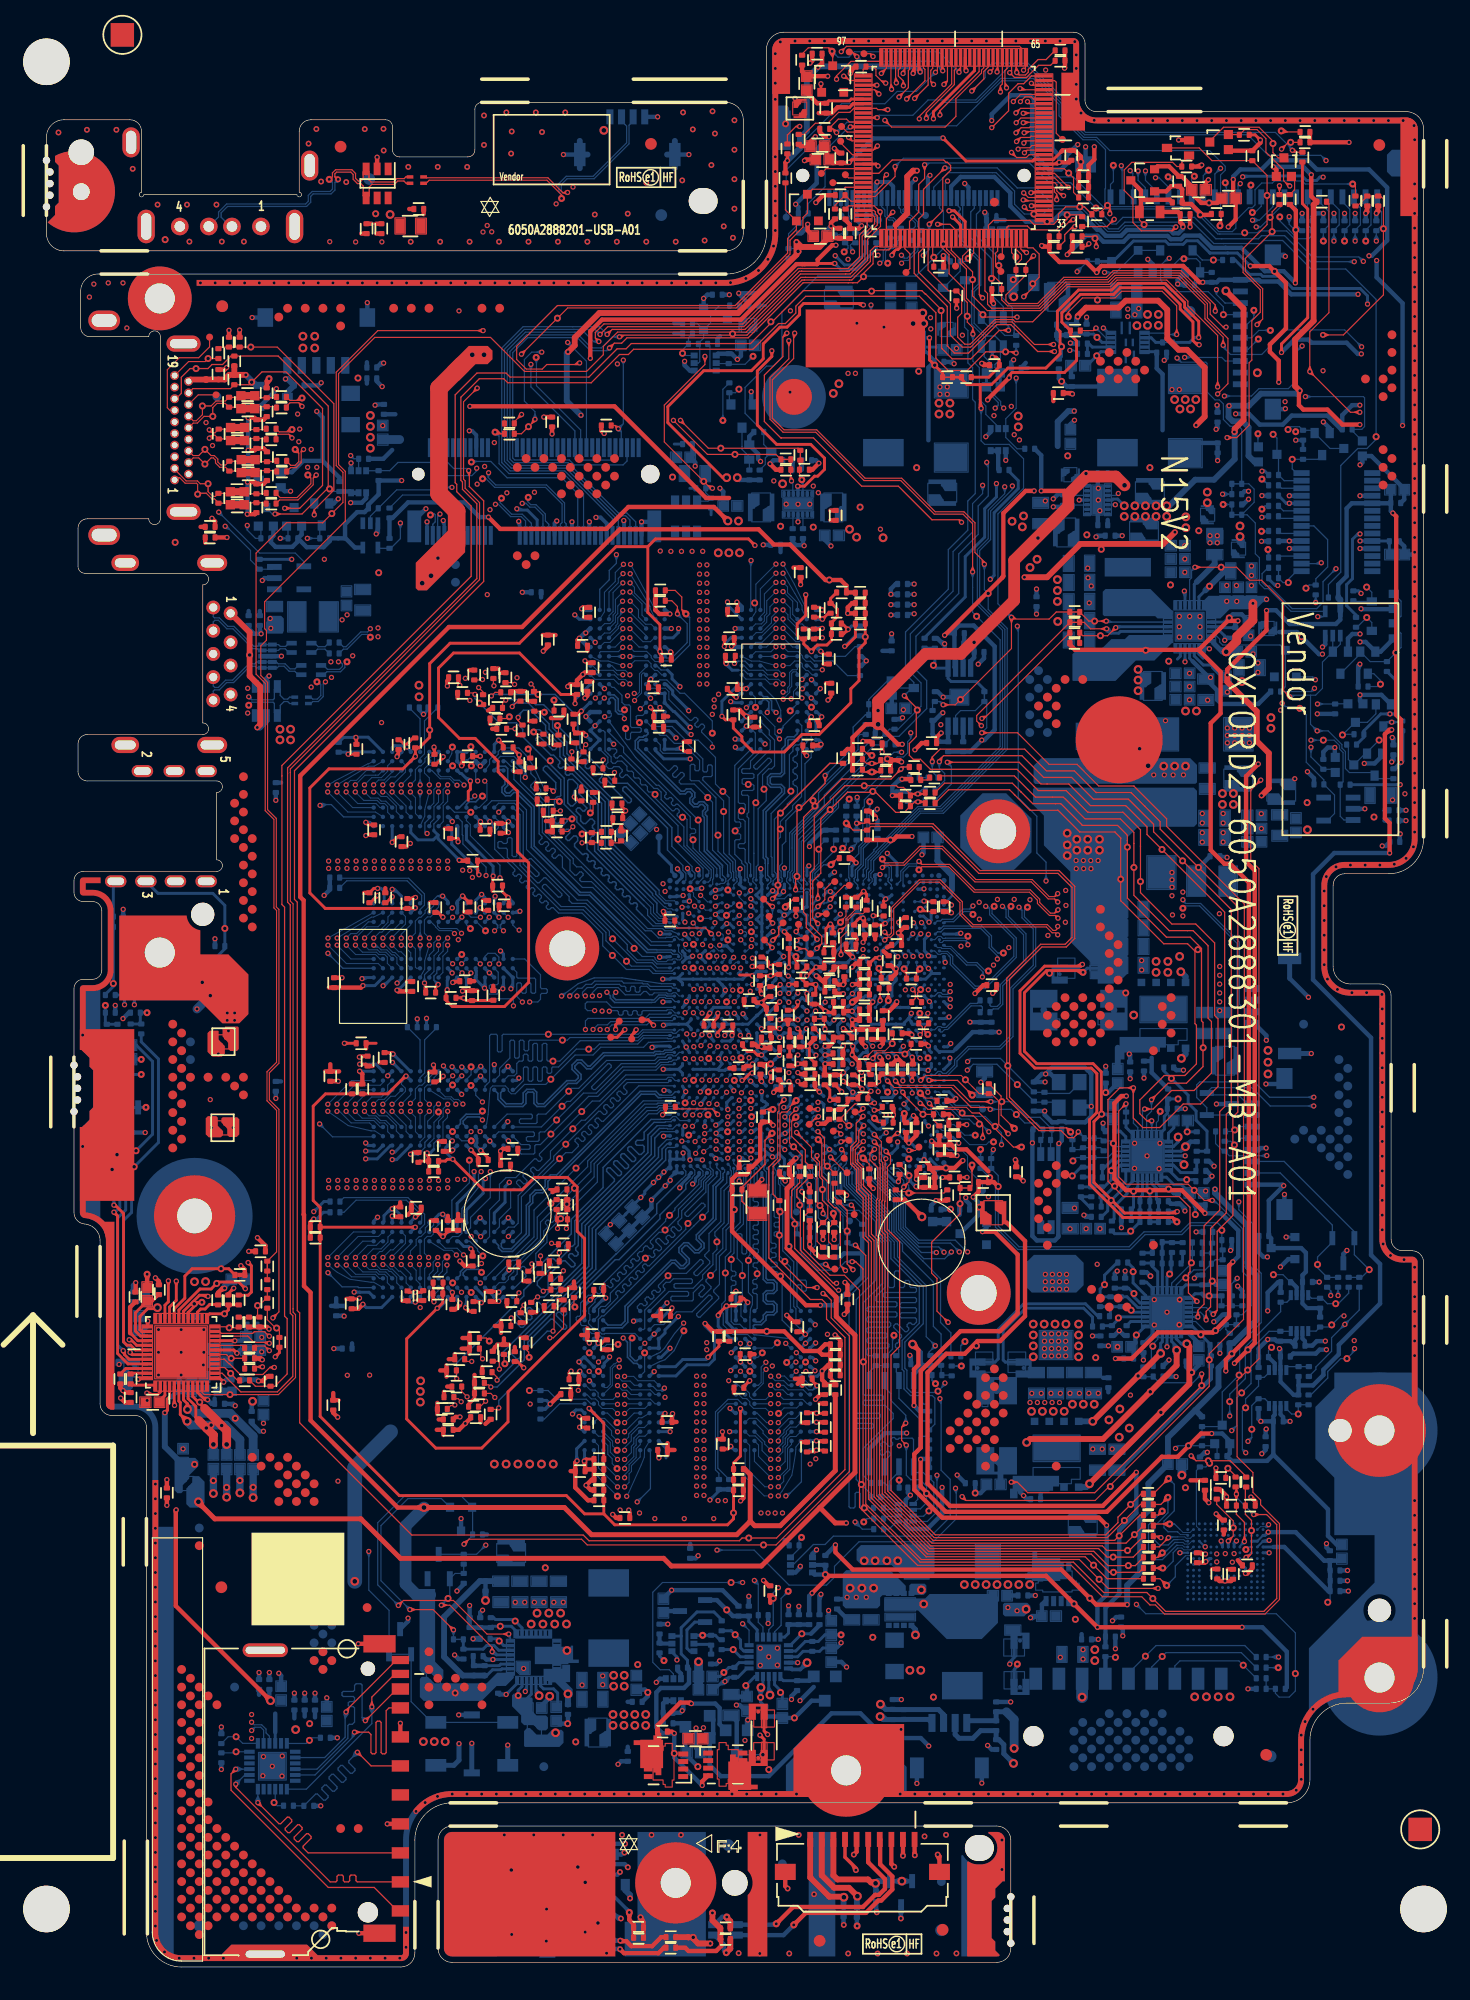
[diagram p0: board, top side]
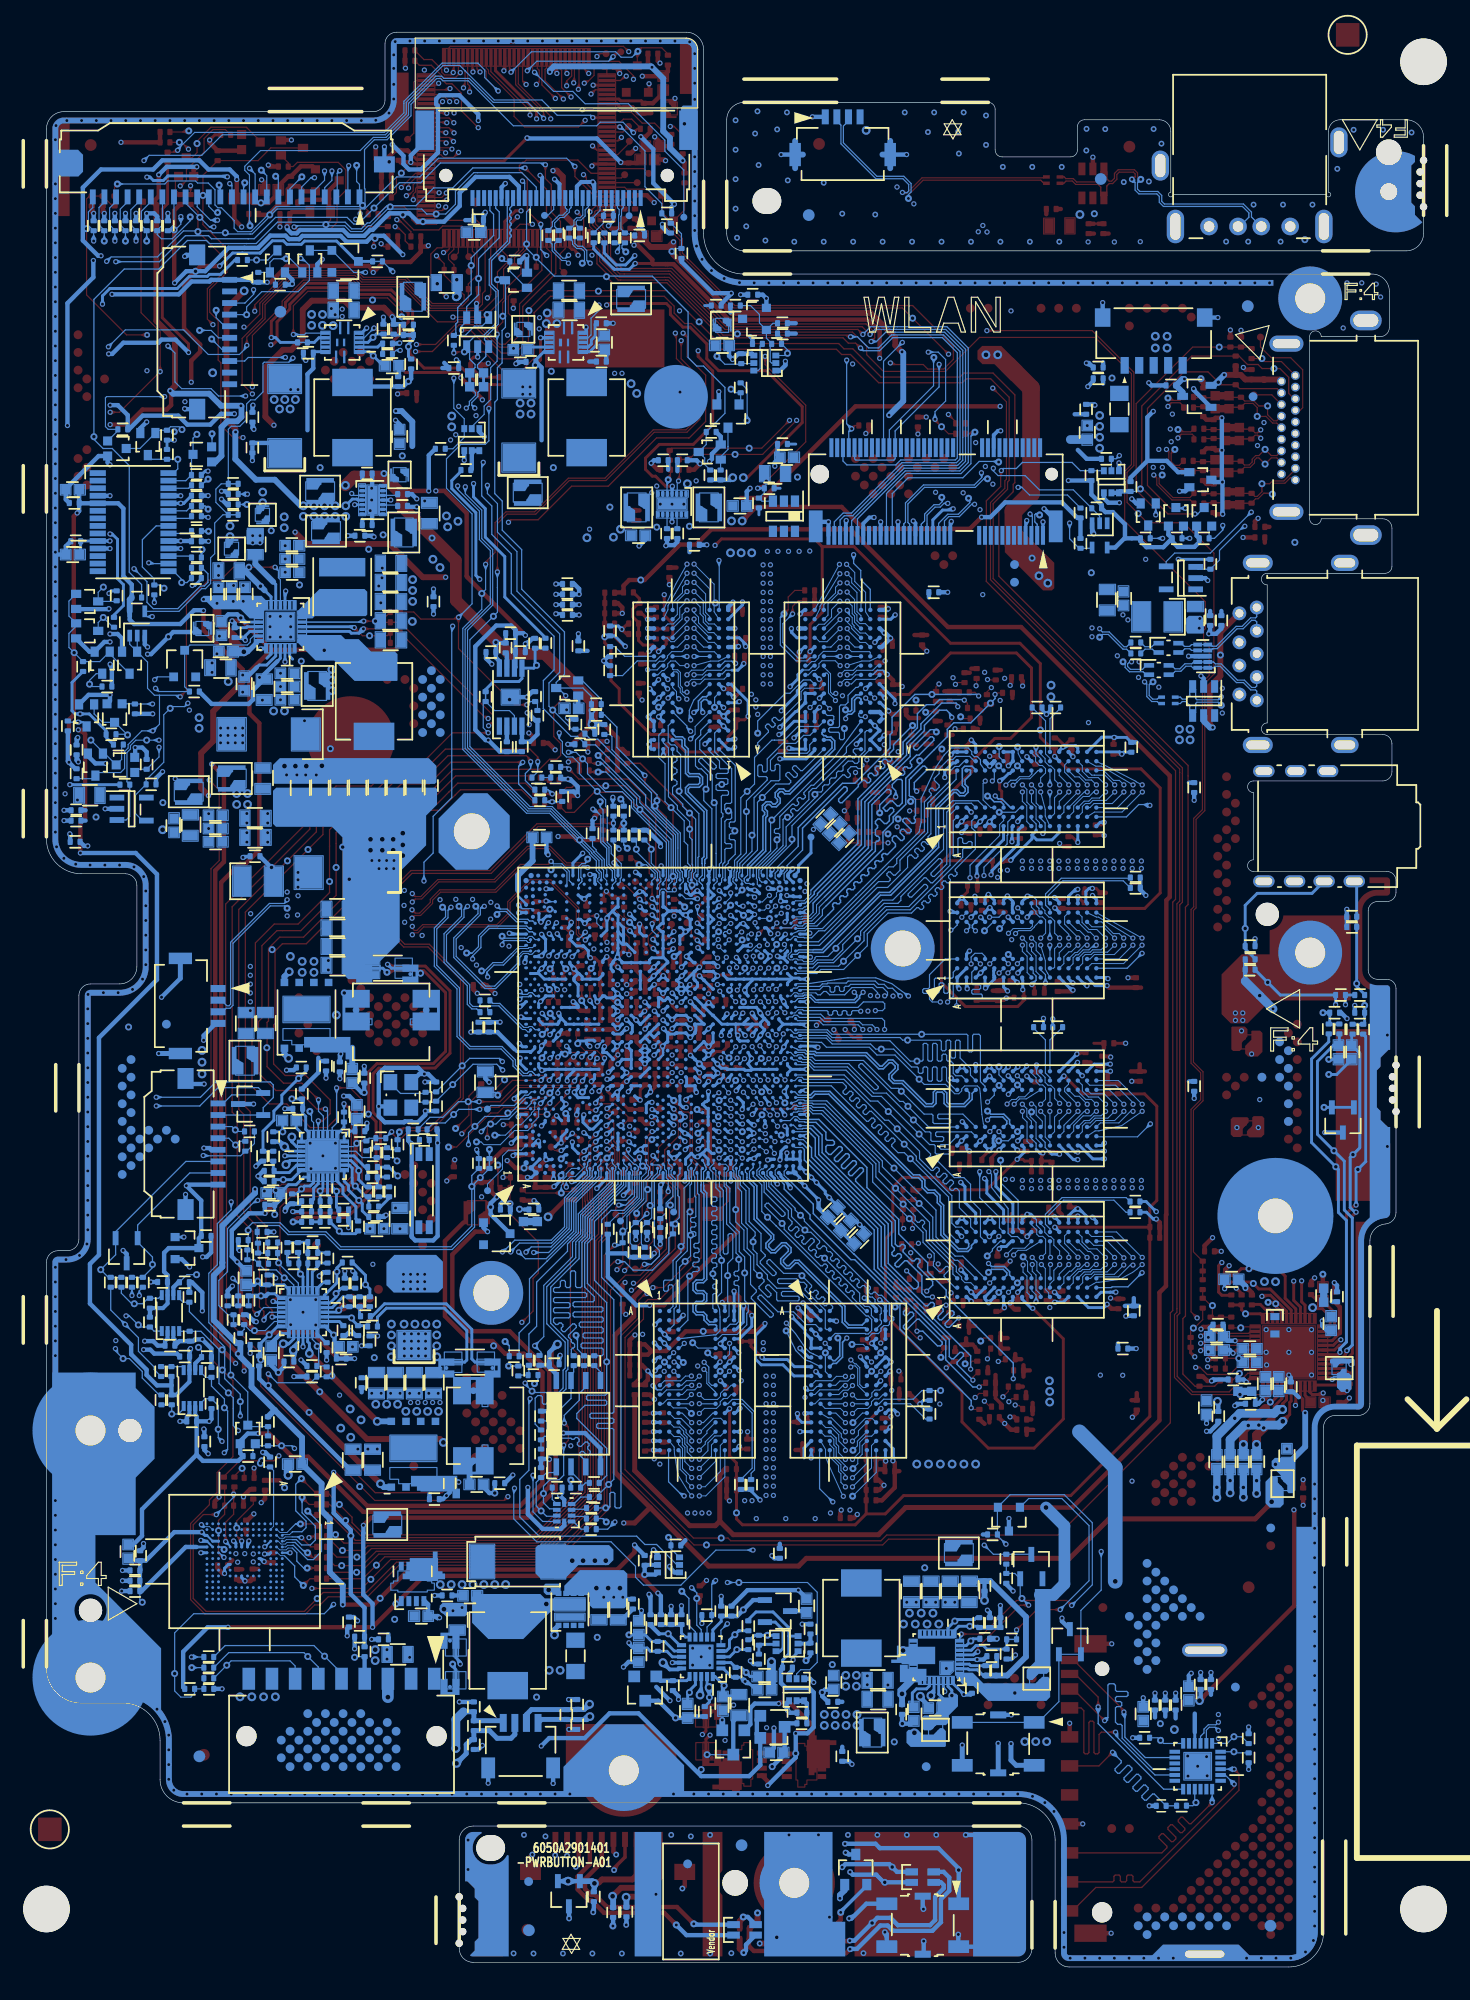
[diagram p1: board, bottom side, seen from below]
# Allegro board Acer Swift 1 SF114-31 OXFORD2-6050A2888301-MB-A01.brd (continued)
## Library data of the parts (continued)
PAD7101 PAD7102 PAD7104 = POWERPAD_2: part number: POWERPAD_2-POWERPAD_2_0610,POWERPAD_2_0610,POWERPAD_2_0610,0.559MM,POWERPAD_2,POWERPAD_2_0610; room: Sheet14
PAD7103 = POWERPAD_2: part number: POWERPAD_2-POWERPAD1X1M,POWERPAD1X1M,POWERPAD1X1M,0.559MM,POWERPAD_2,POWERPAD1X1M; room: Sheet14
PAD60300 PAD60310 = POWERPAD_2: part number: POWERPAD_2-POWERPAD_2_0610,POWERPAD_2_0610,POWERPAD_2_0610,0.559MM,POWERPAD_2,POWERPAD_2_0610; room: Sheet7
PAD60350 PAD60351 = POWERPAD_2: part number: POWERPAD_2-POWERPAD1X1M,POWERPAD1X1M,POWERPAD1X1M,0.559MM,POWERPAD_2,POWERPAD1X1M; room: Sheet7
PAD60610 PAD60900 PAD60910 = POWERPAD_2: part number: POWERPAD_2-POWERPAD_2_0610,POWERPAD_2_0610,POWERPAD_2_0610,0.559MM,POWERPAD_2,POWERPAD_2_0610; room: Sheet12
PAD61000 PAD61110 PAD61700 = POWERPAD_2: part number: POWERPAD_2-POWERPAD1X1M,POWERPAD1X1M,POWERPAD1X1M,0.559MM,POWERPAD_2,POWERPAD1X1M; room: Sheet12
Q281 = PMOS_A: part number: PMOS_A-PM513BA,6015B0145801,TSOT23_292X130X120_3_095,1.35MM,,TRANSISTOR-FET,PEMOS,20V,3A,SOT23,3P,TR; room: Sheet16
Q300 = NMOS: part number: NMOS-L2N7002WT1G,6015B0104301,TSSOT323_200X125X100_3_065,1.15MM,NMOS,,,TRANSISTOR-FET,NEMOS,60V,115MA,SC-70,3P,TR; room: Sheet17
Q310 Q311 = NMOS: part number: NMOS-RU1C001UNTCL,6015B0142601,UMT3F_200X125X100_3_065,1.15MM,NMOS,,,TRANSISTOR-FET,NEMOS,20V,100MA,UMT3F,3P,TR; room: Sheet17
Q1300 = FDC638APZ: part number: FDC638APZ-FDC638APZ_DY,6015B0068901_DY,TSOT_290X160X110_6_095,1.25MM,TRANSISTOR-FET,PEMOS,20V,4.5A,SSOT6,6P,TR; room: Sheet21
Q1302 = NMOS_DUAL_C: part number: NMOS_DUAL_C-L2N7002DW1T1G,6015B0098401,TSSC88_200X125X110_6_065-2,1.25MM,NMOS_DUAL_C,,TRANSISTOR-FET,NEMOS,60V,115MA,SOT363,6P,TR; room: Sheet45
Q3000 Q3004 = PMOS_A: part number: PMOS_A-PM513BA,6015B0145801,TSOT23_292X130X120_3_095,1.35MM,,TRANSISTOR-FET,PEMOS,20V,3A,SOT23,3P,TR; room: Sheet26
Q3001 = NMOS_DUAL_C: part number: NMOS_DUAL_C-L2N7002DW1T1G,6015B0098401,TSSC88_200X125X110_6_065-2,1.25MM,NMOS_DUAL_C,,TRANSISTOR-FET,NEMOS,60V,115MA,SOT363,6P,TR; room: Sheet26
Q3003 Q3007 = NMOS: part number: NMOS-L2N7002WT1G,6015B0104301,TSSOT323_200X125X100_3_065,1.15MM,NMOS,,,TRANSISTOR-FET,NEMOS,60V,115MA,SC-70,3P,TR; room: Sheet26
Q3006 = NPN_D: part number: NPN_D-LMBT3904LT1G,6015B0048201,TSSOT23_292X130X111_3_096,1.26MM,NPN_D,SOT23,0.2A,TRANSISTOR,NPN,40V,200MA,SOT23,3P,TR; room: Sheet26
Q3150 Q3151 = NMOS: part number: NMOS-RU1C001UNTCL,6015B0142601,UMT3F_200X125X100_3_065,1.15MM,NMOS,,,TRANSISTOR-FET,NEMOS,20V,100MA,UMT3F,3P,TR; room: Sheet27
Q3152 Q3153 = NMOS: part number: NMOS-L2N7002WT1G,6015B0104301,TSSOT323_200X125X100_3_065,1.15MM,NMOS,,,TRANSISTOR-FET,NEMOS,60V,115MA,SC-70,3P,TR; room: Sheet27
Q3500 Q3501 = NMOS: part number: NMOS-RU1C001UNTCL_DY,6015B0142601_DY,UMT3F_200X125X100_3_065,1.15MM,NMOS,,,TRANSISTOR-FET,NEMOS,20V,100MA,UMT3F,3P,TR; room: Sheet25
Q3502 = NMOS: part number: NMOS-L2N7002WT1G_DY,6015B0104301_DY,TSSOT323_200X125X100_3_065,1.15MM,NMOS,,,TRANSISTOR-FET,NEMOS,60V,115MA,SC-70,3P,TR; room: Sheet25
Q4505 = NMOS: part number: NMOS-L2N7002WT1G_DY,6015B0104301_DY,TSSOT323_200X125X100_3_065,1.15MM,NMOS,,,TRANSISTOR-FET,NEMOS,60V,115MA,SC-70,3P,TR; room: Sheet40
Q4506 = NMOS_DUAL_C: part number: NMOS_DUAL_C-L2N7002DW1T1G,6015B0098401,TSSC88_200X125X110_6_065-2,1.25MM,NMOS_DUAL_C,,TRANSISTOR-FET,NEMOS,60V,115MA,SOT363,6P,TR; room: Sheet40
Q4513 Q4516 Q4517 = NMOS: part number: NMOS-RU1C001UNTCL,6015B0142601,UMT3F_200X125X100_3_065,1.15MM,NMOS,,,TRANSISTOR-FET,NEMOS,20V,100MA,UMT3F,3P,TR; room: Sheet45
Q4524 Q4525 Q4714 = NMOS: part number: NMOS-L2N7002WT1G,6015B0104301,TSSOT323_200X125X100_3_065,1.15MM,NMOS,,,TRANSISTOR-FET,NEMOS,60V,115MA,SC-70,3P,TR; room: Sheet45
Q6000 = FDMS7620S: part number: FDMS7620S-AON7934,6015B0146701,TSMOS_300X300X080_8_065_T4,0.95MM,,TRANSISTOR-FET,NNEMOS,30V,16/18A,POWER33; room: Sheet5
Q6010 Q6012 = NMOS_4D3S: part number: NMOS_4D3S-RQ3E100BNFU7TB,6015B0134801,MOSFET_300X300X112_8_065,1.27MM,NMOS_4D3S,TRANSISTOR-FET,NEMOS,30V,10A,HSMT8,8P,TR; room: Sheet5
Q6011 = NMOS_4D3S: part number: NMOS_4D3S-RQ3E070BNFU7TB,6015B0162901,MOSFET_300X300X112_8_065,1.27MM,NMOS_4D3S,TRANSISTOR-FET,NEMOS,30V,7A,HSMT8,8,TR; room: Sheet5
Q6610 = FDMS3669S: part number: FDMS3669S-FAIRCHILD_FDMS3669S,6015B0146801,TSMOS_500X600X110_8_127_T1,1.25MM,,TRANSISTOR-FET,NNEMOS,30/30V,10/17A,POWER56; room: Sheet9
Q6710 = FDMS3669S: part number: FDMS3669S-FAIR_FDMS3664S_8P,6015B0131601,TSMOS_500X600X110_8_127_T1,1.25MM,,TRANSISTOR-FET,NNEMOS,30V,13/25A,POWER56; room: Sheet11
Q7000 = NMOS: part number: NMOS-L2N7002WT1G,6015B0104301,TSSOT323_200X125X100_3_065,1.15MM,NMOS,,,TRANSISTOR-FET,NEMOS,60V,115MA,SC-70,3P,TR; room: Sheet13
Q7106 Q7108 Q7114 Q7120 = NMOS: part number: NMOS-L2N7002WT1G,6015B0104301,TSSOT323_200X125X100_3_065,1.15MM,NMOS,,,TRANSISTOR-FET,NEMOS,60V,115MA,SC-70,3P,TR; room: Sheet14
Q7202 = PMOS_A: part number: PMOS_A-PM513BA,6015B0145801,TSOT23_292X130X120_3_095,1.35MM,,TRANSISTOR-FET,PEMOS,20V,3A,SOT23,3P,TR; room: Sheet13
Q7214 Q60002 Q60003 = NMOS_DUAL_C: part number: NMOS_DUAL_C-L2N7002DW1T1G,6015B0098401,TSSC88_200X125X110_6_065-2,1.25MM,NMOS_DUAL_C,,TRANSISTOR-FET,NEMOS,60V,115MA,SOT363,6P,TR; room: Sheet13
R20 R3010 R3021 R3030 = RSC_0402: part number: RSC_0402-100K_5%_2,60130B1040ZT,RSC_100X050X040_2,0.55MM,RSC_0402,0402,RES-CHIP-100K-5%-1/16W-0402-TAP; signal model: R2_60130B1040ZT_100K_5%_2; room: Sheet26
R28 R29 R7109 R7125 = RSC_0402: part number: RSC_0402-200_5%_2,6013A0051201,RSC_100X050X040_2,0.55MM,RSC_0402,0402,RES-CHIP-200-5%-1/16W-0402-TAP; signal model: R2_6013A0051201_200_5%_2; room: Sheet14
R35 R4523 R4545 R4546 = RSC_0402: part number: RSC_0402-10K_5%_2,60130B1030ZT,RSC_100X050X040_2,0.55MM,RSC_0402,0402,RES-CHIP,10K,5%,1/16W,0402,TR; signal model: R2_60130B1030ZT_10K_5%_2; room: Sheet37
R281 R282 R286 = RSC_0402: part number: RSC_0402-0_5%_2_DY,60130B0000ZT_DY,RSC_100X050X040_2,0.55MM,RSC_0402,0402,RES-CHIP-0OHM-5%-1/16W-0402-TAP; signal model: R2_60130B0000ZT_DY_0_5%_2_DY; room: Sheet16
R283-R285 = RSC_0402: part number: RSC_0402-0_5%_2,60130B0000ZT,RSC_100X050X040_2,0.55MM,RSC_0402,0402,RES-CHIP-0OHM-5%-1/16W-0402-TAP; signal model: R2_60130B0000ZT_0_5%_2; room: Sheet16
R301 R311 R323 R334 R350 R390 R4649 = RSC_0402: part number: RSC_0402-10K_5%_2,60130B1030ZT,RSC_100X050X040_2,0.55MM,RSC_0402,0402,RES-CHIP,10K,5%,1/16W,0402,TR; signal model: R2_60130B1030ZT_10K_5%_2; room: Sheet17
R308 R309 = RSC_0402: part number: RSC_0402-47K_5%_2,60130B4730ZT,RSC_100X050X040_2,0.55MM,RSC_0402,0402,RES-CHIP-47K-5%-1/16W-0402-TAP; signal model: R2_60130B4730ZT_47K_5%_2; room: Sheet17
R310 = RSC_0402: part number: RSC_0402-1K_5%_2,60130B1020ZT,RSC_100X050X040_2,0.55MM,RSC_0402,0402,RES-CHIP-1K-5%-1/16W-0402-TAP; signal model: R2_60130B1020ZT_1K_5%_2; room: Sheet17
R312-R314 R325 = RSC_0402: part number: RSC_0402-0_5%_2_DY,60130B0000ZT_DY,RSC_100X050X040_2,0.55MM,RSC_0402,0402,RES-CHIP-0OHM-5%-1/16W-0402-TAP; signal model: R2_60130B0000ZT_DY_0_5%_2_DY; room: Sheet17
R316 R317 = RSC_0402: part number: RSC_0402-1.8K_5%_2,6013A0072101,RSC_100X050X040_2,0.55MM,RSC_0402,0402,RES-CHIP-1.8K-5%-1/16W-0402-TAP; signal model: R2_6013A0072101_1_8K_5%_2; room: Sheet17
R318 = RSC_0603: part number: RSC_0603-2.2_5%_3,60130B2R200T,RSC_160X080X080_2,0.95MM,RSC_0603,0603,RES-CHIP-2.2-5%-1/10W-0603-TAP; signal model: R2_60130B2R200T_2_2_5%_3; room: Sheet17
R320 R324 R333 R346 = RSC_0402: part number: RSC_0402-100K_5%_2,60130B1040ZT,RSC_100X050X040_2,0.55MM,RSC_0402,0402,RES-CHIP-100K-5%-1/16W-0402-TAP; signal model: R2_60130B1040ZT_100K_5%_2; room: Sheet17
R321 R322 = RSC_0402: part number: RSC_0402-3.3K_5%_2,6013A0051001,RSC_100X050X040_2,0.55MM,RSC_0402,0402,RES-CHIP-3.3K-5%-1/16W-0402-TAP; signal model: R2_6013A0051001_3_3K_5%_2; room: Sheet17
R332 R391 = RSC_0402: part number: RSC_0402-10K_5%_2_DY,60130B1030ZT_DY,RSC_100X050X040_2,0.55MM,RSC_0402,0402,RES-CHIP,10K,5%,1/16W,0402,TR; signal model: R2_60130B1030ZT_DY_10K_5%_2_DY; room: Sheet17
R340-R343 = RSC_0402: part number: RSC_0402-33_5%_2,60130B3300ZT,RSC_100X050X040_2,0.55MM,RSC_0402,0402,RES-CHIP-33-5%-1/16W-0402-TAP; signal model: R2_60130B3300ZT_33_5%_2; room: Sheet17
R351 = RSC_0402: part number: RSC_0402-18.7K_1%_2,6013A0017101,RSC_100X050X040_2,0.55MM,RSC_0402,0402,RES-CHIP-18.7K-1%-1/16W-0402-TAP; signal model: R2_6013A0017101_18_7K_1%_2; room: Sheet17
R352 = RSC_THERMISTOR: part number: RSC_THERMISTOR-100K_1%_NTC,6013B0171701,RSC_100X050X055_2,0.7MM,RSC_THERMISTOR,,RESISTOR-THER,NTC,100K,0402,1%,0.1A,0.1W,SMD,TR; signal model: R2_6013B0171701_100K_1%_NTC; room: Sheet17
R500 R513 = RSC_SHORT: part number: RSC_SHORT-SHORT_0603_25,SHORT_0603_25,RSC_160X080X080_2_25_SHORT,0.127MM,RSC_SHORT,SHORT_0603_25; signal model: R2_short_0603_25_short_0603_25; room: Sheet18
R501 = RSC_0402: part number: RSC_0402-20K_1%_2_DY,6013A0015301_DY,RSC_100X050X040_2,0.55MM,RSC_0402,0402,RES-CHIP-20K-1%-1/16W-0402-TAP; signal model: R2_6013A0015301_DY_20K_1%_2_DY; room: Sheet18
R502 = RSC_0402: part number: RSC_0402-200K_5%_2,60130B20400Y,RSC_100X050X040_2,0.55MM,RSC_0402,0402,RES-CHIP-200K-5%-1/16W-0402-TAP; signal model: R2_60130B20400Y_200K_5%_2; room: Sheet18
R503 = RSC_0402: part number: RSC_0402-1K_5%_2_DY,60130B1020ZT_DY,RSC_100X050X040_2,0.55MM,RSC_0402,0402,RES-CHIP-1K-5%-1/16W-0402-TAP; signal model: R2_60130B1020ZT_DY_1K_5%_2_DY; room: Sheet18
R504 R531 = RSC_0402: part number: RSC_0402-100K_5%_2,60130B1040ZT,RSC_100X050X040_2,0.55MM,RSC_0402,0402,RES-CHIP-100K-5%-1/16W-0402-TAP; signal model: R2_60130B1040ZT_100K_5%_2; room: Sheet18
R505 R515 = RSC_0402: part number: RSC_0402-1K_5%_2,60130B1020ZT,RSC_100X050X040_2,0.55MM,RSC_0402,0402,RES-CHIP-1K-5%-1/16W-0402-TAP; signal model: R2_60130B1020ZT_1K_5%_2; room: Sheet18
R506 = RSC_0402: part number: RSC_0402-0_5%_2,60130B0000ZT,RSC_100X050X040_2,0.55MM,RSC_0402,0402,RES-CHIP-0OHM-5%-1/16W-0402-TAP; signal model: R2_60130B0000ZT_0_5%_2; room: Sheet18
R507 = RSC_0402: part number: RSC_0402-75_5%_2,60130B7500ZT,RSC_100X050X040_2,0.55MM,RSC_0402,0402,RES-CHIP-75OHM-5%-1/16W-0402-TAP; signal model: R2_60130B7500ZT_75_5%_2; room: Sheet18
R508-R511 = RSC_0603: part number: RSC_0603-0_5%_3,60130B00000Z,RSC_160X080X055_2,0.7MM,RSC_0603,0603,RES-CHIP-0-5%-1/10W-TAP; signal model: R2_60130B00000Z_0_5%_3; room: Sheet18
R512 = RSC_0402: part number: RSC_0402-100_5%_2,60130B1010ZT,RSC_100X050X040_2,0.55MM,RSC_0402,0402,RES-CHIP-100-5%-1/16W-0402-TAP; signal model: R2_60130B1010ZT_100_5%_2; room: Sheet18
R514 = RSC_SHORT: part number: RSC_SHORT-SHORT_0402_15,SHORT_0402_15,RSC_100X050X040_2_15_SHORT,0.127MM,RSC_SHORT,SHORT_0402_15; signal model: R2_short_0402_15_short_0402_15; room: Sheet18
R520 R521 = RSC_SHORT: part number: RSC_SHORT-SHORT_0402_5,SHORT_0402_5,RSC_100X050X040_2_SHORT,0.127MM,RSC_SHORT,SHORT_0402_5; signal model: R2_short_0402_5_short_0402_5; room: Sheet18
R600 R601 = RSC_0402: part number: RSC_0402-2.2K_5%_2,6013A0049601,RSC_100X050X040_2,0.55MM,RSC_0402,0402,RES-CHIP-2.2K-5%-1/16W-0402-TAP; signal model: R2_6013A0049601_2_2K_5%_2; room: Sheet19
R602 R603 = RSC_0402: part number: RSC_0402-0_5%_2,60130B0000ZT,RSC_100X050X040_2,0.55MM,RSC_0402,0402,RES-CHIP-0OHM-5%-1/16W-0402-TAP; signal model: R2_60130B0000ZT_0_5%_2; room: Sheet19
R604 R605 = RSC_0402: part number: RSC_0402-22_5%_2,60130B2200ZT,RSC_100X050X040_2,0.55MM,RSC_0402,0402,RES-CHIP-22-5%-1/16W-0402-TAP; signal model: R2_60130B2200ZT_22_5%_2; room: Sheet19
R606 R607 = RSC_0402: part number: RSC_0402-4.7K_5%_2,60130B4720ZT,RSC_100X050X040_2,0.55MM,RSC_0402,0402,RES-CHIP-4.7K-5%-1/16W-0402-TAP; signal model: R2_60130B4720ZT_4_7K_5%_2; room: Sheet19
R610 = RSC_0402: part number: RSC_0402-0_5%_2_DY,60130B0000ZT_DY,RSC_100X050X040_2,0.55MM,RSC_0402,0402,RES-CHIP-0OHM-5%-1/16W-0402-TAP; signal model: R2_60130B0000ZT_DY_0_5%_2_DY; room: Sheet19
R704 = RSC_SHORT: part number: RSC_SHORT-SHORT_0402_15,SHORT_0402_15,RSC_100X050X040_2_15_SHORT,0.127MM,RSC_SHORT,SHORT_0402_15; signal model: R2_short_0402_15_short_0402_15; room: Sheet40
R900 = RSC_0402: part number: RSC_0402-6.2K_1%_2,6013A0057801,RSC_100X050X040_2,0.55MM,RSC_0402,0402,RES-CHIP-6.2K,1%-1/16W-0402-TAP; signal model: R2_6013A0057801_6_2K_1%_2; room: Sheet20
R901 = RSC_0402: part number: RSC_0402-0_5%_2,60130B0000ZT,RSC_100X050X040_2,0.55MM,RSC_0402,0402,RES-CHIP-0OHM-5%-1/16W-0402-TAP; signal model: R2_60130B0000ZT_0_5%_2; room: Sheet20
R1301 = RSC_0805: part number: RSC_0805-0_5%_5,60130BA0003T,RSC_200X125X115_2,1.3MM,RSC_0805,0805,RES-CHIP-0-5%-1/8W-0805-TAP; signal model: R2_60130BA0003T_0_5%_5; room: Sheet21
R1302 = RSC_0402: part number: RSC_0402-0_5%_2_DY,60130B0000ZT_DY,RSC_100X050X040_2,0.55MM,RSC_0402,0402,RES-CHIP-0OHM-5%-1/16W-0402-TAP; signal model: R2_60130B0000ZT_DY_0_5%_2_DY; room: Sheet21
R1306 = RSC_0402: part number: RSC_0402-0_5%_2,60130B0000ZT,RSC_100X050X040_2,0.55MM,RSC_0402,0402,RES-CHIP-0OHM-5%-1/16W-0402-TAP; signal model: R2_60130B0000ZT_0_5%_2; room: Sheet21
R1307 R4639 R4640 R4642 R4643 R4652 R4653 R4655-R4657 R4834 = RSC_0402: part number: RSC_0402-10K_5%_2,60130B1030ZT,RSC_100X050X040_2,0.55MM,RSC_0402,0402,RES-CHIP,10K,5%,1/16W,0402,TR; signal model: R2_60130B1030ZT_10K_5%_2; room: Sheet45
R2000 = RSC_0402: part number: RSC_0402-RSC_0402_DY,RSC_0402_DY,RSC_100X050X040_2,0.55MM,RSC_0402,0402,RSC_0402_DY; signal model: R2_RSC_0402_DY_RSC_0402_DY; room: Sheet22
R2001 = RSC_0402: part number: RSC_0402-10K_5%_2,60130B1030ZT,RSC_100X050X040_2,0.55MM,RSC_0402,0402,RES-CHIP,10K,5%,1/16W,0402,TR; signal model: R2_60130B1030ZT_10K_5%_2; room: Sheet22
R2410 = RSC_0402: part number: RSC_0402-10K_5%_2,60130B1030ZT,RSC_100X050X040_2,0.55MM,RSC_0402,0402,RES-CHIP,10K,5%,1/16W,0402,TR; signal model: R2_60130B1030ZT_10K_5%_2; room: Sheet23
R3000 R3006 = RSC_0402: part number: RSC_0402-47K_5%_2,60130B4730ZT,RSC_100X050X040_2,0.55MM,RSC_0402,0402,RES-CHIP-47K-5%-1/16W-0402-TAP; signal model: R2_60130B4730ZT_47K_5%_2; room: Sheet26
R3001 = RSC_0402: part number: RSC_0402-470K_5%_2,60130B47400Z,RSC_100X050X040_2,0.55MM,RSC_0402,0402,RES-CHIP-470K-5%-1/16W-0402-TAP; signal model: R2_60130B47400Z_470K_5%_2; room: Sheet26
R3004 R3011 R3013 = RSC_0402: part number: RSC_0402-100_5%_2,60130B1010ZT,RSC_100X050X040_2,0.55MM,RSC_0402,0402,RES-CHIP-100-5%-1/16W-0402-TAP; signal model: R2_60130B1010ZT_100_5%_2; room: Sheet26
R3005 R3029 = RSC_SHORT: part number: RSC_SHORT-SHORT_0603_10,SHORT_0603_10,RSC_160X080X080_2_SHORT,0.127MM,RSC_SHORT,SHORT_0603_10; signal model: R2_short_0603_10_short_0603_10; room: Sheet26
R3007 = RSC_0402: part number: RSC_0402-4.7K_5%_2,60130B4720ZT,RSC_100X050X040_2,0.55MM,RSC_0402,0402,RES-CHIP-4.7K-5%-1/16W-0402-TAP; signal model: R2_60130B4720ZT_4_7K_5%_2; room: Sheet26
R3016 R3017 R4520 R4705-R4707 = RSC_0402: part number: RSC_0402-100K_5%_2,60130B1040ZT,RSC_100X050X040_2,0.55MM,RSC_0402,0402,RES-CHIP-100K-5%-1/16W-0402-TAP; signal model: R2_60130B1040ZT_100K_5%_2; room: Sheet36
R3020 = RSC_0402: part number: RSC_0402-10K_5%_2,60130B1030ZT,RSC_100X050X040_2,0.55MM,RSC_0402,0402,RES-CHIP,10K,5%,1/16W,0402,TR; signal model: R2_60130B1030ZT_10K_5%_2; room: Sheet26
R3025 = RSC_0402: part number: RSC_0402-2.2K_5%_2,6013A0049601,RSC_100X050X040_2,0.55MM,RSC_0402,0402,RES-CHIP-2.2K-5%-1/16W-0402-TAP; signal model: R2_6013A0049601_2_2K_5%_2; room: Sheet26
R3060 = RSC_0402: part number: RSC_0402-150_5%_2_DY,60130B15100Y_DY,RSC_100X050X040_2,0.55MM,RSC_0402,0402,RES-CHIP-150-5%-1/16W-0402-TAP; signal model: R2_60130B15100Y_DY_150_5%_2_DY; room: Sheet26
R3061 = RSC_0402: part number: RSC_0402-0_5%_2,60130B0000ZT,RSC_100X050X040_2,0.55MM,RSC_0402,0402,RES-CHIP-0OHM-5%-1/16W-0402-TAP; signal model: R2_60130B0000ZT_0_5%_2; room: Sheet26
R3068 = RSC_0603: part number: RSC_0603-0_5%_3,60130B00000Z,RSC_160X080X055_2,0.7MM,RSC_0603,0603,RES-CHIP-0-5%-1/10W-TAP; signal model: R2_60130B00000Z_0_5%_3; room: Sheet26
R3069 = RSC_0603: part number: RSC_0603-0_5%_3_DY,60130B00000Z_DY,RSC_160X080X055_2,0.7MM,RSC_0603,0603,RES-CHIP-0-5%-1/10W-TAP; signal model: R2_60130B00000Z_0_5%_3_DY; room: Sheet26
R3150 = RSC_0402: part number: RSC_0402-100K_5%_2,60130B1040ZT,RSC_100X050X040_2,0.55MM,RSC_0402,0402,RES-CHIP-100K-5%-1/16W-0402-TAP; signal model: R2_60130B1040ZT_100K_5%_2; room: Sheet27
R3152 R3153 R3178 R3179 = RSC_0402: part number: RSC_0402-2.2K_5%_2,6013A0049601,RSC_100X050X040_2,0.55MM,RSC_0402,0402,RES-CHIP-2.2K-5%-1/16W-0402-TAP; signal model: R2_6013A0049601_2_2K_5%_2; room: Sheet27
R3154 = RSC_0402: part number: RSC_0402-1K_5%_2,60130B1020ZT,RSC_100X050X040_2,0.55MM,RSC_0402,0402,RES-CHIP-1K-5%-1/16W-0402-TAP; signal model: R2_60130B1020ZT_1K_5%_2; room: Sheet27
R3157-R3164 = RSC_0402: part number: RSC_0402-619_1%_2,6013A0023401,RSC_100X050X040_2,0.55MM,RSC_0402,0402,RES-CHIP-619-1%-1/16W-0402-TAP; signal model: R2_6013A0023401_619_1%_2; room: Sheet27
R3167-R3170 = RSC_0402: part number: RSC_0402-120_1%_2,6013B0077801,RSC_100X050X040_2,0.55MM,RSC_0402,0402,RES-CHIP,120,1%,1/16W,0402,TR,200PPM/DEGREEC; signal model: R2_6013B0077801_120_1%_2; room: Sheet27; signal model: R2_6013B0077801_DY_120_1%_2_DY-11
R3171 = RSC_0402: part number: RSC_0402-10K_5%_2,60130B1030ZT,RSC_100X050X040_2,0.55MM,RSC_0402,0402,RES-CHIP,10K,5%,1/16W,0402,TR; signal model: R2_60130B1030ZT_10K_5%_2; room: Sheet27
R3180 R3182 R3184 R3186 = RSC_SHORT: part number: RSC_SHORT-SHORT_0603_25,SHORT_0603_25,RSC_160X080X080_2_25_SHORT,0.127MM,RSC_SHORT,SHORT_0603_25; signal model: R2_short_0603_25_short_0603_25; room: Sheet27; signal model: R2_60130B00000Z_0_5%_33
R3181 R3183 R3185 R3187 = RSC_SHORT: part number: RSC_SHORT-SHORT_0603_25,SHORT_0603_25,RSC_160X080X080_2_25_SHORT,0.127MM,RSC_SHORT,SHORT_0603_25; signal model: R2_short_0603_25_short_0603_25; room: Sheet27
R3503-R3507 R3509 R3510 = RSC_0402: part number: RSC_0402-0_5%_2_DY,60130B0000ZT_DY,RSC_100X050X040_2,0.55MM,RSC_0402,0402,RES-CHIP-0OHM-5%-1/16W-0402-TAP; signal model: R2_60130B0000ZT_DY_0_5%_2_DY; room: Sheet25
R3511 R3513-R3515 = RSC_0402: part number: RSC_0402-10K_5%_2_DY,60130B1030ZT_DY,RSC_100X050X040_2,0.55MM,RSC_0402,0402,RES-CHIP,10K,5%,1/16W,0402,TR; signal model: R2_60130B1030ZT_DY_10K_5%_2_DY; room: Sheet25
R3516 = RSC_0402: part number: RSC_0402-2.2K_5%_2_DY,6013A0049601_DY,RSC_100X050X040_2,0.55MM,RSC_0402,0402,RES-CHIP-2.2K-5%-1/16W-0402-TAP; signal model: R2_6013A0049601_DY_2_2K_5%_2_DY; room: Sheet25
R3950 = RSC_0402: part number: RSC_0402-0_5%_2_DY,60130B0000ZT_DY,RSC_100X050X040_2,0.55MM,RSC_0402,0402,RES-CHIP-0OHM-5%-1/16W-0402-TAP; signal model: R2_60130B0000ZT_DY_0_5%_2_DY; room: Sheet24
R3955 R3962 R4665-R4669 R4672-R4674 = RSC_0402: part number: RSC_0402-0_5%_2,60130B0000ZT,RSC_100X050X040_2,0.55MM,RSC_0402,0402,RES-CHIP-0OHM-5%-1/16W-0402-TAP; signal model: R2_60130B0000ZT_0_5%_2; room: Sheet24
R3963 R3965 = RSC_0402: part number: RSC_0402-10K_5%_2_DY,60130B1030ZT_DY,RSC_100X050X040_2,0.55MM,RSC_0402,0402,RES-CHIP,10K,5%,1/16W,0402,TR; signal model: R2_60130B1030ZT_DY_10K_5%_2_DY; room: Sheet24
R3964 R3966 = RSC_0603: part number: RSC_0603-0_5%_3,60130B00000Z,RSC_160X080X055_2,0.7MM,RSC_0603,0603,RES-CHIP-0-5%-1/10W-TAP; signal model: R2_60130B00000Z_0_5%_3; room: Sheet24
R4100 R4101 R4106 R4107 = RSC_0402: part number: RSC_0402-243_1%_2,6013A0087806,RSC_100X050X040_2,0.55MM,RSC_0402,0402,RESISTOR-CHIP,243OHM,1%,1/16W,0402,TAPMM; signal model: R2_6013A0087806_243_1%_2; room: Sheet28
R4102 R4103 R4108 R4109 = RSC_0402: part number: RSC_0402-243_1%_2,6013A0087806,RSC_100X050X040_2,0.55MM,RSC_0402,0402,RESISTOR-CHIP,243OHM,1%,1/16W,0402,TAPMM; signal model: R2_6013A0087806_243_1%_2; room: Sheet29
R4104 R4105 R4110 R4111 = RSC_0402: part number: RSC_0402-4.7K_1%_2,60130B47019Z,RSC_100X050X040_2,0.55MM,RSC_0402,0402,RES-CHIP-4.7K-1%-1/16W-0402-TAP; signal model: R2_60130B47019Z_4_7K_1%_2; room: Sheet28
R4112 R4113 = RSC_0402: part number: RSC_0402-0_5%_2_DY,60130B0000ZT_DY,RSC_100X050X040_2,0.55MM,RSC_0402,0402,RES-CHIP-0OHM-5%-1/16W-0402-TAP; signal model: R2_60130B0000ZT_DY_0_5%_2_DY; room: Sheet28
R4114-R4143 = RSC_0402: part number: RSC_0402-80.6_1%_2,6013A008760G,RSC_100X050X040_2,0.55MM,RSC_0402,0402,RES-CHIP-80.6-1%-1/16W-0402-TAP; signal model: R2_6013A008760G_80_6_1%_2; room: Sheet30
R4144 R4151 R4178 R4179 = RSC_0402: part number: RSC_0402-243_1%_2,6013A0087806,RSC_100X050X040_2,0.55MM,RSC_0402,0402,RESISTOR-CHIP,243OHM,1%,1/16W,0402,TAPMM; signal model: R2_6013A0087806_243_1%_2; room: Sheet31
R4145-R4150 R4152-R4171 R4183-R4186 = RSC_0402: part number: RSC_0402-80.6_1%_2,6013A008760G,RSC_100X050X040_2,0.55MM,RSC_0402,0402,RES-CHIP-80.6-1%-1/16W-0402-TAP; signal model: R2_6013A008760G_80_6_1%_2; room: Sheet33
R4172 R4174 R4175 R4177 = RSC_0402: part number: RSC_0402-4.7K_1%_2,60130B47019Z,RSC_100X050X040_2,0.55MM,RSC_0402,0402,RES-CHIP-4.7K-1%-1/16W-0402-TAP; signal model: R2_60130B47019Z_4_7K_1%_2; room: Sheet31
R4173 R4176 = RSC_0402: part number: RSC_0402-0_5%_2_DY,60130B0000ZT_DY,RSC_100X050X040_2,0.55MM,RSC_0402,0402,RES-CHIP-0OHM-5%-1/16W-0402-TAP; signal model: R2_60130B0000ZT_DY_0_5%_2_DY; room: Sheet31
R4180-R4182 R4187 = RSC_0402: part number: RSC_0402-243_1%_2,6013A0087806,RSC_100X050X040_2,0.55MM,RSC_0402,0402,RESISTOR-CHIP,243OHM,1%,1/16W,0402,TAPMM; signal model: R2_6013A0087806_243_1%_2; room: Sheet32
R4441 = RSC_0402: part number: RSC_0402-150K_5%_2,60130B15400T,RSC_100X050X040_2,0.55MM,RSC_0402,0402,RES-CHIP-150K-5%-1/16W-0402-TAP; signal model: R2_60130B15400T_150K_5%_2; room: Sheet30
R4442 = RSC_0402: part number: RSC_0402-53.6K_1%_2,6013A0073101,RSC_100X050X040_2,0.55MM,RSC_0402,0402,RES-CHIP-53.6K-1%-1/16W-0402-TAP; signal model: R2_6013A0073101_53_6K_1%_2; room: Sheet30
R4443 = RSC_0402: part number: RSC_0402-32.4K_1%_2,6013A008850E,RSC_100X050X040_2,0.55MM,RSC_0402,0402,RES-CHIP-32.4K-1%-1/16W-0402-TAP; signal model: R2_6013A008850E_32_4K_1%_2; room: Sheet30
R4444 = RSC_THERMISTOR: part number: RSC_THERMISTOR-100K_1%_NTC,6013B0171701,RSC_100X050X055_2,0.7MM,RSC_THERMISTOR,,RESISTOR-THER,NTC,100K,0402,1%,0.1A,0.1W,SMD,TR; signal model: R2_6013B0171701_100K_1%_NTC; room: Sheet30
R4445 = RSC_0402: part number: RSC_0402-100K_5%_2,60130B1040ZT,RSC_100X050X040_2,0.55MM,RSC_0402,0402,RES-CHIP-100K-5%-1/16W-0402-TAP; signal model: R2_60130B1040ZT_100K_5%_2; room: Sheet30
R4446 = RSC_0402: part number: RSC_0402-10K_5%_2,60130B1030ZT,RSC_100X050X040_2,0.55MM,RSC_0402,0402,RES-CHIP,10K,5%,1/16W,0402,TR; signal model: R2_60130B1030ZT_10K_5%_2; room: Sheet30
R4448 = RSC_SHORT: part number: RSC_SHORT-SHORT_0402_5,SHORT_0402_5,RSC_100X050X040_2_SHORT,0.127MM,RSC_SHORT,SHORT_0402_5; signal model: R2_short_0402_5_short_0402_5; room: Sheet30
R4449 = RSC_0402: part number: RSC_0402-620K_5%_2,6013B0168301,RSC_100X050X040_2,0.55MM,RSC_0402,0402,RES-CHIP,620K,5%,1/16W,0402,TAP; signal model: R2_6013B0168301_620K_5%_2; room: Sheet30
R4504 = RSC_0402: part number: RSC_0402-182_1%_2,6013A0023201,RSC_100X050X040_2,0.55MM,RSC_0402,0402,RES-CHIP-182-1%-1/16W-0402-TAP; signal model: R2_6013A0023201_182_1%_2; room: Sheet34
R4505 = RSC_0402: part number: RSC_0402-182_1%_2,6013A0023201,RSC_100X050X040_2,0.55MM,RSC_0402,0402,RES-CHIP-182-1%-1/16W-0402-TAP; signal model: R2_6013A0023201_182_1%_2; room: Sheet35
R4514 R4518 = RSC_0402: part number: RSC_0402-402_1%_2,6013A0023801,RSC_100X050X040_2,0.55MM,RSC_0402,0402,RES-CHIP-402-1%-1/16W-0402-TAP; signal model: R2_6013A0023801_402_1%_2; room: Sheet36
R4521 = RSC_0402: part number: RSC_0402-100_1%_2,6013A0016701,RSC_100X050X040_2,0.55MM,RSC_0402,0402,RES-CHIP-100OHM-1%-1/16W-0402-TAP; signal model: R2_6013A0016701_100_1%_2; room: Sheet36
R4522 R4532 = RSC_0402: part number: RSC_0402-402_1%_2,6013A0023801,RSC_100X050X040_2,0.55MM,RSC_0402,0402,RES-CHIP-402-1%-1/16W-0402-TAP; signal model: R2_6013A0023801_402_1%_2; room: Sheet37
R4533 R4534 R4547 R4686 R4900 R4901 = RSC_0402: part number: RSC_0402-10K_5%_2,60130B1030ZT,RSC_100X050X040_2,0.55MM,RSC_0402,0402,RES-CHIP,10K,5%,1/16W,0402,TR; signal model: R2_60130B1030ZT_10K_5%_2; room: Sheet38
R4536-R4539 = RSC_0402: part number: RSC_0402-75_5%_2,60130B7500ZT,RSC_100X050X040_2,0.55MM,RSC_0402,0402,RES-CHIP-75OHM-5%-1/16W-0402-TAP; signal model: R2_60130B7500ZT_75_5%_2; room: Sheet37
R4540 = RSC_SHORT: part number: RSC_SHORT-SHORT_0402_5,SHORT_0402_5,RSC_100X050X040_2_SHORT,0.127MM,RSC_SHORT,SHORT_0402_5; signal model: R2_short_0402_5_short_0402_5; room: Sheet37
R4541 = RSC_0402: part number: RSC_0402-49.9_1%_2,6013A0076901,RSC_100X050X040_2,0.55MM,RSC_0402,0402,RES-CHIP-49.9-1%-1/16W-0402-TAP; signal model: R2_6013A0076901_49_9_1%_2; room: Sheet38
R4542 = RSC_0402: part number: RSC_0402-2.49K_1%_2,6013A008810K,RSC_100X050X040_2,0.55MM,RSC_0402,0402,RES-CHIP-2.49K-1%-1/16W-0402-TAP; signal model: R2_6013A008810K_2_49K_1%_2; room: Sheet38
R4543 = RSC_0402: part number: RSC_0402-200K_5%_2,60130B20400Y,RSC_100X050X040_2,0.55MM,RSC_0402,0402,RES-CHIP-200K-5%-1/16W-0402-TAP; signal model: R2_60130B20400Y_200K_5%_2; room: Sheet38
R4544 R4548 R4551 R4851 = RSC_0402: part number: RSC_0402-4.7K_5%_2,60130B4720ZT,RSC_100X050X040_2,0.55MM,RSC_0402,0402,RES-CHIP-4.7K-5%-1/16W-0402-TAP; signal model: R2_60130B4720ZT_4_7K_5%_2; room: Sheet38
R4549 R4550 = RSC_0402: part number: RSC_0402-100K_5%_2,60130B1040ZT,RSC_100X050X040_2,0.55MM,RSC_0402,0402,RES-CHIP-100K-5%-1/16W-0402-TAP; signal model: R2_60130B1040ZT_100K_5%_2; room: Sheet38
R4553 R4894 R4895 = RSC_0402: part number: RSC_0402-1K_5%_2,60130B1020ZT,RSC_100X050X040_2,0.55MM,RSC_0402,0402,RES-CHIP-1K-5%-1/16W-0402-TAP; signal model: R2_60130B1020ZT_1K_5%_2; room: Sheet38
R4554 R4693 = RSC_0402: part number: RSC_0402-10K_1%_2_DY,60130B10029Z_DY,RSC_100X050X040_2,0.55MM,RSC_0402,0402,RES-CHIP-10K-1%-1/16W-0402-TAP; signal model: R2_60130B10029Z_DY_10K_1%_2_DY; room: Sheet38
R4555 = RSC_0402: part number: RSC_0402-100_1%_2,6013A0016701,RSC_100X050X040_2,0.55MM,RSC_0402,0402,RES-CHIP-100OHM-1%-1/16W-0402-TAP; signal model: R2_6013A0016701_100_1%_2; room: Sheet38
R4560 R4583 R4681-R4684 = RSC_0402: part number: RSC_0402-2.2K_5%_2,6013A0049601,RSC_100X050X040_2,0.55MM,RSC_0402,0402,RES-CHIP-2.2K-5%-1/16W-0402-TAP; signal model: R2_6013A0049601_2_2K_5%_2; room: Sheet38
R4561 R4562 = RSC_0402: part number: RSC_0402-2.2K_5%_2_DY,6013A0049601_DY,RSC_100X050X040_2,0.55MM,RSC_0402,0402,RES-CHIP-2.2K-5%-1/16W-0402-TAP; signal model: R2_6013A0049601_DY_2_2K_5%_2_DY; room: Sheet38
R4563 = RSC_0402: part number: RSC_0402-402_1%_2,6013A0023801,RSC_100X050X040_2,0.55MM,RSC_0402,0402,RES-CHIP-402-1%-1/16W-0402-TAP; signal model: R2_6013A0023801_402_1%_2; room: Sheet39
R4564 = RSC_0603: part number: RSC_0603-113_1%_3,6013A0021101,RSC_160X080X055_2,0.7MM,RSC_0603,0603,RES-CHIP-113-1%-1/10W-0603-TAP; signal model: R2_6013A0021101_113_1%_3; room: Sheet39
R4571 R4572 = RSC_0402: part number: RSC_0402-22_5%_2,60130B2200ZT,RSC_100X050X040_2,0.55MM,RSC_0402,0402,RES-CHIP-22-5%-1/16W-0402-TAP; signal model: R2_60130B2200ZT_22_5%_2; room: Sheet40
R4573 R4814 = RSC_0402: part number: RSC_0402-0_5%_2_DY,60130B0000ZT_DY,RSC_100X050X040_2,0.55MM,RSC_0402,0402,RES-CHIP-0OHM-5%-1/16W-0402-TAP; signal model: R2_60130B0000ZT_DY_0_5%_2_DY; room: Sheet40
R4574 R4617-R4620 R4698-R4701 R4726 = RSC_0402: part number: RSC_0402-100_1%_2,6013A0016701,RSC_100X050X040_2,0.55MM,RSC_0402,0402,RES-CHIP-100OHM-1%-1/16W-0402-TAP; signal model: R2_6013A0016701_100_1%_2; room: Sheet40
R4575 R4580 R4581 = RSC_0402: part number: RSC_0402-20K_5%_2,6013A0050701,RSC_100X050X040_2,0.55MM,RSC_0402,0402,RES-CHIP-20K-5%-1/16W-0402-TAP; signal model: R2_6013A0050701_20K_5%_2; room: Sheet40
R4576 = RSC_0402: part number: RSC_0402-0_5%_2,60130B0000ZT,RSC_100X050X040_2,0.55MM,RSC_0402,0402,RES-CHIP-0OHM-5%-1/16W-0402-TAP; signal model: R2_60130B0000ZT_0_5%_2; room: Sheet40
R4578 = RSC_0603: part number: RSC_0603-0_5%_3_DY,60130B00000Z_DY,RSC_160X080X055_2,0.7MM,RSC_0603,0603,RES-CHIP-0-5%-1/10W-TAP; signal model: R2_60130B00000Z_0_5%_3_DY; room: Sheet40
R4579 = RSC_0402: part number: RSC_0402-10M_5%_2,60130B10600Y,RSC_100X050X040_2,0.55MM,RSC_0402,0402,RES-CHIP-10M-5%-1/16W-0402-TAP; signal model: R2_60130B10600Y_10M_5%_2; room: Sheet40; signal model: R2_60130B10600Y_10M_5%_22
R4582 R4849 R4902 R4903 = RSC_0402: part number: RSC_0402-10K_5%_2_DY,60130B1030ZT_DY,RSC_100X050X040_2,0.55MM,RSC_0402,0402,RES-CHIP,10K,5%,1/16W,0402,TR; signal model: R2_60130B1030ZT_DY_10K_5%_2_DY; room: Sheet38
R4584 = RSC_0402: part number: RSC_0402-4.7K_5%_2,60130B4720ZT,RSC_100X050X040_2,0.55MM,RSC_0402,0402,RES-CHIP-4.7K-5%-1/16W-0402-TAP; signal model: R2_60130B4720ZT_4_7K_5%_2; room: Sheet40
R4586 R4660 R4820 = RSC_0402: part number: RSC_0402-10K_5%_2,60130B1030ZT,RSC_100X050X040_2,0.55MM,RSC_0402,0402,RES-CHIP,10K,5%,1/16W,0402,TR; signal model: R2_60130B1030ZT_10K_5%_2; room: Sheet40
R4587 R4628 = RSC_0402: part number: RSC_0402-1K_5%_2,60130B1020ZT,RSC_100X050X040_2,0.55MM,RSC_0402,0402,RES-CHIP-1K-5%-1/16W-0402-TAP; signal model: R2_60130B1020ZT_1K_5%_2; room: Sheet40
R4590 R4592 R4596 R4645 R4850 = RSC_0402: part number: RSC_0402-200_1%_2,6013A0023701,RSC_100X050X040_2,0.55MM,RSC_0402,0402,RES-CHIP-200-1%-1/16W-0402-TAP; signal model: R2_6013A0023701_200_1%_2; room: Sheet44
R4591 R4593 = RSC_0402: part number: RSC_0402-0_5%_2_DY,60130B0000ZT_DY,RSC_100X050X040_2,0.55MM,RSC_0402,0402,RES-CHIP-0OHM-5%-1/16W-0402-TAP; signal model: R2_60130B0000ZT_DY_0_5%_2_DY; room: Sheet38
R4601 R4604 R4614 R4647 R4846 R4847 = RSC_0402: part number: RSC_0402-0_5%_2,60130B0000ZT,RSC_100X050X040_2,0.55MM,RSC_0402,0402,RES-CHIP-0OHM-5%-1/16W-0402-TAP; signal model: R2_60130B0000ZT_0_5%_2; room: Sheet44
R4602 R4605 = RSC_0402: part number: RSC_0402-301_1%_2,6013A0076501,RSC_100X050X040_2,0.55MM,RSC_0402,0402,RES-CHIP-301-1%-1/16W-0402-TAP; signal model: R2_6013A0076501_301_1%_2; room: Sheet44
R4621-R4623 = RSC_SHORT: part number: RSC_SHORT-SHORT_0402_5,SHORT_0402_5,RSC_100X050X040_2_SHORT,0.127MM,RSC_SHORT,SHORT_0402_5; signal model: R2_short_0402_5_short_0402_5; room: Sheet40
R4625 = RSC_0402: part number: RSC_0402-2.7K_5%_2,60130B27200Z,RSC_100X050X040_2,0.55MM,RSC_0402,0402,RES-CHIP-2.7K-5%-1/16W-0402-TAP; signal model: R2_60130B27200Z_2_7K_5%_2; room: Sheet40
R4631 R4633 R4648 R4805 R4806 = RSC_0402: part number: RSC_0402-10_5%_2,60130B10000X,RSC_100X050X040_2,0.55MM,RSC_0402,0402,RES-CHIP-10-5%-1/16W-0402-TAP; signal model: R2_60130B10000X_10_5%_2; room: Sheet37
R4632 = RSC_0402: part number: RSC_0402-8.2K_5%_2,6013A0050801,RSC_100X050X040_2,0.55MM,RSC_0402,0402,RES-CHIP-8.2K-5%-1/16W-0402-TAP; signal model: R2_6013A0050801_8_2K_5%_2; room: Sheet38
R4635 = RSC_SHORT: part number: RSC_SHORT-SHORT_0402_5,SHORT_0402_5,RSC_100X050X040_2_SHORT,0.127MM,RSC_SHORT,SHORT_0402_5; signal model: R2_short_0402_5_short_0402_5; room: Sheet38
R4637 = RSC_0402: part number: RSC_0402-0_5%_2_DY,60130B0000ZT_DY,RSC_100X050X040_2,0.55MM,RSC_0402,0402,RES-CHIP-0OHM-5%-1/16W-0402-TAP; signal model: R2_60130B0000ZT_DY_0_5%_2_DY; room: Sheet45
R4641 R4644 = RSC_0402: part number: RSC_0402-2.2K_5%_2,6013A0049601,RSC_100X050X040_2,0.55MM,RSC_0402,0402,RES-CHIP-2.2K-5%-1/16W-0402-TAP; signal model: R2_6013A0049601_2_2K_5%_2; room: Sheet45
R4659 = RSC_0402: part number: RSC_0402-20K_5%_2,6013A0050701,RSC_100X050X040_2,0.55MM,RSC_0402,0402,RES-CHIP-20K-5%-1/16W-0402-TAP; signal model: R2_6013A0050701_20K_5%_2; room: Sheet45
R4661 = RSC_0402: part number: RSC_0402-10K_5%_2_DY,60130B1030ZT_DY,RSC_100X050X040_2,0.55MM,RSC_0402,0402,RES-CHIP,10K,5%,1/16W,0402,TR; signal model: R2_60130B1030ZT_DY_10K_5%_2_DY; room: Sheet45
R4670 R4680 = RSC_0402: part number: RSC_0402-100K_5%_2,60130B1040ZT,RSC_100X050X040_2,0.55MM,RSC_0402,0402,RES-CHIP-100K-5%-1/16W-0402-TAP; signal model: R2_60130B1040ZT_100K_5%_2; room: Sheet45
R4671 R4677 = RSC_0402: part number: RSC_0402-10K_5%_2,60130B1030ZT,RSC_100X050X040_2,0.55MM,RSC_0402,0402,RES-CHIP,10K,5%,1/16W,0402,TR; signal model: R2_60130B1030ZT_10K_5%_2; room: Sheet39
R4676 = RSC_0402: part number: RSC_0402-45.3_1%_2,6013A008750L,RSC_100X050X040_2,0.55MM,RSC_0402,0402,RES-CHIP-45.3-1%-1/16-0402-TAP; signal model: R2_6013A008750L_45_3_1%_2; room: Sheet39
R4702 = RSC_0402: part number: RSC_0402-100K_5%_2,60130B1040ZT,RSC_100X050X040_2,0.55MM,RSC_0402,0402,RES-CHIP-100K-5%-1/16W-0402-TAP; signal model: R2_60130B1040ZT_100K_5%_2; room: Sheet37
R4708 = RSC_SHORT: part number: RSC_SHORT-SHORT_0603_25,SHORT_0603_25,RSC_160X080X080_2_25_SHORT,0.127MM,RSC_SHORT,SHORT_0603_25; signal model: R2_short_0603_25_short_0603_25; room: Sheet42
R4709 = RSC_0402: part number: RSC_0402-10K_5%_2_DY,60130B1030ZT_DY,RSC_100X050X040_2,0.55MM,RSC_0402,0402,RES-CHIP,10K,5%,1/16W,0402,TR; signal model: R2_60130B1030ZT_DY_10K_5%_2_DY; room: Sheet40
R4711 = RSC_0402: part number: RSC_0402-150_1%_2,60130B15009Y,RSC_100X050X040_2,0.55MM,RSC_0402,0402,RES-CHIP-150-1%-1/16W-0402-TAP; signal model: R2_60130B15009Y_150_1%_2; room: Sheet36
R4712 = RSC_0402: part number: RSC_0402-80.6_1%_2,6013A008760G,RSC_100X050X040_2,0.55MM,RSC_0402,0402,RES-CHIP-80.6-1%-1/16W-0402-TAP; signal model: R2_6013A008760G_80_6_1%_2; room: Sheet36
R4807 = RSC_0402: part number: RSC_0402-33_5%_2,60130B3300ZT,RSC_100X050X040_2,0.55MM,RSC_0402,0402,RES-CHIP-33-5%-1/16W-0402-TAP; signal model: R2_60130B3300ZT_33_5%_2; room: Sheet37
R4809 R4811 = RSC_0402: part number: RSC_0402-10_5%_2,60130B10000X,RSC_100X050X040_2,0.55MM,RSC_0402,0402,RES-CHIP-10-5%-1/16W-0402-TAP; signal model: R2_60130B10000X_10_5%_2; room: Sheet36
R4810 = RSC_0402: part number: RSC_0402-10_5%_2_DY,60130B10000X_DY,RSC_100X050X040_2,0.55MM,RSC_0402,0402,RES-CHIP-10-5%-1/16W-0402-TAP; signal model: R2_60130B10000X_DY_10_5%_2_DY; room: Sheet36
R4815 R4843 = RSC_0402: part number: RSC_0402-100K_5%_2,60130B1040ZT,RSC_100X050X040_2,0.55MM,RSC_0402,0402,RES-CHIP-100K-5%-1/16W-0402-TAP; signal model: R2_60130B1040ZT_100K_5%_2; room: Sheet40
R4828 = RSC_0402: part number: RSC_0402-5.1_5%_2,6013A008950J,RSC_100X050X040_2,0.55MM,RSC_0402,0402,RES-CHIP-5.1-5%-1/16-0402-TAP; signal model: R2_6013A008950J_5_1_5%_2; room: Sheet40
R4835 = RSC_SHORT: part number: RSC_SHORT-SHORT_0402_15,SHORT_0402_15,RSC_100X050X040_2_15_SHORT,0.127MM,RSC_SHORT,SHORT_0402_15; signal model: R2_short_0402_15_short_0402_15; room: Sheet42
R4836 = RSC_0402: part number: RSC_0402-RSC_0402_DY,RSC_0402_DY,RSC_100X050X040_2,0.55MM,RSC_0402,0402,RSC_0402_DY; signal model: R2_RSC_0402_DY_RSC_0402_DY; room: Sheet40
R4837 = RSC_0402: part number: RSC_0402-0_5%_2,60130B0000ZT,RSC_100X050X040_2,0.55MM,RSC_0402,0402,RES-CHIP-0OHM-5%-1/16W-0402-TAP; signal model: R2_60130B0000ZT_0_5%_2; room: Sheet39
R4844 = RSC_0402: part number: RSC_0402-4.7K_5%_2_DY,60130B4720ZT_DY,RSC_100X050X040_2,0.55MM,RSC_0402,0402,RES-CHIP-4.7K-5%-1/16W-0402-TAP; signal model: R2_60130B4720ZT_DY_4_7K_5%_2_DY; room: Sheet38
R4892 R4893 = RSC_0402: part number: RSC_0402-1K_5%_2_DY,60130B1020ZT_DY,RSC_100X050X040_2,0.55MM,RSC_0402,0402,RES-CHIP-1K-5%-1/16W-0402-TAP; signal model: R2_60130B1020ZT_DY_1K_5%_2_DY; room: Sheet38
R6000 R6001 = RSC_1206_4PIN: part number: RSC_1206_4PIN-0.02_1%_6,6013B0181301,RSC_320X160X160_4,0.90MM,RSC_1206_4PIN,RESISTOR-M/F,0.02,1%,1W,1206,TR; signal model: R4_6013B0181301_0_02_1%_6; room: Sheet5
R6002 = RSC_0402: part number: RSC_0402-20.5K_1%_2,6013A008840P,RSC_100X050X040_2,0.55MM,RSC_0402,0402,RES-CHIP-20.5K-1%-1/16W-0402-TAP; signal model: R2_6013A008840P_20_5K_1%_2; room: Sheet5
R6003 = RSC_0402: part number: RSC_0402-3.32K_1%,6013A0088203,RSC_100X050X040_2,0.55MM,RSC_0402,0402,RESISTOR-CHIP,3.32KOHM,1%,1/16W,0402,TAPMM; signal model: R2_6013A0088203_3_32K_1%; room: Sheet5
R6004 R6005 R6009 = RSC_0402: part number: RSC_0402-4.3K_5%_2,60130B43200Z,RSC_100X050X040_2,0.55MM,RSC_0402,0402,RES-CHIP-4.3K-5%-1/16W-0402-TAP; signal model: R2_60130B43200Z_4_3K_5%_2; room: Sheet5
R6007 = RSC_0402: part number: RSC_0402-110K_5%_2,6013A008990A,RSC_100X050X040_2,0.55MM,RSC_0402,0402,RES-CHIP-110K-5%-1/16-0402-TAP; signal model: R2_6013A008990A_110K_5%_2; room: Sheet5
R6008 = RSC_0402: part number: RSC_0402-91K_5%_2,6013A0089908,RSC_100X050X040_2,0.55MM,RSC_0402,0402,RES-CHIP-91K-5%-1/16W-0402-TAP; signal model: R2_6013A0089908_91K_5%_2; room: Sheet5
R6012 = RSC_0805: part number: RSC_0805-10_5%_5,60130BA1003S,RSC_200X125X115_2,1.3MM,RSC_0805,0805,RES-CHIP-10-5%-1/8W-0805-TAP; signal model: R2_60130BA1003S_10_5%_5; room: Sheet5
R6020 R7600 = RSC_0603: part number: RSC_0603-4.7_5%_3,60130B4R700T,RSC_160X080X080_2,0.95MM,RSC_0603,0603,RES-CHIP-4.7-5%-1/10W-0603-TAP; signal model: R2_60130B4R700T_4_7_5%_3; room: Sheet5
R6050 R6052 = RSC_0402: part number: RSC_0402-33_5%_2,60130B3300ZT,RSC_100X050X040_2,0.55MM,RSC_0402,0402,RES-CHIP-33-5%-1/16W-0402-TAP; signal model: R2_60130B3300ZT_33_5%_2; room: Sheet5
R6051 = RSC_0402: part number: RSC_0402-1K_5%_2,60130B1020ZT,RSC_100X050X040_2,0.55MM,RSC_0402,0402,RES-CHIP-1K-5%-1/16W-0402-TAP; signal model: R2_60130B1020ZT_1K_5%_2; room: Sheet5
R6053 = RSC_0402: part number: RSC_0402-220K_5%_2,6013A0076001,RSC_100X050X040_2,0.55MM,RSC_0402,0402,RES-CHIP-220K-5%-1/16W-0402-TAP; signal model: R2_6013A0076001_220K_5%_2; room: Sheet5
R6054 = RSC_0402: part number: RSC_0402-RSC_0402_DY,RSC_0402_DY,RSC_100X050X040_2,0.55MM,RSC_0402,0402,RSC_0402_DY; signal model: R2_RSC_0402_DY_RSC_0402_DY; room: Sheet5
R6055 = RSC_0402: part number: RSC_0402-10K_5%_2,60130B1030ZT,RSC_100X050X040_2,0.55MM,RSC_0402,0402,RES-CHIP,10K,5%,1/16W,0402,TR; signal model: R2_60130B1030ZT_10K_5%_2; room: Sheet5
R6115 R6165 = RSC_0603: part number: RSC_0603-2.2_5%_3,60130B2R200T,RSC_160X080X080_2,0.95MM,RSC_0603,0603,RES-CHIP-2.2-5%-1/10W-0603-TAP; signal model: R2_60130B2R200T_2_2_5%_3; room: Sheet6
R6150 = RSC_0402: part number: RSC_0402-75K_1%_2,6013A008860M,RSC_100X050X040_2,0.55MM,RSC_0402,0402,RES-CHIP-75K-1%-1/16W-0402-TAP; signal model: R2_6013A008860M_75K_1%_2; room: Sheet6
R6151 = RSC_0402: part number: RSC_0402-10K_1%_2,60130B10029Z,RSC_100X050X040_2,0.55MM,RSC_0402,0402,RES-CHIP-10K-1%-1/16W-0402-TAP; signal model: R2_60130B10029Z_10K_1%_2; room: Sheet6
R6161 R6167 = RSC_SHORT: part number: RSC_SHORT-SHORT_0402_15,SHORT_0402_15,RSC_100X050X040_2_15_SHORT,0.127MM,RSC_SHORT,SHORT_0402_15; signal model: R2_short_0402_15_short_0402_15; room: Sheet6
R6166 = RSC_0402: part number: RSC_0402-RSC_0402_DY,RSC_0402_DY,RSC_100X050X040_2,0.55MM,RSC_0402,0402,RSC_0402_DY; signal model: R2_RSC_0402_DY_RSC_0402_DY; room: Sheet6
R6198 = RSC_0402: part number: RSC_0402-100K_5%_2,60130B1040ZT,RSC_100X050X040_2,0.55MM,RSC_0402,0402,RES-CHIP-100K-5%-1/16W-0402-TAP; signal model: R2_60130B1040ZT_100K_5%_2; room: Sheet6
R6610 = RSC_1206_4PIN: part number: RSC_1206_4PIN-0.002_1%_6,6013B0240203,RSC_320X160X080_4,0.95MM,RSC_1206_4PIN,RESISTOR-M/F,0.002,1%,1W,1206,TR; signal model: R4_6013B0240203_0_05_1%_6; room: Sheet9
R6612 R6650 = RSC_0402: part number: RSC_0402-0_5%_2,60130B0000ZT,RSC_100X050X040_2,0.55MM,RSC_0402,0402,RES-CHIP-0OHM-5%-1/16W-0402-TAP; signal model: R2_60130B0000ZT_0_5%_2; room: Sheet8
R6615 R6645 = RSC_0603: part number: RSC_0603-2.2_5%_3,60130B2R200T,RSC_160X080X080_2,0.95MM,RSC_0603,0603,RES-CHIP-2.2-5%-1/10W-0603-TAP; signal model: R2_60130B2R200T_2_2_5%_3; room: Sheet8
R6616 R6659 R6660 = RSC_0402: part number: RSC_0402-1K_1%_2,60130B10019Z,RSC_100X050X040_2,0.55MM,RSC_0402,0402,RES-CHIP-1K-1%-1/16W-0402-TAP; signal model: R2_60130B10019Z_1K_1%_2; room: Sheet8
R6618 = RSC_0402: part number: RSC_0402-3.3K_1%_2,60130B33019Z,RSC_100X050X040_2,0.55MM,RSC_0402,0402,RES-CHIP-3.3K-1%-1/16W-0402-TAP; signal model: R2_60130B33019Z_3_3K_1%_2; room: Sheet8
R6619 = RSC_0402: part number: RSC_0402-49.9_1%_2,6013A0076901,RSC_100X050X040_2,0.55MM,RSC_0402,0402,RES-CHIP-49.9-1%-1/16W-0402-TAP; signal model: R2_6013A0076901_49_9_1%_2; room: Sheet8
R6633 = RSC_0402: part number: RSC_0402-4.02K_1%_2,6013A008820B,RSC_100X050X040_2,0.55MM,RSC_0402,0402,RES-CHIP-4.02K-1%-1/16W-0402-TAP; signal model: R2_6013A008820B_4_02K_1%_2; room: Sheet8
R6643 R6663 R6666 = RSC_SHORT: part number: RSC_SHORT-SHORT_0402_5,SHORT_0402_5,RSC_100X050X040_2_SHORT,0.127MM,RSC_SHORT,SHORT_0402_5; signal model: R2_short_0402_5_short_0402_5; room: Sheet8
R6646 = RSC_0402: part number: RSC_0402-22.1K_1%_2,6013A008840T,RSC_100X050X040_2,0.55MM,RSC_0402,0402,RES-CHIP-22.1K-1%-1/16W-0402-TAP; signal model: R2_6013A008840T_22_1K_1%_2; room: Sheet8
R6647 = RSC_0402: part number: RSC_0402-10_1%_2,6013A0014201,RSC_100X050X040_2,0.55MM,RSC_0402,0402,RES-CHIP-10OHM-1%-1/16W-0402-TAP; signal model: R2_6013A0014201_10_1%_2; room: Sheet8
R6649 R6651 = RSC_0402: part number: RSC_0402-100K_1%_2,6013A0014701,RSC_100X050X040_2,0.55MM,RSC_0402,0402,RES-CHIP-100K-1%-1/16W-0402-TAP; signal model: R2_6013A0014701_100K_1%_2; room: Sheet8
R6652 = RSC_0402: part number: RSC_0402-18.7K_1%_2,6013A0017101,RSC_100X050X040_2,0.55MM,RSC_0402,0402,RES-CHIP-18.7K-1%-1/16W-0402-TAP; signal model: R2_6013A0017101_18_7K_1%_2; room: Sheet8
R6654 = RSC_0402: part number: RSC_0402-RSC_0402_DY,RSC_0402_DY,RSC_100X050X040_2,0.55MM,RSC_0402,0402,RSC_0402_DY; signal model: R2_RSC_0402_DY_RSC_0402_DY; room: Sheet8
R6655 = RSC_0402: part number: RSC_0402-46.4K_1%_2,6013A0088601,RSC_100X050X040_2,0.55MM,RSC_0402,0402,RES-CHIP-46.4K-1%-1/16-0402-TAP; signal model: R2_6013A0088601_46_4K_1%_2; room: Sheet8
R6658 = RSC_0402: part number: RSC_0402-8.25K_1%_2,6013A0024801,RSC_100X050X040_2,0.55MM,RSC_0402,0402,RES-CHIP-8.25K-1%-1/16W-0402-TAP; signal model: R2_6013A0024801_8_25K_1%_2; room: Sheet8
R6661 = RSC_THERMISTOR: part number: RSC_THERMISTOR-100K_1%_NTC,6013B0171701,RSC_100X050X055_2,0.7MM,RSC_THERMISTOR,,RESISTOR-THER,NTC,100K,0402,1%,0.1A,0.1W,SMD,TR; signal model: R2_6013B0171701_100K_1%_NTC; room: Sheet8
R6665 = RSC_SHORT: part number: RSC_SHORT-SHORT_0402_15,SHORT_0402_15,RSC_100X050X040_2_15_SHORT,0.127MM,RSC_SHORT,SHORT_0402_15; signal model: R2_short_0402_15_short_0402_15; room: Sheet8
R6710 = RSC_1206_4PIN: part number: RSC_1206_4PIN-0.002_1%_6,6013B0240203,RSC_320X160X080_4,0.95MM,RSC_1206_4PIN,RESISTOR-M/F,0.002,1%,1W,1206,TR; signal model: R4_6013B0240203_0_05_1%_6; room: Sheet11
R6712 = RSC_0402: part number: RSC_0402-0_5%_2,60130B0000ZT,RSC_100X050X040_2,0.55MM,RSC_0402,0402,RES-CHIP-0OHM-5%-1/16W-0402-TAP; signal model: R2_60130B0000ZT_0_5%_2; room: Sheet10
R6715 R6745 = RSC_0603: part number: RSC_0603-2.2_5%_3,60130B2R200T,RSC_160X080X080_2,0.95MM,RSC_0603,0603,RES-CHIP-2.2-5%-1/10W-0603-TAP; signal model: R2_60130B2R200T_2_2_5%_3; room: Sheet10
R6716 R6759 R6760 = RSC_0402: part number: RSC_0402-1K_1%_2,60130B10019Z,RSC_100X050X040_2,0.55MM,RSC_0402,0402,RES-CHIP-1K-1%-1/16W-0402-TAP; signal model: R2_60130B10019Z_1K_1%_2; room: Sheet10
R6718 = RSC_0402: part number: RSC_0402-3.3K_1%_2,60130B33019Z,RSC_100X050X040_2,0.55MM,RSC_0402,0402,RES-CHIP-3.3K-1%-1/16W-0402-TAP; signal model: R2_60130B33019Z_3_3K_1%_2; room: Sheet10
R6719 = RSC_0402: part number: RSC_0402-49.9_1%_2,6013A0076901,RSC_100X050X040_2,0.55MM,RSC_0402,0402,RES-CHIP-49.9-1%-1/16W-0402-TAP; signal model: R2_6013A0076901_49_9_1%_2; room: Sheet10
R6733 = RSC_0402: part number: RSC_0402-4.02K_1%_2,6013A008820B,RSC_100X050X040_2,0.55MM,RSC_0402,0402,RES-CHIP-4.02K-1%-1/16W-0402-TAP; signal model: R2_6013A008820B_4_02K_1%_2; room: Sheet10
R6743 R6763 R6766 = RSC_SHORT: part number: RSC_SHORT-SHORT_0402_5,SHORT_0402_5,RSC_100X050X040_2_SHORT,0.127MM,RSC_SHORT,SHORT_0402_5; signal model: R2_short_0402_5_short_0402_5; room: Sheet10
R6746 = RSC_0402: part number: RSC_0402-34.8K_1%_2,6013A0017901,RSC_100X050X040_2,0.55MM,RSC_0402,0402,RES-CHIP-34.8K-1%-1/16W-0402-TAP; signal model: R2_6013A0017901_34_8K_1%_2; room: Sheet10
R6747 = RSC_0402: part number: RSC_0402-10_1%_2,6013A0014201,RSC_100X050X040_2,0.55MM,RSC_0402,0402,RES-CHIP-10OHM-1%-1/16W-0402-TAP; signal model: R2_6013A0014201_10_1%_2; room: Sheet10
R6749 R6751 = RSC_0402: part number: RSC_0402-100K_1%_2,6013A0014701,RSC_100X050X040_2,0.55MM,RSC_0402,0402,RES-CHIP-100K-1%-1/16W-0402-TAP; signal model: R2_6013A0014701_100K_1%_2; room: Sheet10
R6750 = RSC_0402: part number: RSC_0402-48.7K_1%_2,6013A0073301,RSC_100X050X040_2,0.55MM,RSC_0402,0402,RES-CHIP-48.7K-1%-1/16W-0402-TAP; signal model: R2_6013A0073301_48_7K_1%_2; room: Sheet10
R6752 = RSC_0402: part number: RSC_0402-18.7K_1%_2,6013A0017101,RSC_100X050X040_2,0.55MM,RSC_0402,0402,RES-CHIP-18.7K-1%-1/16W-0402-TAP; signal model: R2_6013A0017101_18_7K_1%_2; room: Sheet10
R6754 = RSC_0402: part number: RSC_0402-RSC_0402_DY,RSC_0402_DY,RSC_100X050X040_2,0.55MM,RSC_0402,0402,RSC_0402_DY; signal model: R2_RSC_0402_DY_RSC_0402_DY; room: Sheet10
R6755 = RSC_0402: part number: RSC_0402-36.5K_1%_2,6013A0014001,RSC_100X050X040_2,0.55MM,RSC_0402,0402,RES-CHIP-36.5K-1%-1/16W-0402-TAP; signal model: R2_6013A0014001_36_5K_1%_2; room: Sheet10
R6758 = RSC_0402: part number: RSC_0402-8.25K_1%_2,6013A0024801,RSC_100X050X040_2,0.55MM,RSC_0402,0402,RES-CHIP-8.25K-1%-1/16W-0402-TAP; signal model: R2_6013A0024801_8_25K_1%_2; room: Sheet10
R6761 = RSC_THERMISTOR: part number: RSC_THERMISTOR-100K_1%_NTC,6013B0171701,RSC_100X050X055_2,0.7MM,RSC_THERMISTOR,,RESISTOR-THER,NTC,100K,0402,1%,0.1A,0.1W,SMD,TR; signal model: R2_6013B0171701_100K_1%_NTC; room: Sheet10
R6765 = RSC_SHORT: part number: RSC_SHORT-SHORT_0402_15,SHORT_0402_15,RSC_100X050X040_2_15_SHORT,0.127MM,RSC_SHORT,SHORT_0402_15; signal model: R2_short_0402_15_short_0402_15; room: Sheet10
R7000 R7100 R7229 R7230 R7245 R7247 = RSC_0402: part number: RSC_0402-10K_5%_2,60130B1030ZT,RSC_100X050X040_2,0.55MM,RSC_0402,0402,RES-CHIP,10K,5%,1/16W,0402,TR; signal model: R2_60130B1030ZT_10K_5%_2; room: Sheet13
R7003 R7204 R7206 R7208 R7241 R7243 R7250 R7252 = RSC_SHORT: part number: RSC_SHORT-SHORT_0402_5,SHORT_0402_5,RSC_100X050X040_2_SHORT,0.127MM,RSC_SHORT,SHORT_0402_5; signal model: R2_short_0402_5_short_0402_5; room: Sheet13
R7104 = RSC_0402: part number: RSC_0402-100K_5%_2_DY,60130B1040ZT_DY,RSC_100X050X040_2,0.55MM,RSC_0402,0402,RES-CHIP-100K-5%-1/16W-0402-TAP; signal model: R2_60130B1040ZT_DY_100K_5%_2_DY; room: Sheet13
R7110-R7112 R7115 = RSC_SHORT: part number: RSC_SHORT-SHORT_0402_5,SHORT_0402_5,RSC_100X050X040_2_SHORT,0.127MM,RSC_SHORT,SHORT_0402_5; signal model: R2_short_0402_5_short_0402_5; room: Sheet14
R7207 = RSC_0402: part number: RSC_0402-56.2K_1%_2,6013A0019701,RSC_100X050X040_2,0.55MM,RSC_0402,0402,RES-CHIP-56.2K-1%-1/16W-0402-TAP; signal model: R2_6013A0019701_56_2K_1%_2; room: Sheet13
R7246 = RSC_0402: part number: RSC_0402-100K_1%_2,6013A0014701,RSC_100X050X040_2,0.55MM,RSC_0402,0402,RES-CHIP-100K-1%-1/16W-0402-TAP; signal model: R2_6013A0014701_100K_1%_2; room: Sheet13
R7256 = RSC_0402: part number: RSC_0402-0_5%_2_DY,60130B0000ZT_DY,RSC_100X050X040_2,0.55MM,RSC_0402,0402,RES-CHIP-0OHM-5%-1/16W-0402-TAP; signal model: R2_60130B0000ZT_DY_0_5%_2_DY; room: Sheet13
R7501 R7502 = RSC_0402: part number: RSC_0402-0_5%_2,60130B0000ZT,RSC_100X050X040_2,0.55MM,RSC_0402,0402,RES-CHIP-0OHM-5%-1/16W-0402-TAP; signal model: R2_60130B0000ZT_0_5%_2; room: Sheet46
R7661 = RSC_0603: part number: RSC_0603-RSC_0603_DY,RSC_0603_DY,RSC_160X080X080_2,0.95MM,RSC_0603,0603,RSC_0603_DY; signal model: R2_RSC_0603_DY_RSC_0603_DY; room: Sheet9
R7761 = RSC_0603: part number: RSC_0603-RSC_0603_DY,RSC_0603_DY,RSC_160X080X080_2,0.95MM,RSC_0603,0603,RSC_0603_DY; signal model: R2_RSC_0603_DY_RSC_0603_DY; room: Sheet11
R9121 R9123 = RSC_0402: part number: RSC_0402-150_5%_2,60130B15100Y,RSC_100X050X040_2,0.55MM,RSC_0402,0402,RES-CHIP-150-5%-1/16W-0402-TAP; signal model: R2_60130B15100Y_150_5%_2; room: Sheet48
R9122 = RSC_0402: part number: RSC_0402-470_5%_2,60130B4710ZT,RSC_100X050X040_2,0.55MM,RSC_0402,0402,RES-CHIP-470-5%-1/16W-0402-TAP; signal model: R2_60130B4710ZT_470_5%_2; room: Sheet48
R9124 = RSC_0402: part number: RSC_0402-100_5%_2,60130B1010ZT,RSC_100X050X040_2,0.55MM,RSC_0402,0402,RES-CHIP-100-5%-1/16W-0402-TAP; signal model: R2_60130B1010ZT_100_5%_2; room: Sheet48
R60000 = RSC_0402: part number: RSC_0402-100K_5%_2,60130B1040ZT,RSC_100X050X040_2,0.55MM,RSC_0402,0402,RES-CHIP-100K-5%-1/16W-0402-TAP; signal model: R2_60130B1040ZT_100K_5%_2; room: Sheet12
R60001 = RSC_0402: part number: RSC_0402-10K_5%_2_DY,60130B1030ZT_DY,RSC_100X050X040_2,0.55MM,RSC_0402,0402,RES-CHIP,10K,5%,1/16W,0402,TR; signal model: R2_60130B1030ZT_DY_10K_5%_2_DY; room: Sheet12
R60002 = RSC_SHORT: part number: RSC_SHORT-SHORT_0402_5,SHORT_0402_5,RSC_100X050X040_2_SHORT,0.127MM,RSC_SHORT,SHORT_0402_5; signal model: R2_short_0402_5_short_0402_5; room: Sheet12
R60003 = RSC_0402: part number: RSC_0402-0_5%_2_DY,60130B0000ZT_DY,RSC_100X050X040_2,0.55MM,RSC_0402,0402,RES-CHIP-0OHM-5%-1/16W-0402-TAP; signal model: R2_60130B0000ZT_DY_0_5%_2_DY; room: Sheet12
R60017 R60018 = RSC_0402: part number: RSC_0402-470K_5%_2,60130B47400Z,RSC_100X050X040_2,0.55MM,RSC_0402,0402,RES-CHIP-470K-5%-1/16W-0402-TAP; signal model: R2_60130B47400Z_470K_5%_2; room: Sheet13
R60019 = RSC_0402: part number: RSC_0402-1M_5%_2,60130B10500Y,RSC_100X050X040_2,0.55MM,RSC_0402,0402,RES-CHIP-1M-5%-1/16W-0402-TAP; signal model: R2_60130B10500Y_1M_5%_2; room: Sheet13
R60020 = RSC_0402: part number: RSC_0402-3M_5%_2,6013A009000H,RSC_100X050X040_2,0.55MM,RSC_0402,0402,RES-CHIP,3M,5%,1/16W,0402,TR; signal model: R2_6013A009000H_3M_5%_2; room: Sheet13
R60021 = RSC_0603: part number: RSC_0603-4.7K_5%_3,60130B47200Z,RSC_160X080X080_2,0.95MM,RSC_0603,0603,RES-CHIP-4.7K-5%-1/10W-0603-TAP; signal model: R2_60130B47200Z_4_7K_5%_3; room: Sheet13
R60022 = RSC_0402: part number: RSC_0402-200_5%_2,6013A0051201,RSC_100X050X040_2,0.55MM,RSC_0402,0402,RES-CHIP-200-5%-1/16W-0402-TAP; signal model: R2_6013A0051201_200_5%_2; room: Sheet13
R60023 = RSC_0402: part number: RSC_0402-14K_1%_2,6013A0088407,RSC_100X050X040_2,0.55MM,RSC_0402,0402,RES-CHIP-14K-1%-1/16-0402-TAP; signal model: R2_6013A0088407_14K_1%_2; room: Sheet13
R60024 = RSC_0402: part number: RSC_0402-10K_1%_2,60130B10029Z,RSC_100X050X040_2,0.55MM,RSC_0402,0402,RES-CHIP-10K-1%-1/16W-0402-TAP; signal model: R2_60130B10029Z_10K_1%_2; room: Sheet13
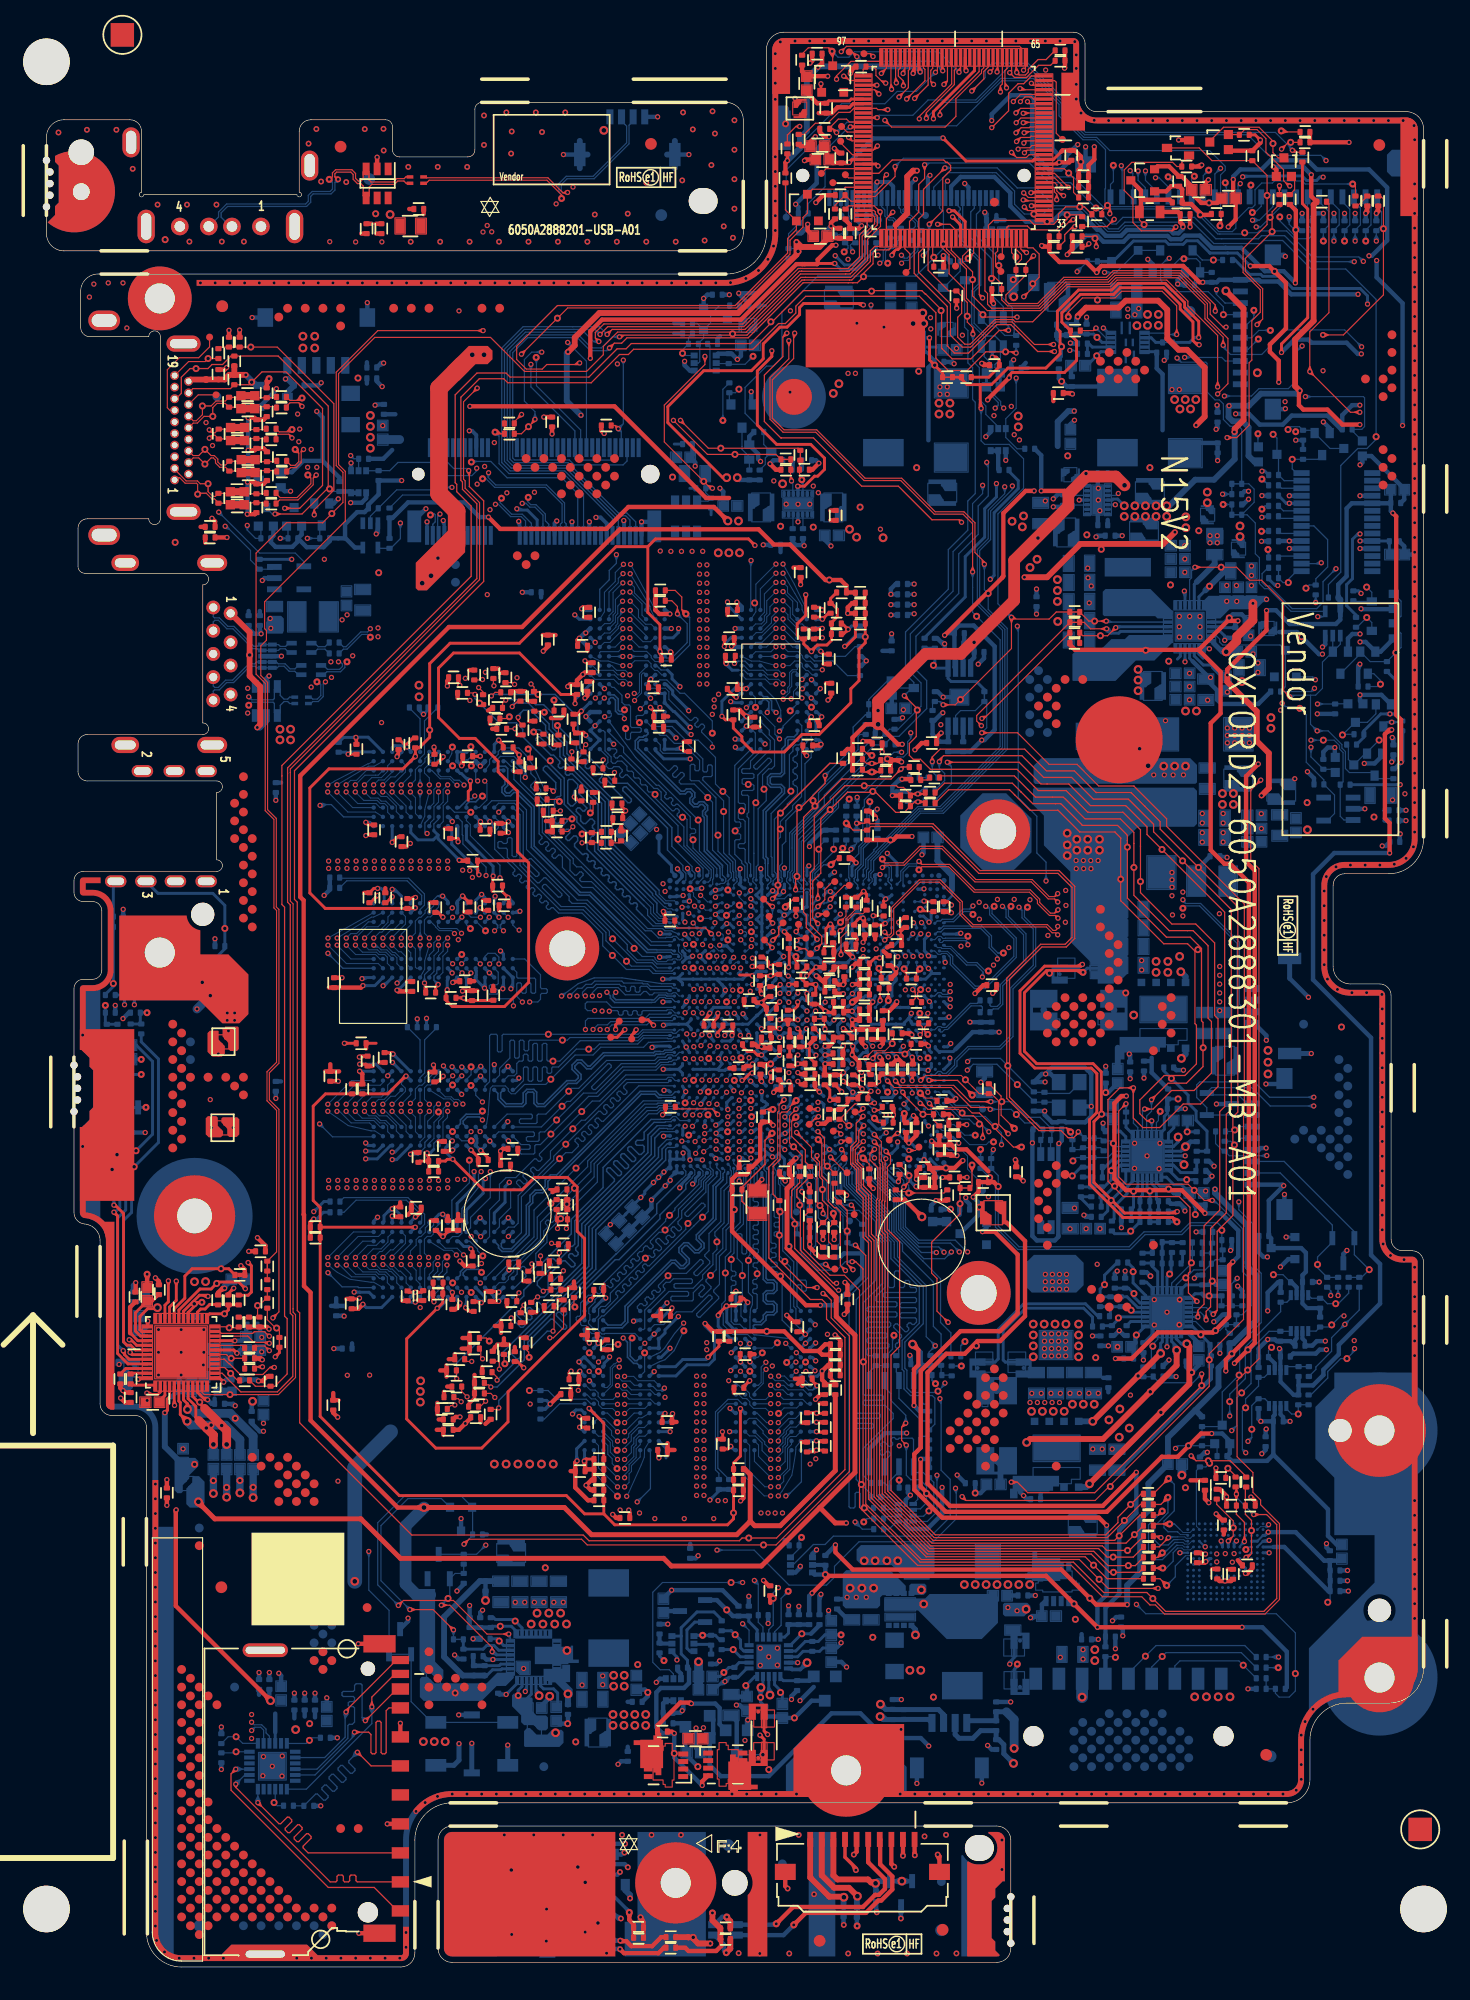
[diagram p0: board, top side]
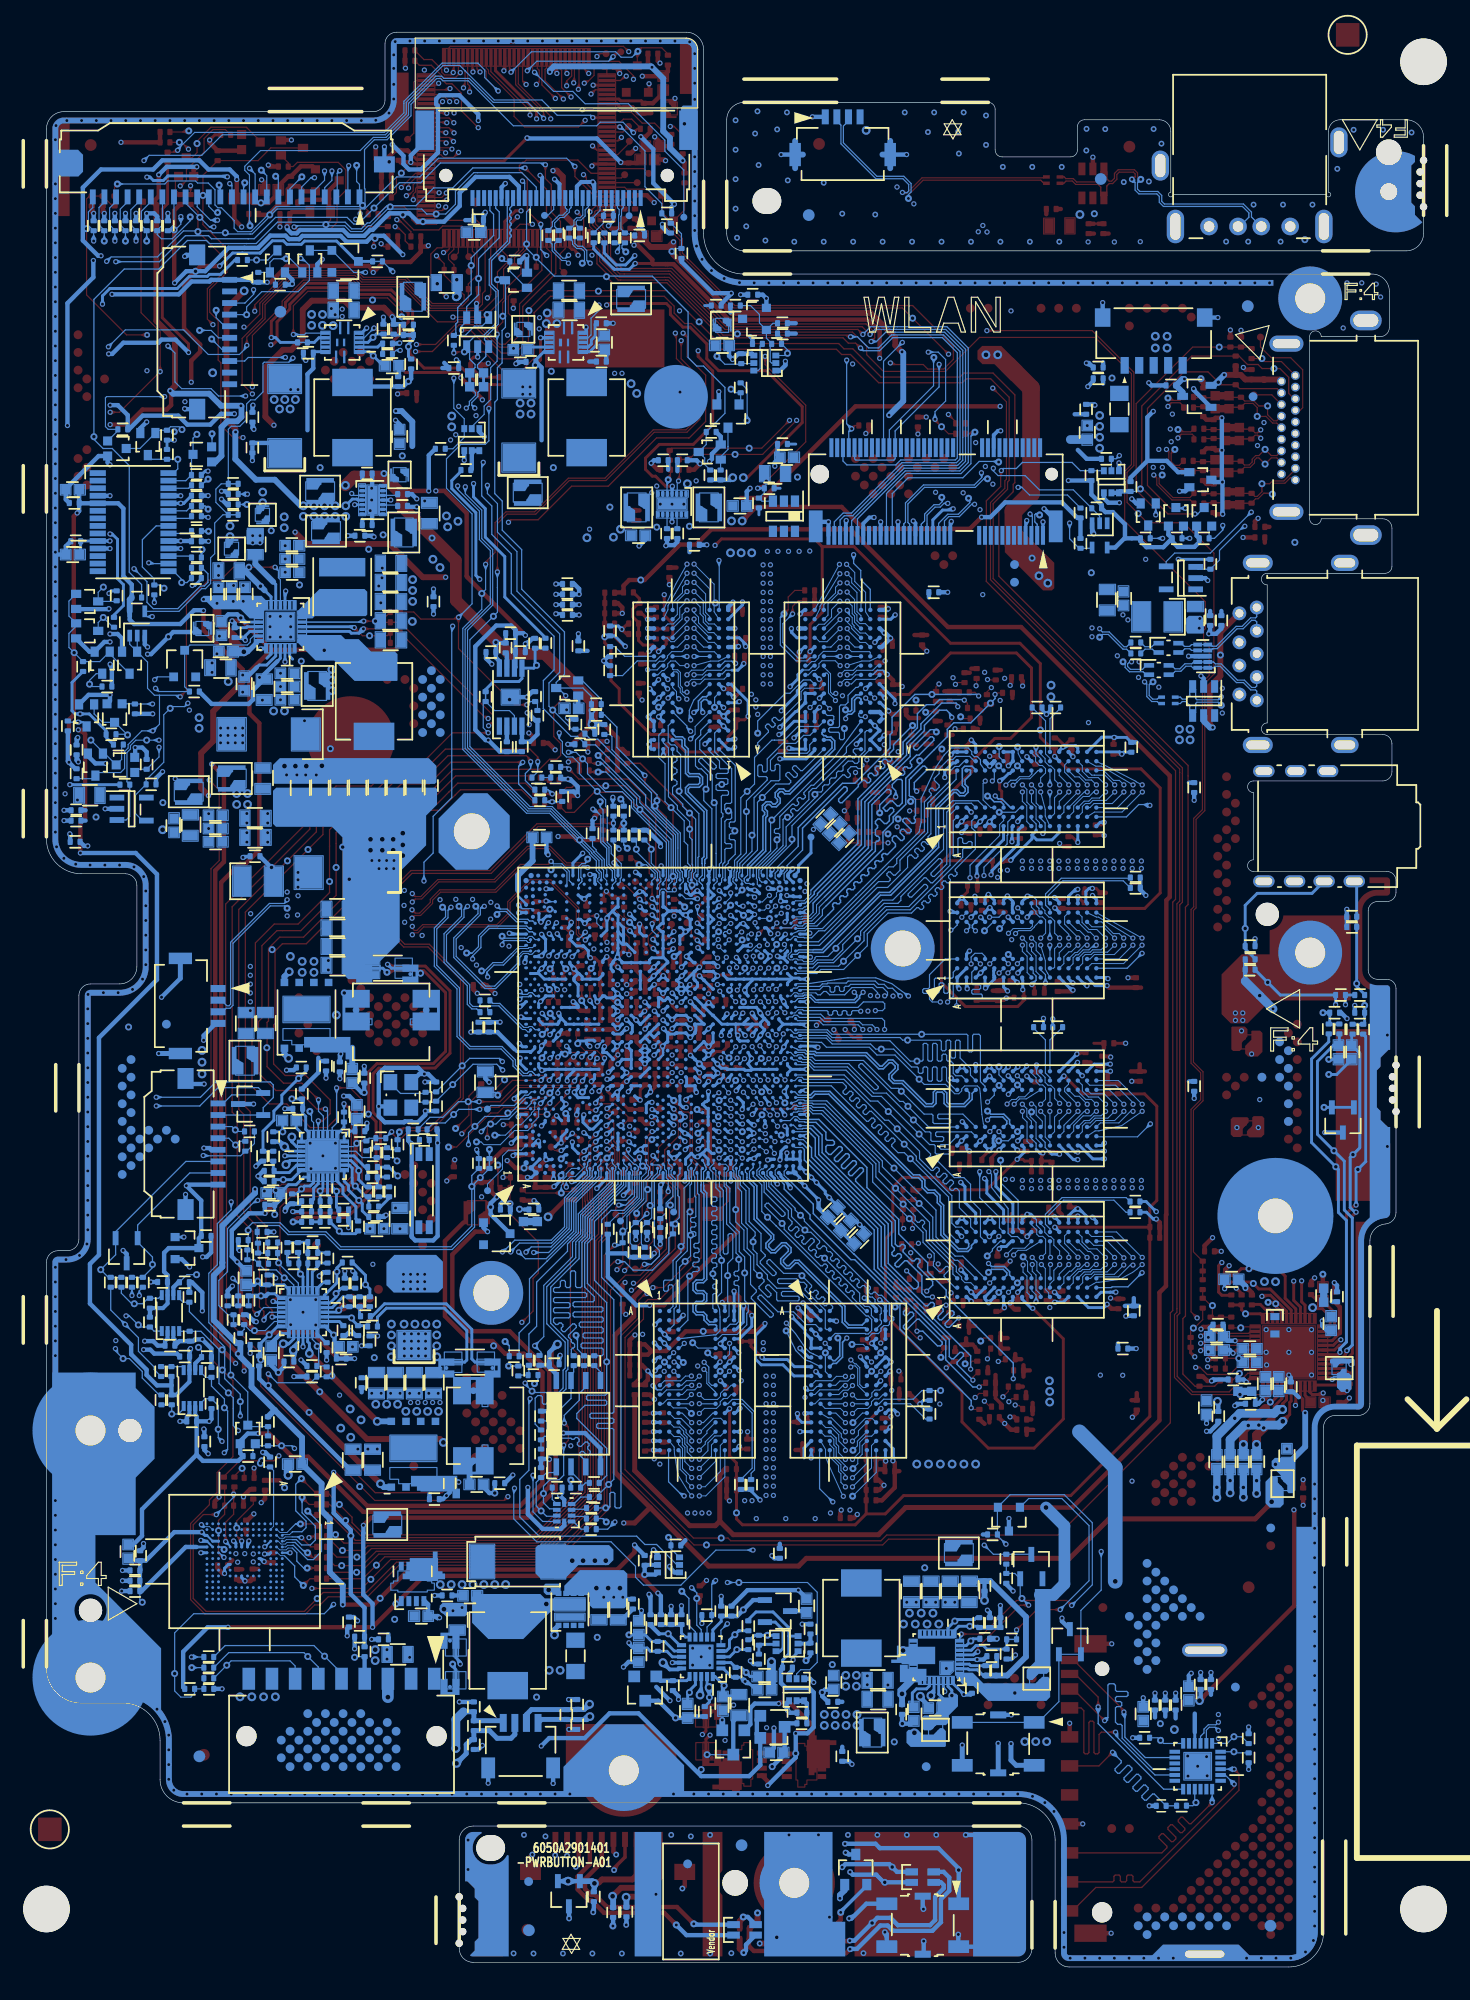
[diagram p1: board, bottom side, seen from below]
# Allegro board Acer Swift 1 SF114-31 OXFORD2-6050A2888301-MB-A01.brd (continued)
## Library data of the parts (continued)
R60300 = RSC_0402: part number: RSC_0402-8.2K_1%_2,6013A0067301,RSC_100X050X040_2,0.55MM,RSC_0402,0402,RES-CHIP-8.2K-1%-1/16W-0402-TAP; signal model: R2_6013A0067301_8_2K_1%_2; room: Sheet7
R60301 = RSC_0402: part number: RSC_0402-10K_1%_2,60130B10029Z,RSC_100X050X040_2,0.55MM,RSC_0402,0402,RES-CHIP-10K-1%-1/16W-0402-TAP; signal model: R2_60130B10029Z_10K_1%_2; room: Sheet7
R60305 = RSC_0402: part number: RSC_0402-6.04K_1%_1/16W_2,6013A0077201,RSC_100X050X040_2,0.55MM,RSC_0402,0402,RES-CHIP-6.04K-1%-1/16W-0402-TAP; signal model: R2_6013A0077201_6_04K_1%_1_16W_2; room: Sheet7
R60306 = RSC_0402: part number: RSC_0402-511K_1%_2,6013A0016201,RSC_100X050X040_2,0.55MM,RSC_0402,0402,RES-CHIP-511K-1%-1/16W-0402-TAP; signal model: R2_6013A0016201_511K_1%_2; room: Sheet7
R60309 R60359 = RSC_SHORT: part number: RSC_SHORT-SHORT_0402_15,SHORT_0402_15,RSC_100X050X040_2_15_SHORT,0.127MM,RSC_SHORT,SHORT_0402_15; signal model: R2_short_0402_15_short_0402_15; room: Sheet7
R60315 = RSC_0603: part number: RSC_0603-0_5%_3,60130B00000Z,RSC_160X080X055_2,0.7MM,RSC_0603,0603,RES-CHIP-0-5%-1/10W-TAP; signal model: R2_60130B00000Z_0_5%_3; room: Sheet7
R60316 = RSC_0603: part number: RSC_0603-RSC_0603_DY,RSC_0603_DY,RSC_160X080X080_2,0.95MM,RSC_0603,0603,RSC_0603_DY; signal model: R2_RSC_0603_DY_RSC_0603_DY; room: Sheet7
S1 S4 = SCREW_1: part number: SCREW_1-SCREW260_550_1P,SCREW260_550_1P,SCREW260_550_1P,0.127MM,SCREW_1,SCREW260_550_1P; room: Sheet15
S2 = SCREW_1: part number: SCREW_1-SCREW260_800_700_1P,SCREW260_800_700_1P,SCREW260_800_700_1P,0.127MM,SCREW_1,SCREW260_800_700_1P; room: Sheet15
S3 = SCREW_1: part number: SCREW_1-SCREW260_1000_800_1P,SCREW260_1000_800_1P,SCREW260_1000_800_1P,0.127MM,SCREW_1,SCREW260_1000_800_1P; room: Sheet15
S6 = SCREW_1: part number: SCREW_1-SCREW260_1000_600_1P,SCREW260_1000_600_1P,SCREW260_1000_600_1P,0.127MM,SCREW_1,SCREW260_1000_600_1P; room: Sheet15
S7 = SCREW_1: part number: SCREW_1-SCREW300_1000_700_1P,SCREW300_1000_700_1P,SCREW300_1000_700_1P,0.127MM,SCREW_1,SCREW300_1000_700_1P; room: Sheet15
S10 = SCREW_1: part number: SCREW_1-SCREW260_700_1P,SCREW260_700_1P,SCREW260_700_1P,0.127MM,SCREW_1,SCREW260_700_1P; room: Sheet47
S9100 = SCREW_1: part number: SCREW_1-SCREW260_700_600_1P,SCREW260_700_600_1P,SCREW260_700_600_1P,0.127MM,SCREW_1,SCREW260_700_600_1P; room: Sheet48
ST1-ST3 = STDPAD_1: part number: STDPAD_1-STANDOFF_3.1_5.5,6052B0260601,STD_R_FF40005_D30015_M20020_SN,0.65MM,STDPAD_1,STANDOFF,FF,M2.0,2.0MM,4.0MM,RND,SN,1.5MM; room: Sheet15
SW500 = TMG_533_Q_T_R: part number: TMG_533_Q_T_R-DIP_TMG_533_Q_T_R_6P,6026B0001201,SWCH-TACT_DIP_6_SMD_V_150,1.5MM,,SWITCH,TACTILE,4P,90D,SMD,TR; room: Sheet15
SW9100 = TMG_533_Q_T_R: part number: TMG_533_Q_T_R-DIP_TMG_533_Q_T_R_6P,6026B0001201,SWCH-TACT_DIP_6_SMD_V_150,1.5MM,,SWITCH,TACTILE,4P,90D,SMD,TR; room: Sheet48
TP300-TP311 TP327 TP329 = TPX_1: part number: TPX_1-TP24,TPX24,TP24,0.127MM,TPX_1,TP24; room: Sheet17
TP3001-TP3003 = TPX_1: part number: TPX_1-TP24,TPX24,TP24,0.127MM,TPX_1,TP24; room: Sheet26
TP3150-TP3152 = TPX_1: part number: TPX_1-TP24,TPX24,TP24,0.127MM,TPX_1,TP24; room: Sheet27
TP4500 TP4501 = TPX_1: part number: TPX_1-TP24,TPX24,TP24,0.127MM,TPX_1,TP24; room: Sheet34
TP4502 TP4503 = TPX_1: part number: TPX_1-TP24,TPX24,TP24,0.127MM,TPX_1,TP24; room: Sheet35
TP4504-TP4506 TP4535 TP4537 TP4551-TP4554 = TPX_1: part number: TPX_1-TP24,TPX24,TP24,0.127MM,TPX_1,TP24; room: Sheet38
TP4509-TP4517 TP4536 = TPX_1: part number: TPX_1-TP24,TPX24,TP24,0.127MM,TPX_1,TP24; room: Sheet40
TP4531 = TPX_1: part number: TPX_1-TP24,TPX24,TP24,0.127MM,TPX_1,TP24; room: Sheet36
TP4533 TP4534 = TPX_1: part number: TPX_1-TP24,TPX24,TP24,0.127MM,TPX_1,TP24; room: Sheet43
TP4540 = TPX_1: part number: TPX_1-TP24,TPX24,TP24,0.127MM,TPX_1,TP24; room: Sheet37
TP4541-TP4544 = TPX_1: part number: TPX_1-TP24,TPX24,TP24,0.127MM,TPX_1,TP24; room: Sheet39
U301 = NPCE985LB1DX: part number: NPCE985LB1DX-WINB_NPCE985LB1DX_LQFP_128P,6019B1153901,LQFP_1400X1400X160_128_040,1.75MM,,IC,EMBEDDED CONTROLLER,100KB RAM,PECI 3.; room: Sheet17
U500 = ALC233_VB2_CGT: part number: ALC233_VB2_CGT-REA_ALC233_VB2_CGT_MQFN_48P,6019B1242401,MQFN_600X600X100_48_040_T1,1.15MM,,IC,AUDIO CODEC,4 CHANNEL,MQFN,48P,TR; room: Sheet18
U900 = RTS5170_GRT: part number: RTS5170_GRT-REA_RTS5170_GRT_QFN_24P,6019B1040601,QFN_400X400X100_24_050_T8,1.15MM,,IC,CARD READER CONTRONLLER,USB2.0,QFN,24P,TR; room: Sheet20
U2000 = G524B1T11U: part number: G524B1T11U-GMT_G524B1T11U_SOT23_5P,6019B1124501,TSOT23_290X160X125_5_095,1.40MM,,IC,POWER SWITCH,SOT-23-5,5P,TR; room: Sheet22
U2406 = G524B1T11U: part number: G524B1T11U-GMT_G524B1T11U_SOT23_5P,6019B1124501,TSOT23_290X160X125_5_095,1.40MM,,IC,POWER SWITCH,SOT-23-5,5P,TR; room: Sheet23
U3151 = AP2802NTR_G1: part number: AP2802NTR_G1-GMT_G5250Q1T73U_SOT23_3P,6019B1243701,SOT23_290X160X145_3_095,1.60MM,,IC,POWER DISTRIBUTION SWITCH,SOT-23,3P,TR; room: Sheet27
U3500 = NPCT650AAAWX: part number: NPCT650AAAWX-NUVOTON_NPCT650AAAWX_TSSOP_28P_DY,6019B1234501_DY,TSSOP_970X440X120_28_065_P3,1.35MM,,IC,TPM,LPC,TSSOP28,28P,TR; room: Sheet25
U3950 = THGBMBG8D4KBAIR: part number: THGBMBG8D4KBAIR-TOSHIBA_THGBMBG8D4KBAIR_FBGA_153P,6019B1214301-001,DB10ST-6019B1214301-001,1MM,,TOSHIBA_THGBMBG8D4KBAIR_FBGA_153P; room: Sheet24
U4100 U4101 = H5TC4G63AFR: part number: H5TC4G63AFR-SAMSUNG_K4B4G1646Q_HYK0_FBGA_96P,6019B1174201,IC-DDR3_SAMSG_1330X1000X110_1,1.2MM,,IC,DDR3L SDRAM,1600MHZ,4G(256M X 16),CL11,1.35V,13.75NS,FBGA,96P,TR; room: Sheet28
U4102 U4103 = H5TC4G63AFR: part number: H5TC4G63AFR-SAMSUNG_K4B4G1646Q_HYK0_FBGA_96P,6019B1174201,IC-DDR3_SAMSG_1330X1000X110_1,1.2MM,,IC,DDR3L SDRAM,1600MHZ,4G(256M X 16),CL11,1.35V,13.75NS,FBGA,96P,TR; room: Sheet29
U4104 U4105 = H5TC4G63AFR: part number: H5TC4G63AFR-SAMSUNG_K4B4G1646Q_HYK0_FBGA_96P,6019B1174201,IC-DDR3_SAMSG_1330X1000X110_1,1.2MM,,IC,DDR3L SDRAM,1600MHZ,4G(256M X 16),CL11,1.35V,13.75NS,FBGA,96P,TR; room: Sheet31
U4106 U4107 = H5TC4G63AFR: part number: H5TC4G63AFR-SAMSUNG_K4B4G1646Q_HYK0_FBGA_96P,6019B1174201,IC-DDR3_SAMSG_1330X1000X110_1,1.2MM,,IC,DDR3L SDRAM,1600MHZ,4G(256M X 16),CL11,1.35V,13.75NS,FBGA,96P,TR; room: Sheet32
U4441 = AT9667: part number: AT9667-GMT_AT9667_MSOP8_8P,6019B1010801,MSOP_300X300X110_8_065_T2,1.25MM,,IC,TEMPERATURE SENSOR,2.7-5.5V,MSOP-8,8P; room: Sheet30
U4500 = 540276: part number: 540276-CPU_540276_BGA_1170P,TMP131223010,CPU_INT_BDW_1C_B_270X250,1.444MM,,CPU_INT_BSW_1C_270X250_1170P; room: Sheet34
U4502 = TCA9406DCUR: part number: TCA9406DCUR-TI_TCA9406DCUR_VSSOP_8P_DY,6019B1110701_DY,VSSOP_200X230X090_8_050_P2,1.05MM,,IC,LEVEL TRANSLATOR,2BIT,1.65V-5.5V,US8,8P,TR; room: Sheet38
U4503 = TCA9406DCUR: part number: TCA9406DCUR-TI_TCA9406DCUR_VSSOP_8P,6019B1110701,VSSOP_200X230X090_8_050_P2,1.05MM,,IC,LEVEL TRANSLATOR,2BIT,1.65V-5.5V,US8,8P,TR; room: Sheet38
U4504 = TC7SZ07FU: part number: TC7SZ07FU-TSB_TC7SZ07FU_SSOP_5P,6019B0599801,SSOP_200X125X100_5_065,1.15MM,,IC,NON_INVERTER,ONE,SSOP,5P,TR; room: Sheet40
U4701 = W25Q64FWSSIG: part number: W25Q64FWSSIG-MXIC_MX25U6435FM2I_10G_SOP_8P,6019B1157101,SOP_523X528X216_8_127,2.31MM,,IC,FLASH MEMORY,8M,-40~+85C,1.8V,104MHZ,4K,SOP,8P,TR; room: Sheet37
U4702 = TS3USB221ARSER: part number: TS3USB221ARSER-TI_TS3USB221ARSER_QFN_10P,6019B0661501,QFN_200X150X060_10_050,0.75MM,,IC,USB SWITCH,ESD PROTECTION,QFN,10P,TR; room: Sheet37
U4703 = AND_GATE: part number: AND_GATE-TC7SZ08FU,6019B0090701,SSOP_200X125X100_5_065,1.15MM,AND_GATE,IC,AND GATE,ONE,5PIN; room: Sheet14
U6000 = BQ24725ARGRR: part number: BQ24725ARGRR-TI_BQ24725ARGRR_QFN_20P,6019B0933901,QFN_350X350X100_20_050_T1,1.15MM,,IC,CHARGER CONTROLLER,SMBUS,QFN,20P,TR; room: Sheet5
U6100 = NB670GQ: part number: NB670GQ-MPS_NB670GQ_QFN_16P,6019B1132701,QFN_300X300X100_14_040_T2,1.15MM,,IC,DC/DC CONVERTER,QFN16,16P,TR; room: Sheet6
U6150 = NB671LGQ: part number: NB671LGQ-MPS_NB671LGQ_QFN_16P,6019B1121901,QFN_300X300X100_14_040_T1,1.15MM,,IC,DC/DC CONVERTER,QFN16,16P,TR; room: Sheet6
U6600 = NCP81101BMNTXG: part number: NCP81101BMNTXG-ON_NCP81201_QFN_28P,6019B1260901,QFN_400X400X100_28_040_T6,1.15MM,,1; room: Sheet8
U6700 = NCP81101BMNTXG: part number: NCP81101BMNTXG-ON_NCP81201_QFN_28P,6019B1260901,QFN_400X400X100_28_040_T6,1.15MM,,1; room: Sheet10
U7100 U7102 = APL3523A: part number: APL3523A-ANPEC_APL3523A_TDFN_14P,6019B1184301,TDFN_300X200X080_14_040_T1,0.95MM,,IC,LOAD SWITCH,WSON,14P,TR; room: Sheet14
U9150 = MH251EST: part number: MH251EST-MH251EST_MH251EST_TSOT23_3P,6019B1024001,IC-HALL_MST_3_SMD_V_080,1.15MM,,IC,MICROPOWER HALL SWITCH,TSOT-23,3P,TR; room: Sheet48
U60300 = G5388K11U: part number: G5388K11U-GMT_G5388K11U_QFN_32P,6019B1270701,TQFN_400X400X080_32_040_T1,0.95MM,,IC,SYNC BUCK REGULATOR,QFN,32P,TR; room: Sheet7
U60600 = RT5041AGQW: part number: RT5041AGQW-RICHTEK_RT5041AGQW_WQFN_28P,6019B1256801,WQFN_400X400X080_28_040_T2,0.95MM,,IC,SYNC BUCK REGULATOR,WQFN-28L,28P,TR; room: Sheet12
X4500 = XTAL_4PIN_19_2MHZ: part number: XTAL_4PIN_19_2MHZ-XTAL_4PIN_19.2MHZ,6018B0082801,XTAL_320X250X090_4_220-3,1.00MM,,CRYSTAL,19.2MHZ,+/-20PPM,12PF,SMD,2.5X3.2,TR; room: Sheet38
X4501 = XTAL_4PIN: part number: XTAL_4PIN-32.768KHZ_12.5PF,6018A0009301,XTAL_670X140X140_4_630,1.55MM,XTAL_4PIN,12.5PF,20PPM,XTAL-32.768KHZ(6H03200413)-20PPM-12.5PF-TAP-TXC; room: Sheet40

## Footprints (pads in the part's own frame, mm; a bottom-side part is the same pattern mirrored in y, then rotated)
AUDIO_SIGAT_6_R_165_165
  oval 1.041x1.854 hole 0.66x1.448: 1(-4.8,0) 2(4.7,-5.5) 3(-4.8,-5.2) 4(-4.8,-7.8) 5(4.7,0) 6(4.7,-2.75) MS(-4.8,-2.65)
BTB_JOINT_5_125_M_215
  rect 0.711x1.448 smd: 1(2.5,4.125) 2(1.25,4.125) 3(0,4.125) 4(-1.25,4.125) 5(-2.5,4.125)
  rect 1.346x1.6 smd: G1(4.4,0) G2(-4.4,0)
CAESAR-6014B0247601-001
  rect 0.584x0.297 smd: 1(-0.585,0.275) 2(-0.585,-0.275) 3(0.585,-0.275) 4(0.585,0.275)
CPU_INT_BDW_1C_B_270X250
  round 0.47 smd: A3(11.951,-11.814) A52(-12.383,-11.814) B2(12.383,-11.383) B53(-12.814,-11.383) BH1(12.814,11.383) BH53(-12.814,11.383) BJ2(12.383,11.814) BJ52(-12.383,11.814) C1(12.814,-10.951)
  round 0.356 smd: A5(11.17,-11.814) A6(10.447,-11.814) A7(9.748,-11.814) A9(8.836,-11.814) A47(-9.621,-11.814) A48(-10.294,-11.814) A49(-10.992,-11.814) A51(-11.773,-11.814) B4(11.632,-11.238) B5(11.038,-11.222) B6(10.445,-11.221) B8(9.258,-11.224) B46(-9.258,-11.224) B48(-10.445,-11.221) B49(-11.038,-11.222) B50(-11.632,-11.238) B52(-12.225,-11.225) BC1(12.814,8.621) BC2(12.246,8.852) BC52(-12.246,8.852) BC53(-12.814,8.621) BD1(12.814,9.294) BD2(12.221,9.445) BD52(-12.221,9.445) BD53(-12.814,9.294) BE1(12.814,9.992) BE2(12.222,10.038) BE52(-12.222,10.038) BE53(-12.814,9.992) BF2(12.238,10.632) BF52(-12.238,10.632) BG1(12.814,10.773) BG3(11.644,10.644) BG51(-11.644,10.644) BG53(-12.814,10.773) BH2(12.225,11.225) BH4(11.632,11.238) BH5(11.038,11.222) BH6(10.445,11.221) BH8(9.258,11.224) BH46(-9.258,11.224) BH48(-10.445,11.221) BH49(-11.038,11.222) BH50(-11.632,11.238) BH52(-12.225,11.225) BJ3(11.773,11.814) BJ5(10.992,11.814) BJ6(10.294,11.814) BJ7(9.621,11.814) BJ47(-9.621,11.814) BJ48(-10.294,11.814) BJ49(-10.992,11.814) BJ51(-11.773,11.814) C3(11.644,-10.644) C51(-11.644,-10.644) C53(-12.814,-10.773) D2(12.238,-10.632) D52(-12.238,-10.632) E1(12.814,-10.17) E2(12.222,-10.038) E52(-12.222,-10.038) E53(-12.814,-9.992) F1(12.814,-9.447) F2(12.221,-9.445) F52(-12.221,-9.445) F53(-12.814,-9.294) G1(12.814,-8.679) G2(12.246,-8.852) G52(-12.246,-8.852) G53(-12.814,-8.621) J1(12.814,-7.816)
  oval 0.254x0.343 smd: A11(7.774,-11.814) A13(6.803,-11.814) A15(5.831,-11.814) A17(4.859,-11.814) A19(3.887,-11.814) A21(2.915,-11.814) A23(1.944,-11.814) A25(0.972,-11.814) A27(0,-11.814) A29(-0.972,-11.814) A31(-1.944,-11.814) A33(-2.915,-11.814) A35(-3.887,-11.814) A37(-4.859,-11.814) A39(-5.831,-11.814) A41(-6.803,-11.814) A43(-7.774,-11.814) A45(-8.746,-11.814) BJ9(8.746,11.814) BJ11(7.774,11.814) BJ13(6.803,11.814) BJ15(5.831,11.814) BJ17(4.859,11.814) BJ19(3.887,11.814) BJ21(2.915,11.814) BJ23(1.944,11.814) BJ25(0.972,11.814) BJ27(0,11.814) BJ29(-0.972,11.814) BJ31(-1.944,11.814) BJ33(-2.915,11.814) BJ35(-3.887,11.814) BJ37(-4.859,11.814) BJ39(-5.831,11.814) BJ41(-6.803,11.814) BJ43(-7.774,11.814) BJ45(-8.746,11.814)
  oval 0.343x0.254 smd: AA1(12.814,-1.944) AA53(-12.814,-1.944) AC1(12.814,-0.972) AC53(-12.814,-0.972) AE1(12.814,0) AE53(-12.814,0) AG1(12.814,0.972) AG53(-12.814,0.972) AJ1(12.814,1.944) AJ53(-12.814,1.944) AL1(12.814,2.915) AL53(-12.814,2.915) AN1(12.814,3.887) AN53(-12.814,3.887) AR1(12.814,4.859) AR53(-12.814,4.859) AU1(12.814,5.831) AU53(-12.814,5.831) AW1(12.814,6.803) AW53(-12.814,6.803) BA1(12.814,7.774) BA53(-12.814,7.774) J53(-12.814,-7.774) L1(12.814,-6.803) L53(-12.814,-6.803) N1(12.814,-5.831) N53(-12.814,-5.831) R1(12.814,-4.859) R53(-12.814,-4.859) U1(12.814,-3.887) U53(-12.814,-3.887) W1(12.814,-2.915) W53(-12.814,-2.915)
  round 0.279 smd: AA3(12.071,-1.944) AA51(-12.071,-1.944) AB2(12.429,-1.458) AB3(11.73,-1.458) AB51(-11.73,-1.458) AB52(-12.429,-1.458) AC3(12.071,-0.972) AC51(-12.071,-0.972) AD2(12.429,-0.486) AD3(11.715,-0.48) AD51(-11.715,-0.48) AD52(-12.429,-0.486) AE3(12.071,0) AE4(11.366,0) AE50(-11.366,0) AE51(-12.071,0) AF2(12.429,0.486) AF3(11.715,0.48) AF51(-11.715,0.48) AF52(-12.429,0.486) AG3(12.071,0.972) AG51(-12.071,0.972) AH2(12.429,1.458) AH3(11.73,1.458) AH51(-11.73,1.458) AH52(-12.429,1.458) AJ3(12.071,1.944) AJ51(-12.071,1.944) AK2(12.429,2.43) AK3(11.73,2.43) AK51(-11.73,2.43) AK52(-12.429,2.43) AL3(12.071,2.915) AL51(-12.071,2.915) AM2(12.429,3.401) AM3(11.73,3.401) AM51(-11.73,3.401) AM52(-12.429,3.401) AN3(12.071,3.887) AN51(-12.071,3.887) AP2(12.429,4.373) AP3(11.73,4.373) AP51(-11.73,4.373) AP52(-12.429,4.373) AR3(12.071,4.859) AR51(-12.071,4.859) AT2(12.429,5.345) AT3(11.73,5.345) AT51(-11.73,5.345) AT52(-12.429,5.345) AU3(12.071,5.831) AU51(-12.071,5.831) AV2(12.429,6.317) AV3(11.73,6.317) AV51(-11.73,6.317) AV52(-12.429,6.317) AW3(12.071,6.803) AW51(-12.071,6.803) AY2(12.429,7.289) AY3(11.73,7.289) AY51(-11.73,7.289) AY52(-12.429,7.289) B10(8.26,-11.429) B12(7.289,-11.429) B14(6.317,-11.429) B16(5.345,-11.429) B18(4.373,-11.429) B20(3.401,-11.429) B22(2.43,-11.429) B24(1.458,-11.429) B26(0.486,-11.429) B28(-0.486,-11.429) B30(-1.458,-11.429) B32(-2.43,-11.429) B34(-3.401,-11.429) B36(-4.373,-11.429) B38(-5.345,-11.429) B40(-6.317,-11.429) B42(-7.289,-11.429) B44(-8.26,-11.429) BA3(12.071,7.774) BA51(-12.071,7.774) BB3(11.929,8.351) BB51(-11.929,8.351) BF27(0,10.366) BG9(8.698,11.028) BG11(7.774,11.071) BG12(7.289,10.73) BG13(6.803,11.071) BG14(6.317,10.73) BG15(5.831,11.071) BG16(5.345,10.73) BG17(4.859,11.071) BG18(4.373,10.73) BG19(3.887,11.071) BG20(3.401,10.73) BG21(2.915,11.071) BG22(2.43,10.73) BG23(1.944,11.071) BG24(1.458,10.73) BG25(0.972,11.071) BG26(0.48,10.715) BG27(0,11.071) BG28(-0.48,10.715) BG29(-0.972,11.071) BG30(-1.458,10.73) BG31(-1.944,11.071) BG32(-2.43,10.73) BG33(-2.915,11.071) BG34(-3.401,10.73) BG35(-3.887,11.071) BG36(-4.373,10.73) BG37(-4.859,11.071) BG38(-5.345,10.73) BG39(-5.831,11.071) BG40(-6.317,10.73) BG41(-6.803,11.071) BG42(-7.289,10.73) BG43(-7.774,11.071) BG45(-8.698,11.028) BH10(8.26,11.429) BH12(7.289,11.429) BH14(6.317,11.429) BH16(5.345,11.429) BH18(4.373,11.429) BH20(3.401,11.429) BH22(2.43,11.429) BH24(1.458,11.429) BH26(0.486,11.429) BH28(-0.486,11.429) BH30(-1.458,11.429) BH32(-2.43,11.429) BH34(-3.401,11.429) BH36(-4.373,11.429) BH38(-5.345,11.429) BH40(-6.317,11.429) BH42(-7.289,11.429) BH44(-8.26,11.429) C9(8.698,-11.028) C11(7.774,-11.071) C12(7.289,-10.73) C13(6.803,-11.071) C14(6.317,-10.73) C15(5.831,-11.071) C16(5.345,-10.73) C17(4.859,-11.071) C18(4.373,-10.73) C19(3.887,-11.071) C20(3.401,-10.73) C21(2.915,-11.071) C22(2.43,-10.73) C23(1.944,-11.071) C24(1.458,-10.73) C25(0.972,-11.071) C26(0.48,-10.715) C27(0,-11.071) C28(-0.48,-10.715) C29(-0.972,-11.071) C30(-1.458,-10.73) C31(-1.944,-11.071) C32(-2.43,-10.73) C33(-2.915,-11.071) C34(-3.401,-10.73) C35(-3.887,-11.071) C36(-4.373,-10.73) C37(-4.859,-11.071) C38(-5.345,-10.73) C39(-5.831,-11.071) C40(-6.317,-10.73) C41(-6.803,-11.071) C42(-7.289,-10.73) C43(-7.774,-11.071) C45(-8.698,-11.028) D27(0,-10.366) H3(11.929,-8.351) H51(-11.929,-8.351) J3(12.071,-7.774) J51(-12.071,-7.774) K2(12.429,-7.289) K3(11.73,-7.289) K51(-11.73,-7.289) K52(-12.429,-7.289) L3(12.071,-6.803) L51(-12.071,-6.803) M2(12.429,-6.317) M3(11.73,-6.317) M51(-11.73,-6.317) M52(-12.429,-6.317) N3(12.071,-5.831) N51(-12.071,-5.831) P2(12.429,-5.345) P3(11.73,-5.345) P51(-11.73,-5.345) P52(-12.429,-5.345) R3(12.071,-4.859) R51(-12.071,-4.859) T2(12.429,-4.373) T3(11.73,-4.373) T51(-11.73,-4.373) T52(-12.429,-4.373) U3(12.071,-3.887) U51(-12.071,-3.887) V2(12.429,-3.401) V3(11.73,-3.401) V51(-11.73,-3.401) V52(-12.429,-3.401) W3(12.071,-2.915) W51(-12.071,-2.915) Y2(12.429,-2.43) Y3(11.73,-2.43) Y51(-11.73,-2.43) Y52(-12.429,-2.43)
  round 0.33 smd: AA16(5.307,-1.961) AA18(4.549,-1.961) AA19(3.791,-1.961) AA21(3.033,-1.961) AA22(2.275,-1.961) AA24(1.516,-1.961) AA25(0.758,-1.961) AA27(0,-1.961) AA29(-0.758,-1.961) AA30(-1.516,-1.961) AA32(-2.275,-1.961) AA33(-3.033,-1.961) AA35(-3.791,-1.961) AA36(-4.549,-1.961) AA38(-5.307,-1.961) AC16(5.307,-1.177) AC18(4.549,-1.177) AC19(3.791,-1.177) AC21(3.033,-1.177) AC22(2.275,-1.177) AC24(1.516,-1.177) AC25(0.758,-1.177) AC27(0,-1.177) AC29(-0.758,-1.177) AC30(-1.516,-1.177) AC32(-2.275,-1.177) AC33(-3.033,-1.177) AC35(-3.791,-1.177) AC36(-4.549,-1.177) AC38(-5.307,-1.177) AD16(5.307,-0.392) AD18(4.549,-0.392) AD19(3.791,-0.392) AD21(3.033,-0.392) AD22(2.275,-0.392) AD24(1.516,-0.392) AD25(0.758,-0.392) AD27(0,-0.392) AD29(-0.758,-0.392) AD30(-1.516,-0.392) AD32(-2.275,-0.392) AD33(-3.033,-0.392) AD35(-3.791,-0.392) AD36(-4.549,-0.392) AD38(-5.307,-0.392) AF16(5.307,0.392) AF18(4.549,0.392) AF19(3.791,0.392) AF21(3.033,0.392) AF22(2.275,0.392) AF24(1.516,0.392) AF25(0.758,0.392) AF27(0,0.392) AF29(-0.758,0.392) AF30(-1.516,0.392) AF32(-2.275,0.392) AF33(-3.033,0.392) AF35(-3.791,0.392) AF36(-4.549,0.392) AF38(-5.307,0.392) AG16(5.307,1.177) AG18(4.549,1.177) AG19(3.791,1.177) AG21(3.033,1.177) AG22(2.275,1.177) AG24(1.516,1.177) AG25(0.758,1.177) AG27(0,1.177) AG29(-0.758,1.177) AG30(-1.516,1.177) AG32(-2.275,1.177) AG33(-3.033,1.177) AG35(-3.791,1.177) AG36(-4.549,1.177) AG38(-5.307,1.177) AJ16(5.307,1.961) AJ18(4.549,1.961) AJ19(3.791,1.961) AJ21(3.033,1.961) AJ22(2.275,1.961) AJ24(1.516,1.961) AJ25(0.758,1.961) AJ27(0,1.961) AJ29(-0.758,1.961) AJ30(-1.516,1.961) AJ32(-2.275,1.961) AJ33(-3.033,1.961) AJ35(-3.791,1.961) AJ36(-4.549,1.961) AJ38(-5.307,1.961) AK16(5.307,2.745) AK18(4.549,2.745) AK19(3.791,2.745) AK21(3.033,2.745) AK22(2.275,2.745) AK24(1.516,2.745) AK25(0.758,2.745) AK27(0,2.745) AK29(-0.758,2.745) AK30(-1.516,2.745) AK32(-2.275,2.745) AK33(-3.033,2.745) AK35(-3.791,2.745) AK36(-4.549,2.745) AK38(-5.307,2.745) AM16(5.307,3.53) AM18(4.549,3.53) AM19(3.791,3.53) AM21(3.033,3.53) AM22(2.275,3.53) AM24(1.516,3.53) AM25(0.758,3.53) AM27(0,3.53) AM29(-0.758,3.53) AM30(-1.516,3.53) AM32(-2.275,3.53) AM33(-3.033,3.53) AM35(-3.791,3.53) AM36(-4.549,3.53) AM38(-5.307,3.53) AN16(5.307,4.314) AN18(4.549,4.314) AN19(3.791,4.314) AN21(3.033,4.314) AN22(2.275,4.314) AN24(1.516,4.314) AN25(0.758,4.314) AN27(0,4.314) AN29(-0.758,4.314) AN30(-1.516,4.314) AN32(-2.275,4.314) AN33(-3.033,4.314) AN35(-3.791,4.314) AN36(-4.549,4.314) AN38(-5.307,4.314) U16(5.307,-4.314) U18(4.549,-4.314) U19(3.791,-4.314) U21(3.033,-4.314) U22(2.275,-4.314) U24(1.516,-4.314) U25(0.758,-4.314) U27(0,-4.314) U29(-0.758,-4.314) U30(-1.516,-4.314) U32(-2.275,-4.314) U33(-3.033,-4.314) U35(-3.791,-4.314) U36(-4.549,-4.314) U38(-5.307,-4.314) V16(5.307,-3.53) V18(4.549,-3.53) V19(3.791,-3.53) V21(3.033,-3.53) V22(2.275,-3.53) V24(1.516,-3.53) V25(0.758,-3.53) V27(0,-3.53) V29(-0.758,-3.53) V30(-1.516,-3.53) V32(-2.275,-3.53) V33(-3.033,-3.53) V35(-3.791,-3.53) V36(-4.549,-3.53) V38(-5.307,-3.53) Y16(5.307,-2.745) Y18(4.549,-2.745) Y19(3.791,-2.745) Y21(3.033,-2.745) Y22(2.275,-2.745) Y24(1.516,-2.745) Y25(0.758,-2.745) Y27(0,-2.745) Y29(-0.758,-2.745) Y30(-1.516,-2.745) Y32(-2.275,-2.745) Y33(-3.033,-2.745) Y35(-3.791,-2.745) Y36(-4.549,-2.745) Y38(-5.307,-2.745)
  round 0.305 smd: AB4(11.137,-1.448) AB6(10.463,-1.448) AB7(9.752,-1.448) AB9(9.041,-1.448) AB10(8.33,-1.448) AB12(7.618,-1.448) AB13(6.907,-1.448) AB14(6.196,-1.448) AB40(-6.196,-1.448) AB41(-6.907,-1.448) AB42(-7.618,-1.448) AB44(-8.33,-1.448) AB45(-9.041,-1.448) AB47(-9.752,-1.448) AB48(-10.463,-1.448) AB50(-11.137,-1.448) AD4(10.995,-0.463) AD6(10.404,-0.525) AD7(9.752,-0.475) AD9(9.041,-0.475) AD10(8.33,-0.475) AD12(7.618,-0.475) AD13(6.907,-0.475) AD14(6.196,-0.475) AD40(-6.196,-0.475) AD41(-6.907,-0.475) AD42(-7.618,-0.475) AD44(-8.33,-0.475) AD45(-9.041,-0.475) AD47(-9.752,-0.475) AD48(-10.404,-0.525) AD50(-10.995,-0.463) AE6(10.108,0) AE8(9.396,0) AE9(8.685,0) AE11(7.974,0) AE12(7.263,0) AE14(6.552,0) AE40(-6.552,0) AE42(-7.263,0) AE43(-7.974,0) AE45(-8.685,0) AE46(-9.396,0) AE48(-10.108,0) AF4(10.995,0.463) AF6(10.404,0.525) AF7(9.752,0.475) AF9(9.041,0.475) AF10(8.33,0.475) AF12(7.618,0.475) AF13(6.907,0.475) AF14(6.196,0.475) AF40(-6.196,0.475) AF41(-6.907,0.475) AF42(-7.618,0.475) AF44(-8.33,0.475) AF45(-9.041,0.475) AF47(-9.752,0.475) AF48(-10.404,0.525) AF50(-10.995,0.463) AH4(11.137,1.448) AH6(10.463,1.448) AH7(9.752,1.448) AH9(9.041,1.448) AH10(8.33,1.448) AH12(7.618,1.448) AH13(6.907,1.448) AH14(6.196,1.448) AH40(-6.196,1.448) AH41(-6.907,1.448) AH42(-7.618,1.448) AH44(-8.33,1.448) AH45(-9.041,1.448) AH47(-9.752,1.448) AH48(-10.463,1.448) AH50(-11.137,1.448) AK4(11.137,2.439) AK6(10.463,2.439) AK7(9.752,2.439) AK9(9.041,2.439) AK10(8.33,2.439) AK12(7.618,2.439) AK13(6.907,2.439) AK14(6.196,2.439) AK40(-6.196,2.439) AK41(-6.907,2.439) AK42(-7.618,2.439) AK44(-8.33,2.439) AK45(-9.041,2.439) AK47(-9.752,2.439) AK48(-10.463,2.439) AK50(-11.137,2.439) AM4(11.137,3.386) AM6(10.463,3.412) AM7(9.752,3.412) AM9(9.041,3.412) AM10(8.33,3.412) AM12(7.618,3.412) AM13(6.907,3.412) AM14(6.196,3.412) AM40(-6.196,3.412) AM41(-6.907,3.412) AM42(-7.618,3.412) AM44(-8.33,3.412) AM45(-9.041,3.412) AM47(-9.752,3.412) AM48(-10.463,3.412) AM50(-11.137,3.386) AN5(10.819,3.887) AN6(10.108,3.887) AN8(9.396,3.887) AN9(8.685,3.887) AN11(7.974,3.887) AN12(7.263,3.887) AN14(6.552,3.887) AN40(-6.552,3.887) AN42(-7.263,3.887) AN43(-7.974,3.887) AN45(-8.685,3.887) AN46(-9.396,3.887) AN48(-10.108,3.887) AN49(-10.819,3.887) AP4(11.137,4.388) AP6(10.463,4.362) AP7(9.752,4.362) AP9(9.041,4.362) AP10(8.33,4.362) AP12(7.618,4.362) AP13(6.907,4.362) AP14(6.196,4.362) AP40(-6.196,4.362) AP41(-6.907,4.362) AP42(-7.618,4.362) AP44(-8.33,4.362) AP45(-9.041,4.362) AP47(-9.752,4.362) AP48(-10.463,4.362) AP50(-11.137,4.388) AT4(11.137,5.336) AT6(10.463,5.336) AT7(9.752,5.336) AT9(9.041,5.336) AT10(8.33,5.336) AT12(7.618,5.336) AT13(6.907,5.336) AT14(6.305,5.336) AT16(5.336,5.196) AT18(4.362,5.196) AT19(3.887,5.552) AT20(3.412,5.196) AT22(2.439,5.196) AT24(1.448,5.196) AT26(0.475,5.196) AT27(0,5.552) AT28(-0.475,5.196) AT30(-1.448,5.196) AT32(-2.439,5.196) AT34(-3.412,5.196) AT35(-3.887,5.552) AT36(-4.362,5.196) AT38(-5.336,5.196) AT40(-6.305,5.336) AT41(-6.907,5.336) AT42(-7.618,5.336) AT44(-8.33,5.336) AT45(-9.041,5.336) AT47(-9.752,5.336) AT48(-10.463,5.336) AT50(-11.137,5.336) AU16(5.336,5.907) AU18(4.362,5.907) AU20(3.412,5.907) AU22(2.439,5.907) AU24(1.448,5.907) AU26(0.475,5.907) AU28(-0.475,5.907) AU30(-1.448,5.907) AU32(-2.439,5.907) AU34(-3.412,5.907) AU36(-4.362,5.907) AU38(-5.336,5.907) AV4(11.137,6.326) AV6(10.463,6.326) AV7(9.752,6.326) AV9(9.041,6.326) AV10(8.33,6.326) AV12(7.618,6.326) AV13(6.907,6.326) AV14(6.326,6.446) AV16(5.336,6.618) AV18(4.362,6.618) AV19(3.887,6.263) AV20(3.412,6.618) AV22(2.439,6.618) AV24(1.448,6.618) AV26(0.475,6.618) AV27(0,6.263) AV28(-0.475,6.618) AV30(-1.448,6.618) AV32(-2.439,6.618) AV34(-3.412,6.618) AV35(-3.887,6.263) AV36(-4.362,6.618) AV38(-5.336,6.618) AV40(-6.326,6.446) AV41(-6.907,6.326) AV42(-7.618,6.326) AV44(-8.33,6.326) AV45(-9.041,6.326) AV47(-9.752,6.326) AV48(-10.463,6.326) AV50(-11.137,6.326) AW13(6.751,6.915) AW19(3.887,6.974) AW27(0,6.974) AW35(-3.887,6.974) AW41(-6.751,6.915) AY4(11.137,7.317) AY6(10.463,7.317) AY7(9.752,7.317) AY9(9.041,7.317) AY10(8.33,7.317) AY12(7.317,7.34) AY14(6.326,7.33) AY16(5.336,7.33) AY18(4.362,7.33) AY20(3.412,7.33) AY22(2.439,7.33) AY24(1.448,7.33) AY26(0.475,7.33) AY28(-0.475,7.33) AY30(-1.448,7.33) AY32(-2.439,7.33) AY34(-3.412,7.33) AY36(-4.362,7.33) AY38(-5.336,7.33) AY40(-6.326,7.33) AY42(-7.317,7.34) AY44(-8.33,7.317) AY45(-9.041,7.317) AY47(-9.752,7.317) AY48(-10.463,7.317) AY50(-11.137,7.317) B7(9.852,-11.23) B47(-9.852,-11.23) BA12(7.317,8.041) BA14(6.326,8.041) BA16(5.336,8.041) BA18(4.362,8.041) BA19(3.887,7.685) BA20(3.412,8.041) BA22(2.439,8.041) BA24(1.448,8.041) BA26(0.475,8.041) BA27(0,7.685) BA28(-0.475,8.041) BA30(-1.448,8.041) BA32(-2.439,8.041) BA34(-3.412,8.041) BA35(-3.887,7.685) BA36(-4.362,8.041) BA38(-5.336,8.041) BA40(-6.326,8.041) BA42(-7.317,8.041) BB4(11.258,8.307) BB5(10.547,8.307) BB7(9.835,8.307) BB8(9.124,8.307) BB10(8.307,8.17) BB19(3.887,8.396) BB27(0,8.396) BB35(-3.887,8.396) BB44(-8.307,8.17) BB46(-9.124,8.307) BB47(-9.835,8.307) BB49(-10.547,8.307) BB50(-11.258,8.307) BC10(8.307,8.764) BC12(7.317,8.752) BC14(6.326,8.752) BC16(5.336,8.752) BC18(4.362,8.752) BC20(3.412,8.752) BC22(2.439,8.752) BC24(1.448,8.752) BC26(0.475,8.752) BC28(-0.475,8.752) BC30(-1.448,8.752) BC32(-2.439,8.752) BC34(-3.412,8.752) BC36(-4.362,8.752) BC38(-5.336,8.752) BC40(-6.326,8.752) BC42(-7.317,8.752) BC44(-8.307,8.764) BD5(10.565,9.302) BD7(9.712,9.302) BD10(8.307,9.457) BD12(7.317,9.463) BD14(6.326,9.463) BD16(5.336,9.463) BD18(4.362,9.463) BD19(3.887,9.108) BD20(3.412,9.463) BD22(2.439,9.463) BD24(1.448,9.463) BD26(0.525,9.404) BD27(0,9.108) BD28(-0.525,9.404) BD30(-1.448,9.463) BD32(-2.439,9.463) BD34(-3.412,9.463) BD35(-3.887,9.108) BD36(-4.362,9.463) BD38(-5.336,9.463) BD40(-6.326,9.463) BD42(-7.317,9.463) BD44(-8.307,9.457) BD47(-9.712,9.302) BD49(-10.565,9.302) BE3(11.643,9.58) BE8(9.32,9.747) BE19(3.887,9.819) BE35(-3.887,9.819) BE46(-9.32,9.747) BE51(-11.643,9.58) BF4(11.163,10.163) BF6(10.113,10.238) BF10(8.307,10.168) BF12(7.317,10.137) BF14(6.326,10.137) BF16(5.336,10.137) BF18(4.388,10.137) BF20(3.386,10.137) BF22(2.439,10.137) BF24(1.448,10.137) BF26(0.463,9.995) BF28(-0.463,9.995) BF30(-1.448,10.137) BF32(-2.439,10.137) BF34(-3.386,10.137) BF36(-4.388,10.137) BF38(-5.336,10.137) BF40(-6.326,10.137) BF42(-7.317,10.137) BF44(-8.307,10.168) BF48(-10.113,10.238) BF50(-11.163,10.163) BG5(10.58,10.643) BG7(9.553,10.709) BG47(-9.553,10.709) BG49(-10.58,10.643) BH7(9.852,11.23) BH47(-9.852,11.23) C5(10.58,-10.643) C7(9.553,-10.709) C47(-9.553,-10.709) C49(-10.58,-10.643) D4(11.163,-10.163) D6(10.113,-10.238) D10(8.307,-10.168) D12(7.317,-10.137) D14(6.326,-10.137) D16(5.336,-10.137) D18(4.388,-10.137) D20(3.386,-10.137) D22(2.439,-10.137) D24(1.448,-10.137) D26(0.463,-9.995) D28(-0.463,-9.995) D30(-1.448,-10.137) D32(-2.439,-10.137) D34(-3.386,-10.137) D36(-4.388,-10.137) D38(-5.336,-10.137) D40(-6.326,-10.137) D42(-7.317,-10.137) D44(-8.307,-10.168) D48(-10.113,-10.238) D50(-11.163,-10.163) E3(11.643,-9.58) E8(9.32,-9.747) E19(3.887,-9.819) E35(-3.887,-9.819) E46(-9.32,-9.747) E51(-11.643,-9.58) F5(10.565,-9.302) F7(9.712,-9.302) F10(8.307,-9.457) F12(7.317,-9.463) F14(6.326,-9.463) F16(5.336,-9.463) F18(4.362,-9.463) F19(3.887,-9.108) F20(3.412,-9.463) F22(2.439,-9.463) F24(1.448,-9.463) F26(0.525,-9.404) F27(0,-9.108) F28(-0.525,-9.404) F30(-1.448,-9.463) F32(-2.439,-9.463) F34(-3.412,-9.463) F35(-3.887,-9.108) F36(-4.362,-9.463) F38(-5.336,-9.463) F40(-6.326,-9.463) F42(-7.317,-9.463) F44(-8.307,-9.457) F47(-9.712,-9.302) F49(-10.565,-9.302) G10(8.307,-8.764) G12(7.317,-8.752) G14(6.326,-8.752) G16(5.336,-8.752) G18(4.362,-8.752) G20(3.412,-8.752) G22(2.439,-8.752) G24(1.448,-8.752) G26(0.475,-8.752) G28(-0.475,-8.752) G30(-1.448,-8.752) G32(-2.439,-8.752) G34(-3.412,-8.752) G36(-4.362,-8.752) G38(-5.336,-8.752) G40(-6.326,-8.752) G42(-7.317,-8.752) G44(-8.307,-8.764) H4(11.258,-8.307) H5(10.547,-8.307) H7(9.835,-8.307) H8(9.124,-8.307) H10(8.307,-8.17) H19(3.887,-8.396) H27(0,-8.396) H35(-3.887,-8.396) H44(-8.307,-8.17) H46(-9.124,-8.307) H47(-9.835,-8.307) H49(-10.547,-8.307) H50(-11.258,-8.307) J12(7.317,-8.041) J14(6.326,-8.041) J16(5.336,-8.041) J18(4.362,-8.041) J19(3.887,-7.685) J20(3.412,-8.041) J22(2.439,-8.041) J24(1.448,-8.041) J26(0.475,-8.041) J27(0,-7.685) J28(-0.475,-8.041) J30(-1.448,-8.041) J32(-2.439,-8.041) J34(-3.412,-8.041) J35(-3.887,-7.685) J36(-4.362,-8.041) J38(-5.336,-8.041) J40(-6.326,-8.041) J42(-7.317,-8.041) K4(11.137,-7.317) K6(10.463,-7.317) K7(9.752,-7.317) K9(9.041,-7.317) K10(8.33,-7.317) K12(7.317,-7.34) K14(6.326,-7.33) K16(5.336,-7.33) K18(4.362,-7.33) K20(3.412,-7.33) K22(2.439,-7.33) K24(1.448,-7.33) K26(0.475,-7.33) K28(-0.475,-7.33) K30(-1.448,-7.33) K32(-2.439,-7.33) K34(-3.412,-7.33) K36(-4.362,-7.33) K38(-5.336,-7.33) K40(-6.326,-7.33) K42(-7.317,-7.34) K44(-8.33,-7.317) K45(-9.041,-7.317) K47(-9.752,-7.317) K48(-10.463,-7.317) K50(-11.137,-7.317) L13(6.751,-6.915) L19(3.887,-6.974) L27(0,-6.974) L35(-3.887,-6.974) L41(-6.751,-6.915) M4(11.137,-6.326) M6(10.463,-6.326) M7(9.752,-6.326) M9(9.041,-6.326) M10(8.33,-6.326) M12(7.618,-6.326) M13(6.907,-6.326) M14(6.326,-6.446) M16(5.336,-6.618) M18(4.362,-6.618) M19(3.887,-6.263) M20(3.412,-6.618) M22(2.439,-6.618) M24(1.448,-6.618) M26(0.475,-6.618) M27(0,-6.263) M28(-0.475,-6.618) M30(-1.448,-6.618) M32(-2.439,-6.618) M34(-3.412,-6.618) M35(-3.887,-6.263) M36(-4.362,-6.618) M38(-5.336,-6.618) M40(-6.326,-6.446) M41(-6.907,-6.326) M42(-7.618,-6.326) M44(-8.33,-6.326) M45(-9.041,-6.326) M47(-9.752,-6.326) M48(-10.463,-6.326) M50(-11.137,-6.326) N16(5.336,-5.907) N18(4.362,-5.907) N20(3.412,-5.907) N22(2.439,-5.907) N24(1.448,-5.907) N26(0.475,-5.907) N28(-0.475,-5.907) N30(-1.448,-5.907) N32(-2.439,-5.907) N34(-3.412,-5.907) N36(-4.362,-5.907) N38(-5.336,-5.907) P4(11.137,-5.336) P6(10.463,-5.336) P7(9.752,-5.336) P9(9.041,-5.336) P10(8.33,-5.336) P12(7.618,-5.336) P13(6.907,-5.336) P14(6.305,-5.336) P16(5.336,-5.196) P18(4.362,-5.196) P19(3.887,-5.552) P20(3.412,-5.196) P22(2.439,-5.196) P24(1.448,-5.196) P26(0.475,-5.196) P27(0,-5.552) P28(-0.475,-5.196) P30(-1.448,-5.196) P32(-2.439,-5.196) P34(-3.412,-5.196) P35(-3.887,-5.552) P36(-4.362,-5.196) P38(-5.336,-5.196) P40(-6.305,-5.336) P41(-6.907,-5.336) P42(-7.618,-5.336) P44(-8.33,-5.336) P45(-9.041,-5.336) P47(-9.752,-5.336) P48(-10.463,-5.336) P50(-11.137,-5.336) T4(11.137,-4.388) T6(10.463,-4.362) T7(9.752,-4.362) T9(9.041,-4.362) T10(8.33,-4.362) T12(7.618,-4.362) T13(6.907,-4.362) T14(6.196,-4.362) T40(-6.196,-4.362) T41(-6.907,-4.362) T42(-7.618,-4.362) T44(-8.33,-4.362) T45(-9.041,-4.362) T47(-9.752,-4.362) T48(-10.463,-4.362) T50(-11.137,-4.388) U5(10.819,-3.887) U6(10.108,-3.887) U8(9.396,-3.887) U9(8.685,-3.887) U11(7.974,-3.887) U12(7.263,-3.887) U14(6.552,-3.887) U40(-6.552,-3.887) U42(-7.263,-3.887) U43(-7.974,-3.887) U45(-8.685,-3.887) U46(-9.396,-3.887) U48(-10.108,-3.887) U49(-10.819,-3.887) V4(11.137,-3.386) V6(10.463,-3.412) V7(9.752,-3.412) V9(9.041,-3.412) V10(8.33,-3.412) V12(7.618,-3.412) V13(6.907,-3.412) V14(6.196,-3.412) V40(-6.196,-3.412) V41(-6.907,-3.412) V42(-7.618,-3.412) V44(-8.33,-3.412) V45(-9.041,-3.412) V47(-9.752,-3.412) V48(-10.463,-3.412) V50(-11.137,-3.386) Y4(11.137,-2.439) Y6(10.463,-2.439) Y7(9.752,-2.439) Y9(9.041,-2.439) Y10(8.33,-2.439) Y12(7.618,-2.439) Y13(6.907,-2.439) Y14(6.196,-2.439) Y40(-6.196,-2.439) Y41(-6.907,-2.439) Y42(-7.618,-2.439) Y44(-8.33,-2.439) Y45(-9.041,-2.439) Y47(-9.752,-2.439) Y48(-10.463,-2.439) Y50(-11.137,-2.439)
CS_730X430X190_2
  rect 2.388x2.794 smd: 1(-3.2,0) 2(3.2,0)
CS_730X430X210_2
  rect 2.388x2.794 smd: 1(-3.2,0) 2(3.2,0)
CS_730X430X210_2_615
  rect 2.057x2.896 smd: 1(-3.075,0) 2(3.075,0)
CSC_100X050X030_2
  custom 0.112x0.112 smd: 1(-0.427,0) 2(0.427,0)
CSC_100X050X040_2
  custom 0.112x0.112 smd: 1(-0.427,0) 2(0.424,0)
CSC_100X050X055_2
  custom 0.112x0.112 smd: 1(-0.427,0) 2(0.424,0)
CSC_160X080X080_2
  rect 0.813x0.813 smd: 1(-0.6,0) 2(0.6,0)
CSC_160X080X090_2
  rect 0.813x0.813 smd: 1(-0.6,0) 2(0.6,0)
CSC_160X080X095_2
  rect 0.813x0.813 smd: 1(-0.6,0) 2(0.6,0)
CSC_200X125X130_2
  rect 0.813x1.295 smd: 1(-0.9,0) 2(0.9,0)
CSC_200X125X140_2
  rect 0.813x1.295 smd: 1(-0.9,0) 2(0.9,0)
CSTJB2_362X305X190_2
  rect 1.524x2.54 smd: 1(-1.372,0) 2(1.372,0)
DB10ST-6019B1214301-001
  round 0.254 smd: A1(-3.25,3.25) A2(-2.75,3.25) A3(-2.25,3.25) A4(-1.75,3.25) A5(-1.25,3.25) A6(-0.75,3.25) A7(-0.25,3.25) A8(0.25,3.25) A9(0.75,3.25) A10(1.25,3.25) A11(1.75,3.25) A12(2.25,3.25) A13(2.75,3.25) A14(3.25,3.25) B1(-3.25,2.75) B2(-2.75,2.75) B3(-2.25,2.75) B4(-1.75,2.75) B5(-1.25,2.75) B6(-0.75,2.75) B7(-0.25,2.75) B8(0.25,2.75) B9(0.75,2.75) B10(1.25,2.75) B11(1.75,2.75) B12(2.25,2.75) B13(2.75,2.75) B14(3.25,2.75) C1(-3.25,2.25) C2(-2.75,2.25) C3(-2.25,2.25) C4(-1.75,2.25) C5(-1.25,2.25) C6(-0.75,2.25) C7(-0.25,2.25) C8(0.25,2.25) C9(0.75,2.25) C10(1.25,2.25) C11(1.75,2.25) C12(2.25,2.25) C13(2.75,2.25) C14(3.25,2.25) D1(-3.25,1.75) D2(-2.75,1.75) D3(-2.25,1.75) D4(-1.75,1.75) D12(2.25,1.75) D13(2.75,1.75) D14(3.25,1.75) E1(-3.25,1.25) E2(-2.75,1.25) E3(-2.25,1.25) E5(-1.25,1.25) E6(-0.75,1.25) E7(-0.25,1.25) E8(0.25,1.25) E9(0.75,1.25) E10(1.25,1.25) E12(2.25,1.25) E13(2.75,1.25) E14(3.25,1.25) F1(-3.25,0.75) F2(-2.75,0.75) F3(-2.25,0.75) F5(-1.25,0.75) F10(1.25,0.75) F12(2.25,0.75) F13(2.75,0.75) F14(3.25,0.75) G1(-3.25,0.25) G2(-2.75,0.25) G3(-2.25,0.25) G5(-1.25,0.25) G10(1.25,0.25) G12(2.25,0.25) G13(2.75,0.25) G14(3.25,0.25) H1(-3.25,-0.25) H2(-2.75,-0.25) H3(-2.25,-0.25) H5(-1.25,-0.25) H10(1.25,-0.25) H12(2.25,-0.25) H13(2.75,-0.25) H14(3.25,-0.25) J1(-3.25,-0.75) J2(-2.75,-0.75) J3(-2.25,-0.75) J5(-1.25,-0.75) J10(1.25,-0.75) J12(2.25,-0.75) J13(2.75,-0.75) J14(3.25,-0.75) K1(-3.25,-1.25) K2(-2.75,-1.25) K3(-2.25,-1.25) K5(-1.25,-1.25) K6(-0.75,-1.25) K7(-0.25,-1.25) K8(0.25,-1.25) K9(0.75,-1.25) K10(1.25,-1.25) K12(2.25,-1.25) K13(2.75,-1.25) K14(3.25,-1.25) L1(-3.25,-1.75) L2(-2.75,-1.75) L3(-2.25,-1.75) L12(2.25,-1.75) L13(2.75,-1.75) L14(3.25,-1.75) M1(-3.25,-2.25) M2(-2.75,-2.25) M3(-2.25,-2.25) M4(-1.75,-2.25) M5(-1.25,-2.25) M6(-0.75,-2.25) M7(-0.25,-2.25) M8(0.25,-2.25) M9(0.75,-2.25) M10(1.25,-2.25) M11(1.75,-2.25) M12(2.25,-2.25) M13(2.75,-2.25) M14(3.25,-2.25) N1(-3.25,-2.75) N2(-2.75,-2.75) N3(-2.25,-2.75) N4(-1.75,-2.75) N5(-1.25,-2.75) N6(-0.75,-2.75) N7(-0.25,-2.75) N8(0.25,-2.75) N9(0.75,-2.75) N10(1.25,-2.75) N11(1.75,-2.75) N12(2.25,-2.75) N13(2.75,-2.75) N14(3.25,-2.75) P1(-3.25,-3.25) P2(-2.75,-3.25) P3(-2.25,-3.25) P4(-1.75,-3.25) P5(-1.25,-3.25) P6(-0.75,-3.25) P7(-0.25,-3.25) P8(0.25,-3.25) P9(0.75,-3.25) P10(1.25,-3.25) P11(1.75,-3.25) P12(2.25,-3.25) P13(2.75,-3.25) P14(3.25,-3.25)
DS_100X050X060_2_S2
  custom 0.112x0.112 smd: 1(-0.427,0) 2(0.424,0)
DS_160X080X090_2
  rect 0.813x0.813 smd: 1(-0.6,0) 2(0.6,0)
DS_250X100X065_10_050
  rect 0.356x0.762 smd: 1(-1.001,-0.437) 2(-0.5,-0.437) 4(0.5,-0.437) 5(1.001,-0.437) 6(1.001,0.437) 7(0.5,0.437) 9(-0.5,0.437) 10(-1.001,0.437)
  rect 0.406x0.686 smd: 3(0,-0.437)
  rect 0.406x0.889 smd: 8(0,0.338)
DSOT23_290X130X150_3_095
  rect 0.508x1.219 smd: 1(-0.95,-1.085) 2(0.95,-1.085) 3(0,1.085)
DSSOD523_120X080X070_2_150
  rect 0.61x0.787 smd: 1(-0.749,0) 2(0.749,0)
DSSOT23_290X130X110_3_095-2
  rect 0.508x1.219 smd: 1(0.95,-1.085) 2(-0.95,-1.085) 3(0,1.085)
DSSOT23_290X160X145_6_095
  rect 0.61x1.092 smd: 1(-0.95,-1.25) 2(0,-1.25) 3(0.95,-1.25) 4(0.95,1.25) 5(0,1.25) 6(-0.95,1.25)
DSSOT23_292X130X109_3_095
  rect 0.762x0.762 smd: 1(-0.95,-1.146) 2(0.95,-1.146) 3(0,1.146)
EMIS_BLM11
  rect 0.813x0.813 smd: 1(-0.6,0) 2(0.6,0)
FIX_MASK
  round 1.016 smd: 1(0,0)
FPC_ACES_4_100_R_150
  rect 0.61x1.295 smd: 1(-1.501,3.251) 2(-0.5,3.251) 3(0.5,3.251) 4(1.501,3.251)
  rect 0.991x2.007 smd: G1(-4.1,0) G2(4.1,0)
FPC_ACES_8_100_R_200_4
  rect 0.508x1.295 smd: 1(-3.5,2.799) 2(-2.499,2.799) 3(-1.499,2.799) 4(-0.5,2.799) 5(0.503,2.799) 6(1.501,2.799) 7(2.499,2.799) 8(3.503,2.799)
  rect 1.803x1.397 smd: G1(-5.649,-0.003) G2(5.652,-0.003)
FPC_ACES_10_100_R_200_3
  rect 0.508x1.295 smd: 1(-4.501,2.799) 2(-3.503,2.799) 3(-2.499,2.799) 4(-1.501,2.799) 5(-0.5,2.799) 6(0.5,2.799) 7(1.499,2.799) 8(2.499,2.799) 9(3.5,2.799) 10(4.501,2.799)
  rect 1.803x1.397 smd: G1(-6.652,-0.003) G2(6.65,-0.003)
FPC_ACES_24_100_R_200_4
  rect 0.508x1.295 smd: 1(-11.501,2.799) 2(-10.5,2.799) 3(-9.5,2.799) 4(-8.501,2.799) 5(-7.501,2.799) 6(-6.5,2.799) 7(-5.502,2.799) 8(-4.501,2.799) 9(-3.5,2.799) 10(-2.499,2.799) 11(-1.501,2.799) 12(-0.5,2.799) 13(0.5,2.799) 14(1.501,2.799) 15(2.499,2.799) 16(3.5,2.799) 17(4.501,2.799) 18(5.502,2.799) 19(6.5,2.799) 20(7.501,2.799) 21(8.501,2.799) 22(9.5,2.799) 23(10.5,2.799) 24(11.501,2.799)
  rect 1.803x1.397 smd: G1(-13.65,-0.003) G2(13.65,-0.003)
FUSE_160X080X031_2
  rect 0.762x1.092 smd: 1(-0.889,0) 2(0.889,0)
HDMI_CONFT_19_RS_060_218
  round 0.762 hole 0.508: 1(-4.501,6.081) 2(-4,7.282) 3(-3.5,6.081) 4(-3,7.282) 5(-2.499,6.081) 6(-1.999,7.282) 7(-1.501,6.081) 8(-1.001,7.282) 9(-0.5,6.081) 10(0,7.282) 11(0.5,6.081) 12(1.001,7.282) 13(1.501,6.081) 14(2.002,7.282) 15(2.499,6.081) 16(3.002,7.282) 17(3.5,6.081) 18(4,7.282) 19(4.501,6.081)
  oval 1.702x2.743 hole 1.092x2.159: G1(-9.251,0.003) G4(9.251,0.003)
  oval 1.397x2.946 hole 0.787x2.362: G2(-7.249,6.85) G3(7.252,6.85)
HL10BM-6012B0131110-001
  round 1.75 hole 1.75 unplated: (-8.2,0) (8.2,0)
  rect 1.092x1.905 smd: 1(8,4.95) 2(6,4.95) 3(4,4.95) 4(2,4.95) 5(0,4.95) 6(-2,4.95) 7(-4,4.95) 8(-6,4.95) 9(-8,4.95)
IC-DDR3_SAMSG_1330X1000X110_1
  round 0.381 smd: A1(-3.2,6) A2(-2.4,6) A3(-1.6,6) A7(1.6,6) A8(2.4,6) A9(3.2,6) B1(-3.2,5.2) B2(-2.4,5.2) B3(-1.6,5.2) B7(1.6,5.2) B8(2.4,5.2) B9(3.2,5.2) C1(-3.2,4.4) C2(-2.4,4.4) C3(-1.6,4.4) C7(1.6,4.4) C8(2.4,4.4) C9(3.2,4.4) D1(-3.2,3.6) D2(-2.4,3.6) D3(-1.6,3.6) D7(1.6,3.6) D8(2.4,3.6) D9(3.2,3.6) E1(-3.2,2.8) E2(-2.4,2.8) E3(-1.6,2.8) E7(1.6,2.8) E8(2.4,2.8) E9(3.2,2.8) F1(-3.2,2) F2(-2.4,2) F3(-1.6,2) F7(1.6,2) F8(2.4,2) F9(3.2,2) G1(-3.2,1.2) G2(-2.4,1.2) G3(-1.6,1.2) G7(1.6,1.2) G8(2.4,1.2) G9(3.2,1.2) H1(-3.2,0.4) H2(-2.4,0.4) H3(-1.6,0.4) H7(1.6,0.4) H8(2.4,0.4) H9(3.2,0.4) J1(-3.2,-0.4) J2(-2.4,-0.4) J3(-1.6,-0.4) J7(1.6,-0.4) J8(2.4,-0.4) J9(3.2,-0.4) K1(-3.2,-1.2) K2(-2.4,-1.2) K3(-1.6,-1.2) K7(1.6,-1.2) K8(2.4,-1.2) K9(3.2,-1.2) L1(-3.2,-2) L2(-2.4,-2) L3(-1.6,-2) L7(1.6,-2) L8(2.4,-2) L9(3.2,-2) M1(-3.2,-2.8) M2(-2.4,-2.8) M3(-1.6,-2.8) M7(1.6,-2.8) M8(2.4,-2.8) M9(3.2,-2.8) N1(-3.2,-3.6) N2(-2.4,-3.6) N3(-1.6,-3.6) N7(1.6,-3.6) N8(2.4,-3.6) N9(3.2,-3.6) P1(-3.2,-4.4) P2(-2.4,-4.4) P3(-1.6,-4.4) P7(1.6,-4.4) P8(2.4,-4.4) P9(3.2,-4.4) R1(-3.2,-5.2) R2(-2.4,-5.2) R3(-1.6,-5.2) R7(1.6,-5.2) R8(2.4,-5.2) R9(3.2,-5.2) T1(-3.2,-6) T2(-2.4,-6) T3(-1.6,-6) T7(1.6,-6) T8(2.4,-6) T9(3.2,-6)
IC-HALL_MST_3_SMD_V_080
  rect 0.787x0.991 smd: 1(-0.95,-1.3) 2(0.95,-1.3) 3(0,1.3)
LED_EVERLI_V_D_160X150X060
  rect 1.092x0.61 smd: 1(0.95,0.45) 2(0.95,-0.452) 3(-0.95,-0.452) 4(-0.95,0.45)
LQFP_1400X1400X160_128_040
  rect 0.297x1.473 smd: 1(-6.2,-7.8) 2(-5.799,-7.8) 3(-5.4,-7.8) 4(-5.001,-7.8) 5(-4.6,-7.8) 6(-4.201,-7.8) 7(-3.8,-7.8) 8(-3.401,-7.8) 9(-3,-7.8) 10(-2.601,-7.8) 11(-2.2,-7.8) 12(-1.801,-7.8) 13(-1.4,-7.8) 14(-1.001,-7.8) 15(-0.599,-7.8) 16(-0.201,-7.8) 17(0.201,-7.8) 18(0.599,-7.8) 19(1.001,-7.8) 20(1.4,-7.8) 21(1.801,-7.8) 22(2.2,-7.8) 23(2.601,-7.8) 24(3,-7.8) 25(3.401,-7.8) 26(3.8,-7.8) 27(4.201,-7.8) 28(4.6,-7.8) 29(5.001,-7.8) 30(5.4,-7.8) 31(5.799,-7.8) 32(6.2,-7.8) 65(6.2,7.8) 66(5.799,7.8) 67(5.4,7.8) 68(5.001,7.8) 69(4.6,7.8) 70(4.201,7.8) 71(3.8,7.8) 72(3.401,7.8) 73(3,7.8) 74(2.601,7.8) 75(2.2,7.8) 76(1.801,7.8) 77(1.4,7.8) 78(1.001,7.8) 79(0.599,7.8) 80(0.201,7.8) 81(-0.201,7.8) 82(-0.599,7.8) 83(-1.001,7.8) 84(-1.4,7.8) 85(-1.801,7.8) 86(-2.2,7.8) 87(-2.601,7.8) 88(-3,7.8) 89(-3.401,7.8) 90(-3.8,7.8) 91(-4.201,7.8) 92(-4.6,7.8) 93(-5.001,7.8) 94(-5.4,7.8) 95(-5.799,7.8) 96(-6.2,7.8)
  rect 1.473x0.297 smd: 33(7.8,-6.2) 34(7.8,-5.799) 35(7.8,-5.4) 36(7.8,-5.001) 37(7.8,-4.6) 38(7.8,-4.201) 39(7.8,-3.8) 40(7.8,-3.401) 41(7.8,-3) 42(7.8,-2.601) 43(7.8,-2.2) 44(7.8,-1.801) 45(7.8,-1.4) 46(7.8,-1.001) 47(7.8,-0.599) 48(7.8,-0.201) 49(7.8,0.201) 50(7.8,0.599) 51(7.8,1.001) 52(7.8,1.4) 53(7.8,1.801) 54(7.8,2.2) 55(7.8,2.601) 56(7.8,3) 57(7.8,3.401) 58(7.8,3.8) 59(7.8,4.201) 60(7.8,4.6) 61(7.8,5.001) 62(7.8,5.4) 63(7.8,5.799) 64(7.8,6.2) 97(-7.8,6.2) 98(-7.8,5.799) 99(-7.8,5.4) 100(-7.8,5.001) 101(-7.8,4.6) 102(-7.8,4.201) 103(-7.8,3.8) 104(-7.8,3.401) 105(-7.8,3) 106(-7.8,2.601) 107(-7.8,2.2) 108(-7.8,1.801) 109(-7.8,1.4) 110(-7.8,1.001) 111(-7.8,0.599) 112(-7.8,0.201) 113(-7.8,-0.201) 114(-7.8,-0.599) 115(-7.8,-1.001) 116(-7.8,-1.4) 117(-7.8,-1.801) 118(-7.8,-2.2) 119(-7.8,-2.601) 120(-7.8,-3) 121(-7.8,-3.401) 122(-7.8,-3.8) 123(-7.8,-4.201) 124(-7.8,-4.6) 125(-7.8,-5.001) 126(-7.8,-5.4) 127(-7.8,-5.799) 128(-7.8,-6.2)
LS_200X120X140_4_080
  rect 0.889x0.406 smd: 1(-0.851,0.401) 2(-0.851,-0.401) 3(0.851,-0.401) 4(0.851,0.401)
LS_320X160X130_2
  rect 1.321x1.6 smd: 1(-1.35,0) 2(1.35,0)
LS_500X500X200_2_340_P2
  rect 1.6x3.988 smd: 1(-1.702,0) 2(1.702,0)
LS_660X660X180_2_540
  rect 2.362x3.505 smd: 1(-3.025,0) 2(3.025,0)
LS_660X660X180_2_570
  rect 2.362x3.505 smd: 1(-3.025,0) 2(3.025,0)
LS_660X660X180_2_605
  rect 2.362x3.505 smd: 1(-3.025,0) 2(3.025,0)
LS_660X660X180_4
  custom 0.591x0.591 smd: 1(-3.025,1.008) 2(3.025,1.008)
  rect 2.057x0.254 smd: 3(-2.873,0) 4(2.873,0)
MOSFET_300X300X112_8_065
  rect 0.432x0.869 smd: 1(-0.975,-1.4) 2(-0.325,-1.4) 3(0.325,-1.4) 4(0.975,-1.4)
  custom 0.636x0.636 smd: 5(0.975,1.527)
  rect 0.432x0.744 smd: 6(0.325,1.527) 7(-0.325,1.527) 8(-0.975,1.527)
MPCI_LOTES_75_050_RV_198
  round 1.6 hole 1.6 unplated: (-10,0)
  round 1.092 hole 1.092 unplated: (10.003,0)
  rect 0.356x1.626 smd: 1(9.251,-5.28) 2(9.002,2.281) 3(8.75,-5.28) 4(8.501,2.281) 5(8.252,-5.28) 6(8.001,2.281) 7(7.752,-5.28) 8(7.501,2.281) 9(7.252,-5.28) 10(7,2.281) 11(6.749,-5.28) 12(6.502,2.281) 13(6.251,-5.28) 14(6.002,2.281) 15(5.751,-5.28) 16(5.502,2.281) 17(5.25,-5.28) 18(5.001,2.281) 19(4.75,-5.28) 20(4.501,2.281) 21(4.252,-5.28) 22(4,2.281) 23(3.752,-5.28) 32(1.501,2.281) 33(1.252,-5.28) 34(1.001,2.281) 35(0.752,-5.28) 36(0.5,2.281) 37(0.249,-5.28) 38(0.003,2.281) 39(-0.249,-5.28) 40(-0.5,2.281) 41(-0.749,-5.28) 42(-1.001,2.281) 43(-1.25,-5.28) 44(-1.501,2.281) 45(-1.75,-5.28) 46(-1.999,2.281) 47(-2.25,-5.28) 48(-2.499,2.281) 49(-2.751,-5.28) 50(-3,2.281) 51(-3.251,-5.28) 52(-3.5,2.281) 53(-3.749,-5.28) 54(-4,2.281) 55(-4.249,-5.28) 56(-4.501,2.281) 57(-4.75,-5.28) 58(-4.999,2.281) 59(-5.25,-5.28) 60(-5.499,2.281) 61(-5.751,-5.28) 62(-5.999,2.281) 63(-6.248,-5.28) 64(-6.5,2.281) 65(-6.749,-5.28) 66(-7,2.281) 67(-7.249,-5.28) 68(-7.501,2.281) 69(-7.75,-5.28) 70(-8.001,2.281) 71(-8.25,-5.28) 72(-8.499,2.281) 73(-8.748,-5.28) 74(-8.999,2.281) 75(-9.251,-5.28)
  rect 1.194x2.743 smd: G1(10.35,-4.5) G2(-10.35,-4.5)
MQFN_600X600X100_48_040_T1
  rect 0.297x0.864 smd: 1(-2.2,-2.901) 2(-1.801,-2.901) 3(-1.4,-2.901) 4(-1.001,-2.901) 5(-0.599,-2.901) 6(-0.201,-2.901) 7(0.201,-2.901) 8(0.599,-2.901) 9(1.001,-2.901) 10(1.4,-2.901) 11(1.801,-2.901) 12(2.2,-2.901) 25(2.2,2.901) 26(1.801,2.901) 27(1.4,2.901) 28(1.001,2.901) 29(0.599,2.901) 30(0.201,2.901) 31(-0.201,2.901) 32(-0.599,2.901) 33(-1.001,2.901) 34(-1.4,2.901) 35(-1.801,2.901) 36(-2.2,2.901)
  rect 0.864x0.297 smd: 13(2.901,-2.2) 14(2.901,-1.801) 15(2.901,-1.4) 16(2.901,-1.001) 17(2.901,-0.599) 18(2.901,-0.201) 19(2.901,0.201) 20(2.901,0.599) 21(2.901,1.001) 22(2.901,1.4) 23(2.901,1.801) 24(2.901,2.2) 37(-2.901,2.2) 38(-2.901,1.801) 39(-2.901,1.4) 40(-2.901,1.001) 41(-2.901,0.599) 42(-2.901,0.201) 43(-2.901,-0.201) 44(-2.901,-0.599) 45(-2.901,-1.001) 46(-2.901,-1.4) 47(-2.901,-1.801) 48(-2.901,-2.2)
  rect 4.394x4.394 smd: 49(0,0)
MSOP_300X300X110_8_065_T2
  rect 0.457x1.499 smd: 1(-0.975,-2.5) 2(-0.325,-2.5) 3(0.325,-2.5) 4(0.975,-2.5) 5(0.975,2.5) 6(0.325,2.5) 7(-0.325,2.5) 8(-0.975,2.5)
  rect 1.524x1.27 smd: 9(0,0)
PASSWORD_0805
  rect 1.016x1.524 smd: 1(-1.003,0) 2(1.003,0)
POWERPAD1X1M
  custom 0.194x0.194 smd: 1(-0.437,0) 2(0.437,0)
POWERPAD2X2M_NP
  custom 0.252x0.252 smd: 1(0,0) 2(1.27,0)
POWERPAD_2_0610
  custom 0.252x0.252 smd: 1(0,0) 2(1.27,0)
QFN_200X150X060_10_050
  rect 0.356x0.66 smd: 1(-0.752,-0.638) 2(-0.249,-0.638) 3(0.249,-0.638) 4(0.752,-0.638) 6(0.752,0.638) 7(0.249,0.638) 8(-0.249,0.638) 9(-0.752,0.638)
  rect 0.711x0.356 smd: 5(0.859,0) 10(-0.859,0)
QFN_300X300X100_14_040_T1
  rect 1.092x0.203 smd: 1(-1.25,0.525) 2(-1.25,-0.175) 8(1.25,-0.525) 9(1.25,0.175)
  rect 0.297x0.787 smd: 3(-0.8,-1.45) 4(-0.4,-1.45) 5(0,-1.45) 6(0.4,-1.45) 7(0.8,-1.45) 10(0.8,1.45) 11(0.4,1.45) 12(0,1.45) 13(-0.4,1.45) 14(-0.8,1.45)
  rect 0.66x0.203 smd: 15(0,0.165) 16(0,-0.435)
QFN_300X300X100_14_040_T2
  rect 1.092x0.203 smd: 1(-1.25,0.525) 2(-1.25,-0.175) 8(1.25,-0.525) 9(1.25,0.175)
  rect 0.297x0.787 smd: 3(-0.8,-1.45) 4(-0.4,-1.45) 5(0,-1.45) 6(0.4,-1.45) 7(0.8,-1.45) 10(0.8,1.45) 11(0.4,1.45) 12(0,1.45) 13(-0.4,1.45) 14(-0.8,1.45)
  rect 0.66x0.203 smd: 15(0,0.17)
  rect 0.66x0.279 smd: 16(0,-0.481)
QFN_350X350X100_20_050_T1
  rect 0.356x0.787 smd: 1(-1.001,-1.699) 2(-0.5,-1.699) 3(0,-1.699) 4(0.5,-1.699) 5(1.001,-1.699) 11(1.001,1.699) 12(0.5,1.699) 13(0,1.699) 14(-0.5,1.699) 15(-1.001,1.699)
  rect 0.787x0.356 smd: 6(1.699,-1.001) 7(1.699,-0.5) 8(1.699,0) 9(1.699,0.5) 10(1.699,1.001) 16(-1.699,1.001) 17(-1.699,0.5) 18(-1.699,0) 19(-1.699,-0.5) 20(-1.699,-1.001)
  rect 2.007x2.007 smd: 21(0,0)
QFN_400X400X100_24_050_T8
  rect 0.356x0.914 smd: 1(-1.25,-1.976) 2(-0.752,-1.976) 3(-0.249,-1.976) 4(0.249,-1.976) 5(0.752,-1.976) 6(1.25,-1.976) 13(1.25,1.976) 14(0.752,1.976) 15(0.249,1.976) 16(-0.249,1.976) 17(-0.752,1.976) 18(-1.25,1.976)
  rect 0.914x0.356 smd: 7(1.976,-1.25) 8(1.976,-0.752) 9(1.976,-0.249) 10(1.976,0.249) 11(1.976,0.752) 12(1.976,1.25) 19(-1.976,1.25) 20(-1.976,0.752) 21(-1.976,0.249) 22(-1.976,-0.249) 23(-1.976,-0.752) 24(-1.976,-1.25)
  rect 2.261x2.261 smd: 25(0,0)
QFN_400X400X100_28_040_T6
  rect 0.297x0.686 smd: 1(-1.2,-1.84) 2(-0.8,-1.84) 3(-0.4,-1.84) 4(0,-1.84) 5(0.4,-1.84) 6(0.8,-1.84) 7(1.2,-1.84) 15(1.2,1.84) 16(0.8,1.84) 17(0.4,1.84) 18(0,1.84) 19(-0.4,1.84) 20(-0.8,1.84) 21(-1.2,1.84)
  rect 0.686x0.297 smd: 8(1.84,-1.2) 9(1.84,-0.8) 10(1.84,-0.4) 11(1.84,0) 12(1.84,0.4) 13(1.84,0.8) 14(1.84,1.2) 22(-1.84,1.2) 23(-1.84,0.8) 24(-1.84,0.4) 25(-1.84,0) 26(-1.84,-0.4) 27(-1.84,-0.8) 28(-1.84,-1.2)
  rect 2.718x2.718 smd: 29(0,0)
RSC_100X050X040_2
  custom 0.112x0.112 smd: 1(-0.427,0) 2(0.424,0)
RSC_100X050X040_2_15_SHORT
  rect 0.457x0.381 smd: (0,0)
  custom 0.112x0.112 smd: 1(-0.427,0) 2(0.424,0)
RSC_100X050X040_2_SHORT
  rect 0.508x0.127 smd: (0,0)
  custom 0.112x0.112 smd: 1(-0.427,0) 2(0.424,0)
RSC_100X050X055_2
  custom 0.112x0.112 smd: 1(-0.427,0) 2(0.424,0)
RSC_160X080X055_2
  rect 0.813x0.813 smd: 1(-0.6,0) 2(0.6,0)
RSC_160X080X080_2
  rect 0.813x0.813 smd: 1(-0.6,0) 2(0.6,0)
RSC_160X080X080_2_25_SHORT
  rect 0.584x0.635 smd: (0,0)
  rect 0.813x0.813 smd: 1(-0.6,0) 2(0.6,0)
RSC_160X080X080_2_SHORT
  rect 0.584x0.254 smd: (0,0)
  rect 0.813x0.813 smd: 1(-0.6,0) 2(0.6,0)
RSC_200X125X115_2
  rect 0.813x1.295 smd: 1(-0.9,0) 2(0.9,0)
RSC_320X160X080_4
  custom 0.349x0.349 smd: 1(-1.989,0.508) 2(1.989,0.508)
  rect 1.041x0.254 smd: 3(-1.232,0) 4(1.232,0)
RSC_320X160X160_4
  custom 0.349x0.349 smd: 1(-1.989,0.508) 2(1.989,0.508)
  rect 1.041x0.254 smd: 3(-1.232,0) 4(1.232,0)
SCREW260_550_1P
  round 5.512 hole 2.591: 1(0,0)
SCREW260_700_1P
  custom 1.455x1.455 hole 2.591: 1(0,0)
SCREW260_700_600_1P
  round 7.01 hole 2.591: 1(0,0)
SCREW260_800_700_1P
  round 8.001 hole 2.591: 1(0,0)
SCREW260_1000_600_1P
  round 5.994 hole 2.591: 1(0,0)
SCREW260_1000_800_1P
  round 8.001 hole 2.591: 1(0,0)
SCREW300_1000_700_1P
  round 7.01 hole 2.997: 1(0,0)
SD_TAIT_11_SMD_ST_285_2
  round 1.245 hole 1.245 unplated: (-11.5,8.85)
  round 1.75 hole 1.75 unplated: (9.5,8.85)
  rect 0.991x1.499 smd: 1(6.875,11.65) 2(4.375,11.65) 3(1.875,11.65) 4(-0.625,11.65) 5(-3.125,11.65) 6(-5.625,11.65) 7(-8.125,11.65) 8(-9.755,11.65) 9(9.375,11.65)
  rect 0.711x1.499 smd: 10(-11.055,11.65) 11(-12.255,11.65)
  rect 1.499x2.794 smd: G1(-13.65,9.85) G2(11.3,9.85)
  oval 1.194x3.912 hole 0.61x3.404: G3(-13.1,0) G4(13.1,0)
SOP_523X528X216_8_127
  rect 0.483x1.473 smd: 1(-1.905,-3.724) 2(-0.635,-3.724) 3(0.635,-3.724) 4(1.905,-3.724) 5(1.905,3.724) 6(0.635,3.724) 7(-0.635,3.724) 8(-1.905,3.724)
SOT23_290X160X145_3_095
  rect 0.61x0.94 smd: 1(-0.95,-1.225) 2(0.95,-1.225) 3(0,1.225)
SSOP_200X125X100_5_065
  rect 0.406x1.016 smd: 1(-0.65,-1.049) 2(0,-1.049) 3(0.65,-1.049) 4(0.65,1.049) 5(-0.65,1.049)
STD_R_FF40005_D30015_M20020_SN
  round 5.512 hole 3.099: 1(0,0)
SWCH-TACT_DIP_6_SMD_V_150
  rect 1.092x1.803 smd: 1(-1.852,3.101) 3(-1.852,-3.101) 4(1.849,3.101) 6(1.849,-3.101)
  rect 0.61x1.397 smd: 2(-2.499,0) 5(2.499,0)
TDFN_300X200X080_14_040_T1
  oval 0.305x0.559 smd: 1(-1.2,-0.89) 2(-0.8,-0.89) 3(-0.4,-0.89) 4(0,-0.89) 5(0.4,-0.89) 6(0.8,-0.89) 7(1.2,-0.89) 8(1.2,0.89) 9(0.8,0.89) 10(0.4,0.89) 11(0,0.89) 12(-0.4,0.89) 13(-0.8,0.89) 14(-1.2,0.89)
  rect 2.489x0.889 smd: 15(0,0)
TP24
  round 0.61 smd: 1(0,0)
TQFN_400X400X080_32_040_T1
  rect 0.297x0.686 smd: 1(-1.4,-2) 2(-1,-2) 3(-0.6,-2) 4(-0.2,-2) 5(0.2,-2) 6(0.6,-2) 7(1,-2) 8(1.4,-2) 17(1.4,2) 18(1,2) 19(0.6,2) 21(-0.2,2) 22(-0.6,2) 23(-1,2)
  rect 0.686x0.297 smd: 9(2,-1.4) 10(2,-1) 12(2,-0.2) 13(2,0.2) 14(2,0.6) 15(2,1) 16(2,1.4) 25(-2,1.4) 26(-2,1) 27(-2,0.6) 28(-2,0.2) 29(-2,-0.2) 30(-2,-0.6) 31(-2,-1) 32(-2,-1.4)
  custom 0.171x0.171 smd: 11(2,-0.6)
  custom 0.4x0.4 smd: 20(0.2,2)
  custom 0.374x0.374 smd: 24(-1.4,2)
  custom 0.263x0.263 smd: 33(-0.925,-0.9)
TSMI_3B
  rect 1.016x1.016 smd: 1(-0.953,-1.049) 2(0.953,-1.049) 3(0,1.049)
TSMOS_300X300X080_8_065_T4
  rect 0.508x0.457 smd: 1(-0.975,-1.38) 2(-0.325,-1.38) 3(0.325,-1.38) 4(0.975,-1.38) 5(0.975,1.38) 6(0.325,1.38) 7(-0.325,1.38) 8(-0.975,1.38)
  rect 2.54x1.041 smd: 9(0,0.433)
  rect 2.54x0.559 smd: 10(0,-0.672)
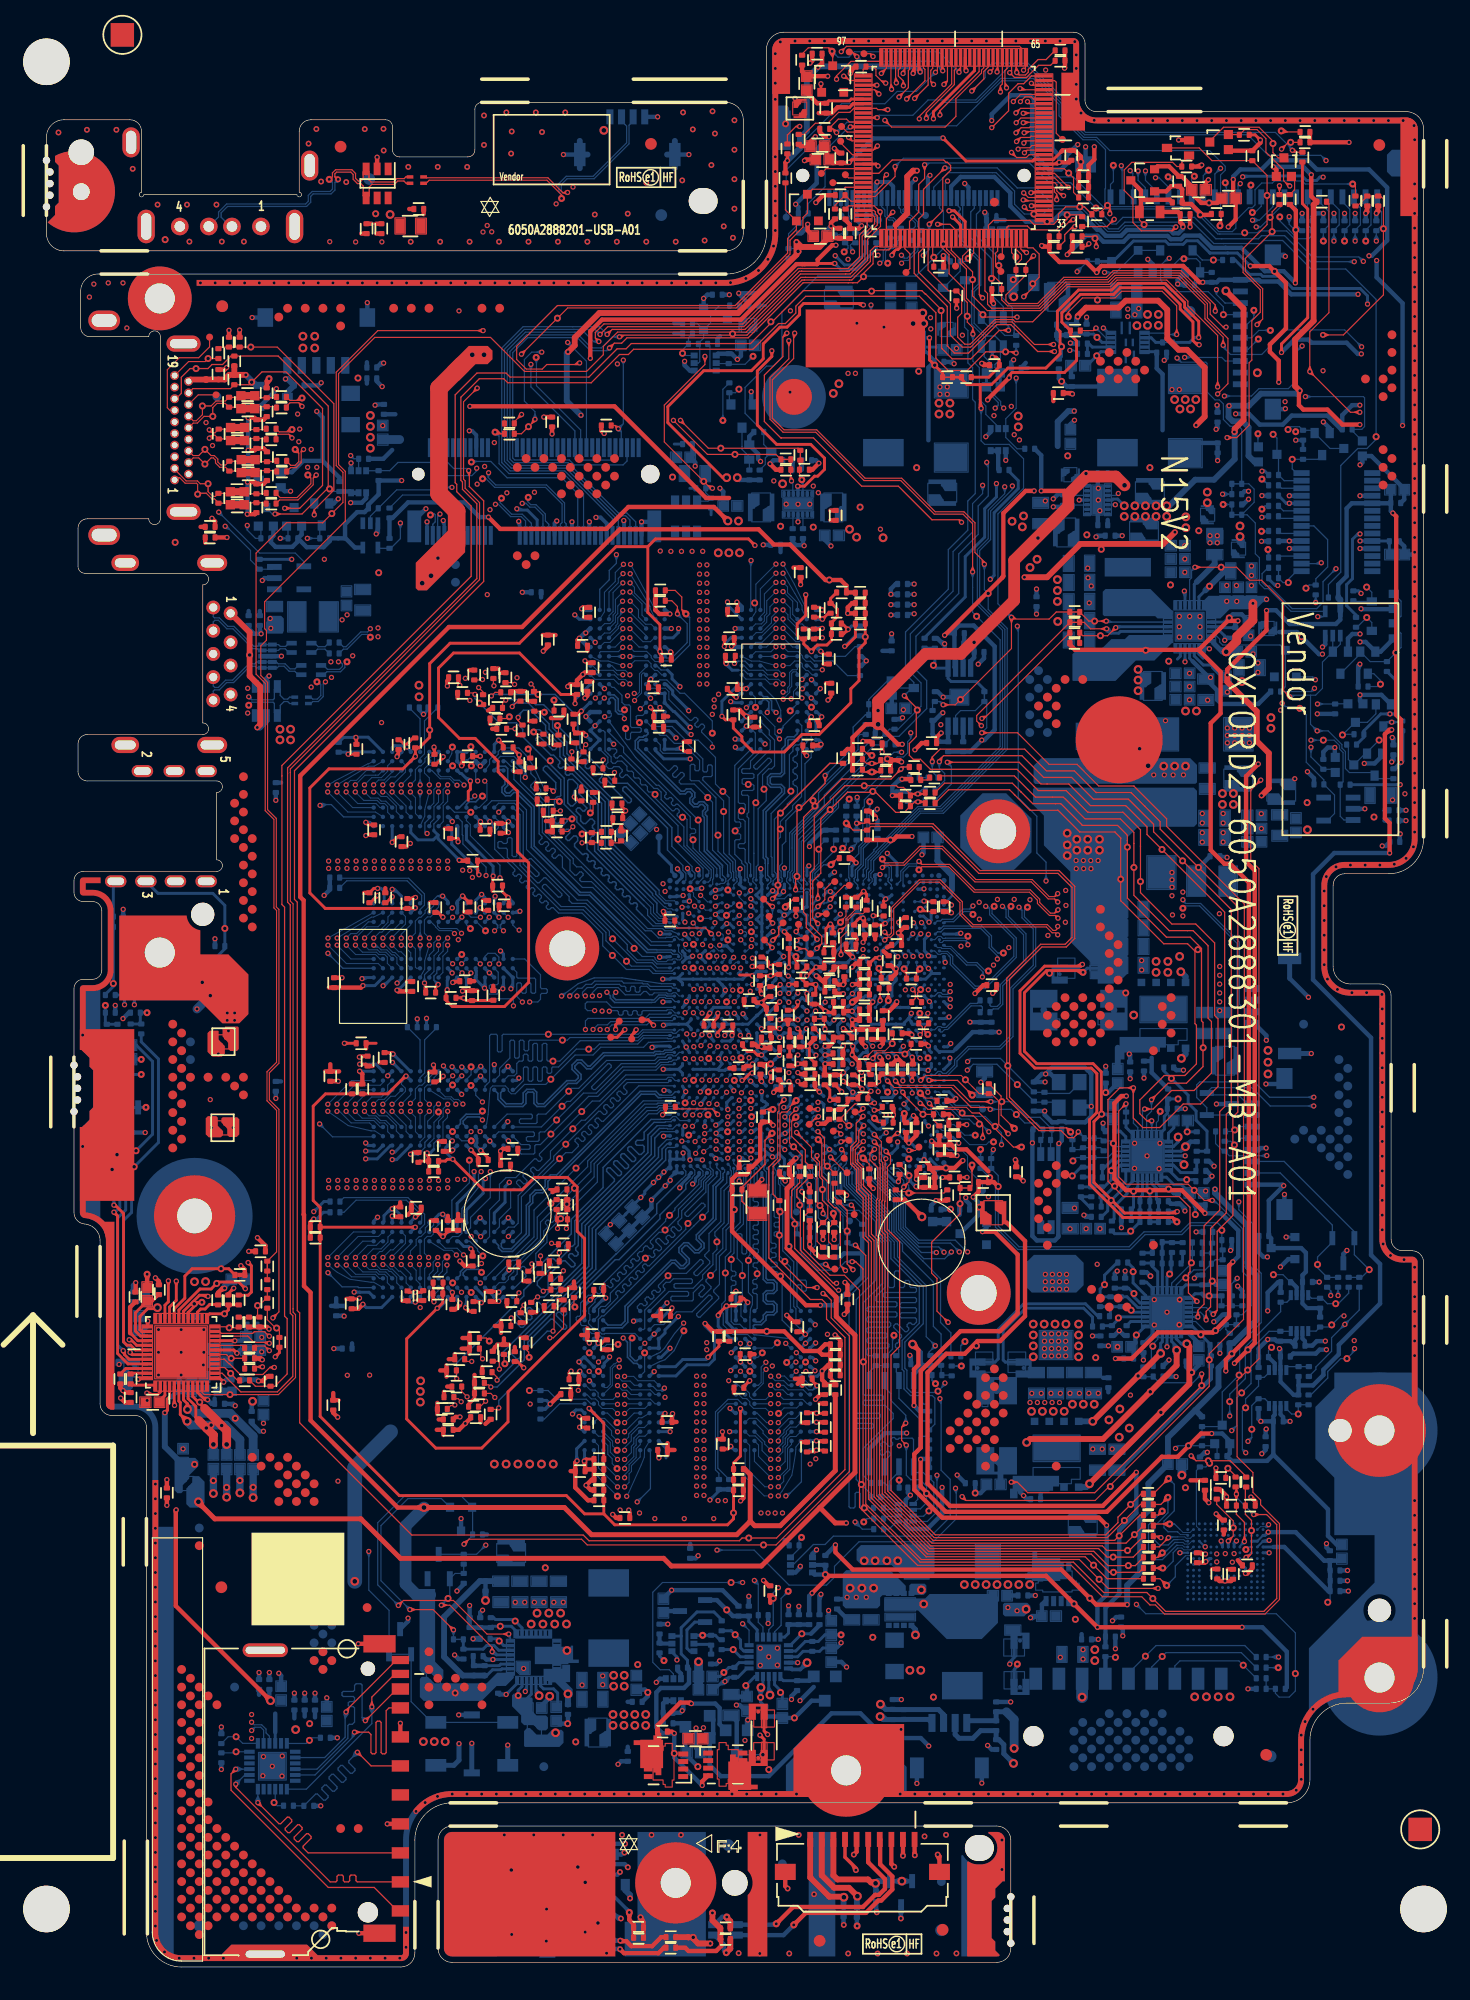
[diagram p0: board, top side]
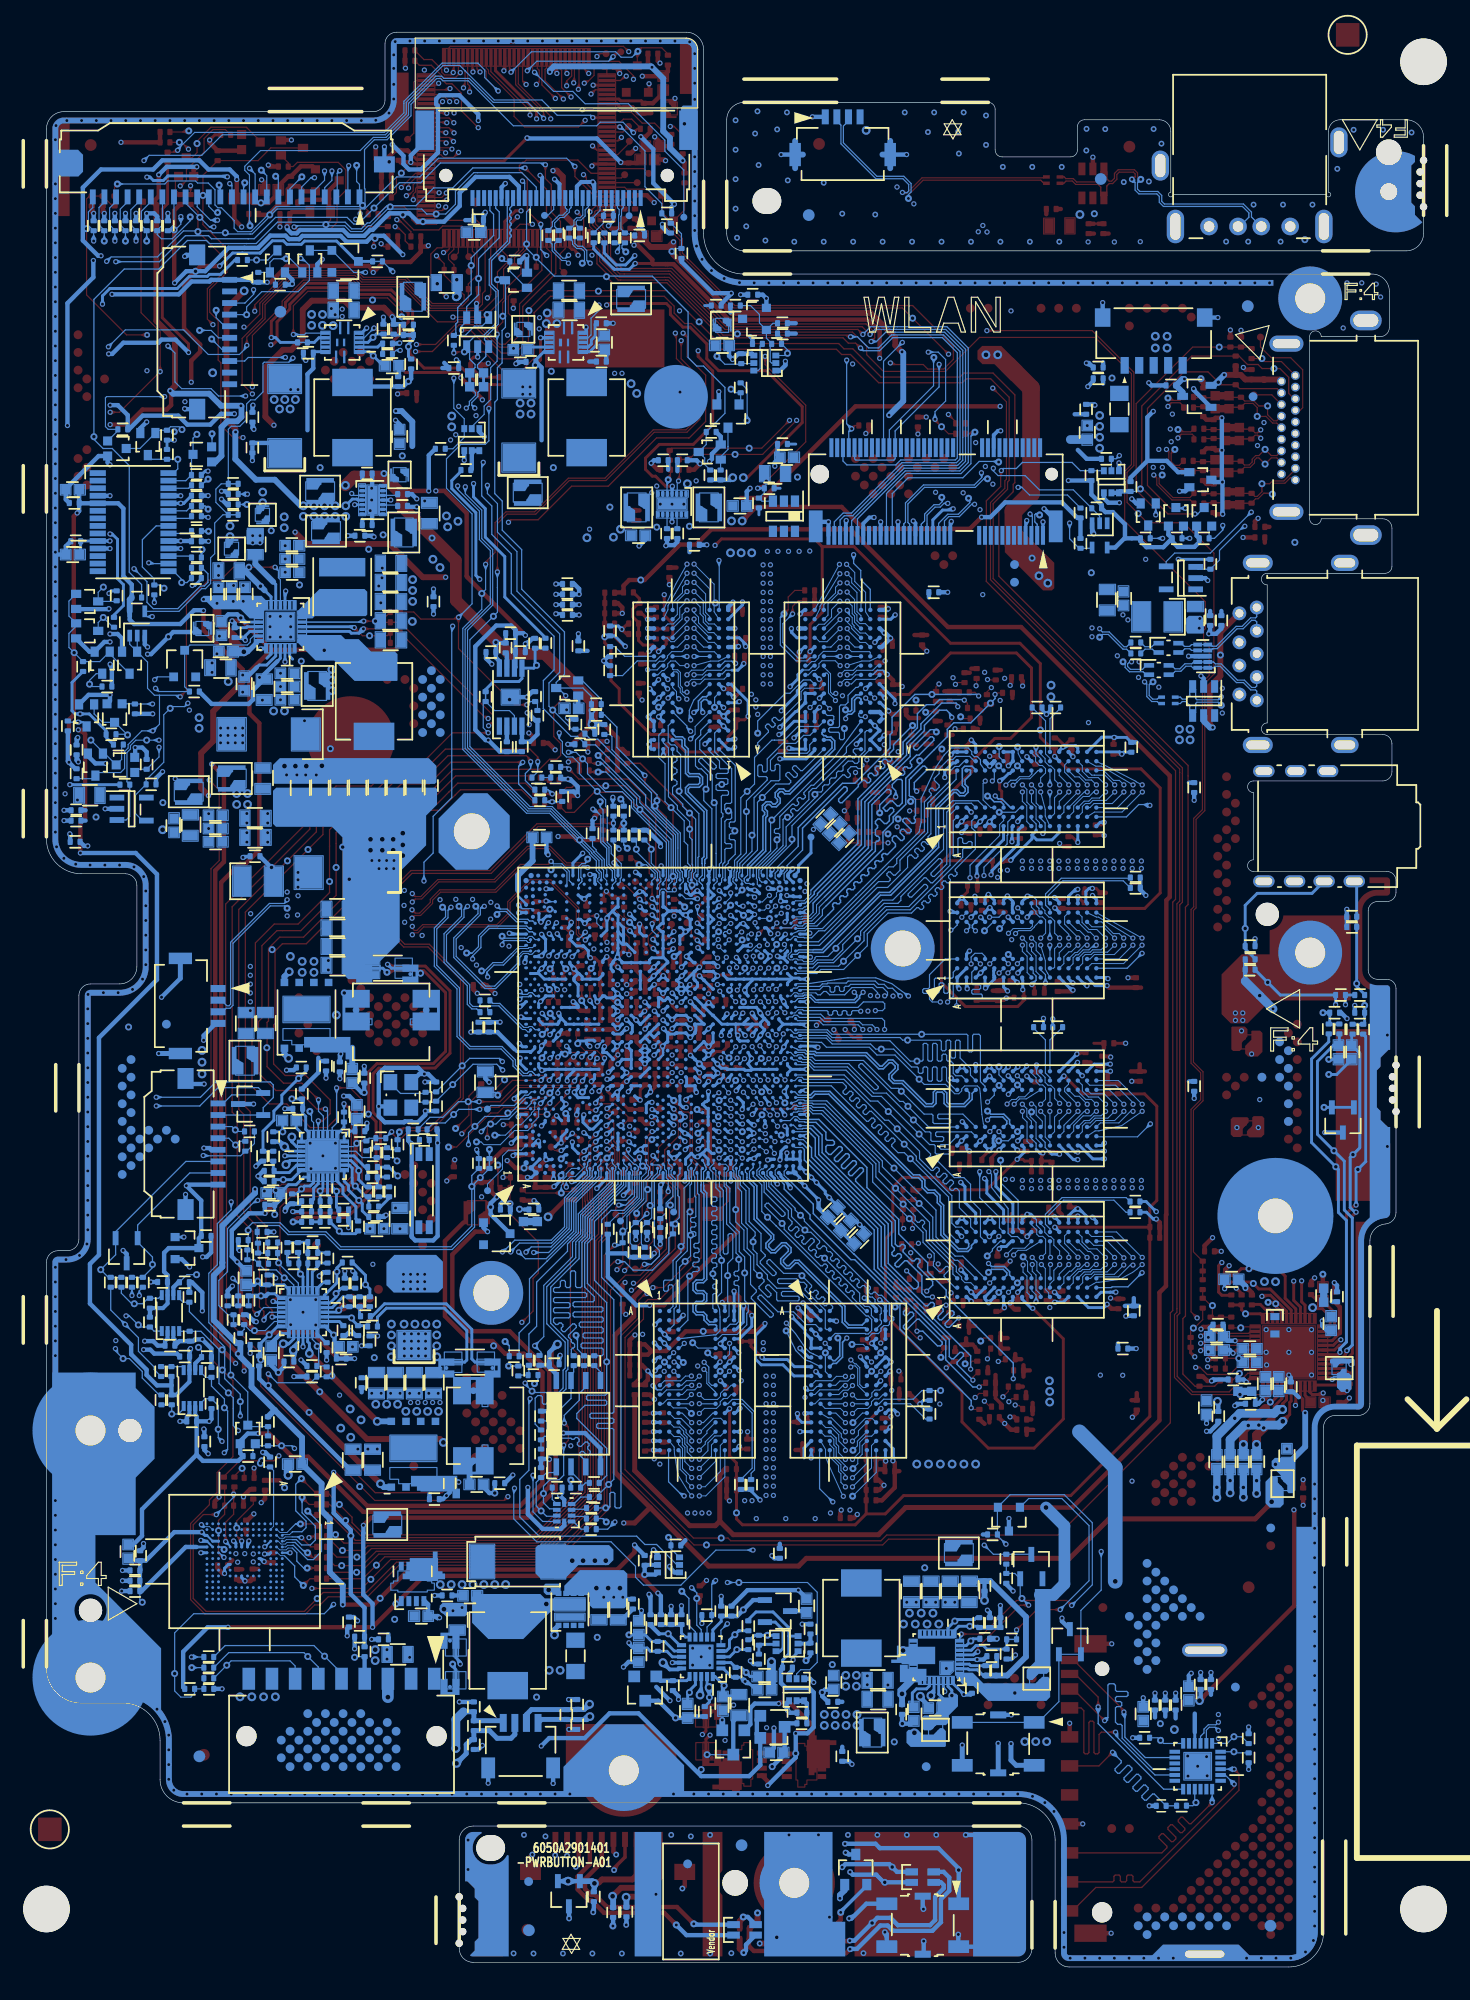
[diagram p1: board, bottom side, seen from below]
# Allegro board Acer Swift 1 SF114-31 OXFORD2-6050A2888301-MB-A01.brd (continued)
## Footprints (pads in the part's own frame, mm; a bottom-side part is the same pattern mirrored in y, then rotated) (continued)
TSMOS_500X600X110_8_127_T1
  rect 0.66x0.635 smd: 1(-1.905,-2.835) 2(-0.635,-2.835) 3(0.635,-2.835) 5(1.905,2.835) 6(0.635,2.835) 7(-0.635,2.835) 8(-1.905,2.835)
  custom 0.486x0.486 smd: 4(1.905,-2.835)
  rect 3.988x2.159 smd: 9(0,0.526)
TSOT23_290X130X110_3_096_P1
  rect 0.508x1.295 smd: 1(-0.96,-1.049) 2(0.96,-1.049) 3(0,1.049)
TSOT23_290X160X125_5_095
  rect 0.508x1.27 smd: 1(-0.965,-1.27) 2(0,-1.27) 3(0.965,-1.27) 4(1.016,1.27) 5(-0.965,1.27)
TSOT23_292X130X120_3_095
  rect 0.711x0.787 smd: 1(-0.95,-1.025) 2(0,1.025) 3(0.95,-1.025)
TSOT_290X160X110_6_095
  rect 0.711x0.991 smd: 1(-0.95,-1.3) 2(0,-1.3) 3(0.95,-1.3) 4(0.95,1.3) 5(0,1.3) 6(-0.95,1.3)
TSSC88_200X125X110_6_065-2
  rect 0.508x0.61 smd: 1(-0.65,-0.95) 2(0,-0.95) 3(0.65,-0.95) 4(0.65,0.95) 5(0,0.95) 6(-0.65,0.95)
TSSOP_970X440X120_28_065_P3
  rect 0.508x1.397 smd: 1(-4.225,-3.05) 2(-3.575,-3.05) 3(-2.925,-3.05) 4(-2.275,-3.05) 5(-1.625,-3.05) 6(-0.975,-3.05) 7(-0.325,-3.05) 8(0.325,-3.05) 9(0.975,-3.05) 10(1.625,-3.05) 11(2.275,-3.05) 12(2.925,-3.05) 13(3.575,-3.05) 14(4.225,-3.05) 15(4.225,3.05) 16(3.575,3.05) 17(2.925,3.05) 18(2.275,3.05) 19(1.625,3.05) 20(0.975,3.05) 21(0.325,3.05) 22(-0.325,3.05) 23(-0.975,3.05) 24(-1.625,3.05) 25(-2.275,3.05) 26(-2.925,3.05) 27(-3.575,3.05) 28(-4.225,3.05)
TSSOT23_292X130X111_3_096
  rect 0.787x0.889 smd: 1(-0.955,-1.001) 2(0.955,-1.001) 3(0,1.001)
TSSOT323_200X125X100_3_065
  rect 0.711x0.889 smd: 1(-0.65,-0.95) 2(0.65,-0.95) 3(0,0.95)
UMT3F_200X125X100_3_065
  rect 0.787x0.787 smd: 1(-0.65,-0.8) 2(0.65,-0.8) 3(0,0.8)
unnamed#2
  round 0.635 hole 0.635 unplated: (0,0) (1,-0.3) (2,-0.3) (3,-0.3) (4,0)
unnamed#3
  round 2.007 hole 2.007 unplated: (0,0)
unnamed#4
  oval 2.21x2.489 hole 2.21x2.489 unplated: (0,-0.14)
unnamed#5
  rect 2.007x2.007 smd: (0,0) (0,0)
USB3_OTOP_9_DIP_RV_S_100_186
  round 1.194 hole 0.711: 1(3.5,9.09) 2(1,9.09) 3(-1,9.09) 4(-3.5,9.09) 5(-4,7.59) 6(-2,7.59) 7(0,7.59) 8(2,7.59) 9(4,7.59)
  oval 1.397x2.591 hole 0.787x2.007: G1(7.85,7.5) G2(-7.85,7.5)
  oval 1.397x2.388 hole 0.787x1.803: G3(7.85,0) G4(-7.85,0)
USB_SYN_4_RS_S_110_250
  round 1.524 hole 0.914: 1(3.5,0) 2(1.001,0) 3(-1.001,0) 4(-3.5,0)
  oval 1.499x2.896 hole 0.889x2.311: G1(6.401,0) G2(-6.401,0)
  oval 1.499x2.591 hole 0.889x2.007: G3(7.701,-5.25) G4(-7.701,-7.252)
VSSOP_200X230X090_8_050_P2
  rect 0.356x0.864 smd: 1(-0.75,-1.55) 2(-0.25,-1.55) 3(0.25,-1.55) 4(0.75,-1.55) 5(0.75,1.55) 6(0.25,1.55) 7(-0.25,1.55) 8(-0.75,1.55)
WQFN_400X400X080_28_040_T2
  rect 0.297x0.787 smd: 1(-1.2,-1.85) 2(-0.8,-1.85) 3(-0.4,-1.85) 4(0,-1.85) 5(0.4,-1.85) 6(0.8,-1.85) 7(1.2,-1.85) 15(1.2,1.85) 16(0.8,1.85) 17(0.4,1.85) 18(0,1.85) 19(-0.4,1.85) 20(-0.8,1.85) 21(-1.2,1.85)
  rect 0.787x0.297 smd: 8(1.85,-1.2) 9(1.85,-0.8) 10(1.85,-0.4) 11(1.85,0) 12(1.85,0.4) 13(1.85,0.8) 14(1.85,1.2) 22(-1.85,1.2) 23(-1.85,0.8) 24(-1.85,0.4) 25(-1.85,0) 26(-1.85,-0.4) 27(-1.85,-0.8) 28(-1.85,-1.2)
  rect 2.393x2.393 smd: 29(0,0)
WTB_ACES_30_050_SMD_R_F_265_1
  round 1.143 hole 1.143 unplated: (-9.55,0.003) (9.55,0.003)
  rect 0.356x1.372 smd: 1(-7.249,1.951) 2(-6.749,1.951) 3(-6.248,1.951) 4(-5.751,1.951) 5(-5.25,1.951) 6(-4.75,1.951) 7(-4.249,1.951) 8(-3.749,1.951) 9(-3.249,1.951) 10(-2.751,1.951) 11(-2.25,1.951) 12(-1.75,1.951) 13(-1.25,1.951) 14(-0.749,1.951) 15(-0.249,1.951) 16(0.251,1.951) 17(0.752,1.951) 18(1.252,1.951) 19(1.75,1.951) 20(2.25,1.951) 21(2.751,1.951) 22(3.251,1.951) 23(3.752,1.951) 24(4.252,1.951) 25(4.75,1.951) 26(5.25,1.951) 27(5.751,1.951) 28(6.251,1.951) 29(6.751,1.951) 30(7.252,1.951)
  rect 1.6x3.404 smd: G1(-11.374,-3.899) G2(11.377,-3.899)
WTB_LCN_4_100_SMD_R_M_290
  rect 0.61x1.549 smd: 1(-1.5,3.875) 2(-0.5,3.875) 3(0.5,3.875) 4(1.5,3.875)
  rect 1.194x1.803 smd: G1(-2.8,0) G2(2.8,0)
XTAL_320X250X090_4_220-3
  rect 1.397x1.194 smd: 1(-1.1,-0.9) 2(1.1,-0.9) 3(1.1,0.9) 4(-1.1,0.9)
XTAL_670X140X140_4_630
  rect 1.194x0.61 smd: 1(-3.15,-0.45) 2(3.15,-0.45) 3(3.15,0.45) 4(-3.15,0.45)

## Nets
3V3A_PG: R7206.1(A) U6100.4
5V_PG: R7241.1(A) U6150.4
AGND_AUDIO: C501.2(B) C502.1(A) C504.2(B) C505.2(B) C512.1(A) C513.2(B) C523.1(A) C524.1(A) C525.1(A) C531.2(B) C600.2(B) C601.2(B) C604.2(B) C605.2(B) D600.3 JACK600.6 JACK600.MS PAD500.2 PAD501.2 PAD502.2 R501.2(B) R531.2(B) R610.2(B) U500.25(AVSS1) U500.38(AVSS2)
AGND_KBC: C305.2(B) PAD319.1 U301.103(AGND)
DGND: B500.2 C13.2(B) C14.2(B) C18.2(B) C300.2(B) C301.2(B) C302.2(B) C303.2(B) C304.2(B) C306.2(B) C310.2(B) C312.2(B) C313.2(B) C316.2(B) C351.2(B) C503.1(A) C506.1(A) C508.2(B) C509.2(B) C510.2(B) C514.2(B) C515.2(B) C516.2(B) C517.2(B) C519.2(B) C520.2(B) C521.2(B) C522.2(B) C523.2(B) C524.2(B) C525.2(B) C530.2(B) C532.2(B) C608.2(B) C609.2(B) C610.2(B) C611.2(B) C900.2(B) C901.2(B) C902.2(B) C903.2(B) C904.2(B) C905.2(B) C906.2(B) C907.2(B) C1301.2(B) C1302.2(B) C1303.2(B) C1304.2(B) C1305.2(B) C2000.2(B) C2001.2(B) C2002.2(B) C2003.2(B) C2004.2(B) C2005.2(B) C2426.2(B) C2427.2(B) C2428.2(B) C2432.2(B) C2456.2(B) C2457.2(B) C3001.2(B) C3002.2(B) C3007.2(B) C3008.2(B) C3009.1(A) C3014.2(B) C3019.2(B) C3020.2(B) C3150.2(B) C3151.2(B) C3500.2(B) C3501.2(B) C3502.2(B) C3503.2(B) C3504.2(B) C3505.2(B) C3950.2(B) C3951.2(B) C3952.2(B) C3953.2(B) C3954.2(B) C3955.2(B) C3956.2(B) C3957.2(B) C3958.2(B) C3959.2(B) C3960.2(B) C4100.2(B) C4101.2(B) C4103.1(A) C4104.2(B) C4105.2(B) C4106.2(B) C4107.2(B) C4108.2(B) C4109.2(B) C4110.2(B) C4111.2(B) C4112.1(A) C4113.1(A) C4114.1(A) C4115.2(B) C4116.2(B) C4117.2(B) C4118.2(B) C4119.2(B) C4120.2(B) C4121.2(B) C4122.2(B) C4123.2(B) C4124.2(B) C4125.2(B) C4126.2(B) C4127.2(B) C4128.2(B) C4129.2(B) C4130.2(B) C4131.2(B) C4132.2(B) C4133.2(B) C4134.2(B) C4135.2(B) C4136.2(B) C4137.2(B) C4138.2(B) C4139.2(B) C4140.2(B) C4141.2(B) C4142.2(B) C4143.2(B) C4144.2(B) C4145.2(B) C4146.2(B) C4147.2(B) C4148.2(B) C4149.2(B) C4150.2(B) C4151.2(B) C4152.2(B) C4153.2(B) C4154.2(B) C4155.2(B) C4156.2(B) C4157.2(B) C4158.2(B) C4159.2(B) C4160.2(B) C4163.2(B) C4164.2(B) C4165.2(B) C4166.2(B) C4167.2(B) C4168.2(B) C4169.2(B) C4170.2(B) C4171.2(B) C4172.2(B) C4173.2(B) C4174.2(B) C4175.2(B) C4176.2(B) C4177.2(B) C4178.2(B) C4179.2(B) C4180.2(B) C4181.2(B) C4182.2(B) C4183.2(B) C4184.2(B) C4185.2(B) C4186.2(B) C4187.2(B) C4188.2(B) C4189.2(B) C4190.2(B) C4191.2(B) C4192.2(B) C4193.2(B) C4194.2(B) C4195.2(B) C4196.2(B) C4197.2(B) C4198.2(B) C4199.2(B) C4201.2(B) C4202.2(B) C4203.2(B) C4204.2(B) C4205.2(B) C4206.2(B) C4207.2(B) C4208.2(B) C4209.2(B) C4210.2(B) C4211.2(B) C4212.2(B) C4213.2(B) C4214.2(B) C4215.2(B) C4251.2(B) C4252.2(B) C4441.2(B) C4506.2(B) C4507.1(A) C4509.1(A) C4510.1(A) C4511.2(B) C4512.2(B) C4513.2(B) C4514.2(B) C4515.2(B) C4516.2(B) C4517.2(B) C4518.2(B) C4519.2(B) C4520.2(B) C4521.2(B) C4522.2(B) C4523.2(B) C4524.2(B) C4525.2(B) C4526.2(B) C4527.2(B) C4528.2(B) C4529.2(B) C4530.2(B) C4531.2(B) C4532.2(B) C4533.2(B) C4534.2(B) C4535.2(B) C4536.2(B) C4537.2(B) C4538.2(B) C4539.2(B) C4540.2(B) C4541.2(B) C4542.2(B) C4543.2(B) C4544.2(B) C4545.2(B) C4546.2(B) C4547.2(B) C4548.2(B) C4549.2(B) C4550.2(B) C4551.2(B) C4552.2(B) C4553.2(B) C4554.2(B) C4555.2(B) C4556.2(B) C4557.2(B) C4558.2(B) C4559.2(B) C4560.2(B) C4561.2(B) C4562.2(B) C4563.2(B) C4564.2(B) C4565.2(B) C4566.2(B) C4569.2(B) C4570.2(B) C4571.2(B) C4572.2(B) C4573.2(B) C4574.2(B) C4575.2(B) C4576.2(B) C4577.2(B) C4578.2(B) C4579.2(B) C4580.2(B) C4581.2(B) C4582.2(B) C4583.2(B) C4584.2(B) C4585.2(B) C4586.2(B) C4587.2(B) C4588.2(B) C4589.2(B) C4590.2(B) C4591.2(B) C4592.2(B) C4593.2(B) C4594.2(B) C4595.2(B) C4596.2(B) C4597.2(B) C4598.2(B) C4599.2(B) C4600.2(B) C4601.2(B) C4602.2(B) C4603.2(B) C4604.2(B) C4605.2(B) C4606.2(B) C4607.2(B) C4608.2(B) C4609.2(B) C4610.2(B) C4617.2(B) C4625.2(B) C4626.2(B) C4627.2(B) C4630.2(B) C4631.1(A) C4636.2(B) C4640.2(B) C4652.2(B) C6000.2(B) C6001.2(B) C6010.2(B) C6011.2(B) C6021.2(B) C6022.2(B) C6024.2(B) C6025.2(B) C6026.1(A) C6028.2(B) C6032.2(B) C6036.2(B) C6037.2(B) C6050.2(B) C6051.2(B) C6100.2(B) C6109.2(B) C6110.2(B) C6111.2(B) C6121.2(B) C6122.2(B) C6150.2(B) C6160.2(B) C6161.2(B) C6162.2(B) C6169.2(B) C6172.2(B) C6600.2(B) C6601.2(B) C6602.2(B) C6603.2(B) C6604.2(B) C6605.2(B) C6606.2(B) C6607.2(B) C6608.2(B) C6609.2(B) C6610.2(B) C6611.2(B) C6612.2(B) C6616.2(B) C6642.2(B) C6643.2(B) C6645.2(B) C6646.2(B) C6647.2(B) C6699.2(B) C6700.2(B) C6701.2(B) C6702.2(B) C6710.2(B) C6711.2(B) C6712.2(B) C6716.2(B) C6742.2(B) C6743.2(B) C6745.2(B) C6746.2(B) C6747.2(B) C7000.2(B) C7001.2(B) C7002.2(B) C7003.2(B) C7100.2(B) C7101.2(B) C7102.2(B) C7104.2(B) C7108.2(B) C7109.2(B) C7110.2(B) C7111.2(B) C7114.2(B) C7116.2(B) C7120.2(B) C7121.2(B) C7122.2(B) C7123.2(B) C7125.2(B) C7203.2(B) C7205.2(B) C7206.2(B) C7207.2(B) C7225.1(A) C7510.2(B) C7511.2(B) C7512.2(B) C7513.2(B) C7514.2(B) C7518.2(B) C7519.2(B) C7520.2(B) C7521.2(B) C7522.2(B) C7526.2(B) C7527.2(B) C7528.2(B) C7529.2(B) C7531.2(B) C7532.2(B) C7533.2(B) C7534.2(B) C7535.2(B) C7536.2(B) C7537.2(B) C7538.2(B) C7539.2(B) C7540.2(B) C7541.2(B) C7546.2(B) C7552.2(B) C7567.2(B) C7568.2(B) C7569.2(B) C7572.2(B) C7573.2(B) C7574.2(B) C7577.2(B) C7578.2(B) C7580.2(B) C7583.2(B) C7584.2(B) C7585.2(B) C7591.2(B) C7593.2(B) C7600.2(B) C7601.2(B) C7602.2(B) C7604.2(B) C7661.2(B) C7761.2(B) C7979.2(B) C60013.2(B) C60209.2(B) C60300.2(B) C60301.2(B) C60302.2(B) C60303.2(B) C60306.2(B) C60310.2(B) C60311.2(B) C60316.2(B) C60350.2(B) C60351.2(B) C60600.2(B) C60601.2(B) C60602.2(B) C60603.2(B) C60604.2(B) C60610.2(B) C60611.2(B) C60612.2(B) C60900.2(B) C60901.2(B) C60910.2(B) C60911.2(B) C60912.2(B) C61000.2(B) C61010.2(B) C61100.2(B) C61110.2(B) C61700.2(B) C61710.2(B) CN245.9 CN245.10 CN245.G1 CN245.G2 CN251.G1 CN251.G2 CN281.5 CN281.G1 CN281.G2 CN600.G1(G) CN600.G2(G_1) CN901.3 CN901.6 CN901.G1 CN901.G2 CN901.G3 CN901.G4 CN1300.1(GND1) CN1300.7(GND2) CN1300.18(GND3) CN1300.33(GND4) CN1300.39(GND5) CN1300.45(GND6) CN1300.51(GND7) CN1300.57(GND8) CN1300.63(GND9) CN1300.69(GND10) CN1300.75(GND11) CN1300.G1 CN1300.G2 CN2002.4 CN2002.G1 CN2002.G2 CN2401.4 CN2401.7 CN2401.G2 CN2401.G4 CN3000.6 CN3000.9 CN3000.12 CN3000.15 CN3000.18 CN3000.25 CN3000.G1 CN3000.G2 CN3150.2 CN3150.5 CN3150.8 CN3150.11 CN3150.17 CN3150.G3 CN3150.G4 CN6000.3 CN6000.4 CN6000.G1 CN6000.G2 CN6050.3 CN6050.8 CN6050.9 D250.2 D251.2 D252.2 D253.2 D254.2 D255.2 D256.2 D257.2 D280.3 D281.3 D282.2 D500.3 D501.2(A2) D901.2 D902.2 D2406.3 D2406.8 D2409.2 D3000.2 D3950.2 D3951.2 D4500.2 D7152.1 D7501.1 D7503.1 PAD319.2 PAD500.1 PAD501.1 PAD502.1 PAD4501.2 Q300.2(S) Q1302.1(S1) Q1302.4(S2) Q3001.1(S1) Q3001.4(S2) Q3003.2(S) Q3006.2(E) Q3007.2(S) Q3152.2(S) Q3153.2(S) Q3501.2(S) Q3502.2(S) Q4506.1(S1) Q4506.4(S2) Q4516.2(S) Q4517.2(S) Q4524.2(S) Q4525.2(S) Q4714.2(S) Q6000.5 Q6000.6 Q6000.7 Q6610.5 Q6610.6 Q6610.7 Q6710.5 Q6710.6 Q6710.7 Q7000.2(S) Q7106.2(S) Q7108.2(S) Q7114.2(S) Q7120.2(S) Q7202.2 Q7214.1(S1) Q7214.4(S2) Q60002.1(S1) Q60002.4(S2) R20.2(B) R324.2(B) R333.2(B) R352.2(B) R391.1(A) R503.2(B) R900.1(A) R2000.2(B) R3010.2(B) R3017.2(B) R3021.2(B) R3061.1(A) R3150.2(B) R3965.2(B) R4100.1(A) R4101.1(A) R4102.1(A) R4103.1(A) R4105.1(A) R4106.1(A) R4107.1(A) R4108.1(A) R4109.1(A) R4111.1(A) R4144.1(A) R4151.1(A) R4174.1(A) R4177.1(A) R4178.1(A) R4179.1(A) R4180.1(A) R4181.1(A) R4182.1(A) R4187.1(A) R4441.2(B) R4444.2(B) R4504.1(A) R4505.1(A) R4520.1(A) R4521.1(A) R4533.1(A) R4541.1(A) R4542.1(A) R4555.1(A) R4564.2(B) R4574.2(B) R4670.2(B) R4676.2(B) R4680.2(B) R4700.1(A) R4701.1(A) R4702.2(B) R4705.2(B) R4706.2(B) R4707.2(B) R4711.2(B) R4712.2(B) R4809.1(A) R4810.1(A) R4815.1(A) R4820.2(B) R4836.1(A) R4837.1(A) R4843.1(A) R4844.2(B) R4849.1(A) R4851.2(B) R4900.2(B) R4901.2(B) R4902.2(B) R4903.2(B) R6003.2(B) R6008.1(A) R6054.1(A) R6151.1(A) R6646.2(B) R6650.2(B) R6652.1(A) R6655.2(B) R6658.2(B) R6661.2(B) R6746.2(B) R6750.2(B) R6752.1(A) R6755.2(B) R6758.2(B) R6761.2(B) R7100.2(B) R7501.2(B) R7502.2(B) R60018.2(B) R60019.2(B) R60024.2(B) R60301.1(A) S1.1 S2.1 S3.1 S4.1 S6.1 S7.1 ST2.1 ST3.1 SW500.2 SW500.4 SW500.5 SW500.6 U301.5(GND6) U301.18(GND1) U301.45(GND2) U301.78(GND3) U301.89(GND4) U301.116(GND5) U500.49 U900.25(GND) U2000.2 U2406.2 U3151.1 U3500.4(GND1) U3500.11(GND2) U3500.18(GND3) U3500.25(GND4) U3950.A6(VSS<1>) U3950.C4(VSSQ<1>) U3950.E7(VSS<2>) U3950.G5(VSS<3>) U3950.H10(VSS<4>) U3950.J5(VSS<5>) U3950.K8(VSS<6>) U3950.N2(VSSQ<2>) U3950.N5(VSSQ<3>) U3950.P4(VSSQ<4>) U3950.P6(VSSQ<5>) U4100.A9(VSS_1) U4100.B1(VSSQ_1) U4100.B3(VSS_2) U4100.B9(VSSQ_2) U4100.D1(VSSQ_3) U4100.D8(VSSQ_4) U4100.E1(VSS_3) U4100.E2(VSSQ_5) U4100.E8(VSSQ_6) U4100.F9(VSSQ_7) U4100.G1(VSSQ_8) U4100.G8(VSS_4) U4100.G9(VSSQ_9) U4100.J2(VSS_5) U4100.J8(VSS_6) U4100.M1(VSS_7) U4100.M9(VSS_8) U4100.P1(VSS_9) U4100.P9(VSS_10) U4100.T1(VSS_11) U4100.T9(VSS_12) U4101.A9(VSS_1) U4101.B1(VSSQ_1) U4101.B3(VSS_2) U4101.B9(VSSQ_2) U4101.D1(VSSQ_3) U4101.D8(VSSQ_4) U4101.E1(VSS_3) U4101.E2(VSSQ_5) U4101.E8(VSSQ_6) U4101.F9(VSSQ_7) U4101.G1(VSSQ_8) U4101.G8(VSS_4) U4101.G9(VSSQ_9) U4101.J2(VSS_5) U4101.J8(VSS_6) U4101.M1(VSS_7) U4101.M9(VSS_8) U4101.P1(VSS_9) U4101.P9(VSS_10) U4101.T1(VSS_11) U4101.T9(VSS_12) U4102.A9(VSS_1) U4102.B1(VSSQ_1) U4102.B3(VSS_2) U4102.B9(VSSQ_2) U4102.D1(VSSQ_3) U4102.D8(VSSQ_4) U4102.E1(VSS_3) U4102.E2(VSSQ_5) U4102.E8(VSSQ_6) U4102.F9(VSSQ_7) U4102.G1(VSSQ_8) U4102.G8(VSS_4) U4102.G9(VSSQ_9) U4102.J2(VSS_5) U4102.J8(VSS_6) U4102.M1(VSS_7) U4102.M9(VSS_8) U4102.P1(VSS_9) U4102.P9(VSS_10) U4102.T1(VSS_11) U4102.T9(VSS_12) U4103.A9(VSS_1) U4103.B1(VSSQ_1) U4103.B3(VSS_2) U4103.B9(VSSQ_2) U4103.D1(VSSQ_3) U4103.D8(VSSQ_4) U4103.E1(VSS_3) U4103.E2(VSSQ_5) U4103.E8(VSSQ_6) U4103.F9(VSSQ_7) U4103.G1(VSSQ_8) U4103.G8(VSS_4) U4103.G9(VSSQ_9) U4103.J2(VSS_5) U4103.J8(VSS_6) U4103.M1(VSS_7) U4103.M9(VSS_8) U4103.P1(VSS_9) U4103.P9(VSS_10) U4103.T1(VSS_11) U4103.T9(VSS_12) U4104.A9(VSS_1) U4104.B1(VSSQ_1) U4104.B3(VSS_2) U4104.B9(VSSQ_2) U4104.D1(VSSQ_3) U4104.D8(VSSQ_4) U4104.E1(VSS_3) U4104.E2(VSSQ_5) U4104.E8(VSSQ_6) U4104.F9(VSSQ_7) U4104.G1(VSSQ_8) U4104.G8(VSS_4) U4104.G9(VSSQ_9) U4104.J2(VSS_5) U4104.J8(VSS_6) U4104.M1(VSS_7) U4104.M9(VSS_8) U4104.P1(VSS_9) U4104.P9(VSS_10) U4104.T1(VSS_11) U4104.T9(VSS_12) U4105.A9(VSS_1) U4105.B1(VSSQ_1) U4105.B3(VSS_2) U4105.B9(VSSQ_2) U4105.D1(VSSQ_3) U4105.D8(VSSQ_4) U4105.E1(VSS_3) U4105.E2(VSSQ_5) U4105.E8(VSSQ_6) U4105.F9(VSSQ_7) U4105.G1(VSSQ_8) U4105.G8(VSS_4) U4105.G9(VSSQ_9) U4105.J2(VSS_5) U4105.J8(VSS_6) U4105.M1(VSS_7) U4105.M9(VSS_8) U4105.P1(VSS_9) U4105.P9(VSS_10) U4105.T1(VSS_11) U4105.T9(VSS_12) U4106.A9(VSS_1) U4106.B1(VSSQ_1) U4106.B3(VSS_2) U4106.B9(VSSQ_2) U4106.D1(VSSQ_3) U4106.D8(VSSQ_4) U4106.E1(VSS_3) U4106.E2(VSSQ_5) U4106.E8(VSSQ_6) U4106.F9(VSSQ_7) U4106.G1(VSSQ_8) U4106.G8(VSS_4) U4106.G9(VSSQ_9) U4106.J2(VSS_5) U4106.J8(VSS_6) U4106.M1(VSS_7) U4106.M9(VSS_8) U4106.P1(VSS_9) U4106.P9(VSS_10) U4106.T1(VSS_11) U4106.T9(VSS_12) U4107.A9(VSS_1) U4107.B1(VSSQ_1) U4107.B3(VSS_2) U4107.B9(VSSQ_2) U4107.D1(VSSQ_3) U4107.D8(VSSQ_4) U4107.E1(VSS_3) U4107.E2(VSSQ_5) U4107.E8(VSSQ_6) U4107.F9(VSSQ_7) U4107.G1(VSSQ_8) U4107.G8(VSS_4) U4107.G9(VSSQ_9) U4107.J2(VSS_5) U4107.J8(VSS_6) U4107.M1(VSS_7) U4107.M9(VSS_8) U4107.P1(VSS_9) U4107.P9(VSS_10) U4107.T1(VSS_11) U4107.T9(VSS_12) U4441.9 U4500.A5(VSS1) U4500.A7(VSS3) U4500.A11(VSS1) U4500.A15(VSS2) U4500.A19(VSS3) U4500.A23(VSS4) U4500.A31(VSS5) U4500.A39(VSS6) U4500.A43(VSS7) U4500.A47(VSS8) U4500.AA16(VSS9) U4500.AA27(VSS10) U4500.AA38(VSS11) U4500.AA53(VSS12) U4500.AB4(VSS17) U4500.AB6(VSS21) U4500.AB10(VSS13) U4500.AB12(VSS14) U4500.AB13(VSS15) U4500.AB14(VSS16) U4500.AB42(VSS18) U4500.AB47(VSS19) U4500.AB50(VSS20) U4500.AC16(VSS22) U4500.AC29(VSS23) U4500.AC33(VSS24) U4500.AC35(VSS25) U4500.AC38(VSS26) U4500.AD4(VSS31) U4500.AD21(VSS27) U4500.AD30(VSS28) U4500.AD32(VSS29) U4500.AD36(VSS30) U4500.AD44(VSS32) U4500.AE1(VSS33) U4500.AE6(VSS45) U4500.AE8(VSS46) U4500.AE9(VSS47) U4500.AE11(VSS34) U4500.AE12(VSS35) U4500.AE14(VSS36) U4500.AE40(VSS37) U4500.AE42(VSS38) U4500.AE43(VSS39) U4500.AE45(VSS40) U4500.AE46(VSS41) U4500.AE48(VSS42) U4500.AE50(VSS43) U4500.AE53(VSS44) U4500.AF10(VSS48) U4500.AF24(VSS1) U4500.AF25(VSS49) U4500.AF32(VSS50) U4500.AF38(VSS51) U4500.AF47(VSS52) U4500.AG25(VSS53) U4500.AH9(VSS62) U4500.AH10(VSS54) U4500.AH12(VSS55) U4500.AH13(VSS56) U4500.AH14(VSS57) U4500.AH41(VSS58) U4500.AH42(VSS59) U4500.AH44(VSS60) U4500.AH47(VSS61) U4500.AJ1(VSS63) U4500.AJ3(VSS66) U4500.AJ16(VSS64) U4500.AJ18(VSS1) U4500.AJ25(VSS65) U4500.AJ51(VSS67) U4500.AJ53(VSS68) U4500.AK4(VSS74) U4500.AK7(VSS80) U4500.AK16(VSS69) U4500.AK22(VSS2) U4500.AK25(VSS70) U4500.AK27(VSS71) U4500.AK29(VSS3) U4500.AK32(VSS72) U4500.AK38(VSS73) U4500.AK40(VSS75) U4500.AK44(VSS76) U4500.AK45(VSS77) U4500.AK47(VSS78) U4500.AK50(VSS79) U4500.AM4(VSS87) U4500.AM13(VSS4) U4500.AM16(VSS81) U4500.AM24(VSS82) U4500.AM27(VSS83) U4500.AM30(VSS84) U4500.AM35(VSS85) U4500.AM38(VSS86) U4500.AM42(VSS88) U4500.AM50(VSS89) U4500.AN1(VSS90) U4500.AN3(VSS98) U4500.AN5(VSS15) U4500.AN6(VSS18) U4500.AN8(VSS19) U4500.AN9(VSS20) U4500.AN11(VSS91) U4500.AN12(VSS92) U4500.AN14(VSS93) U4500.AN16(VSS94) U4500.AN21(VSS5) U4500.AN24(VSS95) U4500.AN25(VSS96) U4500.AN29(VSS97) U4500.AN30(VSS6) U4500.AN33(VSS2) U4500.AN38(VSS7) U4500.AN40(VSS8) U4500.AN42(VSS9) U4500.AN43(VSS10) U4500.AN45(VSS11) U4500.AN46(VSS12) U4500.AN48(VSS13) U4500.AN49(VSS14) U4500.AN51(VSS16) U4500.AN53(VSS17) U4500.AP4(VSS21) U4500.AP9(VSS24) U4500.AP45(VSS22) U4500.AP50(VSS23) U4500.AT3(VSS28) U4500.AT9(VSS33) U4500.AT18(VSS25) U4500.AT19(VSS26) U4500.AT27(VSS27) U4500.AT35(VSS29) U4500.AT36(VSS30) U4500.AT45(VSS31) U4500.AT51(VSS32) U4500.AU1(VSS34) U4500.AU3(VSS35) U4500.AU51(VSS36) U4500.AU53(VSS37) U4500.AV14(VSS38) U4500.AV19(VSS39) U4500.AV24(VSS40) U4500.AV27(VSS41) U4500.AV30(VSS42) U4500.AV35(VSS43) U4500.AV40(VSS44) U4500.AW13(VSS3) U4500.AW19(VSS45) U4500.AW27(VSS46) U4500.AW35(VSS47) U4500.AW41(VSS4) U4500.AY3(VSS53) U4500.AY7(VSS60) U4500.AY9(VSS61) U4500.AY20(VSS48) U4500.AY22(VSS49) U4500.AY24(VSS50) U4500.AY26(VSS51) U4500.AY28(VSS52) U4500.AY30(VSS54) U4500.AY32(VSS55) U4500.AY34(VSS56) U4500.AY45(VSS57) U4500.AY47(VSS58) U4500.AY51(VSS59) U4500.B2(VSS4) U4500.B28(VSS62) U4500.B36(VSS63) U4500.BA19(VSS64) U4500.BA24(VSS65) U4500.BA27(VSS66) U4500.BA30(VSS67) U4500.BA35(VSS68) U4500.BB4(VSS6) U4500.BB19(VSS69) U4500.BB27(VSS70) U4500.BB35(VSS71) U4500.BB50(VSS7) U4500.BC10(VSS72) U4500.BC14(VSS73) U4500.BC16(VSS74) U4500.BC26(VSS75) U4500.BC28(VSS76) U4500.BC38(VSS77) U4500.BC40(VSS78) U4500.BC44(VSS79) U4500.BD1(VSS80) U4500.BD19(VSS81) U4500.BD27(VSS82) U4500.BD35(VSS83) U4500.BD53(VSS84) U4500.BE19(VSS85) U4500.BE35(VSS86) U4500.BF4(VSS8) U4500.BF12(VSS87) U4500.BF22(VSS88) U4500.BF26(VSS89) U4500.BF27(VSS90) U4500.BF28(VSS91) U4500.BF32(VSS92) U4500.BF42(VSS93) U4500.BF50(VSS9) U4500.BG1(VSS10) U4500.BG5(VSS11) U4500.BG7(VSS102) U4500.BG14(VSS94) U4500.BG16(VSS95) U4500.BG18(VSS96) U4500.BG19(VSS97) U4500.BG20(VSS98) U4500.BG24(VSS99) U4500.BG27(VSS100) U4500.BG30(VSS101) U4500.BG34(VSS5) U4500.BG35(VSS6) U4500.BG36(VSS7) U4500.BG38(VSS8) U4500.BG40(VSS9) U4500.BG47(VSS11) U4500.BG49(VSS10) U4500.BG53(VSS12) U4500.BH1(VSS13) U4500.BH2(VSS14) U4500.BH52(VSS15) U4500.BJ7(VSS22) U4500.BJ11(VSS12) U4500.BJ15(VSS13) U4500.BJ19(VSS14) U4500.BJ23(VSS15) U4500.BJ27(VSS16) U4500.BJ31(VSS17) U4500.BJ35(VSS18) U4500.BJ39(VSS19) U4500.BJ43(VSS20) U4500.BJ47(VSS21) U4500.C1(VSS17) U4500.C3(VSS25) U4500.C20(VSS103) U4500.C22(VSS23) U4500.C28(VSS24) U4500.C30(VSS26) U4500.C36(VSS27) U4500.C39(VSS28) U4500.C47(VSS29) U4500.D10(VSS30) U4500.D16(VSS31) U4500.D24(VSS32) U4500.D27(VSS33) U4500.D32(VSS34) U4500.D38(VSS35) U4500.D40(VSS36) U4500.D42(VSS37) U4500.E19(VSS38) U4500.E35(VSS39) U4500.E46(VSS40) U4500.E51(VSS41) U4500.F1(VSS18) U4500.F5(VSS47) U4500.F19(VSS42) U4500.F24(VSS43) U4500.F27(VSS44) U4500.F32(VSS45) U4500.F35(VSS46) U4500.G12(VSS48) U4500.G14(VSS49) U4500.G22(VSS50) U4500.G26(VSS51) U4500.G28(VSS52) U4500.G30(VSS53) U4500.H8(VSS57) U4500.H19(VSS54) U4500.H27(VSS55) U4500.H35(VSS56) U4500.J18(VSS58) U4500.J19(VSS59) U4500.J22(VSS60) U4500.J27(VSS61) U4500.J30(VSS62) U4500.J35(VSS63) U4500.J38(VSS64) U4500.J42(VSS65) U4500.J53(VSS66) U4500.K4(VSS76) U4500.K12(VSS67) U4500.K14(VSS68) U4500.K16(VSS69) U4500.K22(VSS70) U4500.K24(VSS71) U4500.K30(VSS72) U4500.K32(VSS73) U4500.K34(VSS74) U4500.K36(VSS75) U4500.K45(VSS77) U4500.K50(VSS78) U4500.L1(VSS79) U4500.L19(VSS80) U4500.L27(VSS81) U4500.L35(VSS82) U4500.L41(VSS19) U4500.M9(VSS90) U4500.M14(VSS83) U4500.M19(VSS84) U4500.M24(VSSA) U4500.M27(VSS85) U4500.M35(VSS86) U4500.M40(VSS87) U4500.M45(VSS88) U4500.M50(VSS89) U4500.N22(VSS91) U4500.N24(VSS92) U4500.N32(VSS93) U4500.N51(VSS94) U4500.N53(VSS95) U4500.P4(VSS22) U4500.P10(VSS99) U4500.P19(VSS96) U4500.P22(VSS97) U4500.P27(VSS98) U4500.P32(VSS99) U4500.P35(VSS20) U4500.P36(VSS21) U4500.P42(VSS23) U4500.R1(VSS24) U4500.T9(VSS26) U4500.T14(VSS25) U4500.T47(VSS100) U4500.U5(VSS45) U4500.U6(VSS47) U4500.U8(VSS48) U4500.U9(VSS49) U4500.U11(VSS27) U4500.U12(VSS28) U4500.U14(VSS29) U4500.U18(VSS30) U4500.U21(VSS31) U4500.U25(VSS100) U4500.U29(VSS32) U4500.U30(VSS33) U4500.U32(VSS34) U4500.U33(VSS35) U4500.U36(VSS36) U4500.U38(VSS37) U4500.U40(VSS38) U4500.U42(VSS39) U4500.U43(VSS40) U4500.U45(VSS41) U4500.U46(VSS42) U4500.U48(VSS43) U4500.U49(VSS44) U4500.U53(VSS46) U4500.V16(VSS50) U4500.V21(VSS51) U4500.V25(VSS101) U4500.V32(VSS52) U4500.V38(VSS53) U4500.V41(VSS54) U4500.V42(VSS55) U4500.V44(VSS56) U4500.W1(VSS57) U4500.Y4(VSS66) U4500.Y9(VSS70) U4500.Y10(VSS58) U4500.Y14(VSS59) U4500.Y16(VSS60) U4500.Y19(VSS61) U4500.Y21(VSS62) U4500.Y22(VSS63) U4500.Y24(VSS102) U4500.Y29(VSS64) U4500.Y38(VSS65) U4500.Y40(VSS67) U4500.Y45(VSS68) U4500.Y50(VSS69) U4502.2 U4503.2 U4504.3(GND) U4701.4 U4702.5 U4703.3 U6000.14(GND) U6000.21(TML) U6100.2 U6100.14 U6150.2 U6150.14 U6600.11 U6600.29 U6700.11 U6700.29 U7100.11 U7100.15 U7102.11 U7102.15 U60300.4(VTTGND) U60300.11(PGND_1) U60300.12(PGND_2) U60300.13(PGND_3) U60300.14(PGND_4) U60300.15(PGND_5) U60300.16(PGND) U60300.30(VTTGND_1) U60300.32(GND) U60300.33 U60600.12(GND) U60600.15(PGND) U60600.29(PGND_EX) X4500.2 X4500.4
DGND_HDMI: CN2401.G1 CN2401.G3 CN3150.G1 CN3150.G2 R7501.1(A) R7502.1(A)
DGND_PB: C9100.2(B) C9101.2(B) C9102.2(B) C9150.2(B) CN9100.9 CN9100.10 CN9100.G1 CN9100.G2 D9100.3 D9150.1 S9100.1 SW9100.2 SW9100.4 SW9100.5 SW9100.6 U9150.3
DGND_USB1: C2007.2(B) C2460.2(B) C2461.2(B) C2462.2(B) CN2003.1 CN2003.G1 CN2003.G2 CN2403.4 CN2403.G1 CN2403.G2 CN2403.G3 CN2403.G4 D2410.2 S10.1
P0V675M_MA_VERF_CA: C4110.1(A) C4111.1(A) C4115.1(A) C4116.1(A) C4252.1(A) R4104.1(A) R4105.2(B) R4113.2(B) U4100.M8(VREFCA) U4101.M8(VREFCA) U4102.M8(VREFCA) U4103.M8(VREFCA)
P0V675M_MA_VERF_DQ: C4103.2(B) C4112.2(B) C4113.2(B) C4114.2(B) C4251.1(A) R4110.1(A) R4111.2(B) R4112.2(B) U4100.H1(VREFDQ) U4101.H1(VREFDQ) U4102.H1(VREFDQ) U4103.H1(VREFDQ)
P0V675M_MB_VERF_CA: C4163.1(A) C4165.1(A) C4166.1(A) C4190.1(A) C4192.1(A) C7528.1(A) C7534.1(A) C7535.1(A) C7538.1(A) R4172.1(A) R4173.2(B) R4174.2(B) U4104.M8(VREFCA) U4105.M8(VREFCA) U4106.M8(VREFCA) U4107.M8(VREFCA)
P0V675M_MB_VERF_DQ: C4164.1(A) C4167.1(A) C4169.1(A) C4191.1(A) C4193.1(A) C7529.1(A) C7533.1(A) C7536.1(A) C7539.1(A) R4175.1(A) R4176.2(B) R4177.2(B) U4104.H1(VREFDQ) U4105.H1(VREFDQ) U4106.H1(VREFDQ) U4107.H1(VREFDQ)
P0V675M_VREF: PAD60351.2 R4112.1(A) R4113.1(A) R4173.1(A) R4176.1(A)
P0V675S: C4100.1(A) C4101.1(A) C4102.1(A) C4107.1(A) C4143.1(A) C4144.1(A) C4150.1(A) C4151.1(A) C4158.1(A) C4159.1(A) C4160.1(A) C4200.1(A) PAD60350.2 R4116.1(A) R4117.1(A) R4118.1(A) R4119.1(A) R4120.1(A) R4121.1(A) R4122.1(A) R4123.1(A) R4124.1(A) R4125.1(A) R4126.1(A) R4127.1(A) R4128.1(A) R4129.1(A) R4130.1(A) R4131.1(A) R4132.1(A) R4133.1(A) R4134.1(A) R4135.1(A) R4136.1(A) R4137.1(A) R4138.1(A) R4139.1(A) R4140.1(A) R4141.1(A) R4142.1(A) R4143.1(A) R4145.1(A) R4146.1(A) R4147.1(A) R4148.1(A) R4149.1(A) R4150.1(A) R4152.1(A) R4153.1(A) R4154.1(A) R4155.1(A) R4156.1(A) R4157.1(A) R4158.1(A) R4159.1(A) R4160.1(A) R4161.1(A) R4162.1(A) R4163.1(A) R4164.1(A) R4165.1(A) R4166.1(A) R4167.1(A) R4168.1(A) R4169.1(A) R4170.1(A) R4171.1(A) R4183.1(A) R4184.1(A)
P1V05A: C4541.1(A) C4542.1(A) C4543.1(A) C4544.1(A) C4545.1(A) C4546.1(A) C4547.1(A) C4548.1(A) C4549.1(A) C4550.1(A) C4551.1(A) C4552.1(A) C4553.1(A) C4554.1(A) C4555.1(A) C4556.1(A) C4557.1(A) C4558.1(A) C4559.1(A) C4560.1(A) C4561.1(A) C4562.1(A) C4563.1(A) C4564.1(A) C4566.1(A) C4569.1(A) C4570.1(A) C4606.1(A) C4626.1(A) C4630.1(A) C7515.2(B) C7518.1(A) C7593.1(A) PAD60900.2 R4590.2(B) R4602.2(B) R4605.2(B) R4645.2(B) R4726.1(A) R4850.2(B) U4500.AA18(UNCORE_VNN_S41) U4500.AA19(UNCORE_VNN_S42) U4500.AA21(UNCORE_VNN_S43) U4500.AA22(UNCORE_VNN_S44) U4500.AA24(UNCORE_VNN_S45) U4500.AA25(UNCORE_VNN_S46) U4500.AA32(UNCORE_V1P15_S0IX1) U4500.AA33(UNCORE_V1P15_S0IX2) U4500.AA35(UNCORE_V1P15_S0IX3) U4500.AA36(UNCORE_V1P15_S0IX4) U4500.AC18(UNCORE_VNN_S47) U4500.AC19(UNCORE_VNN_S48) U4500.AC21(UNCORE_VNN_S49) U4500.AC22(UNCORE_VNN_S410) U4500.AC24(UNCORE_VNN_S411) U4500.AC25(UNCORE_VNN_S412) U4500.AC32(UNCORE_V1P15_S0IX5) U4500.AD25(UNCORE_VNN_S413) U4500.AD27(UNCORE_VNN_S414) U4500.AM21(DDR_V1P05A_G31) U4500.AM22(DDR_V1P05A_G32) U4500.AM32(DDR_V1P05A_G33) U4500.AM33(DDR_V1P05A_G34) U4500.AN22(DDR_V1P05A_G35) U4500.AN32(DDR_V1P05A_G36) U4500.G10(FUSE0_V1P05A_G3) U4500.H10(FUSE1_V1P05A_G4) U4500.N18(FUSE3_V1P05A_G5) U4500.U19(FUSE_V1P05A_G3) U4500.U22(SATA_V1P05A_G31) U4500.U24(SATA_V1P05A_G32) U4500.U27(USB3_V1P05A_G31) U4500.V18(ICLK_GND_OFF1) U4500.V19(ICLK_GND_OFF2) U4500.V22(PCIE_V1P05A_G31) U4500.V24(PCIE_V1P05A_G32) U4500.V27(USB3_V1P05A_G32) U4500.V29(USBSSIC_V1P05A_G3) U4500.V33(UNCORE_V1P15_S0IX6) U4500.Y30(UNCORE_V1P15_S0IX7) U4500.Y32(UNCORE_V1P15_S0IX8) U4500.Y33(UNCORE_V1P15_S0IX9) U4500.Y35(UNCORE_V1P15_S0IX10)
P1V5S: C508.1(A) C509.1(A) C4582.1(A) PAD503.1 PAD61700.2 U500.9(DVDD-IO) U4500.AF4(UNCORE_V1P8A_G31) U4500.AH4(UNCORE_V1P8A_G32)
P1V8A: C14.1(A) C304.1(A) C4506.1(A) C4583.1(A) C4584.1(A) C4585.1(A) C4586.1(A) C4587.1(A) C4600.1(A) C4601.1(A) C4605.1(A) C4636.1(A) C7003.1(A) C7120.1(A) Q310.1(G) Q3150.1(G) Q3151.1(G) Q4513.1(G) R35.2(B) R310.2(B) R3020.2(B) R3171.2(B) R3178.1(A) R3179.1(A) R3514.2(B) R3964.2(B) R4523.1(A) R4534.2(B) R4544.2(B) R4545.2(B) R4546.2(B) R4547.1(A) R4548.2(B) R4549.1(A) R4550.1(A) R4551.2(B) R4553.2(B) R4554.2(B) R4560.1(A) R4575.2(B) R4582.1(A) R4583.1(A) R4587.2(B) R4625.1(A) R4628.2(B) R4632.2(B) R4640.2(B) R4653.2(B) R4655.2(B) R4657.2(B) R4659.2(B) R4660.1(A) R4671.2(B) R4677.2(B) R4681.1(A) R4682.1(A) R4686.1(A) R4693.2(B) R4708.1(A) R4709.1(A) R4811.1(A) R4892.2(B) R4893.2(B) R4894.2(B) R4895.2(B) U301.88(VCC4) U4500.AA29(USB_V1P8A_G3) U4500.AD33(GPIO_V1P8A_G31) U4500.AF33(GPIO_V1P8A_G32) U4500.AK18(GPIO_V1P8A_G33) U4500.AK19(GPIO_V1P8A_G34) U4500.U16(FUSE_V1P8A_G3) U4500.Y18(GPIO_V1P8A_G35) U4502.3 U4503.3 U4504.5(VCC) U4701.8 U7100.1 U7100.2 U60600.16(SWO_1P8A)
P1V8S: C306.1(A) C312.1(A) C7121.1(A) D7501.2 PAD7103.2 Q311.1(G) Q3500.1(G) R28.1(A) R3950.2(B) R4649.2(B) U301.4(VDD)
P1V15A: C4532.1(A) C4533.1(A) C4534.1(A) C4535.1(A) C4536.1(A) C4537.1(A) C4538.1(A) C4539.1(A) C4540.1(A) C7517.1(A) PAD61110.2 U4500.AJ35(FUSE_V1P15_S0IX1) U4500.AK21(DDI_V1P15_S0IX1) U4500.AK30(CORE_V1P15_S0IX1) U4500.AK33(FUSE_V1P15_S0IX2) U4500.AK35(CORE_V1P15_S0IX2) U4500.AK36(CORE_V1P15_S0IX3) U4500.AM19(DDI_V1P15_S0IX2) U4500.AM29(CORE_V1P15_S0IX4)
P1V24A: C4588.1(A) C4589.1(A) C4590.1(A) C4591.1(A) C4592.1(A) C4593.1(A) C4594.1(A) C4595.1(A) C4596.1(A) C4597.1(A) C4598.1(A) C4599.1(A) C7516.2(B) C7517.2(B) PAD61000.2 U4500.AC30(PCIE_V1P05A_G31) U4500.AC36(CORE_VSFR_G31) U4500.AD35(CORE_VSFR_G32) U4500.AD38(CORE_VSFR_G33) U4500.AF35(CORE_VSFR_G34) U4500.H44(USB_VDDQ_G31) U4500.M41(USBHSIC_V1P2A_G3) U4500.P38(CORE_VSFR_G35) U4500.P40(MIPI_V1P2A_G31) U4500.P41(USBSSIC_V1P2A_G3) U4500.T40(MIPI_V1P2A_G32) U4500.U35(USB_VDDQ_G32) U4500.V30(CORE_VSFR_G36) U4500.V35(USB_VDDQ_G33) U4500.V36(DDI_VDDQ_G31) U4500.Y25(ICLK_VSFR_G31) U4500.Y27(ICLK_VSFR_G32) U4500.Y36(DDI_VDDQ_G32)
P1V35: C4104.1(A) C4105.1(A) C4106.1(A) C4108.1(A) C4109.1(A) C4117.1(A) C4118.1(A) C4119.1(A) C4120.1(A) C4121.1(A) C4122.1(A) C4123.1(A) C4124.1(A) C4125.1(A) C4126.1(A) C4127.1(A) C4128.1(A) C4129.1(A) C4130.1(A) C4131.1(A) C4132.1(A) C4133.1(A) C4134.1(A) C4135.1(A) C4136.1(A) C4137.1(A) C4138.1(A) C4139.1(A) C4140.1(A) C4141.1(A) C4142.1(A) C4145.1(A) C4146.1(A) C4147.1(A) C4148.1(A) C4149.1(A) C4152.1(A) C4153.1(A) C4154.1(A) C4155.1(A) C4156.1(A) C4157.1(A) C4168.1(A) C4170.1(A) C4171.1(A) C4172.1(A) C4173.1(A) C4174.1(A) C4175.1(A) C4176.1(A) C4177.1(A) C4178.1(A) C4179.1(A) C4180.1(A) C4181.1(A) C4182.1(A) C4183.1(A) C4184.1(A) C4185.1(A) C4186.1(A) C4187.1(A) C4188.1(A) C4189.1(A) C4194.1(A) C4195.1(A) C4196.1(A) C4197.1(A) C4198.1(A) C4199.1(A) C4201.1(A) C4202.1(A) C4203.1(A) C4204.1(A) C4205.1(A) C4206.1(A) C4207.1(A) C4208.1(A) C4209.1(A) C4210.1(A) C4211.1(A) C4212.1(A) C4213.1(A) C4214.1(A) C4215.1(A) C4571.1(A) C4572.1(A) C4573.1(A) C4574.1(A) C4575.1(A) C4576.1(A) C4577.1(A) C4578.1(A) C7531.1(A) C7532.1(A) C7537.1(A) C7540.1(A) C7567.1(A) C7568.1(A) C7569.1(A) C7572.1(A) C7573.1(A) C7574.1(A) C7578.1(A) C7580.1(A) C7583.1(A) C7584.1(A) C7585.1(A) C7979.1(A) PAD60300.2 R4104.2(B) R4110.2(B) R4172.2(B) R4175.2(B) R7229.2(B) R7247.2(B) U4100.A1(VDDQ_1) U4100.A8(VDDQ_2) U4100.B2(VDD_1) U4100.C1(VDDQ_3) U4100.C9(VDDQ_4) U4100.D2(VDDQ_5) U4100.D9(VDD_2) U4100.E9(VDDQ_6) U4100.F1(VDDQ_7) U4100.G7(VDD_3) U4100.H2(VDDQ_8) U4100.H9(VDDQ_9) U4100.K2(VDD_4) U4100.K8(VDD_5) U4100.N1(VDD_6) U4100.N9(VDD_7) U4100.R1(VDD_8) U4100.R9(VDD_9) U4101.A1(VDDQ_1) U4101.A8(VDDQ_2) U4101.B2(VDD_1) U4101.C1(VDDQ_3) U4101.C9(VDDQ_4) U4101.D2(VDDQ_5) U4101.D9(VDD_2) U4101.E9(VDDQ_6) U4101.F1(VDDQ_7) U4101.G7(VDD_3) U4101.H2(VDDQ_8) U4101.H9(VDDQ_9) U4101.K2(VDD_4) U4101.K8(VDD_5) U4101.N1(VDD_6) U4101.N9(VDD_7) U4101.R1(VDD_8) U4101.R9(VDD_9) U4102.A1(VDDQ_1) U4102.A8(VDDQ_2) U4102.B2(VDD_1) U4102.C1(VDDQ_3) U4102.C9(VDDQ_4) U4102.D2(VDDQ_5) U4102.D9(VDD_2) U4102.E9(VDDQ_6) U4102.F1(VDDQ_7) U4102.G7(VDD_3) U4102.H2(VDDQ_8) U4102.H9(VDDQ_9) U4102.K2(VDD_4) U4102.K8(VDD_5) U4102.N1(VDD_6) U4102.N9(VDD_7) U4102.R1(VDD_8) U4102.R9(VDD_9) U4103.A1(VDDQ_1) U4103.A8(VDDQ_2) U4103.B2(VDD_1) U4103.C1(VDDQ_3) U4103.C9(VDDQ_4) U4103.D2(VDDQ_5) U4103.D9(VDD_2) U4103.E9(VDDQ_6) U4103.F1(VDDQ_7) U4103.G7(VDD_3) U4103.H2(VDDQ_8) U4103.H9(VDDQ_9) U4103.K2(VDD_4) U4103.K8(VDD_5) U4103.N1(VDD_6) U4103.N9(VDD_7) U4103.R1(VDD_8) U4103.R9(VDD_9) U4104.A1(VDDQ_1) U4104.A8(VDDQ_2) U4104.B2(VDD_1) U4104.C1(VDDQ_3) U4104.C9(VDDQ_4) U4104.D2(VDDQ_5) U4104.D9(VDD_2) U4104.E9(VDDQ_6) U4104.F1(VDDQ_7) U4104.G7(VDD_3) U4104.H2(VDDQ_8) U4104.H9(VDDQ_9) U4104.K2(VDD_4) U4104.K8(VDD_5) U4104.N1(VDD_6) U4104.N9(VDD_7) U4104.R1(VDD_8) U4104.R9(VDD_9) U4105.A1(VDDQ_1) U4105.A8(VDDQ_2) U4105.B2(VDD_1) U4105.C1(VDDQ_3) U4105.C9(VDDQ_4) U4105.D2(VDDQ_5) U4105.D9(VDD_2) U4105.E9(VDDQ_6) U4105.F1(VDDQ_7) U4105.G7(VDD_3) U4105.H2(VDDQ_8) U4105.H9(VDDQ_9) U4105.K2(VDD_4) U4105.K8(VDD_5) U4105.N1(VDD_6) U4105.N9(VDD_7) U4105.R1(VDD_8) U4105.R9(VDD_9) U4106.A1(VDDQ_1) U4106.A8(VDDQ_2) U4106.B2(VDD_1) U4106.C1(VDDQ_3) U4106.C9(VDDQ_4) U4106.D2(VDDQ_5) U4106.D9(VDD_2) U4106.E9(VDDQ_6) U4106.F1(VDDQ_7) U4106.G7(VDD_3) U4106.H2(VDDQ_8) U4106.H9(VDDQ_9) U4106.K2(VDD_4) U4106.K8(VDD_5) U4106.N1(VDD_6) U4106.N9(VDD_7) U4106.R1(VDD_8) U4106.R9(VDD_9) U4107.A1(VDDQ_1) U4107.A8(VDDQ_2) U4107.B2(VDD_1) U4107.C1(VDDQ_3) U4107.C9(VDDQ_4) U4107.D2(VDDQ_5) U4107.D9(VDD_2) U4107.E9(VDDQ_6) U4107.F1(VDDQ_7) U4107.G7(VDD_3) U4107.H2(VDDQ_8) U4107.H9(VDDQ_9) U4107.K2(VDD_4) U4107.K8(VDD_5) U4107.N1(VDD_6) U4107.N9(VDD_7) U4107.R1(VDD_8) U4107.R9(VDD_9) U4500.AM18(DDR_VDDQ_G_S41) U4500.AM25(DDR_VDDQ_G_S42) U4500.AM36(DDR_VDDQ_G_S43) U4500.AN18(DDR_VDDQ_G_S44) U4500.AN19(DDR_VDDQ_G_S45) U4500.AN27(DDRSFR_VDDQ_G_S4) U4500.AN35(DDR_VDDQ_G_S46) U4500.AN36(DDR_VDDQ_G_S47) U4500.AU18(DDR_VDDQ_G_S48) U4500.AU36(DDR_VDDQ_G_S49) U4500.AV10(DDR_VDDQ_G_S410) U4500.AV16(DDR_VDDQ_G_S411) U4500.AV38(DDR_VDDQ_G_S412) U4500.AV44(DDR_VDDQ_G_S413) U4500.AY10(DDR_VDDQ_G_S414) U4500.AY44(DDR_VDDQ_G_S415) U4500.BE1(DDR_VDDQ_G_S416) U4500.BE3(DDR_VDDQ_G_S417) U4500.BE51(DDR_VDDQ_G_S418) U4500.BE53(DDR_VDDQ_G_S419) U4500.BG3(DDR_VDDQ_G_S420) U4500.BG51(DDR_VDDQ_G_S421) U4500.BH4(DDR_VDDQ_G_S422) U4500.BH5(DDR_VDDQ_G_S424) U4500.BH49(DDR_VDDQ_G_S423) U4500.BH50(DDR_VDDQ_G_S425) U4500.BJ2(DDR_VDDQ_G_S426) U4500.BJ3(DDR_VDDQ_G_S427) U4500.BJ5(DDR_VDDQ_G_S429) U4500.BJ49(DDR_VDDQ_G_S428) U4500.BJ51(DDR_VDDQ_G_S430) U4500.BJ52(DDR_VDDQ_G_S431)
P3V3_CARD: C1301.1(A) C1302.1(A) C1303.1(A) C1304.1(A) C1306.1(A) CN1300.2(3P3VAUX1) CN1300.4(3P3VAUX2) CN1300.72(3P3VAUX3) CN1300.74(3P3VAUX4) Q1300.1(D) Q1300.2(D1) Q1300.5(D3) Q1300.6(D2) R1301.1(A) R1307.1(A)
P3V3_LDO: C4441.1(A) PAD6121.2 R323.1(A) R4442.2(B) R4445.1(A) R4446.1(A) R4639.2(B) R4642.2(B) R4834.1(A) R7000.1(A) U4441.6 U4702.10
P3V3_RTC: C4603.1(A) C4608.1(A) C6051.1(A) PAD4501.1 R704.2(B) R4580.2(B) R4581.2(B) R6055.1(A) U4500.B6(RTC_V3P3RTC_G51) U4500.C5(RTC_V3P3RTC_G52)
P3V3_TOUCHPAD: C4631.2(B) CN281.8 D282.1 Q281.2 R308.2(B) R309.2(B) R311.2(B) R4683.2(B) R4684.2(B) U4503.7
P3V3A: C1307.1(A) C3504.1(A) C3505.1(A) C7000.1(A) C7108.1(A) PAD7104.1 Q1300.4(S) R3966.2(B) R4584.2(B) R4586.2(B) R4641.1(A) R4644.1(A) R4652.2(B) R4656.2(B) R4661.2(B) R7125.1(A) R7245.2(B) R7246.2(B) U3500.5(VSB) U4703.5 U60600.17(IN_3P3A)
P3V3A_PRIME: C4602.1(A) C4604.1(A) C4607.1(A) C7001.1(A) R4835.1(A) R60001.2(B) U4500.B22(USB_V3P3A_G31) U4500.C23(USB_V3P3A_G32) U4500.D4(RTC_V3P3A_G51) U4500.E3(RTC_V3P3A_G52) U60600.18(O_3P3A)
P3V3AL: C3009.2(B) C7110.1(A) C7114.1(A) C7566.2(B) CN245.1 D3000.5 D4501.1(A2) L300.1(INA) PAD6100.2 R301.2(B) R316.1(A) R317.1(A) R318.1(A) R320.1(A) R321.1(A) R322.1(A) R334.1(A) R346.2(B) R390.2(B) R514.2(B) R2001.1(A) R2410.1(A) R6007.2(B) R6053.2(B) R7104.1(A) R7230.2(B) U7102.1 U7102.2 U7102.6 U7102.7
P3V3AL_EC: C305.1(A) L300.2(INB) U301.102(AVCC)
P3V3AL_PB: C9100.1(A) CN9100.1 R9121.2(B) R9123.2(B) R9124.2(B) U9150.1
P3V3AL_R: C300.1(A) C301.1(A) C302.1(A) C303.1(A) C313.1(A) R318.2(B) U301.19(VCC1) U301.46(VCC2) U301.76(VCC3) U301.115(VCC5)
P3V3S: C516.1(A) C517.1(A) C532.1(A) C900.1(A) C903.1(A) C3000.2(B) C3500.1(A) C3501.1(A) C3502.1(A) C3503.1(A) C4507.2(B) C7104.1(A) C7521.1(A) C7526.1(A) C7527.1(A) C7551.1(A) C7566.1(A) D901.1 PAD7101.1 Q281.3 Q3000.3 Q3152.1(G) R332.1(A) R350.2(B) R351.1(A) R504.2(B) R1301.2(B) R3000.1(A) R3006.1(A) R3007.1(A) R3016.1(A) R3068.1(A) R3511.2(B) R3513.2(B) R3515.2(B) R3516.1(A) R4561.2(B) R4562.2(B) R4578.1(A) R4643.2(B) R7109.1(A) U500.1(DVDD) U500.36(CPVDD) U900.4(3V3_IN) U3500.10(VDD1) U3500.19(VDD2) U3500.24(VDD3) U4502.7
P3V3S_CAM: C3014.1(A) CN3000.22 FUSE3004.2
P3V3S_CR: C902.1(A) C905.1(A) C906.1(A) CN901.4 D902.1 U900.5(CARD_3V3)
P3V3S_LVDS1: C3003.2(B) PAD3003.1 Q3000.2 R3004.1(A)
P3V3S_LVDS2: C3001.1(A) C3002.1(A) CN3000.1 CN3000.2 PAD3003.2
P5V0A: C2456.1(A) C2457.1(A) C7123.1(A) C7516.1(A) CN245.2 PAD2000.1 PAD6150.2 PAD60610.1 PAD60910.1 R6645.2(B) R6665.2(B) R6745.2(B) R6765.2(B) U2406.5 U7100.4 U7100.6 U7100.7 U7102.4
P5V0A_PBN: C9101.1(A) CN9100.2 R9122.2(B)
P5V0A_USB1: C2426.1(A) C2427.1(A) C2428.1(A) C2432.1(A) CN2401.1 D2409.5 U2406.1
P5V0A_USB2: C2002.1(A) C2003.1(A) C2005.1(A) CN2002.1 R2000.1(A) U2000.1
P5V0A_USB2_DB: C2007.1(A) C2460.1(A) C2461.1(A) C2462.1(A) CN2003.4 CN2403.1 D2410.5
P5V0A_USB_PW1: C2000.1(A) C2001.1(A) PAD2000.2 U2000.5
P5V0S: C519.1(A) C522.1(A) C3150.1(A) C7102.1(A) C7514.1(A) PAD7102.1 R29.1(A) R500.1(A) R513.1(A) R3060.2(B) R3069.1(A) U3151.3
P5V0S_AUDIO_AVDD: C504.1(A) C505.1(A) D501.1(A1) R500.2(B) U500.26(AVDD1)
P5V0S_HDMI_CRT: CN3150.18 D7152.2 R3152.1(A) R3153.1(A) TP3150.1 U3151.2
P5V0S_PVDD: C514.1(A) C515.1(A) C520.1(A) C521.1(A) R513.2(B) U500.41(PVDD1) U500.46(PVDD2)
P5VAUXON: D7000.3(A1) R4445.2(B) R7003.1(A) R7256.1(A) U4441.4
PVBAT: C3019.1(A) C3020.1(A) C6162.1(A) C6699.1(A) C7510.1(A) C7511.1(A) C7512.1(A) C7513.1(A) C7541.1(A) C7546.1(A) C7577.1(A) CN3000.29 CN3000.30 D6000.2(A2) L7601.2(INB) PAD6110.1 PAD6160.1 PAD6610.2 PAD6710.2 PAD60310.2 Q6012.5(D3) Q6012.6(D2) Q6012.7(D1) Q6012.8(D0) R4449.1(A) R6000.2
PVBAT_CPU: C6610.1(A) C6611.1(A) C6612.1(A) PAD6610.1 Q6610.2 Q6610.3 Q6610.4 R6660.1(A)
PVBAT_VGG: C6710.1(A) C6711.1(A) C6712.1(A) PAD6710.1 Q6710.2 Q6710.3 Q6710.4 R6760.1(A)
VCC0_SENSEN_R: R4618.1(A) U4500.AJ32(CORE_VSS0_SENSE)
VCC0_SENSEP_R: R4617.1(A) U4500.AG32(CORE_VCC0_SENSE)
VCC1_SENSEN_R: R4620.1(A) U4500.AF27(CORE_VSS1_SENSE)
VCC1_SENSEP_R: R4619.1(A) U4500.AD29(CORE_VCC1_SENSE)
VCC_POR#: R320.2(B) U301.85(EXT_RST#)
VCC_SENSEN: R4618.2(B) R4620.2(B) R4700.2(B) R6663.1(A)
VCC_SENSEP: R4617.2(B) R4619.2(B) R4698.2(B) R6666.1(A)
VDDQ_PG: Q7202.3 R7229.1(A) U4500.AV28(DDR3_DRAM_PWROK) U60300.8(PGOOD)
ACPRES: Q60002.2(G1) R323.2(B) U301.73(GPIO70) U6000.5(ACOK)
ACPRESENT: Q4506.2(G1) U301.14(GPIO34/CIRRXL)
AOAC_ON#: C1306.2(B) C1307.2(B) Q1300.3(G) R334.2(B) U301.104(GPIO80/VD_IN1)
BAT_OLED#: CN245.6 U301.62(GPIO13/C_PWM)
BAT_OLED#_PB: CN9100.6 D9129.4
BAT_WLED#: CN245.7 U301.81(GPIO66/G_PWM)
BAT_WLED#_PB: CN9100.7 D9129.3
BATT_IN: R6051.1(A) R6053.1(A) R6054.2(B) U301.99(GPIO92/AD2)
BBS: R4549.2(B) U4500.AH51(GPIO_SUS4)
BEEP: R520.2(B) U301.66(GPO33/H_PWM/VD1_EN#)
BTIFON: CN1300.54(RSRVD/W_DISABLE2*) U301.113(GPIO87/CIRRXM/SIN_CR)
CAM_PWR#: R3030.1(A) U301.80(GPIO41/F_WP#)
CARD_REF: R900.2(B) U900.1(RREF)
CLK_KBPCI: R4571.1(A) U301.2(LCLK/GPIOF5)
CLK_KBPCI_R: R4571.2(B) U4500.P2(MF_LPC_CLKOUT0)
CLK_PCI_DEBUG: C1305.1(A) CN1300.68(RSRVD6) R4572.1(A)
CLK_PCIE_WLAN_DN: CN1300.49(REFCLKN0) U4500.B18(CLK_DIFF_N_2)
CLK_PCIE_WLAN_DP: CN1300.47(REFCLKP0) U4500.C18(CLK_DIFF_P_2)
CLK_TPM: R3509.1(A) R4573.1(A)
CLKREQ_WLAN1V8#: Q1302.6(D1) R4640.1(A) U4500.AK14(PCIE_CLKREQ2B)
CLKREQ_WLAN#: CN1300.53(CLKEQ0*) Q1302.5(G2) R1307.2(B)
COREPWROK: Q7214.2(G1) R4843.2(B) R7243.2(B) U4500.G16(COREPWROK)
CPU_EDP_AUX_DN: C3010.1(A) U4500.K42(DDI1_AUXN)
CPU_EDP_AUX_DP: C3011.1(A) U4500.M42(DDI1_AUXP)
CPU_EDP_HPD#: Q3003.3(D) R3020.1(A) U4500.R51(HV_DDI1_HPD)
CPU_PROCHOT#: Q300.3(D) Q4505.3(D) R4576.1(A) U6600.2 U6700.2
CPU_PROCHOT#_R: Q4505.2(S) R4575.1(A) R4576.2(B) U4500.AD50(PROCHOT_B)
DDR3_M0_RCOMPPD: R4504.2(B) U4500.BA28(DDR3_M0_RCOMPPD)
DDR3_M1_RCOMPPD: R4505.2(B) U4500.BA26(DDR3_M1_RCOMPPD)
DDR3_VCCA_PWROK: Q7214.3(D2) R7247.1(A) U4500.AV26(DDR3_VCCA_PWROK)
DP_TX0_C_DN: C4612.2(B) U4500.H51(DDI1_TXN_0)
DP_TX0_C_DP: C4611.2(B) U4500.J51(DDI1_TXP_0)
DP_TX0_DN: C4612.1(A) CN3000.13
DP_TX0_DP: C4611.1(A) CN3000.14
DP_TX1_C_DN: C4614.2(B) U4500.K52(DDI1_TXN_1)
DP_TX1_C_DP: C4613.2(B) U4500.K51(DDI1_TXP_1)
DP_TX1_DN: C4614.1(A) CN3000.10
DP_TX1_DP: C4613.1(A) CN3000.11
DPTF_THERMAL_SEN: C351.1(A) R351.2(B) R352.1(A) U301.108(GPIO05/AD4)
EC_BKLTEN: R332.2(B) R3013.1(A) U301.107(GPIO97/DA3)
EC_MUTE#: U301.95(GPIO03/AD6) U500.47(PDB)
EC_PMU_BATLOW#: D4701.3(A1) R4661.1(A) U301.121(GPIO85/GA20)
EC_PW_ON#: Q7000.1(G) Q7120.1(G) R7100.1(A) R7104.2(B) U301.82(GPIO75/SPI_SCK)
EC_PWRSW#: D4700.3(A1) R346.1(A) U301.79(GPIO02/SPI_CS#)
EC_RSMRST#: D60000.1(A2) R333.1(A) R4814.1(A) U301.25(GPIO50/PSCLK3/TDO) U4500.F18(RSMRST_B) U4702.9
EC_SCI#: R4548.1(A) U301.22(GPIO45/E_PWM) U4500.AG51(GPIO_SUS6)
EC_SMB1_CLK: R322.2(B) R6052.1(A) U301.70(GPIO17/SCL1/N2TCK)
EC_SMB1_DATA: R321.2(B) R6050.1(A) U301.69(GPIO22/SDA1/N2TMS)
EC_SMB2_CLK: R317.2(B) U301.67(GPIO73/SCL2/N2TCK) U6000.9(SCL)
EC_SMB2_DATA: R316.2(B) U301.68(GPIO74/SDA2/N2TMS) U6000.8(SDA)
EC_SMI#: R4656.1(A) U301.9(GPIO65/SMI#)
EC_SPI_CLK: R342.1(A) U4702.2
EC_SPI_CS0#: R343.1(A) U4702.1
EC_SPI_R_CLK: R342.2(B) U301.92(F_SCK)
EC_SPI_R_CS0#: R343.2(B) U301.90(F_CS0#)
EC_SPI_SI_IO0: R341.2(B) U301.87(F_SDIO_F_SDIO0)
EC_SPI_SO_IO1: R340.2(B) U301.86(F_SDI_F_SDIO1)
EC_WAKE_SCI#_N: R4544.1(A) U4500.AD51(GPIO_SUS0)
EC_WLAN_PCIE_WAKE#: R1302.1(A) U301.74(GPIO71)
EDP_AUX_DN: C3010.2(B) CN3000.5 R3016.2(B)
EDP_AUX_DP: C3011.2(B) CN3000.4 R3017.1(A)
EDP_BKLTEN: C3007.1(A) CN3000.21 R20.1(A) R3013.2(B)
EDP_HPD_CN: CN3000.19 Q3003.1(G) R3021.1(A)
EN_1V05A: R7252.2(B) U60600.26(EN_1P05A)
EN_3V: R7003.2(B) U6100.13
EN_3VLDO: U6100.12
EN_5V: D7000.1(A2) Q7000.3(D) R7000.2(B) R7110.1(A) U6150.13
EN_5VLDO: R6150.1(A) R6151.2(B) R6167.1(A) U6150.12
EN_PVCORE: R6643.2(B) R7250.2(B)
EN_PVGG: C7203.1(A) R6743.2(B) R7204.2(B)
EN_VDDQ: C7207.1(A) R7208.2(B) U60300.6(S5)
EN_VTT: C7206.1(A) D7200.1(A2) R7207.2(B) U60300.5(S3)
FLASH_OVERRIDE: R4550.2(B) R4844.1(A) U301.111(GPIO83/SOUT_CR) U4500.AH52(GPIO_SUS5)
GPIO0_RCOMP: R4555.2(B) U4500.AH40(GPIO0_RCOMP)
GPS_32K_CLK: TP4536.1 U4500.C15(PMU_SUSCLK)
H_PROCHOT_EC: Q300.1(G) R324.1(A) U301.21(GPIO44/SCL4B/TDI)
HDA_BITCLK: C4652.1(A) R506.2(B) R4538.2(B)
HDA_R_BITCLK: C510.1(A) R506.1(A) U500.6(BIT-CLK)
HDA_R_SDIN0: R507.1(A) U500.8(SDATA-IN)
HDA_RST#: R4536.2(B) U500.11(RESETB)
HDA_SDIN0: R507.2(B) U4500.AD7(MF_HDA_SDI0)
HDA_SDOUT: R4539.2(B) U500.5(SDATA-OUT)
HDA_SYNC: R4537.2(B) U500.10(SYNC)
HDMI_CN_DDCCLK: CN3150.15 Q3150.3(D) R3152.2(B)
HDMI_CN_DDCDATA: CN3150.16 Q3151.3(D) R3153.2(B)
HDMI_DDC_CLK: Q3150.2(S) R3179.2(B) U4500.T51(HV_DDI2_DDC_SCL)
HDMI_DDC_DAT: Q3151.2(S) R3178.2(B) U4500.T52(HV_DDI2_DDC_SDA)
HDMI_DDC_HPD: Q3153.3(D) R3171.1(A) U4500.U51(HV_DDI2_HPD)
HDMI_HPD_CN: C3151.1(A) Q3153.1(G) R3150.1(A) R3154.1(A)
HDMI_TX0_C_DN: C3164.2(B) R3162.1(A) R3185.1(A)
HDMI_TX0_C_DP: C3165.2(B) R3161.1(A) R3184.1(A)
HDMI_TX0_DN: C3164.1(A) U4500.G42(DDI2_TXN_2)
HDMI_TX0_DP: C3165.1(A) U4500.F42(DDI2_TXP_2)
HDMI_TX0_R_DN: CN3150.9 R3169.1(A) R3185.2(B)
HDMI_TX0_R_DP: CN3150.7 R3169.2(B) R3184.2(B)
HDMI_TX1_C_DN: C3162.2(B) R3160.1(A) R3183.1(A)
HDMI_TX1_C_DP: C3163.2(B) R3159.1(A) R3182.1(A)
HDMI_TX1_DN: C3162.1(A) U4500.K40(DDI2_TXN_1)
HDMI_TX1_DP: C3163.1(A) U4500.J40(DDI2_TXP_1)
HDMI_TX1_R_DN: CN3150.6 R3168.1(A) R3183.2(B)
HDMI_TX1_R_DP: CN3150.4 R3168.2(B) R3182.2(B)
HDMI_TX2_C_DN: C3160.2(B) R3158.1(A) R3181.1(A)
HDMI_TX2_C_DP: C3161.2(B) R3157.1(A) R3180.1(A)
HDMI_TX2_DN: C3160.1(A) U4500.G40(DDI2_TXN_0)
HDMI_TX2_DP: C3161.1(A) U4500.F40(DDI2_TXP_0)
HDMI_TX2_R_DN: CN3150.3 R3167.1(A) R3181.2(B)
HDMI_TX2_R_DP: CN3150.1 R3167.2(B) R3180.2(B)
HDMI_TXC_C_DN: C3166.2(B) R3163.1(A) R3187.1(A)
HDMI_TXC_C_DP: C3167.2(B) R3164.1(A) R3186.1(A)
HDMI_TXC_R_DN: CN3150.12 R3170.1(A) R3187.2(B)
HDMI_TXC_R_DP: CN3150.10 R3170.2(B) R3186.2(B)
HDMI_TXCL_DN: C3166.1(A) U4500.F44(DDI2_TXN_3)
HDMI_TXCL_DP: C3167.1(A) U4500.D44(DDI2_TXP_3)
HP_L: C602.2(B) R605.1(A) U500.32(HP-OUT-L)
HP_R: C603.2(B) R604.1(A) U500.33(HP-OUT-R)
HPS: D600.1 D600.2 JACK600.5 R502.2(B)
HW_I_ADC: C6036.1(A) C6037.1(A) U301.97(GPIO90/AD0) U6000.7(IOUT)
I2CO_SCL: R284.1(A) R4683.1(A) U4503.8
I2CO_SCL_TP: CN281.6 D280.2 R282.2(B) R284.2(B)
I2CO_SDA: R283.1(A) R4684.1(A) U4503.1
I2CO_SDA_TP: CN281.7 D280.1 R281.2(B) R283.2(B)
ICLKICOMP: R4542.2(B) U4500.P20(ICLKICOMP)
ICLKRCOMP: R4541.2(B) U4500.N20(ICLKRCOMP)
IM_CLK_5: CN281.1 D281.2 R309.1(A) U301.72(GPIO37/PSCLK1)
IM_DAT_5: CN281.2 D281.1 R308.1(A) U301.71(GPIO35/PSDAT1)
INV_PWM_3: C3008.1(A) CN3000.20 Q3007.3(D) R3007.2(B)
INV_PWM_APU_1V8: R3025.1(A) U4500.P52(PANEL1_BKLTCTL)
KBRST#: R4635.2(B) R4649.1(A) U301.122(KBRST#/GPIO86)
LCM_BKLTEN_1V8: U301.96(GPIO04/AD5) U4500.P51(PANEL1_BKLTEN)
LCM_VDDEN: Q3001.5(G2) R3010.1(A) U301.100(GPIO93/AD3)
LCM_VDDEN_1V8: R4520.2(B) U301.98(GPIO91/AD1) U4500.R53(PANEL1_VDDEN)
LID_SW#_3: CN245.4 U301.94(GPIO07/AD7/VD_IN2)
LID_SW#_3_PB: C9150.1(A) CN9100.4 D9150.2 U9150.2
LINE1_L: C602.1(A) U500.22(LINE1-L)
LINE1_R: C603.1(A) U500.21(LINE1-R)
LINE1_REF_L: R606.1(A) U500.31(LINE1-VREFO-L)
LINE1_REF_R: R607.1(A) U500.30(LINE1-VREFO-R)
LPC_3S_AD<0>: CN1300.65(RESERVED_2ND_PERP1) R3506.1(A) U301.126(LAD0/GPIOF1) U4500.M3(MF_LPC_AD0)
LPC_3S_AD<1>: CN1300.67(RESERVED_2ND_PERN1) R3505.1(A) U301.127(LAD1/GPIOF2) U4500.M2(MF_LPC_AD1)
LPC_3S_AD<2>: CN1300.71(RSRVD7) R3504.1(A) U301.128(LAD2/GPIOF3) U4500.N3(MF_LPC_AD2)
LPC_3S_AD<3>: CN1300.73(RSRVD8) R3503.1(A) U301.1(LAD3/GPIOF4) U4500.N1(MF_LPC_AD3)
LPC_3S_FRAME#: CN1300.70(RESERVED) R3507.1(A) U301.3(LFRAME#/GPIOF6) U4500.P3(LPC_FRAMEB)
LPC_HVT_RCOMP: R4574.1(A) U4500.T4(LPC_HVT_RCOMP)
M_A_A<0>: R4126.2(B) U4100.N3(A0) U4101.N3(A0) U4102.N3(A0) U4103.N3(A0) U4500.BB47(DDR3_M0_MA_0)
M_A_A<1>: R4127.2(B) U4100.P7(A1) U4101.P7(A1) U4102.P7(A1) U4103.P7(A1) U4500.BC42(DDR3_M0_MA_1)
M_A_A<2>: R4129.2(B) U4100.P3(A2) U4101.P3(A2) U4102.P3(A2) U4103.P3(A2) U4500.BJ48(DDR3_M0_MA_2)
M_A_A<3>: R4128.2(B) U4100.N2(A3) U4101.N2(A3) U4102.N2(A3) U4103.N2(A3) U4500.BH47(DDR3_M0_MA_3)
M_A_A<4>: R4130.2(B) U4100.P8(A4) U4101.P8(A4) U4102.P8(A4) U4103.P8(A4) U4500.BD42(DDR3_M0_MA_4)
M_A_A<5>: R4131.2(B) U4100.P2(A5) U4101.P2(A5) U4102.P2(A5) U4103.P2(A5) U4500.BH48(DDR3_M0_MA_5)
M_A_A<6>: R4133.2(B) U4100.R8(A6) U4101.R8(A6) U4102.R8(A6) U4103.R8(A6) U4500.BB46(DDR3_M0_MA_6)
M_A_A<7>: R4132.2(B) U4100.R2(A7) U4101.R2(A7) U4102.R2(A7) U4103.R2(A7) U4500.BE46(DDR3_M0_MA_7)
M_A_A<8>: R4134.2(B) U4100.T8(A8) U4101.T8(A8) U4102.T8(A8) U4103.T8(A8) U4500.BD44(DDR3_M0_MA_8)
M_A_A<9>: R4135.2(B) U4100.R3(A9) U4101.R3(A9) U4102.R3(A9) U4103.R3(A9) U4500.BE52(DDR3_M0_MA_9)
M_A_A<10>: R4138.2(B) U4100.L7(A10/AP) U4101.L7(A10/AP) U4102.L7(A10/AP) U4103.L7(A10/AP) U4500.BJ45(DDR3_M0_MA_10)
M_A_A<11>: R4137.2(B) U4100.R7(A11) U4101.R7(A11) U4102.R7(A11) U4103.R7(A11) U4500.BB49(DDR3_M0_MA_11)
M_A_A<12>: R4136.2(B) U4100.N7(A12/B_C_) U4101.N7(A12/B_C_) U4102.N7(A12/B_C_) U4103.N7(A12/B_C_) U4500.BF48(DDR3_M0_MA_12)
M_A_A<13>: R4139.2(B) U4100.T3(A13) U4101.T3(A13) U4102.T3(A13) U4103.T3(A13) U4500.BF44(DDR3_M0_MA_13)
M_A_A<14>: R4140.2(B) U4100.T7(A14) U4101.T7(A14) U4102.T7(A14) U4103.T7(A14) U4500.BD47(DDR3_M0_MA_14)
M_A_A<15>: R4141.2(B) U4100.M7(NC_5/A15) U4101.M7(NC_5/A15) U4102.M7(NC_5/A15) U4103.M7(NC_5/A15) U4500.BD49(DDR3_M0_MA_15)
M_A_BS0: R4123.2(B) U4100.M2(BA0) U4101.M2(BA0) U4102.M2(BA0) U4103.M2(BA0) U4500.BH46(DDR3_M0_BS_0)
M_A_BS1: R4125.2(B) U4100.N8(BA1) U4101.N8(BA1) U4102.N8(BA1) U4103.N8(BA1) U4500.AY40(DDR3_M0_BS_1)
M_A_BS2: R4124.2(B) U4100.M3(BA2) U4101.M3(BA2) U4102.M3(BA2) U4103.M3(BA2) U4500.BF52(DDR3_M0_BS_2)
M_A_CAS#: R4120.2(B) U4100.K3(CAS*) U4101.K3(CAS*) U4102.K3(CAS*) U4103.K3(CAS*) U4500.BG45(DDR3_M0_CASB)
M_A_CKE0: R4116.2(B) U4100.K9(CKE0) U4101.K9(CKE0) U4102.K9(CKE0) U4103.K9(CKE0) U4500.BB44(DDR3_M0_CKE_0)
M_A_CKE1: R4118.2(B) U4100.J9(NC_2/CKE1) U4101.J9(NC_2/CKE1) U4102.J9(NC_2/CKE1) U4103.J9(NC_2/CKE1) U4500.AY42(DDR3_M0_CKE_1)
M_A_CLK0_DN: C4616.2(B) R4115.1(A) U4100.K7(CK*) U4101.K7(CK*) U4102.K7(CK*) U4103.K7(CK*) U4500.BF40(DDR3_M0_CKB_0)
M_A_CLK0_DP: C4616.1(A) R4114.1(A) U4100.J7(CK) U4101.J7(CK) U4102.J7(CK) U4103.J7(CK) U4500.BD40(DDR3_M0_CK_0)
M_A_CS#0: R4117.2(B) U4100.L2(CS0*) U4101.L2(CS0*) U4102.L2(CS0*) U4103.L2(CS0*) U4500.AY38(DDR3_M0_CSB_0)
M_A_CS#1: R4119.2(B) U4100.L1(NC_3/_C_S_1_) U4101.L1(NC_3/_C_S_1_) U4102.L1(NC_3/_C_S_1_) U4103.L1(NC_3/_C_S_1_) U4500.AU38(DDR3_M0_CSB_1)
M_A_DM<0>: U4100.D3(UDM) U4500.AP52(DDR3_M0_DM_0)
M_A_DM<1>: U4100.E7(LDM) U4500.AT48(DDR3_M0_DM_1)
M_A_DM<2>: U4101.E7(LDM) U4500.AP44(DDR3_M0_DM_2)
M_A_DM<3>: U4101.D3(UDM) U4500.BA53(DDR3_M0_DM_3)
M_A_DM<4>: U4103.D3(UDM) U4500.BG41(DDR3_M0_DM_4)
M_A_DM<5>: U4102.E7(LDM) U4500.AY36(DDR3_M0_DM_5)
M_A_DM<6>: U4103.E7(LDM) U4500.BD32(DDR3_M0_DM_6)
M_A_DM<7>: U4102.D3(UDM) U4500.BH30(DDR3_M0_DM_7)
M_A_DQ<0>: U4100.C8(DQ10) U4500.AK51(DDR3_M0_DQ_0)
M_A_DQ<1>: U4100.A7(DQ12) U4500.AL51(DDR3_M0_DQ_1)
M_A_DQ<2>: U4100.A2(DQ13) U4500.AT52(DDR3_M0_DQ_2)
M_A_DQ<3>: U4100.C2(DQ11) U4500.AR51(DDR3_M0_DQ_3)
M_A_DQ<4>: U4100.D7(DQ8) U4500.AL53(DDR3_M0_DQ_4)
M_A_DQ<5>: U4100.B8(DQ14) U4500.AK52(DDR3_M0_DQ_5)
M_A_DQ<6>: U4100.A3(DQ15) U4500.AR53(DDR3_M0_DQ_6)
M_A_DQ<7>: U4100.C3(DQ9) U4500.AP51(DDR3_M0_DQ_7)
M_A_DQ<8>: U4100.H8(DQL5) U4500.AP48(DDR3_M0_DQ_8)
M_A_DQ<9>: U4100.E3(DQL0) U4500.AT47(DDR3_M0_DQ_9)
M_A_DQ<10>: U4100.F2(DQL2) U4500.AY48(DDR3_M0_DQ_10)
M_A_DQ<11>: U4100.H3(DQL4) U4500.AV50(DDR3_M0_DQ_11)
M_A_DQ<12>: U4100.F8(DQL3) U4500.AP47(DDR3_M0_DQ_12)
M_A_DQ<13>: U4100.F7(DQL1) U4500.AT50(DDR3_M0_DQ_13)
M_A_DQ<14>: U4100.G2(DQL6) U4500.AY50(DDR3_M0_DQ_14)
M_A_DQ<15>: U4100.H7(DQL7) U4500.AV45(DDR3_M0_DQ_15)
M_A_DQ<16>: U4101.H7(DQL7) U4500.AT40(DDR3_M0_DQ_16)
M_A_DQ<17>: U4101.G2(DQL6) U4500.AP42(DDR3_M0_DQ_17)
M_A_DQ<18>: U4101.F8(DQL3) U4500.AT38(DDR3_M0_DQ_18)
M_A_DQ<19>: U4101.H8(DQL5) U4500.AP40(DDR3_M0_DQ_19)
M_A_DQ<20>: U4101.H3(DQL4) U4500.AT44(DDR3_M0_DQ_20)
M_A_DQ<21>: U4101.F2(DQL2) U4500.AV41(DDR3_M0_DQ_21)
M_A_DQ<22>: U4101.F7(DQL1) U4500.AP41(DDR3_M0_DQ_22)
M_A_DQ<23>: U4101.E3(DQL0) U4500.AV42(DDR3_M0_DQ_23)
M_A_DQ<24>: U4101.A2(DQ13) U4500.BD52(DDR3_M0_DQ_24)
M_A_DQ<25>: U4101.C8(DQ10) U4500.AV52(DDR3_M0_DQ_25)
M_A_DQ<26>: U4101.C2(DQ11) U4500.BC53(DDR3_M0_DQ_26)
M_A_DQ<27>: U4101.D7(DQ8) U4500.AV51(DDR3_M0_DQ_27)
M_A_DQ<28>: U4101.B8(DQ14) U4500.AW51(DDR3_M0_DQ_28)
M_A_DQ<29>: U4101.A3(DQ15) U4500.BC52(DDR3_M0_DQ_29)
M_A_DQ<30>: U4101.A7(DQ12) U4500.AW53(DDR3_M0_DQ_30)
M_A_DQ<31>: U4101.C3(DQ9) U4500.BB51(DDR3_M0_DQ_31)
M_A_DQ<32>: U4103.C8(DQ10) U4500.BG42(DDR3_M0_DQ_32)
M_A_DQ<33>: U4103.D7(DQ8) U4500.BG43(DDR3_M0_DQ_33)
M_A_DQ<34>: U4103.A2(DQ13) U4500.BG37(DDR3_M0_DQ_34)
M_A_DQ<35>: U4103.A3(DQ15) U4500.BJ37(DDR3_M0_DQ_35)
M_A_DQ<36>: U4103.B8(DQ14) U4500.BH42(DDR3_M0_DQ_36)
M_A_DQ<37>: U4103.A7(DQ12) U4500.BJ41(DDR3_M0_DQ_37)
M_A_DQ<38>: U4103.C2(DQ11) U4500.BH36(DDR3_M0_DQ_38)
M_A_DQ<39>: U4103.C3(DQ9) U4500.BH38(DDR3_M0_DQ_39)
M_A_DQ<40>: U4102.F8(DQL3) U4500.BC36(DDR3_M0_DQ_40)
M_A_DQ<41>: U4102.H8(DQL5) U4500.BA36(DDR3_M0_DQ_41)
M_A_DQ<42>: U4102.F2(DQL2) U4500.AU34(DDR3_M0_DQ_42)
M_A_DQ<43>: U4102.H3(DQL4) U4500.AU32(DDR3_M0_DQ_43)
M_A_DQ<44>: U4102.F7(DQL1) U4500.BF36(DDR3_M0_DQ_44)
M_A_DQ<45>: U4102.H7(DQL7) U4500.BD36(DDR3_M0_DQ_45)
M_A_DQ<46>: U4102.E3(DQL0) U4500.AV34(DDR3_M0_DQ_46)
M_A_DQ<47>: U4102.G2(DQL6) U4500.AV32(DDR3_M0_DQ_47)
M_A_DQ<48>: U4103.E3(DQL0) U4500.BF34(DDR3_M0_DQ_48)
M_A_DQ<49>: U4103.F7(DQL1) U4500.BC34(DDR3_M0_DQ_49)
M_A_DQ<50>: U4103.F8(DQL3) U4500.BA32(DDR3_M0_DQ_50)
M_A_DQ<51>: U4103.H3(DQL4) U4500.BD30(DDR3_M0_DQ_51)
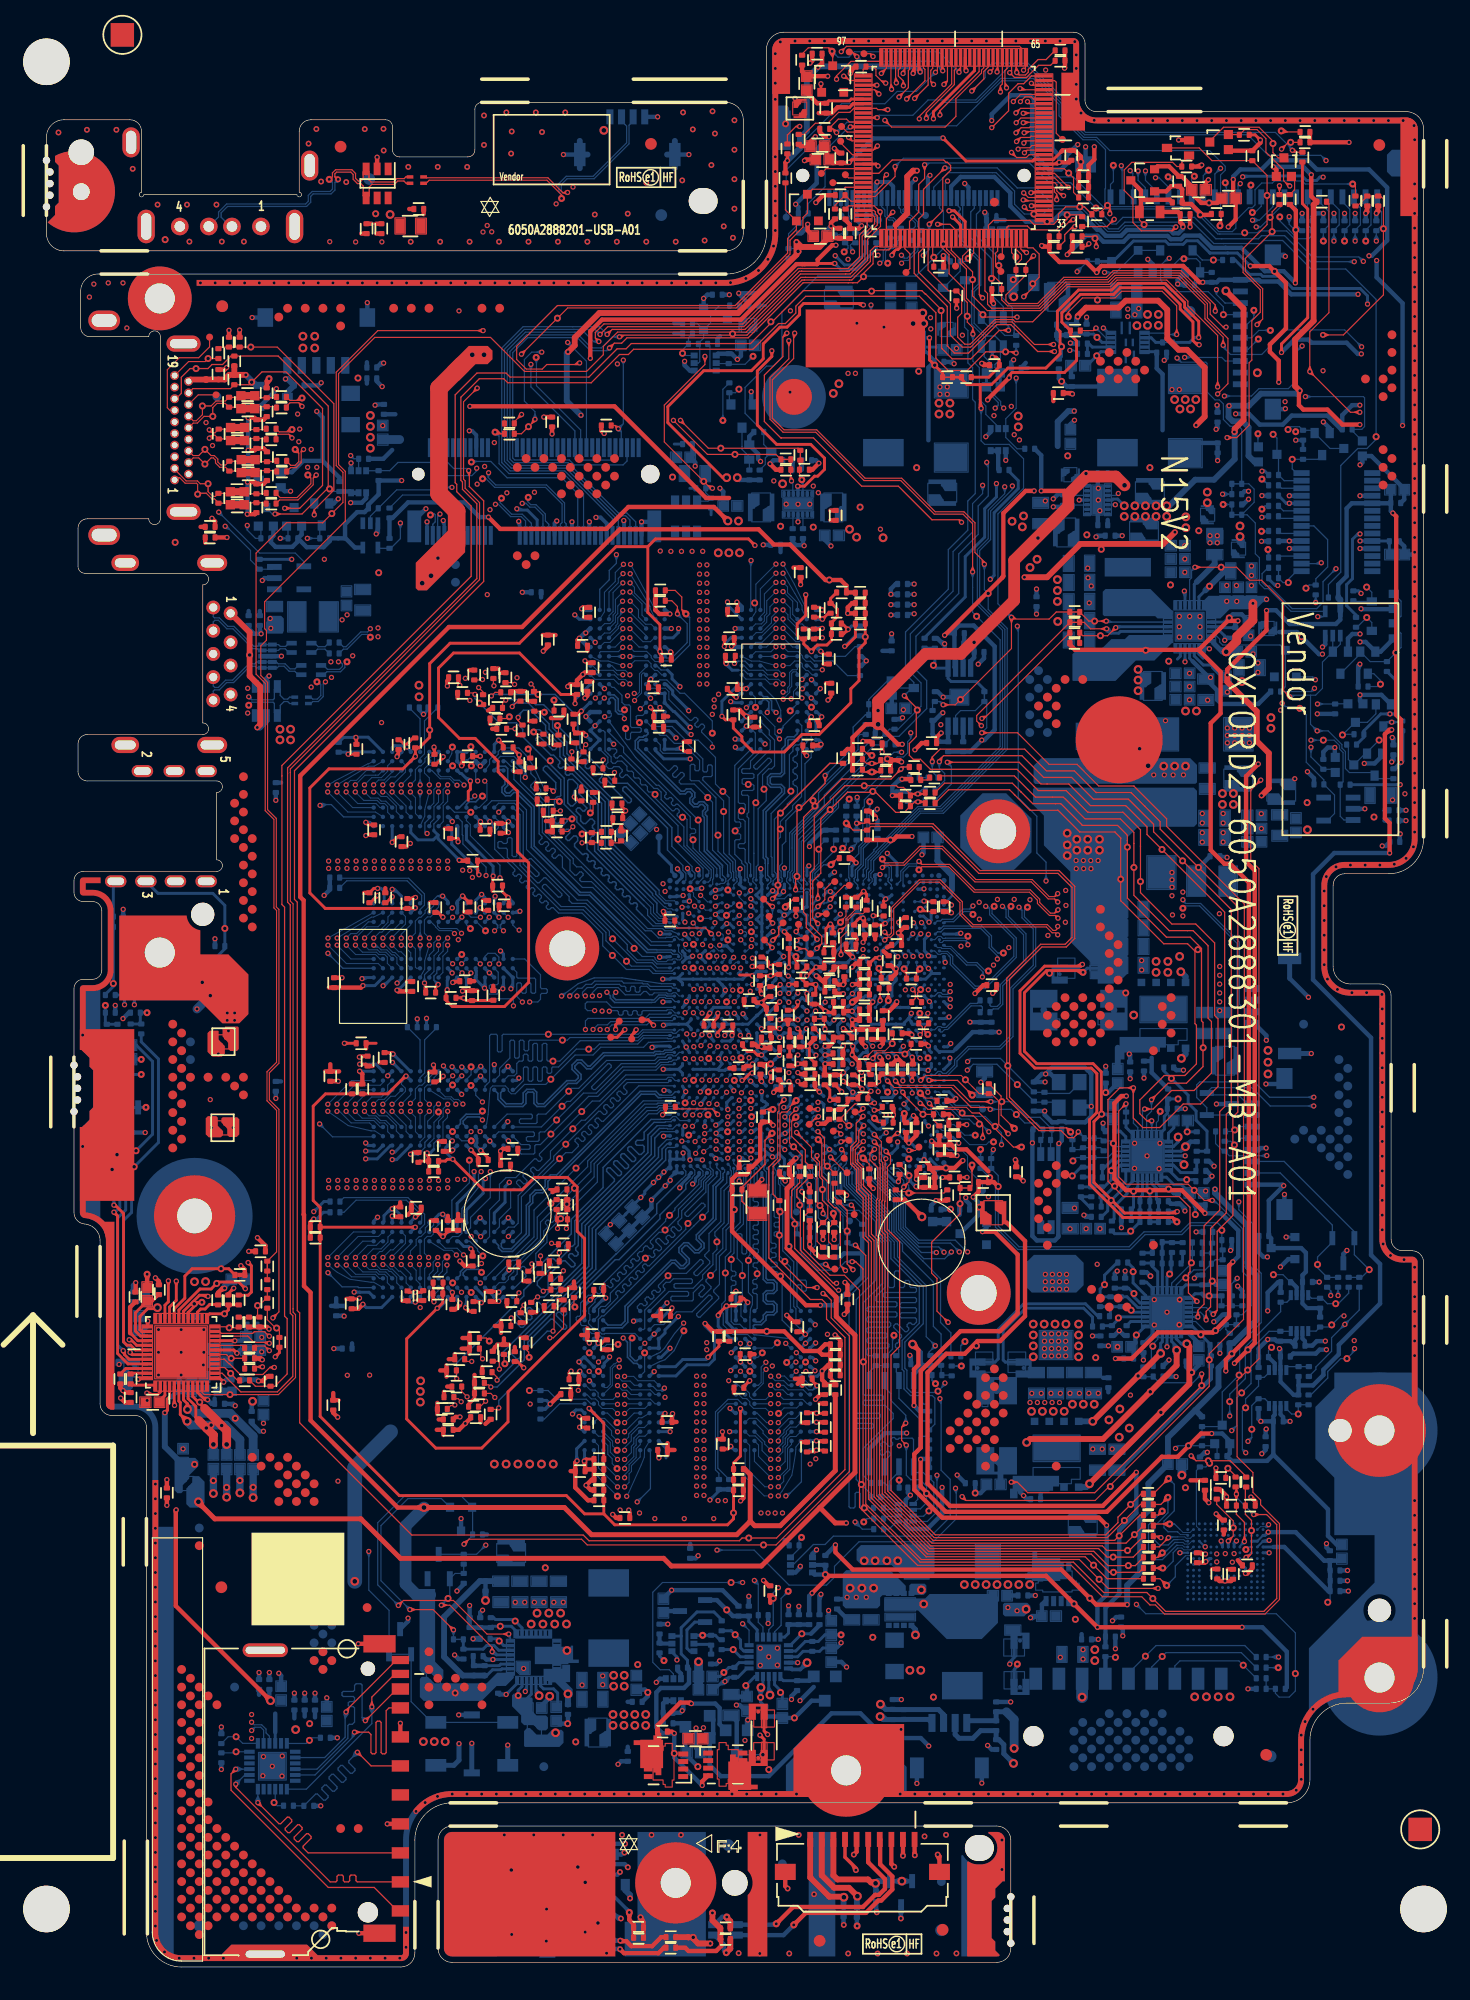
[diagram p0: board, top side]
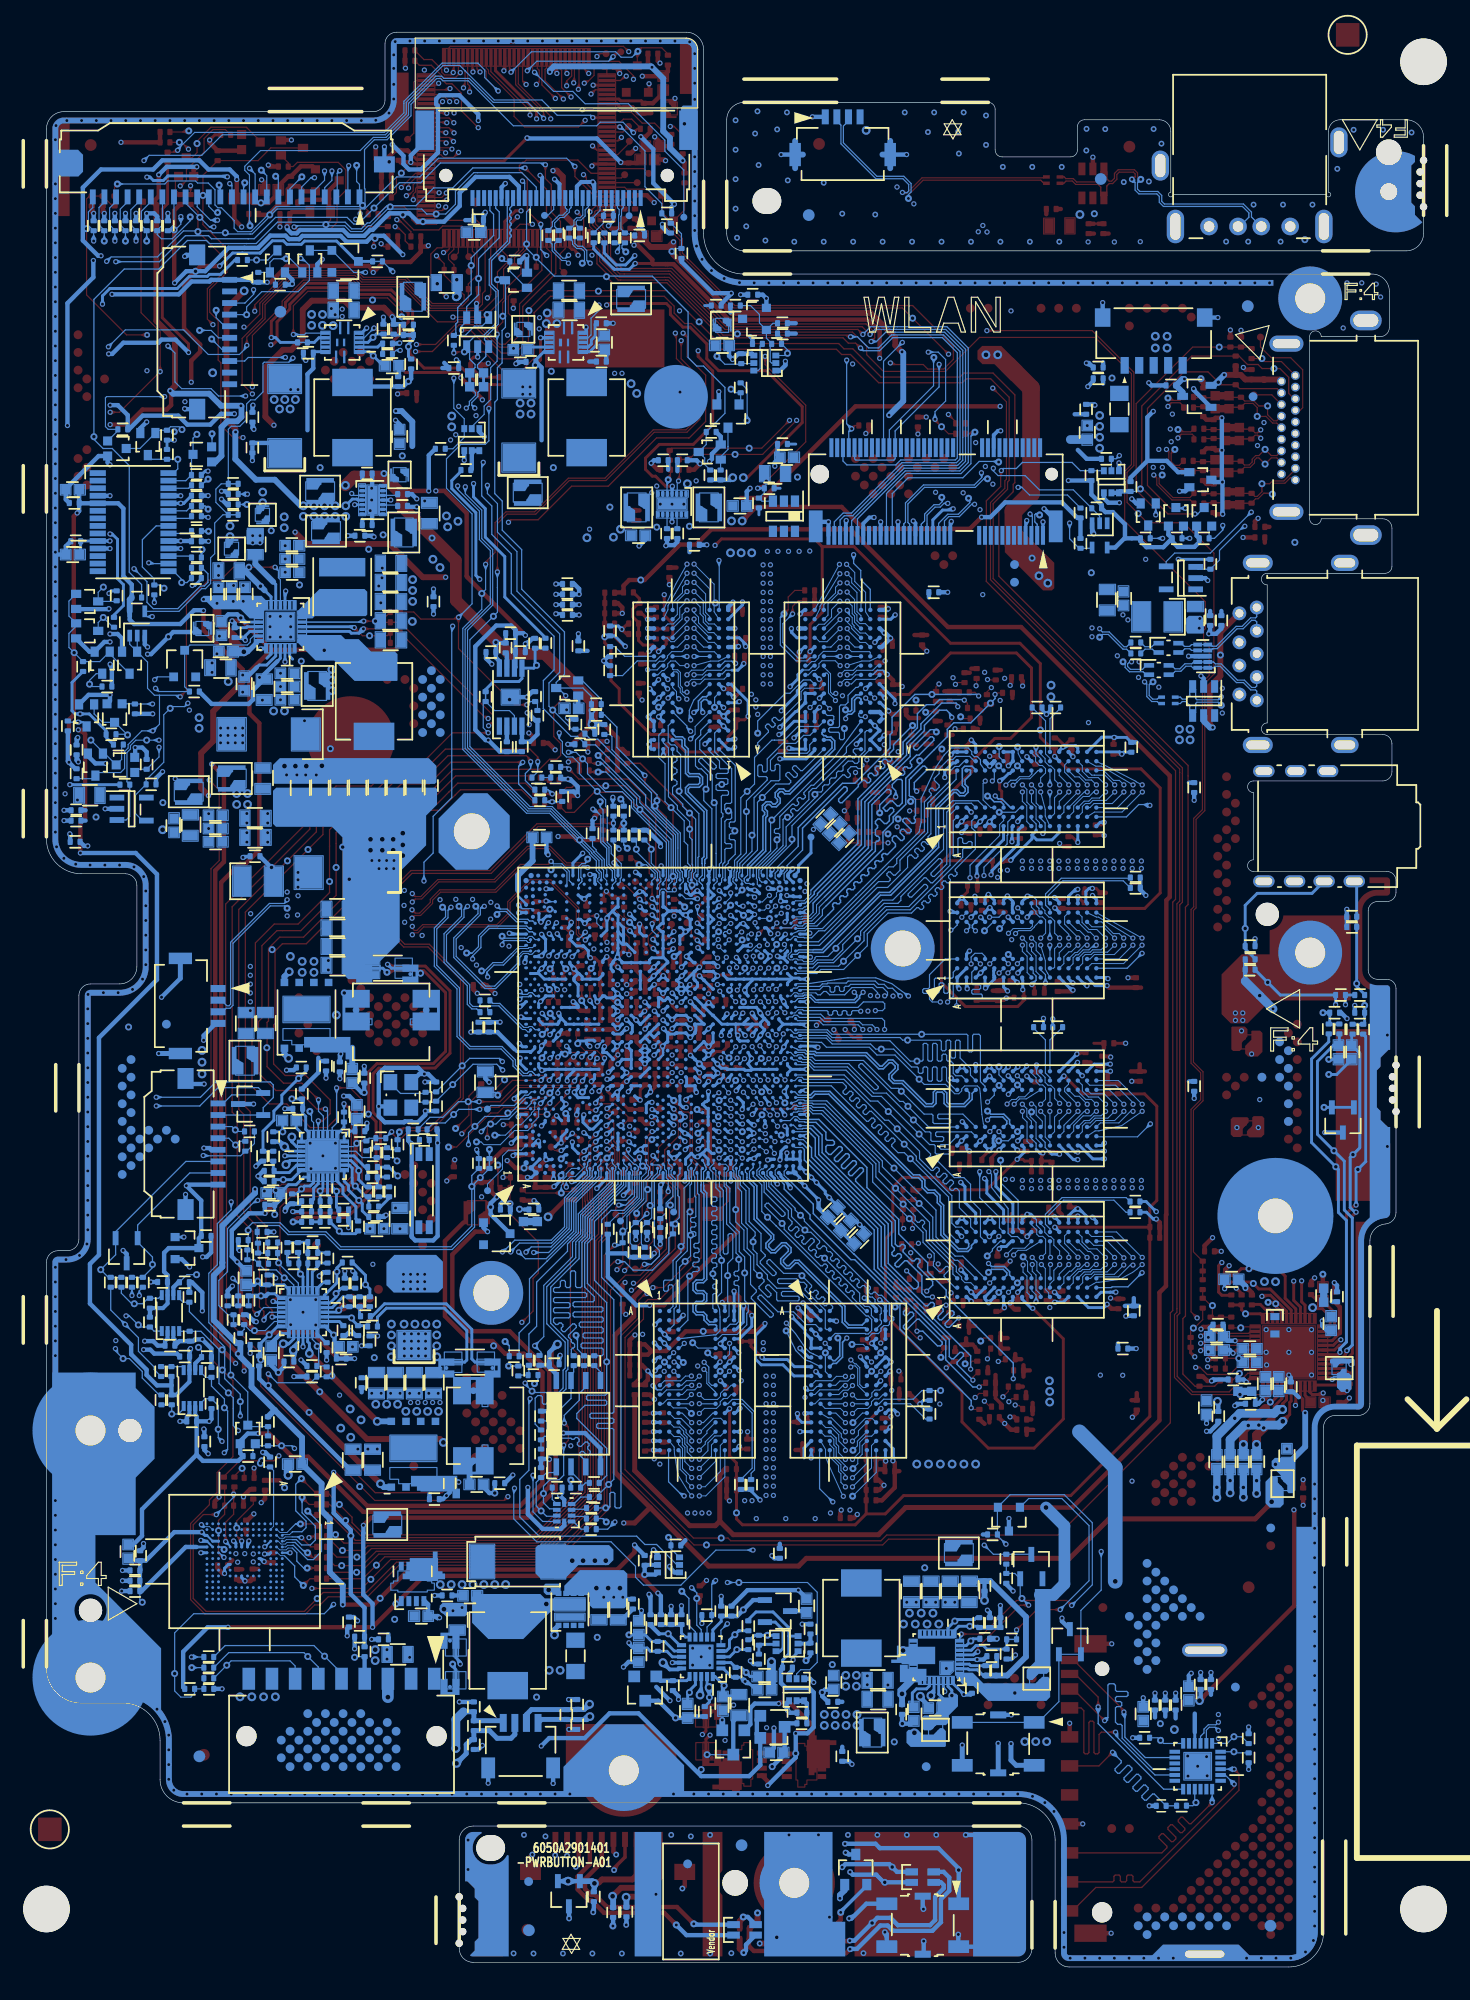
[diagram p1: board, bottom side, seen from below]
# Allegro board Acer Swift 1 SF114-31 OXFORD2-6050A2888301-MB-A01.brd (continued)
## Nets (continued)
M_A_DQ<52>: U4103.H7(DQL7) U4500.BD34(DDR3_M0_DQ_52)
M_A_DQ<53>: U4103.H8(DQL5) U4500.BA34(DDR3_M0_DQ_53)
M_A_DQ<54>: U4103.G2(DQL6) U4500.BF30(DDR3_M0_DQ_54)
M_A_DQ<55>: U4103.F2(DQL2) U4500.BD28(DDR3_M0_DQ_55)
M_A_DQ<56>: U4102.A7(DQ12) U4500.BJ33(DDR3_M0_DQ_56)
M_A_DQ<57>: U4102.A3(DQ15) U4500.BG29(DDR3_M0_DQ_57)
M_A_DQ<58>: U4102.D7(DQ8) U4500.BH34(DDR3_M0_DQ_58)
M_A_DQ<59>: U4102.B8(DQ14) U4500.BG32(DDR3_M0_DQ_59)
M_A_DQ<60>: U4102.C2(DQ11) U4500.BG28(DDR3_M0_DQ_60)
M_A_DQ<61>: U4102.C3(DQ9) U4500.BJ29(DDR3_M0_DQ_61)
M_A_DQ<62>: U4102.A2(DQ13) U4500.BH28(DDR3_M0_DQ_62)
M_A_DQ<63>: U4102.C8(DQ10) U4500.BG33(DDR3_M0_DQ_63)
M_A_DQS0_DN: U4100.B7(UDQS*) U4500.AM51(DDR3_M0_DQSB_0)
M_A_DQS0_DP: U4100.C7(UDQS) U4500.AM52(DDR3_M0_DQS_0)
M_A_DQS1_DN: U4100.G3(LDQS*) U4500.AV48(DDR3_M0_DQSB_1)
M_A_DQS1_DP: U4100.F3(LDQS) U4500.AV47(DDR3_M0_DQS_1)
M_A_DQS2_DN: U4101.G3(LDQS*) U4500.AT41(DDR3_M0_DQSB_2)
M_A_DQS2_DP: U4101.F3(LDQS) U4500.AT42(DDR3_M0_DQS_2)
M_A_DQS3_DN: U4101.B7(UDQS*) U4500.BA51(DDR3_M0_DQSB_3)
M_A_DQS3_DP: U4101.C7(UDQS) U4500.AY52(DDR3_M0_DQS_3)
M_A_DQS4_DN: U4103.B7(UDQS*) U4500.BG39(DDR3_M0_DQSB_4)
M_A_DQS4_DP: U4103.C7(UDQS) U4500.BH40(DDR3_M0_DQS_4)
M_A_DQS5_DN: U4102.G3(LDQS*) U4500.AT34(DDR3_M0_DQSB_5)
M_A_DQS5_DP: U4102.F3(LDQS) U4500.AT32(DDR3_M0_DQS_5)
M_A_DQS6_DN: U4103.G3(LDQS*) U4500.BC32(DDR3_M0_DQSB_6)
M_A_DQS6_DP: U4103.F3(LDQS) U4500.BC30(DDR3_M0_DQS_6)
M_A_DQS7_DN: U4102.B7(UDQS*) U4500.BG31(DDR3_M0_DQSB_7)
M_A_DQS7_DP: U4102.C7(UDQS) U4500.BH32(DDR3_M0_DQS_7)
M_A_OCAVREF: TP4500.1 U4500.AT28(DDR3_M0_OCAVREF)
M_A_ODQVREF: TP4501.1 U4500.AU28(DDR3_M0_ODQVREF)
M_A_ODT0: R4142.2(B) U4100.K1(ODT0) U4101.K1(ODT0) U4102.K1(ODT0) U4103.K1(ODT0) U4500.AV36(DDR3_M0_ODT_0)
M_A_ODT1: R4143.2(B) U4100.J1(NC_1/ODT1) U4101.J1(NC_1/ODT1) U4102.J1(NC_1/ODT1) U4103.J1(NC_1/ODT1) U4500.BA38(DDR3_M0_ODT_1)
M_A_RAS#: R4122.2(B) U4100.J3(RAS*) U4101.J3(RAS*) U4102.J3(RAS*) U4103.J3(RAS*) U4500.BA40(DDR3_M0_RASB)
M_A_WE#: R4121.2(B) U4100.L3(WE*) U4101.L3(WE*) U4102.L3(WE*) U4103.L3(WE*) U4500.BH44(DDR3_M0_WEB)
M_B_B<0>: R4156.2(B) U4104.N3(A0) U4105.N3(A0) U4106.N3(A0) U4107.N3(A0) U4500.BB7(DDR3_M1_MA_0)
M_B_B<1>: R4157.2(B) U4104.P7(A1) U4105.P7(A1) U4106.P7(A1) U4107.P7(A1) U4500.BC12(DDR3_M1_MA_1)
M_B_B<2>: R4159.2(B) U4104.P3(A2) U4105.P3(A2) U4106.P3(A2) U4107.P3(A2) U4500.BJ6(DDR3_M1_MA_2)
M_B_B<3>: R4158.2(B) U4104.N2(A3) U4105.N2(A3) U4106.N2(A3) U4107.N2(A3) U4500.BH7(DDR3_M1_MA_3)
M_B_B<4>: R4160.2(B) U4104.P8(A4) U4105.P8(A4) U4106.P8(A4) U4107.P8(A4) U4500.BD12(DDR3_M1_MA_4)
M_B_B<5>: R4161.2(B) U4104.P2(A5) U4105.P2(A5) U4106.P2(A5) U4107.P2(A5) U4500.BH6(DDR3_M1_MA_5)
M_B_B<6>: R4163.2(B) U4104.R8(A6) U4105.R8(A6) U4106.R8(A6) U4107.R8(A6) U4500.BB8(DDR3_M1_MA_6)
M_B_B<7>: R4162.2(B) U4104.R2(A7) U4105.R2(A7) U4106.R2(A7) U4107.R2(A7) U4500.BE8(DDR3_M1_MA_7)
M_B_B<8>: R4164.2(B) U4104.T8(A8) U4105.T8(A8) U4106.T8(A8) U4107.T8(A8) U4500.BD10(DDR3_M1_MA_8)
M_B_B<9>: R4165.2(B) U4104.R3(A9) U4105.R3(A9) U4106.R3(A9) U4107.R3(A9) U4500.BE2(DDR3_M1_MA_9)
M_B_B<10>: R4168.2(B) U4104.L7(A10/AP) U4105.L7(A10/AP) U4106.L7(A10/AP) U4107.L7(A10/AP) U4500.BJ9(DDR3_M1_MA_10)
M_B_B<11>: R4167.2(B) U4104.R7(A11) U4105.R7(A11) U4106.R7(A11) U4107.R7(A11) U4500.BB5(DDR3_M1_MA_11)
M_B_B<12>: R4166.2(B) U4104.N7(A12/B_C_) U4105.N7(A12/B_C_) U4106.N7(A12/B_C_) U4107.N7(A12/B_C_) U4500.BF6(DDR3_M1_MA_12)
M_B_B<13>: R4169.2(B) U4104.T3(A13) U4105.T3(A13) U4106.T3(A13) U4107.T3(A13) U4500.BF10(DDR3_M1_MA_13)
M_B_B<14>: R4170.2(B) U4104.T7(A14) U4105.T7(A14) U4106.T7(A14) U4107.T7(A14) U4500.BD7(DDR3_M1_MA_14)
M_B_B<15>: R4171.2(B) U4104.M7(NC_5/A15) U4105.M7(NC_5/A15) U4106.M7(NC_5/A15) U4107.M7(NC_5/A15) U4500.BD5(DDR3_M1_MA_15)
M_B_BS0: R4153.2(B) U4104.M2(BA0) U4105.M2(BA0) U4106.M2(BA0) U4107.M2(BA0) U4500.BH8(DDR3_M1_BS_0)
M_B_BS1: R4154.2(B) U4104.N8(BA1) U4105.N8(BA1) U4106.N8(BA1) U4107.N8(BA1) U4500.AY14(DDR3_M1_BS_1)
M_B_BS2: R4155.2(B) U4104.M3(BA2) U4105.M3(BA2) U4106.M3(BA2) U4107.M3(BA2) U4500.BF2(DDR3_M1_BS_2)
M_B_CAS_N: R4150.2(B) U4104.K3(CAS*) U4105.K3(CAS*) U4106.K3(CAS*) U4107.K3(CAS*) U4500.BG9(DDR3_M1_CASB)
M_B_CKE0: R4145.2(B) U4104.K9(CKE0) U4105.K9(CKE0) U4106.K9(CKE0) U4107.K9(CKE0) U4500.BB10(DDR3_M1_CKE_0)
M_B_CKE1: R4146.2(B) U4104.J9(NC_2/CKE1) U4105.J9(NC_2/CKE1) U4106.J9(NC_2/CKE1) U4107.J9(NC_2/CKE1) U4500.AY12(DDR3_M1_CKE_1)
M_B_CLK0_DN: C4623.2(B) R4186.1(A) U4104.K7(CK*) U4105.K7(CK*) U4106.K7(CK*) U4107.K7(CK*) U4500.BF14(DDR3_M1_CKB_0)
M_B_CLK0_DP: C4623.1(A) R4185.1(A) U4104.J7(CK) U4105.J7(CK) U4106.J7(CK) U4107.J7(CK) U4500.BD14(DDR3_M1_CK_0)
M_B_CS0_N: R4147.2(B) U4104.L2(CS0*) U4105.L2(CS0*) U4106.L2(CS0*) U4107.L2(CS0*) U4500.AY16(DDR3_M1_CSB_0)
M_B_CS1_N: R4148.2(B) U4104.L1(NC_3/_C_S_1_) U4105.L1(NC_3/_C_S_1_) U4106.L1(NC_3/_C_S_1_) U4107.L1(NC_3/_C_S_1_) U4500.AU16(DDR3_M1_CSB_1)
M_B_DM<0>: U4104.D3(UDM) U4500.AP2(DDR3_M1_DM_0)
M_B_DM<1>: U4105.E7(LDM) U4500.AT6(DDR3_M1_DM_1)
M_B_DM<2>: U4104.E7(LDM) U4500.AP10(DDR3_M1_DM_2)
M_B_DM<3>: U4105.D3(UDM) U4500.BA1(DDR3_M1_DM_3)
M_B_DM<4>: U4106.D3(UDM) U4500.BG13(DDR3_M1_DM_4)
M_B_DM<5>: U4107.E7(LDM) U4500.AY18(DDR3_M1_DM_5)
M_B_DM<6>: U4106.E7(LDM) U4500.BD22(DDR3_M1_DM_6)
M_B_DM<7>: U4107.D3(UDM) U4500.BH24(DDR3_M1_DM_7)
M_B_DQ<0>: U4104.A2(DQ13) U4500.AK3(DDR3_M1_DQ_0)
M_B_DQ<1>: U4104.A3(DQ15) U4500.AL3(DDR3_M1_DQ_1)
M_B_DQ<2>: U4104.C8(DQ10) U4500.AT2(DDR3_M1_DQ_2)
M_B_DQ<3>: U4104.D7(DQ8) U4500.AR3(DDR3_M1_DQ_3)
M_B_DQ<4>: U4104.C3(DQ9) U4500.AL1(DDR3_M1_DQ_4)
M_B_DQ<5>: U4104.C2(DQ11) U4500.AK2(DDR3_M1_DQ_5)
M_B_DQ<6>: U4104.B8(DQ14) U4500.AR1(DDR3_M1_DQ_6)
M_B_DQ<7>: U4104.A7(DQ12) U4500.AP3(DDR3_M1_DQ_7)
M_B_DQ<8>: U4105.F2(DQL2) U4500.AP6(DDR3_M1_DQ_8)
M_B_DQ<9>: U4105.E3(DQL0) U4500.AT7(DDR3_M1_DQ_9)
M_B_DQ<10>: U4105.F8(DQL3) U4500.AY6(DDR3_M1_DQ_10)
M_B_DQ<11>: U4105.H7(DQL7) U4500.AV4(DDR3_M1_DQ_11)
M_B_DQ<12>: U4105.G2(DQL6) U4500.AP7(DDR3_M1_DQ_12)
M_B_DQ<13>: U4105.H3(DQL4) U4500.AT4(DDR3_M1_DQ_13)
M_B_DQ<14>: U4105.H8(DQL5) U4500.AY4(DDR3_M1_DQ_14)
M_B_DQ<15>: U4105.F7(DQL1) U4500.AV9(DDR3_M1_DQ_15)
M_B_DQ<16>: U4104.H3(DQL4) U4500.AT14(DDR3_M1_DQ_16)
M_B_DQ<17>: U4104.E3(DQL0) U4500.AP12(DDR3_M1_DQ_17)
M_B_DQ<18>: U4104.H8(DQL5) U4500.AT16(DDR3_M1_DQ_18)
M_B_DQ<19>: U4104.G2(DQL6) U4500.AP14(DDR3_M1_DQ_19)
M_B_DQ<20>: U4104.F7(DQL1) U4500.AT10(DDR3_M1_DQ_20)
M_B_DQ<21>: U4104.H7(DQL7) U4500.AV13(DDR3_M1_DQ_21)
M_B_DQ<22>: U4104.F2(DQL2) U4500.AP13(DDR3_M1_DQ_22)
M_B_DQ<23>: U4104.F8(DQL3) U4500.AV12(DDR3_M1_DQ_23)
M_B_DQ<24>: U4105.D7(DQ8) U4500.BD2(DDR3_M1_DQ_24)
M_B_DQ<25>: U4105.A2(DQ13) U4500.AV2(DDR3_M1_DQ_25)
M_B_DQ<26>: U4105.C8(DQ10) U4500.BC1(DDR3_M1_DQ_26)
M_B_DQ<27>: U4105.C2(DQ11) U4500.AV3(DDR3_M1_DQ_27)
M_B_DQ<28>: U4105.C3(DQ9) U4500.AW3(DDR3_M1_DQ_28)
M_B_DQ<29>: U4105.B8(DQ14) U4500.BC2(DDR3_M1_DQ_29)
M_B_DQ<30>: U4105.A3(DQ15) U4500.AW1(DDR3_M1_DQ_30)
M_B_DQ<31>: U4105.A7(DQ12) U4500.BB3(DDR3_M1_DQ_31)
M_B_DQ<32>: U4106.C2(DQ11) U4500.BG12(DDR3_M1_DQ_32)
M_B_DQ<33>: U4106.A2(DQ13) U4500.BG11(DDR3_M1_DQ_33)
M_B_DQ<34>: U4106.C8(DQ10) U4500.BG17(DDR3_M1_DQ_34)
M_B_DQ<35>: U4106.B8(DQ14) U4500.BJ17(DDR3_M1_DQ_35)
M_B_DQ<36>: U4106.A3(DQ15) U4500.BH12(DDR3_M1_DQ_36)
M_B_DQ<37>: U4106.C3(DQ9) U4500.BJ13(DDR3_M1_DQ_37)
M_B_DQ<38>: U4106.D7(DQ8) U4500.BH18(DDR3_M1_DQ_38)
M_B_DQ<39>: U4106.A7(DQ12) U4500.BH16(DDR3_M1_DQ_39)
M_B_DQ<40>: U4107.F2(DQL2) U4500.BC18(DDR3_M1_DQ_40)
M_B_DQ<41>: U4107.G2(DQL6) U4500.BA18(DDR3_M1_DQ_41)
M_B_DQ<42>: U4107.F7(DQL1) U4500.AU20(DDR3_M1_DQ_42)
M_B_DQ<43>: U4107.F8(DQL3) U4500.AU22(DDR3_M1_DQ_43)
M_B_DQ<44>: U4107.H3(DQL4) U4500.BF18(DDR3_M1_DQ_44)
M_B_DQ<45>: U4107.E3(DQL0) U4500.BD18(DDR3_M1_DQ_45)
M_B_DQ<46>: U4107.H7(DQL7) U4500.AV20(DDR3_M1_DQ_46)
M_B_DQ<47>: U4107.H8(DQL5) U4500.AV22(DDR3_M1_DQ_47)
M_B_DQ<48>: U4106.F7(DQL1) U4500.BF20(DDR3_M1_DQ_48)
M_B_DQ<49>: U4106.E3(DQL0) U4500.BC20(DDR3_M1_DQ_49)
M_B_DQ<50>: U4106.F2(DQL2) U4500.BA22(DDR3_M1_DQ_50)
M_B_DQ<51>: U4106.F8(DQL3) U4500.BD24(DDR3_M1_DQ_51)
M_B_DQ<52>: U4106.H3(DQL4) U4500.BD20(DDR3_M1_DQ_52)
M_B_DQ<53>: U4106.G2(DQL6) U4500.BA20(DDR3_M1_DQ_53)
M_B_DQ<54>: U4106.H8(DQL5) U4500.BF24(DDR3_M1_DQ_54)
M_B_DQ<55>: U4106.H7(DQL7) U4500.BD26(DDR3_M1_DQ_55)
M_B_DQ<56>: U4107.A3(DQ15) U4500.BJ21(DDR3_M1_DQ_56)
M_B_DQ<57>: U4107.A7(DQ12) U4500.BG25(DDR3_M1_DQ_57)
M_B_DQ<58>: U4107.A2(DQ13) U4500.BH20(DDR3_M1_DQ_58)
M_B_DQ<59>: U4107.C3(DQ9) U4500.BG22(DDR3_M1_DQ_59)
M_B_DQ<60>: U4107.C8(DQ10) U4500.BG26(DDR3_M1_DQ_60)
M_B_DQ<61>: U4107.B8(DQ14) U4500.BJ25(DDR3_M1_DQ_61)
M_B_DQ<62>: U4107.D7(DQ8) U4500.BH26(DDR3_M1_DQ_62)
M_B_DQ<63>: U4107.C2(DQ11) U4500.BG21(DDR3_M1_DQ_63)
M_B_DQS0_DN: U4104.B7(UDQS*) U4500.AM3(DDR3_M1_DQSB_0)
M_B_DQS0_DP: U4104.C7(UDQS) U4500.AM2(DDR3_M1_DQS_0)
M_B_DQS1_DN: U4105.G3(LDQS*) U4500.AV6(DDR3_M1_DQSB_1)
M_B_DQS1_DP: U4105.F3(LDQS) U4500.AV7(DDR3_M1_DQS_1)
M_B_DQS2_DN: U4104.G3(LDQS*) U4500.AT13(DDR3_M1_DQSB_2)
M_B_DQS2_DP: U4104.F3(LDQS) U4500.AT12(DDR3_M1_DQS_2)
M_B_DQS3_DN: U4105.B7(UDQS*) U4500.BA3(DDR3_M1_DQSB_3)
M_B_DQS3_DP: U4105.C7(UDQS) U4500.AY2(DDR3_M1_DQS_3)
M_B_DQS4_DN: U4106.B7(UDQS*) U4500.BG15(DDR3_M1_DQSB_4)
M_B_DQS4_DP: U4106.C7(UDQS) U4500.BH14(DDR3_M1_DQS_4)
M_B_DQS5_DN: U4107.G3(LDQS*) U4500.AT20(DDR3_M1_DQSB_5)
M_B_DQS5_DP: U4107.F3(LDQS) U4500.AT22(DDR3_M1_DQS_5)
M_B_DQS6_DN: U4106.G3(LDQS*) U4500.BC22(DDR3_M1_DQSB_6)
M_B_DQS6_DP: U4106.F3(LDQS) U4500.BC24(DDR3_M1_DQS_6)
M_B_DQS7_DN: U4107.B7(UDQS*) U4500.BG23(DDR3_M1_DQSB_7)
M_B_DQS7_DP: U4107.C7(UDQS) U4500.BH22(DDR3_M1_DQS_7)
M_B_OCAVREF: TP4502.1 U4500.AT26(DDR3_M1_OCAVREF)
M_B_ODQVREF: TP4503.1 U4500.AU26(DDR3_M1_ODQVREF)
M_B_ODT0: R4184.2(B) U4104.K1(ODT0) U4105.K1(ODT0) U4106.K1(ODT0) U4107.K1(ODT0) U4500.AV18(DDR3_M1_ODT_0)
M_B_ODT1: R4183.2(B) U4104.J1(NC_1/ODT1) U4105.J1(NC_1/ODT1) U4106.J1(NC_1/ODT1) U4107.J1(NC_1/ODT1) U4500.BA16(DDR3_M1_ODT_1)
M_B_RAS_N: R4152.2(B) U4104.J3(RAS*) U4105.J3(RAS*) U4106.J3(RAS*) U4107.J3(RAS*) U4500.BA14(DDR3_M1_RASB)
M_B_WE_N: R4149.2(B) U4104.L3(WE*) U4105.L3(WE*) U4106.L3(WE*) U4107.L3(WE*) U4500.BH10(DDR3_M1_WEB)
MEM_RST0#: C4617.1(A) U4100.T2(RESET*) U4101.T2(RESET*) U4102.T2(RESET*) U4103.T2(RESET*) U4500.BA42(DDR3_M0_DRAMRSTB)
MEM_RST1_N: C4610.1(A) U4104.T2(RESET*) U4105.T2(RESET*) U4106.T2(RESET*) U4107.T2(RESET*) U4500.BA12(DDR3_M1_DRAMRSTB)
MIC: C605.1(A) JACK600.3 R602.1(A)
MIC2_REF: R600.2(B) R601.2(B) U500.29(MIC2-VREFO)
MIC_IN_CLK: C18.1(A) CN3000.26 D3000.3 R512.1(A)
MIC_IN_CLK_R: R512.2(B) U500.3(GPIO1/DMIC-CLK)
MIC_IN_DATA: R3011.1(A) U500.2(GPIO0/DMIC-DATA)
MIC_IN_DATA_R: CN3000.27 D3000.1 R3011.2(B)
MMC1_CLK: R3955.2(B) U4500.M7(SDMMC1_CLK)
MMC1_CLK_R: C3960.1(A) R3955.1(A) U3950.M6(CLK)
MMC1_CMD: R3962.1(A) U4500.P6(SDMMC1_CMD)
MMC1_CMD_R: R3962.2(B) U3950.M5(CMD)
MMC1_D0: R4665.1(A) U4500.M6(SDMMC1_D0)
MMC1_D0_R: R4665.2(B) U3950.A3(DAT0)
MMC1_D1: R4666.1(A) U4500.M4(SDMMC1_D1)
MMC1_D1_R: R4666.2(B) U3950.A4(DAT1)
MMC1_D2: R4667.1(A) U4500.P9(SDMMC1_D2)
MMC1_D2_R: R4667.2(B) U3950.A5(DAT2)
MMC1_D3: R4668.1(A) U4500.P7(SDMMC1_D3_CD_B)
MMC1_D3_R: R4668.2(B) U3950.B2(DAT3)
MMC1_D4: R4669.1(A) U4500.T6(MMC1_D4_SD_WE)
MMC1_D4_R: R4669.2(B) U3950.B3(DAT4)
MMC1_D5: R4672.1(A) U4500.T7(MMC1_D5)
MMC1_D5_R: R4672.2(B) U3950.B4(DAT5)
MMC1_D6: R4673.1(A) U4500.T10(MMC1_D6)
MMC1_D6_R: R4673.2(B) U3950.B5(DAT6)
MMC1_D7: R4674.1(A) U4500.T12(MMC1_D7)
MMC1_D7_R: R4674.2(B) U3950.B6(DAT7)
MMC1_RCLK: TP4531.1 U4500.T13(MMC1_RCLK)
MMC1_RST#: C3958.1(A) R3963.2(B) R4540.2(B) U3950.K5(RST*)
MOIC_RSMRST: D60000.3(A1) R4814.2(B) R60001.1(A) U60600.13(RSMRST)
MUX_GPIO_SUS1: R4551.1(A) U4500.AD52(GPIO_SUS1)
MUX_GPIO_SUS2: R4547.2(B) U4500.AH50(GPIO_SUS2)
MUX_GPIO_SUS3: R4693.1(A) U4500.AH48(GPIO_SUS3)
MUX_GPIO_SUS8: R4554.1(A) R4851.1(A) U4500.AF51(SEC_GPIO_SUS8)
MUX_GPIO_SUS9: R4553.1(A) R4849.2(B) U4500.AF52(SEC_GPIO_SUS9)
MUX_GPIO_SUS11: R4533.2(B) U4500.AC51(SEC_GPIO_SUS11)
NB671LGQ_LP#: R6198.2(B) U6150.3
PCH_SPI_CLK: R4631.1(A) U4500.W3(FST_SPI_CLK)
PCH_SPI_CS0#: R4807.1(A) U4500.V4(FST_SPI_CS0_B)
PCH_SPI_IO2: R4805.2(B) U4500.U1(FST_SPI_D2)
PCH_SPI_IO3: R4806.2(B) U4500.U3(FST_SPI_D3)
PCH_SPI_SI: R4633.2(B) U4500.V2(FST_SPI_D0)
PCH_SPI_SO: R4648.2(B) U4500.V3(FST_SPI_D1)
PCI_3S_CLKRUN#: R3510.1(A) U301.8(GPIO11/CLKRUN#) U4500.T3(LPC_CLKRUNB)
PCI_3S_SERIRQ: D7503.2 Q3500.2(S) R4660.2(B) U301.125(SERIRQ/GPIOF0) U4500.T2(ILB_SERIRQ)
PCI_SERR#: R4534.1(A) U4500.AA1(I2C6_SCL)
PCIE_OBSN: R4522.1(A) U4500.F26(PCIE_OBSN)
PCIE_OBSP: R4522.2(B) U4500.D26(PCIE_OBSP)
PCIE_WAKE#: Q4513.3(D) R325.1(A) R1306.2(B) R4637.2(B) R4652.1(A)
PCIE_WLAN_RX_DN: CN1300.43(PERN0) U4500.F22(PCIE_RXN2)
PCIE_WLAN_RX_DP: CN1300.41(PERP0) U4500.D22(PCIE_RXP2)
PCIE_WLAN_TX_C_DN: C4505.2(B) CN1300.37(PETN0)
PCIE_WLAN_TX_C_DP: C4504.2(B) CN1300.35(PETP0)
PCIE_WLAN_TX_DN: C4505.1(A) U4500.C26(PCIE_TXN2)
PCIE_WLAN_TX_DP: C4504.1(A) U4500.B26(PCIE_TXP2)
PCSPKR: R521.2(B) U4500.H4(SPKR)
PCU_SMB_CLK: R4560.2(B) U4500.AM6(MF_SMB_CLK) U4502.5
PCU_SMB_DATA: R4583.2(B) U4500.AM7(MF_SMB_DATA) U4502.4
PLT_RST#: CN1300.52(PERSTO*) CN1300.66(RSRVD5) R4584.1(A) U301.7(LRESET#/GPIOF7) U3500.16(L_R_E_S_E_T_/S_P_I___R_S_T/_S_R_E_S_E_T) U4504.4(OUT-Y)
PLT_RST_1V8#: R4628.1(A) U4500.F14(PMU_PLTRST_B) U4504.2(IN-A)
PMU_AC_PRESENT: Q4506.3(D2) R4587.1(A) U4500.C13(PMU_AC_PRESENT)
PMU_BATLOW#: D4701.1(A2) R4659.1(A) U4500.C14(PMU_BATLOW_B)
PMU_PCIE_WAKE#: Q4513.2(S) R4637.1(A) R4655.1(A) U4500.N16(PMU_WAKE_B)
PMU_RSTBTN#: C4515.1(A) R4625.2(B) U4500.AF2(PMU_RESETBUTTON_B)
PMU_STAT_1V8#: Q3501.1(G) R3514.1(A) U4500.D14(SUS_STAT_B)
PVADPTR: C6030.1(A) D6000.1(A1) L7600.2(INB) Q6010.5(D3) Q6010.6(D2) Q6010.7(D1) Q6010.8(D0) R6002.2(B) R60021.1(A)
PVCORE: C4516.1(A) C4517.1(A) C4518.1(A) C4519.1(A) C4520.1(A) C4521.1(A) C4522.1(A) C4523.1(A) C4524.1(A) C4609.1(A) C6600.1(A) C6601.1(A) C6602.1(A) C6603.1(A) C6604.1(A) C6605.1(A) C6606.1(A) C6607.1(A) C6608.1(A) C6609.1(A) C7515.1(A) C7551.2(B) C7552.1(A) D4500.1 R4698.1(A) R6610.2 U4500.AF29(CORE_VCC1_S0IX1) U4500.AF30(CORE_VCC1_S0IX2) U4500.AF36(CORE_VCC1_S0IX3) U4500.AG27(CORE_VCC1_S0IX4) U4500.AG29(CORE_VCC1_S0IX5) U4500.AG30(CORE_VCC1_S0IX6) U4500.AG33(CORE_VCC1_S0IX7) U4500.AG35(CORE_VCC1_S0IX8) U4500.AG36(CORE_VCC1_S0IX9) U4500.AG38(CORE_VCC1_S0IX10) U4500.AJ27(CORE_VCC1_S0IX11) U4500.AJ29(CORE_VCC1_S0IX12) U4500.AJ30(CORE_VCC1_S0IX13) U4500.AJ33(CORE_VCC1_S0IX14) U4500.AJ36(CORE_VCC1_S0IX15) U4500.AJ38(CORE_VCC1_S0IX16)
PVCORE_PG: R350.1(A) U301.11(GPIO27/PSDAT2) U6600.6
PVGG: C4525.1(A) C4526.1(A) C4527.1(A) C4528.1(A) C4529.1(A) C4530.1(A) C4531.1(A) C4565.1(A) C4640.1(A) C6700.1(A) C6701.1(A) C6702.1(A) C7519.1(A) C7520.1(A) C7522.1(A) C7591.1(A) R4699.1(A) R6710.2 U4500.AD16(DDI_VGG_S0IX1) U4500.AD18(DDI_VGG_S0IX2) U4500.AD19(DDI_VGG_S0IX3) U4500.AF16(DDI_VGG_S0IX4) U4500.AF18(DDI_VGG_S0IX5) U4500.AF19(DDI_VGG_S0IX6) U4500.AF21(DDI_VGG_S0IX7) U4500.AF22(DDI_VGG_S0IX8) U4500.AG16(DDI_VGG_S0IX9) U4500.AG18(DDI_VGG_S0IX10) U4500.AG19(DDI_VGG_S0IX11) U4500.AG21(DDI_VGG_S0IX12) U4500.AG22(DDI_VGG_S0IX13) U4500.AG24(DDI_VGG_S0IX14) U4500.AJ19(DDI_VGG_S0IX15) U4500.AJ21(DDI_VGG_S0IX16) U4500.AJ22(DDI_VGG_S0IX17) U4500.AJ24(DDI_VGG_S0IX18) U4500.AK24(DDI_VGG_S0IX19)
PVGG_PG: C7225.2(B) R7245.1(A) R7250.1(A) U6700.6
PVPACK: C6010.1(A) C6011.1(A) C6033.1(A) C6050.1(A) CN6050.1 CN6050.2 D60002.1(A1) D60002.2(A2) Q6012.1(S0) Q6012.2(S1) Q6012.3(S2) R6001.2
PWR_OLED#: CN245.8 U301.16(GPIO40/F_PWM/1_WIRE)
PWR_OLED#_PB: CN9100.8 D9128.4
PWR_SWIN#_3: CN245.3 R301.1(A) U301.93(GPIO06/IOX_DOUT)
PWR_SWIN#_3_PB: C9102.1(A) CN9100.3 D9100.1 D9100.2 SW9100.1 SW9100.3
PWR_WLED#: CN245.5 U301.65(GPIO32/D_PWM)
PWR_WLED#_PB: CN9100.5 D9128.3
RAM_ID1: R4892.1(A) R4900.1(A) U4500.AD2(I2C3_SDA)
RAM_ID2: R4893.1(A) R4901.1(A) U4500.AC1(I2C4_SCL)
RAM_ID3: R4894.1(A) R4902.1(A) U4500.AD3(I2C4_SDA)
RAM_ID4: R4895.1(A) R4903.1(A) U4500.AF7(I2C2_SDA)
RING2: R601.1(A) R603.2(B) U500.17(MIC2-L/RING2)
RING2_CONN: C604.1(A) JACK600.4 R603.1(A) R610.1(A)
RTC_RST_N: C4625.1(A) C4627.1(A) R4580.1(A) U4500.D18(SRTCRST_B)
RTC_TEST_N: C4514.1(A) R4581.1(A) U4500.J16(RTEST_B)
RTCX1: C4512.1(A) R4579.2(B) U4500.M18(BRTCX1_PAD) X4501.4
RTCX2: C4511.1(A) R4579.1(A) U4500.K18(BRTCX2_PAD) X4501.1
SATA_OBSN: R4532.1(A) U4500.M30(SATA_OBSN)
SATA_OBSP: R4532.2(B) U4500.N30(SATA_OBSP)
SB_PWRBTN#: D4700.1(A2) R4653.1(A) U4500.M16(PMU_PWRBTN_B)
SB_PWRGD: R7243.1(A) U301.118(GPIO21/B_PWM)
SB_USB_1: U301.17(GPIO42/SCL3B/TCK) U2406.4
SB_USB_3: C2004.1(A) U301.23(GPIO46/SDA4B/CIRRXM/TRST#) U2000.4
SCAN_IN<0>: CN251.24 D250.1 U301.54(KBSIN0/GPIOA0/N2TCK)
SCAN_IN<1>: CN251.23 D251.1 U301.55(KBSIN1/GPIOA1/N2TMS)
SCAN_IN<2>: CN251.22 D252.1 U301.56(KBSIN2/GPIOA2)
SCAN_IN<3>: CN251.21 D253.1 U301.57(KBSIN3/GPIOA3)
SCAN_IN<4>: CN251.20 D254.1 U301.58(KBSIN4/GPIOA4)
SCAN_IN<5>: CN251.19 D255.1 U301.59(KBSIN5/GPIOA5)
SCAN_IN<6>: CN251.18 D256.1 U301.60(KBSIN6/GPIOA6)
SCAN_IN<7>: CN251.17 D257.1 U301.61(KBSIN7/GPIOA7)
SCAN_OUT<0>: CN251.1 U301.53(KBSOUT0/GPOB0/JENK#)
SCAN_OUT<1>: CN251.2 U301.52(KBSOUT1/GPIOB1/TCK)
SCAN_OUT<2>: CN251.3 U301.51(KBSOUT2/GPIOB2/TMS)
SCAN_OUT<3>: CN251.4 U301.50(KBSOUT3/GPIOB3/TDI)
SCAN_OUT<4>: CN251.5 U301.49(KBSOUT4/GPOB4/JEN0#)
SCAN_OUT<5>: CN251.6 U301.48(KBSOUT5/GPIOB5/TDO)
SCAN_OUT<6>: CN251.7 U301.47(KBSOUT6/GPIOB6/RDY#)
SCAN_OUT<7>: CN251.8 U301.43(KBSOUT7/GPIOB7)
SCAN_OUT<8>: CN251.9 U301.42(KBSOUT8/GPIOC0)
SCAN_OUT<9>: CN251.10 U301.41(KBSOUT9/GPOC1/SDP_VIS#)
SCAN_OUT<10>: CN251.11 U301.40(KBSOUT10_P80_CLK/GPIOC2)
SCAN_OUT<11>: CN251.12 U301.39(KBSOUT11_P80_DAT/GPIOC3)
SCAN_OUT<12>: CN251.13 U301.38(KBSOUT12/GPO64/TEST#)
SCAN_OUT<13>: CN251.14 U301.37(KBSOUT13/GPO63/TRIST#<0>)
SCAN_OUT<14>: CN251.15 U301.36(KBSOUT14/GPO62/XORTR#<0>)
SCAN_OUT<15>: CN251.16 U301.35(KBSOUT15/GPIO61/XOR_OUT)
SCAN_OUT<16>: U301.34(GPIO60/KBSOUT16)
SCAN_OUT<17>: U301.33(GPIO57/KBSOUT17)
SD_CD#: CN901.10 U900.13(SP6)
SD_CLK: C907.1(A) CN901.5 R901.2(B)
SD_CMD: CN901.2 U900.18(SP10)
SD_D0: CN901.7 U900.11(SP4)
SD_D1: CN901.8 U900.10(SP3)
SD_D2: CN901.9 U900.21(SP13)
SD_D3: CN901.1 U900.20(SP12)
SD_R_CLK: R901.1(A) U900.15(SP8)
SD_WP: CN901.11 U900.8(SP1)
SDIO_V3P3A_V1P8A: C4579.1(A) C4580.1(A) R4708.2(B) U4500.E1(SDIO_V3P3A_V1P8A_G31) U4500.E2(SDIO_V3P3A_V1P8A_G32)
SDMMC1_RCOMP: R4521.2(B) U4500.P13(SDMMC1_RCOMP)
SDMMC3_RCOMP: R4712.1(A) U4500.P12(SDMMC3_RCOMP)
SIO_I2C_CLK: R4681.2(B) U4500.AK6(I2C0_SCL) U4503.5
SIO_I2C_DATA: R4682.2(B) U4500.AH7(I2C0_SDA) U4503.4
SLEEVE: R600.1(A) R602.2(B) U500.18(MIC2-R/SLEEVE)
SLP_S3#: Q4517.1(G) R4680.1(A) U4500.B14(PMU_SLP_S3_B)
SLP_S3#_3R: Q4525.3(D) Q4714.1(G) R4641.2(B) R60003.1(A) U301.106(GPIO96/DA2) U4703.1 U4703.2 U60600.4(SLP_S3_B)
SLP_S3#_3R_IC: D7200.3(A1) R7111.1(A) R7112.1(A) R7115.1(A) R7204.1(A) R7207.1(A) U4703.4
SLP_S3_3R: Q4714.3(D) Q7106.1(G) Q7108.1(G) Q7114.1(G) R4834.2(B)
SLP_S4#: Q4516.1(G) R4670.1(A) U4500.C12(PMU_SLP_S4_B)
SLP_S4#_3R: Q4524.3(D) Q7202.1 R4644.2(B) R7208.1(A) U301.20(GPIO43/SDA3B/TMS)
SOC_COLD_RESET_N: TP4535.1 U4500.Y3(GPIO_ALERT)
SOC_SDMMC3_P1V8_EN: R4810.2(B) R4811.2(B) U4500.K2(SDMMC3_1P8_EN)
SOC_SDMMC3_PWR_EN_N: R4809.2(B) U4500.L3(SDMMC3_PWR_EN_B)
SOC_SMBCLK: R282.1(A) R314.2(B) R4591.2(B)
SOC_SMBDAT: R281.1(A) R313.2(B) R4593.2(B)
SOC_SMI#: R4657.1(A) U4500.AG53(GPIO_SUS7)
SPI_CLK: U4701.6 U4702.7
SPI_CS0#: R35.1(A) U4701.1 U4702.8
SPI_HOLD: R4545.1(A) R4806.1(A) U4701.7
SPI_SI_IO0: R341.1(A) R4633.1(A) U4701.5
SPI_SO_IO1: R340.1(A) R4648.1(A) U4701.2
SPI_SOC_R_CLK: R4631.2(B) U4702.4
SPI_SOC_R_CS0#: R4807.2(B) U4702.3
SPI_WP#: R4546.1(A) R4805.1(A) U4701.3
SPK_OUT_L_N: R508.2(B) U500.43(SPK-L-)
SPK_OUT_L_P: R509.2(B) U500.42(SPK-L+)
SPK_OUT_R_L_N: C607.2(B) C609.1(A) CN600.3 R508.1(A)
SPK_OUT_R_L_P: C607.1(A) C608.1(A) CN600.4 R509.1(A)
SPK_OUT_R_N: R510.2(B) U500.44(SPK-R-)
SPK_OUT_R_P: R511.2(B) U500.45(SPK-R+)
SPK_OUT_R_R_N: C606.1(A) C610.1(A) CN600.2 R510.1(A)
SPK_OUT_R_R_P: C606.2(B) C611.1(A) CN600.1 R511.1(A)
SUS_PWR_DN_ACK: R4709.2(B) R4815.2(B) R60002.1(A) U301.64(GPIO01/TB2) U4500.AE3(SUSPWRDNACK)
SVID_ALERT: R4614.1(A) R4645.1(A) R4647.1(A) U4500.AD40(SVID0_ALERT_B)
SVID_CLK: R4590.1(A) R4592.1(A) R4596.1(A) R4850.1(A) U4500.AD42(SVID0_CLK)
SVID_DATA: R4601.1(A) R4604.1(A) U4500.AD41(SVID0_DATA)
THRM_SHUTDWN#: D500.1 D500.2 R4448.1(A) SW500.1 SW500.3 U4441.3
TP_EN#: Q281.1 U301.123(GPIO67/N2TMS)
TP_INT#: Q311.2(S) R285.1(A) R286.1(A) R311.1(A) R312.1(A)
TP_INT#_SOC: Q310.2(S) R310.1(A) U4500.AE51(SEC_GPIO_SUS10)
TPM_CLKRUN: R3510.2(B) R3513.1(A) U3500.15(C_L_K_R_U_N_/GPIO04/S_I_N_T_)
TPM_LPC_AD<0>: R3506.2(B) U3500.26(LAD0/MISO)
TPM_LPC_AD<1>: R3505.2(B) U3500.23(LAD1/MOSI)
TPM_LPC_AD<2>: R3504.2(B) U3500.20(LAD2/S_P_I___I_R_Q_)
TPM_LPC_AD<3>: R3503.2(B) U3500.17(LAD3)
TPM_LPC_CLK: R3509.2(B) U3500.21(LCLK/SCLK)
TPM_LPC_FRAME#: R3507.2(B) U3500.22(L_F_R_A_M_E_/S_C_S_)
TPM_LPCPD#: Q3502.3(D) R3516.2(B) U3500.28(LPCPD*)
TPM_SERIRQ: Q3500.3(D) R3511.1(A) U3500.27(SERIRQ)
TSENSE: C6646.1(A) R6612.1(A) U6600.13
UNNAMED_5_BEADSINGLE_I57_INA: C6000.1(A) C6001.1(A) C7604.1(A) L7601.1(INA) Q6000.2 Q6000.3 Q6000.4 Q6000.10
UNNAMED_5_BEADSINGLE_I76_INA: C7601.1(A) C7602.1(A) CN6000.1 CN6000.2 L7600.1(INA)
UNNAMED_5_CN09_I103_4: CN6050.4 R6055.2(B)
UNNAMED_5_CN09_I103_5: CN6050.5 R6052.2(B)
UNNAMED_5_CN09_I103_6: CN6050.6 R6050.2(B)
UNNAMED_5_CN09_I103_7: CN6050.7 R6051.2(B)
UNNAMED_5_POWERINDUCTOR_I49_2: L6000.2 R6001.1
UNNAMED_5_RSC0805_I51_B: D6000.3(C) R6012.2(B)
UNNAMED_6_CSC0402_I64_A: C6166.1(A) R6166.2(B) R6167.2(B)
UNNAMED_6_CSC0805_I6_A: C6160.1(A) C6161.1(A) PAD6160.2 U6150.1
UNNAMED_6_CSC0805_I27_A: C6110.1(A) C6111.1(A) PAD6110.2 U6100.1
UNNAMED_8_CSC0402_I24_A: C6647.1(A) R6660.2(B) U6600.7
UNNAMED_8_CSC0402_I35_A: C6618.1(A) R6666.2(B) U6600.27
UNNAMED_8_CSC0402_I35_B: C6618.2(B) C6649.1(A) R6659.1(A) R6663.2(B)
UNNAMED_8_CSC0402_I36_B: C6649.2(B) R6659.2(B) U6600.26
UNNAMED_8_CSC0402_I40_A: C6613.1(A) R6619.1(A)
UNNAMED_8_CSC0402_I40_B: C6613.2(B) C6614.1(A) C6617.1(A) R6616.2(B) R6654.1(A) U6600.24
UNNAMED_8_CSC0402_I41_B: C6617.2(B) R6618.2(B) R6654.2(B)
UNNAMED_8_CSC0402_I44_B: C6614.2(B) R6618.1(A) U6600.23
UNNAMED_8_CSC0402_I52_A: C6616.1(A) R6647.1(A) U6600.17
UNNAMED_8_CSC0402_I57_A: C6639.1(A) C6640.1(A) R6633.1(A) R6651.2(B) U6600.19
UNNAMED_8_CSC0402_I57_B: C6639.2(B) C6640.2(B) R6649.1(A) R6651.1(A) U6600.18
UNNAMED_8_CSC0402_I58_A: C6645.1(A) R6655.1(A) U6600.20
UNNAMED_8_CSC0603_I70_A: C6643.1(A) R6665.1(A) U6600.15
UNNAMED_8_NCP81101BMNTXG_I71_14: R6650.1(A) U6600.14
UNNAMED_8_NCP81101BMNTXG_I71_16: R6646.1(A) U6600.16
UNNAMED_8_NCP81101BMNTXG_I71_21: R6633.2(B) U6600.21
UNNAMED_8_NCP81101BMNTXG_I71_22: R6652.2(B) U6600.22
UNNAMED_8_NCP81101BMNTXG_I71_25: R6616.1(A) R6619.2(B) U6600.25
UNNAMED_8_RSC0402_I48_A: R6612.2(B) R6658.1(A) R6661.1(A)
UNNAMED_9_CSC0402_I14_A: C7661.1(A) R7661.2(B)
UNNAMED_9_IDUT4PIN_I34_2: L6610.2 L6610.4 R6610.1
UNNAMED_10_CSC0402_I24_A: C6747.1(A) R6760.2(B) U6700.7
UNNAMED_10_CSC0402_I35_A: C6718.1(A) R6766.2(B) U6700.27
UNNAMED_10_CSC0402_I35_B: C6718.2(B) C6749.1(A) R6759.1(A) R6763.2(B)
UNNAMED_10_CSC0402_I36_B: C6749.2(B) R6759.2(B) U6700.26
UNNAMED_10_CSC0402_I40_A: C6713.1(A) R6719.1(A)
UNNAMED_10_CSC0402_I40_B: C6713.2(B) C6714.1(A) C6717.1(A) R6716.2(B) R6754.1(A) U6700.24
UNNAMED_10_CSC0402_I41_B: C6717.2(B) R6718.2(B) R6754.2(B)
UNNAMED_10_CSC0402_I44_B: C6714.2(B) R6718.1(A) U6700.23
UNNAMED_10_CSC0402_I51_A: C6716.1(A) R6747.1(A) U6700.17
UNNAMED_10_CSC0402_I56_A: C6739.1(A) C6740.1(A) R6733.1(A) R6751.2(B) U6700.19
UNNAMED_10_CSC0402_I56_B: C6739.2(B) C6740.2(B) R6749.1(A) R6751.1(A) U6700.18
UNNAMED_10_CSC0402_I57_A: C6745.1(A) R6755.1(A) U6700.20
UNNAMED_10_CSC0603_I49_A: C6743.1(A) R6765.1(A) U6700.15
UNNAMED_10_NCP81101BMNTXG_I71_1: R6750.1(A) U6700.14
UNNAMED_10_NCP81101BMNTXG_I71_2: R6746.1(A) U6700.16
UNNAMED_10_NCP81101BMNTXG_I71_3: R6733.2(B) U6700.21
UNNAMED_10_NCP81101BMNTXG_I71_4: R6752.2(B) U6700.22
UNNAMED_10_NCP81101BMNTXG_I71_5: R6716.1(A) R6719.2(B) U6700.25
UNNAMED_10_RSC0402_I48_A: R6712.2(B) R6758.1(A) R6761.1(A)
UNNAMED_11_CSC0402_I7_A: C7761.1(A) R7761.2(B)
UNNAMED_11_IDUT4PIN_I27_2: L6710.2 L6710.4 R6710.1
UNNAMED_12_CSC0402_I17_A: C7205.1(A) R7206.2(B) R7230.1(A) R7241.2(B) R7252.1(A) R7256.2(B)
UNNAMED_12_CSC0603_I125_A: C60013.1(A) D60002.3(C) R60017.1(A)
UNNAMED_12_DDUALSERIESA_I130_A1: D60003.1(A1) Q60003.3(D2)
UNNAMED_12_DDUALSERIESA_I130_C: D60003.3(C) R60021.2(B)
UNNAMED_12_NMOSDUALC_I66_D1: Q7214.5(G2) Q7214.6(D1) R7246.1(A)
UNNAMED_12_NMOSDUALC_I91_D1: Q60002.5(G2) Q60002.6(D1) R60017.2(B) R60018.1(A)
UNNAMED_12_NMOSDUALC_I91_D2: Q60002.3(D2) R60022.2(B)
UNNAMED_12_NMOSDUALC_I113_G1: Q60003.2(G1) R60019.1(A) R60020.2(B)
UNNAMED_12_NMOSDUALC_I113_G2: Q60003.5(G2) R60023.2(B) R60024.1(A)
UNNAMED_13_CSC0603_I58_A: C60610.1(A) C60611.1(A) C60612.1(A) PAD60610.2 U60600.1(IN_1P8_0) U60600.2(IN_1P8_1)
UNNAMED_13_CSC0603_I80_A: C60910.1(A) C60911.1(A) C60912.1(A) PAD60910.2 U60600.20(IN_1P05A_0) U60600.21(IN_1P05A_1)
UNNAMED_13_RSC0402_I94_B: R60000.2(B) R60003.2(B) U60600.25(SLP_S0IX_B)
UNNAMED_13_RSCSHORT_I99_B: R60002.2(B) U60600.24(SUSPWRDNACK)
UNNAMED_15_APL3523A_I201_3: C7116.1(A) R7115.2(B) U7100.3
UNNAMED_15_APL3523A_I201_5: C7125.1(A) R7112.2(B) U7100.5
UNNAMED_15_APL3523A_I201_8: PAD7102.2 U7100.8 U7100.9
UNNAMED_15_APL3523A_I201_10: C7101.1(A) U7100.10
UNNAMED_15_APL3523A_I201_12: C7122.1(A) U7100.12
UNNAMED_15_APL3523A_I201_13: PAD7103.1 U7100.13 U7100.14
UNNAMED_15_APL3523A_I202_3: C13.1(A) R7110.2(B) U7102.3
UNNAMED_15_APL3523A_I202_5: C7111.1(A) R7111.2(B) U7102.5
UNNAMED_15_APL3523A_I202_8: PAD7101.2 U7102.8 U7102.9
UNNAMED_15_APL3523A_I202_10: C7100.1(A) U7102.10
UNNAMED_15_APL3523A_I202_12: C7109.1(A) U7102.12
UNNAMED_15_APL3523A_I202_13: PAD7104.2 U7102.13 U7102.14
UNNAMED_15_NMOS_I179_D: Q7108.3(D) R29.2(B)
UNNAMED_15_NMOS_I184_D: Q7114.3(D) R28.2(B)
UNNAMED_15_NMOS_I189_D: Q7120.3(D) R7125.2(B)
UNNAMED_15_NMOS_I194_D: Q7106.3(D) R7109.2(B)
UNNAMED_16_505030084N001_I222_3: CN281.3 R286.2(B)
UNNAMED_16_505030084N001_I222_4: CN281.4 R285.2(B)
UNNAMED_20_CSC0402_I15_A: C904.1(A) U900.6(SDREG)
UNNAMED_20_CSC0402_I20_A: C901.1(A) U900.24(V18)
UNNAMED_21_APCI0062P001A_I66_PE: CN1300.55(PEWAKE0*) R1302.2(B) R1306.1(A)
UNNAMED_24_CSC0402_I46_A: C3954.1(A) C3955.1(A) C3956.1(A) C3957.1(A) D3950.1 R3966.1(A) U3950.E6(VCC<1>) U3950.F5(VCC<2>) U3950.J10(VCC<3>) U3950.K9(VCC<4>)
UNNAMED_24_CSC0402_I53_A: C3950.1(A) C3951.1(A) C3952.1(A) C3953.1(A) D3951.1 R3964.1(A) U3950.C6(VCCQ<1>) U3950.M4(VCCQ<2>) U3950.N4(VCCQ<3>) U3950.P3(VCCQ<4>) U3950.P5(VCCQ<5>)
UNNAMED_24_CSC0402_I63_A: C3959.1(A) U3950.C2(VDDI)
UNNAMED_24_RSC0402_I92_A: R3965.1(A) U3950.H5(DS)
UNNAMED_24_RSC0402_I113_A: R3950.1(A) R3963.1(A)
UNNAMED_25_NMOS_I248_D: Q3501.3(D) Q3502.1(G) R3515.1(A)
UNNAMED_27_099A4AC19HBLBNF_I1_1: CN3150.14 TP3151.1
UNNAMED_27_099A4AC19HBLBNF_I1_2: CN3150.19 R3154.2(B)
UNNAMED_27_099A4AC19HBLBNF_I126: CN3150.13 TP3152.1
UNNAMED_27_NMOS_I117_D: Q3152.3(D) R3157.2(B) R3158.2(B) R3159.2(B) R3160.2(B) R3161.2(B) R3162.2(B) R3163.2(B) R3164.2(B)
UNNAMED_29_H5TC4G63AFR_I114_NC4: R4103.2(B) U4103.L9(NC_4/ZQ1)
UNNAMED_29_H5TC4G63AFR_I114_ZQ0: R4109.2(B) U4103.L8(ZQ0)
UNNAMED_29_H5TC4G63AFR_I157_NC4: R4102.2(B) U4102.L9(NC_4/ZQ1)
UNNAMED_29_H5TC4G63AFR_I157_ZQ0: R4108.2(B) U4102.L8(ZQ0)
UNNAMED_30_H5TC4G63AFR_I119_NC4: R4101.2(B) U4101.L9(NC_4/ZQ1)
UNNAMED_30_H5TC4G63AFR_I119_ZQ0: R4107.2(B) U4101.L8(ZQ0)
UNNAMED_30_H5TC4G63AFR_I178_NC4: R4100.2(B) U4100.L9(NC_4/ZQ1)
UNNAMED_30_H5TC4G63AFR_I178_ZQ0: R4106.2(B) U4100.L8(ZQ0)
UNNAMED_32_H5TC4G63AFR_I41_NC4: R4179.2(B) U4104.L9(NC_4/ZQ1)
UNNAMED_32_H5TC4G63AFR_I41_ZQ0: R4178.2(B) U4104.L8(ZQ0)
UNNAMED_32_H5TC4G63AFR_I181_NC4: R4144.2(B) U4105.L9(NC_4/ZQ1)
UNNAMED_32_H5TC4G63AFR_I181_ZQ0: R4151.2(B) U4105.L8(ZQ0)
UNNAMED_35_540276_I159_DDI0PL_1: R4514.2(B) U4500.F38(DDI0_PLLOBS_P)
UNNAMED_35_540276_I159_DDI0PLLO: R4514.1(A) U4500.G38(DDI0_PLLOBS*)
UNNAMED_35_540276_I159_DDI1PL_1: R4518.2(B) U4500.F47(DDI1_PLLOBS_P)
UNNAMED_35_540276_I159_DDI1PLLO: R4518.1(A) U4500.F49(DDI1_PLLOBS*)
UNNAMED_35_540276_I159_GPCAME_1: R4705.1(A) U4500.V40(GP_CAMERASB11)
UNNAMED_35_540276_I159_GPCAME_2: R4707.1(A) U4500.Y44(GP_CAMERASB08)
UNNAMED_35_540276_I159_GPCAMERA: R4706.1(A) U4500.Y42(GP_CAMERASB09)
UNNAMED_35_540276_I159_MCSICOMP: R4711.1(A) U4500.P44(MCSI_COMP)
UNNAMED_36_540276_I157_MFHDACLK: R4538.1(A) U4500.AD9(MF_HDA_CLK)
UNNAMED_36_540276_I157_MFHDARST: R4536.1(A) U4500.AF13(MF_HDA_RSTB)
UNNAMED_36_540276_I157_MFHDASDO: R4539.1(A) U4500.AF14(MF_HDA_SDO)
UNNAMED_36_540276_I157_MFHDASYN: R4537.1(A) U4500.AF12(MF_HDA_SYNC)
UNNAMED_36_540276_I157_PCIECLKR: R4523.2(B) U4500.AM12(PCIE_CLKREQ1B)
UNNAMED_36_540276_I157_SATAGP0: R4540.1(A) U4500.AH2(SATA_GP0)
UNNAMED_36_540276_I157_SATAGP3: TP4540.1 U4500.AF3(SATA_GP3)
UNNAMED_36_RSC0402_I236_A: R4702.1(A) U4702.6
UNNAMED_37_540276_I161_GPIODFX0: TP4551.1 U4500.AM40(GPIO_DFX0)
UNNAMED_37_540276_I161_GPIODFX1: TP4552.1 U4500.AM41(GPIO_DFX1)
UNNAMED_37_540276_I161_GPIODFX2: TP4553.1 U4500.AM44(GPIO_DFX2)
UNNAMED_37_540276_I161_GPIODFX3: TP4554.1 U4500.AM45(GPIO_DFX3)
UNNAMED_37_540276_I161_I2C5SCL: TP4506.1 U4500.AB2(I2C5_SCL)
UNNAMED_37_540276_I161_I2C5SDA: TP4505.1 U4500.AC3(I2C5_SDA)
UNNAMED_37_540276_I161_I2C6SDA: R4635.1(A) U4500.AB3(I2C6_SDA)
UNNAMED_37_540276_I161_I2CNFCSC: TP4504.1 U4500.AA3(I2C_NFC_SCL)
UNNAMED_37_540276_I161_I2CNFCSD: TP4537.1 U4500.Y2(I2C_NFC_SDA)
UNNAMED_37_540276_I161_MFSMBALE: B500.1 R4632.1(A) U4500.AM9(MF_SMB_ALERTB)
UNNAMED_37_RSC0402_I174_B: R4686.2(B) U4503.6
UNNAMED_37_RSC0402_I273_B: R4582.2(B) U4502.6
UNNAMED_37_RSC0402_I274_A: R4561.1(A) R4591.1(A) U4502.8
UNNAMED_37_RSC0402_I275_A: R4562.1(A) R4593.1(A) U4502.1
UNNAMED_38_540276_I11_VSS2: TP4534.1 U4500.A6(VSS2)
UNNAMED_38_540276_I11_VSS16: TP4533.1 U4500.BH53(VSS16)
UNNAMED_39_NMOS_I11_G: Q4517.3(D) Q4525.1(G) R4639.1(A)
UNNAMED_39_NMOS_I12_D: Q4516.3(D) Q4524.1(G) R4642.1(A)
UNNAMED_39_NMOSDUALC_I78_D2: Q1302.2(G1) Q1302.3(D2) R4643.1(A)
UNNAMED_41_540276_I90_SDIOV3P3A: C4581.1(A) R4835.2(B) U4500.G1(SDIO_V3P3A_V1P8A_G33)
UNNAMED_42_RSC0402_I10_A: R4601.2(B) R4602.1(A) R4846.1(A)
UNNAMED_42_RSC0402_I11_A: R4604.2(B) R4605.1(A) R4847.1(A)
UNNAMED_45_AT9667_I14_2: R4446.2(B) U4441.2
UNNAMED_45_AT9667_I14_5: R4441.1(A) R4448.2(B) R4449.2(B) U4441.5
UNNAMED_45_AT9667_I14_7: R4443.2(B) U4441.7
UNNAMED_45_AT9667_I14_8: R4442.1(A) R4443.1(A) R4444.1(A) U4441.8
UNNAMED_45_CSC0402_I38_B: C4102.2(B) R4114.2(B) R4115.2(B)
UNNAMED_46_CSC0402_I70_A: C310.1(A) U301.44(VCORF)
UNNAMED_46_CSC0402_I232_A: C316.1(A) U301.12(VTT)
UNNAMED_46_NMOS_I547_D: Q310.3(D) Q311.3(D)
UNNAMED_46_NPCE985LB1DX_I255_10: TP302.1 U301.120(GPIO31/SDA3A/N2TMS)
UNNAMED_46_NPCE985LB1DX_I255_11: TP307.1 U301.6(GPIO24)
UNNAMED_46_NPCE985LB1DX_I255_12: TP308.1 U301.109(GPIO30/F_WP#)
UNNAMED_46_NPCE985LB1DX_I255_13: TP309.1 U301.15(GPIO36)
UNNAMED_46_NPCE985LB1DX_I255_14: TP310.1 U301.26(GPIO51/N2TCK)
UNNAMED_46_NPCE985LB1DX_I255_15: TP306.1 U301.83(GPIO76/SPI_MOSI)
UNNAMED_46_NPCE985LB1DX_I255__1: TP329.1 U301.91(GPIO81/F_WP#/F_SDIO2)
UNNAMED_46_NPCE985LB1DX_I255__2: R390.1(A) R391.2(B) U301.124(GPIO10/LPCPD#)
UNNAMED_46_NPCE985LB1DX_I255__3: TP301.1 U301.114(GPIO16)
UNNAMED_46_NPCE985LB1DX_I255__4: R314.1(A) U301.24(GPIO47/SCL4A/N2TCK)
UNNAMED_46_NPCE985LB1DX_I255__5: R313.1(A) U301.28(GPIO53/SDA4A/N2TMS)
UNNAMED_46_NPCE985LB1DX_I255__6: TP303.1 U301.27(GPIO52/PSDAT3/RDY#)
UNNAMED_46_NPCE985LB1DX_I255__7: TP311.1 U301.117(GPIO20/TA2/IOX_DIN_DIO)
UNNAMED_46_NPCE985LB1DX_I255__8: TP304.1 U301.84(GPIO77/SPI_MISO)
UNNAMED_46_NPCE985LB1DX_I255__9: TP300.1 U301.119(GPIO23/SCL3A/N2TCK)
UNNAMED_46_NPCE985LB1DX_I255_EC: TP327.1 U301.29(ECSCI#/GPIO54)
UNNAMED_46_NPCE985LB1DX_I255_GP: R312.2(B) U301.75(GPIO72)
UNNAMED_46_NPCE985LB1DX_I256__1: TP305.1 U301.63(GPIO14/TB1)
UNNAMED_46_NPCE985LB1DX_I256_GP: R325.2(B) U301.30(GPIO55/CLKOUT/IOX_DIN_DIO)
UNNAMED_51_ALC233VB2CGT_I110__1: C511.1(A) U500.37(CBP)
UNNAMED_51_ALC233VB2CGT_I110__2: C512.2(B) U500.39(LDO2-CAP)
UNNAMED_51_ALC233VB2CGT_I110__3: C530.1(A) U500.7(LDO3-CAP)
UNNAMED_51_ALC233VB2CGT_I110_AV: C513.1(A) PAD503.2 U500.40(AVDD2)
UNNAMED_51_ALC233VB2CGT_I110_CB: C511.2(B) U500.35(CBN)
UNNAMED_51_ALC233VB2CGT_I110_CP: C503.2(B) U500.34(CPVEE)
UNNAMED_51_ALC233VB2CGT_I110_HP: R502.1(A) R504.1(A) U500.13(HP/LINE1 JD)
UNNAMED_51_ALC233VB2CGT_I110_LD: C501.1(A) R531.1(A) U500.27(LDO1-CAP)
UNNAMED_51_ALC233VB2CGT_I110_MI: C531.1(A) U500.19(MIC-CAP)
UNNAMED_51_ALC233VB2CGT_I110_NC: R514.1(A) U500.20(NC)
UNNAMED_51_ALC233VB2CGT_I110_PC: C507.1(A) U500.12(PCBEEP)
UNNAMED_51_ALC233VB2CGT_I110_SP: R501.1(A) U500.15(SPDIFO/FRONT JD/GPIO3)
UNNAMED_51_ALC233VB2CGT_I110_VR: C502.2(B) U500.28(VREF)
UNNAMED_51_CSC0402_I68_B: C506.2(B) C507.2(B) R503.1(A) R505.1(A) R515.1(A)
UNNAMED_51_RSC0402_I120_B: R505.2(B) R521.1(A)
UNNAMED_51_RSC0402_I136_B: R515.2(B) R520.1(A)
UNNAMED_52_2SJ3095078111F_I61_1: C600.1(A) JACK600.1 R605.2(B) R606.2(B)
UNNAMED_52_2SJ3095078111F_I61_2: C601.1(A) JACK600.2 R604.2(B) R607.2(B)
UNNAMED_54_5020303001001_I97_3: CN3000.3 TP3001.1
UNNAMED_54_5020303001001_I97_7: CN3000.7 R3060.1(A) R3061.2(B)
UNNAMED_54_5020303001001_I97_8: CN3000.8 TP3002.1
UNNAMED_54_5020303001001_I97_16: CN3000.16 TP3003.1
UNNAMED_54_CSC0402_I39_A: C3016.1(A) Q3004.3 R3068.2(B) R3069.2(B)
UNNAMED_54_CSC0402_I39_B: C3015.2(B) C3016.2(B) Q3004.1 R3030.2(B)
UNNAMED_54_CSC0402_I43_A: C3015.1(A) FUSE3004.1 Q3004.2
UNNAMED_54_CSC0402_I105_A: C3000.1(A) C3003.1(A) Q3000.1 Q3001.2(G1) R3001.2(B)
UNNAMED_54_NMOS_I135_G: Q3006.3(C) Q3007.1(G) R3006.2(B)
UNNAMED_54_NMOSDUALC_I102_D1: Q3001.6(D1) R3004.2(B)
UNNAMED_54_NMOSDUALC_I102_D2: Q3001.3(D2) R3000.2(B) R3001.1(A)
UNNAMED_54_NPND_I136_B: Q3006.1(B) R3025.2(B)
UNNAMED_59_540276_I142_BVCCRTCE: C4513.1(A) U4500.F16(BVCCRTC_EXTPAD)
UNNAMED_59_540276_I142_CXPRDYB: TP4516.1 U4500.AD45(CX_PRDY_B)
UNNAMED_59_540276_I142_CXPREQB: TP4517.1 U4500.AF41(CX_PREQ_B)
UNNAMED_59_540276_I142_MFLPCCLK: R4828.2(B) U4500.R3(MF_LPC_CLKOUT1)
UNNAMED_59_540276_I142_PWM0: TP4509.1 U4500.H5(PWM0)
UNNAMED_59_540276_I142_PWM1: TP4510.1 U4500.H7(PWM1)
UNNAMED_59_540276_I142_RSVDVSS: R4820.1(A) U4500.G18(RSVD_VSS)
UNNAMED_59_540276_I142_TCK: TP4511.1 U4500.AF42(TCK)
UNNAMED_59_540276_I142_TDI: TP4512.1 U4500.AD47(TDI)
UNNAMED_59_540276_I142_TDO: TP4513.1 U4500.AF40(TDO)
UNNAMED_59_540276_I142_TMS: TP4514.1 U4500.AD48(TMS)
UNNAMED_59_540276_I142_TRSTB: TP4515.1 U4500.AB48(TRST_B)
UNNAMED_59_NMOS_I8_G: Q4505.1(G) R4578.2(B)
UNNAMED_59_NMOSDUALC_I161_D1: Q4506.5(G2) Q4506.6(D1) R4586.1(A)
UNNAMED_59_RSC0402_I187_B: R4572.2(B) R4573.2(B) R4828.1(A)
UNNAMED_59_RSCSHORT_I186_A: D4501.3(A1) R704.1(A)
UNNAMED_60_540276_I79_UART1RXD: TP4542.1 U4500.AD12(UART1_RXD)
UNNAMED_60_540276_I79_UART1TXD: TP4541.1 U4500.AD10(UART1_TXD)
UNNAMED_60_540276_I79_UART2RXD: TP4544.1 U4500.Y7(UART2_RXD)
UNNAMED_60_540276_I79_UART2TXD: TP4543.1 U4500.Y6(UART2_TXD)
UNNAMED_61_19223S2T1DC302T_I5_1: D9129.1 R9123.1(A)
UNNAMED_61_19223S2T1DC302T_I5_2: D9129.2 R9124.1(A)
UNNAMED_61_19223S2T1DC302T_I6_1: D9128.1 R9121.1(A)
UNNAMED_61_19223S2T1DC302T_I6_2: D9128.2 R9122.1(A)
UNNAMED_62_CSC0402_I6_B: C4200.2(B) R4185.2(B) R4186.2(B)
UNNAMED_63_H5TC4G63AFR_I34_NC4: R4182.2(B) U4106.L9(NC_4/ZQ1)
UNNAMED_63_H5TC4G63AFR_I34_ZQ0: R4187.2(B) U4106.L8(ZQ0)
UNNAMED_63_H5TC4G63AFR_I164_NC4: R4180.2(B) U4107.L9(NC_4/ZQ1)
UNNAMED_63_H5TC4G63AFR_I164_ZQ0: R4181.2(B) U4107.L8(ZQ0)
USB3_OBSN: R4563.1(A) U4500.F34(USB3_OBSN)
USB3_OBSP: R4563.2(B) U4500.D34(USB3_OBSP)
USB3_PCH_RX1_DN: L2432.2(INA) U4500.D28(USB3_RXN0)
USB3_PCH_RX1_DP: L2432.1(INC) U4500.F28(USB3_RXP0)
USB3_PCH_TX1_DN: C2440.1(A) U4500.C32(USB3_TXN0)
USB3_PCH_TX1_DP: C2441.1(A) U4500.B32(USB3_TXP0)
USB3_SSRX1_DN: CN2401.5 D2406.1 D2406.10 L2432.3(INB)
USB3_SSRX1_DP: CN2401.6 D2406.2 D2406.9 L2432.4(IND)
USB3_SSTX1_C_DN: C2440.2(B) L2440.2(INA)
USB3_SSTX1_C_DP: C2441.2(B) L2440.1(INC)
USB3_SSTX1_L_DN: CN2401.8 D2406.4 D2406.7 L2440.3(INB)
USB3_SSTX1_L_DP: CN2401.9 D2406.5 D2406.6 L2440.4(IND)
USB_CAM_DN: R3005.1(A) U4500.A41(USB_DN2)
USB_CAM_DP: R3029.1(A) U4500.C41(USB_DP2)
USB_CAM_R_DN: CN3000.23 D3000.6 R3005.2(B)
USB_CAM_R_DP: CN3000.24 D3000.4 R3029.2(B)
USB_CR_DN: U900.2(DM) U4500.A45(USB_DN3)
USB_CR_DP: U900.3(DP) U4500.C45(USB_DP3)
USB_HSIC_RCOMP: R4676.1(A) U4500.N38(USB_HSIC_RCOMP)
USB_OC0#: R4677.1(A) U4500.P14(USB_OC0_B)
USB_OC1#: R4671.1(A) U4500.P16(USB_OC1_B)
USB_OC#_1: R2410.2(B) U301.32(GPIO15/A_PWM) U2406.3
USB_OC#_3: R2001.2(B) U301.10(GPIO26/PSCLK2) U2000.3
USB_P0_DN: L2404.1(INC) U4500.B42(USB_DN0)
USB_P0_DP: L2404.2(INA) U4500.C42(USB_DP0)
USB_P0_L_DN: CN2401.2 D2409.3 L2404.4(IND)
USB_P0_L_DP: CN2401.3 D2409.4 L2404.3(INB)
USB_P2_DN: CN2002.2 U4500.B44(USB_DN1)
USB_P2_DN_A: CN2003.3 L2406.1(INC)
USB_P2_DP: CN2002.3 U4500.C43(USB_DP1)
USB_P2_DP_A: CN2003.2 L2406.2(INA)
USB_P2_L_DN: CN2403.2 D2410.4 L2406.4(IND)
USB_P2_L_DP: CN2403.3 D2410.3 L2406.3(INB)
USB_RCOMP: R4564.1(A) U4500.A48(USB_RCOMP)
USB_VBUS_SENSE: R4837.2(B) U4500.B47(USB_VBUSSNS)
USB_WLAN_DN: CN1300.5(USB_D-) U4500.C40(USB_DN4)
USB_WLAN_DP: CN1300.3(USB_D+) U4500.B40(USB_DP4)
VGG_SENSEN: R4622.2(B) R4701.2(B) R6763.1(A)
VGG_SENSEN_R: R4622.1(A) U4500.AD22(UNCORE_VSS_SENSE2)
VGG_SENSEP: R4621.2(B) R4699.2(B) R6766.1(A)
VGG_SENSEP_R: R4621.1(A) U4500.AD24(DDI_VGG_SENSE)
VGG_TSENSE: C6746.1(A) R6712.1(A) U6700.13
VNN_SENSE_R: R4623.1(A) U4500.AC27(UNCORE_VSS_SENSE1)
VNN_SENSEP: R4623.2(B) R4726.2(B) R4836.2(B)
VR_SVID_VCC_ALERT#: R4614.2(B) U6600.4
VR_SVID_VCC_CLK: R4592.2(B) U6600.5
VR_SVID_VCC_DATA: R4846.2(B) U6600.3
VR_SVID_VGG_ALERT#: R4647.2(B) U6700.4
VR_SVID_VGG_CLK: R4596.2(B) U6700.5
VR_SVID_VGG_DATA: R4847.2(B) U6700.3
VRA3V3A_LDO: C6121.1(A) PAD6121.1 U6100.6
VRA3V3A_VCC: C6122.1(A) U6100.11
VRA3V3A_VCLK: U6100.5
VRA5V0A_VCC: C6172.1(A) R6198.1(A) U6150.11
VRACHG_ACDET: D60003.2(A2) R6002.1(A) R6003.1(A) U6000.6(ACDET)
VRACHG_ACDRV: R6004.1(A) U6000.4(ACDRV)
VRACHG_ACDRV1: C6030.2(B) C6031.1(A) Q6010.4(G) Q6011.4(G) Q60003.6(D1) R6004.2(B) R60022.1(A)
VRACHG_ACN: C6020.2(B) C6022.1(A) R6000.4 U6000.1(ACN)
VRACHG_ACP: C6020.1(A) C6021.1(A) R6000.3 U6000.2(ACP)
VRACHG_BATDRV: R6009.1(A) U6000.11(BATDRV)
VRACHG_BATDRV1: C6033.2(B) Q6012.4(G) R6009.2(B)
VRACHG_BST: R6020.1(A) U6000.17(BTST)
VRACHG_BST1: C6027.1(A) D6001.3(C) R6020.2(B)
VRACHG_CMSRC: R6005.1(A) U6000.3(CMSRC)
VRACHG_CMSRC1: C6031.2(B) Q6010.1(S0) Q6010.2(S1) Q6010.3(S2) Q6011.1(S0) Q6011.2(S1) Q6011.3(S2) Q60003.1(S1) R6005.2(B) R60020.1(A)
VRACHG_HG: Q6000.1 U6000.18(HIDRV)
VRACHG_ILIM: C6032.1(A) R6007.1(A) R6008.2(B) U6000.10(ILIM)
VRACHG_MP1: Q6011.5(D3) Q6011.6(D2) Q6011.7(D1) Q6011.8(D0) Q60003.4(S2) R6000.1
VRACHG_PH: C6027.2(B) L6000.1 Q6000.9 R7600.1(A) U6000.19(PHASE)
VRACHG_REGN: C6028.1(A) D6001.1(A1) D6001.2(A2) R60023.1(A) U6000.16(REGN)
VRACHG_SNB: C7600.1(A) R7600.2(B)
VRACHG_SRN: C6023.2(B) C6025.1(A) R6001.4 U6000.12(SRN)
VRACHG_SRP: C6023.1(A) C6024.1(A) R6001.3 U6000.13(SRP)
VRACHG_VCC: C6026.2(B) R6012.1(A) U6000.20(VCC)
VRACPU_BST: C6615.2(B) R6615.1(A)
VRACPU_BST1: R6615.2(B) U6600.8
VRACPU_CSN1: R6610.4 R6647.2(B)
VRACPU_CSP1: R6610.3 R6649.2(B)
VRACPU_VDD: C6642.1(A) R6645.1(A) U6600.28
VRAVDDQ_BST: R60315.1(A) U60300.27(BST)
VRAVDDQ_BST1: C60315.2(B) R60315.2(B)
VRAVDDQ_CS: R60305.2(B) U60300.10(CS)
VRAVDDQ_SET: C60304.2(B) R60300.1(A) R60301.2(B) U60300.3(VDDQSET)
VRAVDDQ_SNB: C60316.1(A) R60316.1(A)
VRAVDDQ_TON: R60306.1(A) U60300.7(TON)
VRAVGG_BST: C6715.2(B) R6715.1(A)
VRAVGG_BST1: R6715.2(B) U6700.8
VRAVGG_CSN1: R6710.4 R6747.2(B)
VRAVGG_CSP1: R6710.3 R6749.2(B)
VRAVGG_ON: R6743.1(A) U6700.1
VRAVGG_VDD: C6742.1(A) R6745.1(A) U6700.28
VRAVR_ON: R6643.1(A) U6600.1
VRB3V3A_BST: R6115.1(A) U6100.10
VRB3V3A_BST1: C6115.1(A) R6115.2(B)
VRB5V0A_BST: R6165.1(A) U6150.10
VRB5V0A_BST1: C6165.1(A) R6165.2(B)
VRB_VCC: C60306.1(A) R60305.1(A) R60309.2(B) U60300.9(VCC)
VRB_VDD5: C60209.1(A) R6161.2(B) R60000.1(A) R60309.1(A) U60600.11(VCC)
VRP1V05A: C60900.1(A) C60901.1(A) L60900.2(INB) PAD60900.1 U60600.19(O_1P05A)
VRP1V05A_PH: L60900.1(INA) U60600.22(LX_1P05A_0) U60600.23(LX_1P05A_1)
VRP1V5S: C61700.1(A) PAD61700.1 U60600.10(O_1P5S)
VRP1V8A: C7002.1(A) C60600.1(A) C60601.1(A) C60602.1(A) C60603.1(A) C60604.1(A) C61010.1(A) C61110.1(A) C61710.1(A) L60600.2(INB) U60600.3(O_1P8) U60600.7(IN_1P24A) U60600.8(IN_1P15A) U60600.9(IN_1P5S) U60600.14(SWIN_1P8A)
VRP1V8A_PH: L60600.1(INA) U60600.27(LX_1P8_0) U60600.28(LX_1P8_1)
VRP1V15: C61100.1(A) PAD61110.1 U60600.6(O_1P15A)
VRP1V24A: C61000.1(A) PAD61000.1 U60600.5(O_1P24A)
VRP3V3A: C6100.1(A) C6109.1(A) L6100.2 PAD6100.1 U6100.7
VRP3V3A_PH: C6115.2(B) L6100.1 U6100.8 U6100.9 U6100.15 U6100.16
VRP5V0A: C6150.1(A) C6166.2(B) C6169.1(A) L6150.2(INB) PAD6150.1 R6150.2(B) R6161.1(A) U6150.7
VRP5V0A_PH: C6165.2(B) L6150.1(INA) R6166.1(A) U6150.8 U6150.9 U6150.15 U6150.16
VRPCHG_LG: Q6000.8 U6000.15(LODRV)
VRPVCORE_HG1: Q6610.1 U6600.9
VRPVCORE_LG1: Q6610.8 U6600.12
VRPVCORE_PH1: C6615.1(A) L6610.1 L6610.3 Q6610.9 R7661.1(A) U6600.10
VRPVDDQ: C60300.1(A) C60301.1(A) C60302.1(A) C60303.1(A) C60304.1(A) L60300.2(INB) PAD60300.1 R60300.2(B) R60359.1(A) U60300.2(VDDQSNS)
VRPVDDQ_PH: C60315.1(A) L60300.1(INA) R60316.2(B) U60300.17(LX_1) U60300.18(LX_4) U60300.19(LX_3) U60300.20(LX_2) U60300.25(LX)
VRPVDDQ_VIN: C60310.1(A) C60311.1(A) PAD60310.1 R60306.2(B) U60300.21(V+_3) U60300.22(V+_2) U60300.23(V+) U60300.24(V+_1)
VRPVDDQ_VLDOIN: R60359.2(B) U60300.28(VLDOIN)
VRPVGG_HG1: Q6710.1 U6700.9
VRPVGG_LG1: Q6710.8 U6700.12
VRPVGG_PH1: C6715.1(A) L6710.1 L6710.3 Q6710.9 R7761.1(A) U6700.10
VRPVTT: C60350.1(A) PAD60350.1 U60300.29(VTT) U60300.31(VTTSNS)
VRPVTT_REF: C60351.1(A) PAD60351.1 U60300.1(VTTERF)
WLON: CN1300.56(W_DISABLE1*) U301.31(GPIO56/TA1)
XTAL_SOC_IN: C4509.2(B) R4543.1(A) U4500.P24(OSCIN) X4500.1
XTAL_SOC_OUT: C4510.2(B) R4543.2(B) U4500.M22(OSCOUT) X4500.3

Pads without a net: CN1300 6 8 9 10 11 12 13 14 15 16 17 19 20 21 22 23 32 34 36 38 40 42 44 46 48 50 58 59 60 61 62 64; CN3000 17 28; CN6000 5; D2409 1 6; D2410 1 6; D4501 2; D4700 2; D4701 2; D7000 2; D7200 2; D60000 2; FIX1 1; FIX2 1; FIX3 1; FIX4 1; FIX5 1; FIX6 1; FIX7 1; FIX8 1; FIX23 1; FIX24 1; FIX25 1; FIX26 1; FIX9113 1; FIX9114 1; FIX9115 1; FIX9116 1; ST1 1; U301 13 77 101 105 110 112; U500 4 14 16 23 24 48; U900 7 9 12 14 16 17 19 22 23; U3500 1 2 3 6 7 8 9 12 13 14; U3950 A1 A2 A7 A8 A9 A10 A11 A12 A13 A14 B1 B7 B8 B9 B10 B11 B12 B13 B14 C1 C3 C5 C7 C8 C9 C10 C11 C12 C13 C14 D1 D2 D3 D4 D12 D13 D14 E1 E2 E3 E5 E8 E9 E10 E12 E13 E14 F1 F2 F3 F10 F12 F13 F14 G1 G2 G3 G10 G12 G13 G14 H1 H2 H3 H12 H13 H14 J1 J2 J3 J12 J13 J14 K1 K2 K3 K6 K7 K10 K12 K13 K14 L1 L2 L3 L12 L13 L14 M1 M2 M3 M7 M8 M9 M10 M11 M12 M13 M14 N1 N3 N6 N7 N8 N9 N10 N11 N12 N13 N14 P1 P2 P7 P8 P9 P10 P11 P12 P13 P14; U4441 1; U4500 A3 A9 A13 A17 A21 A25 A27 A29 A33 A35 A37 A49 A51 A52 AA30 AA51 AB7 AB9 AB40 AB41 AB44 AB45 AB51 AB52 AC53 AD6 AD13 AD14 AE4 AF6 AF9 AF44 AF45 AF48 AF50 AG1 AG3 AH3 AH6 AH45 AK9 AK10 AK12 AK13 AK41 AK42 AK48 AM10 AM14 AM47 AM48 AT24 AT30 AU24 AU30 B4 B5 B7 B8 B10 B12 B16 B20 B24 B30 B34 B38 B46 B48 B49 B50 B52 B53 BD16 BD38 BF16 BF38 C7 C9 C11 C16 C17 C19 C21 C24 C25 C27 C29 C31 C33 C34 C35 C37 C38 C49 C51 C53 D2 D6 D12 D20 D30 D36 D48 D50 D52 E8 E52 E53 F2 F7 F10 F12 F20 F30 F36 F52 F53 G2 G20 G24 G32 G34 G36 G44 G52 G53 H3 H46 H47 H49 H50 J1 J3 J12 J14 J20 J24 J26 J28 J32 J34 J36 K3 K6 K7 K9 K10 K20 K26 K28 K38 K44 K47 K48 L13 L51 L53 M10 M12 M13 M20 M26 M28 M32 M34 M36 M38 M44 M47 M48 M51 M52 N26 N28 N34 N36 P18 P26 P28 P30 P34 P45 P47 P48 P50 T41 T42 T44 T45 T48 T50 V6 V7 V9 V10 V12 V13 V14 V45 V47 V48 V50 V51 V52 W51 W53 Y12 Y13 Y41 Y47 Y48 Y51 Y52; U4504 1; U6100 3; U6150 5 6; U60300 26; X4501 2 3

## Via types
v1: diameter 0.457, hole 0.254, TOP to BOTTOM, 2771 vias
v2: diameter 0.61, hole 0.305, TOP to BOTTOM, 398 vias
v3: diameter 0.61, hole 0.254, TOP to BOTTOM, 228 vias
v4: diameter 0.508, hole 0.254, TOP to BOTTOM, 108 vias
v5: diameter 0.762, hole 0.406, TOP to BOTTOM, 247 vias

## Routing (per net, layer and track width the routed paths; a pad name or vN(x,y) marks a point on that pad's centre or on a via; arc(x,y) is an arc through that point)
3V3A_PG: length 4.6
  TOP w0.254: R7206.1 77.29,137.41 v2(76.61,138.09) 76.17,138.54 v1(76.17,140.46)
  BOTTOM w0.254: U6100.4 v1(76.17,140.46)
5V_PG: length 1.7
  BOTTOM w0.254: U6150.4 95.28,140.46 95.68,140.06 R7241.1
AGND_AUDIO: length 16.7
  TOP w0.254: U500.38 9.82,49.57 9.6,49.35 8.79,49.35 v1(8.66,49.48) ; v1(8.73,55.7) 8.72,55.68 U500.25
  TOP w0.381: C525.1 v1(10.39,42.01) ; C523.1 v1(17.45,61.7) ; v1(15.36,58.52) 15.19,58.52 14.81,58.14 R501.2 ; v1(9.39,59.41) 9.7,59.11 R531.2 ; C524.1 6.78,48.67 v1(6.4,49.05) ; C502.1 7.7,58.22 v1(7.7,59) ; C501.2 v3(8.68,59.72)
  BOTTOM w0.381: C605.2 v1(14.53,88.64) ; v1(7.7,59) 7.46,58.76 C505.2 ; C600.2 7.11,82.27 v1(6.6,81.76) ; D600.3 v1(8.52,71.94) ; C604.2 R610.2 v1(6.62,91.18) ; C601.2 v1(5.93,82.9) ; C504.2 8.35,54.9 8.73,55.28 v1(8.73,55.7)
  BOTTOM w0.508: v1(15.36,58.52) 15.36,58.69 C531.2
  vias: v1(6.27,51.95) v1(8.68,48.84) v1(11.78,44.67) v1(14.25,72.36) v1(14.83,78.71)
AGND_KBC: length 4.2
  TOP w0.279: 69.05,160.32 69.27,160.32 69.57,160.63 U301.103
  TOP w0.381: 66.6,159.82 C305.2 67.73,159.82 68.23,160.32 69.05,160.32
  vias: v2(63.75,158.9)
DGND: length 1119.6
  TOP w0.203: U301.5 73.64,148.23 73.48,148.07 73.44,148.07 73.43,148.06 73.26,148.06 72.92,147.71 v1(72.92,147.57)
  TOP w0.254: C4108.2 51.93,110.83 v1(52.12,111.02) ; C4543.2 68.02,76.03 v1(68.59,75.46) ; C4152.2 27.93,91.75 v1(28.56,92.37) ; C4113.1 35.97,83.55 v1(35.99,83.54) 36.21,83.32 C4214.2 38.51,83.32 C4201.2 ; C4532.2 62.1,82.14 C4524.2 ; v1(37.51,57.27) 37.41,57.37 C4197.2 ; C4138.2 33.62,103.69 34.21,104.29 v1(34.21,104.34) ; v1(53.36,47.73) 53.1,47.47 C4177.2 ; C4541.2 69.47,80.22 68.78,80.91 v1(68.73,80.91) ; C4123.2 55.04,104.79 v1(54.75,105.08) ; v1(73.05,73.47) 73.03,73.44 R4712.2 ; R4555.1 65.58,86.16 65.06,85.64 65.06,85.26 65.52,84.8 C4519.2 66.32,84.73 v1(66.35,84.7) 66.35,83.98 C4605.2 ; U301.18 78.84,150.19 v1(78.15,150.88) ; C7531.2 66.39,47.78 v1(66.42,47.74) 66.44,47.73 C4180.2 ; v1(66.67,75.43) 66.28,75.82 C4527.2 C4528.2 ; C4143.2 49.7,99.43 v1(49.95,99.68) 49.63,100 C4151.2 ; C4104.2 67.03,113.18 v1(66.79,113.43) ; C4206.2 34.12,62.97 v1(34.2,62.97) 34.62,63.39 C7537.2 ; C4158.2 45.46,106.61 C4130.2 ; C4163.2 46.57,43.79 46.57,43.79 v1(46.39,43.61) ; v1(65.98,107.78) 65.97,107.77 65.97,107.77 65.8,107.6 C4105.2 ; C4159.2 34.69,110.98 ; C4545.2 67.56,75.62 v1(67.56,74.73) ; C4181.2 67.06,44.56 v1(66.41,44.56) 66.26,44.4 C4189.2 ; C4252.2 68.75,114.92 v1(69.15,115.31) 68.64,115.82 R4105.1 ; v1(29.89,78.71) 29.77,78.83 C4198.2 ; C4610.2 53.39,73.71 v1(53.14,73.46) ; v1(67.4,109.22) 67.68,109.5 C4118.2 ; C4183.2 58.78,44.66 v1(59.01,44.89) ; C4212.2 32.2,69.48 C4191.2 ; C7533.2 C4164.2 58,53.51 v1(57.06,52.56) ; C4210.2 33.72,76.31 v1(34.22,76.8) ; v1(66.42,46.15) 66.46,46.1 C4187.2 ; R4705.2 70.74,92.48 v1(70.48,92.73) 69.97,92.22 R4706.2 R4707.2 ; v1(31.83,92.2) 31.74,92.11 C4115.2 ; v1(52.1,108.6) 52.1,108.57 52.37,108.29 C4125.2 C4122.2 ; U301.89 74.84,163.34 v1(74.75,163.25) ; C4185.2 60.15,50.04 v1(60.66,50.55) ; v1(71.73,155.26) 71.56,155.43 U301.116 ; v1(27.55,98.68) 27.77,98.46 C4141.2 ; v1(52.82,43.89) 52.72,43.99 C4174.2 ; C4150.2 40.77,103.93 v1(40.77,104.5) 40.25,105.02 C4142.2 ; v1(34.2,90.5) 33.78,90.92 C4137.2 ; v1(59.85,52.17) 59.83,52.19 C4184.2 ; C4569.2 62.44,85.45 v1(62.45,85.45) 62.58,85.58 C4536.2 ; C4523.2 64.43,82.49 64.8,82.85 v1(64.8,83.19) ; R4504.1 56.71,81.59 57.21,82.09 v1(57.21,82.23) ; C4535.2 60.91,86.21 v1(60.87,86.25) ; C4593.2 C4552.2 C4551.2 C4595.2 71.48,87.01 71.84,87.01 v1(71.86,86.99) ; R4711.2 72.21,91.89 v1(72.38,92.07) ; v1(66.92,116.99) 66.68,117.22 C4119.2 ; v1(29.82,96.95) 30.32,97.45 C4134.2 ; C4139.2 39.79,97.74 v1(39.84,97.8) ; C4596.2 67.06,87.84 67.23,88.01 67.23,89.52 v1(67.62,89.91) 67.84,89.69 C4597.2 ; v1(79.32,163.47) 79.24,163.55 U301.78 ; C4126.2 59.6,117.63 v1(59.56,117.67) ; v1(45.25,51.37) 45.08,51.2 C4186.2 ; C4178.2 46.57,46.53 v1(45.98,46.53) ; v1(41.17,51.66) 40.62,52.2 C4107.2 ; C4205.2 38.1,69.74 v1(37.46,70.39) ; v1(59.47,58.26) 59.05,57.84 C4182.2 ; v1(35.89,92.33) 36.42,91.8 C4148.2 ; C4176.2 47.5,53.87 v1(47.6,53.77) 47.89,53.77 48.18,54.07 C4172.2 ; v1(70.43,76.53) 70.18,76.53 69.8,76.91 C4585.2 ; C4202.2 35.15,84.98 v1(35.04,84.87) ; C7539.2 C4191.2 ; C4191.2 32.97,70.05 v1(32.83,70.18) ; v1(59.49,109.47) 59.38,109.47 58.73,110.12 C4106.2 ; v1(72.35,89.96) 72.22,89.83 C4589.2 ; C4530.2 64.1,78.56 C4521.2 65,79.32 C4522.2 65.57,79.32 v1(65.64,79.38) 65.8,79.22 65.8,78.42 66.28,77.93 C4529.2 ; v1(26.99,78.44) 27.07,78.53 C4203.2 ; C4116.2 31.62,105.96 31.09,105.42 v1(31.09,105.18) 30.47,105.8 C4133.2 ; C4155.2 33.56,84.48 v1(33.79,84.7) ; C7536.2 33.35,58.07 C4193.2 33.33,57.43 v1(33.42,57.34) ; C4157.2 29.31,91.75 v1(29.82,92.27) ; C4591.2 70.58,90.28 v1(70.44,90.42) 70.13,90.42 69.67,89.97 C4599.2 ; C4110.2 66.2,115.35 C4127.2 66.8,115.34 66.86,115.4 v1(66.92,115.4) ; v1(66.46,50.12) 66.04,50.54 C4188.2 ; U301.45 87.2,155.43 v1(87.35,155.58) ; C4617.2 53.34,90.86 v1(53.21,91) ; C7540.2 v1(25.7,79.64) ; R4809.1 73.58,67.8 v1(73.48,67.7) ; C4146.2 39.33,92.69 v1(39.83,92.19) 39.89,92.13 C4149.2 ; C4168.2 47.21,57.81 v1(46.91,57.51) ; C4147.2 37.67,91.09 37.43,91.34 v1(37.41,91.34) ; v1(59.13,80.32) 59.2,80.38 R4505.1 ; C4135.2 37.4,98.71 v1(37.44,98.74) ; C4199.2 32.36,58.18 v1(31.83,58.18) 31.25,58.18 C4195.2 ; C4517.2 62.19,83.67 v1(61.66,83.14) ; C4170.2 53.82,56.69 v1(53.95,56.82) ; C4136.2 35.48,97.29 35.5,97.27 v1(35.5,97.01) ; C4140.2 v1(26.02,104.56)
  TOP w0.381: C4204.2 39.37,70.54 v1(39.17,70.33) 39.17,69.17 C4196.2 ; v1(61.66,79.34) 61.66,79.35 C4520.2 ; v1(61.66,79.34) 61.33,79.34 61.13,79.54 C4566.2 ; v1(61.66,79.34) 61.77,79.23 61.78,79.23 C4538.2 ; C524.2 6.79,49.52 6.62,49.69 v1(6.6,49.69) 6.37,49.92 C503.1 ; v1(18.2,62.87) 18.89,62.19 C523.2 ; R4815.1 65.83,67.39 v1(65.78,67.44) ; v1(27.01,77.22) 27.24,76.99 C7538.2 C4190.2 ; C7583.2 49.15,38.71 v1(48.84,39.01) ; C4173.2 32.32,65.16 v1(31.83,64.67) ; v1(114.7,151.18) 114.86,151.34 C3007.2 ; v1(77.35,147.54) 77.38,147.5 C316.2 ; C4208.2 36.08,60.43 v1(35.66,60.85) ; C4109.2 46.28,117.21 v1(46.16,117.09) ; v1(35.6,95.41) 35.62,95.41 35.66,95.37 C4114.1 ; v1(29.82,64.74) 29.89,64.67 C4207.2 ; C4211.2 35.28,56.7 35.66,57.08 v1(35.66,57.25) ; C4100.2 36.59,47.32 v1(36.13,46.86) 35.58,46.31 C4160.2 ; C4117.2 46.44,111.59 46.28,111.43 v1(46.26,111.43) 45.76,110.92 C4112.1 45.14,110.56 v1(44.97,110.38) ; C4518.2 64.03,88.87 v1(63.65,89.25) ; v1(100.25,40.03) 99.92,40.36 C3956.2 ; v1(23.05,64.48) 22.76,64.19 C4192.2 C7535.2 ; R4810.1 77.62,66.07 v1(76.72,66.07) ; C4550.2 66.95,84.99 66.5,85.44 v1(66.4,85.44) ; C4550.2 67.14,85.17 67.92,85.95 C4594.2 67.98,86.22 C4626.2 ; C4550.2 C4549.2 ; v1(63.86,56.18) 64.42,55.62 C4179.2 ; R4836.1 66.2,79.95 v1(65.64,79.38) ; v1(99.64,155.35) 99.51,155.22 R3021.2 ; C4557.2 70.31,79.69 v1(70.65,79.35) ; D7503.1 68.92,150.59 69.29,150.22 D7501.1 70.06,149.87 v1(70.3,150.11) ; C4625.2 77.83,73.03 v1(78.09,73.29) 77.87,73.51 C4514.2 ; v1(61.85,33.32) 62.31,32.86 C7546.2 ; C4129.2 66.71,105.3 v1(66.81,105.41) ; R4541.1 75.89,79.58 v1(76.07,79.41) ; C4601.2 68.74,82.33 C4600.2 68.89,82.41 69.48,82.41 v1(69.5,82.4) ; C18.2 19.04,50.92 18.64,50.52 v1(18.28,50.52) ; v1(68.72,79.4) 68.7,79.37 C4544.2 68.7,78.76 C4553.2 ; v1(43.45,48.53) 44.31,49.39 C7532.2 ; v1(65.66,150.24) 65.66,149.71 C312.2 ; C7537.2 C4209.2 ; v1(103.88,40.51) 104.26,40.14 C3960.2 ; R4902.2 v1(66.98,62.71) ; C4103.1 59.79,108.37 60.35,107.82 v1(60.37,107.82) 60.4,107.79 60.44,107.75 C4121.2 ; v1(73.76,103.89) 73.61,104.04 R4851.2 72.81,104.04 R4849.1 ; R4111.1 69.49,117.59 69.11,117.2 v1(69.11,116.7) C4251.2 ; C7528.2 C4166.2 60.11,40.43 v1(59.86,40.18) ; C7511.2 88.41,135.69 v1(88.49,135.61) ; C4124.2 46.65,109.6 v1(46.45,109.39) ; C304.2 66.04,164.32 v1(65.86,164.13) ; v1(71.88,78.42) 72.06,78.24 C4562.2 71.59,77.84 71.51,77.76 C4548.2 70.94,77.09 C4559.2 ; C4590.2 73.75,88.88 v1(73.48,89.15) 73.95,89.62 C4598.2 ; C4175.2 38.34,57.36 38.98,57.36 v1(39.01,57.38) ; v1(73.34,83.22) 73.34,83.08 72.71,82.44 C4542.2 ; v1(83.56,69.59) 83.64,69.51 C7519.2 ; v1(35.81,103.55) 35.91,103.65 C4153.2 ; C7514.2 v1(42.9,133.62) ; C4584.2 67.6,74.77 v1(67.56,74.73) ; v1(25.12,47.4) 24.74,47.78 C7574.2 ; v1(68.81,56.26) 69.08,56.54 C7522.2 ; R4700.1 71.02,99.66 71.5,99.19 v1(71.5,99.03) ; R4542.1 74.51,80.49 v1(74.64,80.37) ; C4158.2 46.31,106.38 v1(46.51,106.19) ; v1(113.79,151.18) 113.92,151.31 R20.2 ; v1(90.38,156.92) 90.38,155.84 89.88,155.34 C302.2 89.88,153.48 C301.2 89.87,153.47 C310.2 ; v1(69.33,163.24) 69.33,163.44 69.72,163.83 C6037.2 ; C4561.2 73.31,78.21 v1(73.31,78.44) 73.83,77.92 C4555.2 ; CN901.6 v1(30.52,21.01) ; C7584.2 v1(25.17,76.36) ; v1(87.35,155.58) 88.21,155.58 C303.2 ; R7502.2 v1(15.57,123.24) ; C3952.2 99.9,34.86 v1(100,34.95) ; C4532.2 62.1,82.7 v1(61.66,83.14) 61.24,83.14 C4573.2 ; C7534.2 C4163.2 ; C7534.2 46.61,42.9 C4171.2 46.46,43.54 v1(46.39,43.61) ; C7534.2 C4165.2 47.03,42.01 v1(46.54,41.53) 46.94,41.12 R4174.1 ; C4604.2 75.04,68.61 75.04,67.96 75.04,67.95 v1(75.04,67.92) 75.18,68.06 C4581.2 ; C525.2 v1(10.39,39.8) ; v1(73.05,73.47) 73.05,74.03 R4521.1 ; 34.69,110.98 34.58,110.87 v1(34.58,110.43) ; v1(65.38,155.73) 65.48,155.83 C313.2 ; v1(66.54,72.7) 67.13,72.7 C4583.2 ; v1(66.62,129.64) 66.06,129.08 C7111.2 ; C3954.2 104,34.36 103.57,33.92 v1(103.42,33.92) ; v1(67.95,156.78) 68.36,156.38 C300.2 ; v1(74.67,78.43) 74.72,78.38 R4820.2 ; C4556.2 C4563.2 72.12,79.59 v1(71.9,79.37) ; v1(78.53,69.95) 77.98,69.95 C4608.2 C4603.2 ; R4574.2 70.96,67.46 v1(71.31,67.12) ; v1(81.68,143.41) 81.54,143.55 R333.2 ; C4144.2 39.88,60.54 39.89,60.52 39.89,60.11 v1(39.9,60.1) ; C4131.2 45.81,114.4 v1(45.97,114.56) ; C4652.2 68.75,66.79 v1(69.01,66.53) ; C4513.2 78.25,74.68 v1(78.43,74.85) ; C13.2 62.91,129.08 v1(62.4,129.59) ; C4592.2 68.97,87.63 v1(69.53,87.06) ; C3009.1 80.82,138.1 v1(80.67,138.25) ; v1(71.27,83.2) 70.98,82.91 C4560.2 C4558.2 ; R7501.2 14.54,124.62 v1(14.27,124.89) ; C510.2 18.49,52.48 v1(18.62,52.35) ; CN901.3 v1(29.39,12.34) ; C7529.2 68.46,51.9 C4167.2 R4177.1 C4169.2 68.46,54.04 v1(68.02,54.49) ; C4154.2 30.34,84.11 v1(30.23,84.21) ; C7572.2 43.25,113.84 v1(42.85,113.44) ; v1(61.7,67.88) 61.31,67.49 B500.2 ; R4901.2 v1(67.94,62.71) ; R4107.1 R4101.1 52.52,116.98 52.86,116.64 v1(53.77,116.64) ; D7152.1 15.36,137.71 v1(15.54,137.9) ; v1(100.89,39.06) 101.43,38.52 C3955.2 ; D3950.2 101.17,33.27 v1(101.65,33.27) 102.17,33.27 C3957.2 ; C4570.2 75.03,71.69 v1(74.38,71.04) 74.14,71.28 C4606.2 ; C4586.2 63.34,76.32 C4531.2 62.98,75.66 v1(62.72,75.4) ; v1(61.68,76.35) 61.59,76.44 C4539.2 ; v1(60.9,77.85) 60.73,77.68 60.33,77.68 C4571.2 ; R4843.1 v1(77.29,68.07) ; R4837.1 77.94,90.99 v1(78.05,90.88) ; v1(27.29,57.13) 26.91,56.75 C4194.2 ; C3014.2 v1(98.63,150.01) ; R4533.1 69.43,95.6 v1(69.83,95.2) ; C4101.2 35.3,47.42 v1(35.67,47.42) ; C4120.2 59.32,114.08 v1(59.08,113.84) ; v1(19.2,54.99) 19.01,55.18 R503.2 18.36,55.17 C506.1 ; C306.2 67.93,149.89 67.89,149.94 67.81,149.94 v1(67.67,150.09) 67.67,150.36 R391.1 ; v1(65.05,119.18) C7573.2 ; C4582.2 63.23,68.26 63.69,67.8 63.69,67.79 v1(63.72,67.76) ; v1(59.76,69.77) 59.75,69.76 C4587.2 ; CN901.G1 v1(26.9,27.86) ; v1(70.43,105.67) 71.05,105.67 C7552.2 ; R3150.2 v1(16.66,141.12) ; C3151.2 v1(15.74,141.1) ; CN901.G2 v1(26.95,2.91) ; Q3003.2 98.52,157.5 v1(97.65,157.5) ; v1(58.63,112.37) 58.56,112.43 C4128.2 ; C4588.2 72.64,86.33 72.86,86.33 73.12,86.07 73.27,86.07 v1(73.29,86.06) 73.28,86.05 73.28,85.65 72.89,85.27 R4676.2 ; C4145.2 v1(25.49,85.29) ; v1(53.84,113.37) 53.84,113.37 53.89,113.32 C4111.2 ; C4213.2 34.93,70.32 v1(35.03,70.42) ; C3958.2 v1(101.78,40.53) 101.78,40.61 101.2,41.19 R3965.2 ; C1305.2 47.86,132.45 v1(48.1,132.21)
  BOTTOM w0.076: U3950.N2 104.46,37.71 104.71,37.96 105.24,37.96
  BOTTOM w0.089: v1(33.42,57.34) 33.42,57.94 33.78,58.29 33.78,58.52 U4106.J2 ; 65.74,49.75 65.34,50.15 65.06,50.15 U4104.J2
  BOTTOM w0.102: U4102.J2 33.67,85.95 33.67,85.68 33.42,85.43 ; U4105.J2 52.11,50.05 52.31,50.05 52.65,49.71 53.1,49.71 ; 59.65,111.8 60.16,111.8 60.49,111.48 60.69,111.48 U4100.J2 ; 33.41,70.49 33.41,71.01 33.82,71.42 U4107.J2 ; 33.41,98.03 33.41,98.54 33.82,98.95 U4103.J2
  BOTTOM w0.127: v1(33.79,84.7) 33.42,85.07 33.42,85.43 ; 65.74,49.75 66.1,49.75 v1(66.46,50.12) ; 46.29,111.45 46.63,111.79 47.11,111.79 47.46,111.44 47.67,111.44 U4101.J2
  BOTTOM w0.152: U4500.AV27 59.33,80.51 v1(59.13,80.32)
  BOTTOM w0.178: v1(99.95,36.23) 99.92,36.23 U3950.C4 ; U3950.P4 U3950.N5 ; U3950.A6 v1(97.76,35.71)
  BOTTOM w0.203: v1(65.64,79.38) 65.59,79.34 65.59,79.17 65.59,79.16 65.59,78.84 65.59,78.84 65.59,78.64 U4500.AD21
  BOTTOM w0.254: U4500.T47 69.6,90.67 U4500.U46 U4500.U45 ; U4500.T47 70.44,90.54 v1(70.44,90.42) 70.44,89.38 U4500.P42 ; U4500.T47 69.6,91.38 U4500.U48 U4500.U49 ; U4105.D8 v1(47.6,53.77) 47.21,53.38 U4105.E8 ; U4102.E8 37.02,90.95 v1(37.41,91.34) 37.43,91.34 37.82,90.94 U4102.D8 ; U4105.T9 46.41,43.64 v1(46.39,43.61) ; U4500.BG40 54.86,87.56 55.07,87.35 55.07,87.16 55.23,86.99 ; v1(60.75,90.63) 60.44,90.32 U4500.AT45 ; v1(103.42,33.92) 103.42,34.38 103.08,34.71 U3950.K8 ; U4500.U33 69.9,84.31 69.51,83.92 v1(69.51,83.92) ; U4105.B3 50.71,55.75 v1(50.64,55.68) ; v1(45.98,46.53) 46.37,46.15 U4105.P9 ; U4500.H8 73.9,72.03 74.38,71.55 74.38,71.07 74.38,71.07 v1(74.38,71.04) 74.43,70.98 74.62,70.98 U4500.F5 ; 55.23,86.99 U4500.BG38 ; 55.23,86.99 55.58,86.99 v1(55.73,87.15) ; U4500.AW27 58.62,81.4 U4500.AY28 ; U4500.AW27 U4500.AV27 U4500.AT27 60.52,81.28 U4500.AN29 61.31,82.03 62.06,82.79 U4500.AM30 ; U4500.AW27 U4500.BA27 ; v1(52.24,79.28) 52.34,79.39 53.72,79.39 U4500.BJ23 ; U4102.D1 37.82,84.43 v1(37.78,84.39) 37.02,85.15 U4102.E1 37.02,85.44 37.08,85.5 37.08,85.89 37.02,85.94 U4102.E2 ; v1(77.92,78.35) 77.92,77.9 U4500.A19 ; v1(32.52,107.99) 32.91,108.38 R4109.1 ; v1(61.98,105.43) 61.97,105.44 61.92,105.44 61.58,105.79 U4100.B3 ; U4500.BG19 54.86,77.05 U4500.BG18 ; U4500.BG19 54.86,77.73 U4500.BG20 ; U4500.BG19 U4500.BJ19 v1(53.2,77.39) ; U4106.E1 37.02,57.75 v1(37.51,57.27) 37.82,57.58 U4106.D1 U4106.E2 ; U60300.32 40.62,24.47 v1(39.65,23.49) ; U4107.G1 35.42,70.82 35.03,70.42 v1(35.03,70.42) ; U4500.U36 69.9,85.87 70.08,86.04 70.08,86.41 U4500.U38 69.9,86.69 v1(69.53,87.06) ; v1(52.88,87.06) 53.46,87.06 53.49,87.09 53.76,87.09 U4500.BJ39 ; U4500.BA19 U4500.AY20 v1(57.96,78.32) U4500.AY22 ; U4500.BA19 58,77.3 58.53,77.3 U4500.AW19 U4500.AV19 U4500.AT19 60.13,77.48 60.57,77.48 60.9,77.81 v1(60.9,77.85) 61.28,78.22 U4500.AN21 ; U4500.BA19 U4500.BB19 U4500.BD19 U4500.BE19 ; v1(78.53,69.95) 78.5,69.95 78.35,70.11 U4500.A5 ; U4500.AN45 61.58,89.96 U4500.AP45 61.58,90.67 U4500.AN46 ; U4500.AN45 U4500.AN43 U4500.AN42 U4500.AN40 ; U4500.AN45 U4500.AN46 ; 65.59,87.07 65.2,86.68 U4500.AF38 65.22,86.58 U4500.AD36 65.98,85.82 66.36,85.44 v1(66.4,85.44) 66.4,85.4 66.74,85.07 U4500.AC35 ; 65.59,87.07 U4500.AE40 U4500.AE42 U4500.AE43 65.71,89.25 U4500.AD44 65.71,89.96 U4500.AE45 U4500.AE46 65.47,90.67 U4500.AF47 ; 65.59,87.07 65.66,87 66.56,87 66.77,86.8 U4500.AC38 U4500.AA38 U4500.Y38 U4500.V38 69.12,86.65 v1(69.53,87.06) ; U4500.AE53 65.59,94.77 v1(65.76,94.93) ; U4500.AT36 60.39,85.52 U4500.AT35 U4500.AV35 U4500.AW35 U4500.BA35 ; v1(69.83,95.2) 69.81,95.2 69.48,94.87 U4500.U53 ; U4500.J38 73.63,86.48 73.29,86.14 v1(73.29,86.06) 72.92,85.69 U4500.K36 ; v1(71.86,86.99) 72.04,87.17 U4500.M40 72.46,88.03 U4500.L41 73.07,88.03 U4500.J42 73.48,88.74 v1(73.48,89.15) ; v1(59.75,67.76) 59.75,68.45 U4500.AU1 ; U4500.BF27 55.6,81.65 U4500.BF28 ; U4500.BF27 55.6,80.9 U4500.BF26 ; U4500.BF27 U4500.BG27 U4500.BJ27 53.4,81.28 53.31,81.19 v1(53.21,81.19) ; U4103.T9 26.22,104.75 v1(26.02,104.56) 25.85,104.73 C4156.2 ; U4105.J8 v1(46.83,50.54) ; U4102.G8 35.42,91.06 35.47,91.11 35.47,91.5 35.42,91.55 U4102.G9 35.42,91.87 v1(35.89,92.33) 36.22,92 U4102.F9 ; U4500.AT9 60.02,72 v1(59.75,72) ; U4500.U45 U4500.U43 ; U4500.U45 69.36,89.96 U4500.V44 U4500.V42 ; U4500.N32 v1(71.27,83.2) 70.79,83.68 U4500.P32 70.62,83.72 70.46,83.55 U4500.U32 69.85,83.55 69.51,83.88 v1(69.51,83.92) ; U4500.AV30 U4500.AY30 U4500.BA30 57.21,82.38 v1(57.21,82.23) 57.21,82.12 U4500.BC28 ; U4500.AH9 63.78,71.87 v1(63.7,71.87) 63.5,71.87 U4500.AK7 ; v1(70.43,76.53) 70.11,76.53 U4500.U18 ; U4500.U42 69.12,88.18 U4500.V41 ; U4500.U42 U4500.U40 69.48,87.11 v1(69.53,87.06) ; U4500.U42 U4500.U43 ; U4500.K50 72.56,92.07 v1(72.38,92.07) 72.04,92.41 U4500.M50 ; v1(69.01,66.53) 68.53,67.01 68.53,68.38 68.51,68.4 U4500.W1 ; v1(69.15,115.31) 69.44,115.61 C4132.2 ; U4500.AH14 U4500.AH13 63.88,74.1 v1(63.6,74.1) ; v1(59.01,51.42) 59.35,51.75 U4104.G9 ; U4107.D8 37.82,76.42 v1(37.44,76.81) 37.37,76.74 37.05,76.42 U4107.E8 ; v1(27.55,98.68) 27.89,98.68 U4103.T1 ; U4107.F9 35.85,77.59 v1(35.82,77.59) ; v1(55.52,106.87) 55.51,106.88 55.51,106.88 54.16,108.24 54.08,108.24 U4101.F9 U4101.G9 U4101.G8 ; v1(77.52,86.61) 77.4,86.72 U4500.A39 ; v1(60.37,107.82) 60,108.19 U4100.E1 ; v1(60.37,107.82) 60.74,108.19 U4100.E2 ; v1(60.37,107.82) 59.97,107.42 U4100.D1 ; U4500.AM4 61.7,69.64 U4500.AN3 ; U4500.AM4 61.89,70.46 U4500.AN5 ; U4500.AM4 62.5,69.84 v1(62.62,69.84) 62.86,69.84 U4500.AK4 63.65,69.64 U4500.AJ3 ; v1(63.65,89.25) 64,89.61 U4500.AH44 ; v1(63.65,89.25) 64,88.89 U4500.AH42 U4500.AH41 ; v1(63.65,89.25) 63.51,89.25 U4500.AK44 63.25,89.71 63.25,90.21 U4500.AK45 63.28,90.32 v1(63.64,90.68) ; U4500.BA35 57.91,85.04 U4500.AY34 58.56,84.39 v1(58.56,84.21) 58.56,84.01 U4500.AY32 ; U4500.BA35 U4500.BB35 U4500.BD35 U4500.BE35 U4500.BG35 ; v1(36.88,68.58) 36.88,67.28 35.42,65.82 U4106.G9 U4106.G8 ; v1(76.08,72.5) 75.76,72.82 U4500.D10 ; v1(60.77,72) 61,72 U4500.AP9 ; v1(67.54,70.48) 67.21,70.81 U4500.AB6 ; v1(67.54,70.48) 67.68,70.48 U4500.Y4 ; v1(67.54,70.48) 67.19,70.14 U4500.AB4 ; U4106.M9 31.42,64.26 v1(31.83,64.67) ; U4106.T1 27.82,58.17 27.03,58.17 27.02,58.18 v1(26.54,58.18) ; U4500.AF25 U4500.AF24 65.26,79.76 v1(65.64,79.38) ; U4500.AF25 65.55,80.87 v1(65.55,80.9) ; U4500.AF25 65.12,80.52 65.03,80.43 64.58,80.43 64.49,80.52 U4500.AG25 U4500.AJ25 63.24,80.13 v1(63.24,80.13) 62.85,80.52 U4500.AK25 62.85,80.62 62.77,80.7 62.77,81.09 62.85,81.17 U4500.AK27 U4500.AM27 62.82,82.03 U4500.AK29 ; U4104.F9 59.47,52.55 v1(59.85,52.17) 60.26,51.75 U4104.G8 ; v1(63.86,56.18) 64.26,55.78 U4104.B3 ; U4500.AM50 62.58,92.79 v1(62.64,92.79) 62.77,92.79 U4500.AK50 63.27,92.41 v1(63.57,92.72) 63.65,92.79 U4500.AJ51 ; U4500.BD1 56.3,68.3 55.99,67.99 55.99,67.75 v1(55.73,67.5) ; U4500.U30 69.86,82.79 69.5,82.43 v1(69.5,82.4) 69.86,82.03 U4500.U29 ; 53.1,49.71 v1(53.3,49.91) ; v1(53.15,85.16) U4500.BJ35 53.86,85.25 54.43,85.25 U4500.BG35 ; v1(55.51,69.57) 55.43,69.65 U4500.BF4 55.43,70.32 55.06,70.7 U4500.BG5 ; v1(54.5,56.08) 53.35,54.92 53.35,54.66 52.84,54.15 U4105.D1 U4105.E1 U4105.E2 ; U4500.Y40 68.74,88.18 U4500.V41 ; 33.78,97.58 33.41,97.95 33.41,98.03 ; 33.78,97.58 33.78,97.25 35.6,95.43 v1(35.6,95.41) ; 33.78,97.58 33.36,97.17 32.04,97.17 31.42,97.79 U4103.M1 ; v1(78.43,74.85) 77.84,75.45 U4500.A15 ; U4105.B1 52.89,55.75 v1(53.95,56.82) ; U4500.C20 76.32,77.58 v1(76.04,77.3) 76.04,77.3 75.95,77.39 U4500.E19 U4500.F19 U4500.H19 U4500.J19 ; v1(23.05,64.48) 23.31,64.48 23.89,65.07 R4182.1 ; U4500.AN5 61.39,70.14 U4500.AP4 ; U4500.AN5 U4500.AN6 U4500.AN8 ; U4500.AJ18 63.56,76.66 63.56,76.04 U4500.AJ16 U4500.AK16 62.85,75.52 v1(62.72,75.4) ; U4500.AV14 59.1,74.95 U4500.AW13 58.68,74.19 58.77,74.09 v1(58.77,73.92) ; v1(101.32,36.73) 101.43,36.61 U3950.G5 ; v1(55.04,89.03) 55.08,88.99 55.08,88.96 U4500.BF42 ; U4100.F9 66.37,108.99 v1(65.96,109.4) 65.57,109.79 U4100.G8 ; v1(39.17,70.33) 39.42,70.59 U4107.B1 ; U4106.D8 37.82,63.35 37.45,62.97 37.45,62.97 ; U4500.BG36 54.52,85.31 U4500.BG35 ; v1(72.23,141.38) 72.21,141.35 72.21,140.99 72.35,140.86 U6100.14 ; v1(30.23,84.21) 30.33,84.21 U4102.M1 ; U4500.C36 76.32,85.83 v1(76.07,86.08) 75.73,86.43 U4500.D38 ; U4500.C36 U4500.B36 ; U4500.C36 75.84,85.16 U4500.E35 U4500.F35 U4500.H35 ; U4106.M1 v1(31.83,58.18) ; U4500.G12 73.96,74.34 v1(73.96,74.4) 74.34,74.78 U4500.G14 ; v1(41.3,23.75) 41.42,23.87 U60300.30 ; U4500.BC16 v1(56.4,75.44) ; U4500.BG35 54.86,84.82 U4500.BG34 ; U4500.J19 U4500.L19 U4500.M19 U4500.P19 ; U4500.J19 73.28,77.27 U4500.J18 73.86,76.68 73.86,76.4 v1(73.86,76.4) ; 61.7,92.91 U4500.AP50 61.52,92.1 U4500.AN49 ; 61.7,92.91 U4500.AN51 61.7,93.38 61.62,93.47 61.62,93.96 61.7,94.05 U4500.AN53 61.62,94.17 61.62,94.66 61.61,94.67 v1(61.61,94.68) ; 61.7,92.91 U4500.AN49 ; U4500.F1 v1(75.04,67.92) ; v1(78.69,71.02) 78.18,71.53 U4500.A7 ; U4105.T1 52.81,43.9 v1(52.82,43.89) ; CN1300.39 42.32,124.75 41.48,125.6 40.68,125.6 v1(40.57,125.71) ; U3950.E7 100.33,35.21 100.07,34.95 v1(100,34.95) ; CN1300.7 34.32,124.6 v1(34.22,124.7) ; U4500.BC28 57.19,81.4 U4500.BB27 ; U4500.BC28 56.48,81.4 U4500.BD27 ; U4500.V42 69.12,88.89 U4500.U43 ; U4500.V42 U4500.V41 ; U4500.V32 69.14,83.55 69.51,83.92 v1(69.51,83.92) ; v1(37.44,98.74) 37.02,99.15 U4103.E2 ; v1(37.44,98.74) U4103.D1 ; v1(37.44,98.74) 37.05,98.35 U4103.E1 ; U4500.AY51 58.17,92.87 57.75,92.87 57.72,92.84 v1(57.7,92.84) 57.69,92.83 57.52,92.83 57.28,92.6 U4500.BB50 ; U4500.BJ11 53.18,73.5 v1(53.14,73.46) ; U4500.AE50 U4500.AE48 65.47,91.38 U4500.AF47 ; v1(71.42,69.75) 71.03,70.14 U4500.P4 ; U4500.Y29 68.31,82.03 v1(67.92,81.64) 67.55,81.28 U4500.AA27 67.53,81.28 U4500.AC29 ; v1(56.78,72.45) 56.78,72.93 U4500.BC10 ; U4500.U25 69.81,80.43 69.21,80.43 U4500.V25 69.12,80.56 68.77,80.91 v1(68.73,80.91) ; U4500.K45 72.7,90.32 v1(72.35,89.96) 71.99,90.32 U4500.M45 ; v1(78.86,89.12) 78.79,89.05 U4500.A43 ; U4500.AY7 58.13,71.67 57.96,71.67 v1(57.76,71.88) 57.76,71.88 58.11,72.24 U4500.AY9 ; U4500.Y21 U4500.V21 69.12,78.2 69.48,77.84 v1(69.5,77.84) ; U4500.Y21 U4500.Y19 ; U4500.Y21 U4500.Y22 68.34,79.01 v1(68.72,79.4) 68.37,79.76 U4500.Y24 ; v1(55.07,90.08) 54.88,90.27 U4500.BG47 ; U4500.AC33 66.38,84.7 v1(66.35,84.7) ; U4500.AN46 U4500.AN48 U4500.AN49 ; U4500.BF22 v1(55.18,79.31) U4500.BG24 ; 59.65,111.8 59.14,111.8 58.64,112.3 58.64,112.35 v1(58.63,112.37) ; v1(73.31,78.44) 73.31,78.45 U4500.K22 ; v1(32.82,124.59) CN1300.1 ; U4500.A47 78.04,90.9 v1(78.05,90.88) ; v1(39.79,72.88) 39.42,72.51 U4107.B3 ; U4500.K36 72.83,85.64 72.57,85.37 U4500.L35 U4500.M35 U4500.P35 70.79,85.52 U4500.P36 ; U4500.K36 72.93,85.64 73.28,85.29 U4500.J35 73.28,85.03 72.93,84.69 U4500.K34 U4500.K32 ; U4500.G28 74.59,81.51 74.59,81.39 U4500.F27 U4500.D27 76.31,81.63 U4500.C28 ; U4500.G28 73.99,81.4 U4500.H27 U4500.J27 U4500.L27 U4500.M27 U4500.P27 ; U4500.G28 74.59,82 v1(74.59,82.22) ; U4500.BA27 U4500.BB27 ; U4500.BA27 57.91,81.16 U4500.AY26 ; v1(62.67,89.28) 62.56,89.28 U4500.AM42 ; U60600.15 100.25,113.69 100.3,113.64 v1(100.3,113.64) ; U4500.AB14 67.02,75.08 v1(66.67,75.43) 66.67,75.87 U4500.AC16 ; U4102.B9 39.42,91.79 v1(39.83,92.19) 40.22,91.8 U4102.A9 ; v1(64.67,72.59) 64.76,72.59 U4500.AF10 ; U4500.AM16 61.68,76.35 v1(61.68,76.35) ; v1(52.18,66.12) 52.18,66.15 v1(53.38,67.34) 53.8,67.77 v1(53.8,67.82) 53.8,68.06 U4500.BH1 ; U4500.T14 69.62,75.42 v1(69.55,75.42) ; U4107.T9 27.01,77.22 v1(27.01,77.22) ; U4100.A9 66.62,104.99 66.81,105.18 v1(66.81,105.41) 66.81,105.6 66.62,105.79 U4100.B9 ; U4500.AY45 58.13,90.32 57.71,90.74 ; v1(58.96,48.16) 59.37,47.75 U4104.M9 ; v1(59.13,80.32) 59.16,80.29 59.16,80.01 U4500.AV24 U4500.AY24 ; U4100.B1 59.47,105.79 v1(59.4,105.87) ; U4500.BF32 55.45,83.58 55.2,83.33 55.2,83.25 v1(55.19,83.24) 55.18,83.23 55.18,83.05 54.87,82.73 U4500.BG30 ; U4500.AB12 U4500.AB13 66.86,74.55 v1(66.54,74.55) ; v1(52.1,108.6) 52.12,108.6 U4101.E8 U4101.D8 ; U4106.F9 36.22,65.27 37.67,66.71 37.67,67.77 v1(37.87,67.97) ; U4500.D16 76.02,75.65 v1(76.02,75.41) ; R4178.1 58,41.03 v1(57.22,40.26) ; U4100.J8 v1(65.17,110.99) ; U4500.BC14 v1(56.44,74.39) ; U4500.AB47 67.22,91.03 67.59,91.4 v1(67.59,91.41) ; v1(67.56,74.73) 67.57,74.74 67.69,74.74 67.73,74.78 U4500.Y14 ; v1(46.91,57.51) 46.91,57.51 46.41,57.02 46.41,57.02 U4105.A9 U4105.B9 ; U4500.AT18 60.39,76.72 v1(60.74,76.37) 61.14,75.97 U4500.AN16 ; v1(48.93,105.42) 48.55,105.79 U4101.B3 ; v1(72.52,96.01) 73.37,95.17 U4500.J53 ; v1(29.82,92.27) 29.82,92.27 U4102.P9 ; U4500.AN1 v1(61.7,67.88) ; v1(74.67,78.43) 74.34,78.76 U4500.G22 ; U4500.BH1 54.37,68.62 U4500.BH2 ; U4500.BH1 U4500.BG1 ; U4103.J8 33.82,103.95 v1(34.21,104.34) ; v1(35.5,97.01) 35.52,97.02 35.52,97.28 35.49,97.31 35.49,98.29 U4103.G1 ; U4500.BF12 55.09,73.6 v1(55.09,73.45) ; U4500.BC40 56.81,87.6 v1(56.35,87.14) 56.35,87.1 U4500.BC38 ; U4500.BJ7 53.26,71.66 v1(53.22,71.62) ; v1(71.9,79.37) 71.95,79.37 72.21,79.63 U4500.M24 ; U4105.G8 47.21,51.75 U4105.F9 46.31,52.55 v1(45.93,52.17) 46.34,51.75 U4105.G9 ; U4104.D1 v1(65.47,53.77) U4104.E2 ; v1(66.41,44.56) 66.41,44.55 U4104.T1 ; U4500.K16 72.92,75.74 v1(73.25,75.41) 73.25,75.28 U4500.K14 U4500.M14 ; v1(39.84,97.8) 39.42,98.22 U4103.B1 ; U4500.AM30 62.82,83.55 U4500.AK32 ; U4500.AM30 61.71,83.14 v1(61.66,83.14) 61.63,83.14 U4500.AN30 ; U4500.BB27 57.19,81.16 U4500.BC26 56.84,80.76 57.19,80.4 v1(57.19,80.32) 57.19,80.18 U4500.BA24 ; U4104.J8 60.26,50.15 v1(60.66,50.55) ; U4500.AN9 U4500.AN11 U4500.AN12 61.82,74.01 U4500.AM13 61.95,74.6 61.83,74.6 U4500.AN14 61.7,75.37 61.68,75.39 v1(61.68,75.47) ; 105.24,37.96 v1(105.41,38.13) ; U4500.A11 77.88,73.5 v1(78.09,73.29) ; U4500.F24 74.7,80.18 74.7,80.31 v1(74.64,80.37) 74.61,80.39 74.61,80.53 U4500.G26 ; v1(63.64,90.68) 63.87,90.68 64.14,90.95 U4500.AH47 64.41,91.03 64.45,91.07 64.84,91.07 64.88,91.03 U4500.AF47 ; v1(63.64,90.68) 63.29,91.03 U4500.AK47 ; U4107.P9 v1(29.44,76.83) ; U4500.N24 71.57,79.9 72.14,79.9 U4500.M24 ; U4106.P9 29.82,64.74 v1(29.82,64.74) ; v1(28.56,92.37) 28.22,92.04 U4102.T9 ; U4103.B3 39.4,99.95 v1(39.01,99.56) ; U4106.B3 39.42,59.62 v1(39.9,60.1) ; v1(54.43,94.67) 54.43,94.62 54.82,94.23 U4500.BG53 54.82,93.95 U4500.BH52 ; v1(32.78,81.78) 32.78,81.78 R4181.1 ; v1(101.65,33.27) 101.93,33.56 U3950.H10 ; v1(53.21,91) 53.31,90.9 U4500.BJ47 ; CN3000.6 70.03,151.51 69.88,151.36 R3061.1 69.88,150.54 v1(70.3,150.11) ; U4101.J8 52.49,111.39 v1(52.12,111.02) ; U4105.G1 52.81,51.75 54.26,51.75 54.88,52.37 56.87,52.37 v1(57.06,52.56) ; v1(32.83,70.18) 33.1,70.18 33.41,70.49 ; v1(73.48,67.7) 73.15,67.7 U4500.L1 ; U4500.K12 72.93,73.59 v1(73.05,73.47) ; R4187.1 23.93,65.99 23.06,65.12 v1(23.05,65.12) ; 37.45,62.97 37.05,63.37 U4106.E8 ; 37.45,62.97 v1(37.45,62.97) ; U4104.B9 U4104.A9 59.46,58.13 59.47,58.14 v1(59.47,58.26) ; U4500.C30 76.32,83.07 v1(76.16,83.23) 75.73,83.66 U4500.D32 U4500.F32 ; v1(53.17,83.2) 53.18,83.2 53.18,83.21 53.2,83.21 53.2,83.23 53.24,83.23 53.24,83.19 53.24,83.19 53.28,83.22 U4500.BJ31 ; v1(35.66,57.25) 35.42,57.49 U4106.G1 ; v1(70.46,71.82) 70.37,71.82 U4500.T9 ; U4100.D8 65.59,107.39 65.97,107.77 65.97,107.77 v1(65.98,107.78) 65.95,107.78 65.57,108.16 U4100.E8 ; v1(65.78,67.44) 65.59,67.63 U4500.AE1 ; v1(29.82,96.95) 29.82,96.95 U4103.P1 ; v1(58.06,88.09) 58.13,88.03 U4500.AW41 59.1,87.6 U4500.AV40 ; v1(66.75,110.21) 66.37,109.84 U4100.G9 ; U7100.11 v1(89.07,126.47) ; U4500.C39 76.14,87.11 v1(76.07,87.17) 76.07,87.26 U4500.D40 75.73,88.21 U4500.D42 76.07,88.93 v1(76.07,89.03) ; v1(69.55,75.42) 69.12,75.85 U4500.V16 ; v1(69.55,75.42) 69.48,75.34 U4500.U14 ; U4104.T9 59.35,44.55 v1(59.01,44.89) ; U4500.K24 U4500.M24 ; v1(28.56,64.64) 28.22,64.3 U4106.T9 ; v1(39.36,84.33) 39.42,84.39 U4102.B1 ; v1(54.75,105.08) 54.66,104.99 U4101.A9 U4101.B9 ; U4500.G30 U4500.J30 U4500.K30 72.92,82.89 73.25,83.22 v1(73.34,83.22) ; U4500.AK40 63.2,87.47 63.56,87.11 v1(63.58,87.11) 63.58,87.11 63.49,87.11 62.96,86.58 U4500.AK38 ; U4500.BD53 56.3,94.49 v1(56.18,94.61) ; v1(98.22,69.93) U6600.11 ; v1(102.64,36.73) 102.43,36.52 U3950.J5 ; v1(29.89,78.71) 31.39,77.22 U4107.M9 ; U60600.12 101.24,115.14 101.62,114.76 v1(101.62,114.38) ; v1(75.68,92.95) 75.66,92.92 U4500.E51 ; U4500.AA53 67.83,94.39 v1(67.97,94.39) ; U6150.14 91.6,140.86 v1(91.16,141.3) ; U4500.A23 77.71,79.33 v1(77.99,79.61) ; U4500.AU3 v1(59.76,69.77) 60.02,69.77 U4500.AT3 ; v1(66.3,55.37) 65.92,55.75 U4104.B1 ; U4106.J8 34.2,62.99 v1(34.2,62.97) ; v1(29.03,84.59) 29.11,84.59 U4102.P1 ; U4500.D24 75.73,79.75 v1(76.07,79.41) 76.15,79.32 76.15,79.01 U4500.C22 ; R4151.1 43.13,48.85 v1(43.45,48.53) ; v1(56.31,89.09) 56.31,89.22 56.67,89.58 U4500.BC44 ; U4102.B3 39.42,87.33 v1(39.16,87.59) ; v1(62.45,85.45) 62.07,85.07 U4500.AM35 61.3,84.31 U4500.AN33 ; U4107.G8 35.42,76.43 v1(35.82,76.83) ; U4104.M1 66.42,47.75 v1(66.42,47.74) ; v1(34.99,77.61) 35.38,77.22 U4107.G9 ; v1(52.93,89.13) 53.08,89.13 53.15,89.05 U4500.BJ43 ; U3950.P6 v1(105.46,35.71) ; v1(46.45,109.39) 46.84,109.79 U4101.G1 ; U4500.AB42 67.3,88.89 67.62,89.21 v1(67.62,89.91) ; U4104.G1 65.94,51.75 v1(66.29,51.4) ; v1(72.43,73.47) 72.5,73.39 72.5,72.82 U4500.M9 71.64,72.24 U4500.P10 ; v1(29.82,69.6) 30.21,69.6 31.42,70.82 U4107.M1 ; U4500.N51 71.48,93.41 71.48,93.93 71.42,93.99 U4500.N53 71.52,94.19 v1(71.9,94.19) ; U4500.AA16 U4500.Y16 68.34,75.71 v1(68.59,75.46) ; U4500.U8 U4500.U6 U4500.U5 ; v1(34.2,90.5) 33.82,90.87 U4102.J8 ; CN1300.33 40.82,124.54 v1(40.73,124.63) ; v1(57.7,90.74) 57.71,90.74 ; 57.71,90.74 57.88,90.91 57.96,90.91 58.08,91.03 U4500.AY47 ; U4101.M9 53.41,113.79 53.83,113.37 v1(53.84,113.37) ; U6700.11 v1(96.65,53.47) ; v1(45.37,47.67) 45.37,47.73 45.66,48.02 46.14,48.02 46.41,47.75 U4105.M9 ; U4105.M1 53.33,47.75 v1(53.36,47.73) ; U4500.BJ15 53.65,75.57 v1(53.26,75.57) ; U4107.D1 37.82,70.75 v1(37.46,70.39) 37.02,70.82 U4107.E1 37.02,70.93 37.13,71.03 37.13,71.42 37.02,71.53 U4107.E2 ; U4107.T1 27.76,70.82 v1(27.53,71.05) ; U4500.AJ1 63.65,67.84 v1(63.72,67.76) ; U4106.P1 28.9,56.85 27.58,56.85 v1(27.29,57.13) ; v1(71.31,67.12) 70.45,67.97 70.45,68.4 70.45,68.4 U4500.R1 ; U3950.P4 105.39,36.71 v1(105.46,36.78) ; U4500.AH12 64.06,73.66 v1(63.68,73.28) 64.02,72.95 U4500.AH10 ; v1(77.85,81.91) 77.72,81.77 77.5,81.77 77.49,81.76 U4500.B28 ; U4500.BG14 v1(55.14,75.47) U4500.BG16 ; U4500.U21 69.9,78.29 70.46,78.84 U4500.P22 70.79,79.21 v1(70.65,79.35) ; v1(63.65,94.74) U4500.AJ53 ; v1(64.8,83.19) 65.16,83.55 U4500.AF32 65.44,83.31 65.59,83.31 65.74,83.46 65.79,83.46 65.88,83.55 U4500.AD32 U4500.AD30 ; v1(60.87,86.25) 61.2,86.58 U4500.AN38 U4500.AM38 ; U4500.A31 77.84,82.78 v1(77.94,82.78) ; U4101.B1 46.91,105.79 v1(46.51,106.19) ; U4102.M9 31.42,91.8 v1(31.83,92.2) ; v1(34.22,76.8) 33.84,76.42 U4107.J8 ; U4106.B1 39.39,57.77 v1(39.01,57.38) ; U4103.F9 U4103.G9 U4103.G8 35.42,103.94 v1(35.81,103.55) ; U4107.B9 39.42,77.26 v1(39.81,77.65) 40.22,77.23 U4107.A9 ; U4104.P9 58.92,46.15 v1(58.92,46.15) ; U4104.E8 60.29,53.35 60.64,53.7 60.64,53.72 v1(60.65,53.73) 60.64,53.75 60.64,53.78 60.27,54.15 U4104.D8 ; U60300.4 v1(38.5,26.51) ; U4105.P1 v1(53.79,46.15) ; U4500.BB4 57.42,70.02 57.74,69.69 v1(57.74,69.69) 58.15,69.69 U4500.AY3 ; U4103.B9 U4103.A9 40.52,104.75 v1(40.77,104.5) ; v1(35.04,84.87) 35.42,85.26 U4102.G1 ; U4500.C47 76.3,90.25 v1(76.12,90.07) 76.12,90.11 75.64,90.6 U4500.E46 ; v1(59.83,94.68) 59.76,94.61 U4500.AU53 59.76,94.04 59.88,93.92 59.88,93.49 59.76,93.37 U4500.AU51 60.1,93.01 U4500.AT51 ; U4106.A9 40.22,64.21 v1(39.83,64.6) 39.42,64.18 U4106.B9 ; U4500.C3 U4500.B2 U4500.C1 76.93,68.07 v1(77.29,68.07) ; v1(55.09,72.49) 54.88,72.28 U4500.BG7 ; U4500.K4 73.42,70.65 v1(73.42,71.13) ; v1(64.82,124.59) U7102.11 ; v1(27.53,69.67) 28.53,69.67 29.68,70.82 U4107.P1 ; v1(27.22,85.21) 27.31,85.3 U4102.T1 ; U4104.P1 66.41,46.15 v1(66.42,46.15) ; U4500.BF50 55.46,92.41 v1(55.46,91.89) 55.42,91.86 U4500.BG49 ; U4100.G1 59.82,109.79 v1(59.49,109.47) ; U4500.Y50 67.73,92.71 v1(67.61,92.71) 67.34,92.71 U4500.AB50 ; v1(53.77,116.64) 53.42,116.99 U4101.T9 ; U4104.E1 v1(66.34,53.8) ; R4180.1 v1(31.98,81.74) ; U4500.AN25 U4500.AN24 61.28,79.73 v1(61.66,79.34) 62.06,79.74 U4500.AM24 62.09,79.76 U4500.AK22 ; v1(71.88,78.42) 71.88,78.46 U4500.N22 ; U4103.M9 31.42,104.85 v1(31.09,105.18) 30.98,105.29 30.01,105.29 29.82,105.1 U4103.P9 ; U4500.Y45 v1(68.48,90.77) ; U4500.J22 73.63,79.1 v1(73.91,79.37)
  BOTTOM w0.305: R4144.1 43.01,48.09 v1(43.45,48.53) ; v1(32.52,107.99) 32.16,108.36 R4103.1
  BOTTOM w0.33: v1(47.39,124.97) 47.8,124.97 48.32,124.44 CN1300.63 ; CN1300.57 v1(46.82,124.59) ; CN1300.45 43.83,124.47 v1(44.02,124.66) ; U6000.14 v1(64.79,26.24) ; CN1300.18 37.07,132.07 36.71,132.44 v1(36.47,132.44) ; CN1300.69 49.82,124.67 v1(49.79,124.7) ; CN1300.51 v1(45.33,124.59)
  BOTTOM w0.356: CN1300.75 v1(51.33,124.59) ; CN3000.25 79.52,153.43 v1(79.2,153.76) ; U4502.2 106.44,47.63 106.67,47.4 C4506.2 v1(107.26,47.04) ; CN3000.12 73.03,153.51 72.65,153.89 v1(71.65,153.89) 71.53,153.77 CN3000.9 ; U4503.2 108.33,54.18 108.55,53.96 C4636.2 ; v1(76.2,154.46) 76.03,154.28 CN3000.18 ; U4702.5 74.12,40.28 v1(74.51,40.68) ; CN3000.15 74.53,153.7 v1(74.95,154.13)
  BOTTOM w0.381: v1(69.01,25.86) 68.57,26.3 C6024.2 ; v1(90.12,74.19) 90.12,76.99 90.03,77.08 90.03,77.11 89.84,77.3 89.8,77.3 89.58,77.52 86.71,77.52 v1(86.18,76.99) ; v1(90.12,74.19) 90.12,73.34 89.59,72.82 87.93,72.82 87.85,72.9 87.28,72.9 87.21,72.82 86.74,72.82 86.1,73.46 v1(86.1,73.79) C4510.1 ; v1(90.12,74.19) 89.22,74.19 X4500.2 ; CN2002.4 104.17,81.35 105.22,80.3 v1(105.22,79.9) ; R6008.1 v1(64.89,31.09) ; U3500.18 v1(107.2,122.29) ; v1(46.16,117.09) 46.26,116.99 U4101.T1 ; R6752.1 94.9,59.89 v4(95.22,59.56) ; v1(106.85,147.47) 106.72,147.6 CN245.G1 ; v1(81.18,19.1) 81.52,18.75 C610.2 ; D902.2 v1(23.16,23.61) ; C7116.2 103.34,127.23 v1(103.68,127.23) ; v1(113.3,129.5) 113.5,129.7 Q3501.2 114.28,130.26 117.11,127.43 C3505.2 117.11,126.51 C3504.2 ; v1(60.79,135.81) 60.79,134.87 Q3006.2 ; R6746.2 92.95,54.44 v1(92.53,54.86) 92.1,54.44 C6716.2 ; C4627.2 80.92,76.61 v1(80.59,76.28) ; U4504.3 28.59,123.69 v1(28.44,123.55) ; R6661.2 97.45,77.32 v1(98.07,77.32) ; v1(49.3,17.47) 49.56,17.74 C7577.2 ; v1(66.79,113.43) 66.43,113.79 U4100.M9 ; v1(92.71,63.74) R6655.2 C6645.2 ; Q3153.2 24.77,126.17 v1(25.17,126.57) ; C509.2 18.43,55.09 C508.2 ; v5(43.41,23.34) 43.41,23.24 42.71,22.55 C60350.2 ; R60018.2 54.66,21.92 v1(54.84,22.1) 54.94,22.2 54.94,22.74 Q60002.4 ; v1(19.2,111.3) 18.97,111.07 D2409.2 ; C3951.2 v1(112.22,34.19) ; v1(100.68,55.63) 100.83,55.63 101.44,56.23 C7225.1 ; v1(110.4,36.5) 110.4,36.17 C3953.2 ; v1(35.4,32.41) 35.99,32.99 C7206.2 ; C2427.2 17.44,115.39 17.89,114.93 v1(18.51,114.93) 18.4,115.05 C2432.2 ; CN600.G1 v1(80.67,15.85) ; v1(55.04,138.43) 55.04,138.39 55.04,138.2 55.04,138.08 55.5,137.63 Q3001.1 ; Q1302.4 v1(26.27,129.67) ; v1(96.41,138.51) 96.61,138.71 C6169.2 ; R6658.2 100.27,69.48 v1(100.71,69.04) ; v1(75.51,95.88) 75.65,96.02 R4564.2 ; D3951.2 v1(112.29,32.41) ; C6616.2 96.98,65.79 96.99,65.79 R6646.2 97.78,65.79 98.19,65.38 v1(98.19,65.18) ; v1(28.34,134.64) 28.41,134.71 C1302.2 ; U4101.P9 53.89,115.39 v1(53.89,115.39) ; Q7000.2 95.41,146.8 v1(94.99,147.22) ; v1(59.56,117.67) 59.97,117.25 U4100.T1 ; C7580.2 v1(72.89,114.93) ; R6151.1 v1(89.71,142.23) ; U4100.P1 v1(59.4,115.39) ; U2000.2 v1(113.71,99.85) ; v1(92.35,59.99) 92.15,59.79 R6755.2 ; v1(38.5,26.51) 37.95,26.51 R60301.1 ; v1(79.65,81.46) 79.66,81.45 C4602.2 C4607.2 ; CN245.G2 106.82,134.3 v1(106.86,134.34) ; C2004.2 109.33,102.48 v1(108.76,103.05) ; R4100.1 70.33,112.98 v1(70.71,112.6) 70.29,112.18 R4106.1 ; Q4714.2 112.25,114.54 112.64,114.92 v1(113.3,114.92) ; C4507.1 107.54,52.88 109.48,52.88 109.82,53.22 v1(110.4,53.22) ; v1(76.72,66.07) 76.31,65.66 C4580.2 ; v1(20.04,25.32) 20.24,25.12 C900.2 ; C4636.2 109.18,53.57 109.57,53.96 v1(110.3,53.96) ; R4179.1 R4178.1 ; C3008.2 60.62,131.93 Q3007.2 60.62,131.21 61.38,130.44 61.38,130.01 v1(61.59,129.79) ; v1(55.95,129.39) 55.95,129.71 C1303.2 55.72,130.35 C1304.2 ; v1(88.67,133.35) 88.31,132.99 C7121.2 ; D282.2 104.58,61.59 104.96,61.21 v1(105.31,61.21) ; U2406.2 18.82,119.74 18.82,119.73 v1(18.62,119.53) ; v1(66.42,35.97) 66.07,35.62 Q7214.4 ; v1(86.18,76.99) 86.61,76.99 X4500.4 ; v1(86.18,76.99) 85.85,76.99 C4509.1 v1(86.13,76.3) ; v1(65.66,150.24) 65.66,150.01 65.13,149.49 R352.2 ; v1(116.76,97.69) 116.73,97.65 C7512.2 ; C3501.2 v1(104.8,122.91) ; C904.2 v1(25.09,19.76) ; v1(105.2,70.6) 104.71,70.6 104.56,70.45 CN281.5 ; 65.3,122.58 65.25,122.63 C7100.2 ; 65.3,122.58 v1(65.35,122.53) ; 65.3,122.58 64.64,122.58 64.36,122.86 C7109.2 ; C7585.2 55.99,35.24 v1(56.21,35.46) ; C351.2 64,147.01 61.29,144.3 v1(59.71,144.3) 59.71,144.25 60.58,143.37 C3001.2 ; v1(18.72,46.19) 18.39,46.19 18.39,46.19 17.7,46.87 C519.2 ; C60013.2 56.03,18.89 v1(56.03,20.6) ; v1(74.19,46.03) 72.32,46.03 70.99,44.7 U4701.4 ; v1(94.61,52.32) R6750.2 ; U4100.T9 66.91,116.99 v1(66.92,116.99) ; v1(71.5,99.03) 71.68,98.86 R4520.1 ; C7110.2 66.37,129.9 v1(66.62,129.64) ; v1(19.83,136.07) 19.83,135.96 U3151.1 ; Q7108.2 115.07,113.4 Q7114.2 113.78,114.23 v1(113.3,114.23) ; v1(73.83,107.7) 73.7,107.56 R4844.2 ; Q3001.4 57.92,139.08 R3010.2 59.1,139.08 v1(59.59,138.59) 59.9,138.89 C3002.2 ; v1(66.92,115.4) 66.91,115.39 U4100.P9 ; v1(67.66,122.5) 67.14,123.03 C7104.2 ; C7108.2 58.38,127.19 v1(58.09,127.48) ; v1(99.01,59.38) 99.28,59.66 C6742.2 ; C901.2 v1(15.08,17.03) ; D281.3 v1(100.91,74.4) ; C7101.2 87.56,125.88 87.56,125.88 v1(86.84,125.88) ; D251.2 v1(113.79,151.18) ; v1(105.18,76.12) 106.3,76.12 CN281.G1 ; v1(58.06,26.39) 57.79,26.12 R60019.2 ; v1(112.16,61.77) 111.86,61.47 D280.3 ; CN251.G1 v1(89.63,156.92) ; R900.1 v1(15.08,20.69) ; C3950.2 v1(112.22,33.3) ; v1(80.36,112.32) 80.86,112.82 R4444.2 ; R4670.2 v1(109.61,108.03) ; C7661.2 v1(91.36,77.65) ; C611.2 v1(83.16,22.85) ; C906.2 v1(22.27,23.61) ; C6025.2 67.46,30.06 v1(67.46,30.73) ; v1(20.27,113) D2406.8 D2406.3 ; v1(96.82,52.33) C6746.2 ; C4540.2 v1(72.83,116.56) ; R6761.2 83.99,40.92 v1(84.27,40.64) 84.58,40.33 C6712.2 ; C4511.2 87.57,71.24 v1(87.32,70.99) 87.28,70.95 87.28,63.05 87.27,63.05 87.27,62.94 86.97,62.64 85.42,62.64 85.04,63.02 v1(85.04,71.04) 85.04,72.15 C4512.2 ; v1(59.08,113.84) 59.13,113.79 U4100.M1 ; C7578.2 v1(61.82,122.61) ; CN281.G2 v1(106.78,66.6) ; v1(35.2,26.9) 35.55,26.55 C7207.2 ; C60209.2 102.51,114.59 101.83,114.59 v1(101.62,114.38) ; R324.2 77.46,147.54 v1(77.35,147.54) 77.33,147.51 Q300.2 ; C7123.2 90.68,125.38 v1(90.85,125.55) ; C7521.2 101.01,134.6 v1(100.96,134.64) ; C6000.2 69.44,31.72 C7604.2 ; C7979.2 v1(19.78,100.58) ; v1(86.84,126.57) 87.25,126.97 C7122.2 ; SW500.2 v1(35.56,21.73) ; U4101.E2 U4101.E1 v1(46.52,107.8) U4101.D1 ; v1(80.93,151.28) 81.08,151.12 C3020.2 81.08,149.79 C3019.2 ; C7527.2 116.18,104.04 v1(116.02,103.89) ; v1(79.29,66.34) 79.29,66.1 79.62,65.77 C4579.2 ; C6051.2 92.19,27.44 v1(92.2,27.43) ; v1(89.48,64.82) 89.63,64.67 R6652.1 ; U3500.11 v1(113.3,122.29) ; C7510.2 83.21,138.35 v1(83.42,138.56) ; C6028.2 64.26,23.35 v1(64.26,23.06) ; C6745.2 v1(93.04,59.99) ; U3500.4 v1(113.3,126.84) ; v1(60.58,31.95) R6003.2 ; 46.29,111.45 46.26,111.43 v1(46.26,111.43) ; C7601.2 28.49,136.71 v1(28.95,136.25) ; C6026.1 60.26,22.11 59.79,22.58 v1(59.51,22.58) ; D252.2 v1(112.87,151.18) ; R4702.2 74.3,40.89 v1(74.51,40.68) ; C6642.2 91.13,72.24 v1(91.13,72.75) ; v1(113.66,103.76) 114.55,103.76 115.2,104.41 Q4525.2 ; C907.2 v1(23.66,13.89) ; C903.2 v1(18.34,25.39) ; 117.8,121.77 C3500.2 117.11,122.48 C3502.2 ; U4703.3 110.29,114.03 v1(110.06,113.79) ; C4537.2 v1(72.83,117.45) ; C7120.2 90.68,127.53 v1(90.73,127.48) ; v1(81.68,143.41) 81.68,142.3 D3000.2 ; v1(74.47,52.73) 74.55,52.65 C14.2 ; C902.2 v1(21.38,23.61) ; v1(52.6,24.54) 52.92,24.85 Q60002.1 ; v1(37.61,30.76) 37.41,30.56 C60306.2 ; C3959.2 99.9,44.37 v1(100.12,44.37) ; v1(39.65,23.49) 39.07,23.49 C60351.2 ; D500.3 31.19,29.81 v1(31.19,30.07) ; C7205.2 76.86,109.95 v1(77.34,109.47) U4441.9 ; v1(65.78,67.44) 65.83,67.39 C4515.2 ; U4103.E8 37.02,103.93 37.18,103.77 37.18,103.77 v1(37.42,103.53) 37.82,103.93 U4103.D8 ; C7203.2 103.15,58.29 v1(102.74,58.7) ; C6036.2 v1(62.24,29.62) ; C4574.2 C4578.2 50.25,63.51 C4577.2 52.18,65.44 v1(52.18,66.12) ; v1(67.67,150.09) 67.19,149.61 R3017.2 ; C4441.2 77.47,114.06 v1(77.47,114.07) 77.31,114.07 76.84,114.55 R4441.2 ; v1(87.35,155.58) 87.35,156.17 86.15,157.36 CN3000.G2 ; U4101.M1 46.74,113.79 v1(45.97,114.56) 46.42,115.01 v1(46.52,115.01) 46.89,115.39 U4101.P1 ; v1(81.02,131.93) 81.44,132.34 Q4506.1 ; C6646.2 100.07,68.63 v1(100.53,68.17) 100.1,67.74 R6650.2 ; C7526.2 v1(58.9,144.17) ; C7125.2 103.22,126.09 v1(103.68,126.54) ; C6647.2 v1(98.22,73.99) ; v1(23.7,136.58) 23.47,136.35 C3150.2 ; 91.59,49.55 C7520.2 ; R2000.2 v1(117.26,98.83) ; C7567.2 v1(41.04,118.52) ; C2003.2 v1(117.26,99.72) ; 107.22,85.23 v1(108.85,83.6) ; R6054.1 v1(103.63,23.98) ; D250.2 v1(114.7,151.18) ; v1(32.73,125.72) 31.73,124.71 CN1300.G1 ; R4701.1 v1(99.16,63.37) ; v1(26.24,126.24) 27.19,126.24 27.57,126.62 Q1302.1 ; Q4506.4 v1(82.74,129.9) ; Q3502.2 110.68,132.65 v1(110.13,133.2) ; v1(62.4,129.59) 62.71,129.9 C7114.2 ; CN1300.G2 52.04,124.59 v1(51.33,124.59) ; Q3152.2 20.54,127.23 v1(21.05,127.23) ; R4680.2 110.13,104.75 110.51,105.13 v1(111.12,105.13) 111.12,104.32 Q4517.2 ; D256.2 109.22,150.91 109.49,151.18 v1(110.13,151.18) D255.2 ; C905.2 v1(24.18,23.21) ; D253.2 v1(111.96,151.18) ; R60024.2 v1(53.59,29.56) ; D901.2 v1(19.22,25.39) ; C520.2 11.45,50.83 ; C4215.2 25.64,56.14 v1(25.68,56.11) ; C4631.1 v1(109.78,59.05) ; C7602.2 28.87,138.28 v1(29.08,138.28) ; Q7214.1 64.6,34.01 65.02,34.43 v1(65.02,34.54) ; C3503.2 v1(104.83,126.85) ; v1(104.82,44.25) 105.15,44.58 C7513.2 ; v1(18.28,50.52) 18.16,50.65 C516.2 ; C7591.2 v1(91.6,53.55) ; v1(78.55,42.41) C7761.2 ; R4902.2 v1(66.98,62.71) ; C7593.2 99.16,94.56 99.16,93.6 ; U3500.25 v1(107.2,126.84) ; C6172.2 88.36,139.95 v1(88.31,140) ; C6032.2 v1(64,31.14) ; Q7202.2 v1(35.76,38.66) ; D257.2 v1(108.3,151.18) ; 50.13,22.86 C60316.2 ; C7569.2 v1(19.78,74.88) ; C4533.2 v1(72.83,118.34) 72.83,118.81 73.25,119.23 C4534.2 ; R4901.2 v1(67.94,62.71) ; Q4524.2 115.14,109.67 v1(113.3,109.67) 113.3,109.16 Q4516.2 ; Q7106.2 116.19,117.06 113.42,117.06 v1(113.38,117.09) ; C7600.2 v1(85.29,32.03) ; C514.2 15.52,48.56 15.53,48.55 16.12,48.55 v1(16.28,48.39) ; C7541.2 92.27,30.17 v1(91.94,29.84) ; C6612.2 v1(94.66,76.63) ; R7100.2 97.62,145.03 v1(97.57,145.09) 97.57,145.45 Q7120.2 ; v1(78.28,138.22) 78.12,138.38 C6109.2 ; C7518.2 v1(93.47,76.58) ; CN600.G2 v1(75.07,15.82) ; C7568.2 v1(24.79,53.31) ; D254.2 v1(111.05,151.18) ; R6758.2 v1(97.43,50.9) ; C522.2 v1(18.72,46.87) ; v1(23.95,92.38) 24.44,92.87 R4102.1 R4108.1 ; C6122.2 v1(69.9,141.71) ; C6747.2 v1(101.21,52.91) ; C6050.2 v1(90.73,28.24) ; CN6000.G2 v1(17.74,142.2) ; CN6000.G1 v1(27.68,143.48)
  BOTTOM w0.432: SW500.4 35.14,17.39 35.58,17.83 v1(35.58,19.25) ; SW500.5 v1(36.68,19.28) ; CN2002.G2 109.09,78.75 v1(109.09,78.75) ; v1(39.79,19.13) SW500.6 ; C608.2 v1(73.71,20.48) ; CN2002.G1 107.22,85.23 ; C609.2 v1(73.73,23.06)
  BOTTOM w0.762: C6162.2 83.35,144.07 v5(83.43,143.99) ; C6022.2 C6021.2 v5(56.24,26.31)
  BOTTOM w1.016: CN6050.3 v5(89.32,23.27)
  vias: v1(3.12,80.34) v1(3.12,70.74) v1(3.71,143.97) v1(4.09,145.08) v1(5.33,145.19) v1(6.6,145.19) v1(6.93,141.3) v1(9.39,41.63) v1(9.39,40.36) v1(9.39,39.09) v1(9.39,37.82) v1(9.39,36.55) v1(9.39,35.28) v1(9.39,34.01) v1(9.39,32.74) v1(9.39,31.47) v1(9.39,30.2) v1(9.39,28.93) v1(9.39,27.66) v1(9.39,26.39) v1(9.39,25.12) v1(9.39,23.85) v1(9.39,22.58) v1(9.39,21.31) v1(9.39,20.04) v1(9.39,18.77) v1(9.39,17.5) v1(9.39,16.23) v1(9.39,14.96) v1(9.39,13.69) v1(9.39,12.42) v1(9.39,11.15) v1(9.39,9.88) v1(9.39,8.61) v1(9.39,7.34) v1(9.39,6.07) v1(9.39,4.8) v1(9.39,3.53) v1(9.5,2.29) v1(9.66,54.95) v1(9.66,52.99) v1(9.66,51.04) v1(10.18,1.29) v1(11.45,0.76) v1(11.62,54.95) v1(11.62,52.99) v1(11.62,51.04) v1(12.72,0.76) v1(13.28,145.19) v1(13.54,51.9) v1(13.57,54.95) v1(13.57,52.99) v1(13.76,133.15) v1(13.99,0.76) v1(14.32,131.17) v1(14.55,145.19) v1(15.26,0.76) v1(15.59,82.24) v1(15.59,81.61) v1(15.7,80.71) v1(15.82,145.19) v1(16.1,72.36) v1(16.23,82.24) v1(16.23,81.61) v1(17.09,145.19) v1(17.36,110.24) v1(17.36,108.1) v1(17.69,21.76) v1(17.69,19.7) v1(18.36,145.19) v1(18.56,54.28) v1(18.56,53.03) v1(18.72,18.13) v1(18.66,16.48) v1(19.3,116.26) v1(19.35,115.42) v1(19.48,17.3) v1(19.63,145.19) v1(20.34,18.18) v1(20.32,16.46) v1(20.9,145.19) v1(21.59,0.76) v1(21.66,133.88) v1(21.84,132.59) v1(21.76,131.5) v1(22.17,145.19) v1(22.53,129.29) v1(22.83,130.83) v1(22.83,110.34) v1(22.86,0.76) v1(23.31,129.29) v1(23.44,145.19) v1(24.13,0.76) v1(24.53,112.52) v1(24.58,111.18) v1(24.71,145.19) v1(25.4,0.76) v1(25.5,116.14) v1(25.93,116.57) v1(25.98,145.19) v1(25.95,51.01) v1(26.41,113.04) v1(26.67,0.76) v1(27.25,145.19) v1(27.87,51.02) v1(27.94,0.76) v1(28.52,145.19) v1(28.6,115.44) v1(28.6,114.68) v1(28.9,107.28) v1(29,132.88) v1(29.21,0.76) v1(29.79,145.19) v1(30.48,0.76) v1(31.01,2.97) v1(31.01,1.7) v1(31.06,145.19) v1(31.87,13.41) v1(32.33,145.19) v1(32.66,14.17) v1(33.6,145.19) v1(33.73,14.71) v1(34.87,145.19) v1(35,14.91) v1(35.53,88.57) v1(36.14,145.19) v1(36.27,14.91) v1(36.52,109.19) v1(36.74,93.94) v1(37.15,127.83) v1(37.41,145.19) v1(37.54,14.91) v1(37.79,129.36) v1(37.86,111.61) v1(38.26,125.64) v1(38.68,145.19) v1(38.81,14.91) v1(39.71,127.09) v1(39.95,145.19) v1(40.08,14.91) v1(40.43,31.44) v1(40.59,111.15) v1(41.22,145.19) v1(41.16,25.73) v1(41.25,31.44) v1(41.35,14.91) v1(41.72,48.53) v1(42.09,127.14) v1(42.08,31.44) v1(42.49,145.19) v1(42.62,14.91) v1(42.9,31.44) v1(43.76,145.19) v1(43.76,31.44) v1(43.89,14.91) v1(44.57,31.44) v1(45.03,145.19) v1(45.16,14.91) v1(45.76,83.71) v1(46.3,145.19) v1(46.43,14.91) v1(47.57,145.19) v1(47.71,83.75) v1(47.7,14.91) v1(47.75,80.82) v1(47.92,82.41) v1(47.98,25.09) v1(47.98,24.33) v1(48.84,145.19) v1(48.97,14.91) v1(49.24,138.2) v1(50.11,145.19) v1(50.12,109.59) v1(50.24,14.91) v1(51.38,145.19) v1(51.51,14.91) v1(52.47,38.65) v1(52.65,145.19) v1(52.78,14.91) v1(53.92,145.19) v1(54.05,14.91) v1(55.01,38.65) v1(55.19,145.19) v1(55.32,14.91) v1(56.46,145.19) v1(56.59,14.91) v1(57.43,107.99) v1(57.55,38.65) v1(57.73,145.19) v1(57.86,14.91) v1(57.97,109.72) v1(59,145.21) v1(59.13,14.91) v1(60.32,145.57) v1(60.4,14.91) v1(61.41,146.25) v1(61.57,27.48) v1(61.57,26.01) v1(61.67,14.91) v1(62.23,147.22) v1(62.3,26.74) v1(62.61,51.81) v1(62.71,148.36) v1(62.86,164.95) v1(62.86,163.68) v1(62.86,162.41) v1(62.86,161.01) v1(62.86,156.06) v1(62.86,154.79) v1(62.86,153.52) v1(62.86,152.25) v1(62.86,150.98) v1(62.86,149.71) v1(62.94,14.91) v1(63.04,27.48) v1(63.04,26.03) v1(63.29,165.96) v1(63.8,126.11) v1(64.13,135.77) v1(64.56,166.04) v1(64.56,161.09) v1(64.69,14.91) v1(64.82,126.11) v1(65.83,166.04) v1(65.83,126.11) v1(67.1,166.04) v1(68.37,166.04) v1(68.47,72.48) v1(69.14,147.22) v1(69.06,31.88) v1(69.64,166.04) v1(69.85,31.88) v1(70.71,31.88) v1(70.91,166.04) v1(71.73,147.57) v1(72.18,166.04) v1(73.45,166.04) v1(73.63,14.91) v1(74.08,84.24) v1(74.72,166.04) v1(74.9,14.91) v1(75.99,166.04) v1(76.06,84.24) v1(76.17,14.91) v1(76.25,142.19) v1(76.27,141.22) v1(77.06,136.22) v1(77.06,135.58) v1(77.26,166.04) v1(77.44,14.91) v1(77.7,136.22) v1(77.7,135.58) v1(77.95,84.71) v1(78.53,166.04) v1(78.49,139.54) v1(78.71,14.91) v1(78.88,88) v1(79.8,166.04) v1(79.98,14.91) v1(80.45,91.79) v1(80.47,90.33) v1(81.07,166.04) v1(81.24,66.4) v1(81.25,14.91) v1(81.72,133.75) v1(81.68,86.38) v1(82.02,92.04) v1(82.34,166.04) v1(82.52,14.91) v1(82.93,30.99) v1(83,87.88) v1(83.22,134.54) v1(83.47,92.04) v1(83.61,166.04) v1(83.72,30.71) v1(83.79,14.91) v1(84.83,92.01) v1(84.83,48.67) v1(84.88,166.04) v1(84.99,49.45) v1(85.06,14.91) v1(85.47,48.67) v1(85.8,49.45) v1(86.1,48.67) v1(86.15,166.04) v1(86.15,126.39) v1(86.15,59.71) v1(86.15,59.08) v1(86.15,58.44) v1(86.33,14.91) v1(86.37,88.93) v1(86.64,49.45) v1(86.74,48.67) v1(86.76,59.71) v1(86.76,59.08) v1(86.76,58.44) v1(87.42,166.04) v1(87.37,59.71) v1(87.37,59.08) v1(87.37,58.44) v1(87.37,48.67) v1(87.45,49.45) v1(87.6,14.91) v1(87.91,92.81) v1(87.93,91.52) v1(87.88,90.07) v1(87.98,59.71) v1(87.98,59.08) v1(87.98,58.44) v1(88.28,49.46) v1(88.69,165.99) v1(88.67,65.43) v1(88.82,164.85) v1(88.82,163.68) v1(88.82,162.31) v1(88.82,161.04) v1(88.87,14.91) v1(89.09,49.46) v1(89.23,159.83) v1(89.4,27.36) v1(89.4,26.54) v1(89.91,49.46) v1(90.14,14.91) v1(90.24,44.65) v1(90.37,159.21) v1(90.73,126.47) v1(90.72,49.46) v1(90.87,63.65) v1(91.06,44.65) v1(91.41,14.91) v1(91.61,159.18) v1(91.92,44.65) v1(92.68,14.91) v1(92.88,159.18) v1(93.27,142.93) v1(93.27,142.29) v1(93.49,49.3) v1(93.88,142.44) v1(93.85,71.02) v1(93.85,68.86) v1(93.95,14.91) v1(94.15,159.18) v1(94.21,142.98) v1(94.46,86.77) v1(94.46,85.95) v1(94.93,69.93) v1(95.22,14.91) v1(95.42,159.18) v1(95.5,102.77) v1(95.55,57.53) v1(95.55,55.35) v1(96.03,71.02) v1(95.96,68.82) v1(96.42,102.77) v1(96.49,14.91) v1(96.69,159.18) v1(96.65,56.45) v1(97.08,135.99) v1(97.08,94.36) v1(97.08,93.73) v1(97.08,93.09) v1(97.08,92.35) v1(97.12,90.7) v1(97.18,102.77) v1(97.71,135.99) v1(97.71,116.43) v1(97.71,115.54) v1(97.71,114.66) v1(97.76,14.91) v1(97.96,159.18) v1(98.02,92.67) v1(98.02,90.61) v1(98.07,102.77) v1(98.18,122.53) v1(98.18,121.39) v1(98.18,120.24) v1(98.6,116.43) v1(98.6,114.66) v1(98.59,111.53) v1(98.59,110.39) v1(98.59,109.24) v1(99.03,14.91) v1(99.23,159.18) v1(99.49,116.43) v1(99.49,115.54) v1(99.49,114.66) v1(99.69,99.44) v1(99.69,98.63) v1(99.69,97.79) v1(99.69,96.98) v1(99.98,66.9) v1(100.15,109.22) v1(100.3,14.91) v1(100.35,123.39) v1(100.35,122.78) v1(100.5,159.18) v1(100.99,123.39) v1(100.99,122.78) v1(101.17,90.8) v1(101.19,86.26) v1(101.19,85.5) v1(101.19,84.73) v1(101.19,83.97) v1(101.19,83.21) v1(101.19,82.45) v1(101.57,14.91) v1(101.77,159.18) v1(101.8,119.1) v1(101.85,109.91) v1(101.85,106.81) v1(101.85,106.17) v1(101.85,105.54) v1(102.49,106.81) v1(102.49,106.17) v1(102.49,105.54) v1(102.64,119.1) v1(102.84,14.91) v1(103.04,159.18) v1(103.12,106.81) v1(103.12,106.17) v1(103.12,105.54) v1(103.76,106.81) v1(103.76,106.17) v1(103.76,105.54) v1(103.93,120.78) v1(103.93,119.96) v1(103.93,119.09) v1(103.86,114.73) v1(104.07,113.2) v1(104.11,14.91) v1(104.31,159.18) v1(104.49,112.42) v1(104.49,111.61) v1(104.78,99.43) v1(104.79,98.15) v1(105.38,14.91) v1(105.58,159.18) v1(106.65,14.91) v1(106.85,159.18) v1(107.79,15.24) v1(108.12,159.18) v1(108.23,19.99) v1(108.23,18.72) v1(108.23,17.45) v1(108.23,16.18) v1(108.56,21.16) v1(109.24,22.22) v1(109.39,159.18) v1(110.21,92.76) v1(110.21,91.49) v1(110.21,90.22) v1(110.21,88.95) v1(110.21,87.68) v1(110.21,86.41) v1(110.39,94) v1(110.49,85.17) v1(110.66,159.18) v1(111.22,94.84) v1(111.35,84.28) v1(111.93,159.18) v1(112.47,95) v1(112.6,84) v1(113.2,159.18) v1(113.74,95) v1(113.87,84) v1(114.47,159.18) v1(115.01,95) v1(115.19,83.84) v1(115.21,82.6) v1(115.21,81.33) v1(115.21,80.06) v1(115.21,78.79) v1(115.21,77.52) v1(115.21,76.25) v1(115.21,74.98) v1(115.21,73.71) v1(115.21,72.44) v1(115.21,71.17) v1(115.21,69.9) v1(115.21,68.63) v1(115.21,67.36) v1(115.21,66.09) v1(115.21,64.82) v1(115.21,63.55) v1(115.29,62.33) v1(115.74,159.18) v1(115.92,61.34) v1(116.1,100.61) v1(116.25,95.07) v1(117.01,159.18) v1(117.09,60.98) v1(117.27,95.58) v1(117.9,96.57) v1(117.95,158.75) v1(118.01,157.53) v1(118.01,153.72) v1(118.01,152.45) v1(118.01,151.18) v1(118.01,149.91) v1(118.01,148.64) v1(118.01,147.37) v1(118.01,146.1) v1(118.01,144.83) v1(118.01,143.56) v1(118.01,142.29) v1(118.01,141.02) v1(118.01,139.75) v1(118.01,138.48) v1(118.01,137.21) v1(118.01,135.94) v1(118.01,134.67) v1(118.01,133.4) v1(118.01,132.13) v1(118.01,130.86) v1(118.01,129.59) v1(118.01,128.32) v1(118.01,127.05) v1(118.01,125.78) v1(118.01,124.51) v1(118.01,123.24) v1(118.01,121.97) v1(118.01,120.7) v1(118.01,119.43) v1(118.01,118.16) v1(118.01,116.89) v1(118.01,115.62) v1(118.01,114.35) v1(118.01,113.08) v1(118.01,111.81) v1(118.01,110.54) v1(118.01,109.27) v1(118.01,108) v1(118.01,106.73) v1(118.01,105.46) v1(118.01,104.19) v1(118.01,102.92) v1(118.01,101.65) v1(118.01,100.38) v1(118.01,99.11) v1(118.01,97.84) v1(118.01,60.32) v1(118.01,59.05) v1(118.01,57.78) v1(118.01,56.51) v1(118.01,55.24) v1(118.01,53.97) v1(118.01,52.7) v1(118.01,40.21) v1(118.01,38.94) v1(118.01,37.67) v1(118.01,36.4) v1(118.01,35.13) v1(118.01,33.86) v1(118.01,32.59) v1(118.01,31.32) v1(118.01,30.05) v2(99.31,87.71) v4(92.38,53.46) v4(97.74,57.53) v4(97.71,55.37) v5(22.12,140.59) v5(22.12,139.57) v5(23.14,140.59) v5(23.14,139.57) v5(41.81,29.57) v5(42.31,30.5) v5(42.82,29.57) v5(43.33,30.5) v5(43.84,29.57) v5(44.35,30.5) v5(44.85,29.57) v5(48.92,25.15) v5(48.92,24.21) v5(49.83,25.15) v5(49.83,24.21) v5(69.31,32.66) v5(70.33,32.66) v5(70.53,35.03) v5(71.35,32.66) v5(71.47,35.03) v5(72.49,35.03) v5(73.43,35.03) v5(74.75,141.68) v5(75.59,142.6) v5(75.66,141.68) v5(76.98,134.82) v5(76.98,133.88) v5(77.92,134.82) v5(77.92,133.88) v5(84.49,30.85) v5(84.96,47.9) v5(85.9,47.9) v5(86.84,47.9) v5(87.2,119.61) v5(87.2,118.67) v5(87.2,117.73) v5(87.22,116) v5(87.78,47.9) v5(88.49,48.51) v5(89.43,48.51) v5(90.37,48.51) v5(90.42,27.36) v5(90.42,26.42) v5(91.64,47.17) v5(92.53,45.67) v5(92.58,48.11) v5(93.39,46.46) v5(94.05,141.5) v5(94.97,142.47) v5(94.97,141.53) v5(95.02,103.56) v5(95.7,86.69) v5(95.7,85.75) v5(95.91,142.47) v5(95.91,141.53) v5(96.36,103.53) v5(96.72,86.69) v5(96.72,85.75) v5(97.3,135.13) v5(97.3,103.53) v5(97.74,87.12) v5(97.76,134.31) v5(98.22,135.13) v5(98.27,125.02) v5(98.27,124.08) v5(98.24,108.28) v5(98.24,103.53) v5(98.68,134.31) v5(99.03,23.29) v5(99.13,135.13) v5(99.18,108.28) v5(100.05,23.29) v5(101.06,23.29) v5(102.08,23.29) v5(104.44,137.44) v5(108.76,98.04)
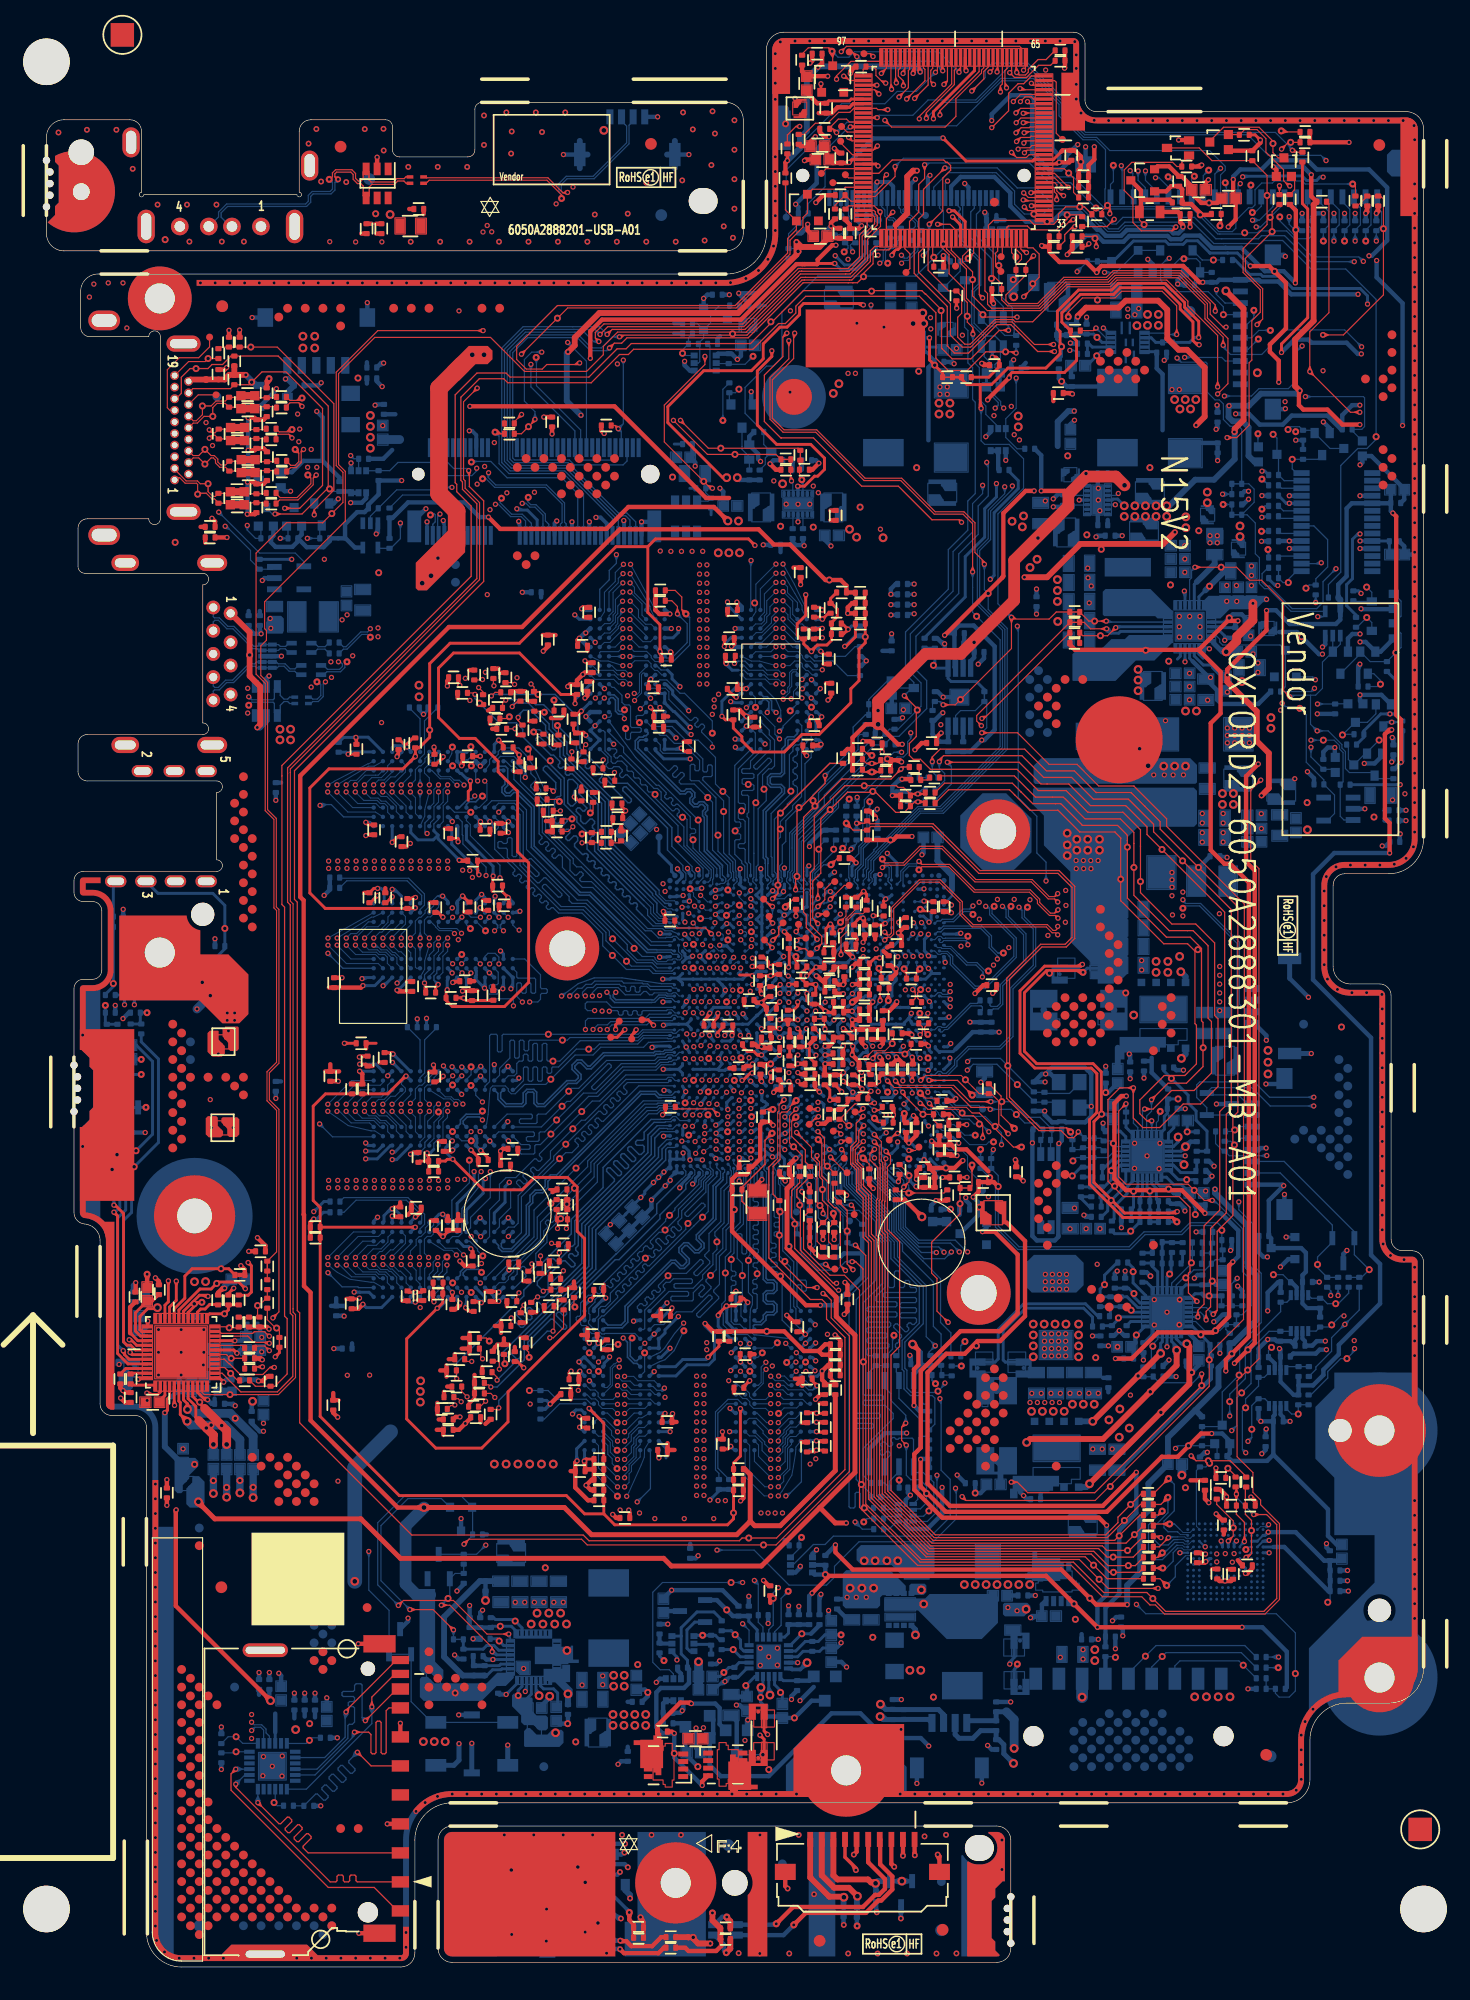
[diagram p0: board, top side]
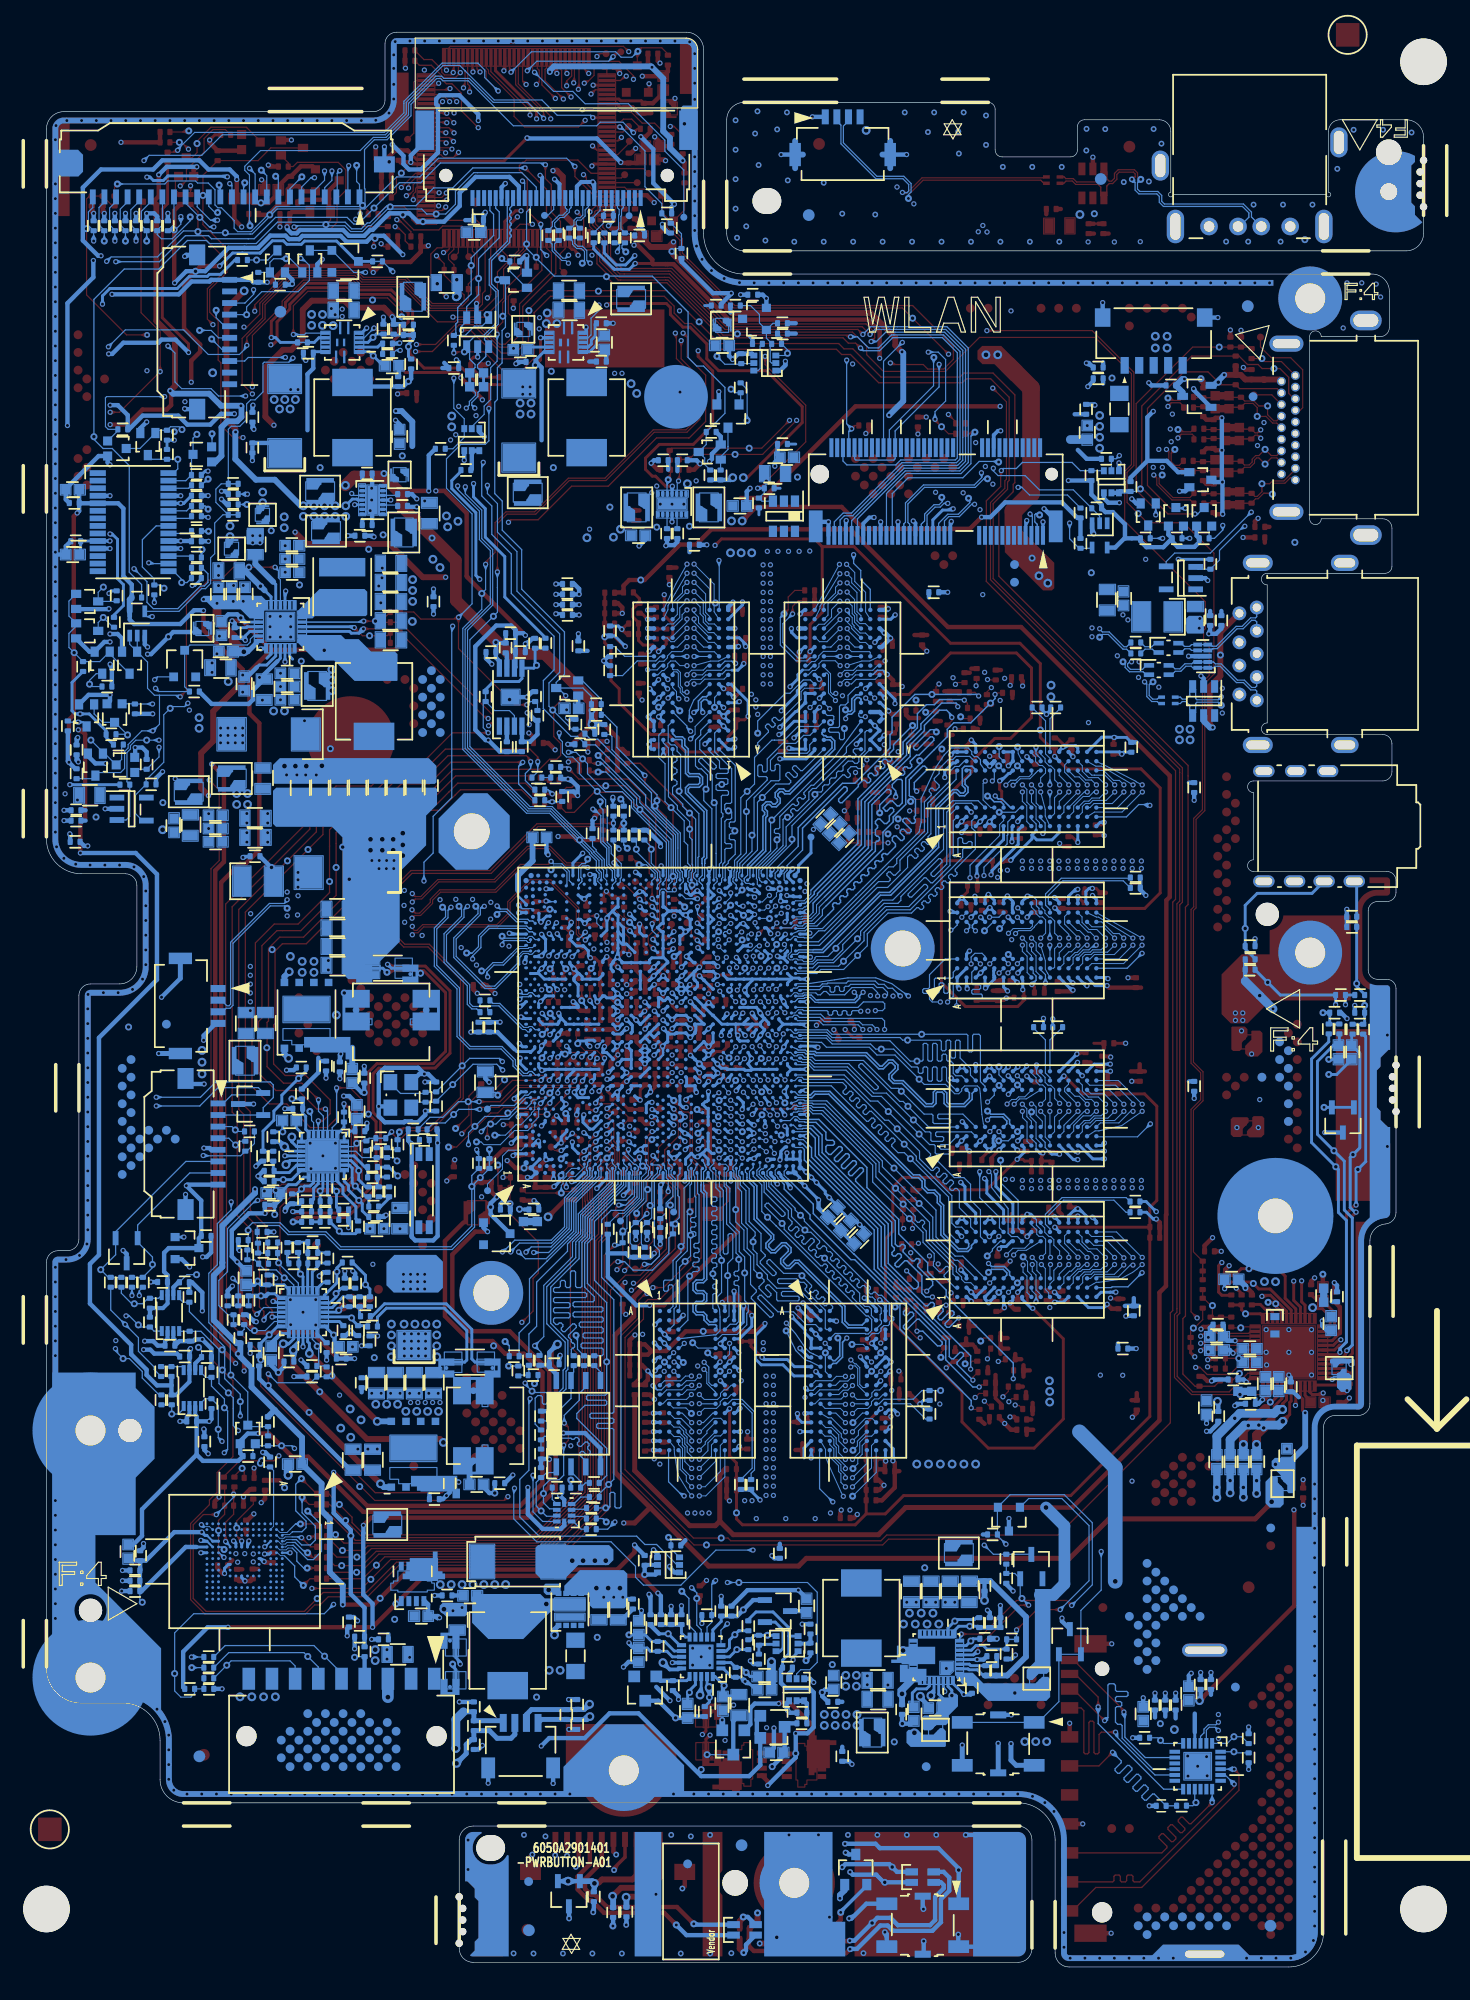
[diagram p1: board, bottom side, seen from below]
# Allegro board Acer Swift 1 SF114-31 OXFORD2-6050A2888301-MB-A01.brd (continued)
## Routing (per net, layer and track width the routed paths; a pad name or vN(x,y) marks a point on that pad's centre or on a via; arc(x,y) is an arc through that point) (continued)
DGND_HDMI: length 0.8
  TOP w0.381: 13.3,124.15 R7501.1 ; 13.69,122.79 R7502.1
  vias: v2(11.1,122.82)
DGND_PB: length 19.2
  TOP w0.381: D9150.1 51.49,2.52 C9150.2 51.49,3.88 51.24,4.14 v4(51.24,4.3) ; v4(73.87,9.58) 73.87,9.58 CN9100.9 ; CN9100.G2 77.02,9.54 v4(76.87,9.69) ; v4(74.9,9.63) 74.88,9.65 CN9100.10 ; CN9100.G1 63.72,6.97 v4(63.93,6.77)
  BOTTOM w0.381: C9101.2 69.9,3.56 v3(69.92,3.54) ; v4(71.62,4.71) 71.56,4.77 C9102.2 ; D9100.3 73.7,5.21 v4(73.7,4.18) ; v4(46.46,3.01) 46.3,2.84 SW9100.6 ; SW9100.2 43.2,5.05 v4(43.13,4.99) ; v4(43.11,2.23) 43.11,1.18 SW9100.5 ; 38.58,1.75 SW9100.4 40.13,1.78 v4(40.13,2.8) ; U9150.3 49.56,9.7 49.73,9.86 v4(49.85,9.86) ; C9100.2 68.75,3.65 v4(68.77,3.63) ; v4(39.49,11.39) 38.64,11.39
  vias: v4(42.03,11.39) v4(44.57,11.39) v4(47.11,11.39) v4(48.31,1.19) v4(49.65,11.39) v4(52.19,11.39) v4(54.73,11.39) v4(59.7,1.19) v4(61.54,11.38) v4(61.53,1.16) v4(63.2,11.26) v4(64.07,1.16) v4(64.89,11.39) v4(66.21,6.27) v4(69.15,1.16) v4(71.69,1.16) v4(74.23,1.16) v4(75.74,11.26) v4(76.77,1.16) v4(77.59,11.39) v4(78.49,1.17) v4(82.41,10.94) v4(82.41,8.4)
DGND_USB1: length 12.1
  TOP w0.381: 27.16,149.43 C2460.2 ; 28.52,155.01 D2410.2 v1(28.52,156.02) ; 28.43,149.43 C2461.2 ; 32.54,151.11 C2462.2
  BOTTOM w0.381: CN2003.G2 v1(44.59,156.25) ; CN2003.G1 v1(55.41,156.25) ; CN2003.1 v1(52.71,159.5)
  BOTTOM w0.508: CN2003.G2 46.67,156.25 ; CN2003.G2 46,155.07 ; CN2003.G2 46,157.43 ; 53.53,156.25 CN2003.G1 ; CN2003.G1 54.2,155.07 ; CN2003.G1 54.2,157.43
  vias: v1(24.43,148.74) v1(26.67,148.72) v1(28.93,148.72) v1(37.65,149.57) v1(38.01,150.14) v1(38.4,149.59) v1(43.96,152) v1(45.41,153.45) v2(10.24,148.92) v4(1.04,158.15) v4(3.49,158.39) v4(6.03,158.39) v4(7.44,155.02) v4(9.58,151.93) v4(12.12,151.93) v4(12.33,148.75) v4(14.66,151.93) v4(15.12,148.75) v4(17.03,148.75) v4(22.61,157.19) v4(23.28,158.45) v4(23.69,153.93) v4(25.86,153.88) v4(27.45,158.45) v4(29.07,158.47) v4(29.08,156.6) v4(31.21,155.19) v4(31.42,148.74) v4(33.75,155.19) v4(33.96,148.74) v4(36.29,155.19) v4(36.5,148.74) v4(37.74,159.62) v4(37.74,157.08) v4(39.04,148.74) v4(39.67,159.88) v4(40.13,158.24) v4(40.08,156.34) v4(41.58,148.74) v4(42.21,159.88) v4(42.75,158.19) v4(44.12,148.74) v4(44.75,159.88) v4(46.66,148.74) v4(47.29,151.08) v4(49.2,148.74) v4(50.14,151.15) v4(51.74,153.82) v4(51.74,148.74) v4(54.28,148.74) v4(54.84,154.03) v4(54.91,159.88) v4(55.75,158.42) v4(56.77,148.84) v4(57.35,155.35) v4(57.45,159.98) v4(57.65,158.06) v4(58.42,150.06) v4(59.21,149.08) v4(59.34,159.21) v4(59.34,156.67) v4(59.34,154.13) v4(59.34,151.59)
P0V675M_MA_VERF_CA: length 103
  TOP w0.254: 51.87,122.45 51.87,116.77 52.91,115.73 v1(52.91,113.41) 53.04,113.28 C4111.1 ; 51.87,122.45 49.12,122.45 40.8,114.12 34.81,114.12 33.05,112.37 v2(33.05,106.64) 33.05,106.02 32.14,105.11 C4116.1 31.82,105.1 v1(31.82,104.36) 30.75,103.29 24.37,103.29 22.72,101.64 22.72,92.59 24.05,91.26 C4115.1 31.76,91.26 v1(31.81,91.31) ; 51.87,122.45 52.53,123.12 60.55,123.12 v1(61.11,122.55) ; R4113.2 67.63,117.98 R4104.1 67.71,117.56 68.21,117.06 68.21,116.4 67.7,115.9 R4105.2 67.7,114.92 C4252.1 67.71,114.36 67.31,113.97 66.48,113.97 65.98,113.47 v1(65.98,113.4) 65.32,114.06 C4110.1 65.08,114.5 64.75,114.82 64.75,115.79 65.49,116.53 v1(65.49,118.31)
  L3 w0.254: v1(65.49,118.31) 65.55,118.37 65.55,119.99 63.79,121.76 61.9,121.76 v1(61.11,122.55)
  BOTTOM w0.254: U4103.M8 31.42,103.96 v1(31.82,104.36) ; v1(65.98,113.4) 65.59,113.79 U4100.M8 ; v1(52.91,113.41) 52.53,113.79 U4101.M8 ; U4102.M8 31.42,90.92 v1(31.81,91.31)
P0V675M_MA_VERF_DQ: length 128.8
  TOP w0.254: R4112.2 R4111.2 70.62,116.7 C4251.1 R4110.1 v2(70.62,114.67) 70.62,114.16 70.09,113.62 70.09,110.9 69.38,110.19 69.38,108.99 66.65,106.26 65.16,106.26 63.65,104.75 60.94,104.75 59.98,105.71 59.98,106.07 59.24,106.8 59.24,107.52 C4103.2 58.56,107.52 v1(58.26,107.82) ; 41.39,95.39 41.37,95.37 C4114.2 37.19,94.28 v1(37.31,94.16) ; 41.39,95.39 40.63,96.15 40.63,101.36 38.95,103.04 38.95,103.94 36.98,105.91 35.62,105.91 33.82,107.72 33.82,111.98 35.11,113.28 40.8,113.28 44.37,109.71 C4112.2 45.59,109.54 v1(45.59,108.92) ; 41.39,95.39 41.59,95.2 41.59,84.88 39.51,82.8 35,82.8 34.47,83.34 C4113.2 34.47,84.15 v1(34.57,84.25)
  L3 w0.254: v1(58.26,107.82) 57.91,107.47 57.91,103.97 53.11,99.16 53.11,97.55 48.02,92.46 40.3,92.46 39.97,92.79 38.28,92.79 37.31,93.77 v1(37.31,94.16)
  BOTTOM w0.254: U4102.H1 34.62,85.12 34.57,85.07 v1(34.57,84.25) ; U4100.H1 59.73,110.59 58.26,109.12 v1(58.26,107.82) ; v1(37.31,94.16) 37.23,94.24 37.23,94.52 34.96,96.79 34.96,98.01 U4103.H1 ; U4101.H1 46.91,110.59 45.59,109.27 v1(45.59,108.92)
P0V675M_MB_VERF_CA: length 105.7
  TOP w0.254: C4192.1 23.61,65.48 23.01,66.08 23.01,74.21 24.07,75.27 C4190.1 C7538.1 29.43,75.27 30.96,76.81 v1(31.01,76.81) ; C4192.1 23.62,63.78 v1(31.81,63.78) ; C4192.1 C7535.1 23.61,47.46 30.43,40.64 44.85,40.64 46.42,39.06 48.07,39.06 ; 48.07,39.06 R4172.1 48.07,40.24 R4174.2 48.07,41.12 C4165.1 C7534.1 C4163.1 48.07,43.8 48.07,46.88 v1(46.8,48.15) ; 48.07,39.06 49.02,38.12 58.74,38.12 59.26,38.63 v2(59.26,39.15) 59.26,40.06 C4166.1 C7528.1 59.26,42.01 R4173.2 59.26,43.46 59.85,44.05 v1(59.85,48.14)
  BOTTOM w0.254: U4107.M8 31.42,76.44 31.05,76.81 v1(31.01,76.81) ; U4104.M8 60.24,47.75 v1(59.85,48.14) ; v1(46.8,48.15) 47.2,47.75 U4105.M8 ; v1(31.81,63.78) 31.42,63.39 U4106.M8
P0V675M_MB_VERF_DQ: length 125.4
  TOP w0.254: 68.03,50.19 68.03,50.38 67.61,50.8 C7529.1 ; C7536.1 34.2,58.07 C4193.1 34.18,57.27 v1(33.71,56.79) 31.07,54.15 31.07,47.24 33.58,44.73 37.54,44.73 39.81,47 39.81,49.58 46.41,56.18 46.41,62.79 45.78,63.43 45.78,67.24 44.94,68.07 42.1,68.07 41.03,67 37.68,67 v1(35.05,69.63) 34.57,69.63 34.41,69.48 C4191.1 C7539.1 ; 58.9,54.8 C7533.1
  TOP w0.381: R4177.2 66.9,52.79 66.59,53.1 ; R4177.2 C4169.1 67.16,53.68 66.59,53.1 ; R4177.2 C4167.1 ; v1(56.8,55.48) 57.49,54.79 C4164.1 C7533.1 ; 66.59,53.1 65.33,53.1 63.63,54.8 v2(62.13,54.8) 58.9,54.8 ; C7529.1 67.61,51.01 C4167.1 ; C4167.1 67.42,51.9 v1(66.9,51.38) 66.9,50.62 67.15,50.37 R4175.1 68.03,50.19 R4176.2
  L3 w0.254: v1(56.8,55.48) 56.8,59.05 45.74,70.12 39.67,70.12 39.06,69.52 37.16,69.52 36.66,69.03 35.65,69.03 v1(35.05,69.63)
  BOTTOM w0.254: v1(33.71,56.79) 33.83,56.79 34.62,57.58 34.62,57.58 U4106.H1 ; v1(66.9,51.38) 66.79,51.27 66.79,51.24 66.49,50.93 65.88,50.93 U4104.H1 ; U4105.H1 52.81,50.95 54.29,50.95 55.25,51.91 57.12,51.91 57.61,52.4 57.61,54.46 56.8,55.27 v1(56.8,55.48) ; U4107.H1 34.62,70.82 34.45,70.64 34.45,70.23 v1(35.05,69.63)
P0V675M_VREF: length 188.3
  TOP w0.381: v5(32.56,39.61) 30.29,39.61 22.78,47.12 22.78,58.14 22.22,58.71 22.22,64.84 22.18,64.87 22.18,91.96 21.89,92.25 21.89,102.7 34.71,115.52 41.03,115.52 49.45,123.94 61.42,123.94 62.73,122.63 64.13,122.63 67.19,119.57 v2(67.52,119.57) 68.51,119.57 69,119.08 R4113.1 69.74,118.5 R4112.1
  TOP w0.432: 60.7,38.43 61.09,38.05 63.29,38.05 68.04,42.79 R4176.1 ; 60.7,38.43 60.7,42.45 60.23,42.93 R4173.1 ; 60.7,38.43 59.54,37.27 47.01,37.27 44.67,39.61 v5(32.56,39.61)
  BOTTOM w1.016: v5(32.56,39.61) 30.97,38.02 30.97,33.02 31.92,32.08 33.09,32.08
P0V675S: length 80.4
  TOP w0.254: C4102.1 50.08,97.94 ; C4200.1 43.39,67.03
  TOP w0.305: R4170.1 36.41,48.52 36.92,49.03 R4167.1
  TOP w0.381: 45.24,105.53 C4158.1 ; R4149.1 44.76,58.39 ; 38.26,107.18 R4130.1 ; R4138.1 46.13,101.78 ; 43.08,98.79 R4143.1 43.61,98.34 ; C4102.1 49.56,98.33 ; R4133.1 39,111.93 ; R4169.1 34.51,51.88 ; R4169.1 33.97,51.43 ; R4169.1 34.51,50.9 ; 41.11,59.13 R4148.1 ; 34.57,50.03 R4163.1 ; 38.09,108.32 R4131.1 ; R4167.1 R4161.1 36.92,51.04 ; 38.68,55.27 R4153.1 ; R4153.1 39.21,55.71 ; R4153.1 39.21,54.67 ; 45.87,103.91 R4117.1 ; R4154.1 36.49,54.67 ; R4154.1 R4157.1 ; R4154.1 35.88,54.23 ; 43.37,60.38 R4152.1 ; 45.05,58.56 R4146.1 45.5,59.1 ; R4166.1 39.9,53.66 ; R4166.1 39.45,54.2 ; R4166.1 38.88,53.66 ; R4157.1 36.49,52.86 ; R4157.1 35.81,53.31 ; R4120.1 47.59,101.26 ; R4125.1 42.17,103.37 ; R4145.1 41.35,55.55 ; R4162.1 34.29,49.58 ; 43.51,107.67 44.36,107.67 44.63,107.94 R4126.1 ; 37.86,46.82 R4165.1 ; C4107.1 40.39,53.45 ; 48.78,99.86 C4151.1 ; 43.71,105.36 R4124.1 ; 45.01,61.85 R4183.1 ; 33.72,48.63 R4164.1 33.72,47.66 ; 40.61,106.22 R4128.1 ; 43.15,97.89 R4122.1 43.63,98.34 ; 34.23,45.87 C4160.1 33.67,46.31 ; 34.7,52.4 R4160.1 35.22,52.84 ; 42.85,99.23 R4142.1 ; 44.83,103.3 R4141.1 ; 40.73,60.28 C4144.1 ; 48.85,98.6 C4143.1 ; 44.15,57.5 R4171.1 ; R4150.1 43.5,59.78 ; 37.21,108.84 R4134.1 ; R4121.1 42.24,102.06 ; 37.44,46.95 C4100.1 ; R4184.1 42.98,59.79 ; 42.42,105.43 R4123.1 ; R4159.1 37.58,51.73 ; 47.15,102.89 R4116.1 ; 36.45,111.81 R4132.1 ; 35.46,109.39 R4139.1 ; 41.33,109.98 R4129.1 40.12,109.98 R4135.1 ; 40.36,103.04 C4150.1 ; 35.54,110.74 C4159.1 ; 39.71,56.95 R4147.1 ; R4158.1 38.71,53.47 ; 33.83,47.2 C4101.1 ; R4168.1 42.25,56.44 ; 40.89,54.25 R4156.1 ; 38.44,106.74 R4127.1 ; 41.63,107.41 R4136.1 ; 39.14,111.58 R4140.1 ; 43.64,66.81 C4200.1 ; 42.93,56.52 R4155.1 ; 42.32,100.21 R4119.1 ; 41.61,109.11 R4137.1 ; 48.16,101.82 R4118.1
  L3 w1.27: v5(43.91,20.19) 39.24,20.19 26.59,32.84 v5(26.59,33.25)
  BOTTOM w1.27: 29.68,46.14 26.59,43.05 v5(26.59,33.25)
  vias: v1(35.65,110.49) v1(36.13,111.09) v2(43.45,103.99) v5(32.13,110.5) v5(32.14,109.5) v5(32.27,50.53) v5(32.25,49.62) v5(32.25,48.7)
P1V05A: length 75.9
  TOP w0.254: C4544.1 67.71,78.62 v1(67.16,78.62) ; v1(61.68,83.9) 61.54,84.04 C4569.1 ; v1(61.67,78.62) 61.31,78.62 61.02,78.92 60.47,78.92 60.03,79.35 C4566.1 ; v1(69.49,78.64) 69.54,78.68 v1(69.54,79.38)
  TOP w0.381: C7515.2 81.96,84.28 81.96,84.28 v1(81.61,83.94) ; C4555.1 C4561.1 C4562.1 71.78,76.72 v1(71.78,76.35) 71.53,76.09 C4559.1 ; C4551.1 C4552.1 69.55,84.73 v1(69.51,84.69) ; C4626.1 68.82,84.78 v1(68.73,84.69) 68.28,84.69 C4550.1 ; v1(69.49,78.64) 70.09,78.04 C4548.1 70.09,77.34 v1(70.31,77.13) ; C4542.1 72.13,80.83 C4563.1 C4556.1 71.22,80.82 C4557.1 69.63,80.82 69.53,80.92 v1(69.51,80.92) 69.51,80.92 v1(69.51,81.66) 70.13,81.66 C4558.1 C4560.1 ; C4541.1 R4726.1 67.87,79.76 67.49,79.38 v1(67.16,79.38) ; C4549.1 68.18,83.9 v1(68.73,83.9) ; v1(72.96,100.99) R4645.2 R4850.2 ; v1(74.78,73.4) 75.03,73.15 C4570.1 ; v3(73.99,73.58) 73.99,72.94 C4606.1 ; R4602.2 74.48,102.41 v1(73.79,102.41) ; C4553.1 67.81,77.86 v1(67.16,77.86) 67.13,77.83 C4545.1 C4543.1 68.52,76.9 v1(68.73,77.11)
  L4 w0.381: 93.11,101.27 91.07,103.31 80.73,103.31 79.3,104.75 76.13,104.75 v1(73.79,102.41)
  BOTTOM w0.254: U4500.U24 69.54,79.41 v1(69.54,79.38) ; 67.15,80.15 U4500.AA24 ; 67.15,80.15 U4500.AC24 ; 67.15,80.15 U4500.AC25 ; v1(69.51,81.66) 69.51,81.7 69.18,82.03 U4500.V29 ; U4500.AD25 66.38,80.13 U4500.AC25 ; v1(61.67,78.62) 61.29,79 U4500.AN22 ; v1(61.67,78.62) 61.68,78.62 U4500.AM21 ; v1(61.67,78.62) 62.05,79 U4500.AM22 ; U4500.H10 73.76,73.36 v3(73.99,73.58) ; U4500.V24 69.16,79.76 v1(69.54,79.38) ; v1(67.16,78.62) U4500.AC22 66.78,79 v1(67.16,79.38) 67.54,79 U4500.AA22 v1(67.16,78.62) ; v1(67.16,78.62) U4500.AC21 v1(67.16,77.86) U4500.AA21 v1(67.16,78.62) ; v1(70.31,77.13) 70.26,77.13 U4500.U19 ; v1(69.54,79.38) 69.54,79.35 U4500.U22 ; U4500.AC25 66.36,80.91 U4500.AD27 ; U4500.AC19 67.16,77.11 U4500.AA18 ; U4500.G10 v1(74.78,73.4) ; U4500.V18 v1(68.73,77.11) U4500.V19 ; v1(71.78,76.35) 71.75,76.35 71.5,76.6 U4500.N18 ; C7593.1 101.72,95.76 v1(101.83,95.66) ; U4500.U27 69.54,80.93 69.52,80.93 v1(69.51,80.92) 69.5,80.93 69.47,80.93 U4500.V27 ; U4500.AA36 U4500.AA35 U4500.AA33
  BOTTOM w0.381: R4590.2 73.31,101.34 v1(72.96,100.99) 72.96,101.77 73.6,102.41 v1(73.79,102.41) 74.3,102.41 R4605.2 ; v1(93.39,78.71) 93.47,78.64 C7518.1
  vias: v1(101.49,99.44) v1(101.49,98.63) v1(101.49,97.79) v1(101.49,96.98) v5(101.43,101.17) v5(101.43,100.23) v5(102.37,101.17) v5(102.37,100.23)
P1V5S: length 227.6
  TOP w0.254: v1(16.25,53.99) 16.25,53.99 U500.9
  TOP w0.432: 66.71,39.61 68.04,38.28 v1(68.98,38.28) ; 66.71,39.61 69.73,42.64 69.73,54.47 68.12,56.08 68.12,57.73 63.88,61.98 63.88,67.1 64.28,67.51 64.28,68.13 64.08,68.34 C4582.1 64.08,69.16 v1(64.64,69.72) ; 66.71,39.61 61.67,34.57 53.9,34.57 53.24,35.23 30.53,35.23 27.12,38.63 14.52,38.63 13.1,40.05 v5(13.1,40.11)
  L3 w0.381: v5(13.1,40.11) 13.38,40.39 13.38,46.37 15.87,48.86 15.87,53.61 v1(16.25,53.99)
  L4 w0.381: v1(68.98,38.28) 69.44,37.82 90.3,37.82 95.16,42.68 95.16,42.98 95.16,43.33 103.69,51.87 103.69,62.06 108.02,66.39 108.02,80.71 107.97,80.76 106.49,82.23 106.49,95.06 107.52,96.08 108.03,96.59 108.03,98.36 110.14,100.48 110.58,100.91 110.58,105.38 111.16,105.96 111.16,111.4 111.08,111.47 111.08,112.32 110.22,113.18 v1(110.06,113.18)
  BOTTOM w0.254: U4500.AF4 65.13,70.1 64.75,69.72 v1(64.64,69.72) 64.56,69.72 U4500.AH4
  BOTTOM w0.381: C509.1 17.23,55.3 C508.1 16.89,53.99 v1(16.25,53.99) ; v1(110.06,113.18) 109.75,113.18 v2(108.25,114.68) 107.85,115.09 106.32,115.09
P1V8A: length 436.5
  TOP w0.254: v1(68.73,76.35) 68.91,76.35 69.2,76.06 C4585.1 69.98,76.06 70.34,75.7 v1(70.35,75.7) 70.35,75.46 70,75.1 R4671.2 69.24,74.89 C4584.1 69.13,74.49 68.57,73.93 R4677.2 68.4,73.93 C4583.1 ; v1(64.64,90.6) 64.64,91.18 R4693.2 ; R310.2 104.25,157.95 v1(104.7,157.5) ; R4653.2 v1(63.9,155.73) ; v1(62.49,76.34) 62.45,76.38 v1(62.45,77.09) 62.45,77.1 62.69,77.34 C4586.1 ; v1(75.36,163.37) 75.24,163.49 U301.88 ; v1(65.59,83.93) 65.59,83.31 65.89,83.01 C4605.1 66.57,83.01 v1(67.18,82.4) 67.26,82.4 67.37,82.29 C4600.1 67.89,82.33 C4601.1
  TOP w0.381: v1(85.8,127.25) 87.83,127.25 88.13,126.95 ; v5(74.7,53.7) 75.21,53.19 75.21,51.91 74.83,51.53 v1(74.83,48.41) ; R4811.1 74.03,66.15 74.03,66.15 v5(75.51,64.67) ; v1(104.7,157.5) 104.7,157.27 R3020.2 104,156.58 102.03,156.58 Q310.1 ; R4657.2 69.09,105 R4547.1 ; R4657.2 69.52,105.98 70.68,107.13 v5(71.73,107.13) 73.45,105.41 v1(73.81,105.41) ; R4657.2 R4554.2 R4553.2 ; C304.1 66.9,164.13 v1(66.54,163.78) ; v1(62.67,72.56) 62.38,72.85 R4523.1 61.56,72.62 61.56,69.67 60.86,68.96 C4587.1 60.6,68.53 60.39,68.33 59.54,68.33 59.14,67.92 R4632.2 59.14,63.43 65.52,57.05 v1(66.75,57.05) ; R4659.2 63.74,155.56 v1(63.9,155.73) ; v1(100.5,45.99) 99.58,45.99 97.58,43.98 96.75,43.98 96.2,43.98 91.45,39.24 77.57,39.24 75.4,41.41 v1(75.4,43.76) ; R4893.2 R4894.2 66.69,61.2 v1(66.35,61.53) 65.83,62.05 v1(65.83,62.31) R4709.1
  TOP w1.016: v5(92.99,127.74) 92.23,128.49 89.68,128.49 88.13,126.95 88.13,125.93 83.46,121.26 83.46,117.81 78.86,113.21 75.82,113.21 71.73,109.12 v2(71.73,108.32) v5(71.73,107.13)
  L3 w0.381: v1(104.74,47.04) 105.34,47.64 v1(105.34,54.1) 105.34,56.56 v1(105.33,56.57) ; v1(102.57,133.9) 101.51,132.84 101.51,132.32 99.26,130.08 99.26,128.47 ; v1(74.83,48.41) 75.4,47.84 v1(75.4,43.76) ; v1(104.7,157.5) 104.15,158.05 89.54,158.05 86.7,160.89 86.7,161.88 85.63,162.95 85.63,163.46 84.65,164.44 76.43,164.44 v1(75.36,163.37)
  L3 w1.016: v5(74.7,53.7) 74.05,54.35 74.05,62.63 74.3,62.89 ; v5(92.99,127.74) 98.52,127.74 99.26,128.47 101.37,128.47 102.51,127.33 102.51,125.73 101.85,125.07 101.85,120.52 100.94,119.6 100.94,117.32 101.83,116.43 101.83,115.62 102.97,114.48 102.97,113.09
  L4 w0.381: v1(104.7,157.5) 104.91,157.71 110.91,157.71 115.8,152.82 115.8,147.34 114.91,146.46 114.5,146.46 112.36,144.32 112.36,144.16 112.16,143.96 112.16,137.36 112.89,136.63 112.89,135.03 113.27,134.64 v1(113.28,134.64) ; v1(63.9,155.73) 63.9,147.51 59.56,143.17 51.5,143.17 50.62,144.05 45.44,144.05 43.15,141.76 37.28,141.76 30.64,135.11 v1(30.64,128.15)
  BOTTOM w0.254: v1(68.73,76.35) 68.35,76.73 U4500.Y18 ; v1(62.49,76.34) 62.49,76.38 U4500.AK18 ; U4500.AK19 62.45,77.09 v1(62.45,77.09) ; 99.77,112.83 99.4,113.19 U60600.16 ; U4500.AF33 65.22,84.31 v1(65.59,83.93) 65.98,84.31 U4500.AD33 ; U4500.AA29 67.18,82.4 v1(67.18,82.4)
  BOTTOM w0.305: v1(70.35,75.7) 70.08,75.97 U4500.U16
  BOTTOM w0.356: C4636.1 107.7,54.06 107.83,54.19 U4503.3 ; C4506.1 105.82,47.48 105.94,47.6 U4502.3
  BOTTOM w0.381: U4504.5 26.6,122.37 25.75,123.21 ; 25.75,123.21 25.75,124.38 26.79,125.42 27.44,125.42 R4628.2 27.77,126.07 28.65,126.95 R4640.2 v1(30.64,128.15) ; 25.75,123.21 25.7,123.16 25.16,123.16 R3171.2 24.42,122.93 23.9,122.4 22.45,122.4 R3178.1 ; v1(100.5,45.99) 101.41,45.99 102.06,45.34 Q4513.1 102.06,44.29 R4655.2 102.23,43.63 105.28,43.63 105.82,44.17 ; v1(113.28,134.64) 112.62,134.64 112.62,134.64 111.76,133.79 R3514.2 111.66,132.56 110.47,133.74 107.4,133.74 106.63,132.97 104.65,132.97 103.72,133.9 v1(102.57,133.9) ; 70.35,61.52 R4534.2 ; 70.35,61.52 70.35,59.51 67.9,57.05 v1(66.75,57.05) ; 70.35,61.52 68.79,61.52 68.47,61.2 R4895.2 R4892.2 66.69,61.2 v1(66.35,61.53) ; R4587.2 85.8,130.32 v1(85.8,127.25) ; C4636.1 107.31,53.95 R4682.1 106.11,53.95 105.97,54.1 v1(105.34,54.1) 104.55,53.31 R4582.1 104.54,52.57 R4560.1 ; v1(74.83,48.41) 75.31,47.92 R4545.2 ; R4551.2 R4544.2 66.97,98.01 65.81,96.85 v1(65.81,96.6) ; U4701.8 74.8,51.1 75.4,51.71 C14.1 ; R35.2 R4546.2 75.43,43.8 v1(75.4,43.76) ; R3178.1 22.01,123.49 Q3151.1 ; R3178.1 21.68,122.9 21.21,122.43 19.76,122.43 19.35,122.84 R3179.1 19.57,123.39 Q3150.1 ; C14.1 75.5,51.87 R4660.1 ; C14.1 75.4,52.99 v5(74.7,53.7) ; v1(105.33,56.57) 105.33,58.14 106.21,59.02 106.45,59.02 ; R4550.1 71.48,106.88 v5(71.73,107.13) ; R3964.2 111.28,36.41 110.53,37.16 110.53,39.46 105.82,44.17 ; v5(71.73,107.13) 70.69,107.13 R4549.1 ; v5(71.73,107.13) 71.77,107.17 R4575.2 ; 105.82,44.17 C4506.1 v1(104.74,47.04) 104.54,47.24 R4583.1 ; 106.45,59.02 R4686.1 ; 106.45,59.02 R4681.1 ; v1(73.81,105.41) R4548.2 ; R4625.1 v1(65.83,62.31) ; 91.53,128.3 C7120.1
  BOTTOM w0.508: v1(63.9,155.73) 65,156.82 65,157.68 65.58,158.27 65.58,162.81 v1(66.54,163.78) 66.62,163.85 75,163.85 75.36,163.5 v1(75.36,163.37)
  vias: v5(103.1,110.82)
P1V8S: length 281.5
  TOP w0.254: U301.4 73.24,150.18
  TOP w0.381: D7501.2 68.42,149.02 C306.1 67.52,149.04 C312.1 ; Q311.1 106.08,154.93 v1(105.81,155.19) ; R4649.2 109.09,152.65 v1(109.09,154.51) ; v1(113.28,132.97) 111.78,132.97 110.49,134.26 108.4,134.26 108.02,134.64 108.02,135.81 v1(108.1,135.89) ; R3950.2 v1(100.87,43.01)
  TOP w0.508: C312.1 67.35,148.96 66.67,148.28 65.12,148.28 v1(64.69,148.72) 64.69,147.62 59.67,142.59 47.69,142.59 45.56,140.47 45.56,139.8 45,139.24 v1(44.98,139.24) ; 73.24,150.18 74.24,151.18 74.24,154.36 74.75,154.86 v1(75.08,154.86) ; R4649.2 109.29,151.92 109.29,141.91 107.69,140.31 107.69,136.3 v1(108.1,135.89)
  L3 w0.508: v1(75.08,154.86) 74.95,154.86 73.93,155.89 71.17,155.89 66.31,151.03 65.5,151.03 64.69,150.22 v1(64.69,148.72)
  L4 w0.381: v1(100.87,43.01) 100.87,44.11 108.06,51.31 108.06,63.74 110.69,66.37 110.69,80.52 107.92,83.29 107.92,94.3 112.86,99.24 112.86,101.5 114.27,102.91 114.27,111.33 v1(113.28,112.32) 113.28,113.45 113.84,114.01 113.84,116.78 113.93,116.87 113.93,117.32 113.49,117.75 113.07,117.75 112.48,118.34 112.48,132.17 v1(113.28,132.97)
  L4 w0.508: v1(102,134.59) 99.67,132.26 88.41,132.26 87.83,132.84 87.83,133.55 88.41,134.14 v1(88.64,134.14) 88.64,134.16 87.09,135.71 80.49,135.71 79.98,135.2 79.98,133.84 81.86,131.96 81.86,129.29 81.35,128.78 70.53,128.78 65.83,133.48 59.05,133.48 58.34,134.19 56.72,134.19 55.03,132.5 54.05,132.5 53.66,132.89 52.77,133.78 v1(46.1,133.78)
  BOTTOM w0.381: R28.1 113.13,112.17 v1(113.28,112.32) ; v1(109.09,154.51) 108.4,155.19 v1(105.81,155.19)
  BOTTOM w0.508: v1(46.1,133.78) 44.88,135 44.88,139.14 v1(44.98,139.24) ; v1(108.1,135.89) 107.85,135.64 104.75,135.64 103.7,134.59 v1(102,134.59) 101.96,134.55 101.96,133.63 102.32,133.26 103.16,133.26 103.68,132.74 103.68,130.28 104.2,129.75 Q3500.1 ; v1(88.64,134.14) 88.13,134.14 87.22,133.22 87.22,131.11
  vias: v2(88.08,130.28)
P1V15A: length 15.1
  TOP w0.254: C4532.1 62.95,82.61 62.95,82.93 v1(63.24,83.21) ; C4536.1 62.68,86.43 v1(62.45,86.2) 62.36,86.3 62.29,86.37 62.29,86.65 61.88,87.06 61.68,87.06 C4535.1 ; C4538.1 63.23,79.21 v1(63.23,78.59)
  TOP w0.381: v3(62.46,77.86) 62.42,77.82 C4539.1 62.03,77.62 ; 63.25,78.78 C4538.1
  BOTTOM w0.254: U4500.AM19 62.4,77.82 62.41,77.82 62.45,77.86 v3(62.46,77.86) 62.84,78.24 U4500.AK21 63.2,78.59 v1(63.23,78.59) ; U4500.AK36 62.87,85.83 U4500.AJ35 ; U4500.AK36 62.47,86.2 v1(62.45,86.2) ; U4500.AK36 62.87,85.8 62.94,85.73 62.94,85.16 U4500.AK35 62.62,84.84 62.62,84.54 U4500.AK33 ; C4537.1 v1(74.84,117.45) ; U4500.AM29 U4500.AK30 63.19,83.14 63.19,83.17 v1(63.24,83.21) ; C4533.1 v1(74.84,118.34) ; C4540.1 74.36,116.66 v1(74.84,116.66) ; C4534.1 v1(74.84,119.23)
  BOTTOM w0.381: C7517.1 v1(85.39,118.8)
  vias: v5(102.94,124.23) v5(102.94,123.32)
P1V24A: length 18.4
  TOP w0.254: v1(73.5,90.06) 73.91,90.47 C4598.1 ; v1(65.57,85.46) 65.63,85.46 66.37,86.19 v1(66.39,86.19)
  TOP w0.381: 71.47,88.58 C4589.1 ; C4599.1 69.89,88.58 ; 72.5,87.89 C4590.1 ; v3(69.51,83.17) 69.66,83.17 70.13,83.64 C4593.1 ; 67.91,86.76 C4596.1 67.91,88.22 C4597.1 ; v1(66.39,86.19) 67.04,86.19 C4594.1 67.07,86.61 ; 70.58,88.58 C4591.1 ; v1(69.5,86.21) 69.8,86.51 C4595.1 70.13,86.79 v1(70.45,87.1) ; 72.19,87.58 C4588.1 ; 69.82,87.69 C4592.1
  BOTTOM w0.254: v3(69.51,83.17) 69.5,83.17 U4500.V30 ; v1(70.45,87.1) 70.79,86.76 U4500.P38 ; U4500.AD38 66.39,86.19 v1(66.39,86.19) U4500.AC36 ; U4500.H44 73.5,89.84 v1(73.5,90.06) ; v1(67.17,83.19) 67.13,83.15 67.13,83.15 U4500.AC30 ; U4500.Y25 68.24,80.61 68.24,81.18 U4500.Y27 68.72,81.66 v1(68.75,81.66) ; U4500.V36 69.47,86.17 69.47,86.18 v1(69.5,86.21) ; U4500.AD35 65.57,85.46 v1(65.57,85.46) 65.55,85.44 65.55,85.41 U4500.AF35 ; PAD61000.2 v5(100.12,126.24)
  BOTTOM w0.381: C7516.2 90.62,123.39 v1(90.52,123.29) ; C7517.2 v1(85.39,116.64)
  vias: v1(70.43,88.34) v1(70.43,87.72) v1(71.56,87.77) v5(100.12,127.15)
P1V35: length 287.3
  TOP w0.254: v1(58.47,113.84) 58.47,113.84 C4120.1 ; C4203.1 27.53,77.83 v1(27.02,77.83) ; v1(27,57.67) 26.93,57.6 C4194.1 ; v1(59.34,112.38) 59.34,112.95 C4128.1 ; v1(35.01,58.16) 35.01,58.16 C4211.1 ; v1(68.85,113.85) 68.96,113.85 69.77,114.67 R4110.2 ; v1(60,76.43) 60.07,76.43 60.7,77.06 v1(60.87,77.06) ; C4175.1 38.97,58.23 v1(39.02,58.18) ; v1(48.24,57.68) 48.06,57.86 C4168.1 ; C4197.1 36.52,56.52 36.19,56.84 v1(36.15,56.84) ; v1(66.87,107.78) 66.65,107.56 C4105.1 ; v1(29.82,65.37) 29.97,65.52 C4207.1 ; R4104.2 67.44,116.71 v1(66.93,116.19) 66.74,116.37 C4119.1 ; v1(33.43,105.17) 33.46,105.13 C4138.1 ; C4129.1 65.24,104.76 v1(65.57,104.43) ; v1(36.62,70.43) 37.25,69.79 C4205.1 ; v1(57.94,56.17) 57.94,56.28 v1(58.65,56.99) 59.41,56.99 59.9,57.47 C4182.1 60.15,57.63 v1(60.49,57.29) ; v1(37.42,104.38) 37.42,104.38 C4153.1 ; v1(39,105.77) 39,105.75 39.4,105.36 C4142.1 ; v1(60.67,52.17) 60.68,52.18 C4184.1 ; v1(60.88,85.45) 60.81,85.52 59.79,85.52 ; v1(30.24,104.34) 30.37,104.47 C4133.1 ; v1(28.56,92.98) 28.23,92.98 C4152.1 ; v1(36.56,102.25) 36.56,101.53 36.38,101.34 36.38,100.58 ; v1(39.84,98.76) 39.68,98.59 C4139.1 ; C7540.1 28.44,79.64 ; v1(58.3,46.14) 58.33,46.12 C4183.1 ; v1(33.38,77.76) 33.46,77.68 C4210.1 ; v1(66.92,114.59) 66.3,114.59 C4127.1 ; 38.55,94.03 v1(38.52,94.05) 38.48,94.01 C4146.1 ; v1(60.37,106.97) 60.45,106.9 C4121.1 ; C4140.1 26.74,105.96 v1(26.69,106)
  TOP w0.381: C4168.1 48.06,58.81 ; v1(60.37,110.21) 60.34,110.18 C4106.1 59.58,110.63 ; 45.21,42.75 C4171.1 ; C4171.1 45.61,41.33 46.71,40.23 R4172.2 ; C4171.1 45.61,43.48 v1(45.77,43.64) ; 37.25,69.12 C4205.1 ; 48.76,53.21 C4172.1 47.9,53.21 ; 25.18,48.86 C7574.1 24.74,49.48 ; 33.14,64.35 C4206.1 ; C4203.1 28.14,77.67 ; 24.04,77.21 C7584.1 ; C7584.1 25.24,77.21 ; C7584.1 24.48,77.83 ; 67.23,110.67 C4118.1 ; 53.57,44.13 C4174.1 ; C4174.1 54.17,44.57 ; C4174.1 53.57,45.15 ; 66.69,48.58 C4180.1 ; 45.93,50.22 C4186.1 45.93,51.29 v1(46,51.36) ; 66.45,107.5 C4105.1 ; C7583.1 50.31,39.16 ; C4207.1 30.51,65.92 ; v1(27.3,84.6) 27.13,84.43 C4145.1 24.37,84.43 ; 52.78,109.87 C4108.1 ; 33.01,77.16 C4210.1 ; 52.97,55.68 C4170.1 ; C4170.1 52.32,56.13 ; C4170.1 52.97,56.73 ; 57.88,45.51 C4183.1 ; C4208.1 36.75,61.68 ; C4134.1 31.07,96.59 ; 27.57,79.19 C7540.1 ; C7537.1 34.62,64.75 ; 45.22,48.94 C7532.1 45.22,49.87 ; 25.87,57.6 C4194.1 ; 31.64,70.22 C4212.1 ; 46.66,113.45 C4131.1 ; 60.17,82.91 C4573.1 ; 38.73,98.59 C4139.1 ; 27.41,92.6 C4152.1 ; C4184.1 61.08,52.83 ; 65.15,46.93 C7531.1 ; 65.19,50.12 C4188.1 ; C4188.1 64.55,50.72 ; C4188.1 64.79,50.27 ; 46.66,112.44 C4117.1 ; C4201.1 38.54,84.59 ; C4121.1 61.5,106.9 ; 42.81,114.83 C7572.1 43.91,114.83 ; 31.1,84.96 C4154.1 ; 27.81,97.61 C4141.1 ; C4202.1 36.9,84.98 ; 54.97,105.64 C4123.1 ; C4155.1 32.71,84.45 ; 38.48,92.78 C4146.1 ; 66.69,45.33 C4181.1 ; 58.75,116.55 C4126.1 ; 46.65,54.03 C4176.1 ; C4176.1 46.12,54.48 ; C4176.1 46.65,55.06 ; 31.47,65.9 C4173.1 31.47,65.13 31.19,64.85 ; C4124.1 47.1,110.82 ; 54.35,46.99 C4177.1 53.95,47.66 v1(54,47.71) ; 37.64,91.94 C4147.1 ; R4175.2 66.74,49.34 v1(66.34,48.94) ; 66.69,46.96 C4187.1 ; 46.36,116.36 C4109.1 ; 35.95,64.36 C4209.1 35.51,64.92 ; v1(35.88,84.14) 35.91,84.17 C4214.1 37.16,84.17 ; C4125.1 53.62,107.81 ; 37.86,58.23 C4175.1 ; v1(45.95,47.46) 46.09,47.31 C4178.1 ; 28.72,77.98 C4198.1 ; 34.37,98.14 C4136.1 ; v1(46.13,108.27) 45.87,108 C4130.1 ; 53.22,106.47 C4122.1 ; 33.83,71.17 C4213.1 ; 33.1,91.77 C4137.1 ; 65.14,45.25 C4189.1 ; 39.04,91.08 C4149.1 ; C4179.1 65.22,54.77 v1(65.46,54.53) ; 58.9,77.49 C4571.1 ; 36.04,90.95 C4148.1 ; 40.66,70.09 C4204.1 ; 30.7,57.43 C4195.1 ; 32.05,57.46 C4199.1 ; 40.02,68.72 C4196.1 ; 67.03,112.33 C4104.1 ; C4157.1 29.23,93 ; 59.3,49.49 C4185.1 ; 38.26,97.61 C4135.1 ; C7573.1 64.43,120.64
  L3 w0.254: v1(60.88,85.45) 60.21,86.12 v1(59.87,86.12) 59.87,86.38 59.27,86.99 v1(59.27,87.04) 59.27,87.27 59.42,87.42 59.42,88.01 59.41,88.02 59.41,89.44 58.9,89.96 v1(58.67,89.96) ; v1(60,76.43) 59.29,75.72 v1(59.29,75.54) ; v1(59.42,105.16) 59.88,105.62 59.88,106.49 v1(60.37,106.97)
  L4 w0.254: v1(39,105.77) 39.25,105.53 39.25,104.59 v1(41.3,102.55) ; v1(65.46,54.53) 66.36,54.53 66.92,53.97 66.92,52.83 v1(66.35,52.25) 65.5,51.4 v1(65.5,51.35) ; v1(30.24,104.34) 31.02,104.34 31.92,105.24 33.35,105.24 v1(33.43,105.17)
  BOTTOM w0.089: 33.02,71.48 33.02,71.48 U4107.K2
  BOTTOM w0.102: 32.31,70.32 32.64,70.65 32.64,71.09 33.02,71.48 ; 34.11,92.32 33.71,92.32 33.39,92 33.39,91.48 33.17,91.26 33.17,91.05 U4102.K8 ; v1(32.83,97.72) 32.64,97.91 32.64,98.63 33.02,99.01 U4103.K2 ; U4102.K2 33.02,85.96 32.61,85.55 v1(32.61,84.83) ; U4100.K2 60.64,112.19 60.25,112.58 59.67,112.58 59.47,112.38 v1(59.34,112.38) ; U4107.K8 33.02,76.67 33.38,77.03 v1(33.38,77.76) ; 33.57,64.6 33.39,64.42 33.39,63.95 33.02,63.58 U4106.K8 ; U4101.K8 52.63,112.19 52.75,112.07 52.84,111.98 53.01,111.81 53.56,111.81 ; U4103.K8 33.02,104.18 33.43,104.59 v1(33.43,105.17) ; U4100.K8 65.74,112.19 66.1,111.82 66.9,111.82 v1(66.92,111.83)
  BOTTOM w0.254: v1(29.84,77.98) 30.61,77.22 U4107.N9 ; v1(52.11,109.38) 52.11,109.4 U4101.G7 ; C4156.1 25.63,106 v1(26.69,106) 26.71,106.02 27.75,106.02 29.02,104.75 U4103.R9 ; v1(54.64,110.37) 53.96,111.05 53.96,111.42 53.56,111.81 ; v1(38.62,77.8) 38.62,77.8 U4107.C9 ; U4105.H9 v1(46,51.36) ; U4500.AM36 U4500.AN36 61.26,85.83 v1(60.88,85.45) 61.26,85.07 U4500.AN35 ; U4103.N9 30.62,104.73 v1(30.24,104.34) ; U4500.BE51 56.41,92.92 56.49,93 v1(56.52,93) ; U4105.C9 U4105.D9 ; U4107.B2 39.45,71.62 v1(39.85,71.22) 40.22,70.85 U4107.A1 ; v1(66.41,45.36) 66.4,45.35 U4104.R1 ; U4102.E9 37.02,91.96 v1(37.53,92.47) 37.82,92.18 U4102.D9 ; U4105.N1 53.62,46.95 54,47.34 v1(54,47.71) ; v1(65.57,104.43) 65.57,104.44 U4100.A8 ; v1(35.88,84.14) 36.22,84.48 U4102.F1 ; U4107.D2 37.83,71.62 v1(38.24,71.21) 38.62,70.83 U4107.C1 ; v1(59.01,109.09) 59.11,108.99 U4100.F1 ; U4104.A8 60.26,57.06 v1(60.49,57.29) ; U4107.A8 40.53,76.42 v1(40.75,76.64) ; U4500.BG3 54.93,69.64 ; 54.93,69.64 U4500.BH4 ; 54.93,69.64 54.93,70.15 v1(54.91,70.18) ; U4103.G7 35.69,102.89 35.79,102.89 36.43,102.25 v1(36.56,102.25) ; U4100.C1 59.99,106.59 v1(60.37,106.97) 60.77,107.37 U4100.D2 ; v1(54.62,67.17) 54.62,67.33 55.43,68.15 55.43,68.29 U4500.BE1 ; U4106.N9 30.62,64.75 30,65.37 v1(29.82,65.37) 29.71,65.37 29.11,64.77 29.11,64.26 U4106.R9 ; U4500.AM18 61.91,76.88 61.44,76.88 61.37,76.8 61.35,76.8 U4500.AN18 61.21,76.73 v1(60.87,77.06) 60.87,77.08 U4500.AN19 ; U4500.BH4 54.37,69.66 U4500.BH5 ; U4500.BH4 53.92,69.64 U4500.BJ3 ; v1(31.82,57.31) 31.07,57.31 U4106.N1 ; v1(54.91,92.38) 54.85,92.31 U4500.BH49 54.32,92.27 U4500.BJ49 ; v1(58.74,72.67) 58.99,72.67 U4500.AV10 ; v1(27.53,70.34) 28.54,70.34 U4107.R1 ; U4101.D2 47.34,107.01 v1(47.32,107.01) 46.92,106.61 U4101.C1 U4101.B2 U4101.A1 ; v1(38.7,92.31) 38.62,92.23 U4102.C9 ; v1(35,71.21) 34.62,71.6 U4107.H2 ; U4104.C1 65.86,54.94 v1(65.46,54.53) 65.07,54.15 U4104.D2 ; U4107.D9 37.82,77.28 v1(37.45,77.65) 37.02,77.22 U4107.E9 ; v1(59.27,87.04) 58.97,86.75 U4500.AV38 ; v1(60.67,52.17) 61.06,51.78 U4104.G7 ; U4100.E9 66.46,108.19 v1(66.87,107.78) 66.48,107.39 U4100.D9 U4100.C9 ; U4102.R1 28.32,84.6 v1(27.3,84.6) ; U4106.A8 40.22,63.36 v1(39.84,62.98) ; 48.26,63.2 48.26,63.61 48.64,63.99 v1(48.64,64) 48.65,64 48.98,64.34 C4578.1 49.96,64.9 49.96,64.92 C4577.1 50.53,65.61 v1(51.26,66.34) 51.6,66.68 51.6,66.87 52.35,67.62 v1(52.35,67.63) 52.73,68 52.73,68 v1(52.8,68.07) 52.8,68.07 53.26,68.52 v1(53.26,68.54) 53.28,68.54 53.64,68.89 U4500.BJ2 U4500.BJ3 ; U4103.C9 38.62,105.39 v1(39,105.77) ; U4105.G7 48.1,51.84 48.1,52.05 48.57,52.52 v1(48.57,52.6) ; 32.31,70.32 32.06,70.07 v1(31.4,70.07) ; v1(40.83,91.01) 40.72,90.9 U4102.A8 ; U4101.E9 U4101.D9 54.28,107.39 55.42,106.25 v1(55.6,106.25) ; 34.11,92.32 v1(34.17,92.32) 34.62,91.87 U4102.H9 ; C4132.1 69.75,114.76 v1(68.85,113.85) ; v1(35.81,75.23) U4107.G7 ; v1(39.92,67.65) 39.55,67.28 39.55,65.92 38.62,65 38.62,64.17 U4106.C9 ; U4500.AY44 58.53,89.86 58.58,89.86 v1(58.67,89.96) 58.92,89.96 U4500.AV44 ; v1(60,76.43) 59.98,76.44 59.98,76.62 U4500.AU18 ; v1(45.57,116.57) 45.95,116.19 U4101.R1 ; U4101.N9 54.04,114.59 54.5,115.05 54.5,115.36 v1(54.52,115.39) ; U4100.B2 60.52,105.54 U4100.A1 59.58,104.99 v1(59.42,105.16) ; U4500.BJ5 U4500.BJ3 ; v1(30.24,84.82) 30.62,85.2 U4102.N1 ; U4101.F1 46.85,108.99 v1(46.13,108.27) ; U4105.D2 52.01,54.16 v1(52.42,54.57) 52.8,54.95 U4105.C1 ; v1(47.33,114.2) 46.94,114.59 U4101.N1 ; U4100.R9 66.92,116.19 v1(66.93,116.19) ; v1(48.24,57.68) 48.13,57.68 47.21,56.76 U4105.A8 ; v1(66.41,46.97) 66.4,46.95 U4104.N1 ; U4104.D9 59.02,54.15 57.94,55.23 v1(57.94,56.17) ; U4104.E9 59.46,53.35 v1(59.06,52.95) ; U4102.N9 30.62,92.31 30.03,92.91 v1(29.82,92.91) ; 53.44,43.89 53.44,44.73 U4105.R1 ; v1(66.35,52.25) 66.05,52.55 U4104.F1 ; U4101.H2 48.1,110.21 v1(48.13,110.21) ; U4106.F1 36.22,56.91 v1(36.15,56.84) ; U4100.G7 64.77,109.78 v1(65.16,109.39) ; U4107.N1 30.05,70.25 v1(29.82,70.25) ; v1(34.24,77.68) 34.24,77.6 U4107.H9 ; v1(60.37,110.21) 60.39,110.21 U4100.H2 ; U4101.H9 53.44,110.59 54.02,110.02 54.02,109.72 55.4,108.34 v1(55.4,108.3) ; v1(59.87,86.12) 59.87,85.83 U4500.AU36 ; U4103.H2 34.71,99.15 35,98.86 v1(35,98.75) ; U4106.H2 34.62,58.55 v1(35.01,58.16) ; v1(35.83,90.52) 35.42,90.11 U4102.G7 ; U4105.R9 45.73,44.67 45.73,43.68 v1(45.77,43.64) ; v1(55.53,104.15) 55.52,104.15 53.24,104.15 52.52,104.88 U4101.A8 ; U4105.H2 52.03,50.95 v1(52.42,51.33) ; v1(57.73,72.58) 57.91,72.58 U4500.AY10 ; v1(34.99,85.69) 34.99,85.73 U4102.H2 ; U4105.B2 52.01,55.75 U4105.A1 52.82,56.55 v1(53.52,57.25) ; v1(53.78,53.34) 53.78,53.33 53.01,52.55 52.81,52.55 U4105.F1 ; v1(36.6,61.92) 36.41,62.11 36,62.11 35.54,62.57 U4106.G7 ; U4500.AV16 59.29,75.63 v1(59.29,75.54) ; U4100.N1 59.02,114.59 58.47,114.04 v1(58.47,113.84) ; U4500.AN27 61.28,81.28 v1(61.67,80.89) 61.68,80.89 62.05,80.52 U4500.AM25 ; v1(28.56,92.98) 28.86,92.98 29.13,92.71 29.13,91.81 U4102.R9 ; U4101.C9 53.68,106.59 v1(54.3,105.96) ; U4102.B2 U4102.A1 40.22,84.49 v1(40.06,84.33) ; U4106.B2 39.4,58.57 v1(39.02,58.18) 38.62,57.79 U4106.C1 U4106.D2 ; U4500.BE53 55.43,94.26 55.43,94.41 55.29,94.55 v1(55.29,94.71) ; U4106.H9 34.62,64.45 v1(34.18,64.89) 33.86,64.89 33.57,64.6 ; v1(38.52,94.05) 38.52,94.89 36.22,97.19 36.22,98.35 U4103.F1 ; U4100.N9 66.91,114.59 v1(66.92,114.59) ; U4100.H9 v1(65.98,110.98) ; U4103.A1 40.22,98.38 v1(39.84,98.76) 39.45,99.15 U4103.B2 ; v1(36.62,70.43) 36.22,70.82 U4107.F1 ; U4102.C1 38.61,85.3 v1(38.2,85.71) 37.82,86.09 U4102.D2 ; v1(56.57,69.57) 56.51,69.63 U4500.BE3 ; v1(58.65,56.99) 58.68,56.96 58.68,55.59 59.32,54.95 U4104.C9 ; v1(58.74,117.68) 58.74,117.42 U4100.R1 ; v1(27.02,77.83) 28.41,77.83 U4107.R9 ; U4103.D2 37.83,99.15 v1(38.24,98.75) 38.62,98.36 U4103.C1 ; U4103.A8 40.22,103.95 40.37,103.8 40.59,103.8 41.3,103.1 v1(41.3,102.55) ; U4106.E9 37.02,64.22 v1(37.4,64.59) U4106.D9
  BOTTOM w0.381: C4132.1 70.61,114.76 ; C7568.1 26.36,53.76 ; C7585.1 55.52,36.48 ; C4215.1 24.99,57.66 ; C4215.1 25.76,56.99 ; C4215.1 24.54,56.99 ; 42.66,118.07 C7567.1 ; 24.76,105.58 C4156.1 ; 63.67,36.79 R7247.2 ; C7578.1 63.31,121.98 ; R7229.2 38,37.29 ; C7569.1 20.23,76.35 ; C7580.1 72.1,113.47 ; C7979.1 20.23,102.1
  vias: v1(27.55,97.54) v1(31.39,96.86) v1(32.23,56.85) v1(45.87,49.71) v1(46.45,112.6) v1(46.82,53.79) v1(49.48,39.39) v1(50.22,39.39) v1(51.15,39.14) v1(52.62,98.07) v1(52.94,122.07) v1(53.18,93.39) v1(53.35,92.73) v1(53.35,49.11) v1(53.86,122.04) v1(54.77,122.04) v1(55.68,122.04) v1(56.6,122.04) v1(57.92,40.2) v1(58.56,40.2) v1(58.85,50.55) v1(61.63,39.14) v1(62.24,39.14) v1(62.85,39.14) v1(63.48,39.14) v1(65.87,43.35) v1(66.35,43.81) v2(61.08,117.59) v5(38.63,43.36) v5(39.65,43.36) v5(40.66,43.36) v5(41.68,43.36) v5(42.69,43.36) v5(43.71,43.36) v5(57.95,121.92) v5(58.86,121.92) v5(59.77,121.92)
P3V3_CARD: length 6
  BOTTOM w0.254: C1306.1 55.5,127.48 ; C1304.1 54.15,131.29
  BOTTOM w0.381: R1307.1 29.05,130.02 29.82,130.78 ; C1302.1 30.09,133.86
  BOTTOM w0.762: C1301.1 30.46,131.68
  vias: v2(54,128.45)
P3V3_LDO: length 274.5
  TOP w0.254: R323.1 108.33,152.02 108.79,151.56 108.79,142.19 106.52,139.93 v1(106.52,139.19) ; v1(83.03,137.01) 83.03,137.21 83.28,137.46 87.8,137.46 88.85,138.51 88.85,140.18 88.32,140.71 R7000.1 87.58,141.81 87.58,142.6 89.18,144.2 92.04,144.2 92.61,144.77 96.35,144.77 97.79,143.34 97.79,142.92 98.89,141.82 98.89,140.22 99.25,139.85 v1(99.42,139.85)
  TOP w0.381: v1(85.19,127.25) 84.45,127.25 82.53,125.33 82.53,119.9 82.45,119.81 82.45,119.79 v1(77.47,114.81) ; v1(104.52,103.71) 103.47,102.66 103.47,95.27 104.21,94.53 104.21,53.8 v2(103.62,53.21) v1(102.46,52.04) ; v1(81.18,135.1) 81.18,135.15 v1(83.03,137.01)
  L3 w0.254: v1(99.42,139.85) 100.17,139.85 101.14,138.88 105.67,138.88 105.98,139.19 v1(106.52,139.19)
  L4 w0.254: v1(79,140.68) 79,140.53 78.99,140.52 78.99,138.05 79.96,137.08 82.95,137.08 v1(83.03,137.01)
  L4 w0.381: v1(113.41,139.06) 115.16,137.31 115.16,125.22 115.87,124.51 v1(115.87,108.03) ; v1(104.52,103.71) 99.84,103.71 98.32,102.18 94.18,102.18 92.54,103.82 82.62,103.82 v1(80.67,105.77) ; v1(102.46,52.04) 101.67,52.04 101.55,51.93 101.5,51.93 101.18,51.61 101.18,51.56 92.45,42.83 92.45,41.73 90.01,39.29 79.3,39.29 v1(77.25,41.34) ; v1(81.18,135.1) 81.18,133.45 85.04,129.59 85.04,127.41 v1(85.19,127.25)
  BOTTOM w0.254: R4834.1 116.57,110.73 116.57,108.3 116.3,108.03 v1(115.87,108.03) 115.08,108.03 113.63,106.57 R4642.2 113.63,106.02 R4639.2
  BOTTOM w0.381: R4445.1 R4446.1 79.68,104.78 v1(80.67,105.77) 80.9,105.77 81.78,106.65 81.78,113.84 79.98,115.65 78.69,115.65 78.31,115.26 R4442.2 ; U4702.10 74.12,38.06 74.42,37.77 75.98,37.77 77.25,39.04 v1(77.25,41.34) ; R4442.2 78.31,113.37 C4441.1 78.33,112.06 U4441.6 ; R4442.2 77.64,114.99 v1(77.47,114.81) ; v1(113.41,139.06) 113.1,139.06 112.14,140.03 109.12,140.03 108.85,140.3 107.63,140.3 v1(106.52,139.19)
P3V3_RTC: length 74.7
  TOP w0.381: 82.8,64.19 84.4,62.58 84.4,56.11 82.25,53.96 80.3,53.96 79.21,52.87 77.61,52.87 75.99,51.26 75.99,41.68 77.92,39.75 91.11,39.75 v1(94,42.65) ; v1(76.35,71.2) 76.67,70.89 C4603.1 ; C4608.1 78.06,70.89 78.43,70.52 78.43,70.52 78.47,70.48 79.35,70.48 81.24,68.59 ; C4608.1 C4603.1 ; C4608.1 77.9,71.66 R4580.2 ; R704.2 81.71,67.67 v2(82.09,67.28) ; C4603.1 R4581.2
  BOTTOM w0.254: U4500.C5 76.23,71.09 v1(76.35,71.2) 76.5,71.2 76.81,70.89 U4500.B6
  BOTTOM w0.381: v1(94,42.65) 94,39.14 92.53,37.67 92.53,32.16 91.34,30.97 C6051.1 91.34,28.47 R6055.1
P3V3_TOUCHPAD: length 132.5
  TOP w0.381: v1(88.04,147.63) 88.47,148.06 R308.2 R309.2 ; v1(107.72,145.19) 107.76,145.22 v2(107.76,149.76) 107.76,151.43 R311.2
  L4 w0.381: v1(106.71,67.36) 107.24,67.88 107.24,80.45 105.76,81.93 105.76,95.36 107.29,96.9 107.29,98.67 109.84,101.22 109.84,105.68 110.42,106.26 110.42,111.09 108.87,112.64 108.87,119.34 108.87,119.34 108.87,120.15 108.58,120.45 108.58,121.66 109.13,122.21 109.13,135.7 107.74,137.09 107.74,145.16 v1(107.72,145.19)
  BOTTOM w0.356: C4631.2 108.33,59.05 U4503.7 108.33,57.2 108.73,56.8 R4683.2
  BOTTOM w0.381: R4684.2 R4683.2 ; C4631.2 108.34,59.64 108.63,59.93 108.63,61.57 108.22,61.98 Q281.2 105.63,62.82 D282.1 105.43,66.08 v1(106.71,67.36) 106.62,67.45 CN281.8 ; v1(88.04,147.63) 89.67,149.25 90.65,149.25 91.16,148.74 92.9,148.74 93.4,149.24 96.7,149.24 96.98,148.96 97.85,148.96 98.16,149.26 99.47,149.26 100.53,148.21 100.53,148.21 103.07,148.21 105.08,146.2 106.71,146.2 v1(107.72,145.19)
P3V3A: length 312.9
  TOP w0.381: v1(116.13,125.35) 116.42,125.06 116.42,107.94 116.84,107.52 v1(116.84,103.86) ; v1(38.12,124.99) 39.14,123.98 48.3,123.98 50.19,125.87 57.57,125.87 v5(58.77,124.66) ; v1(105.23,116.94) 105.23,115.24 101.85,111.86 v1(101.85,111.38) ; v1(93.21,31.24) 90.54,31.24 v2(89.99,31.79) 87.52,34.26 69.54,34.26 68.05,35.76 v1(68.05,36.38)
  TOP w0.508: v1(84.35,119.81) 86.31,119.81 89.18,122.68 96.31,122.68 v1(97.33,123.7) ; v1(104.8,100.99) 105.43,101.62 105.43,104.65 104.39,105.69 104.39,108.25 101.85,110.79 v1(101.85,111.38)
  L3 w0.508: v1(101.85,111.38) 100.91,112.32 100.91,116.08 99.96,117.04 99.96,122.01 98.78,123.19 97.84,123.19 v1(97.33,123.7)
  L4 w0.381: v1(116.13,125.35) 116.13,141.17 v1(113.94,143.36)
  L4 w0.508: v1(104.8,100.99) 103.74,99.93 103.74,97.79 102.68,96.73 102.68,71.16 101.62,70.1 101.62,67.89 v1(100.78,67.06) ; v1(84.35,119.81) 84.17,119.63 v1(81.4,119.63) 75.31,119.63 72.62,122.33 69.21,122.33 68.07,123.47 60.88,123.47 v5(59.69,124.66)
  BOTTOM w0.254: v1(113.94,143.36) 113.94,144.07 113.31,144.7 107.49,144.7 106.44,145.75 104.89,145.75 104.72,145.92 103.76,145.92 102.52,147.16 R7125.1 ; U60600.17 99,113.02 99.78,112.24 100.43,112.24 100.63,112.04 ; C1307.1 57.32,125.2 ; v1(81.4,119.63) 81.74,119.97 81.74,125.37 83.82,127.45 83.82,128.14 83.02,128.94 R4586.2
  BOTTOM w0.381: C3504.1 115.93,126.19 U3500.5 112.59,126.19 112.14,125.74 112.14,119.9 111.42,119.18 R4656.2 ; C3504.1 115.95,127.31 C3505.1 ; C3504.1 115.95,125.52 v1(116.13,125.35) ; 100.63,112.04 101.43,111.24 C7000.1 ; R4644.1 116.93,103.95 v1(116.84,103.86) 116.27,103.3 R4641.1 ; v1(38.12,124.99) 37.36,124.99 36.09,126.26 31.19,126.26 29.85,124.92 R4661.2 R4584.2 ; U4703.5 111.59,116.16 111.21,115.78 107.23,115.78 106.04,116.97 105.36,116.97 105.33,116.94 v1(105.23,116.94) ; R7246.2 68.05,36.35 v1(68.05,36.38)
  BOTTOM w0.508: 99.09,48.01 R4652.2 ; 99.09,48.01 101.09,50.01 101.09,51.64 102.05,52.6 R7245.2 102.37,53.78 104.34,55.75 104.34,59.63 103.6,60.36 103.6,60.72 103.6,63.91 100.78,66.73 v1(100.78,67.06) ; 99.09,48.01 96.73,45.65 R3966.2 95.04,41.67 95.04,39.34 94.33,38.63 94.33,34.03 93.21,32.91 v1(93.21,31.24) ; U4703.5 111.59,117.88 R4656.2
P3V3A_PRIME: length 81.7
  TOP w0.381: C4604.1 76.17,69.12 v1(75.69,69.6) ; C4604.1 76.6,68.45 R4835.1 ; C4604.1 v2(77.58,68.88) 78.33,68.88 78.97,69.52 v1(79.04,69.52)
  L3 w0.381: v1(79.04,69.52) 79.5,69.98 79.5,71.96 80.05,72.51 80.05,74.17 82.17,76.29 v1(82.17,80.59) 82.17,82.94 85.97,86.74 88.31,86.74 88.97,87.39 96.86,87.39 99.3,89.83 99.3,93.92 99.16,94.06 99.16,94.07 97.37,95.85 97.37,95.92 97.37,97.11 97.37,97.11 97.37,101.17 99.17,102.97 99.17,107.05 100.76,108.64 100.76,110.82 v1(100.4,111.18)
  BOTTOM w0.254: U4500.D4 75.75,69.66 v1(75.69,69.6) 75.21,69.6 U4500.E3 ; U4500.C23 76.66,79.21 U4500.B22 77.09,78.92 78.2,78.92 78.41,79.12 ; 98.85,112.57 98.6,112.83 U60600.18
  BOTTOM w0.381: 98.85,112.57 100,111.43 C7001.1 100.96,110.07 100.96,109.26 101.33,108.89 104.53,108.89 R60001.2 ; v1(82.17,80.59) 82.16,80.6 C4607.1 C4602.1 79.89,80.6 78.41,79.12
P3V3AL: length 565.7
  TOP w0.254: R7230.2 81.28,137.06 82.18,137.96 C3009.2 82.18,138.53 81.93,138.79 v1(81.58,138.79)
  TOP w0.381: v1(67.38,163.01) L300.1 65.17,163.41 R346.2 ; v1(91.44,38.07) 90.78,38.73 77.26,38.73 74.85,41.15 74.85,44.22 75.41,44.78 75.41,51.39 78.83,54.81 82.24,54.81 83.77,56.34 83.77,61.42 81.79,63.39 v1(80.73,63.39) ; R321.1 R322.1 ; R322.1 85.93,148.31 v1(85.84,148.4) ; R322.1 86.49,147.87 87.37,146.99 89.68,146.99 v1(90.59,146.09) 90.59,146.25 90.99,146.65 98.04,146.65 99.45,145.24 v1(99.73,145.24) ; R390.2 66.99,152.74 v1(66.36,152.11) ; v1(112.35,157.3) R301.2 108.97,157.31 R320.1 ; v1(66.04,32.23) 67.52,33.72 86.22,33.72 v2(88.63,31.3) v1(90.65,29.29) v1(103.12,29.29) ; R317.1 R316.1 87.85,163.74 87.85,163.73 v1(87.81,163.7) ; v1(66.32,157.78) 65.91,157.38 R318.1 65.05,156.97 R334.1 ; R514.2 17.11,60.12 v1(16.77,60.46) ; 67.62,125.57 C7566.2
  L3 w0.381: v1(23.97,121.36) 27.01,118.31 v1(38.02,118.31) ; v1(35.58,142.77) 61.43,142.77 64.12,145.47 64.12,150.55 65.68,152.11 v1(66.36,152.11) 66.52,152.27 66.52,157.58 v1(66.32,157.78) ; v1(67.38,163.01) 69.68,165.3 86.2,165.3 v1(87.81,163.7)
  L4 w0.381: v1(23.97,121.36) 23.97,118.18 18.08,112.29 18.08,112.14 16.8,110.86 16.8,105.8 17.8,104.8 17.8,64.03 16.77,63 v1(16.77,60.46) ; v1(23.97,121.36) v1(21.16,121.36) ; v1(23.97,121.36) 29.79,127.18 29.79,136.98 v1(35.58,142.77) ; v5(63.49,127.87) 61.16,125.54 46.42,125.54 45.92,125.04 45.92,124.38 39.85,118.31 v1(38.02,118.31) ; v1(85.84,148.4) 82.08,152.16 82.08,158.8 81.69,159.18 v1(81.53,159.18) ; v1(81.58,138.79) 83.97,141.17 85.67,141.17 v1(90.59,146.09) ; v1(88.95,157.11) 88.95,157.16 87.81,158.3 v1(87.81,163.7) ; v1(66.32,157.78) 67.56,159.03 67.56,162.5 67.38,162.67 v1(67.38,163.01) ; v1(112.35,157.3) 116.3,153.35 116.3,147.56 116.3,147.13 115.12,145.95 114.87,145.95 v1(113.12,144.2) 112.67,143.75 112.67,137.57 114.65,135.58 114.65,125.01 115.17,124.49 115.17,103.52 v1(116.76,101.93) 116.6,101.93 108.73,94.07 108.73,85.09 111.72,82.1 111.72,66.07 111.42,65.77 109,63.35 109,35.17 108.8,34.96 108.8,33.29 104.8,29.29 v1(103.12,29.29)
  BOTTOM w0.254: v1(21.16,121.36) R2410.1 ; R2001.1 v1(116.76,101.93) ; D3000.5 v1(81.58,138.79)
  BOTTOM w0.381: R6007.2 65.78,31.98 v1(66.04,32.23) ; C7114.1 64.36,128.95 ; v1(113.12,144.2) 107.36,144.2 106.26,145.31 104.71,145.31 104.57,145.45 CN245.1 101.15,145.45 100.94,145.24 R7104.1 v1(99.73,145.24) ; v1(80.73,63.39) 81.08,63.74 D4501.1 ; v1(88.95,157.11) 87.98,156.14 87.98,155.44 87.51,154.96 86.47,154.96 85.01,156.43 85.01,160.44 85.16,160.59 85.16,161.04 84.84,161.36 83.17,161.36 81.53,159.73 v1(81.53,159.18) ; R6053.2 106.98,24.11 106.98,27.18 104.87,29.29 v1(103.12,29.29) ; C7110.1 65.15,129.08 ; v1(91.44,38.07) 91.44,37.41 91.45,37.39 91.45,32.12 90.65,31.32 v1(90.65,29.29)
  vias: v1(62.73,128.12) v1(66.14,127.67) v1(66.57,127.1) v1(71.93,123.95) v5(72.16,123.21)
P3V3AL_EC: length 5.6
  TOP w0.254: U301.102 69.41,161.03 69.26,160.88 67.46,160.88 C305.1
  TOP w0.381: L300.2 65.58,161.57 66.47,160.67 C305.1
P3V3AL_PB: length 38.3
  TOP w0.381: R9124.2 58.19,2.36 58.19,1.81 57.76,1.38 55.37,1.38 55.09,1.66 R9121.2
  TOP w0.508: CN9100.1 65.87,7.71 67.52,6.06 68.73,6.06 v5(68.78,6.01) ; v3(57.44,4.66) 57.44,4.02 R9123.2 58.13,2.42 R9124.2
  L4 w0.508: v4(50.34,5.92) 50.37,5.88 50.92,5.88 53.46,3.34 56.16,3.34 57.41,4.59 57.41,4.65 57.43,4.67 57.43,4.66 v3(57.44,4.66) 57.44,4.59 58.69,3.34 61,3.34 62.36,4.69 65.85,4.69 67.16,6 68.77,6 v5(68.78,6.01)
  BOTTOM w0.508: v4(50.34,5.92) 50.34,6.2 49.92,6.61 U9150.1 ; C9100.1 68.75,5.98 v5(68.78,6.01)
P3V3AL_R: length 48.2
  TOP w0.254: v1(77.32,157.68) 79.31,155.69 85.06,155.69 85.2,155.83 U301.46 86.86,155.83 87.51,156.49 ; U301.115 69.5,155.83 v1(69.24,155.57) ; U301.19 79.24,150.47 78.31,151.4 v1(77.84,151.4) ; U301.76 80.04,163.48 76.5,159.94 v1(76.5,159.33)
  TOP w0.381: v1(69.24,155.57) 69.19,155.53 C300.1 67.83,155.53 C313.1 67.33,156.02 67.33,156.76 R318.2 ; C301.1 89.03,153.48 C302.1 89.03,154.93 89.21,155.11 v2(89.21,155.63) 89.21,156.1 88.7,156.61 C303.1 87.63,156.61 87.51,156.49
  L3 w0.254: v1(76.5,159.33) 77.32,158.51 v1(77.32,157.68) 77.01,157.37 77.01,152.54 77.84,151.7 v1(77.84,151.4)
  BOTTOM w0.381: v1(77.32,157.68) 77.28,157.64 71.3,157.64 v1(69.24,155.57)
P3V3S: length 457.2
  TOP w0.254: v1(7.88,50.65) 7.88,50.66 8.01,50.79 U500.36 ; v5(58.67,128.4) 58.33,128.4 53.59,133.14 53.59,134.52 56.69,137.62 60.79,137.62 61.82,138.65 61.82,139.93 63.27,141.37 63.88,141.37 64.96,142.46 64.96,143.06 65.3,143.41 70.33,143.41 v1(70.46,143.28) ; v1(78.51,143) 78.48,143.03 R350.2 ; v1(15.29,50.42) 14.91,50.79 U500.1 ; R504.2 15.69,58.06 v1(16.15,58.52)
  TOP w0.381: v1(116.03,106.66) 115.82,106.66 115.44,106.28 115.44,99.03 115.85,98.63 v1(115.85,96.04) ; v1(77.17,106.38) 77.15,106.38 76.77,106 C7551.1 ; v1(100.22,154.08) 99.99,153.84 R3068.1 ; v5(19.33,22.96) 11.15,31.13 11.15,39.38 v1(11.19,39.41) ; R332.1 66.7,158.19 67.1,157.78 v1(67.51,157.78) ; v1(36.52,134.54) 48.99,134.54 56.89,126.64 58.87,126.64 ; 67.62,124.72 C7566.1
  L3 w0.254: v1(68.03,147.54) 68.86,146.71 68.86,144.88 v1(70.46,143.28)
  L3 w0.381: v1(16.15,58.52) 15.54,57.91 15.54,54.74 15.29,54.48 v1(15.29,50.42) ; v1(23.31,134.11) 23.31,135.28 24.97,136.93 34.13,136.93 v1(36.52,134.54) ; v1(64.61,151.97) 64.61,151.94 63.55,150.88 63.55,145.74 61.08,143.28 57.25,143.28 v1(56.68,143.85) ; v1(106.35,53.31) 106.35,60.27 v1(106.43,60.35) ; v1(11.19,39.41) 12.87,41.1 12.87,46.58 15.29,49 v1(15.29,50.42) ; v1(15.29,50.42) 14.55,49.68 9.47,49.68 8.5,50.65 v1(7.88,50.65)
  L4 w0.254: v1(100.22,154.08) 100.58,154.43 101.83,154.43 102.01,154.61 102.92,154.61 103.17,154.36 v1(103.17,154.33) ; v1(78.51,143) 77.64,143.87 71.02,143.87 70.46,143.3 v1(70.46,143.28)
  L4 w0.381: v1(77.14,107.1) 75.29,107.1 74.01,108.38 v1(73.91,108.38) ; v1(114.73,147.12) 115.29,147.68 115.29,152.4 113.38,154.3 v1(110.11,154.3)
  L4 w1.27: 58.5,126.49 44.09,126.49 21.16,103.56 21.16,35.89 22.25,34.8 22.25,25.88 v5(19.33,22.96)
  BOTTOM w0.254: C3503.1 106.93,126.19 v1(107.2,126.19) U3500.24 ; v1(68.03,147.54) 68.83,146.74 69.63,146.74 70.66,147.76 R3016.1 ; v1(110.11,154.3) 109.84,154.3 109.55,154.02 108.69,154.02 108.3,154.41 105.74,154.41 105.71,154.38 103.22,154.38 v1(103.17,154.33) ; v1(106.2,119.1) 105.98,119.1 105.41,119.66 R3513.2 ; v1(107.75,131.63) R3515.2 R3516.1 ; R3511.2 105.08,128.96 v1(104.84,128.96) ; v1(113.38,118.41) 113.16,118.64 R7109.1 ; C3500.1 115.83,121.85 C3502.1 115.8,122.94 U3500.10 v1(113.3,122.94) ; 19.73,20.24 U900.4
  BOTTOM w0.356: 107.57,49.32 106.44,50.45 U4502.7 106.43,51.47 C4507.2
  BOTTOM w0.381: U3500.19 v1(107.2,122.94) 106.3,122.94 106.29,122.94 C3501.1 ; v1(116.07,105.99) 116.18,105.89 C7527.1 ; 16,51.09 C516.1 15.52,50.65 v1(15.29,50.42) ; v1(115.85,96.04) 111.07,96.04 109.24,94.21 109.24,85.11 114.25,80.11 114.25,61.38 115.02,60.6 115.02,57.19 111.47,53.64 111.47,52.82 110.14,51.49 110.14,51.04 109.24,50.14 107.99,50.14 ; v1(114.73,147.12) 114.73,145.67 116.96,143.43 v1(116.96,132.89) ; C3000.2 54.15,141.71 ; 107.99,50.14 107.99,49.34 R4562.2 107.57,49.32 ; 107.99,50.14 R4561.2 ; D901.1 19.22,23.06 v5(19.33,22.96) ; C4507.2 106.43,53.23 v1(106.35,53.31) ; v1(67.51,157.78) 66.43,156.71 66.43,153.78 v1(64.61,151.97) 64.85,151.73 R351.1 ; 23.82,129.84 22.15,129.84 21.17,128.87 Q3152.1 ; 23.82,129.84 25.27,128.4 R4643.2 ; 23.82,129.84 23.82,133.6 v1(23.31,134.11) ; C7526.1 57,144.17 v1(56.68,143.85) Q3000.3 ; R3007.1 R3006.1 59.78,128.2 v5(59.59,128.4) ; C903.1 18.34,23.47 ; v1(106.43,60.35) 107.11,61.03 Q281.3 ; 19.73,21.84 19.73,20.24 ; R3000.1 54.15,140.82 ; C7521.1 101.01,132.68 v1(100.89,132.56)
  vias: v2(70.18,125.86) v5(69.26,123.95) v5(69.87,123.27)
P3V3S_CAM: length 28.4
  TOP w0.381: FUSE3004.2 97.59,151.3 C3014.1 97.78,150.42 98.02,150.17 v1(98.02,150.01)
  BOTTOM w0.356: 78.03,153.5 CN3000.22
  BOTTOM w0.381: 78.03,153.5 78.85,154.32 81.76,154.32 83.13,152.95 83.13,151.82 84.48,150.47 v2(86.31,150.47) 86.76,150.47 87.48,151.19 89.21,151.19 90.64,149.76 90.86,149.76 91.37,149.25 92.69,149.25 93.19,149.75 96.91,149.75 97.19,149.47 97.64,149.47 98.02,149.85 v1(98.02,150.01)
P3V3S_CR: length 1.9
  BOTTOM w0.381: D902.1 23.16,21.51 ; C906.1 22.27,21.59 ; C902.1 21.38,21.44
  vias: v2(22.7,20.98) v5(21.49,20.47)
P3V3S_LVDS1: length 1.3
  BOTTOM w0.381: R3004.1 57.88,140.38 58.09,140.59 ; C3003.2 59.78,142.64
  vias: v2(59.18,140.79)
P3V3S_LVDS2: length 0.6
  BOTTOM w0.254: C3001.1 62,143.23
  vias: v2(62.48,141.83)
P5V0A: length 185.5
  TOP w0.254: v1(62.56,139.34) 62.56,138.85 61.31,137.6 61.31,132.93 62.98,131.26 65.92,131.26 67.1,130.08 67.1,129.11 66.52,128.52 66.24,128.52 65.38,127.66 v1(64.79,127.66)
  TOP w0.381: v1(92.2,52.45) 93.6,52.45 95.86,54.71 98.79,54.71 98.8,54.7 100.62,54.7 102,56.08 102,60.47 v1(102.33,60.79) ; v1(99.92,64.97) 97.92,66.97 93.11,66.97 92.11,67.97 92.11,74.46 92.73,75.08 v1(93.14,75.08)
  TOP w0.508: v5(101.72,144.5) 103.25,142.98 103.25,133.37 102.49,132.61 102.49,132.36 v1(102.46,132.33)
  TOP w1.524: 35.86,138.12 33.86,136.12 33.86,127.02 35.38,125.5 35.38,122.63
  L3 w1.524: 38.15,138.99 40.09,137.05 51.17,137.05 54.23,140.11 61.79,140.11 v1(62.56,139.34) 63.45,138.45 65.65,138.45 66.06,138.86 70.23,138.86
  L4 w0.381: v1(107.67,102.44) 107.67,100 106.78,99.11 106.78,98.64 106.78,97.11 105.25,95.57 105.25,81.72 106.73,80.24 106.73,68.27 106.06,67.6 106.06,65.83 102.96,62.73 102.96,61.42 v1(102.33,60.79)
  BOTTOM w0.254: U7100.4 91.91,126.47 91.99,126.55 92.39,126.55 92.96,125.98 v5(92.96,125.97) ; v1(64.79,127.66) 64.82,127.63 U7102.4 ; v5(94.79,125.97) 94.79,126.21 PAD6150.2
  BOTTOM w0.381: v1(93.14,75.08) 92.66,75.08 92,74.42 R6645.2 ; C7516.1 v1(92.78,123.39) ; R6665.2 99.94,64.99 v1(99.92,64.97) 101.32,64.97 102.79,63.5 102.79,61.25 v1(102.33,60.79) R6745.2 ; R6765.2 v1(92.2,52.45) ; C7123.1 91.53,124.75
  BOTTOM w0.508: v5(96.62,125.97) 96.83,125.97 99.08,128.22 100.71,128.22 102.49,130 102.49,132.31 v1(102.46,132.33)
  vias: v2(33.77,121.46) v5(32.41,119.3) v5(33.17,119.94) v5(36.73,138.99) v5(37.74,138.99) v5(84.83,120.65) v5(85.44,121.36) v5(92.96,125.06) v5(93.88,125.97) v5(93.88,125.06) v5(94.15,111.86) v5(94.15,110.95) v5(94.15,110.03) v5(94.79,125.06) v5(95.7,125.97) v5(95.7,125.06) v5(96.62,125.06) v5(105.61,107.71) v5(105.61,106.79)
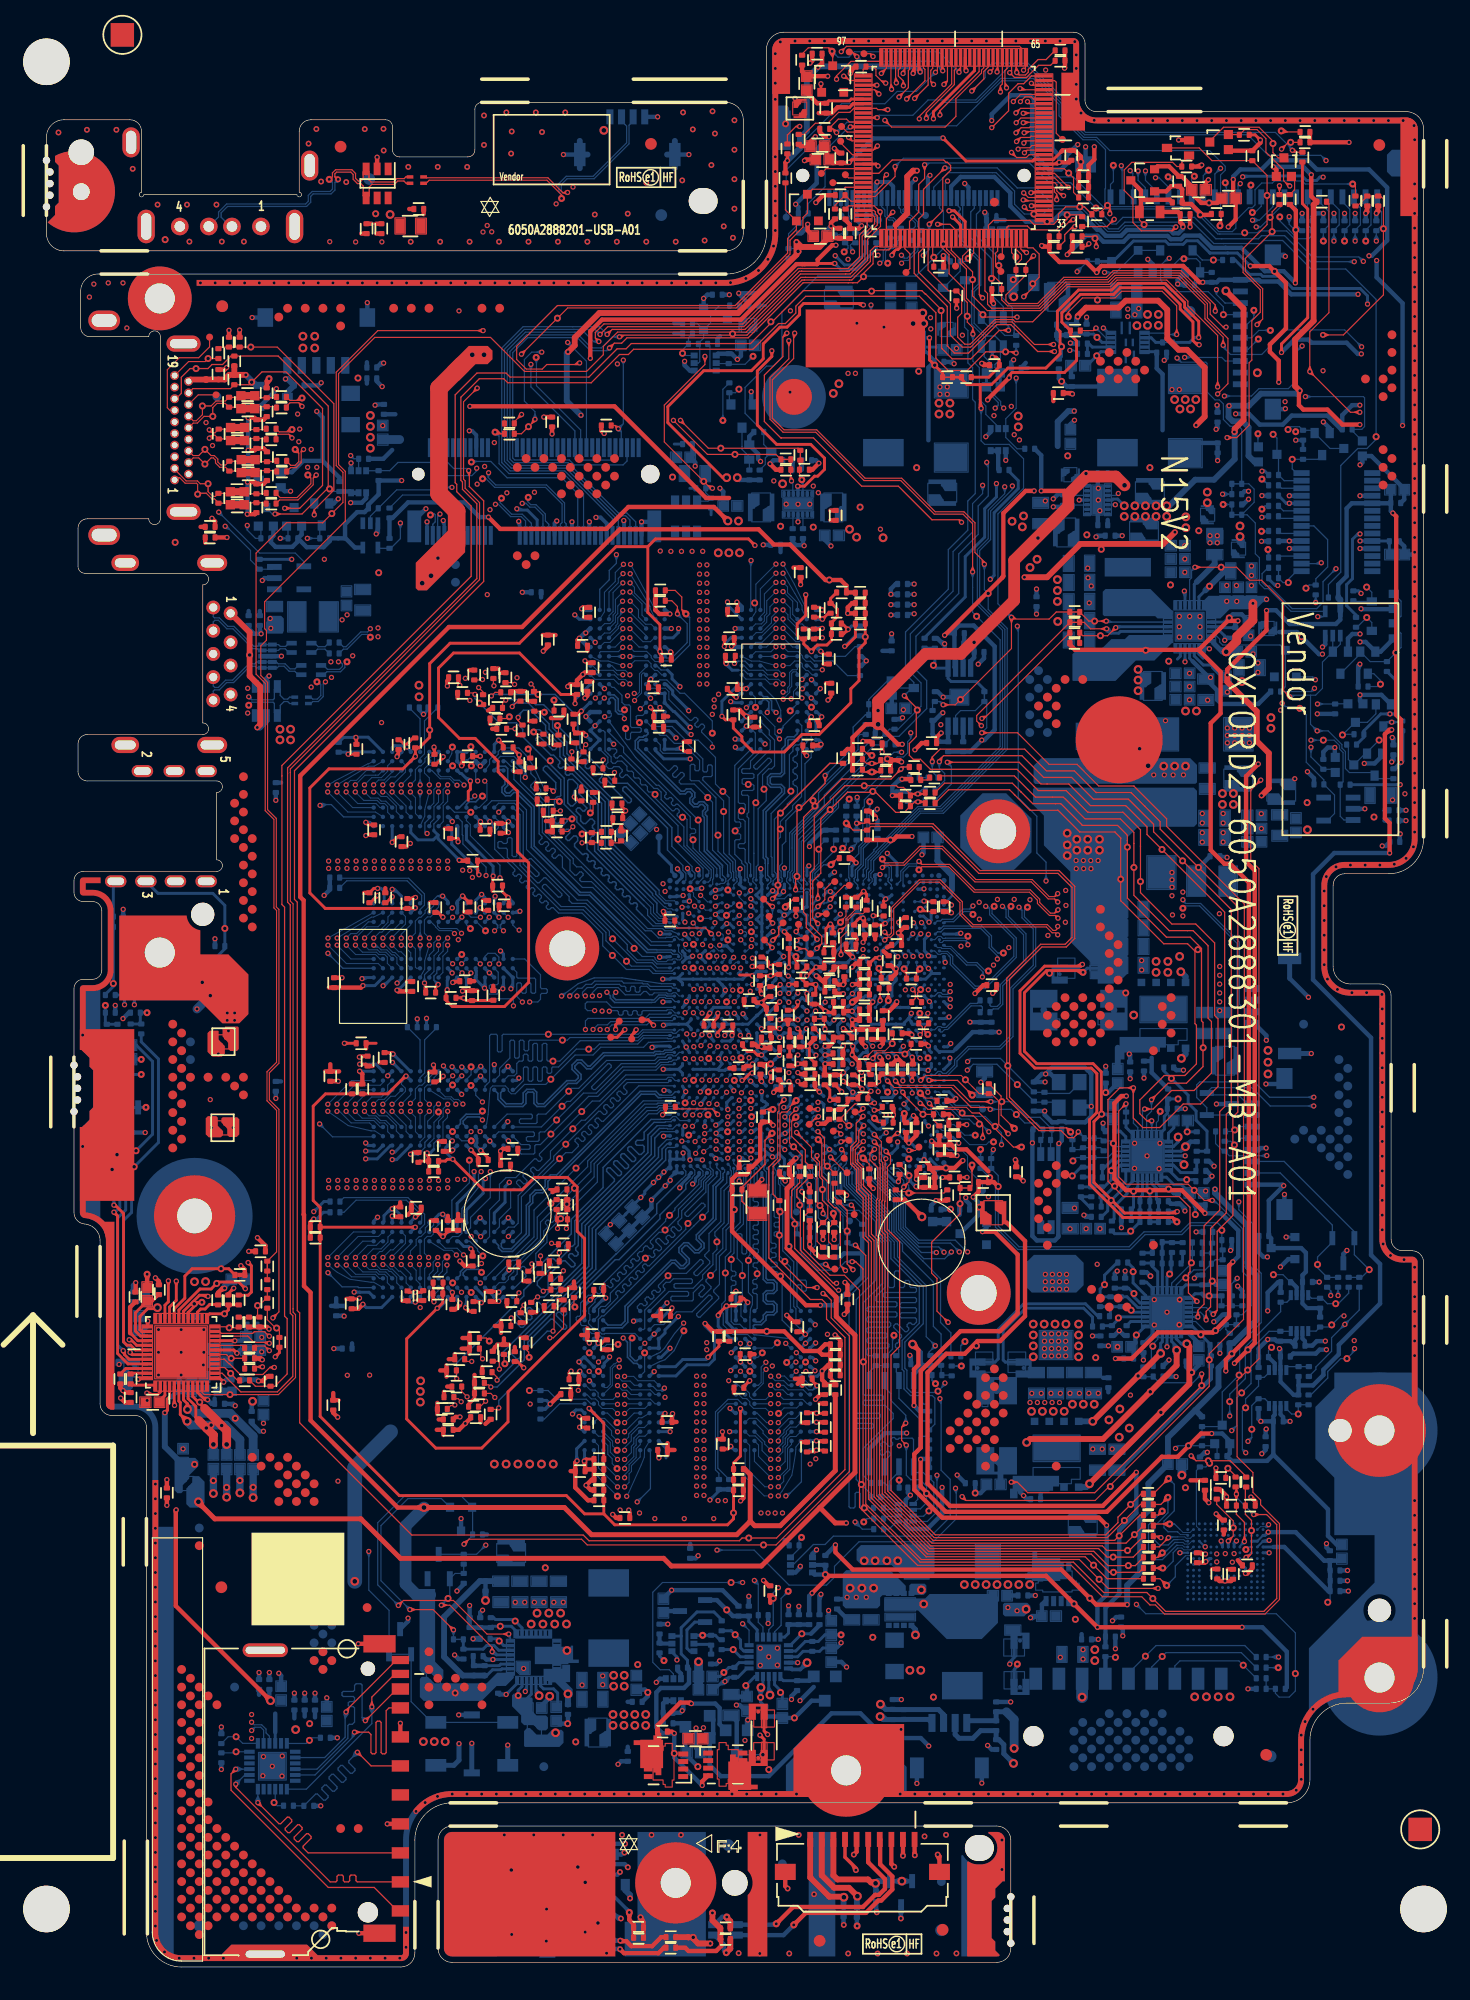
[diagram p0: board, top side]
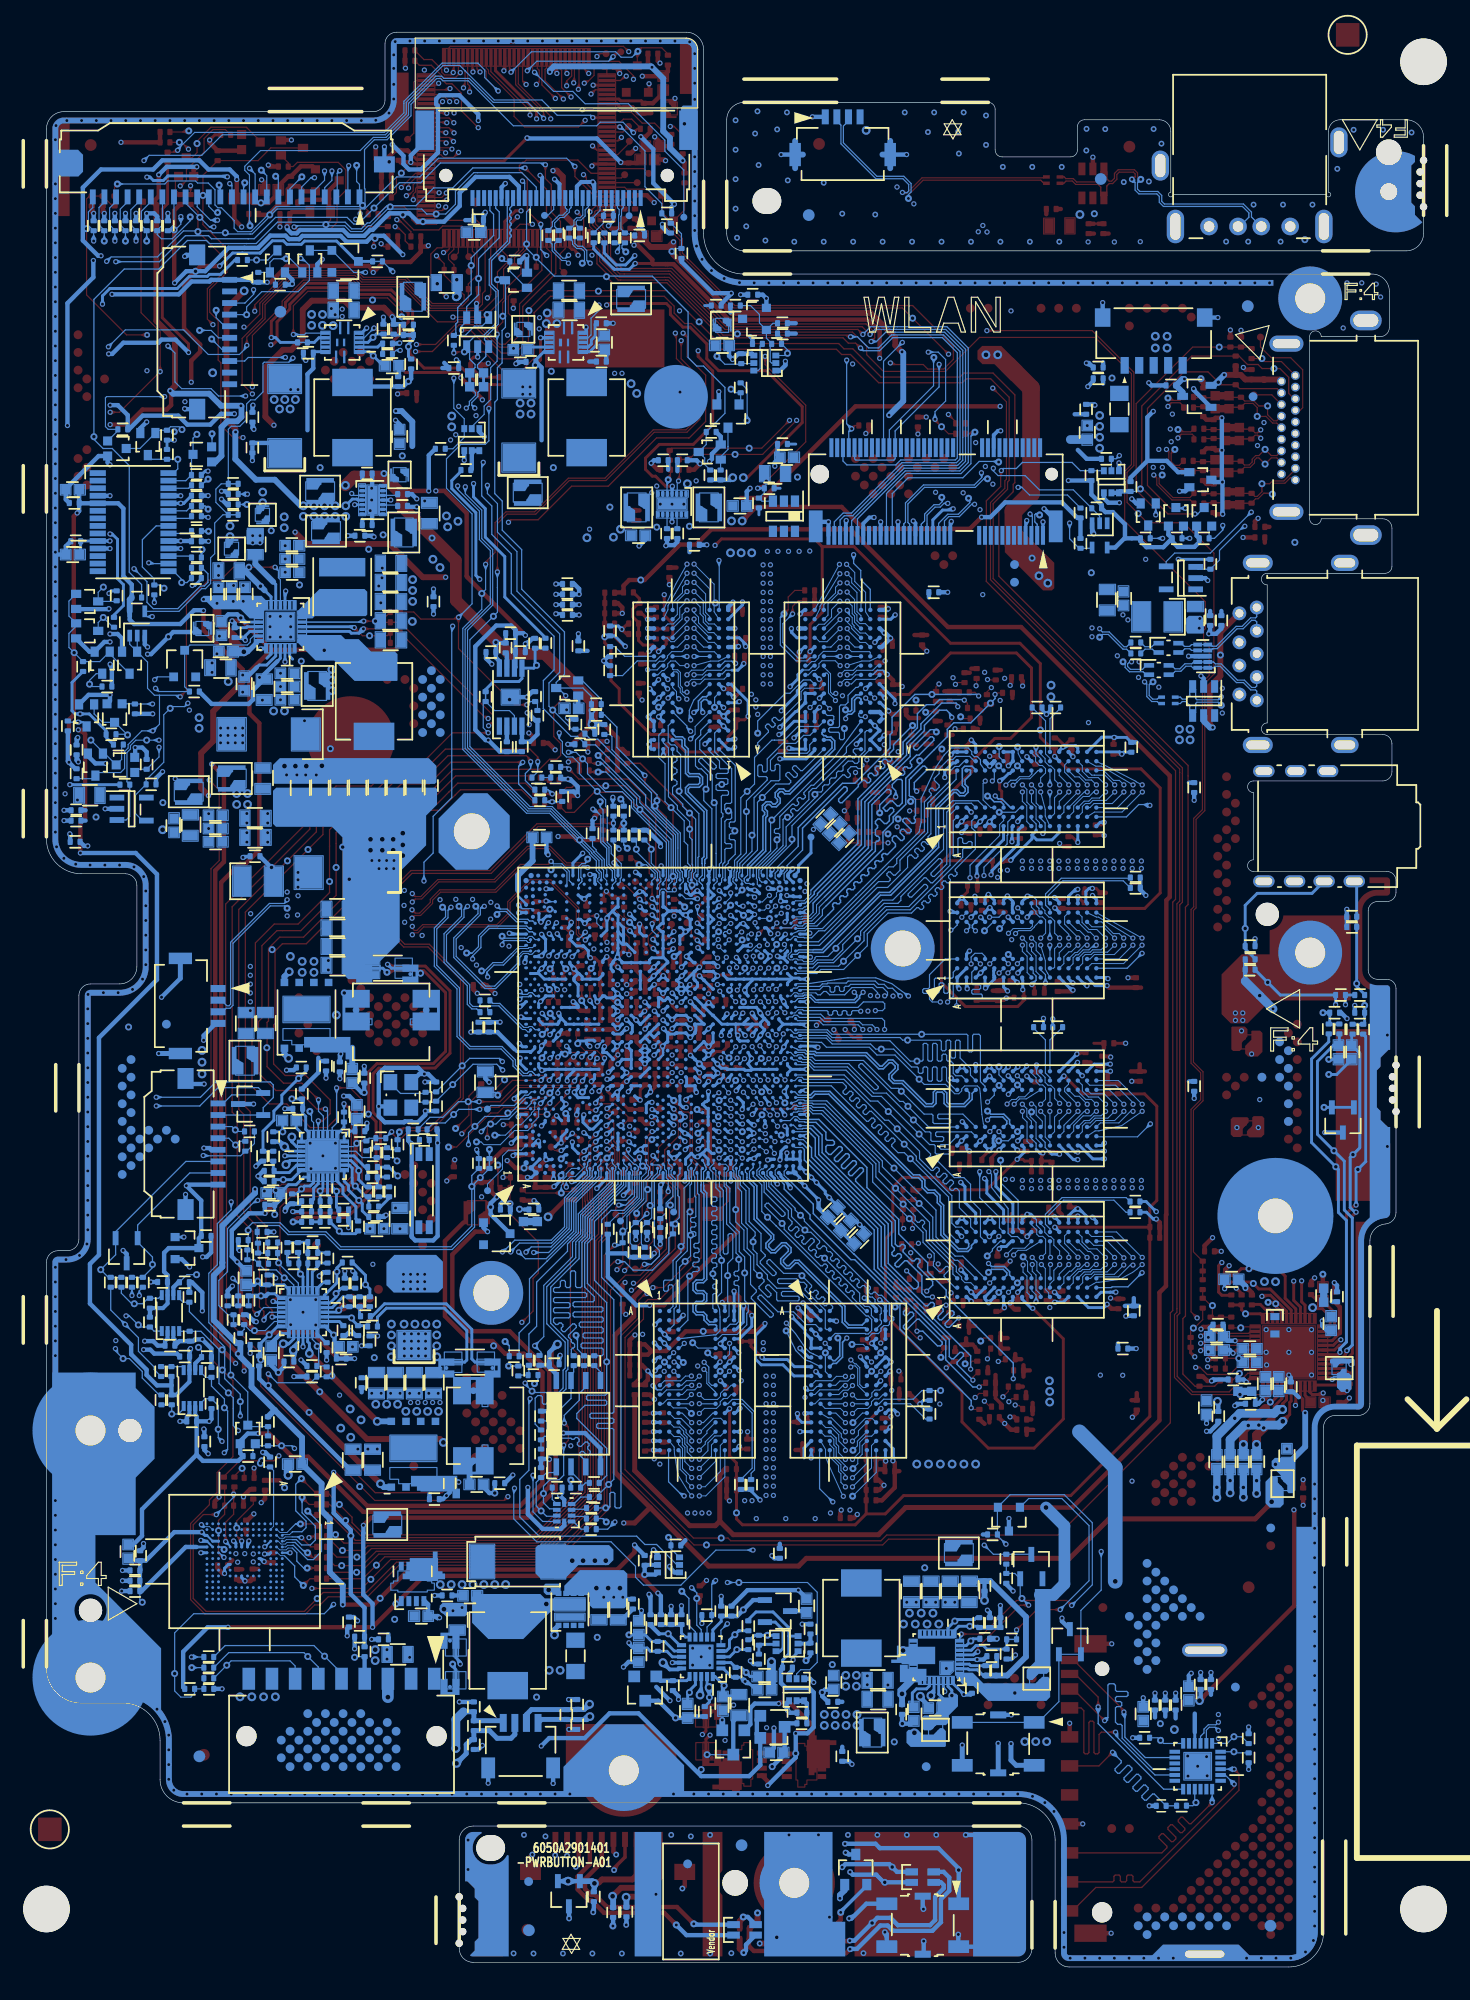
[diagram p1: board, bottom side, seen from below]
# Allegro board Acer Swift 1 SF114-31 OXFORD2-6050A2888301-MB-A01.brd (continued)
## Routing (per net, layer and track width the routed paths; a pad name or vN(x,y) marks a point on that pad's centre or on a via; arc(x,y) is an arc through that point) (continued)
P5V0A_PBN: length 26
  TOP w0.508: CN9100.2 66.87,7.9 67.94,6.83 69.22,6.83 v5(69.94,6.1) ; R9122.2 55.35,2.57 55.36,2.56 v2(55.79,2.56) 55.79,2.45 56.21,2.02 v4(57.25,2.02)
  L4 w0.508: v4(57.25,2.02) 64.96,2.02 67.65,4.71 69.36,4.71 69.94,5.29 v5(69.94,6.1)
  BOTTOM w0.508: v5(69.94,6.1) 69.9,6.06 C9101.1
P5V0A_USB1: length 13.3
  TOP w0.508: CN2401.1 17.52,115.06 v2(17.52,113.11) 17.52,111.3 18.44,110.39 18.44,107.11 v1(18.18,106.86)
  BOTTOM w0.381: C2432.1 18.4,116.9 ; C2427.1 17.44,116.9
  BOTTOM w0.508: D2409.5 18.92,107.85 18.92,107.37 18.41,106.86 v1(18.18,106.86)
P5V0A_USB2: length 0.8
  BOTTOM w0.381: 115.4,99.72 C2003.1 ; 115.4,98.83 R2000.1
  vias: v2(114.5,99.14)
P5V0A_USB2_DB: length 1.3
  TOP w0.381: C2460.1 28.06,150.29 ; 28.43,150.29 C2461.1 ; 31.29,151.56 C2462.1
  vias: v2(28.39,151.15) v5(29.64,151.08) v5(48.08,158.34)
P5V0A_USB_PW1:
  vias: v2(108.73,100.38)
P5V0S: length 184.7
  TOP w0.254: v1(67.99,146.86) 66.52,146.86
  TOP w0.381: v1(102.36,154.1) 102.36,152.68 R3069.1 102.57,150.64 v1(101.93,150.01) ; C7514.1 v1(43.61,132.16) ; v1(46.91,138.68) 46.91,141.01 47.92,142.02 59.9,142.02 64.69,146.8 65.19,146.8 65.39,146.8 66.46,146.8 66.52,146.86 66.52,147.19 67.77,148.44 v1(68.09,148.44)
  L3 w0.508: v1(20.62,136.91) 21.22,137.5 34.71,137.5 37.97,134.24 37.97,132.08 v1(38.63,131.42)
  L4 w0.254: v1(114.07,147.52) 114.07,146.76 111.92,144.61 111.92,144.34 111.72,144.15 111.72,137.17 112.42,136.47 112.42,134.22 113.08,133.55 113.38,133.55 113.78,133.15 113.78,126.64 112.92,125.78 112.92,123.92 v1(113.3,123.55)
  L4 w0.381: 44.52,131.55 44.52,134.26 46.91,136.65 v1(46.91,138.68) ; v1(68.09,148.44) 69.67,150.01 69.67,150.86 78.54,159.73 81.87,159.73 82.69,158.91 82.69,152.61 84.11,151.19 86.98,151.19 87.73,151.93 100.18,151.93 101.93,150.17 v1(101.93,150.01)
  L4 w0.635: 16.51,57.56 16.51,55.37 17.6,54.28 17.6,48.95 v5(17.78,48.77)
  BOTTOM w0.254: v1(113.3,123.55) 113.11,123.55 112.65,123.08 112.65,119.69 112.14,119.18 112.14,117.36 112.95,116.55 R29.1 ; R3060.2 71.57,148.12 69.91,146.46 69.89,146.46 69.79,146.35 68.5,146.35 v1(67.99,146.86)
  BOTTOM w0.381: v1(102.36,154.1) 102.36,154.36 102.97,154.96 104.8,154.96 105.58,155.75 108.79,155.75 109.57,154.96 114.07,154.96 115.64,153.4 115.64,148.84 114.31,147.52 v1(114.07,147.52) ; C519.1 17.7,48.69 v5(17.78,48.77)
  BOTTOM w0.508: U3151.3 20.78,135.76 C3150.1 20.8,136.91 v1(20.62,136.91)
  vias: v2(85.52,123.19) v5(12.77,59.08) v5(13.72,59.09) v5(83.28,124.64) v5(84.17,124.15) v5(84.27,125.09)
P5V0S_AUDIO_AVDD: length 4.1
  TOP w0.254: v5(9.57,56.84) 9.48,56.75 8.73,56.75 8.06,56.08 8.06,54.95 8.21,54.79 U500.26
  BOTTOM w0.381: C505.1 7.91,57.36
  vias: v2(12.75,57.17)
P5V0S_HDMI_CRT: length 7.4
  TOP w0.508: CN3150.18 12.41,136.85 TP3150.1 13.77,136.86 D7152.2 15.37,136.86 15.77,137.26 R3153.1 ; v1(17.19,137.26) R3153.1 ; R3153.1 R3152.1
  BOTTOM w0.508: v1(17.19,137.26) 18.09,136.36 U3151.2
P5V0S_PVDD: length 5.9
  TOP w0.254: U500.46 13.02,49.55 13.66,48.9 v1(13.89,48.9) ; v1(11.05,48.41) 11.02,48.44 U500.41
  BOTTOM w0.381: v1(13.89,48.9) 14.24,48.56 C514.1 14.5,49 ; 10.77,49.12 11.23,49.59 C520.1 11.9,49.59
  vias: v2(13.22,48.7)
P5VAUXON: length 97.6
  TOP w0.381: v1(106.29,136.63) 106.29,138.48 105.52,139.24 105.52,139.88 106.91,141.26 106.91,145.2 v2(105.92,146.18) 105.47,146.64 v1(103.84,146.64)
  L3 w0.381: v1(106.45,108.36) 106.46,108.37 106.97,108.37 108.1,109.5 108.1,120.51 108.9,121.31 108.9,122.37 108.9,129.38 106.97,131.31 106.97,133.41 106.29,134.1 v1(106.29,136.63)
  L4 w0.381: v1(77.31,108.13) 77.39,108.2 79.71,108.2 79.98,108.47 81.4,108.47 84.91,104.96 105.22,104.96 106.45,106.2 v1(106.45,108.36)
  BOTTOM w0.254: v1(103.84,146.64) 102.72,147.76 101.88,147.76 100.34,147.76 99.29,148.82 98.34,148.82 98.04,148.51 96.79,148.51 96.51,148.79 93.75,148.79 92,147.04 D7000.3 R7003.1
  BOTTOM w0.381: U4441.4 77.76,105.64 R4445.2 77.07,105.63 76.43,106.27 R7256.1 76.61,107.47 77.26,108.13 v1(77.31,108.13)
PVBAT: length 23.2
  TOP w0.381: C7511.1 86.84,135 ; C7546.1 62.43,31.39
  BOTTOM w0.254: v1(81.94,127.89) 81.94,126.74 80.92,125.72 80.92,123.27 79.24,121.59 79.24,118.11 75.74,114.6 R4449.1
  BOTTOM w0.381: v1(92.83,28.55) 92.83,29.16 C7541.1 ; v1(115.21,96.65) 115.52,96.65 C7512.1 ; 84.46,138.29 C7510.1 84.63,137.85 ; C7577.1 50.14,18.98 ; 82.65,150.6 C3020.1 81.93,151.04 ; C7513.1 105.15,46.33 v1(105.2,46.38)
  BOTTOM w0.508: v1(60.49,21.29) D6000.2
  vias: v1(69.14,137.39) v1(69.77,137.39) v1(83.47,132.1) v1(83.92,131.65) v2(111.69,81.04) v5(48.87,21.77) v5(48.87,20.83) v5(49.81,21.77) v5(49.81,20.83) v5(50.75,21.77) v5(50.75,20.83) v5(51.69,21.77) v5(51.69,20.83) v5(67.87,135.66) v5(68.35,136.5) v5(74.47,25.58) v5(75.41,25.58) v5(79.17,32.97) v5(80.11,32.97) v5(81.05,32.97) v5(81.99,32.97) v5(82.93,32.97) v5(83.82,133.71) v5(83.82,132.78) v5(83.87,32.97) v5(84.81,32.97) v5(105.36,79.02) v5(105.36,78) v5(105.36,76.99)
PVBAT_CPU: length 3.7
  BOTTOM w0.381: R6660.1 95.32,77.11 95.32,78.38 ; C6612.1 95.11,78.1
  vias: v2(99.77,79.25)
PVBAT_VGG: length 12.9
  BOTTOM w0.381: C6712.1 85.74,40.78 ; R6760.1 100.43,50.72 92.54,42.84 C6710.1
  vias: v2(91.76,41.42)
VCC0_SENSEN_R: length 22.9
  L3 w0.135: v1(64.03,83.16) 64.42,82.78 64.97,82.78 65.3,83.11 65.85,83.11 67.17,84.44 67.17,84.46 67.17,84.53 67.17,84.53 67.17,97.71 69.92,100.46 v1(69.92,100.84)
  BOTTOM w0.109: v1(69.92,100.84) 69.92,100.12 R4618.1 ; U4500.AJ32 64.02,83.16 v1(64.03,83.16)
VCC0_SENSEP_R: length 21.5
  L3 w0.135: v1(64.81,83.97) 64.81,83.78 65.25,83.34 65.76,83.34 66.95,84.53 66.95,96.14 66.95,96.14 66.95,97.85 69.29,100.19 69.29,100.63 v3(69.24,100.69)
  BOTTOM w0.109: v3(69.24,100.69) 68.98,100.43 R4617.1 ; v1(64.81,83.97) 64.41,83.57 U4500.AG32
VCC1_SENSEN_R: length 18.2
  L3 w0.135: v1(69.39,96.37) 69.12,96.09 69.12,89.09 67.71,87.68 67.71,84.34 66.75,83.38 66.75,82.25 66.51,82.01 65.97,82.01 v1(65.6,81.64)
  BOTTOM w0.109: v1(65.6,81.64) 65.24,81.28 U4500.AF27 ; v1(69.39,96.37) 69.87,96.85 R4620.1
VCC1_SENSEP_R: length 16.5
  L3 w0.135: v1(66.34,82.42) 66.34,83.29 67.4,84.34 67.4,84.34 67.48,84.43 67.48,87.78 68.89,89.19 68.89,96.23 v3(68.68,96.44)
  BOTTOM w0.109: v1(66.34,82.42) 65.98,82.06 U4500.AD29 ; R4619.1 68.98,96.75 v3(68.68,96.44)
VCC_POR#: length 37.8
  TOP w0.102: U301.85 76.44,163.68 76.27,163.52 76.27,162.53 v1(76.51,162.29) ; v3(106.5,158.29) 106.59,158.2 R320.2
  L3 w0.102: v3(106.5,158.29) 106.5,158.32 106.4,158.42 89.72,158.42 87.07,161.06 87.07,162.65 v1(86.18,163.54)
  L4 w0.102: v1(76.51,162.29) 77.13,162.91 85.55,162.91 v1(86.18,163.54)
VCC_SENSEN: length 51.5
  TOP w0.109: v1(69.87,98.6) 70.58,98.6 R4700.2 71.04,98.56 76.47,98.56 80.51,94.52 87.34,94.52 88.69,93.17 88.69,88.67 87.96,87.93 85.85,87.93 83.06,85.14 83.06,74.98 85.7,72.34 87.98,72.34 v3(88.34,71.98)
  BOTTOM w0.109: R4620.2 v1(69.87,98.6) R4618.2 ; v3(88.34,71.98) 88.49,71.83 R6663.1
VCC_SENSEP: length 53.6
  TOP w0.109: v3(68.98,98.6) 69.58,98.01 R4698.2 71.1,98.32 76.37,98.32 80.41,94.28 87.24,94.28 88.45,93.07 88.45,88.76 87.86,88.17 85.75,88.17 82.83,85.24 82.83,85.05 82.83,74.88 85.6,72.1 87.51,72.1 88.11,71.5 88.13,71.5 88.14,71.5 88.54,71.5 88.54,71.5 88.59,71.5 89,71.91 v1(89,72.01)
  BOTTOM w0.109: R4617.2 v3(68.98,98.6) R4619.2 ; R6666.1 89.51,71.5 v1(89,72.01)
VDDQ_PG: length 115.2
  TOP w0.102: v1(39.87,28.7) 38,28.7 35.1,31.6 30.78,31.6 v1(30.35,31.17) ; v1(66.98,58.06) 67.1,58.06 67.69,57.48 67.69,55.96 69.26,54.38 69.26,42.72 62.93,36.38 v2(61.85,36.38) 46.65,36.38 46.15,36.88 36.45,36.88 v1(36.01,36.45)
  L4 w0.089: 63.07,66.97 63.07,67.06 63.01,67.11 63.01,68.37 62.14,69.24 62.14,76.15 62.06,76.22 62.06,79.49 60.58,80.98 60.58,82.23 60.1,82.7 59.17,82.7 v1(58.71,82.24)
  L4 w0.102: 63.07,66.97 63.07,61.72 66.06,58.72 66.06,58.29 66.29,58.06 v1(66.98,58.06)
  BOTTOM w0.089: U4500.AV28 58.97,81.97 v1(58.71,82.24)
  BOTTOM w0.102: U60300.8 40.02,28.56 v1(39.87,28.7) ; v1(36.01,36.45) 36.76,37.19 R7229.1 36.76,39.59 Q7202.3 36.71,39.66 35.66,40.72 30.98,40.72 28.57,38.3 28.57,32.94 v1(30.35,31.17)
ACPRES: length 224.8
  TOP w0.102: v1(79.81,161.73) 80.85,162.77 80.85,163.42 81.24,163.81 U301.73 ; v1(107.46,156.62) 107.62,156.46 R323.2
  L3 w0.102: v1(60.04,29.59) 60.04,29.59 v1(60.04,33.15)
  L4 w0.102: v1(60.04,33.15) 60.43,32.77 62.12,32.77 64.43,35.08 67.9,35.08 69.74,36.92 91.14,36.92 94.76,40.54 94.76,41.22 97.99,44.45 97.99,45.21 104.26,51.49 104.26,61.83 108.59,66.15 108.59,80.48 108.59,80.95 108.54,80.99 107.07,82.47 107.07,94.6 111.81,99.34 111.81,116.72 111.3,117.23 111.3,118.37 111.3,118.54 109.15,120.68 109.15,121.43 109.7,121.98 109.7,122.45 109.7,135.94 108.35,137.29 108.35,138.39 108.91,138.94 108.91,153.3 108.23,153.98 108.23,154.84 107.52,155.56 107.52,156.57 v1(107.46,156.62)
  BOTTOM w0.102: v1(60.04,29.59) 60.6,29.03 U6000.5 ; Q60002.2 54.07,25.27 53.72,25.63 52.93,25.63 52.3,26.26 52.3,32.31 53.13,33.15 v2(59.05,33.15) v1(60.04,33.15) ; v1(79.81,161.73) 80.97,162.89 80.97,163.54 81.57,164.13 84.65,164.13 87.94,160.84 87.94,160.67 87.94,159.84 89.62,158.16 105.99,158.16 107.46,156.69 v1(107.46,156.62)
ACPRESENT: length 18.4
  TOP w0.102: v1(79.91,140.77) 79.91,141.33 79.42,141.81 v2(79.42,142.32) 79.42,143.5 79.14,143.78 79.14,144.68 77.85,145.97 77.85,147.61 77.24,148.22 U301.14
  BOTTOM w0.102: v1(79.91,140.77) 79.91,138.44 80.46,137.88 80.46,135.13 81.02,134.57 81.02,133.85 82.09,132.78 Q4506.2
AOAC_ON#: length 59.1
  TOP w0.102: v1(57.44,127.48) 57.28,127.48 v2(56.69,128.08) 53.29,131.48 53.29,134.64 56.79,138.15 v1(56.79,138.85) ; R334.2 65.35,157.99 66.32,158.95 67.38,158.95 68.32,159.89 69.29,159.89 69.63,160.23 U301.104 71.6,160.23 71.71,160.12 v1(72.56,160.12)
  L4 w0.102: v1(56.79,138.85) 57.68,139.74 62.73,139.74 63.26,139.21 64.87,139.21 65.6,139.94 65.6,145.43 67.37,147.2 67.37,147.22 67.37,148.58 68.58,149.79 68.58,153.03 72.72,157.18 72.72,159.97 v1(72.56,160.12)
  BOTTOM w0.102: Q1300.3 57.06,126.37 C1307.2 56.86,127.1 C1306.2 v1(57.44,127.48)
BAT_OLED#: length 43
  TOP w0.102: U301.62 85.11,162.23 v1(84.95,162.4)
  L4 w0.102: v3(105.57,141.09) 104.6,141.09 104.48,140.97 103.26,140.97 100.28,143.95 100.28,145.49 102.75,147.96 102.75,150.67 99.9,153.52 99.11,153.52 98.94,153.52 96.65,155.81 94.88,155.81 94.35,156.34 91.6,156.34 91.07,155.81 88.82,155.81 86.69,157.94 86.69,160.66 v1(84.95,162.4)
  BOTTOM w0.102: CN245.6 103.93,140.45 104.57,141.09 v3(105.57,141.09)
BAT_OLED#_PB: length 18.9
  TOP w0.381: CN9100.6 70.88,9.03 72.32,7.58 72.32,6.73 71.8,6.21 71.46,6.21 70.42,5.17 64.4,5.17 v3(62.94,3.72)
  BOTTOM w0.381: v3(62.94,3.72) 62.87,3.65 D9129.4
BAT_WLED#: length 49.1
  TOP w0.102: U301.81 78.08,164.6 78.08,162.34 75.28,159.54 v1(75.28,159.33)
  L3 w0.102: v1(75.28,159.33) 76.7,157.91 76.7,152.41 77.44,151.68 77.44,151.02 83.23,145.22 87.52,145.22 88.42,144.32 96.31,144.32 97,143.63 98.36,143.63 100.16,141.83 100.33,141.83 102.32,141.83 103.36,140.8 104.07,140.8 v3(104.53,140.34)
  BOTTOM w0.102: CN245.7 102.98,139.45 103.63,139.45 v3(104.53,140.34)
BAT_WLED#_PB: length 19.8
  TOP w0.381: v3(64.45,3.63) 65.5,4.67 70.69,4.67 71.75,5.73 72,5.73 72.96,6.69 72.96,7.81 71.91,8.85 71.91,10.96 CN9100.7
  BOTTOM w0.381: D9129.3 63.57,2.75 v3(64.45,3.63)
BATT_IN: length 211
  TOP w0.102: v1(71.62,162.23) U301.99
  L4 w0.102: v1(94.01,31.26) 92.61,32.66 92.61,37.32 94.97,39.68 94.97,41.14 99.26,45.43 99.26,46.19 104.47,51.4 104.47,61.74 109.99,67.26 109.99,75.73 109.97,79.85 108.75,81.08 107.27,82.56 107.27,94.52 112.01,99.26 112.01,116.8 111.5,117.31 111.5,118.28 111.5,118.62 109.35,120.77 109.35,121.34 109.9,121.89 109.9,122.53 109.9,131.19 110.54,131.82 110.54,135.39 108.56,137.37 108.56,138.3 109.12,138.86 109.12,153.38 108.43,154.07 108.43,156.3 107.39,157.34 106.03,157.34 105.45,156.76 103.65,156.76 102.27,155.37 101.83,155.37 99.09,158.11 92.3,158.11 90.7,156.51 88.98,156.51 87.3,158.19 87.3,163.57 86.52,164.35 73.74,164.35 v1(71.62,162.23)
  BOTTOM w0.102: v1(94.01,31.26) 94.82,30.45 106.07,30.45 107.72,28.8 v2(107.72,25.3) 107.72,23.8 107.18,23.27 106.32,23.27 106,23.59 R6053.1 R6054.2 105.2,23.98 R6051.1
BBS: length 16.5
  BOTTOM w0.102: U4500.AH51 64.13,93.28 63.84,93.57 63.84,93.84 63.93,93.93 63.93,94.4 63.94,94.41 64.1,94.57 64.1,97.76 66.12,99.77 v2(66.12,100.55) 66.12,101.06 70,104.95 70,106.08 70.17,106.26 R4549.2
BEEP: length 165.5
  TOP w0.102: v1(37.67,141.07) 28.58,141.07 24.99,137.48 24.99,129.44 25.57,128.85 25.57,126.26 v2(24.61,125.3) 23.82,124.51 20.7,124.51 18.08,121.89 18.08,111.45 18.87,110.67 18.87,99.69 19.62,98.94 19.62,91.31 19.85,91.08 19.85,78 19.02,77.17 19.02,74.68 19.85,73.85 19.85,61.65 R520.2 ; U301.66 84.04,165.48 83.94,165.58 69.01,165.58 v1(68.55,165.12)
  L4 w0.102: v1(37.67,141.07) 42.98,141.07 45.59,143.68 50.47,143.68 51.35,142.8 59.71,142.8 64.28,147.37 64.28,149.85 64.91,150.48 64.91,150.91 64.91,151.08 65.5,151.67 65.5,152.41 66.29,153.2 66.29,156.08 64.26,158.11 64.26,159.05 66.06,160.86 66.06,162.48 66.06,162.49 66.06,162.63 v1(68.55,165.12)
BTIFON: length 57
  TOP w0.102: U301.113 71.31,156.63 v1(71.68,157)
  L4 w0.102: v3(42.24,138.76) 42.24,139.31 46,143.07 48.44,143.07 49.82,143.07 49.82,143.07 50.5,143.07 51.74,141.83 61.14,141.83 61.31,141.83 63.5,139.65 64.73,139.65 65.19,140.11 65.19,145.62 66.96,147.39 66.96,148.36 66.96,148.36 66.96,148.75 68.17,149.96 68.17,153.49 v1(71.68,157)
  BOTTOM w0.102: v3(42.24,138.76) 42.26,138.73 42.26,136.32 46.08,132.51 CN1300.54
CAM_PWR#: length 43.8
  TOP w0.102: R3030.1 101.32,150.22 v3(101.22,150.11) ; U301.80 78.44,163.66 78.31,163.52 78.31,162.28 75.89,159.87 v1(75.89,159.37)
  BOTTOM w0.102: v1(75.89,159.37) 75.89,159.39 77.25,160.75 80.24,160.75 82.3,162.81 84.5,162.81 84.7,163.01 85.2,163.01 87.54,160.67 87.54,159.68 89.48,157.73 90.58,157.73 91.71,156.6 100.31,156.6 101.67,155.23 101.67,154.9 101.27,154.49 101.27,150.16 v3(101.22,150.11)
CARD_REF: length 3.6
  BOTTOM w0.102: U900.1 16.92,19.28 v2(16.35,19.85) 15.67,19.85 R900.2
CLK_KBPCI: length 168.4
  TOP w0.109: U301.2 72.44,150.73 v1(73,151.29)
  L3 w0.135: v3(79.22,53.92) 81.68,53.92 84.28,51.32 94.02,51.32 94.86,50.48 97.61,50.48 102.16,55.03 102.16,56.88 103.99,58.71 103.99,62.09 104.57,62.67 104.57,67.63 103.75,68.45 103.75,80.37 102.36,81.76 102.36,98.46 103.55,99.65 103.55,103.49 104.82,104.76 104.82,105.13 104.82,105.13 104.82,107.87 106.71,109.76 107.08,110.13 107.46,110.51 107.46,120.78 108.26,121.58 108.26,122.11 108.26,127.54 103.99,131.81 103.99,135.14 103.74,135.39 103.74,135.42 101.87,137.29 101.31,137.29 101.31,137.29 100.38,137.29 99.81,136.71 99.81,132.91 96.39,129.49 88.64,129.49 88.03,130.1 88.03,136.67 86.23,138.47 85.35,139.35 85.35,141.6 84.04,142.91 82.78,142.91 81.98,143.71 81.98,144.17 78.85,147.31 78.85,147.55 77.32,149.07 75.21,149.07 v1(73,151.29)
  BOTTOM w0.109: R4571.1 78.86,53.56 v3(79.22,53.92)
CLK_KBPCI_R: length 19.1
  BOTTOM w0.109: U4500.P2 70.94,68.07 73.1,65.91 73.1,63.35 73.61,62.84 75.58,60.86 77.11,59.33 77.11,55.56 78.01,54.67 R4571.2
CLK_PCI_DEBUG: length 205.3
  TOP w0.109: v1(49.32,132.61) 49.04,132.89 C1305.1
  L3 w0.135: v3(76.68,50.29) 76.68,50.44 78.44,52.2 78.44,54.05 78.95,54.57 82.03,54.57 84.63,51.97 94.28,51.97 94.35,51.9 97.56,51.9 101.52,55.87 101.52,59.26 103.35,61.09 103.35,62.36 103.93,62.94 103.93,67.36 103.11,68.18 103.11,80.1 101.7,81.51 101.7,95.13 100.73,96.11 100.73,101.57 104.18,105.03 104.18,108.14 106.44,110.4 106.82,110.78 106.82,121.04 107.62,121.84 107.62,127.28 103.35,131.55 103.35,134.87 101.58,136.64 100.65,136.64 100.45,136.45 100.45,132.56 96.73,128.84 88.35,128.84 87.35,129.84 87.35,136.44 84.35,139.44 84.35,140.61 83.15,141.82 82.63,141.82 81.18,143.26 81.18,144.06 78.2,147.04 78.2,147.28 77.05,148.43 74.95,148.43 73.88,149.5 67.87,149.5 66.86,148.49 66.86,146.5 61.83,141.46 61.12,141.46 53.69,141.46 50.63,138.4 49.88,138.4 v1(49.76,138.53)
  BOTTOM w0.109: v1(49.76,138.53) 49.76,133.04 v1(49.32,132.61) 49.58,132.36 CN1300.68 ; R4572.1 76.38,50.59 v3(76.68,50.29)
CLK_PCIE_WLAN_DN: length 115.4
  L3 w0.109: v1(38.13,128.82) 38.13,128.45 38.24,128.34 38.52,128.34 43.08,132.9 46.49,132.9 48.25,134.66 65.23,134.66 66.08,133.81 68.47,133.81 76.76,125.53 76.76,124.87 80.13,121.49 80.13,121.07 80.61,120.6 80.61,116.6 83.44,113.76 83.44,102.23 85.8,99.87 85.8,95.21 84.28,93.69 84.28,91.6 84.52,91.36 v3(84.61,91.36)
  BOTTOM w0.107: U4500.B18 77.08,76.9 77.15,76.83 77.69,76.83 78.53,77.67 78.53,78.11 79.56,79.15 82.29,79.15 83.36,80.22 83.36,84.32 85.32,86.28 85.32,89.57 84.35,90.54 84.35,91.1 v3(84.61,91.36) ; CN1300.49 44.83,124.41 44.68,124.55 44.68,126.21 43.13,127.77 38.75,127.77 38.11,128.41 38.11,128.8 v1(38.13,128.82)
CLK_PCIE_WLAN_DP: length 115.4
  L3 w0.109: v1(83.88,91.36) 84.07,91.55 84.07,93.77 85.59,95.29 85.59,99.78 83.23,102.14 83.23,113.67 80.4,116.51 80.4,120.51 79.92,120.98 79.92,121.4 76.54,124.78 76.54,125.44 68.39,133.6 65.99,133.6 65.14,134.45 48.34,134.45 46.58,132.69 43.17,132.69 38.61,128.13 38.16,128.13 37.98,128.3 v3(37.61,128.3)
  BOTTOM w0.107: CN1300.47 44.33,124.38 44.48,124.53 44.48,126.13 43.04,127.56 38.66,127.56 37.92,128.3 v3(37.61,128.3) ; v1(83.88,91.36) 84.14,91.1 84.14,90.45 85.11,89.48 85.11,86.36 83.16,84.41 83.16,80.3 82.21,79.35 79.48,79.35 78.33,78.2 78.33,77.76 77.6,77.04 77.3,77.04 77.13,77.21 76.9,77.21 76.6,76.9 U4500.C18
CLK_TPM: length 96.3
  L3 w0.135: v3(78.91,51.81) 82.89,51.81 84.02,50.68 93.75,50.68 94.6,49.84 98.95,49.84 102.84,53.73 102.84,56.64 104.63,58.43 104.63,61.82 105.22,62.4 105.22,67.89 104.39,68.72 104.39,80.63 103,82.02 103,96.65 103.65,97.3 103.65,98.84 104.2,99.39 104.2,99.92 104.2,102.67 107.46,105.93 107.46,107.71 108.95,109.2 108.95,117.1 v1(109.47,117.63)
  BOTTOM w0.109: R3509.1 v1(109.47,117.63) ; R4573.1 v3(78.91,51.81)
CLKREQ_WLAN1V8#: length 189.1
  TOP w0.089: 62.8,69.47 63.07,69.73 63.07,73.68 63.18,73.79 63.18,74.32 v1(63.63,74.77)
  TOP w0.109: 62.8,69.47 62.31,68.97 62.31,61.13 65.89,57.55 66.88,57.55 67.28,57.15 67.28,55.86 68.87,54.27 68.87,42.88 62.97,36.98 v2(60.58,36.98) 59.99,36.98 59.76,36.74 46.8,36.74 46.3,37.24 31.51,37.24 21.84,46.91 21.84,56.39 21.63,56.6 21.63,91.8 21.39,92.04 21.39,103.13 37.71,119.45 37.71,126.39 36.47,127.63 36.47,128.96 v1(36.42,129.01)
  BOTTOM w0.089: v1(63.63,74.77) 63.31,75.08 U4500.AK14
  BOTTOM w0.109: Q1302.6 28.64,128.99 R4640.1 29.61,129 30.31,129.71 34.6,129.71 35.13,129.18 36.24,129.18 v1(36.42,129.01)
CLKREQ_WLAN#: length 26.4
  L3 w0.135: v1(26.24,130.3) 26.51,130.02 35.07,130.02 35.35,129.74 v3(36.65,129.74)
  BOTTOM w0.109: Q1302.5 26.92,130.01 R1307.2 26.51,130.02 v1(26.24,130.3) ; v3(36.65,129.74) 36.7,129.79 38.33,129.79 39.73,128.39 44.45,128.39 45.82,127.02 CN1300.53
COREPWROK: length 59
  TOP w0.109: v1(79.4,68.07) R4843.2 78.75,67.2 R7243.2 v2(78.8,65.8) 78.8,64.93 76.35,62.48 76.35,59.82 76.81,59.36 76.81,56.54 v1(77.77,55.57)
  L3 w0.135: v1(74.67,75.34) 74.67,74.57 75.4,73.84 75.62,73.84 77.26,72.2 77.26,69.6 78.79,68.07 v1(79.4,68.07) ; v1(77.06,49) 76.04,50.02 76.04,50.7 77.8,52.46 77.8,54.96 77.77,54.99 v1(77.77,55.57)
  BOTTOM w0.109: v1(74.67,75.34) 74.67,75.61 U4500.G16 ; v1(77.06,49) 77.16,48.89 77.16,42.82 77.95,42.04 77.95,38.81 76.28,37.14 67.87,37.14 67.15,36.42 66.15,36.42 64.39,34.66 Q7214.2
CPU_EDP_AUX_DN: length 103.1
  TOP w0.099: v1(87.22,89.71) 87.22,89.54 87.04,89.36 86.83,89.36 86.33,89.86 79.93,89.86 78.99,90.8 78.99,91.83 77.1,93.72 75.28,93.72 72.87,91.32 72.87,89.13 72.72,88.98 72.54,88.98 v1(72.3,89.22)
  L3 w0.099: v1(69.53,147.86) 69.43,147.86 69.18,148.11 69.18,148.35 69.5,148.67 73.51,148.67 75.34,146.84 76.46,146.84 79.61,143.69 79.61,142.88 82.09,140.4 82.09,137.09 82.8,136.38 84.75,136.38 85.98,135.15 85.98,129.08 87.95,127.1 87.95,125.49 88.83,124.61 88.83,115.42 86.79,113.39 86.79,105.37 93.64,98.52 93.64,94.19 89.3,89.86 88.37,89.86 87.84,89.33 87.46,89.33 87.22,89.58 v1(87.22,89.71)
  BOTTOM w0.099: v1(72.3,89.22) 72.3,89.17 72.88,88.59 U4500.K42 ; C3010.1 69.55,148.65 69.34,148.44 69.34,148.06 v1(69.53,147.86)
CPU_EDP_AUX_DP: length 103.1
  TOP w0.099: v1(72.3,88.53) 72.54,88.78 72.81,88.78 73.07,89.04 73.07,91.24 75.36,93.52 77.02,93.52 78.79,91.75 78.79,90.72 79.85,89.66 86.25,89.66 86.74,89.16 87.05,89.16 v1(87.22,88.99)
  L3 w0.099: v1(87.22,88.99) 87.36,89.13 87.93,89.13 88.45,89.66 89.38,89.66 93.84,94.11 93.84,98.61 86.99,105.45 86.99,113.3 89.03,115.34 89.03,124.69 88.15,125.57 88.15,127.19 86.18,129.16 86.18,135.24 84.84,136.58 82.89,136.58 82.29,137.17 82.29,140.48 79.81,142.96 79.81,143.77 76.55,147.04 75.43,147.04 73.59,148.87 69.41,148.87 68.98,148.44 68.98,148.04 v3(68.81,147.86)
  BOTTOM w0.099: v1(72.3,88.53) 71.93,88.89 U4500.M42 ; v3(68.81,147.86) 69.14,148.2 69.14,148.39 C3011.1
CPU_EDP_HPD#: length 101.7
  TOP w0.102: Q3003.3 99.43,156.82 100.52,155.73 R3020.1 105.28,154.45 v2(105.28,152.73) 105.28,150.22 103.21,148.15 103.21,146.08 104.69,144.6 104.69,142.66 103.96,141.93 103.96,138.54 103.73,138.3 103.73,132.92 102.66,131.85 v1(101.83,131.85)
  L4 w0.102: v1(82.65,127.61) 82.65,127.53 82.93,127.25 84.5,127.25 84.91,126.85 85.98,126.85 86.23,127.1 86.23,131.29 86.74,131.8 101.77,131.8 v1(101.83,131.85)
  BOTTOM w0.089: 70.72,94.47 70.72,93.93 70.45,93.66 U4500.R51
  BOTTOM w0.102: v1(82.65,127.61) 82.65,127.02 81.23,125.6 81.23,123.14 80.29,122.2 80.29,117.41 82.46,115.24 82.46,105.13 77.17,99.85 75.23,99.85 71.56,96.18 71.56,96.11 70.86,95.41 70.86,94.69 70.72,94.55 70.72,94.47
CPU_PROCHOT#: length 140.6
  TOP w0.109: v1(99.23,57.38) 98.49,58.12 98.49,59.81 98.63,59.94 98.63,65.49 97.7,66.42 92.88,66.42 91.56,67.74 91.56,74.77 92.58,75.79 v1(93.75,75.79) 93.74,75.78 93.74,73.19 94.56,72.36 96.01,72.36 98.05,74.4 99.54,74.4 101.05,75.9 101.05,81.74 100.76,82.03 100.76,88.28 99.13,89.91 97.07,89.91 94.36,92.62 v2(94.36,93.58) 94.36,96.64 94.36,98.04 92.85,99.55 89.82,99.55 87.95,101.42 86.54,101.42 86.54,101.42 85.54,101.42 85.21,101.75 83.71,103.25 76.25,103.25 75.38,104.12 74.76,104.12 74.43,104.45 74.43,105.48 75.02,106.08 75.02,108.57 v1(73.99,109.6)
  BOTTOM w0.109: v1(93.75,75.79) 93.75,72.74 94.13,72.36 U6600.2 ; v1(73.99,109.6) 74.65,110.26 ; 74.65,110.26 Q4505.3 74.81,110.74 74.1,111.46 74.1,115.09 77.79,118.78 77.79,122.19 79.46,123.87 79.46,126.38 80.11,127.02 80.11,134.9 79.88,135.13 79.88,137.88 79.47,138.29 79.47,141.08 79.19,141.37 79.19,145.37 Q300.3 ; 74.65,110.26 72.5,110.26 71.77,109.53 R4576.1 ; v1(99.23,57.38) 99.1,57.25 U6700.2
CPU_PROCHOT#_R: length 23.9
  TOP w0.109: v1(67.16,102.72) 67.16,102.03 64.73,99.61 v2(64.73,94.02) 64.61,93.9 v1(64.61,92.86)
  BOTTOM w0.102: v1(64.61,92.86) 64.77,92.7 65.23,92.7 65.47,92.93 65.71,92.93 65.88,92.76 65.88,92.44 U4500.AD50
  BOTTOM w0.109: v1(67.16,102.72) 69.58,105.14 69.58,106.89 70.63,107.95 R4575.1 70.92,107.95 R4576.2 70.92,109.26 72.57,110.91 Q4505.2
DDR3_M0_RCOMPPD: length 1.8
  TOP w0.254: R4504.2 57.56,81.53 57.91,81.88 v1(57.91,82.23)
  BOTTOM w0.254: v1(57.91,82.23) 57.91,82.11 U4500.BA28
DDR3_M1_RCOMPPD: length 1.7
  TOP w0.254: R4505.2 58.35,81.02 57.89,80.57 v1(57.89,80.31)
  BOTTOM w0.254: v1(57.89,80.31) 57.89,80.46 U4500.BA26
DDR3_VCCA_PWROK: length 52.9
  L3 w0.102: v1(67.36,54.54) 68.35,53.55 68.35,40.85 65.69,38.19 65.69,37.6 v3(65.12,37.03)
  L4 w0.089: 62.83,67.75 62.83,68.3 61.96,69.17 61.96,71.26 61.29,71.93 61.29,78.34 59.75,79.88 58.93,79.88 v1(58.51,80.31)
  L4 w0.102: v1(67.36,54.54) 66.96,54.94 65.28,54.94 64.32,55.9 64.32,59.56 62.83,61.05 62.83,67.75
  BOTTOM w0.102: v1(58.51,80.31) 58.62,80.42 58.62,80.45 U4500.AV26 ; v3(65.12,37.03) 64.91,36.82 R7247.1 64.91,36.06 Q7214.3
DP_TX0_C_DN: length 91.9
  TOP w0.099: v3(75.25,94.59) 75.51,94.85 77.81,94.85 80,92.66 84.78,92.66 85.47,91.97 85.47,91.69 86.5,90.65 87.01,90.65 v1(87.25,90.42)
  L3 w0.099: v1(87.25,90.42) 87.43,90.6 89.36,90.6 93.16,94.39 93.16,98.27 86.3,105.12 86.3,113.74 88.35,115.78 88.35,124.4 87.47,125.28 87.47,126.88 85.46,128.88 85.46,134.78 84.34,135.9 82.6,135.9 81.53,136.97 81.53,138.26 81.18,138.62 81.18,140.63 79.12,142.69 79.12,143.46 76.24,146.33 75.17,146.33 74.16,147.34 73.97,147.34 v1(73.74,147.57)
  BOTTOM w0.099: v1(73.74,147.57) 73.99,147.32 74.24,147.32 74.96,148.04 74.96,148.55 74.66,148.85 C4612.2 ; v3(75.25,94.59) 75.25,94.7 75.04,94.9 74.4,94.9 73.88,94.38 73.88,93.26 U4500.H51
DP_TX0_C_DP: length 91.9
  TOP w0.099: v1(75.25,95.32) 75.51,95.05 77.9,95.05 80.09,92.86 84.86,92.86 85.67,92.05 85.67,91.77 86.59,90.85 86.96,90.85 v1(87.25,91.14)
  L3 w0.099: v1(73.75,146.89) 73.75,146.97 73.92,147.14 74.08,147.14 75.08,146.13 76.16,146.13 78.92,143.38 78.92,142.61 80.98,140.55 80.98,138.53 81.33,138.18 81.33,136.89 82.52,135.7 84.26,135.7 85.26,134.69 85.26,128.8 87.27,126.8 87.27,125.19 88.15,124.31 88.15,115.86 86.1,113.82 86.1,105.03 92.95,98.18 92.95,94.48 89.28,90.8 87.46,90.8 87.25,91.01 v1(87.25,91.14)
  BOTTOM w0.099: v1(75.25,95.32) 75.04,95.1 74.32,95.1 73.68,94.47 73.68,93.66 U4500.J51 ; v1(73.75,146.89) 73.98,147.12 74.32,147.12 75.16,147.96 75.16,148.52 C4611.2
DP_TX0_DN: length 3.7
  BOTTOM w0.099: CN3000.13 73.53,151.67 73.68,151.52 73.68,151.29 74.14,150.82 74.47,150.82 74.94,150.35 74.94,150.05 C4612.1
DP_TX0_DP: length 3.7
  BOTTOM w0.099: CN3000.14 74.03,151.67 73.88,151.52 73.88,151.38 74.23,151.03 74.55,151.03 75.14,150.44 75.14,150.05 C4611.1
DP_TX1_C_DN: length 94.4
  TOP w0.099: v1(87.22,92.54) 86.96,92.28 86.49,92.28 85.02,93.75 80.16,93.75 77.29,96.62 75.33,96.62 73.9,95.19 72.32,95.19 72.09,95.42 v3(72.09,95.51)
  L3 w0.099: v1(71.87,146.88) 72,146.88 72.19,146.69 72.19,146.36 73.11,145.45 75.55,145.45 77.85,143.15 77.85,140.97 80.06,138.76 80.06,137.19 82.24,135.01 83.93,135.01 84.58,134.36 84.58,126.91 87.29,124.2 87.29,120.85 85.85,119.41 85.85,115.75 85.39,115.29 85.39,104.75 92.27,97.87 92.27,94.76 89.74,92.22 87.49,92.22 87.22,92.49 v1(87.22,92.54)
  BOTTOM w0.099: C4614.2 73.08,149.05 73.2,148.93 73.2,148.59 72.96,148.34 72.54,148.34 72.17,147.98 72.17,147.12 71.93,146.88 v1(71.87,146.88) ; v3(72.09,95.51) 72.09,95.32 72.29,95.13 72.6,95.13 72.88,94.85 U4500.K52
DP_TX1_C_DP: length 94.4
  TOP w0.099: v1(87.22,91.81) 86.96,92.07 86.41,92.07 84.93,93.55 80.08,93.55 77.21,96.42 75.41,96.42 73.98,94.99 72.3,94.99 v1(72.09,94.79)
  L3 w0.099: v3(72.56,146.88) 72.4,146.72 72.4,146.45 73.19,145.65 75.63,145.65 78.05,143.23 78.05,141.05 80.26,138.84 80.26,137.28 82.32,135.22 84.01,135.22 84.78,134.44 84.78,126.99 87.49,124.29 87.49,120.76 86.05,119.33 86.05,115.66 85.59,115.21 85.59,104.84 92.47,97.96 92.47,94.67 89.82,92.02 87.43,92.02 v1(87.22,91.81)
  BOTTOM w0.099: v3(72.56,146.88) 72.37,147.07 72.37,147.89 72.62,148.14 73.04,148.14 73.41,148.51 73.41,148.78 C4613.2 ; v1(72.09,94.79) 72.23,94.92 72.52,94.92 72.68,94.76 72.68,93.94 72.59,93.85 72.59,93.58 72.68,93.49 72.88,93.29 U4500.K51
DP_TX1_DN: length 3.3
  BOTTOM w0.099: CN3000.10 72.02,151.77 72.31,151.48 72.31,150.95 72.66,150.6 72.97,150.6 73.08,150.49 73.08,150.22 C4614.1
DP_TX1_DP: length 3.3
  BOTTOM w0.099: CN3000.11 72.51,152.49 72.51,151.03 72.75,150.8 73.06,150.8 73.28,150.58 73.28,150.18 73.56,149.91 C4613.1
DPTF_THERMAL_SEN: length 14.8
  TOP w0.102: U301.108 v1(69.33,158.63)
  BOTTOM w0.102: v2(64.83,147.9) 64.58,148.15 C351.1 64,149.42 R352.1 65.7,151.12 R351.2 65.7,152.03 67.15,153.48 67.15,156.57 69.21,158.63 v1(69.33,158.63)
EC_BKLTEN: length 64
  TOP w0.102: R3013.1 112.9,153.47 v3(112.66,153.71) ; 68.29,159.3 69.01,159.3 69.25,159.06 70.41,159.06 U301.107 ; v1(68.15,158.14) 67.81,158.47 R332.2
  TOP w0.109: R332.2 67.55,158.56 68.29,159.3
  BOTTOM w0.102: v3(112.66,153.71) 108.56,153.71 108.3,153.97 105.91,153.97 105.74,153.8 104.82,153.8 104.24,153.22 104.24,151.91 103.99,151.66 103.68,151.66 102.59,150.57 102.59,149.91 102.28,149.6 101.11,149.6 98.96,151.76 91.42,151.76 91.3,151.88 91.3,153.28 91.34,153.32 91.34,156.68 90.5,157.53 89.4,157.53 87.33,159.59 87.33,160.59 85.12,162.8 84.78,162.8 84.59,162.61 82.38,162.61 78.5,158.73 71.32,158.73 71,159.04 69.05,159.04 v1(68.15,158.14)
EC_MUTE#: length 161.6
  TOP w0.102: U301.95 72.44,163.68 v1(72.01,163.25) ; U500.47 13.42,49.54 13.62,49.35 v2(15.83,49.35) 20.01,49.35 21.48,50.82 21.48,56.24 21.27,56.45 21.27,56.75 21.27,91.65 21.03,91.89 21.03,102.98 21.03,103.28 37.35,119.6 37.35,126.24 36.11,127.49 36.11,128.12 35.97,128.26 35.97,134.94 v1(37.16,136.12)
  L4 w0.102: v1(37.16,136.12) 37.16,136.88 40.28,140 42.2,140 45.67,143.47 50.39,143.47 51.26,142.6 59.8,142.6 65.11,147.91 65.11,150.99 65.71,151.59 65.71,152.32 66.49,153.11 66.49,156.17 64.46,158.2 64.46,158.97 66.27,160.77 66.27,162.55 67.62,163.91 71.35,163.91 v1(72.01,163.25)
EC_PMU_BATLOW#: length 57.7
  TOP w0.102: v1(40.97,139.04) v2(44.07,142.14) 44.95,143.02 59.49,143.02 64.13,147.67 64.13,148.87 65.25,149.99 65.25,150.82 65.63,151.21 D4701.3 66.07,153.26 68.73,153.26 68.9,153.43 U301.121
  L4 w0.102: v1(34.97,127.56) 34.97,129.9 40.97,135.89 v1(40.97,139.04)
  BOTTOM w0.102: R4661.1 30.71,126.9 33.98,126.9 34.64,127.56 v1(34.97,127.56)
EC_PW_ON#: length 47.2
  TOP w0.102: v1(77.4,162.29) 77.71,162.6 77.71,164.56 U301.82
  L4 w0.102: v3(98.1,147.27) 100.06,147.27 102.54,149.76 102.54,150.37 99.6,153.31 98.86,153.31 96.57,155.6 94.79,155.6 94.47,155.93 91.48,155.93 91.15,155.6 88.73,155.6 86.48,157.85 86.48,160.29 84.58,162.19 84.58,162.19 84.16,162.61 77.72,162.61 v1(77.4,162.29)
  BOTTOM w0.102: R7104.2 100.5,146.09 100.25,146.09 Q7120.1 ; Q7120.1 99.5,146.95 99.18,147.27 v3(98.1,147.27) 97.75,147.27 96.71,146.23 Q7000.1 ; Q7120.1 99.5,146.01 99.03,145.54 R7100.1
EC_PWRSW#: length 17.7
  TOP w0.102: D4700.3 67.81,165.1 v3(67.76,165.15) 67.46,165.46 65.71,165.46 65.17,164.92 R346.1 ; U301.79 78.84,163.48 v1(78.71,163.35)
  BOTTOM w0.102: v3(67.76,165.15) 68.27,164.64 69.21,164.64 69.68,165.11 76.95,165.11 v1(78.71,163.35)
EC_RSMRST#: length 192.1
  TOP w0.089: v1(75.4,76.44) 75.83,76.86 78.89,76.86 v2(79.26,76.49) 79.84,75.91
  TOP w0.102: v1(82.95,71.83) 82.14,72.65 82.14,74.65 81.49,75.29 R4814.1 80.46,75.29 79.84,75.91 ; v1(101.74,141.38) 101.5,141.38 100.37,142.5 100.37,143.44 97.77,146.04 92.09,146.04 91.51,145.47 87.83,145.47 85.57,143.2 82.9,143.2 82.39,143.72 R333.1 82.39,145.09 81.64,145.84 U301.25
  L3 w0.102: v1(76.81,42.39) 77.02,42.6 77.02,48.05 75.54,49.53 75.54,50.91 77.3,52.67 77.3,54.76 76.35,55.7 76.35,61.87 80.44,65.97 80.44,68.05 82.95,70.56 v1(82.95,71.83)
  L4 w0.102: v1(101.74,141.38) 102.04,141.38 103.49,139.93 104.1,139.93 104.55,139.47 105.25,139.47 107.16,137.56 107.16,135.87 107.55,135.48 107.55,134.02 107.34,133.81 107.34,131.46 108.38,130.43 108.38,122.27 108.01,121.9 108.01,120.21 108.3,119.92 108.3,119.58 108.3,119.58 108.3,112.4 109.45,111.26 v1(109.45,110.97) 109.78,110.64 109.78,110.07 108.99,109.28 108.99,106.55 108.45,106.02 108.45,105.12 106.65,103.32 106.65,101.6 106.65,100.75 105.8,99.91 105.8,98.23 105.8,97.72 104.12,96.04 104.12,70.47 103.45,69.79 103.45,65.71 100.1,62.36 97.68,62.36 89.84,70.2 89.84,71.93 89.35,72.41 84.35,72.41 83.77,71.83 v1(82.95,71.83)
  BOTTOM w0.089: v1(75.4,76.44) 75.4,76.52 75.05,76.87 U4500.F18
  BOTTOM w0.102: v1(76.81,42.39) 76.81,39.24 75.97,38.41 U4702.9 ; v1(109.45,110.97) 109.19,111.22 D60000.1
EC_SCI#: length 67.2
  TOP w0.109: v1(80.74,143.89) 80.45,144.18 80.45,149.02 U301.22
  L4 w0.135: v1(81.1,129.72) 80.72,130.1 80.72,131.11 78.52,133.31 78.52,137.19 77.78,137.94 77.78,139.17 78.07,139.46 78.07,140.56 80.74,143.23 v1(80.74,143.89)
  BOTTOM w0.109: U4500.AG51 64.43,93.54 64.43,93.84 64.34,93.93 64.34,94.25 64.51,94.43 64.51,97.61 67.09,100.18 67.09,101.03 71.42,105.36 72.29,105.36 R4548.1 72.34,105.47 72.97,106.1 73.53,106.1 75.92,108.48 75.92,110.9 74.99,111.83 74.99,114.72 78.68,118.41 78.68,121.82 80.36,123.5 80.36,125.96 81.23,126.83 81.23,129.59 v1(81.1,129.72)
EC_SMB1_CLK: length 174.8
  TOP w0.109: R322.2 87.83,148.8 87.83,149.35 88.52,150.04 v1(88.7,150.04) ; v1(82.28,161.65) 82.28,162.17 82.44,162.33 U301.70
  L3 w0.135: v1(106.27,26.72) 109.32,29.77 109.32,33.8 109.32,59.35 110.89,60.92 110.89,80.93 107.91,83.91 107.91,94.82 114.21,101.13 114.21,102 114.61,102.39 114.61,105.31 115.3,106 115.3,108.3 115.7,108.7 115.7,140.84 110.78,145.77 108.56,145.77 107.31,147.02 105.07,147.02 104.35,147.74 101.84,147.74 100.53,149.04 96.33,149.04 95.93,149.45 91.97,149.45 91.12,150.29 88.99,150.29 88.73,150.04 v1(88.7,150.04) 87.95,150.04 87.87,150.12 84.62,150.12 83.19,151.55 83.19,152.82 82.7,153.32 82.29,153.72 82.29,158.01 82.47,158.18 82.47,160.41 82.46,160.43 82.46,161.47 v1(82.28,161.65)
  BOTTOM w0.109: R6052.1 v1(106.27,26.72)
EC_SMB1_DATA: length 177.1
  TOP w0.109: v1(82.81,162) 82.67,162.14 82.67,163.49 82.84,163.66 U301.69 ; R321.2 87.34,149.6 88.38,150.64 v1(88.56,150.64)
  L3 w0.135: v1(82.81,162) 82.97,161.83 82.97,160.64 82.99,160.63 82.99,158.4 82.99,157.97 82.81,157.79 82.81,153.94 83.21,153.53 83.71,153.04 83.71,151.77 84.83,150.64 v1(88.56,150.64) 88.61,150.64 88.78,150.81 91.34,150.81 92.18,149.96 96.14,149.96 96.55,149.56 100.75,149.56 102.05,148.25 104.83,148.25 105.13,147.95 107.11,147.95 108.78,146.28 111.64,146.28 116.28,141.64 116.28,130.46 116.55,130.19 116.55,124.2 116.24,123.89 116.24,108.74 116.55,108.43 116.55,105.72 115.13,104.3 115.13,103.98 115.12,103.97 115.12,102.18 114.73,101.79 114.73,99.9 113.78,98.94 112.76,98.94 108.42,94.61 108.42,84.66 111.4,81.68 111.4,59.61 109.86,58.07 109.86,29.42 v3(106.25,25.81)
  BOTTOM w0.109: R6050.1 v3(106.25,25.81)
EC_SMB2_CLK: length 225.4
  TOP w0.109: U301.67 83.64,163.37 v1(83.69,163.32) 83.89,163.11 84.44,163.11 84.68,163.35 84.68,163.6 85.52,164.44 86.21,164.44 R317.2
  L3 w0.135: v3(63.98,32.39) 65.48,32.39 68.73,35.64 74.46,35.64 75.27,34.83 86.73,34.83 91.26,30.3 94.5,30.3 96.7,28.11 104.78,28.11 105.08,28.41 108.8,32.13 108.8,59.56 110.37,61.13 110.37,80.7 107.39,83.68 107.39,95.03 113.7,101.34 113.7,102.21 114.09,102.61 114.09,105.52 114.39,105.82 114.78,106.21 114.78,108.08 114.78,108.51 115.19,108.92 115.19,140.63 110.56,145.25 108.35,145.25 107.1,146.51 104.86,146.51 104.14,147.22 101.62,147.22 100.32,148.53 99.63,148.53 99.63,148.53 96.12,148.53 95.72,148.93 91.75,148.93 91.08,149.6 89.23,149.6 89.15,149.52 87.74,149.52 87.74,149.52 87.12,149.52 87.03,149.61 84.41,149.61 82.79,151.23 82.68,151.34 82.68,152.61 82.18,153.1 81.78,153.51 81.78,158.22 81.95,158.4 81.95,160.2 81.86,160.3 81.86,161.34 81.77,161.43 81.77,161.86 82.07,162.16 82.2,162.16 82.55,162.52 82.88,162.52 83.16,162.8 83.29,162.8 83.59,163.1 83.59,163.23 v1(83.69,163.32)
  BOTTOM w0.109: v3(63.98,32.39) 63.36,31.77 63.36,29.46 62.8,28.89 U6000.9
EC_SMB2_DATA: length 225.9
  TOP w0.109: U301.68 83.24,163.48 v1(83.08,163.31) 83.49,162.9 84.54,162.9 85.58,163.95 86.61,163.95 R316.2
  L3 w0.135: v1(63.13,32.7) 63.47,33.04 65.4,33.04 68.51,36.16 74.68,36.16 75.49,35.35 86.94,35.35 91.47,30.82 94.72,30.82 96.91,28.63 104.57,28.63 108.29,32.34 108.29,59.78 109.86,61.34 109.86,80.49 107.26,83.08 106.88,83.47 106.88,95.25 112.85,101.22 112.85,103.54 113.58,104.27 113.58,105.74 114.27,106.43 114.27,107.87 114.27,108.74 114.67,109.15 114.67,140.42 110.35,144.74 107.48,144.74 107.13,145.09 106.3,145.92 103.68,145.92 102.89,146.71 102.86,146.71 101.41,146.71 100.11,148.01 95.91,148.01 95.5,148.42 91.54,148.42 90.87,149.09 89.45,149.09 89.36,149.01 86.77,149.01 86.68,149.09 84.19,149.09 82.57,150.71 82.16,151.12 82.16,152.4 81.11,153.45 81.11,161.8 81.25,161.94 81.25,162.07 81.85,162.68 81.99,162.68 82.62,163.31 v1(83.08,163.31)
  BOTTOM w0.109: v1(63.13,32.7) 62.68,32.26 v2(62.68,31.77) 62.68,29.47 62.3,29.09 U6000.8
EC_SMI#: length 77.4
  TOP w0.109: U301.9 75.24,150.71 75.65,151.11 75.65,153.25 v1(77.49,155.1)
  BOTTOM w0.109: R4656.1 110.57,119.18 111.63,120.25 111.63,129.44 113.1,130.91 113.89,130.91 114.68,131.7 v2(114.68,131.93) 114.68,143.76 112.07,146.38 109.08,146.38 106.62,148.84 104.98,148.84 104.71,148.58 101.54,148.58 100.69,148.58 98.84,150.42 93.01,150.42 92.44,149.85 91.62,149.85 91.11,150.36 90.89,150.36 89.4,151.84 86.92,151.84 85.38,153.37 83.73,153.37 83.72,153.39 82,155.1 v1(77.49,155.1)
EC_SPI_CLK: length 1.4
  BOTTOM w0.109: R342.1 72.39,38.84 73.41,38.84 U4702.2
EC_SPI_CS0#: length 1.6
  BOTTOM w0.109: U4702.1 73.33,38.41 72.67,37.74 R343.1
EC_SPI_R_CLK: length 211
  TOP w0.109: U301.92 73.64,163.71 73.47,163.54 73.47,163.02 73.91,162.59 v1(73.91,162.18)
  L3 w0.135: v1(73.91,162.18) 75.3,162.18 75.66,161.82 77.15,161.82 79.42,159.55 79.42,154.24 79.65,154.01 79.65,152.74 80.25,152.14 80.25,151.03 84.2,147.07 90.87,147.07 91.75,146.19 99.84,146.19 100.74,145.29 102.3,145.29 103.09,144.5 105.71,144.5 106.89,143.32 109.76,143.32 112.86,140.22 112.86,132.45 112.87,132.44 112.87,122.11 113.25,121.73 113.25,119.08 112.85,118.68 112.85,109.42 112.85,109.42 112.85,107.33 111.97,106.45 111.97,105.94 111.97,105.38 111.01,104.42 111.01,102.94 107.02,98.94 107.02,97.4 105.46,95.84 105.46,82.86 107.89,80.42 107.89,73.84 109.21,72.52 109.21,61.61 107.54,59.94 107.54,48.16 106.52,47.14 106.52,31.5 105.57,30.54 105.19,30.17 96.28,30.17 93.59,32.85 90.35,32.85 87.21,35.99 75.75,35.99 74.44,37.3 71.56,37.3 v3(70.49,38.37)
  BOTTOM w0.109: R342.2 70.78,38.66 v3(70.49,38.37)
EC_SPI_R_CS0#: length 212.2
  TOP w0.109: U301.90 74.44,163.6 74.34,163.5 74.34,162.02 v1(73.53,161.21)
  L3 w0.135: v1(73.53,161.21) 73.83,161.51 75.06,161.51 75.4,161.18 76.88,161.18 78.71,159.35 78.71,152.77 79.6,151.87 79.6,150.76 83.94,146.43 88.02,146.43 88.92,145.53 98.33,145.53 100.01,143.85 105.45,143.85 106.67,142.63 109.54,142.63 112.22,139.96 112.22,132.19 112.23,132.17 112.23,122.38 112.23,121.84 112.61,121.47 112.61,119.35 112.2,118.94 112.2,107.59 110.37,105.76 110.37,103.2 106.37,99.21 106.37,97.66 104.81,96.1 104.81,82.57 107.23,80.16 107.23,73.6 108.57,72.25 108.57,62.17 106.9,60.5 106.9,48.45 105.88,47.44 105.88,31.77 104.92,30.81 96.54,30.81 93.64,33.71 90.4,33.71 87.48,36.63 76.02,36.63 74.71,37.94 72.59,37.94 71.74,38.79 70.17,38.79 v1(69.74,38.37)
  BOTTOM w0.109: v1(69.74,38.37) 70.37,37.74 R343.2
EC_SPI_SI_IO0: length 202.5
  TOP w0.109: U301.87 75.64,163.73 75.77,163.6 75.77,162.61 v1(74.19,161.04)
  L3 w0.135: v1(74.19,161.04) 74.57,160.66 76.67,160.66 78.19,159.14 78.19,152.55 79.08,151.66 79.08,150.55 83.72,145.91 87.8,145.91 88.71,145 96.6,145 97.28,144.32 98.7,144.32 99.69,143.33 105.23,143.33 106.45,142.11 109.32,142.11 111.54,139.89 111.54,132.12 111.71,131.95 111.71,122.59 111.71,121.63 112.09,121.25 112.09,119.57 111.68,119.16 111.68,107.92 109.7,105.94 109.7,105.72 109.7,103.27 105.85,99.43 105.85,97.88 104.29,96.32 104.29,82.36 106.7,79.94 106.7,73.38 108.05,72.04 108.05,62.98 105.54,60.47 105.54,60.21 105.54,58.06 104.17,56.69 104.17,50.89 99.24,45.97 99.24,43.99 98.72,43.47 96.74,43.47 92.49,39.22 77.33,39.22 72.97,43.57 72.97,54.33 v3(73.1,54.46)
  BOTTOM w0.109: v3(73.1,54.46) 72.97,54.33 72.97,53.26 R341.2
EC_SPI_SO_IO1: length 188.9
  TOP w0.109: U301.86 76.04,162.25 v1(74.88,161.09)
  L3 w0.135: v3(73.55,41.98) 74.04,41.98 77.06,38.96 92.6,38.96 96.85,43.2 98.83,43.2 99.5,43.88 99.5,45.86 104.43,50.79 104.43,56.58 105.8,57.95 105.8,59.53 105.8,60.36 108.31,62.87 108.31,72.14 106.96,73.49 106.96,80.05 104.55,82.47 104.55,96.21 106.11,97.77 106.11,99.32 109.96,103.17 109.96,105.83 111.94,107.81 111.94,119.05 112.35,119.46 112.35,121.36 111.97,121.74 111.97,122.49 111.97,132.06 111.95,132.08 111.95,139.85 109.43,142.37 106.56,142.37 105.34,143.59 99.8,143.59 98.79,144.6 97.37,144.6 96.71,145.27 88.81,145.27 87.91,146.17 83.83,146.17 79.34,150.66 79.34,151.76 78.45,152.66 78.45,159.25 76.78,160.92 75.05,160.92 v1(74.88,161.09)
  BOTTOM w0.109: R340.2 v3(73.55,41.98)
EC_WAKE_SCI#_N: length 4.9
  BOTTOM w0.089: 66.61,95.16 66.15,94.7
  BOTTOM w0.102: U4500.AD51 66.07,93.29 65.78,93.58 65.78,93.84 65.87,93.92 65.87,94.42 66.15,94.7 ; 66.61,95.16 v2(66.61,96.36) 66.61,96.57 R4544.1
EC_WLAN_PCIE_WAKE#: length 70.4
  TOP w0.102: R1302.1 40.97,132.18 v2(41.57,132.79) 42.14,133.35 v1(42.14,133.43) ; v1(72.31,159.21) 72.89,158.62 77.52,158.62 78.44,159.54 78.44,161.07 80.65,163.28 80.65,163.53 80.84,163.73 U301.74
  L4 w0.102: v1(72.31,159.21) 72.31,157.06 68.37,153.12 68.37,149.87 67.16,148.66 67.16,148.45 67.16,147.28 65.39,145.52 65.39,140.03 64.81,139.44 63.41,139.44 61.23,141.63 51.66,141.63 50.67,142.62 50.42,142.86 49.73,142.86 49.73,142.86 48.53,142.86 48.52,142.86 46.37,142.86 v1(42.72,139.22)
  BOTTOM w0.102: v1(42.72,139.22) 41.86,139.22 41.22,138.58 41.22,135 42.14,134.09 v1(42.14,133.43)
EDP_AUX_DN: length 4.1
  BOTTOM w0.099: CN3000.5 69.52,151.67 69.38,151.52 69.38,151.07 69.43,151.02 69.43,149.84 C3010.2 R3016.2
EDP_AUX_DP: length 4.1
  BOTTOM w0.099: R3017.1 C3011.2 69.23,149.84 69.23,150.94 69.17,150.99 69.17,151.52 69.02,151.67 CN3000.4
EDP_BKLTEN: length 58.6
  TOP w0.102: v4(110.09,140.7) 111.86,140.7 115.31,144.16 v2(115.31,149.86) 115.31,152.42 115.07,152.67 C3007.1 R20.1 113.07,151.82 R3013.2
  L3 w0.135: v4(110.09,140.7) 108.95,141.85 106.16,141.85 105.75,142.26 100.34,142.26 98.54,144.05 97.17,144.05 96.48,144.74 96.41,144.74 88.6,144.74 87.69,145.65 83.59,145.65 78.82,150.42 78.82,151.47 77.72,152.57 v1(77.72,153.97)
  BOTTOM w0.102: v1(77.72,153.97) 77.53,153.77 CN3000.21
EDP_HPD_CN: length 41.3
  TOP w0.102: v1(97.42,150.01) 97.09,149.68 94.42,149.68 93.71,150.4 93.71,152.41 92.95,153.16 92.95,154.92 93.61,155.58 97.13,155.58 97.49,155.22 R3021.1 97.92,155.54 Q3003.1
  BOTTOM w0.102: v1(97.42,150.01) 97.31,150.11 93.03,150.11 92.54,149.62 91.52,149.62 91.01,150.13 90.79,150.13 89.36,151.55 86.4,151.55 85.97,151.12 v2(85.16,151.12) 84.34,151.12 83.5,151.97 83.5,153.1 83.28,153.32 81.91,154.69 81.61,154.69 77.78,154.69 76.53,153.44 CN3000.19
EN_1V05A: length 8
  TOP w0.102: v1(91.41,116.03) v2(90.4,116.03) 89.91,116.03 R7252.2
  BOTTOM w0.127: v1(91.41,116.03) 91.49,115.94 U60600.26
EN_3V: length 25.4
  L4 w0.102: v1(71.12,143.28) 71.4,143.56 76.97,143.56 78.03,142.5 78.72,142.5 79.26,143.04 79.26,143.62 80.51,144.87 81.13,144.87 81.42,144.58 87.32,144.58 v1(88.9,146.15)
  BOTTOM w0.102: v1(88.9,146.15) 89.79,147.04 R7003.2 ; v1(71.12,143.28) 71.12,142.82 71.8,142.14 71.8,140.7 72.05,140.46 U6100.13
EN_5V: length 74.3
  TOP w0.102: R7000.2 90.3,141.07 v1(90.52,141.3) ; R7110.1 62.92,130.4 v2(59.38,130.4) 57.01,130.4 v1(54.07,133.34)
  L4 w0.102: v1(90.52,141.3) 91.26,142.03 v1(91.26,146.09) 90.84,146.51 90.4,146.51 85.53,141.63 85.36,141.63 83.47,141.63 83.11,141.99 83.11,143 82.03,144.07 81.35,144.07 81.04,144.39 80.6,144.39 80.05,143.84 80.05,143.25 78.84,142.05 77.35,142.05 76.25,143.15 72.08,143.15 71.32,142.39 70.01,142.39 69.11,141.5 69.11,138.32 69.11,138.15 65.07,134.11 59.38,134.11 58.68,134.81 56.73,134.81 54.85,132.93 54.51,132.93 54.11,133.34 v1(54.07,133.34)
  BOTTOM w0.102: U6150.13 91.36,140.46 v1(90.52,141.3) ; v1(91.26,146.09) 92.26,146.09 D7000.1 Q7000.3
EN_5VLDO: length 4.2
  BOTTOM w0.254: U6150.12 91.05,140.06 v2(90.61,140.49) 90.33,140.77 R6151.2 89.71,140.77 R6150.1 88.74,140.69 R6167.1
EN_PVCORE: length 28.4
  TOP w0.102: v1(100.56,66.09) 99.86,66.09 v2(99,66.96) 98.47,67.49 93.11,67.49 92.48,68.12 92.48,73.79 v1(93.11,74.42)
  BOTTOM w0.102: v1(100.56,66.09) 100.72,66.09 103.16,63.65 103.16,59.94 103.91,59.19 103.91,57.01 103.12,56.23 R7250.2 ; R6643.2 v1(93.11,74.42)
EN_PVGG: length 1.8
  BOTTOM w0.102: C7203.1 103.14,57 R7204.2 R6743.2
EN_VDDQ: length 5.2
  BOTTOM w0.254: U60300.6 39.01,27.31 38.6,27.71 37.97,27.71 37.66,27.4 C7207.1 35.96,27.41 R7208.2
EN_VTT: length 12.7
  TOP w0.102: v1(38.44,27.18) 38.44,27.55 34.8,31.19 v1(34.06,31.19)
  BOTTOM w0.102: R7207.2 C7206.1 35.25,33.93 D7200.1 34.79,31.92 v2(34.64,31.77) v1(34.06,31.19)
  BOTTOM w0.254: v1(38.44,27.18) 38.55,27.18 38.82,26.91 U60300.5
FLASH_OVERRIDE: length 91.4
  TOP w0.102: v1(69.19,157.73) 69.49,157.43 U301.111
  L3 w0.102: v1(64.17,142.78) 64.27,142.78 64.36,142.87 71.47,142.87 72.29,143.69 76.21,143.69 77.17,142.73 77.17,140 79.33,137.84 79.33,129.97 80.74,128.55 v1(80.74,127.74)
  L4 w0.102: v1(69.19,157.73) 69.19,156.84 67.49,155.15 67.49,151.76 66.59,150.86 66.59,149.33 66.28,149.03 66.28,148.08 66.28,147.67 63.82,145.21 63.82,143.13 v1(64.17,142.78)
  BOTTOM w0.102: U4500.AH52 64.13,93.85 64.14,93.85 64.14,94.34 64.31,94.51 64.31,96.46 ; R4550.2 72.71,106.71 R4844.1 73.46,106.71 v2(75.11,108.36) 75.43,108.69 75.43,110.7 74.51,111.63 74.51,114.92 78.2,118.61 78.2,122.02 79.88,123.7 79.88,126.16 80.74,127.03 v1(80.74,127.74)
  BOTTOM w0.114: R4550.2 71.85,105.85 71.21,105.85 66.59,101.23 66.59,99.97 64.31,97.69 64.31,96.46
GPIO0_RCOMP: length 1.5
  TOP w0.254: R4555.2 64.73,87.02 v3(64.64,87.11)
  BOTTOM w0.254: v3(64.64,87.11) 64.5,87.11 U4500.AH40
GPS_32K_CLK: length 4.7
  BOTTOM w0.109: U4500.C15 76.96,75.45 77.24,75.16 77.52,75.16 78.42,74.27 80.44,74.27 TP4536.1
H_PROCHOT_EC: length 5.7
  TOP w0.102: v3(79.5,147.29) 79.97,147.76 79.97,148.96 U301.21
  BOTTOM w0.102: Q300.1 77.38,144.76 78.81,146.2 R324.1 79.24,147.04 v3(79.5,147.29)
HDA_BITCLK: length 94.7
  TOP w0.109: v1(69.57,60.11) 69.55,60.11 69.06,60.61 v2(69.06,63.45) 69.06,65.23 C4652.1 67.84,66.45 67.84,67.44 R4538.2 ; R506.2 18.1,51.74 v1(18.63,51.74)
  L3 w0.135: v1(69.57,60.11) 70.37,59.31 70.37,40.68 69.6,39.91 67.24,37.55 67.24,36.15 64.91,33.82 59.03,33.82 58.85,33.65 53.87,33.65 53.7,33.82 31.47,33.82 31.17,34.12 20.04,45.25 20.04,49.48 18.63,50.89 v1(18.63,51.74)
HDA_R_BITCLK: length 3.6
  TOP w0.109: R506.1 C510.1 v2(15.94,52.48) 15.85,52.48 15.53,52.79 U500.6
HDA_R_SDIN0: length 2.7
  TOP w0.109: U500.8 16.87,53.59 16.87,53.59 R507.1
HDA_RST#: length 99.2
  TOP w0.109: v1(19.22,54.38) 19.2,54.38 18.82,54.76 17.92,54.76 17.78,54.63 15.08,54.63 14.92,54.79 U500.11 ; R4536.2 64.97,67.62 64.27,66.93 64.27,64.67 64.54,64.4 v2(64.54,64.06) 64.54,61.94 68.14,58.34 v1(68.32,58.34)
  L3 w0.135: v1(68.32,58.34) 68.39,58.27 68.39,56.45 68.38,56.44 68.38,56.09 68.39,56.08 68.39,55.04 68.59,54.84 68.59,40.74 65.94,38.09 65.94,37.23 64.05,35.34 58.71,35.34 58.32,34.95 54.41,34.95 54.02,35.34 32.95,35.34 22.65,45.64 22.65,52.96 21.22,54.38 v1(19.22,54.38)
HDA_SDIN0: length 99.5
  TOP w0.109: v1(68.91,60.04) 68.48,60.48 68.48,65.1 68.12,65.46 67.96,65.46 67.43,65.99 67.43,67.64 66.88,68.2 66.88,71.02 v3(66.56,71.33) ; R507.2 18.12,53.54 18.83,53.54 v1(19.22,53.14)
  L3 w0.135: v1(68.91,60.04) 69.85,59.1 69.85,40.89 66.72,37.76 66.72,37.14 66.72,37.14 66.72,36.91 64.16,34.34 58.81,34.34 58.64,34.17 54.09,34.17 53.92,34.34 31.68,34.34 20.56,45.46 20.56,49.69 19.22,51.03 v1(19.22,53.14)
  BOTTOM w0.109: U4500.AD7 66.37,71.52 v3(66.56,71.33)
HDA_SDOUT: length 99.4
  TOP w0.109: R4539.2 63.21,63.09 v2(63.21,63.09) 63.21,60.92 65.55,58.57 v1(66.47,58.57) ; U500.5 15.35,52.39 15.74,52 15.79,52 16.71,51.08 18.66,51.08 19.27,51.69 v1(19.66,51.69)
  L3 w0.135: v1(19.66,51.69) 21.32,50.03 21.32,45.08 28.75,37.64 29.91,37.64 32.73,34.82 53.81,34.82 54.2,34.43 58.53,34.43 58.92,34.82 63.83,34.82 64.26,34.82 66.46,37.01 66.46,37.87 69.59,41 69.59,58.93 69.01,59.51 67.41,59.51 v1(66.47,58.57)
HDA_SYNC: length 100.1
  TOP w0.109: U500.10 17.36,54.39 17.9,53.85 19.15,53.85 v1(19.22,53.77) ; R4537.2 64.72,67.01 64.72,66.37 64.97,66.12 v2(64.97,65.68) 65.02,65.63 65.02,61.79 67.87,58.94 v1(68.15,58.94)
  L3 w0.135: v1(19.22,53.77) 21.46,53.77 22.38,52.85 22.38,45.53 32.84,35.08 53.91,35.08 54.31,34.69 58.42,34.69 58.81,35.08 63.94,35.08 64.16,35.08 66.2,37.12 66.2,37.98 69.33,41.11 69.33,57.94 68.33,58.94 v1(68.15,58.94)
HDMI_CN_DDCCLK: length 31
  TOP w0.109: v1(19.71,125.26) 22.04,125.26 24.3,127.52 24.3,134.57 19.99,138.88 R3152.2 15.91,138.88 15.19,138.15 14.27,138.15 13.92,137.8 v2(12.9,137.8) 12.38,137.8 11.63,137.05 11.63,135.66 11.17,135.2 CN3150.15
  BOTTOM w0.109: v1(19.71,125.26) 19.47,125.26 Q3150.3
HDMI_CN_DDCDATA: length 25.2
  TOP w0.109: CN3150.16 12.63,136.07 15.87,136.07 R3153.2 17.48,136.41 v2(17.7,136.63) 18.59,137.52 20.66,137.52 23.81,134.37 23.81,127.72 21.84,125.75 v1(20.55,125.75)
  BOTTOM w0.109: v1(20.55,125.75) 21.29,125.75 Q3151.3
HDMI_DDC_CLK: length 103.5
  L3 w0.135: v3(71.01,100.46) 71.01,102.19 71.65,102.82 71.65,105.73 72.83,106.92 72.83,108.19 70.01,111.01 69.69,111.33 69.69,116.85 64.08,122.46 62.6,122.46 61.98,123.08 48.63,123.08 39.87,114.32 32.61,114.32 29.84,111.55 28.48,111.55 25.46,108.53 22.21,108.53 20.75,109.99 20.75,118.03 19.93,118.86 19.93,121.67 v1(17.32,124.28)
  BOTTOM w0.109: v1(17.32,124.28) 17.32,123.88 18.03,123.16 R3179.2 18.5,123.99 Q3150.2 ; v3(71.01,100.46) 71.01,99.99 70.77,99.75 70.77,97.03 70.26,96.52 70.26,95.06 69.76,94.56 69.76,93.93 69.67,93.84 69.67,93.83 69.67,93.58 69.96,93.29 U4500.T51
HDMI_DDC_DAT: length 99.5
  L3 w0.135: v1(71.65,99.82) 71.65,102.1 72.52,102.97 72.52,105.88 73.35,106.71 73.35,108.4 73.05,108.7 70.21,111.54 70.21,117.06 64.29,122.98 62.89,122.98 62.27,123.6 48.85,123.6 48.42,123.6 39.66,114.84 32.29,114.84 29.52,112.07 28.27,112.07 27.96,111.77 25.25,109.05 22.42,109.05 21.26,110.21 21.26,118.25 20.44,119.07 20.44,122.89 v1(20.16,123.16)
  BOTTOM w0.109: Q3151.2 20.83,124.09 R3178.2 v1(20.16,123.16) ; U4500.T52 69.96,94.48 70.45,94.97 70.45,96.44 70.96,96.95 70.96,99.26 71.52,99.82 v1(71.65,99.82)
HDMI_DDC_HPD: length 103
  L3 w0.102: v1(74.55,106.4) 74.55,108.48 74.04,108.99 73.53,108.99 71.22,111.3 71.22,113.34 70.71,113.85 70.71,117.32 66.42,121.61 66.42,122.1 65.04,123.48 63.23,123.48 62.61,124.1 49.05,124.1 48.21,124.1 39.45,115.34 32.08,115.34 29.31,112.57 28.06,112.57 27.77,112.28 27.47,111.97 25.04,109.55 22.63,109.55 21.76,110.41 21.76,116.71 23.44,118.39 23.44,122.22 v1(22.5,123.16)
  BOTTOM w0.102: U4500.U51 69.28,93.54 69.28,93.83 69.2,93.91 69.2,95.12 70.06,95.98 70.06,96.6 70.41,96.95 70.41,99.92 70.54,100.06 70.54,100.62 v2(71.27,101.35) 72.82,102.9 72.82,103.76 73.38,104.32 73.93,104.32 74.27,104.66 74.27,105.64 74.55,105.91 v1(74.55,106.4) ; Q3153.3 23.57,124.1 23.57,124.1 R3171.1 v1(22.5,123.16)
HDMI_HPD_CN: length 23.3
  TOP w0.102: R3154.1 14.97,139.65 C3151.1 R3150.1 v2(17.62,139.65) 19.91,139.65 24.79,134.77 24.79,127.32 23.1,125.63 v1(23.1,125.19)
  BOTTOM w0.102: Q3153.1 v1(23.1,125.19)
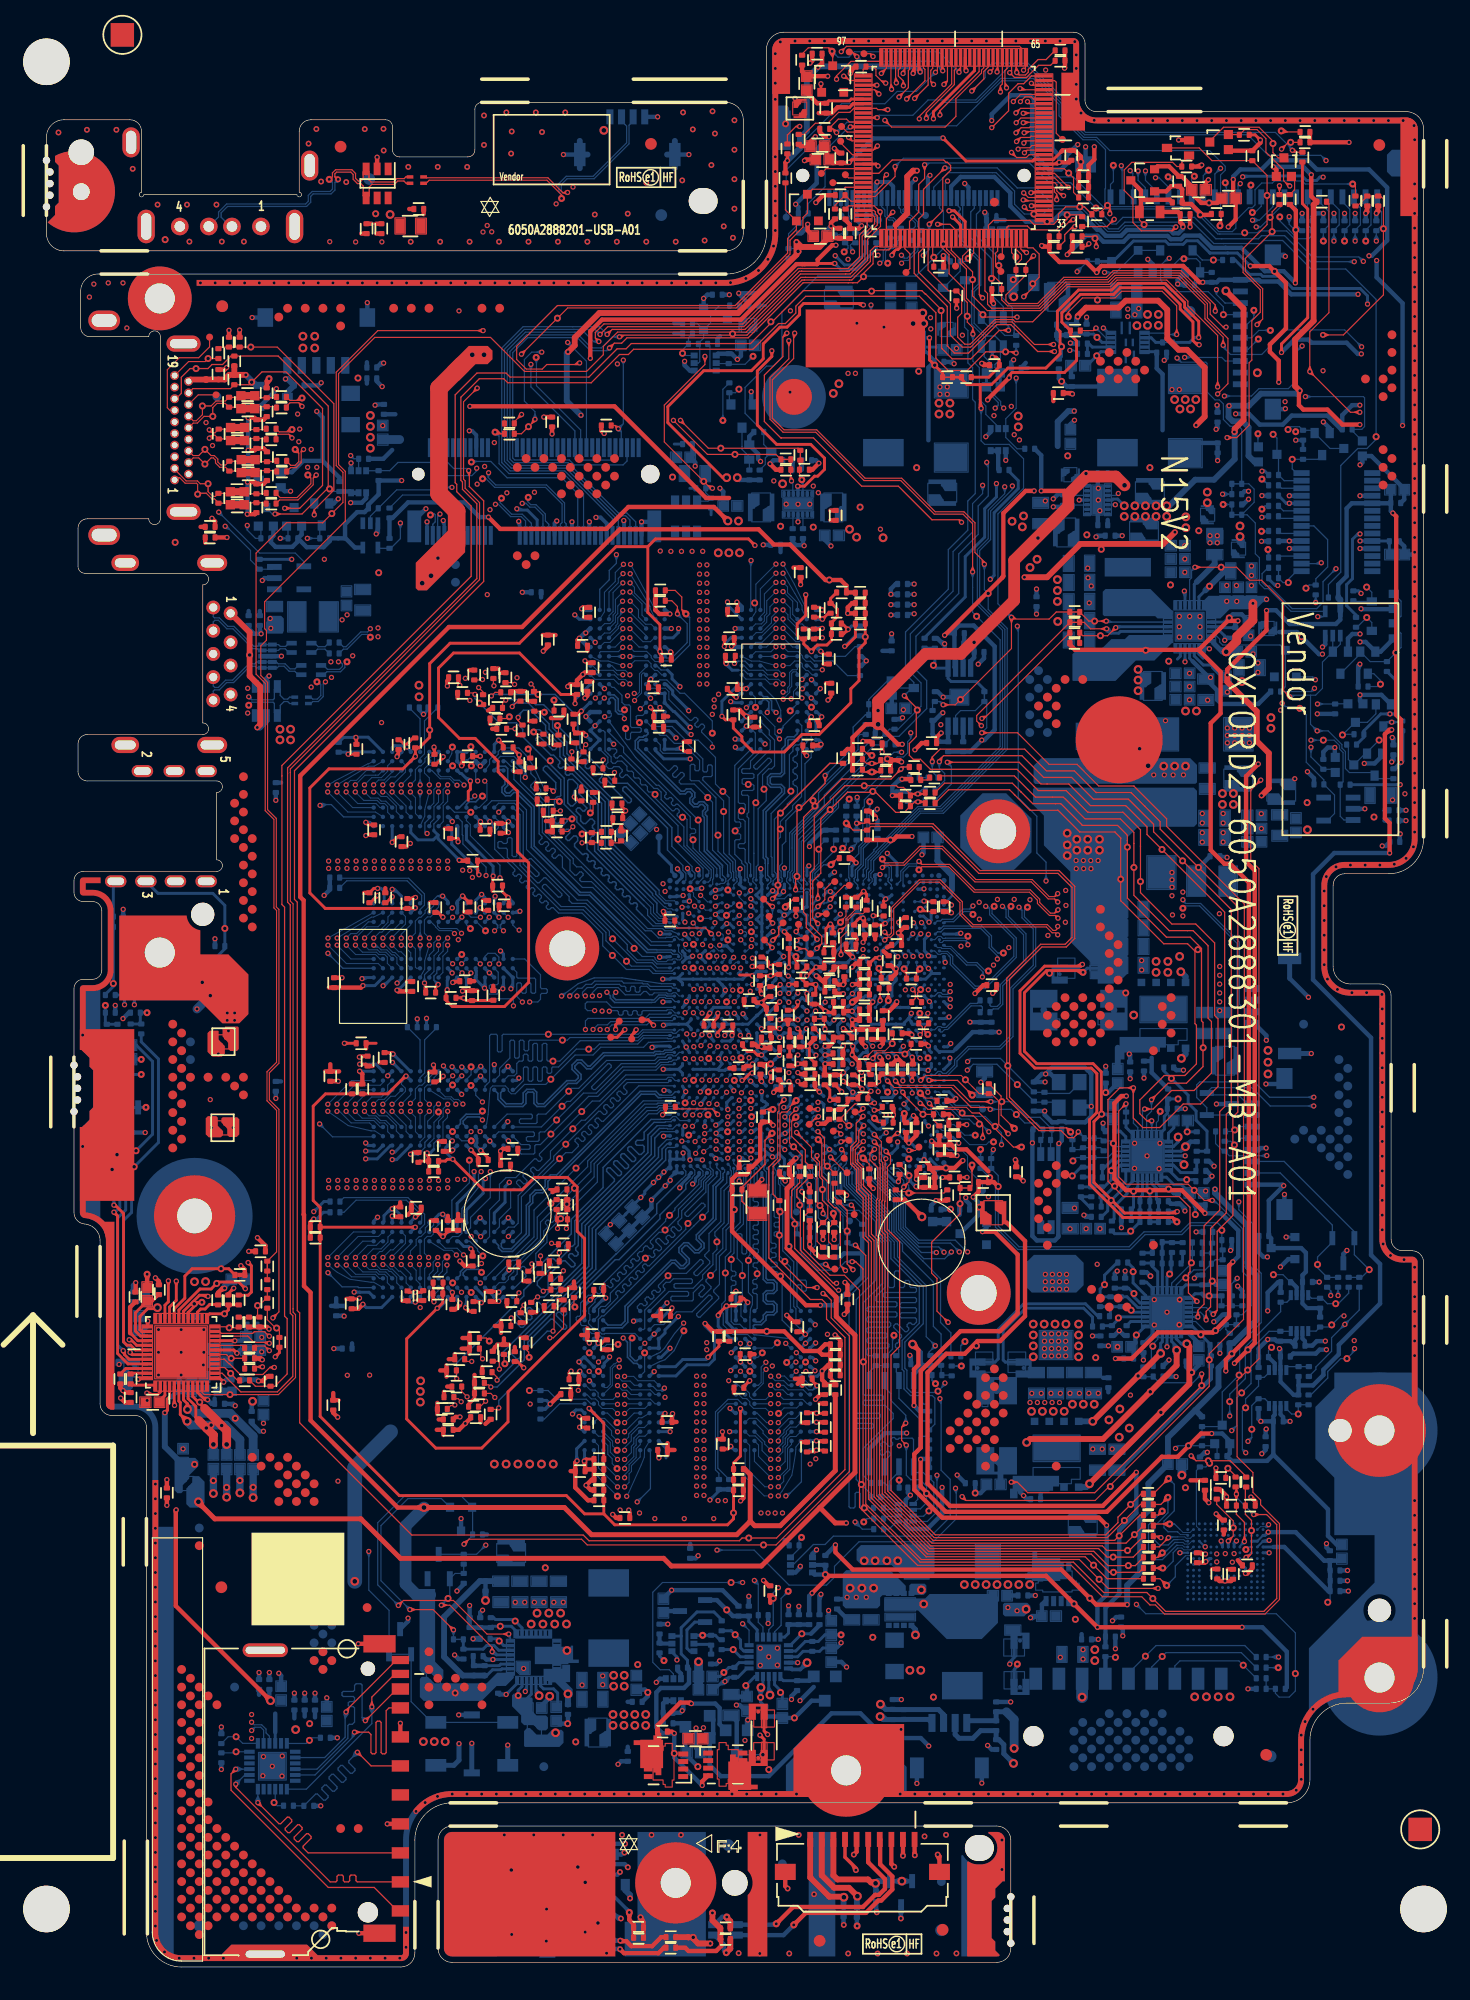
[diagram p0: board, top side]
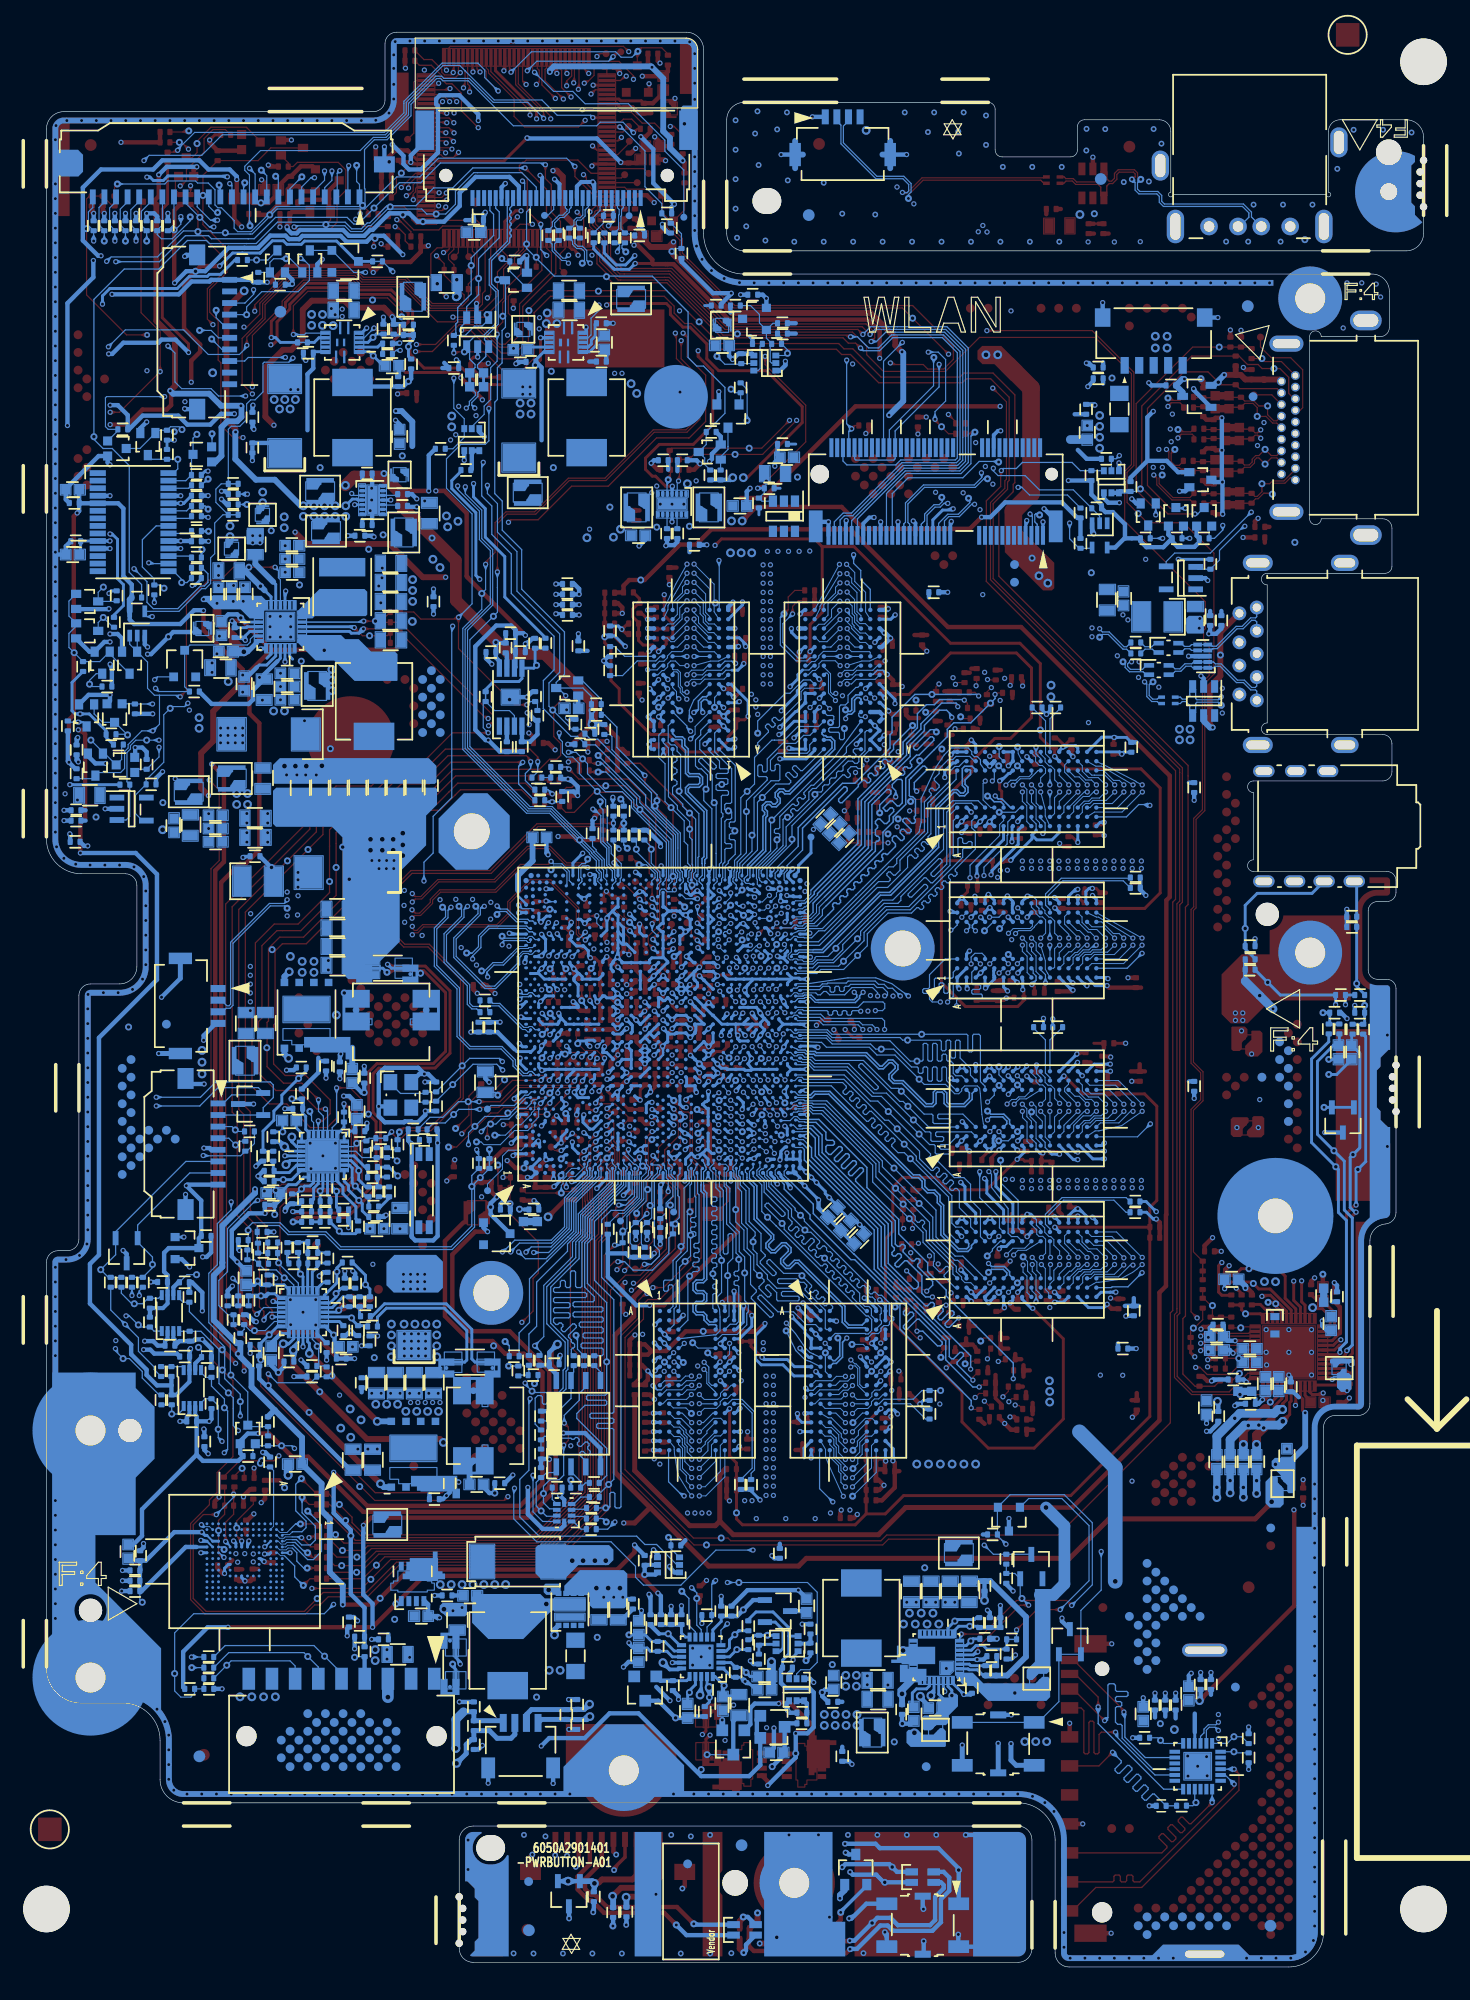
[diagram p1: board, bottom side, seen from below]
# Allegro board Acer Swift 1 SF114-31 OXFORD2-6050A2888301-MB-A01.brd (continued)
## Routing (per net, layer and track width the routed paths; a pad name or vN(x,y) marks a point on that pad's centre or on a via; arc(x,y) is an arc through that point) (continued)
HDMI_TX0_C_DN: length 2
  TOP w0.099: C3164.2 18.88,132.54 R3162.1 17.25,132.54 R3185.1
HDMI_TX0_C_DP: length 2
  TOP w0.099: C3165.2 18.88,131.77 R3161.1 17.25,131.77 R3184.1
HDMI_TX0_DN: length 109
  TOP w0.099: v3(21.18,132.54) 20.98,132.34 20.07,132.34 C3164.1
  L3 w0.099: v1(74.72,89.08) 75.29,89.65 76.3,89.65 76.56,89.9 76.56,94.11 77.47,95.03 77.47,101.1 78.99,102.62 78.99,104.44 78.61,104.82 78.61,110.94 75.52,114.03 75.52,119.22 74.83,119.91 73.94,119.91 71.27,122.58 71.27,124.12 66.03,129.37 63.27,129.37 62.44,130.2 61.3,130.2 61.06,129.96 51.55,129.96 49.52,127.92 45.7,127.92 42.74,124.96 42.74,123.24 40.88,121.38 27.48,121.38 20.32,128.55 20.32,132.04 20.64,132.36 21,132.36 v3(21.18,132.54)
  BOTTOM w0.099: U4500.G42 v1(74.72,89.08)
HDMI_TX0_DP: length 109
  TOP w0.099: v1(21.18,131.82) 21.18,131.86 20.9,132.14 19.96,132.14 19.8,131.99 C3165.1
  L3 w0.099: v1(21.18,131.82) 21.18,132 21.02,132.16 20.73,132.16 20.52,131.95 20.52,128.63 27.57,121.58 40.79,121.58 42.54,123.33 42.54,125.05 45.62,128.12 49.44,128.12 51.47,130.16 60.98,130.16 61.22,130.4 62.53,130.4 63.36,129.57 66.11,129.57 71.47,124.21 71.47,122.66 74.02,120.11 74.91,120.11 75.72,119.3 75.72,114.12 78.81,111.03 78.81,104.9 79.19,104.52 79.19,102.54 77.67,101.02 77.67,94.95 76.76,94.03 76.76,89.81 76.39,89.45 75.45,89.45 75.35,89.34 75.35,89.14 v1(75.41,89.08)
  BOTTOM w0.099: v1(75.41,89.08) 75.38,89.08 75.05,88.75 U4500.F42
HDMI_TX0_R_DN: length 5.6
  TOP w0.099: v1(14.04,132.52) 14.31,132.26 14.53,132.26 R3169.1 15.75,132.58 R3185.2
  L3 w0.099: CN3150.9 12.54,132.2 12.94,131.79 13.1,131.79 13.3,131.99 13.3,131.99 13.57,132.26 13.78,132.26 v1(14.04,132.52)
HDMI_TX0_R_DP: length 5.6
  TOP w0.099: v1(14.04,131.79) 14.31,132.06 14.53,132.06 R3169.2 15.75,131.73 R3184.2
  L3 w0.099: v1(14.04,131.79) 13.78,132.06 13.65,132.06 13.5,131.91 13.19,131.59 12.93,131.59 12.53,131.2 CN3150.7
HDMI_TX1_C_DN: length 2
  TOP w0.099: C3162.2 19.8,129.77 R3160.1 18.17,129.77 R3183.1
HDMI_TX1_C_DP: length 2
  TOP w0.099: R3182.1 18.17,129 R3159.1 19.8,129 C3163.2
HDMI_TX1_DN: length 110.6
  TOP w0.099: v3(21.45,130.83) 21.77,130.51 21.77,129.78 21.45,129.46 21.07,129.46 20.72,129.81 C3162.1
  L3 w0.099: v3(21.45,130.83) 21.5,130.83 21.77,130.56 21.77,128.14 27.85,122.06 40.6,122.06 42.06,123.53 42.06,125.24 45.42,128.6 49.24,128.6 51.27,130.64 60.71,130.64 60.96,130.88 62.72,130.88 63.54,130.07 66.86,130.07 72.72,124.21 72.72,122.99 76.2,119.5 76.2,114.34 79.32,111.22 79.32,105.08 79.68,104.72 79.68,102.24 78.15,100.72 78.15,94.72 77.26,93.83 77.26,89.54 76.29,88.56 74.59,88.56 73.71,87.68 73.71,87.38 v1(73.43,87.1)
  BOTTOM w0.099: U4500.K40 v1(73.43,87.1)
HDMI_TX1_DP: length 110.6
  TOP w0.099: C3163.1 21.05,129.26 21.53,129.26 21.97,129.69 21.97,130.62 v1(22.17,130.83)
  L3 w0.099: v1(22.17,130.83) 21.97,130.62 21.97,128.22 27.93,122.26 40.51,122.26 41.86,123.61 41.86,125.33 45.33,128.8 49.15,128.8 51.19,130.84 60.63,130.84 60.88,131.08 62.81,131.08 63.62,130.27 66.95,130.27 72.92,124.3 72.92,123.07 76.4,119.58 76.4,114.43 79.52,111.3 79.52,105.16 79.88,104.81 79.88,102.16 78.35,100.63 78.35,94.64 77.46,93.75 77.46,89.46 76.37,88.36 74.67,88.36 73.91,87.6 73.91,87.33 v1(74.09,87.15)
  BOTTOM w0.099: v1(74.09,87.15) U4500.J40
HDMI_TX1_R_DN: length 5.8
  TOP w0.099: R3183.2 16.66,129.81 R3168.1 15.45,129.49 15.04,129.49 14.78,129.75 14.78,130 14.47,130.3 14.2,130.3 v2(13.67,130.84) 13.13,130.3 12.66,130.3 CN3150.6
HDMI_TX1_R_DP: length 5.8
  TOP w0.099: CN3150.4 12.66,130.1 13.13,130.1 v2(13.67,129.57) 14.2,130.1 14.39,130.1 14.58,129.91 14.58,129.66 14.96,129.29 15.45,129.29 R3168.2 16.66,128.96 R3182.2
HDMI_TX2_C_DN: length 2
  TOP w0.099: R3181.1 17.23,127 R3158.1 18.88,127 C3160.2
HDMI_TX2_C_DP: length 2
  TOP w0.099: R3180.1 17.23,126.23 R3157.1 18.88,126.23 C3161.2
HDMI_TX2_DN: length 109.4
  TOP w0.099: C3160.1 19.8,127.03 20.16,126.68 21.62,126.68 22.81,127.87 22.81,128.36 v3(22.54,128.63)
  L3 w0.099: v3(22.54,128.63) 22.81,128.36 22.81,128.07 28.13,122.74 40.06,122.74 41.38,124.06 41.38,125.13 41.38,125.53 45.13,129.28 48.96,129.28 50.99,131.32 60.37,131.32 60.62,131.57 63,131.57 63.82,130.75 67.26,130.75 73.4,124.61 73.4,123.27 76.88,119.78 76.88,115.98 78.03,114.83 78.03,113.48 80.01,111.5 80.01,105.38 80.39,105 80.39,101.93 78.84,100.39 78.84,94.42 78.48,94.06 78.48,89.73 76.64,87.89 75.52,87.89 v1(74.75,87.12)
  BOTTOM w0.099: U4500.G40 74.75,87.2 v1(74.75,87.12)
HDMI_TX2_DP: length 109.4
  TOP w0.099: v1(23.27,128.63) 23.01,128.36 23.01,127.78 21.7,126.48 20.12,126.48 C3161.1
  L3 w0.099: v1(75.45,87.16) 75.45,87.54 75.6,87.69 76.73,87.69 78.68,89.65 78.68,93.98 79.04,94.34 79.04,100.3 80.59,101.85 80.59,105.08 80.21,105.46 80.21,111.58 78.23,113.56 78.23,114.92 77.08,116.06 77.08,119.87 73.6,123.35 73.6,124.69 67.34,130.95 63.9,130.95 63.09,131.77 60.54,131.77 60.29,131.52 50.91,131.52 48.87,129.48 45.05,129.48 41.18,125.61 41.18,125.05 41.18,124.14 39.98,122.94 28.21,122.94 23.01,128.15 23.01,128.36 v1(23.27,128.63)
  BOTTOM w0.099: v1(75.45,87.16) 75.45,87.23 75.08,87.6 U4500.F40
HDMI_TX2_R_DN: length 6.4
  TOP w0.099: R3181.2 15.72,127.05 R3167.1 14.56,126.78 14.35,126.78 13.94,127.18 v2(13.94,127.87) 13.27,127.87 13.02,128.11 12.05,128.11 11.06,129.11 CN3150.3
HDMI_TX2_R_DP: length 6.4
  TOP w0.099: CN3150.1 11.24,128.39 11.49,128.39 11.96,127.91 12.94,127.91 13.04,127.81 v2(13.04,126.97) 13.13,127.06 13.78,127.06 14.26,126.58 14.48,126.58 14.83,126.23 R3167.2 15.72,126.19 R3180.2
HDMI_TXC_C_DN: length 2
  TOP w0.099: C3166.2 19.77,135.28 R3163.1 18.14,135.28 R3187.1
HDMI_TXC_C_DP: length 2
  TOP w0.099: C3167.2 19.77,134.51 R3164.1 18.14,134.51 R3186.1
HDMI_TXC_R_DN: length 6
  TOP w0.099: CN3150.12 12.66,133.3 12.93,133.3 13.45,133.82 v2(13.45,134.58) 14.21,134.58 14.63,135 15.42,135 R3170.1 16.64,135.33 R3187.2
HDMI_TXC_R_DP: length 6
  TOP w0.099: R3186.2 16.64,134.47 R3170.2 15.42,134.8 14.71,134.8 14.35,134.44 v2(14.35,133.68) 13.59,133.68 13.01,133.1 12.66,133.1 CN3150.10
HDMI_TXCL_DN: length 110.7
  TOP w0.099: v3(22.04,135.26) 21.84,135.06 20.99,135.06 C3166.1
  L3 w0.099: v1(74.78,90.03) 74.78,90.04 75.03,90.29 75.03,90.45 74.67,90.8 74.67,92.84 75.11,93.27 75.11,93.66 76.73,95.28 76.73,101.32 78.3,102.9 78.3,104.06 77.93,104.44 77.93,110.66 74.12,114.47 74.12,118.69 70.59,122.22 70.59,123.84 65.76,128.67 60.68,128.67 60.29,129.06 57.53,129.06 55.71,127.24 46.01,127.24 43.45,124.68 43.45,122.99 41.16,120.7 26.41,120.7 19.63,127.48 19.63,134.04 20.67,135.08 21.86,135.08 v3(22.04,135.26)
  BOTTOM w0.099: v1(74.78,90.03) 75.05,89.76 U4500.F44
HDMI_TXCL_DP: length 110.7
  TOP w0.099: v1(22.04,134.54) 22.04,134.57 21.76,134.86 21.01,134.86 20.69,134.54 C3167.1
  L3 w0.099: v1(75.47,90.04) 75.23,90.29 75.23,90.53 74.87,90.89 74.87,92.75 75.31,93.19 75.31,93.57 76.93,95.2 76.93,101.24 78.5,102.81 78.5,104.15 78.13,104.53 78.13,110.74 74.32,114.55 74.32,118.77 70.79,122.31 70.79,123.93 65.85,128.87 60.77,128.87 60.37,129.26 57.45,129.26 55.63,127.44 45.93,127.44 43.25,124.76 43.25,123.08 41.08,120.9 26.49,120.9 19.83,127.56 19.83,133.96 20.75,134.88 21.85,134.88 22.04,134.68 v1(22.04,134.54)
  BOTTOM w0.099: U4500.D44 75.76,89.76 v1(75.47,90.04)
HP_L: length 32.3
  TOP w0.254: v1(6.62,53.14) 6.74,53.02 6.74,52.79 7.14,52.39 U500.32
  BOTTOM w0.254: R605.1 7.26,79.54 C602.2 7.75,79.47 7.75,79.47 9.15,78.07 9.15,71.79 v2(7.73,70.37) 6.83,69.47 6.83,65.26 6.14,64.57 6.14,53.61 v1(6.62,53.14)
HP_R: length 31.6
  TOP w0.254: v1(5.82,65.07) 6.13,64.76 6.13,52.89 7.04,51.99 U500.33
  BOTTOM w0.254: v1(5.82,65.07) 5.93,65.07 6.33,65.47 6.33,69.79 v2(6.09,70.03) 5.5,70.62 5.5,78.77 C603.2 6.19,80.34 R604.1
HPS: length 64.9
  TOP w0.254: v1(17.4,60.73) 17.68,60.45 17.68,58.18 17.4,57.91 16.6,57.91 R502.2
  L3 w0.254: JACK600.5 15.21,103.1 15.95,102.36 15.95,86.18 14.13,84.36 v1(14.13,74.78) 14.13,73.49 9.65,69.01 9.65,63.92 12.3,61.26 16.86,61.26 v1(17.4,60.73)
  L4 w0.254: v1(14.13,74.78) 10.15,74.78 9.48,74.11 v3(8.58,74.11)
  BOTTOM w0.254: v3(8.58,74.11) D600.2 D600.1
HW_I_ADC: length 217.2
  TOP w0.102: v1(72.39,162.41) 72.21,162.41 71.55,163.07 71.55,163.58 71.3,163.83 C6037.1 70.44,163.59 U301.97
  L4 w0.102: v1(61.06,33.32) 61.77,34.04 62.81,34.04 64.21,35.43 67.96,35.43 69.65,37.12 91.06,37.12 94.48,40.55 94.48,41.23 97.79,44.54 97.79,45.3 104.06,51.57 104.06,61.91 108.38,66.23 108.38,80.56 108.38,80.86 108.34,80.91 108.34,80.91 107.1,82.14 107.1,82.14 106.86,82.39 106.86,94.68 111.6,99.43 111.6,116.64 111.1,117.15 111.1,118.45 108.95,120.6 108.95,121.51 109.5,122.06 109.5,122.36 109.5,122.36 109.5,135.86 108.15,137.2 108.15,138.47 108.71,139.03 108.71,153.21 108.02,153.9 108.02,154.76 106.96,155.83 106.96,156.94 106.76,157.14 106.12,157.14 105.53,156.55 103.73,156.55 102.35,155.17 101.75,155.17 99.96,156.96 96.14,156.96 95.2,157.91 92.39,157.91 90.78,156.31 88.89,156.31 87.09,158.11 87.09,163.49 86.43,164.15 73.92,164.15 72.39,162.61 v1(72.39,162.41)
  BOTTOM w0.102: v1(61.06,33.32) 61.39,32.99 C6036.1 61.39,29.71 61.8,29.31 U6000.7
I2CO_SCL: length 4.7
  BOTTOM w0.109: R284.1 112.32,58.08 111.38,57.15 111.23,57.15 v2(111.2,57.18) 110.48,57.18 110.01,57.65 R4683.1 109.1,57.65 U4503.8
I2CO_SCL_TP: length 17.2
  BOTTOM w0.109: CN281.6 106.75,69.45 112.81,63.39 D280.2 112.81,61.4 v2(114.09,60.12) 113.43,59.45 R282.2 R284.2
I2CO_SDA: length 6.3
  L3 w0.135: v1(111.91,56.13) 111.38,56.66 111.38,57.87 v1(111.4,57.89)
  BOTTOM w0.109: U4503.1 109.5,54.82 R4684.1 110.67,55.17 v2(110.85,55.36) 111.63,56.13 v1(111.91,56.13) ; R283.1 v1(111.4,57.89)
I2CO_SDA_TP: length 15.1
  BOTTOM w0.109: R283.2 R281.2 109.63,60.28 v2(109.63,60.56) 109.63,61.21 110.91,62.49 D280.1 110.91,63.96 106.42,68.45 CN281.7
ICLKICOMP: length 4.4
  TOP w0.089: R4542.2 73.07,80.37 73.07,79.73 v2(72.95,79.61) 72.33,78.99 71.27,78.99 v1(70.64,78.36)
  BOTTOM w0.102: v1(70.64,78.36) 70.64,78.01 U4500.P20
ICLKRCOMP: length 4.8
  TOP w0.089: R4541.2 74.57,79.23 v2(74.04,78.7) 73.9,78.84 72.45,78.84 72.42,78.81 71.64,78.81 71.27,78.44 v1(71.27,78.33)
  BOTTOM w0.102: v1(71.27,78.33) 71.5,78.11 U4500.N20
IM_CLK_5: length 138.9
  TOP w0.109: v1(81.38,163.37) 81.64,163.64 U301.72 ; R309.1 90.27,149.2 v2(90.44,149.03) 90.55,148.92 v1(90.55,148.31)
  L3 w0.135: v1(81.38,163.37) 80.33,162.32 80.33,153.13 81.38,152.07 81.38,150.8 82.25,149.93 83.87,148.32 84.98,148.32 85.52,147.78 87.17,147.78 87.44,148.05 90.29,148.05 v1(90.55,148.31) 91.22,147.64 95.18,147.64 95.98,146.84 100.1,146.84 101.01,145.93 102.57,145.93 103.36,145.14 105.98,145.14 106.36,144.76 107.16,143.96 110.03,143.96 113.89,140.09 113.89,109.48 113.49,109.07 113.49,109.06 113.49,107.06 112.61,106.18 112.61,105.07 111.77,104.23 111.77,103.81 111.77,102.7 107.66,98.59 107.66,97.13 106.1,95.57 106.1,83.13 106.48,82.74 106.48,82.74 108.54,80.69 108.54,74.99 v1(109.3,74.23)
  BOTTOM w0.109: v1(109.3,74.23) 105.55,74.23 103.97,75.81 100.5,75.81 100.08,75.39 D281.2 100.24,75.18 102.79,75.18 103.52,74.45 CN281.1
IM_DAT_5: length 140.4
  TOP w0.109: v1(89.91,148.56) 89.66,148.31 R308.1 ; U301.71 82.04,163.43 v1(81.99,163.37)
  L3 w0.135: v1(81.99,163.37) 81.99,163.09 81.84,162.94 81.75,162.94 80.99,162.18 80.99,162.09 80.85,161.95 80.85,153.34 81.9,152.29 81.9,151.02 82.46,150.45 84.08,148.83 86.36,148.83 86.62,148.56 89.91,148.56 v1(89.91,148.56) 89.91,148.56 90.17,148.83 90.76,148.83 91.43,148.16 95.39,148.16 95.8,147.75 100,147.75 101.3,146.45 102.78,146.45 103.57,145.66 106.19,145.66 106.87,144.98 107.37,144.47 110.24,144.47 114.41,140.31 114.41,109.26 114,108.85 114,107.76 114,106.85 113.12,105.97 113.12,104.86 112.29,104.02 112.29,101.69 110.67,100.07 109.88,100.07 108.18,98.37 108.18,96.92 106.61,95.36 106.61,83.34 109.51,80.44 109.51,75.19 v1(109.31,74.98)
  BOTTOM w0.109: CN281.2 100.08,73.45 D281.1 100.08,74.08 99.21,74.95 99.21,76.05 99.46,76.3 104.17,76.3 105.49,74.98 v1(109.31,74.98)
INV_PWM_3: length 37.3
  BOTTOM w0.102: R3007.2 62,129.53 62,130.09 Q3007.3 61.87,131.26 C3008.1
  BOTTOM w0.109: CN3000.20 77.03,151.65 77.37,151.31 v2(77.37,148.54) 77.37,148.16 74.98,145.77 66.52,145.77 63.43,142.68 63.43,138.76 62.69,138.01 62.1,138.01 60.26,136.17 60.26,133.94 C3008.1
INV_PWM_APU_1V8: length 72.9
  L4 w0.102: v3(58.34,133.33) 58.86,132.81 65.89,132.81 70.35,128.35 70.71,128.35 82.65,128.35 v1(83.31,127.69)
  BOTTOM w0.102: v1(83.31,127.69) 83.31,127.39 81.43,125.51 81.43,123.06 80.49,122.12 80.49,117.49 82.66,115.32 82.66,105.05 77.27,99.66 75.31,99.66 71.75,96.1 71.75,96.03 71.12,95.4 71.12,94.56 70.91,94.36 70.91,93.73 U4500.P52 ; v3(58.34,133.33) 58.34,136.01 R3025.1
KBRST#: length 240.7
  TOP w0.102: v1(69.77,62.23) 70.66,61.34 70.66,39.92 75.46,35.13 89.08,35.13 v2(90.8,33.42) 91.58,32.64 v1(95.88,32.64) ; R4649.1 110.61,151.98 110.61,142.62 108.96,140.97 v1(108.96,137.54) 112.47,134.04 v1(113.28,134.04)
  TOP w0.109: v1(72.46,154.52) 72.21,154.27 72.21,153.77 71.48,153.03 U301.122
  L3 w0.135: v1(108.96,137.54) 108.96,138.4 106.98,140.38 105.74,140.38 105.25,139.9 103.97,139.9 103.52,140.35 102.74,140.35 102.18,140.92 100.71,140.92 98.26,143.36 96.95,143.36 96.21,144.1 85.87,144.1 85.01,144.96 83.01,144.96 73.45,154.52 v1(72.46,154.52)
  L4 w0.102: v1(95.88,32.64) 97.89,30.63 105.23,30.63 108.43,33.83 108.43,63.59 111.06,66.22 111.06,82.21 108.28,84.98 108.28,94.14 113.23,99.09 113.23,101.35 114.72,102.84 114.72,124.13 114.08,124.77 114.08,133.3 113.35,134.04 v1(113.28,134.04)
  BOTTOM w0.089: R4635.2 69.29,62.23 v1(69.77,62.23)
LCM_BKLTEN_1V8: length 97.9
  TOP w0.102: v1(68.15,162.74) 68.15,163.04 69.39,164.29 71.93,164.29 72.04,164.4 U301.96 ; v1(80.9,120.93) 80.9,121.13 80.08,121.94 80.08,124.51 79.14,125.45 76.66,125.45 73.77,128.35 70.6,128.35 66.44,132.52 63.62,132.52 62.61,133.53 62.61,136.83 64.44,138.67 64.44,140.77 v1(64.53,140.86)
  L4 w0.135: v1(64.53,140.86) 64.69,141.02 64.69,145.77 66.5,147.58 66.5,148.17 66.5,148.94 66.81,149.24 66.81,150.76 67.71,151.67 67.71,155.06 69.75,157.1 69.75,161.13 v1(68.15,162.74)
  BOTTOM w0.089: 71.1,94.28 71.1,93.94 71.22,93.82 71.22,93.59 70.94,93.3 U4500.P51
  BOTTOM w0.102: v1(80.9,120.93) 80.9,118.74 v2(81.23,118.41) 81.23,117.04 82.86,115.4 82.86,104.97 77.37,99.47 75.38,99.47 71.94,96.02 71.94,95.95 71.35,95.36 71.35,94.52 71.1,94.28
LCM_VDDEN: length 35.4
  TOP w0.102: v1(71.8,161.47) 71.44,161.84 U301.100
  L4 w0.102: v1(71.8,161.47) 72.97,160.3 72.97,157.14 68.78,152.95 68.78,149.71 67.57,148.5 67.57,146.83 65.8,145.07 65.8,139.86 64.8,138.86 v3(60.94,138.86)
  BOTTOM w0.102: Q3001.5 57.81,138.23 R3010.1 58.91,138.17 60.26,138.17 v3(60.94,138.86)
LCM_VDDEN_1V8: length 94.3
  TOP w0.102: v1(79.88,120.27) 79.88,124.43 79.06,125.25 76.58,125.25 73.68,128.15 70.52,128.15 66.35,132.31 63.54,132.31 62.4,133.44 62.4,137.01 64.03,138.64 v1(64.03,140.21)
  TOP w0.109: U301.98 69.27,162.63 68.89,163.01 v1(68.76,163.01)
  L4 w0.135: v1(68.76,163.01) 69.99,161.79 69.99,157 67.95,154.96 67.95,151.53 67.04,150.62 67.04,149.14 66.74,148.84 66.74,148.27 66.74,147.48 64.97,145.71 64.97,140.62 64.56,140.21 v1(64.03,140.21)
  BOTTOM w0.102: U4500.R53 70.45,94.6 70.66,94.81 70.66,95.48 71.37,96.19 71.37,96.31 71.68,96.62 R4520.2 72.4,97.29 75.15,100.04 77.07,100.04 82.26,105.22 82.26,114.41 v2(80.22,116.44) 79.88,116.79 79.88,118.92 v1(79.88,120.27)
LID_SW#_3: length 57
  TOP w0.102: U301.94 72.84,161.93 v1(72.89,161.87)
  L4 w0.102: v1(96.84,147.3) 97.26,147.73 100.22,147.73 102.34,149.84 102.34,150.29 99.52,153.11 98.77,153.11 96.49,155.4 94.71,155.4 94.38,155.73 91.56,155.73 91.24,155.4 88.65,155.4 86.28,157.77 86.28,160.2 84.38,162.11 84.08,162.41 79.69,162.41 79.06,161.77 72.99,161.77 v1(72.89,161.87)
  BOTTOM w0.102: v1(96.84,147.3) 96.7,147.3 96.1,146.7 96.1,145.4 97.07,144.43 100.2,144.43 101.51,143.12 v2(101.51,142.45) 101.87,142.45 101.87,142.45 CN245.4
LID_SW#_3_PB: length 30.6
  TOP w0.305: CN9100.4 68.87,9.47 69.82,8.52 v4(69.82,8.35)
  TOP w0.381: D9150.2 50.64,2.52 C9150.1 50.64,3.69 50.27,4.06 v3(50.27,4.7)
  L3 w0.305: v3(50.27,4.7) 50.45,4.7 50.69,4.94 52.76,4.94 53.27,4.44 55.09,4.44 56.64,5.99 58.16,5.99 58.61,5.54 60.45,5.54 60.73,5.82 64.34,5.82 66.37,7.85 69.32,7.85 v4(69.82,8.35)
  BOTTOM w0.305: U9150.2 48.02,7.01 50.17,4.87 50.17,4.81 v3(50.27,4.7)
LINE1_L: length 25.8
  TOP w0.254: v1(10.51,59.15) 10.51,57.35 10.22,57.05 U500.22
  L4 w0.254: v3(8.18,78.24) 8.68,77.73 8.68,76.74 6.81,74.86 6.81,63.44 10.51,59.74 v1(10.51,59.15)
  BOTTOM w0.254: v3(8.18,78.24) 8.15,78.27 8.14,78.27 C602.1
LINE1_R: length 27.9
  TOP w0.254: v1(11.2,59.13) 11.2,57.47 10.62,56.89 U500.21
  L4 w0.254: v3(8.18,76.95) 6.3,75.07 6.3,63.23 9.95,59.58 9.95,59.03 10.01,58.98 10.01,58.94 10.3,58.64 10.72,58.64 11.02,58.94 11.02,58.95 v1(11.2,59.13)
  BOTTOM w0.254: C603.1 6.19,78.24 7.49,76.95 v3(8.18,76.95)
LINE1_REF_L: length 31.1
  TOP w0.254: U500.31 7.4,52.79 v1(7.21,52.98)
  BOTTOM w0.254: R606.1 8.18,79.76 9.66,78.28 9.66,71.08 v2(7.57,68.99) 7.34,68.76 7.34,65.05 6.65,64.36 6.65,53.88 7.21,53.32 v1(7.21,52.98)
LINE1_REF_R: length 29.7
  TOP w0.254: U500.30 7.68,53.19 7.26,53.61 6.94,53.61 6.65,53.9 6.65,64.96 5.93,65.68 v1(5.82,65.68)
  BOTTOM w0.254: v1(5.82,65.68) 5.82,68.6 v2(5.66,68.75) 4.99,69.43 4.99,80.21 R607.1
LPC_3S_AD<0>: length 255.8
  TOP w0.109: v1(48.36,140.74) 48.79,141.18 60.25,141.18 65.03,145.96 68.93,145.96 69.33,145.96 70.59,147.23 70.59,149.12 71.66,150.18 71.66,150.97 71.49,151.14 71.49,151.31 71.36,151.43 U301.126
  L3 w0.135: v3(104.83,128.27) 106.56,126.54 106.56,121.7 105.59,120.72 105.59,119.05 106.18,118.46 106.18,111.04 103.49,108.36 103.05,108.36 102.75,108.36 100.61,106.21 100.61,102.36 98.8,100.56 98.8,96.51 100.73,94.58 100.73,81.54 102.41,79.87 102.41,63.44 100.75,61.78 90.67,61.78 89.87,60.98 83.94,60.98 83.28,61.65 v1(79.45,61.65)
  L4 w0.135: v1(48.36,140.74) 47.94,141.16 47.57,141.16 46.96,140.55 46.96,139.48 50.81,135.63 59.3,135.63 59.94,135 65.32,135 68.66,138.34 68.66,142.2 70.65,144.19 77.95,144.19 78.88,145.12 81.29,145.12 81.59,144.82 86.95,144.82 89.45,147.33 91.41,147.33 95.07,143.67 96.22,143.67 98.41,141.47 98.41,139.44 100.75,137.1 100.83,137.1 101.35,137.1 105.44,133.01 105.44,128.88 v3(104.83,128.27)
  BOTTOM w0.109: CN1300.65 48.82,124.85 44.7,128.98 39.99,128.98 39.27,129.7 39.27,132.08 39.27,139.57 41.11,141.41 45.39,141.41 45.39,141.41 46.18,141.41 46.18,141.41 47.69,141.41 v1(48.36,140.74) ; R3506.1 104.88,128.27 v3(104.83,128.27) ; v1(79.45,61.65) 79.4,61.65 78.38,62.66 75.24,62.66 74.09,63.81 74.09,66.32 72.11,68.3 72.11,68.62 72.19,68.7 72.19,68.71 72.2,68.72 72.2,68.98 72.1,69.08 72.1,69.36 U4500.M3
LPC_3S_AD<1>: length 251.6
  TOP w0.109: U301.127 71.25,151.04 71.42,150.86 71.42,150.28 70.36,149.22 70.36,147.32 69.23,146.19 69.03,146.19 65.13,146.19 65.13,146.19 64.94,146.19 60.16,141.41 48.42,141.41 v1(47.75,140.74)
  L3 w0.135: v1(78.74,61.65) 79.16,62.07 83.22,62.07 84.05,61.24 89.73,61.24 90.56,62.07 100.67,62.07 102.15,63.55 102.15,79.76 100.47,81.43 100.47,94.48 98.54,96.41 98.54,96.62 98.54,100.68 100.34,102.48 100.34,106.32 102.64,108.62 103.16,108.62 103.16,108.62 103.38,108.62 105.91,111.15 105.91,118.35 105.33,118.94 105.33,120.83 106.3,121.81 106.3,124.21 v3(104.83,125.68)
  L4 w0.135: v3(104.83,125.68) 105.06,125.68 105.7,126.32 105.7,133.12 101.46,137.37 100.86,137.37 98.67,139.55 98.67,141.58 96.32,143.93 95.2,143.93 91.53,147.59 89.56,147.59 89.35,147.59 86.84,145.08 81.7,145.08 81.4,145.38 78.77,145.38 77.85,144.45 70.54,144.45 68.4,142.31 68.4,138.45 66.22,136.26 50.55,136.26 47.22,139.59 47.22,140.31 47.66,140.74 v1(47.75,140.74)
  BOTTOM w0.109: v1(78.74,61.65) 77.98,62.41 75.21,62.41 73.89,63.73 73.89,66.24 71.91,68.22 71.91,68.67 71.91,68.68 U4500.M2 ; R3505.1 105.11,125.96 v3(104.83,125.68) ; v1(47.75,140.74) 47.32,141.17 46.08,141.17 41.21,141.17 39.51,139.47 39.51,129.8 40.09,129.21 44.8,129.21 49.32,124.69 CN1300.67
LPC_3S_AD<2>: length 251.4
  TOP w0.109: v1(47.65,140.13) 47.34,140.44 47.34,140.91 48.08,141.65 60.06,141.65 64.84,146.43 65.03,146.43 65.23,146.43 65.23,146.43 69.13,146.43 70.12,147.42 70.12,149.32 70.79,149.99 70.79,150.52 70.68,150.63 U301.128
  L3 w0.135: v1(77.42,61.62) 78.43,62.64 83.4,62.64 84.27,61.76 89.46,61.76 90.33,62.64 100.49,62.64 101.62,63.77 101.62,79.54 99.95,81.22 99.95,81.65 99.95,94.26 98.02,96.19 98.02,96.84 98.02,100.89 99.82,102.7 99.82,106.54 102.42,109.14 103.16,109.14 105.39,111.37 105.39,114.27 104.8,114.85 104.8,121.05 105.78,122.02 105.78,122.79 v3(104.8,123.77)
  L4 w0.135: v1(47.65,140.13) 47.73,140.05 49.77,140.05 53.03,136.79 66,136.79 67.88,138.66 67.88,142.53 70.35,145 77.66,145 78.63,145.97 82.7,145.97 82.9,145.77 86.78,145.77 88.46,147.45 88.46,147.73 89.73,148.99 91.12,148.99 95.66,144.45 96.54,144.45 99.97,141.02 99.97,139.2 101.27,137.89 101.67,137.89 106.23,133.34 106.23,125.2 v3(104.8,123.77)
  BOTTOM w0.109: v1(77.42,61.62) 76.96,62.08 75.26,62.08 73.69,63.64 73.69,66.16 71.7,68.14 71.7,68.63 71.61,68.72 71.61,69.02 U4500.N3 ; v1(47.65,140.13) 47.19,140.13 46.38,140.94 45.98,140.94 41.31,140.94 39.74,139.37 39.74,131.87 39.74,129.9 40.19,129.45 44.9,129.45 49.24,125.11 49.96,125.11 50.33,124.75 CN1300.71 ; v3(104.8,123.77) 105.39,123.77 R3504.1
LPC_3S_AD<3>: length 247.5
  TOP w0.109: v1(49.43,140.54) 49.57,140.69 60.42,140.69 65.17,145.43 65.36,145.43 69.27,145.43 69.27,145.43 69.46,145.43 71.06,147.03 71.06,147.95 71.45,148.34 71.88,148.34 72.04,148.5 U301.1
  L3 w0.135: v3(105.36,122.2) 104.54,121.38 104.54,114.73 105.1,114.17 105.1,111.45 103.05,109.4 102.31,109.4 99.56,106.65 99.56,102.81 97.76,101.01 97.76,96.95 97.76,96.08 99.69,94.15 99.69,81.76 99.69,81.11 101.36,79.43 101.36,69.29 101.36,63.87 100.43,62.94 90.26,62.94 89.35,62.03 84.38,62.03 83.46,62.94 78.1,62.94 v1(76.76,61.59)
  L4 w0.135: v1(49.43,140.54) 49.65,140.54 53.14,137.05 65.89,137.05 67.62,138.77 67.62,142.64 70.24,145.26 77.55,145.26 78.52,146.24 83.64,146.24 83.83,146.05 85.84,146.05 88.6,148.81 89.18,148.81 89.63,149.26 91.22,149.26 94.87,145.61 95.75,145.61 100.23,141.13 100.23,139.31 101.38,138.15 101.78,138.15 106.49,133.44 106.49,123.33 v3(105.36,122.2)
  BOTTOM w0.109: v1(76.76,61.59) 75.46,61.59 73.49,63.56 73.49,66.07 71.42,68.15 U4500.N1 ; v1(49.43,140.54) 48.82,140.54 47.86,139.58 47,139.58 45.88,140.7 45.69,140.7 41.41,140.7 39.98,139.27 39.98,129.99 40.29,129.69 44.99,129.69 49.33,125.35 50.06,125.35 50.82,124.58 CN1300.73 ; v3(105.36,122.2) 105.41,122.14 R3503.1
LPC_3S_FRAME#: length 247.9
  TOP w0.109: U301.3 72.84,148.21 72.78,148.15 72.78,148.15 72.66,148.03 71.57,148.03 71.29,147.75 71.29,146.84 70.47,146.01 v2(70.47,145.72) 69.94,145.2 69.56,145.2 65.27,145.2 60.52,140.45 50.07,140.45 49.61,139.99 48.98,139.99 v1(48.56,139.57)
  L3 w0.135: v1(104.83,124.98) 106.04,123.76 106.04,121.92 105.06,120.94 105.06,118.83 105.65,118.25 105.65,111.26 103.27,108.88 102.53,108.88 100.08,106.43 100.08,102.59 98.28,100.79 98.28,96.73 98.28,96.3 100.21,94.37 100.21,81.54 100.21,81.32 101.89,79.65 101.89,63.66 100.56,62.33 90.39,62.33 89.56,61.5 84.16,61.5 83.33,62.33 78.74,62.33 v1(78.05,61.65)
  L4 w0.135: v1(48.56,139.57) 49.48,139.57 52.52,136.52 66.11,136.52 68.14,138.56 68.14,142.42 70.46,144.74 77.76,144.74 78.74,145.71 81.44,145.71 81.78,145.36 86.75,145.36 89.24,147.85 89.67,147.85 89.67,147.85 91.81,147.85 95.47,144.19 96.43,144.19 98.96,141.66 98.96,140.3 98.98,140.28 98.98,139.61 100.96,137.63 101.56,137.63 105.96,133.23 105.96,125.93 105.01,124.98 v1(104.83,124.98)
  BOTTOM w0.109: v1(104.83,124.98) 104.92,125.07 R3507.1 ; CN1300.70 50.08,129.84 49.74,129.5 45.52,129.5 45.09,129.92 40.38,129.92 40.21,130.09 40.21,139.18 41.5,140.47 45.78,140.47 46.91,139.34 48.33,139.34 v1(48.56,139.57) ; U4500.P3 70.96,69.52 70.96,69.24 71.23,68.97 71.23,68.72 71.22,68.71 71.22,68.7 71.14,68.62 71.14,68.15 73.3,65.99 73.3,63.43 73.81,62.92 75.66,61.06 77.47,61.06 v1(78.05,61.65)
LPC_HVT_RCOMP: length 1.8
  TOP w0.102: v3(70.43,69.75) 70.96,69.21 R4574.1
  BOTTOM w0.089: U4500.T4 70.37,69.75 v3(70.43,69.75)
M_A_A<0>: length 113.3
  TOP w0.102: R4126.2 43.78,109.21 v3(43.77,109.22)
  L3 w0.102: v1(29.08,94.71) 29.08,94.79 28.68,95.18 28.68,96.38 31.92,99.62 32.69,99.62 34.21,101.14 34.21,102.12 34.39,102.3 34.92,102.3 35.51,102.9 37.58,102.9 38.09,103.4 38.09,104.27 38.23,104.42 38.37,104.42 38.55,104.24 38.69,104.24 41.56,107.1 41.56,107.38 41.86,107.68 42,107.68 42.47,107.2 42.62,107.2 42.76,107.35 42.76,107.49 42.29,107.96 42.29,108.11 43.4,109.22 v3(43.77,109.22) 43.77,109.97 43.95,110.15 44.07,110.15 44.29,109.93 44.42,109.93 44.57,110.08 44.57,110.23 44.36,110.44 44.36,110.56 44.83,111.03 45.87,111.03 45.93,110.97 46.38,110.97 46.72,111.32 46.72,111.63 46.88,111.79 47.11,111.79 47.21,111.89 47.21,112.25 47.31,112.34 47.51,112.34 47.62,112.24 47.62,111.89 47.72,111.79 47.92,111.79 48.02,111.89 48.02,112.25 48.12,112.34 48.32,112.34 48.43,112.24 48.43,111.89 48.53,111.79 48.73,111.79 48.84,111.89 48.84,112.25 48.93,112.34 49.14,112.34 49.24,112.24 49.24,111.89 49.34,111.79 50.53,111.79 50.96,112.21 50.96,113.16 51.15,113.35 51.29,113.35 51.71,112.94 51.85,112.94 52,113.08 52,113.22 51.58,113.64 51.58,113.78 51.72,113.93 51.87,113.93 52.28,113.51 52.43,113.51 52.57,113.65 52.57,113.8 52.15,114.21 52.15,114.36 52.55,114.75 52.79,114.75 52.89,114.65 52.89,114.12 53,114.02 53.2,114.02 53.3,114.12 53.3,114.65 53.4,114.75 53.61,114.75 53.71,114.65 53.71,114.12 53.81,114.02 54.01,114.02 54.13,114.14 54.13,114.59 54.27,114.73 54.79,114.73 56.2,116.14 v1(56.33,116.14)
  L4 w0.089: v1(29.02,88.09) 28.63,88.48 28.63,89.07 28.96,89.4 28.96,94.59 v1(29.08,94.71) 29.08,94.8 28.69,95.18 28.69,95.53 28.95,95.79 28.95,98.48 29.14,98.67 29.14,99.84 29.01,99.98 v1(29.01,101.3) ; v1(49.7,116.17) 49.98,116.45 49.98,116.46 50.07,116.55 50.67,116.55 50.97,116.25 55.83,116.25 55.95,116.14 v1(56.33,116.14) 56.41,116.14 56.8,116.52 57.15,116.52 57.39,116.28 60.12,116.28 60.33,116.07 62.79,116.07 v1(62.92,116.21) ; 56.62,95.7 56.65,95.67 56.65,94.19 55.93,93.46 55.93,92.23 56.09,92.07 56.09,91.87 v1(56.54,91.42)
  L4 w0.152: v3(43.77,109.22) 45.21,107.78 45.21,105.6 45.75,105.07 45.75,104.63 49.53,100.85 51.48,100.85 56.62,95.7
  BOTTOM w0.089: v1(29.01,101.3) 29.26,101.3 30.61,99.95 U4103.N3 ; v1(56.54,91.42) 56.54,91.41 56.84,91.11 U4500.BB47 ; v1(29.02,88.09) 29.24,88.09 29.87,87.47 30.06,87.47 U4102.N3 ; v1(62.92,116.21) 62.92,115.95 61.99,115.02 61.57,114.6 U4100.N3 ; v1(49.7,116.17) 49.7,115.94 49.32,115.56 49.32,115.39 U4101.N3
M_A_A<1>: length 112.7
  TOP w0.102: R4127.2 40.4,106.74 v1(40.41,106.75)
  L3 w0.102: v1(56.96,116.93) 57.07,116.82 57.07,116.64 56.96,116.53 56.17,116.53 55.93,116.3 55.93,116.21 55.51,115.79 55.37,115.79 55.18,115.97 55.04,115.97 54.9,115.83 54.9,115.69 55.08,115.5 55.08,115.36 54.7,114.98 53.73,114.98 53.46,115.25 53.46,115.5 53.35,115.6 53.14,115.6 53.04,115.51 53.04,115.11 52.92,115 52.45,115 50.71,113.26 50.71,112.82 50.48,112.59 49.4,112.59 49.29,112.69 49.29,112.75 49.19,112.85 48.99,112.85 48.89,112.75 48.89,112.69 48.79,112.59 48.58,112.59 48.48,112.69 48.48,112.75 48.38,112.85 48.18,112.85 48.08,112.75 48.08,112.69 47.97,112.59 47.77,112.59 47.67,112.69 47.67,112.75 47.57,112.85 47.36,112.85 47.1,112.59 47,112.59 46.46,112.04 45.48,112.04 43.53,110.09 43.53,109.69 40.59,106.75 v1(40.41,106.75) 40.53,106.63 40.53,106.46 40.24,106.17 40.1,106.17 39.86,106.41 39.71,106.41 39.57,106.27 39.57,106.13 39.81,105.89 39.81,105.74 38.86,104.79 38.45,104.79 38.35,104.89 38.35,105.62 38.26,105.71 38.05,105.71 37.94,105.6 37.94,104.89 37.84,104.79 37.25,104.79 36.64,104.18 36.5,104.18 36.16,104.51 36.02,104.51 35.88,104.37 35.88,104.22 36.24,103.87 36.24,103.26 36.12,103.14 34.89,103.14 34.66,102.91 34.52,102.91 34.24,103.19 34.1,103.19 33.95,103.04 33.95,102.9 34.23,102.62 34.23,102.48 34.05,102.3 33.65,102.3 33.42,102.07 33.42,101.14 33.19,100.91 32.86,100.91 32.51,100.55 32.51,100.41 32.73,100.19 32.73,100.05 32.58,99.9 32.44,99.9 32.22,100.12 32.08,100.12 28.13,96.18 28.13,95.5 v1(28.29,95.34)
  L4 w0.089: v1(28.23,88.7) 28.17,88.76 28.17,94 28.67,94.5 28.67,94.91 28.29,95.3 v1(28.29,95.34) 28.29,95.53 28.6,95.84 28.6,98.77 28.82,98.99 28.82,99.77 28.6,99.98 28.6,101.52 v1(28.22,101.91) ; v1(63.53,117) 63.14,116.61 62.06,116.61 61.83,116.38 61.05,116.38 60.81,116.61 57.46,116.61 57.14,116.93 v1(56.96,116.93) 56.92,116.93 56.53,116.54 55.82,116.54 55.32,117.04 51.68,117.04 51.56,116.92 50.39,116.92 v1(50.36,116.96) ; v1(56.59,88.14) 56.44,88.14 56.02,88.56 54.97,88.56 54.66,88.87 54.66,89.56 54.5,89.72 54.5,90.3 53.59,91.2 53.59,91.33 52.93,91.99
  L4 w0.152: 52.93,91.99 52.93,92.84 52.7,93.08 52.7,93.91 47.55,99.06 46.71,99.06 45.1,100.68 45.1,101.47 42.78,103.78 42.78,104.38 v1(40.41,106.75)
  BOTTOM w0.089: v1(28.22,101.91) 28.64,102.33 29.14,102.33 29.82,103.02 U4103.P7 ; U4100.P7 63.95,116.21 63.95,116.57 v1(63.53,117) ; U4102.P7 28.93,89.21 28.75,89.21 28.23,88.7 v1(28.23,88.7) ; v1(56.59,88.14) 56.59,88.35 U4500.BC42 ; U4101.P7 50.36,116.75 v1(50.36,116.96)
M_A_A<2>: length 106.8
  TOP w0.102: R4129.2 40.64,109.13 v1(40.17,108.66)
  L3 w0.102: v1(27.5,94.71) 27.5,94.79 27.1,95.18 27.1,96.49 31,100.38 31,102.07 34.5,105.58 35.96,105.58 38.96,108.58 40.1,108.58 v1(40.17,108.66) 40.63,108.66 45.01,113.04 45.01,113.18 44.87,113.32 44.87,113.47 45.01,113.61 45.15,113.61 45.3,113.47 45.44,113.47 45.6,113.63 45.6,113.78 45.46,113.92 45.46,114.06 45.6,114.21 45.75,114.21 45.89,114.06 46.05,114.06 46.6,114.61 49.07,114.61 49.44,114.98 51.14,114.98 51.69,115.53 51.73,115.53 53.49,117.29 55.45,117.29 55.88,117.72 v1(56.33,117.72)
  L4 w0.089: v1(49.69,117.75) 50.08,118.13 50.51,118.13 50.78,117.86 56.06,117.86 56.21,117.72 v1(56.33,117.72) 56.39,117.72 56.77,118.1 57.12,118.1 57.16,118.07 60.66,118.07 61.06,117.67 62.81,117.67 v1(62.92,117.79) ; v1(27.43,101.3) 27.54,101.19 27.54,99.22 27.16,98.84 27.16,95.56 27.11,95.51 27.11,95.16 27.5,94.77 v1(27.5,94.71) 27.5,94.59 27.17,94.26 27.17,89 27.05,88.88 27.05,88.48 27.44,88.09 v1(27.44,88.09)
  BOTTOM w0.089: U4102.P3 29.82,86.94 29.28,87.48 28.75,87.48 28.55,87.69 27.81,87.69 27.44,88.06 v1(27.44,88.09) ; U4103.P3 29.27,100.5 28.87,100.5 28.6,100.78 27.95,100.78 v1(27.43,101.3) ; U4101.P3 49.07,115.94 49.07,116.47 49.28,116.67 49.28,117.33 v1(49.69,117.75) ; U4100.P3 62.12,115.94 62.12,116.39 62.4,116.66 62.4,117.26 v1(62.92,117.79)
  BOTTOM w0.124: U4500.BJ48 53.66,91.69 53.36,91.69 52.55,92.5 52.55,92.69 48.49,96.75 48.49,100.58 44.59,104.48 44.59,105.48 43.35,106.71 43.35,107.17 41.56,108.96 40.32,108.96 40.17,108.82 v1(40.17,108.66)
M_A_A<3>: length 107
  TOP w0.102: v1(40.68,107.73) 40.68,107.45 R4128.2
  L3 w0.102: v1(56.33,116.93) 56.17,116.77 56.07,116.77 55.54,116.25 54.3,116.25 54.21,116.16 54.21,116 54.1,115.9 53.9,115.9 53.8,115.99 53.8,116.13 53.7,116.23 53.34,116.23 52.35,115.24 52.35,115.24 50.49,113.37 49.51,113.37 49.24,113.1 46.07,113.1 40.69,107.73 v1(40.68,107.73) 39.16,106.2 38.31,106.2 38.06,105.95 37.95,105.95 36.8,104.8 35.96,104.8 35.21,104.04 34.56,104.04 32.63,102.11 32.63,101.1 27.89,96.36 27.89,95.18 28.29,94.79 v1(28.29,94.71)
  L4 w0.089: v1(49.71,116.96) 50.1,117.35 55.8,117.35 56.22,116.93 v1(56.33,116.93) 56.41,116.93 56.8,117.31 57.43,117.31 57.86,116.89 62.81,116.89 v1(62.92,117) ; v1(28.22,101.3) 28.29,101.22 28.29,96.21 27.9,95.82 27.9,95.18 28.29,94.79 v1(28.29,94.71) 28.29,94.6 27.83,94.15 27.83,88.49 v1(28.23,88.09)
  BOTTOM w0.089: U4500.BH47 54.04,91.13 53.94,91.23 53.57,91.23 53.4,91.39 53.3,91.39 52.27,92.42 ; U4103.N2 30.62,99.15 30.17,99.6 30.17,100.1 29.36,100.91 28.85,100.91 28.46,101.3 v1(28.22,101.3) ; v1(49.71,116.96) 49.71,116.75 49.28,116.33 49.28,115.81 49.12,115.65 49.12,115.51 48.6,115 48.13,115 U4101.N2 ; U4102.N2 30.23,86.49 30.23,87 29.97,87.26 29.79,87.26 29.36,87.69 28.86,87.69 28.45,88.09 v1(28.23,88.09) ; U4100.N2 61.22,115.04 61.7,115.04 62.53,115.87 62.53,116.37 62.92,116.75 v1(62.92,117)
  BOTTOM w0.124: 52.27,92.42 52.27,92.54 48.18,96.63 48.18,100.45 44.29,104.35 44.29,105.35 43.05,106.59 43.05,107.04 41.75,108.35 41.13,108.35 40.68,107.9 v1(40.68,107.73)
M_A_A<4>: length 119.6
  TOP w0.102: v3(39.93,107.78) 39.78,107.63 R4130.2
  L3 w0.102: v1(56.96,117.72) 56.89,117.72 56.49,117.32 55.93,117.32 55.65,117.05 53.59,117.05 51.83,115.29 51.81,115.29 50.68,114.17 49.43,114.17 49.23,113.97 49.23,113.48 49.12,113.36 48.69,113.36 48.6,113.46 48.6,114.28 48.5,114.37 48.3,114.37 48.19,114.26 48.19,113.47 48.08,113.36 47.88,113.36 47.78,113.46 47.78,113.69 47.67,113.81 47.45,113.81 47.38,113.73 47.38,113.47 47.27,113.36 47.02,113.36 46.92,113.46 46.92,114.13 46.83,114.21 46.63,114.21 46.51,114.09 46.51,113.47 46.4,113.36 45.69,113.36 40.11,107.78 v3(39.93,107.78) 39.39,108.32 39.11,108.32 38.97,108.18 38.97,108.05 39.71,107.31 39.71,107.14 39.56,107 39.42,107 38.69,107.72 38.55,107.72 38.41,107.58 38.41,107.44 38.82,107.02 38.82,106.89 38.68,106.75 38.52,106.75 38.12,107.15 37.98,107.15 37.82,106.99 37.82,106.85 38.15,106.53 38.15,106.38 38,106.24 37.86,106.24 37.53,106.56 37.33,106.56 35.51,104.75 34.01,104.75 33.66,104.4 33.66,104.25 33.86,104.05 33.86,103.91 33.65,103.69 33.5,103.69 33.3,103.89 33.16,103.89 32.99,103.72 32.99,102.94 32.35,102.3 32.07,102.3 31.84,102.07 31.84,100.89 27.5,96.54 v1(27.5,95.34)
  L4 w0.089: v1(63.53,117.79) 63.13,117.38 62.76,117.38 62.65,117.27 58.19,117.27 57.75,117.72 v1(56.96,117.72) 56.91,117.72 56.53,117.33 56.11,117.33 55.88,117.56 51.42,117.56 51.33,117.64 51.11,117.64 51.03,117.56 50.54,117.56 v1(50.35,117.75) ; v1(55.69,89.07) 55.65,89.07 55.1,89.62 54.99,89.62 54.69,89.92 54.69,90.38 54.05,91.01 54.05,91.6 53.76,91.89 53.76,93.35 53.27,93.84 ; v1(27.44,88.7) 27.44,94.05 27.88,94.49 27.88,94.91 27.5,95.29 v1(27.5,95.34) 27.5,96.13 27.94,96.57 27.94,101.03 27.83,101.14 27.83,101.51 v1(27.43,101.91)
  L4 w0.152: 53.27,93.84 53.24,93.84 43.11,103.97 43.11,104.66 39.99,107.78 v3(39.93,107.78)
  BOTTOM w0.089: U4100.P8 65.3,115.67 65.3,115.67 65.18,115.78 64.7,115.78 64.15,116.33 64.15,117.16 v1(63.53,117.79) ; U4101.P8 52.52,115.39 52.15,115.76 51.67,115.76 51.06,116.37 51.06,117.03 50.35,117.74 v1(50.35,117.75) ; U4102.P8 29.45,90.53 29.45,90.06 28.84,89.44 28.18,89.44 v1(27.44,88.7) ; v1(27.43,101.91) 28.05,102.54 28.88,102.54 29.43,103.08 29.43,103.56 29.82,103.95 U4103.P8 ; v1(55.69,89.07) 55.69,89.03 U4500.BD42
M_A_A<5>: length 116.2
  TOP w0.102: R4131.2 39.33,108.94 v1(39.61,109.22)
  L3 w0.102: v1(26.71,94.71) 26.71,94.79 26.31,95.18 26.31,95.68 26.47,95.83 26.47,98.19 29.42,101.14 29.42,102.26 30.72,103.56 30.72,103.86 32.68,105.82 32.89,105.85 34.09,105.85 34.3,106.06 35.76,106.06 38.76,109.06 38.76,109.06 38.83,109.13 39.53,109.13 v1(39.61,109.22) 46.95,116.56 47.77,116.56 47.88,116.66 47.88,116.99 47.98,117.1 48.18,117.1 48.28,116.99 48.28,116.66 48.38,116.56 48.59,116.56 48.69,116.66 48.69,116.99 48.79,117.1 48.99,117.1 49.1,116.99 49.1,116.66 49.2,116.56 52.05,116.56 53.27,117.77 55.25,117.77 55.99,118.51 v1(56.33,118.51)
  L4 w0.089: v1(26.64,101.3) 26.74,101.2 26.74,95.92 26.3,95.49 26.3,95.2 26.71,94.8 v1(26.71,94.71) 26.71,89.39 26.25,88.94 26.25,88.49 v1(26.65,88.09) ; v1(62.92,118.58) 62.82,118.48 57.54,118.48 57.12,118.89 56.8,118.89 56.41,118.51 v1(56.33,118.51) 51.01,118.51 50.59,118.92 50.1,118.92 v1(49.72,118.54)
  BOTTOM w0.089: 52.84,92.83 52.84,92.5 53.42,91.92 54.17,91.92 U4500.BH48 ; U4101.P2 48.14,115.81 48.62,115.81 48.87,116.07 48.87,116.56 49.07,116.76 49.07,117.89 v1(49.72,118.54) ; U4103.P2 29.82,99.15 29.43,99.54 29.43,100.04 29.17,100.3 28.79,100.3 28.52,100.57 27.37,100.57 v1(26.64,101.3) ; U4102.P2 29.4,86.52 29.4,87.06 29.18,87.28 28.67,87.28 28.47,87.48 27.26,87.48 v1(26.65,88.09) ; v1(62.92,118.58) 62.12,117.78 62.12,116.68 61.92,116.47 61.92,116.05 61.66,115.78 61.16,115.78 U4100.P2
  BOTTOM w0.124: 52.84,92.83 48.79,96.88 48.79,100.7 44.89,104.6 44.89,105.6 43.66,106.84 43.66,108.05 42.88,108.82 42.19,108.82 41.74,109.27 39.66,109.27 v1(39.61,109.22)
M_A_A<6>: length 119.8
  TOP w0.102: R4133.2 38.55,110.5 v1(38.59,110.45)
  L3 w0.102: v1(25.13,95.34) 25.66,98.47 27.03,101.14 27.03,102.08 30.84,105.89 31.65,105.89 32.28,106.53 33.98,106.77 33.99,106.77 34.13,106.8 36.23,107.81 36.51,107.94 37.35,108.79 38.18,110.04 v1(38.59,110.45) 46.56,118.41 49.39,118.93 50.49,118.93 56.15,119.69 56.49,119.69 56.89,120.09 v1(56.96,120.09)
  L4 w0.089: 53.73,95.25 54.04,94.94 54.04,94.51 54.52,94.02 54.52,92.21 55.24,91.5 55.3,91.5 v3(56.42,90.38) ; v1(50.35,120.11) 51.5,120.11 51.92,119.7 56.49,119.7 v1(56.96,120.09) 57.41,120.09 57.73,119.77 63.26,119.77 63.53,120.04 v1(63.53,120.16) ; v1(25.06,101.91) 25.45,101.52 25.45,100.32 v1(25.13,95.34) 25.13,95.3 25.51,94.91 25.51,94.55 v1(25.07,88.7)
  L4 w0.152: v1(38.59,110.45) 39.84,110.45 40.48,109.82 43.27,108.55 44.51,107.31 44.51,104.46 53.73,95.25
  BOTTOM w0.089: v1(25.07,88.7) 28.04,90.51 28.21,90.51 U4102.R8 ; v1(25.06,101.91) 27.78,103.52 28.27,103.52 U4103.R8 ; U4100.R8 65.17,117.01 65.17,117.35 64.55,118.41 v1(63.53,120.16) ; U4500.BB46 56.43,90.4 v3(56.42,90.38) ; v1(50.35,120.11) 52.06,117.3 52.06,117.13 U4101.R8
M_A_A<7>: length 127.9
  TOP w0.102: v1(37.61,110.99) 37.57,110.96 R4132.2
  L3 w0.102: v1(56.33,120.88) 54.53,120.88 54.43,120.98 54.43,121.21 54.33,121.31 54.13,121.31 54.02,121.2 54.02,120.98 53.92,120.88 51.15,120.88 50.67,121.35 48.25,121.35 37.89,110.99 v1(37.61,110.99) 36.33,110.15 33.74,107.57 32.3,107.57 29.57,106.58 24.98,102.41 24.66,102.09 24.66,101.15 24.1,99.79 23.94,95.4 23.94,95.18 v1(24.34,94.71)
  L4 w0.089: 53.26,94.75 53.65,94.36 53.65,94.34 54.14,93.85 54.14,92.06 54.43,91.77 54.43,91.2 54.79,90.84 v1(55.4,90.84) ; v1(49.76,120.92) 49.76,121.1 49.97,121.31 55.89,121.31 v1(56.33,120.88) 56.72,121.26 57.64,121.26 58.12,120.79 62.77,120.79 v1(62.92,120.95) ; v1(24.28,88.09) 23.88,88.49 23.88,91.76 24.39,92.27 24.39,94.66 v1(24.34,94.71) 23.95,95.1 23.95,99.67 24.44,100.16 24.44,101.11 v1(24.25,101.3)
  L4 w0.152: 53.26,94.75 43.77,104.24 43.77,105.94 39.7,110.01 38.43,110.01 37.61,110.83 v1(37.61,110.99)
  BOTTOM w0.089: U4500.BE46 v1(55.4,90.84) ; U4100.R2 61.02,116.58 61.19,116.84 61.19,119.21 v1(62.92,120.95) ; v1(24.25,101.3) 24.27,101.3 26,99.57 28.38,99.57 U4103.R2 ; U4101.R2 48.12,116.83 48.12,118.51 49.06,119.45 49.06,120.22 v1(49.76,120.92) ; v1(24.28,88.09) 25.87,86.51 28.62,86.51 U4102.R2
M_A_A<8>: length 124.2
  TOP w0.102: R4134.2 37.66,109.92 v1(37.28,110.3)
  L3 w0.102: v1(56.96,120.88) 56.49,120.48 56.17,120.48 56.13,120.52 49.57,120.52 49.46,120.41 46.6,119.37 37.54,110.3 v1(37.28,110.3) 37.27,110.29 36.98,110.29 36.97,110.29 36.79,110.11 36.42,109.73 36.26,109.73 35.9,109.37 35.9,109.22 36.34,108.78 36.34,108.65 36.2,108.5 36.05,108.5 35.61,108.94 35.47,108.94 33.86,107.32 32.34,107.32 32.27,107.3 31.35,106.38 29.75,106.38 25.45,102.08 25.45,100.68 24.34,99.57 v1(24.34,95.34)
  L4 w0.089: v1(24.28,88.7) 24.28,89.53 24.72,89.98 24.72,94.87 24.34,95.26 v1(24.34,95.34) 24.15,95.53 24.15,98.65 24.64,99.14 24.64,101.54 v1(24.27,101.91) ; v1(63.53,120.95) 63.14,120.56 58.06,120.56 57.59,121.03 57.12,121.03 v1(56.96,120.88) 56.88,120.88 56.49,120.49 56.17,120.49 55.64,121.02 50.47,121.02 v1(50.38,120.92) ; v1(55.78,90.01) 55.64,90.14 55.56,90.14 55.23,90.47 54.87,90.47 54.24,91.09 54.24,91.68 53.95,91.97 53.95,93.59 53.33,94.22
  L4 w0.152: v1(37.28,110.3) 37.28,110.06 39.12,108.21 41.03,108.21 43.44,105.8 43.44,104.11 52.52,95.03 53.33,94.22
  BOTTOM w0.089: U4100.T8 64.5,119.22 63.92,120.26 63.76,120.54 v1(63.53,120.95) ; v1(50.38,120.92) 51.75,118.41 U4101.T8 ; v1(24.28,88.7) 24.83,89.01 24.84,89.01 U4102.T8 ; U4103.T8 27.78,103.72 27.72,103.72 24.83,102.23 24.77,102.17 v1(24.27,101.91) ; U4500.BD44 55.96,89.75 55.96,89.82 v1(55.78,90.01)
M_A_A<9>: length 115.4
  TOP w0.102: v1(38.37,109.57) 38.37,109.57 38.69,109.89 R4135.2
  L3 w0.102: v1(25.92,94.71) 25.92,94.79 25.52,95.18 25.52,95.76 25.98,96.22 25.98,98.39 27.82,100.23 27.82,102.53 30.94,105.65 31.83,105.65 32.46,106.29 34.1,106.54 34.22,106.58 36.65,107.74 37.78,108.87 38.37,109.57 v1(38.37,109.57) 38.37,109.57 44.4,115.6 45.29,115.6 46.79,117.1 46.79,117.36 47.58,118.14 52.92,118.14 53.04,118.26 55.05,118.26 56.09,119.3 v1(56.33,119.3)
  L4 w0.089: v1(25.86,88.09) 25.46,88.49 25.46,88.87 25.92,89.32 v1(25.92,94.71) 25.92,94.8 25.53,95.19 25.53,96.26 25.93,96.67 25.93,101.21 v1(25.85,101.3) ; v1(49.72,119.32) 50.1,119.71 50.64,119.71 51.05,119.3 v1(56.33,119.3) 56.42,119.3 56.8,119.69 57.12,119.69 57.13,119.68 57.56,119.25 62.81,119.25 v1(62.92,119.37)
  BOTTOM w0.089: v1(25.86,88.09) 25.86,88.09 26.67,87.28 28.38,87.28 28.76,86.9 U4102.R3 ; v1(62.92,119.37) 61.92,118.37 61.92,116.77 61.57,116.42 U4100.R3 ; v1(49.72,119.32) 49.7,119.32 48.87,118.5 48.87,116.85 48.52,116.49 U4101.R3 ; v1(25.85,101.3) 26.85,100.3 28.42,100.3 28.77,99.95 28.77,99.95 U4103.R3
  BOTTOM w0.102: 53.94,96.61 55.68,94.87 55.68,94.54 55.93,94.3 55.93,93.88 U4500.BE52
  BOTTOM w0.124: 53.94,96.61 53.94,98.23 50.12,102.05 49.06,102.05 46.01,105.09 46.01,106.24 45.84,106.42 45.84,107.74 43.87,109.71 v2(42.4,109.71) 38.51,109.71 38.38,109.57 v1(38.37,109.57)
M_A_A<10>: length 92.5
  TOP w0.102: R4138.2 45.87,100.53 v1(45.53,100.88)
  L3 w0.102: v1(32.23,95.34) 32.39,95.5 32.39,95.61 34.88,98.1 38.22,98.1 39.7,99.58 39.7,99.73 39.38,100.05 39.38,100.2 39.52,100.34 39.66,100.34 40.02,99.98 40.16,99.98 40.3,100.13 40.3,100.28 39.95,100.63 39.95,100.77 40.09,100.91 40.24,100.91 40.56,100.59 40.71,100.59 41,100.88 v1(45.53,100.88) 45.81,100.88 49.22,104.29 50.21,104.29 54.23,108.3 54.23,110.55 55.94,112.26 55.94,112.47 56.06,112.59 56.57,112.59 v1(56.96,112.98)
  L4 w0.089: v1(63.53,112.98) 63.53,112.83 63.29,112.59 62.76,112.59 62.38,112.97 56.97,112.97 v1(56.96,112.98) 56.92,112.98 56.53,112.59 51.8,112.59 51.42,112.97 50.33,112.97 v1(50.32,112.98) ; v1(32.23,101.91) 32.37,101.91 32.62,101.66 32.62,98.06 32.43,97.87 32.43,95.48 v1(32.23,95.34) 32.23,95.28 32.64,94.87 32.64,94.53 32.42,94.31 32.42,88.89 v1(32.23,88.7)
  BOTTOM w0.089: U4101.L7 50.33,112.99 v1(50.32,112.98) ; v1(63.53,112.98) 63.54,112.99 U4100.L7 ; U4500.BJ45 53.68,90.12 53.47,90.12 53.41,90.18 52.77,90.18 52.12,90.82 52.12,91.37 51.54,91.94 ; v1(32.23,101.91) 32.22,101.92 U4103.L7 ; U4102.L7 32.23,90.09 v1(32.23,88.7)
  BOTTOM w0.124: v1(45.53,100.88) 45.53,101.4 45.82,101.7 45.82,101.95 45.39,102.38 45.06,102.38 44.96,102.28 44.96,100.36 45.22,100.1 45.39,100.1 45.82,100.53 46,100.53 46.6,99.93 46.6,99.88 46.42,99.7 46.42,99.65 46.27,99.65 46,99.93 45.83,99.93 45.7,99.8 45.7,99.61 46.07,99.24 46.07,98.82 46.31,98.58 46.5,98.58 46.89,98.97 47.07,98.97 47.27,98.76 47.27,98.58 47.09,98.4 47.09,98.22 47.28,98.04 47.28,97.61 47.15,97.48 47.05,97.48 46.93,97.36 46.93,97.18 47.05,97.06 47.15,97.06 47.28,96.93 47.28,96.21 51.54,91.94
M_A_A<11>: length 115.4
  TOP w0.102: R4137.2 42.05,110.35 v1(41.79,110.61)
  L3 w0.102: v1(26.71,95.34) 26.71,97.29 27.69,98.28 27.72,98.28 30.2,100.77 30.2,102.1 32.21,104.11 32.21,104.55 33.24,105.57 34.16,105.57 34.4,105.82 35.86,105.82 38.86,108.82 39.78,108.82 41.38,110.42 41.6,110.42 v1(41.79,110.61) 41.71,110.69 41.71,110.97 46.51,115.77 47.06,115.77 47.16,115.87 47.16,116.19 47.26,116.3 47.46,116.3 47.57,116.19 47.57,115.28 47.66,115.18 47.87,115.18 47.97,115.29 47.97,116.19 48.07,116.3 48.28,116.3 48.38,116.19 48.38,115.28 48.48,115.18 48.68,115.18 48.78,115.29 48.78,116.19 48.89,116.3 49.09,116.3 49.19,116.19 49.19,115.87 49.29,115.77 51.63,115.77 53.39,117.53 55.35,117.53 55.93,118.11 56.49,118.11 56.89,118.51 v1(56.96,118.51)
  L4 w0.089: v1(50.33,118.54) 50.56,118.54 50.99,118.1 56.49,118.1 56.89,118.51 v1(56.96,118.51) 57.13,118.51 57.36,118.27 60.87,118.27 61.13,118.01 62.07,118.01 62.24,118.19 63.14,118.19 v1(63.53,118.58) ; v1(26.65,88.7) 26.65,88.92 26.94,89.2 26.94,94.32 27.09,94.48 27.09,94.87 26.71,95.26 v1(26.71,95.34) 26.71,95.51 26.94,95.74 26.94,99.57 27.18,99.81 27.18,100.75 27.03,100.91 27.03,101.52 v1(26.64,101.91) ; v1(56.42,92.38) 56.42,92.43 56.12,92.74 56.12,93.29 56.84,94.02 56.84,96.03 56.68,96.19
  L4 w0.152: v1(41.79,110.61) 43.01,110.61 45.54,108.08 45.54,105.74 46.08,105.2 46.08,104.77 49.67,101.18 51.69,101.18 56.68,96.19
  BOTTOM w0.089: v1(56.42,92.38) 56.46,92.38 57.02,91.82 U4500.BB49 ; U4102.R7 29.02,90.1 28.6,89.68 27.62,89.68 v1(26.65,88.7) ; v1(26.64,101.91) 27.47,102.75 28.38,102.75 28.38,102.75 28.62,102.75 U4103.R7 ; v1(50.33,118.54) 50.38,118.48 50.4,118.48 51.37,117.52 51.37,116.55 U4101.R7 ; v1(63.53,118.58) 64.36,117.74 64.36,116.6 U4100.R7
M_A_A<12>: length 110.3
  TOP w0.102: v3(42.94,108.17) 42.85,108.26 42.63,108.26 42.62,108.26 R4136.2
  L3 w0.102: v1(29.08,95.34) 29.08,95.65 29.3,95.87 29.3,96.02 29.05,96.26 29.05,96.41 29.2,96.55 29.34,96.55 29.59,96.3 29.81,96.3 30.25,96.74 30.25,97.61 32.02,99.38 32.79,99.38 34.01,100.6 34.46,100.6 34.74,100.88 34.88,100.88 35.14,100.62 35.28,100.62 35.42,100.76 35.42,100.91 35.22,101.12 35.22,101.52 35.02,101.72 35.02,102.06 35.61,102.66 37.71,102.66 37.94,102.89 38.09,102.89 38.31,102.67 38.46,102.67 38.6,102.81 38.6,102.95 38.37,103.18 38.37,103.58 40.95,106.15 41.09,106.15 41.38,105.87 41.52,105.87 41.66,106.01 41.66,106.15 41.38,106.44 41.38,106.58 41.89,107.09 42.03,107.09 42.35,106.77 42.53,106.77 43.21,107.45 43.21,107.64 42.89,107.95 42.89,108.1 42.94,108.15 v3(42.94,108.17) 43.82,108.17 44.18,108.53 44.18,108.68 44.07,108.79 44.07,108.93 44.21,109.08 44.36,109.08 44.47,108.96 44.61,108.96 44.76,109.11 44.76,109.25 44.54,109.47 44.54,109.61 44.68,109.76 44.82,109.76 45.04,109.54 45.19,109.54 45.4,109.75 45.4,110.66 45.53,110.79 45.71,110.79 45.81,110.69 45.81,110.15 45.91,110.04 46.1,110.04 46.22,110.16 46.22,110.59 46.32,110.69 47.04,110.69 47.16,110.81 47.16,111.47 47.26,111.57 47.47,111.57 47.57,111.47 47.57,110.63 47.67,110.53 47.87,110.53 47.98,110.63 47.98,111.47 48.08,111.57 48.29,111.57 48.39,111.47 48.39,110.63 48.5,110.53 48.7,110.53 48.8,110.63 48.8,111.47 48.9,111.57 49.11,111.57 49.21,111.47 49.21,111.1 49.31,111 50.49,111 50.71,111.23 50.71,111.36 52.21,112.85 52.99,112.85 53.43,113.29 53.43,113.54 53.67,113.78 54.2,113.78 56.16,115.74 56.49,115.74 56.89,116.14 v1(56.96,116.14)
  L4 w0.089: 53.43,95.08 53.83,94.68 53.83,94.43 54.33,93.93 54.33,92.14 54.82,91.65 v1(54.82,91.36) ; v1(29.01,101.91) 29.23,101.91 29.39,101.75 29.39,97.69 29.15,97.45 29.15,95.43 29.08,95.35 v1(29.08,95.34) 29.08,95.26 29.46,94.87 29.46,94 29.21,93.74 29.21,89.11 29.02,88.92 v1(29.02,88.7) ; v1(50.33,116.17) 50.44,116.05 55.32,116.05 55.62,115.75 56.51,115.75 56.9,116.14 v1(56.96,116.14) 56.97,116.14 57.05,116.06 59.56,116.06 59.8,115.82 63.38,115.82 63.53,115.97 v1(63.53,116.21)
  L4 w0.152: v3(42.94,108.17) 42.94,107.49 44.14,106.29 44.14,104.37 53.43,95.08
  BOTTOM w0.089: U4103.N7 30.07,102.6 29.7,102.6 v1(29.01,101.91) ; U4101.N7 51.72,114.77 v1(50.33,116.17) ; U4102.N7 29.88,89.35 29.67,89.35 v1(29.02,88.7) ; v1(63.53,116.21) 63.53,115.95 64.77,114.71 U4100.N7 ; v1(54.82,91.36) 54.85,91.39 U4500.BF48
M_A_A<13>: length 120.8
  TOP w0.102: v1(36.96,109.71) 36.83,109.84 R4139.2
  L3 w0.102: v1(25.13,94.71) 25.13,94.79 24.73,95.18 24.73,99.26 26.24,100.78 26.24,102.07 26.47,102.3 26.48,102.3 30.32,106.14 31.55,106.14 32.5,107.08 33.96,107.08 34.9,108.02 35.02,108.02 35.19,107.86 35.33,107.86 35.47,108 35.47,108.15 35.31,108.31 35.31,108.43 35.48,108.6 35.6,108.6 36.05,108.16 36.38,108.16 37.03,108.81 37.03,109.64 v1(36.96,109.71) 37.15,109.91 37.49,109.91 46.71,119.12 48.96,119.12 49.55,119.72 49.9,119.72 49.9,119.72 50.51,119.72 50.88,120.09 v1(56.33,120.09)
  L4 w0.089: v1(62.92,120.16) 62.8,120.04 57.93,120.04 57.49,120.48 56.8,120.48 56.42,120.09 v1(56.33,120.09) 55.4,120.09 54.96,120.52 50.13,120.52 v1(49.73,120.12) ; v1(25.07,88.09) 24.68,88.48 24.68,89.26 24.93,89.51 24.93,94.51 v1(25.13,94.71) 25.13,94.8 24.74,95.19 24.74,98.95 25.17,99.38 25.17,101.19 v1(25.06,101.3)
  BOTTOM w0.089: v1(25.07,88.09) 26.26,86.9 U4102.T3 ; U4103.T3 26.41,99.95 26.41,99.95 v1(25.06,101.3) ; v1(62.92,120.16) 61.57,118.81 U4100.T3 ; U4101.T3 48.52,118.53 49.32,119.33 49.32,119.71 v1(49.73,120.12)
  BOTTOM w0.102: 51.53,91.48 51.85,91.15 51.85,90.67 52.56,89.95 53.35,89.95 53.56,89.74 53.95,89.74 54.04,89.83 54.28,89.83 54.53,89.58 U4500.BF44
  BOTTOM w0.124: 51.53,91.48 46.63,96.38 46.63,97.84 45.74,98.72 45.74,99.15 44.66,100.23 44.66,102.48 42.24,104.9 41.08,106.06 41.08,106.7 40.52,107.26 39.05,107.26 v2(37.35,108.96) 36.96,109.35 v1(36.96,109.71)
M_A_A<14>: length 113.5
  TOP w0.102: R4140.2 40.22,110.73 v1(40.38,110.58)
  L3 w0.102: v1(25.92,95.34) 25.92,95.82 26.22,96.12 26.22,98.29 28.61,100.68 28.61,101.7 28.61,101.7 28.61,102.07 28.84,102.3 28.85,102.3 30.48,103.93 30.48,103.96 32.56,106.04 34.2,106.3 36.92,107.56 39.93,110.58 v1(40.38,110.58) 40.39,110.59 40.63,110.59 41.28,111.24 41.28,111.39 41.01,111.65 41.01,111.79 41.16,111.93 41.31,111.93 41.57,111.67 41.71,111.67 41.85,111.82 41.85,111.96 41.61,112.2 41.61,112.35 41.75,112.49 41.9,112.49 42.14,112.25 42.29,112.25 42.43,112.39 42.43,112.54 42.19,112.77 42.19,112.92 42.34,113.06 42.48,113.06 42.72,112.82 42.86,112.82 47.39,117.35 52.49,117.35 53.16,118.01 55.15,118.01 56.04,118.9 56.49,118.9 56.89,119.3 v1(56.96,119.3)
  L4 w0.089: 54.79,95.28 54.9,95.17 54.9,92.99 55.88,92.01 55.88,91.47 v1(55.89,91.46) ; v1(63.53,119.37) 63.14,118.98 59.35,118.98 59.17,118.79 57.62,118.79 57.12,119.3 v1(56.96,119.3) 56.88,119.3 56.49,118.91 50.9,118.91 50.65,119.16 50.5,119.16 v1(50.33,119.32) ; v1(25.85,101.91) 26.24,101.52 26.24,98.79 26.44,98.58 26.44,96.36 25.92,95.84 v1(25.92,95.34) 25.92,95.26 26.3,94.87 26.3,89.28 25.86,88.83 v1(25.86,88.7)
  L4 w0.152: v1(40.38,110.58) 40.8,110.15 42.17,110.15 44.88,107.44 44.88,104.56 49.33,100.11 50.13,100.11 51.32,98.92 51.32,98.75 53.42,96.65 53.76,96.31 54.79,95.28
  BOTTOM w0.089: U4500.BD47 56.29,91.07 v1(55.89,91.46) ; U4102.T7 27.76,90.1 26.75,89.09 26.25,89.09 v1(25.86,88.7) ; U4100.T7 64.77,117.62 63.92,118.48 63.92,118.98 v1(63.53,119.37) ; v1(25.85,101.91) 26.24,102.3 26.74,102.3 27.59,103.15 U4103.T7 ; v1(50.33,119.32) 50.72,118.94 50.72,118.45 51.72,117.45 51.72,116.99 U4101.T7
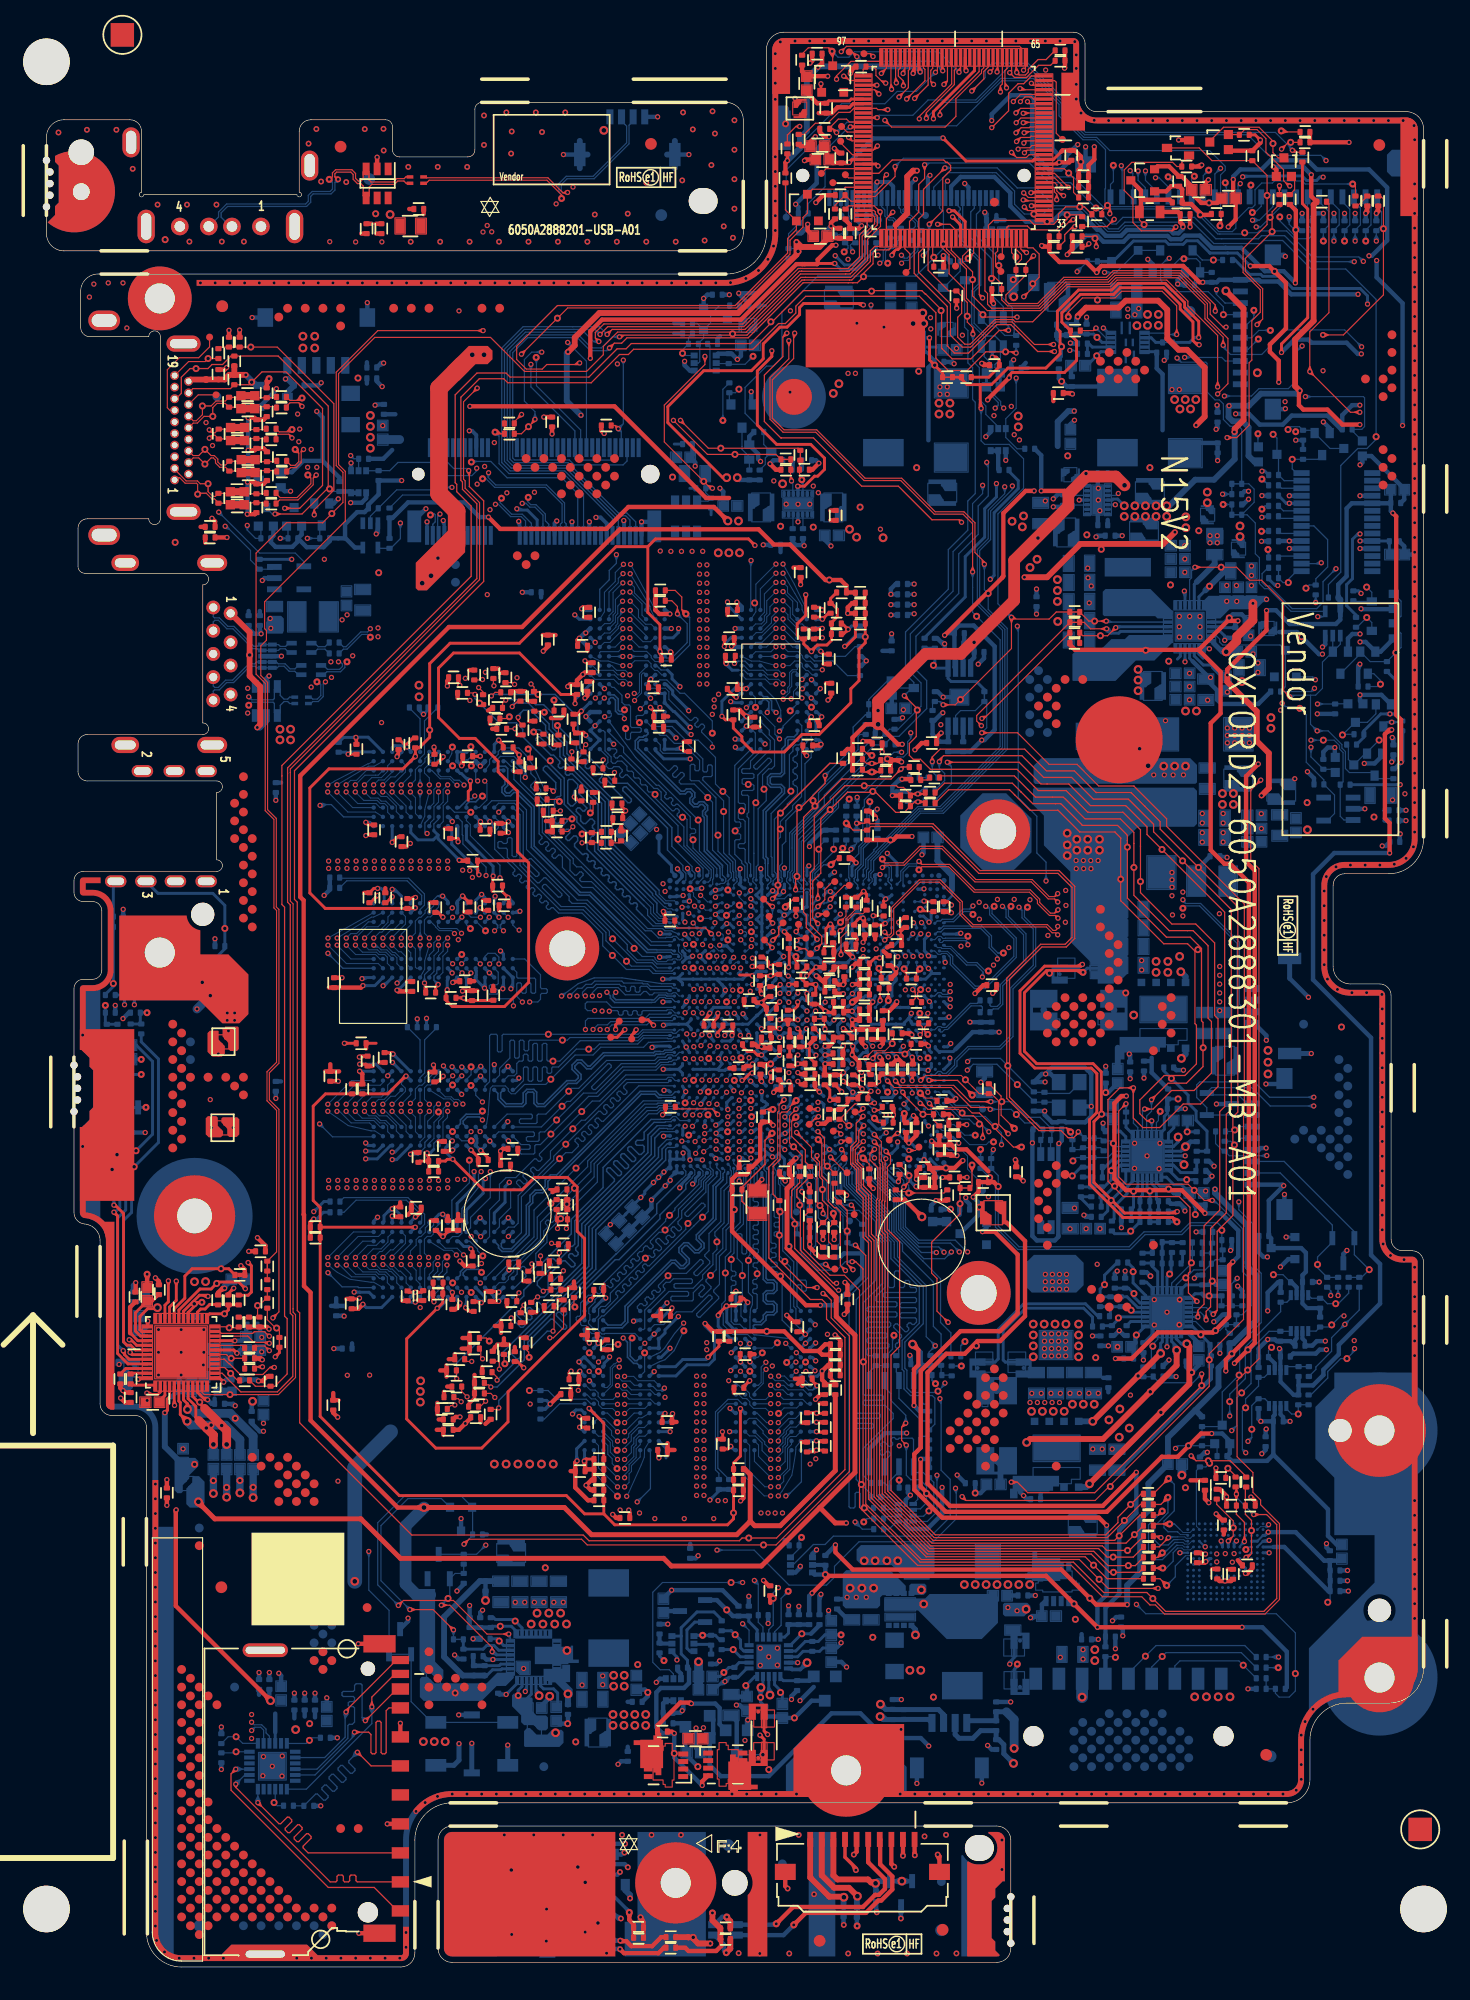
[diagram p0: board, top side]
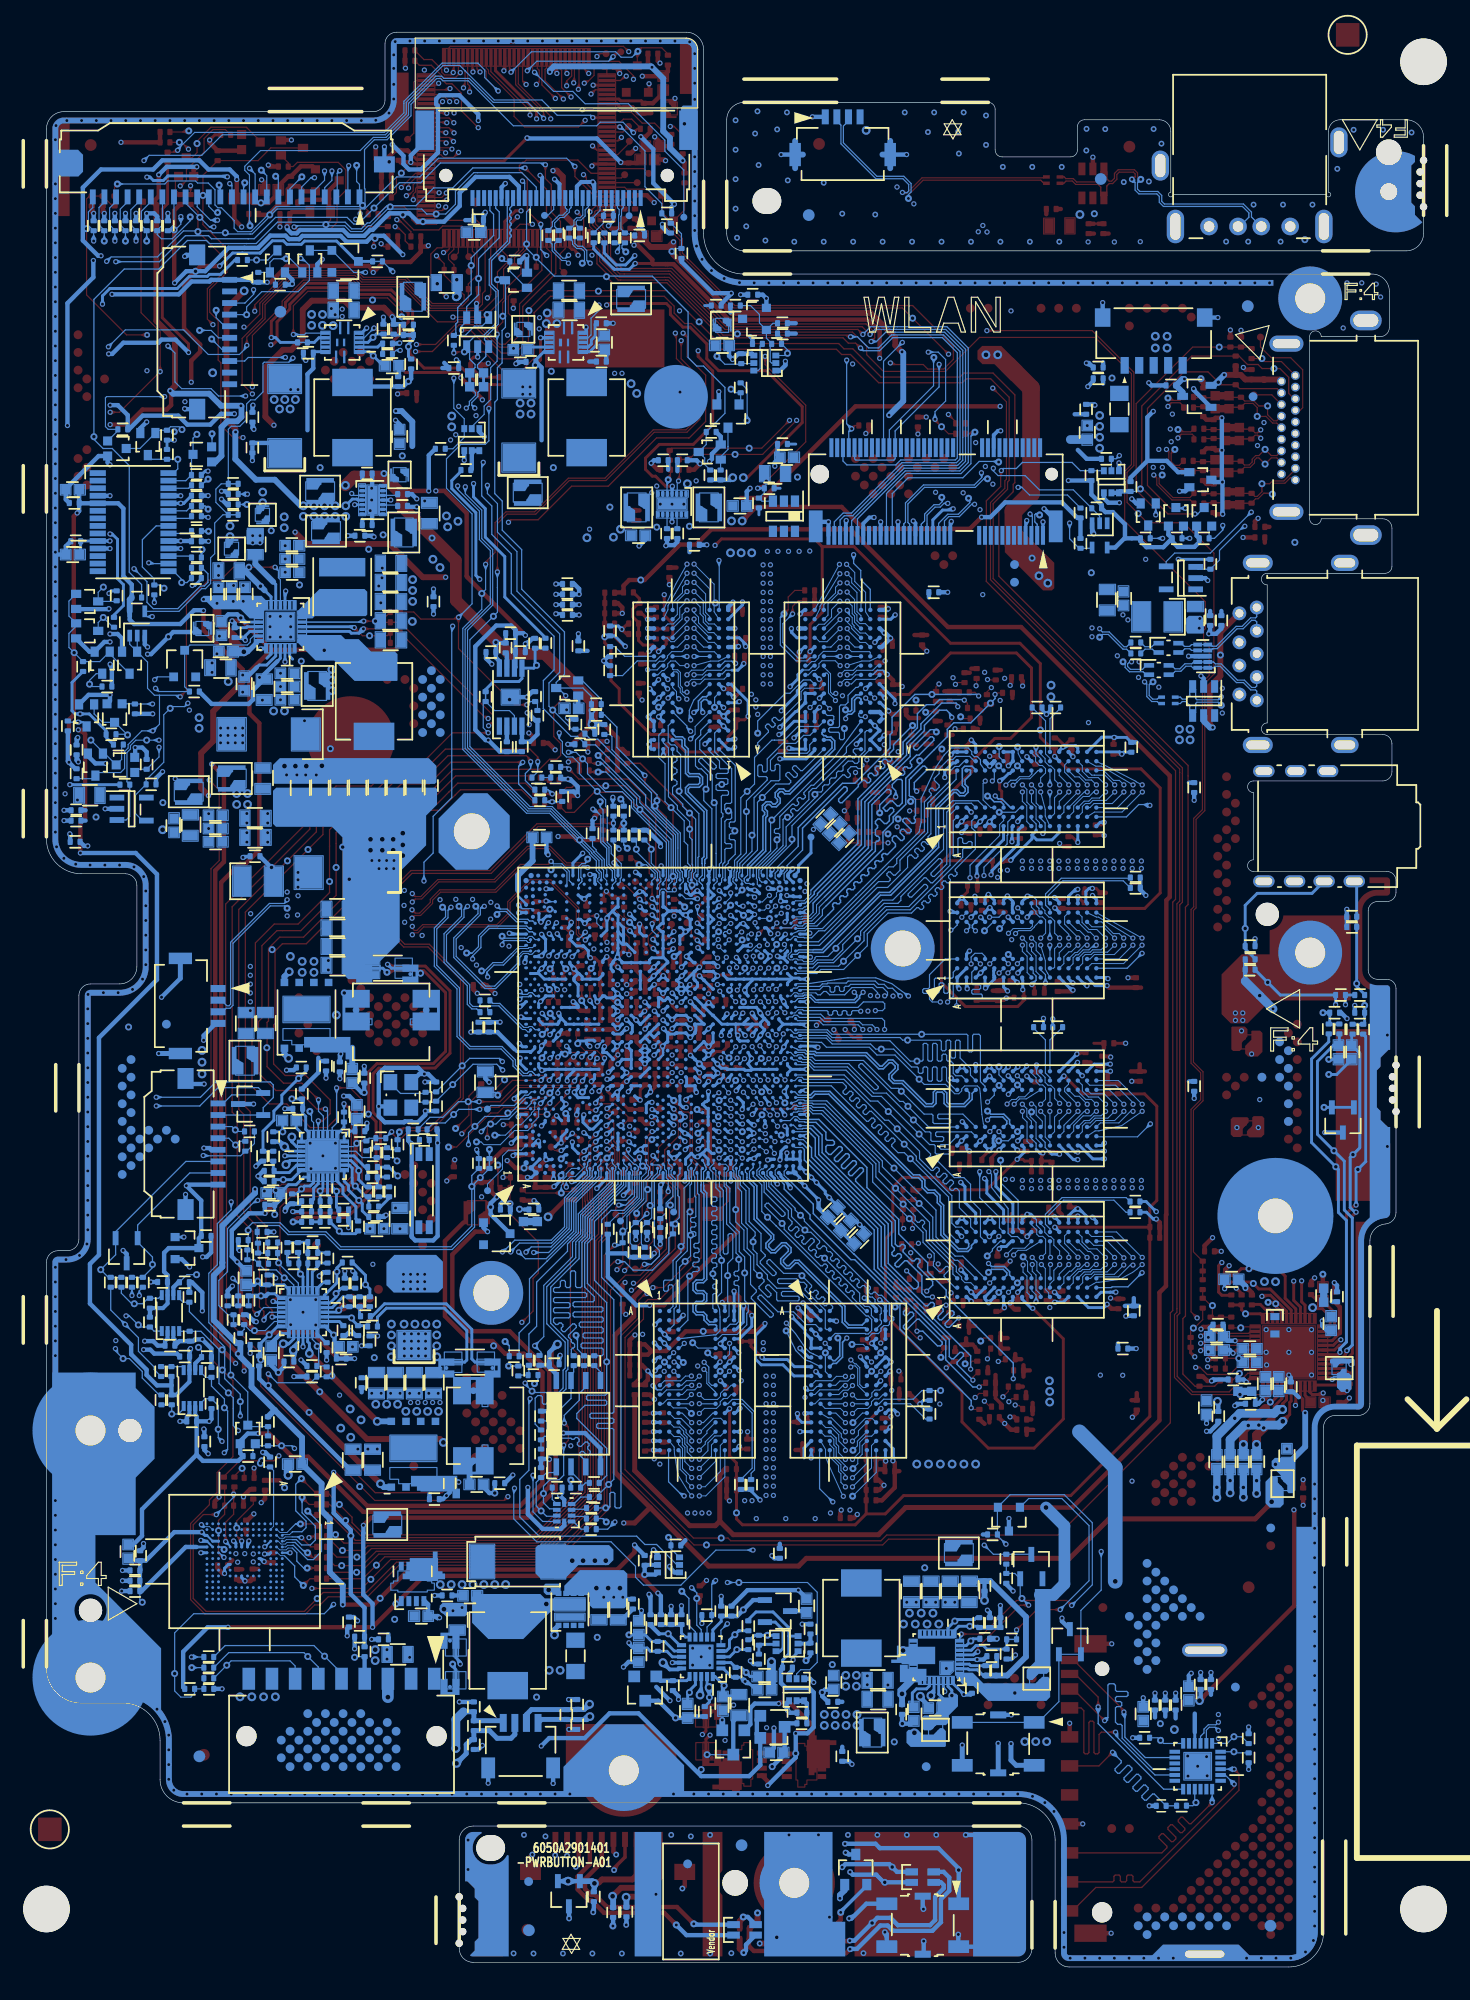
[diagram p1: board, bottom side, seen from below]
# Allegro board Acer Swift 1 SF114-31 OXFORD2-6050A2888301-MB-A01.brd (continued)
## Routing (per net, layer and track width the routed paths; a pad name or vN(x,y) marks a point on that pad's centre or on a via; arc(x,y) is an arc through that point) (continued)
M_A_A<15>: length 107.6
  TOP w0.102: R4141.2 45.28,104.74 v1(45.31,104.77)
  L3 w0.102: v1(56.96,114.56) 56.96,114.3 56.83,114.16 56.17,114.16 54.97,112.97 54.97,112.71 53.27,111 53.27,110.77 52.52,110.02 52.52,109.3 52.51,109.29 52.51,108.07 50.8,106.36 49.53,106.36 49.43,106.46 49.43,106.83 49.32,106.93 49.12,106.93 49.02,106.83 49.02,106.46 48.92,106.36 48.71,106.36 48.61,106.46 48.61,106.83 48.51,106.93 48.31,106.93 48.21,106.83 48.21,106.46 48.11,106.36 47.25,106.36 46.67,105.78 46.34,105.78 45.85,106.27 45.56,106.27 45.36,106.07 45.21,106.07 44.53,106.76 44.39,106.76 44.25,106.61 44.25,106.46 44.93,105.78 44.93,105.64 44.49,105.2 44.49,105.08 44.64,104.94 44.8,104.94 45.64,105.78 45.77,105.78 45.96,105.58 45.96,105.42 v1(45.31,104.77) 45.08,104.53 42.91,104.53 42.81,104.64 42.81,104.84 42.9,104.94 43.99,104.94 44.09,105.04 44.09,105.92 43.91,106.09 43.48,106.09 43.28,105.9 43.28,105.45 43.18,105.35 42.73,105.35 42.4,105.01 42.4,104.59 38.11,100.3 36.37,100.3 35.72,99.64 34.41,99.64 33.19,98.42 32.65,98.42 32.2,97.97 32.2,97.79 32.5,97.49 32.5,97.36 32.35,97.22 32.18,97.22 31.88,97.52 31.75,97.52 31.6,97.36 31.6,97.23 31.79,97.03 31.79,96.69 30.66,95.56 v1(30.66,95.34)
  L4 w0.089: v1(63.53,114.61) 63.53,114.38 63.37,114.23 59.56,114.23 59.29,114.49 57.04,114.49 56.97,114.56 v1(56.96,114.56) 56.96,114.55 56.87,114.55 56.49,114.17 56.16,114.17 55.83,114.5 50.41,114.5 v1(50.32,114.59) ; v1(30.6,88.7) 30.8,88.9 30.8,94.05 31.05,94.3 31.05,94.89 30.66,95.28 v1(30.66,95.34) 30.66,95.36 30.72,95.42 30.72,97.2 30.99,97.47 30.99,101.7 30.78,101.91 v1(30.6,101.91)
  L4 w0.152: v1(45.31,104.77) 45.31,104.6 49.39,100.52 51.34,100.52 53.77,98.08 53.77,97.72 54.04,97.45 54.4,97.45 54.93,96.92 54.93,96.73 54.64,96.43 54.64,96.24 54.77,96.11 54.96,96.11 55.26,96.41 55.45,96.41 55.58,96.27 55.58,96.09 55.28,95.79 55.28,95.6 55.42,95.46 55.61,95.46 55.9,95.76 56.09,95.76 56.28,95.57 56.28,95.31 55.76,94.79 55.76,93.93 55.52,93.69 v3(55.52,92.95)
  BOTTOM w0.089: v1(63.53,114.61) 64.35,113.79 U4100.M7 ; U4500.BD49 55.81,92.32 55.81,92.59 55.64,92.77 55.64,92.83 v3(55.52,92.95) ; v1(30.6,88.7) 30.6,89.03 31.42,89.85 U4102.M7 ; v1(30.6,101.91) 31.42,102.73 U4103.M7 ; v1(50.32,114.59) 50.32,114.58 51.12,113.79 U4101.M7
M_A_BS0: length 106.4
  TOP w0.102: R4123.2 42.21,106.28 v3(42.02,106.47)
  L3 w0.102: v1(56.33,115.35) 56.22,115.35 54.25,113.38 54.25,113.18 53.69,112.61 52.35,112.61 50.96,111.22 50.96,110.69 50.48,110.22 49.61,110.22 49.19,109.8 46.97,109.8 46.87,109.9 46.87,110.35 46.77,110.45 46.56,110.45 46.46,110.35 46.46,109.9 46.36,109.8 45.91,109.8 45.3,109.19 45.29,109.19 42.62,106.52 42.07,106.52 v3(42.02,106.47) 42.02,106 41.39,105.36 40.6,105.36 38.84,103.6 38.84,102.7 37.74,101.6 36.62,101.6 35.38,100.36 34.11,100.36 32.89,99.14 32.12,99.14 30.49,97.51 30.49,96.63 29.47,95.62 29.47,95.18 29.87,94.79 v1(29.87,94.71)
  L4 w0.089: v1(29.81,88.09) 29.42,88.48 29.42,88.87 29.41,88.88 29.41,93.66 29.87,94.11 v1(29.87,94.71) 29.87,94.8 29.48,95.18 29.48,95.52 29.43,95.57 29.43,97.11 29.9,97.57 29.9,101.21 v1(29.81,101.3) ; v1(62.92,115.4) 62.83,115.31 60.02,115.31 59.56,115.78 57.19,115.78 57.16,115.75 56.82,115.75 56.42,115.35 v1(56.33,115.35) 55.73,115.35 55.3,115.78 50.11,115.78 v1(49.71,115.38)
  BOTTOM w0.089: U4100.M2 61.18,114.2 61.71,114.2 v1(62.92,115.4) ; U4103.M2 31.02,99.56 31.02,100.09 v1(29.81,101.3) ; v1(29.81,88.09) 29.81,88.09 30.38,87.52 30.59,87.52 31.02,87.09 31.02,86.5 U4102.M2 ; U4500.BH46 53.67,90.53 53.61,90.59 52.98,90.59 52.65,90.92 ; v1(49.71,115.38) 49.71,115.3 48.6,114.19 48.12,114.19 U4101.M2
  BOTTOM w0.124: v3(42.02,106.47) 42.22,106.67 42.53,106.67 43.98,105.22 43.98,105.06 43.86,104.93 43.66,104.93 42.54,106.05 42.36,106.05 42.24,105.93 42.24,105.75 43.51,104.48 43.73,104.48 44.27,103.95 44.27,103.77 44.15,103.65 44.15,103.48 44.28,103.35 44.45,103.35 44.57,103.47 44.75,103.47 44.87,103.34 44.87,103.16 44.76,103.05 44.76,102.87 44.89,102.74 45.06,102.74 45.18,102.86 45.35,102.86 47.88,100.33 47.88,96.49 52.65,91.71 52.65,90.92
M_A_BS1: length 113
  TOP w0.102: R4125.2 41.72,104.83 v3(41.55,105)
  L3 w0.102: v1(29.87,95.34) 29.87,95.45 30.74,96.32 30.74,97.42 32.22,98.9 32.99,98.9 34.21,100.12 35.48,100.12 35.84,100.47 35.84,100.48 36.72,101.36 38.49,101.36 38.78,101.65 38.78,101.79 38.6,101.98 38.6,102.12 38.74,102.26 38.89,102.26 39.07,102.08 39.21,102.08 40.57,103.44 40.57,103.55 40.42,103.69 40.25,103.69 39.38,102.82 39.23,102.82 39.08,102.96 39.08,103.1 40.25,104.27 40.42,104.27 40.86,103.84 40.97,103.84 41.74,104.61 41.74,104.81 v3(41.55,105) 41.55,105.11 44.12,107.68 44.38,107.94 45.22,107.94 46.26,108.98 48.56,108.98 48.66,108.88 48.66,108.31 48.76,108.21 48.96,108.21 49.06,108.32 49.06,108.9 49.17,109 49.97,109 50.18,108.79 50.92,108.79 51.32,109.19 51.32,109.5 52.78,110.97 52.78,111.2 54.49,112.91 54.49,113.28 56.17,114.95 56.49,114.95 56.89,115.35 v1(56.96,115.35)
  L4 w0.089: v1(29.81,88.7) 29.81,89.66 30.25,90.1 30.25,94.89 29.87,95.28 v1(29.87,95.34) 29.87,95.79 30.21,96.14 30.21,101.72 30.01,101.91 v1(29.81,101.91) ; v1(57.29,88.03) 56.8,87.54 55.58,87.54 55.42,87.38 54.09,87.38 52.4,89.08 ; v1(63.53,115.4) 63.53,115.21 63.32,115 57.76,115 57.41,115.35 v1(56.96,115.35) 56.9,115.35 56.51,114.96 51.72,114.96 51.49,115.19 50.52,115.19 v1(50.33,115.38)
  L4 w0.152: 52.4,89.08 51.81,89.66 51.81,92.18 51.64,92.35 51.64,93.12 50.26,94.5 50.05,94.5 49.91,94.37 49.91,94.37 49.43,93.89 48.53,93.89 46.01,96.41 45.66,96.76 45.66,97.9 45.85,98.09 45.85,99.46 44.67,100.64 44.67,101.02 41.28,104.41 41.28,104.73 v3(41.55,105)
  BOTTOM w0.089: U4100.N8 65.57,114.59 65.25,114.59 64.91,114.25 64.63,114.25 63.53,115.36 v1(63.53,115.4) ; v1(50.33,115.38) 51.45,114.25 52.09,114.25 52.43,114.59 52.43,114.59 52.43,114.59 U4101.N8 ; v1(29.81,101.91) 29.86,101.91 30.96,103.01 30.96,103.62 U4103.N8 ; v1(57.29,88.03) 57.31,88.05 57.54,88.05 57.99,87.6 U4500.AY40 ; U4102.N8 30.96,90.56 30.96,89.9 29.81,88.75 v1(29.81,88.7)
M_A_BS2: length 100.8
  TOP w0.102: v3(44.07,107.03) 44.16,106.94 R4124.2
  L3 w0.102: v1(30.66,94.71) 30.66,94.79 30.26,95.18 30.26,95.51 30.98,96.22 30.98,97.09 32.55,98.66 33.09,98.66 34.31,99.88 35.58,99.88 36.24,100.54 38.01,100.54 42.03,104.55 42.03,104.98 v3(44.07,107.03) 44.44,107.4 45.16,107.4 45.27,107.29 45.27,106.7 45.37,106.6 45.57,106.6 45.67,106.7 45.67,107.42 45.78,107.52 45.98,107.52 46.08,107.42 46.08,106.7 46.18,106.6 46.38,106.6 46.49,106.7 46.49,107.29 46.59,107.4 46.79,107.4 46.89,107.29 46.89,106.7 46.99,106.6 47.49,106.6 48.07,107.18 50.22,107.18 50.92,107.88 51.2,107.88 51.66,108.33 51.66,109.5 53.03,110.87 53.03,111.1 54.73,112.81 54.73,113.07 56.22,114.56 v1(56.33,114.56)
  L4 w0.089: v1(62.92,114.61) 62.79,114.48 59.59,114.48 59.38,114.7 57.76,114.7 57.51,114.94 56.78,114.94 56.4,114.56 v1(56.33,114.56) 56.18,114.7 51.68,114.7 51.41,114.98 50.08,114.98 49.71,114.61 v1(49.71,114.56) ; v1(30.6,101.3) 30.73,101.17 30.73,98.16 30.52,97.94 30.52,96.14 30.27,95.89 30.27,95.17 30.66,94.78 v1(30.66,94.71) 30.66,94.23 30.5,94.07 30.5,90.06 30.21,89.77 30.21,88.48 v1(30.6,88.09)
  BOTTOM w0.089: v1(49.71,114.56) 49.71,114.45 49.05,113.79 U4101.M3 ; v1(30.6,101.3) 31.42,100.48 U4103.M3 ; v1(30.6,88.09) 30.76,88.09 31.42,87.43 U4102.M3 ; U4100.M3 62.1,113.79 v1(62.92,114.61)
  BOTTOM w0.102: U4500.BF52 55.15,93.7 55.15,94.29 54.89,94.54 54.89,94.96 53.56,96.29
  BOTTOM w0.124: 53.56,96.29 53.56,98.18 49.99,101.75 49.84,101.75 49.71,101.62 49.71,101.42 50.45,100.68 50.45,100.5 50.32,100.37 50.15,100.37 49.68,100.84 48.75,101.77 48.75,101.93 48.37,102.3 48.2,102.3 48,102.1 47.82,102.1 47.69,102.23 47.69,102.41 47.89,102.61 47.89,102.78 47.77,102.91 47.59,102.91 47.39,102.71 47.21,102.71 47.09,102.84 47.09,103.01 47.29,103.21 47.29,103.39 47.16,103.52 46.98,103.52 46.78,103.32 46.61,103.32 46.48,103.44 46.48,103.62 46.68,103.82 46.68,104 46.55,104.13 46.38,104.13 46.17,103.92 46,103.92 45.87,104.05 45.87,104.23 46.07,104.43 46.07,104.61 45.71,104.96 45.71,105.39 v3(44.07,107.03)
M_A_CAS#: length 101.6
  TOP w0.102: v3(46.91,99.5) 47.14,99.73 R4120.2
  L3 w0.102: v1(33.81,95.34) 33.97,95.5 33.97,95.7 34.62,96.36 40.7,96.36 43.35,99.01 43.51,99.01 43.65,98.87 43.65,98.73 41.5,96.59 41.5,96.45 41.64,96.3 41.8,96.3 44.86,99.37 45.95,99.37 46.06,99.27 46.06,98.95 46.16,98.84 46.36,98.84 46.46,98.95 46.46,99.27 46.56,99.37 46.78,99.37 v3(46.91,99.5) 48.59,99.5 50.51,101.42 50.65,101.42 50.82,101.25 50.95,101.25 51.1,101.4 51.1,101.55 50.94,101.71 50.94,101.85 51.29,102.2 51.43,102.2 51.69,101.94 51.84,101.94 51.98,102.08 51.98,102.23 51.72,102.49 51.72,102.63 51.86,102.77 52.01,102.77 52.27,102.51 52.41,102.51 52.56,102.66 52.56,102.8 52.3,103.06 52.3,103.21 52.44,103.35 52.58,103.35 52.84,103.09 52.99,103.09 53.13,103.23 53.13,103.38 52.87,103.64 52.87,103.78 53.01,103.92 53.16,103.92 53.42,103.66 53.56,103.66 53.71,103.81 53.71,103.95 53.45,104.21 53.45,104.36 53.59,104.5 53.73,104.5 53.99,104.24 54.14,104.24 54.28,104.38 54.28,104.53 54.02,104.79 54.02,104.93 55.12,106.03 55.12,107.04 55.84,107.76 55.84,109.12 55.93,109.22 55.93,110.77 56.17,111 56.57,111 v1(56.96,111.4)
  L4 w0.089: v1(50.32,111.4) 51.38,111.4 51.59,111.61 55.57,111.61 56.17,111.01 56.51,111.01 56.89,111.4 v1(56.96,111.4) 61.62,111.4 62,111.02 62.16,111.02 62.34,111.2 62.57,111.2 62.76,111.01 63.28,111.01 63.53,111.26 v1(63.53,111.4) ; v1(33.81,88.7) 33.81,89.21 33.61,89.42 33.61,92.31 33.82,92.52 33.82,94.17 34.2,94.55 34.2,94.89 33.81,95.27 v1(33.81,95.34) 33.68,95.48 33.68,95.86 33.84,96.02 34.05,96.02 34.22,96.18 34.22,101.51 v1(33.81,101.91)
  BOTTOM w0.089: U4103.K3 33.41,100.34 33.41,101.51 v1(33.81,101.91) ; U4500.BG45 54.33,90.2 54.23,90.2 54.1,90.33 53.59,90.33 53.52,90.4 52.85,90.4 52.36,90.89 52.36,91.56 51.67,92.25 ; U4101.K3 48.52,112.19 48.76,112.19 49.17,111.79 49.93,111.79 v1(50.32,111.4) ; U4100.K3 61.57,112.19 61.73,112.19 62.12,111.8 63.13,111.8 v1(63.53,111.4) ; v1(33.81,88.7) 33.41,88.3 33.41,87.63 33.02,87.24 33.02,87.24 U4102.K3
  BOTTOM w0.124: 51.67,92.25 47.58,96.34 47.58,100.2 46.97,100.82 46.27,101.51 46.06,101.51 45.94,101.39 45.94,101.13 46.91,100.17 v3(46.91,99.5)
M_A_CKE0: length 118.9
  TOP w0.102: R4116.2 48,104.05 v1(48.02,104.07)
  L3 w0.102: v1(31.45,95.34) 31.45,95.46 31.97,95.98 32.08,95.98 33.48,97.38 33.48,97.8 34.84,99.15 35.74,99.15 35.75,99.15 36.85,99.15 37.48,99.78 38.27,99.78 40.56,102.06 41.54,102.06 41.78,102.3 41.78,102.89 41.88,102.99 43.45,102.99 43.55,102.88 43.55,102.68 43.45,102.58 42.29,102.58 42.18,102.47 42.18,102.27 42.28,102.17 43.44,102.17 43.91,101.7 45.88,101.7 48.02,103.84 v1(48.02,104.07) 47.84,104.25 47.63,104.25 47.34,103.96 47.34,103.73 47.17,103.56 46.94,103.56 46.76,103.39 46.76,103.16 46.59,102.99 46.36,102.99 46.19,102.81 46.19,102.58 46.02,102.41 45.79,102.41 45.53,102.15 44.03,102.15 43.92,102.27 43.92,102.45 44.03,102.56 45.36,102.56 47.57,104.77 50.01,104.77 53.56,108.31 53.56,110.38 53.75,110.57 53.75,110.8 55.46,112.51 55.46,112.67 56.16,113.37 56.82,113.37 56.96,113.51 v1(56.96,113.77)
  L4 w0.089: 57.62,94.04 57.62,93.41 57.31,93.1 57.31,90.18 57.46,90.03 v1(57.66,90.03) ; v1(31.39,101.91) 31.47,101.99 31.66,101.99 31.78,101.88 31.78,95.81 31.45,95.47 v1(31.45,95.34) 31.45,95.26 31.83,94.87 31.83,92.75 31.39,92.31 v1(31.39,88.7) ; v1(63.53,113.82) 63.61,113.74 63.61,113.54 63.5,113.43 58.33,113.43 57.99,113.77 v1(56.96,113.77) 56.88,113.77 56.49,113.38 54.93,113.38 54.46,113.85 50.41,113.85 50.33,113.77 v1(50.32,113.77)
  L4 w0.152: v1(48.02,104.07) 48.34,104.39 48.34,104.74 47.04,106.05 47.04,106.21 47.2,106.37 47.36,106.37 48.75,104.98 49.29,104.98 56.91,97.36 57.62,96.65 57.62,94.04
  BOTTOM w0.089: v1(63.53,113.82) 63.96,113.4 64.84,113.4 65.22,113.02 65.22,112.87 65.52,112.57 65.9,112.57 66.28,112.19 U4100.K9 ; U4103.K9 33.02,104.57 32.64,104.19 32.64,103.9 32.29,103.55 32.14,103.55 31.82,103.22 31.82,102.34 v1(31.39,101.91) ; v1(57.66,90.03) 57.66,89.72 57.51,89.58 U4500.BB44 ; v1(50.32,113.77) 50.33,113.77 50.68,113.42 51.77,113.42 52.16,113.02 52.16,112.87 52.49,112.54 52.78,112.54 53.13,112.19 U4101.K9 ; v1(31.39,88.7) 31.81,89.13 31.81,90.17 32.15,90.5 32.3,90.5 32.66,90.86 32.66,91.07 32.91,91.32 32.91,91.59 33.02,91.7 U4102.K9
M_A_CKE1: length 119.2
  TOP w0.102: R4118.2 49.01,102.96 v1(48.99,102.98)
  L3 w0.102: v1(56.96,112.19) 56.57,111.79 56.17,111.79 55.39,111.02 55.39,109.36 54.75,108.71 54.75,108.14 54.36,107.75 54.36,107.61 54.6,107.37 54.6,107.22 54.46,107.08 54.32,107.08 54.07,107.32 53.93,107.32 53.79,107.18 53.79,107.03 54.03,106.79 54.03,106.65 53.88,106.5 53.74,106.5 53.5,106.75 53.36,106.75 53.13,106.51 53.13,106.38 53.56,105.95 53.56,105.8 51.11,103.35 51,103.35 50.85,103.49 50.85,103.67 52.98,105.8 52.98,105.95 52.84,106.1 52.71,106.1 50.22,103.61 50.22,103.5 50.48,103.25 50.48,103.08 49.17,101.77 48.97,101.77 48.82,101.92 48.82,102.09 49.28,102.54 49.28,102.7 v1(48.99,102.98) 48.69,102.98 46.54,100.83 46.54,100.68 46.68,100.54 46.82,100.54 48.16,101.88 48.3,101.88 48.44,101.74 48.44,101.59 46.99,100.13 45.84,100.13 45.79,100.09 44.01,100.09 43.81,99.89 43.3,99.89 42.79,99.39 41.9,99.39 41.36,98.86 41.22,98.86 40.94,99.14 40.79,99.14 40.65,98.99 40.65,98.85 40.93,98.57 40.93,98.42 40.71,98.21 39.06,98.21 38.44,97.59 35.05,97.59 33.02,95.56 v1(33.02,95.34)
  L4 w0.089: v1(63.53,112.19) 63.53,111.93 63.4,111.8 62.76,111.8 62.58,111.98 57.83,111.98 57.46,112.35 57.12,112.35 v1(56.96,112.19) 56.88,112.19 56.5,111.8 56.17,111.8 55.96,112.01 50.5,112.01 v1(50.32,112.19) ; v1(57.97,89.06) 57.52,88.61 57.26,88.61 56.95,88.91 56.95,89.81 57.12,89.97 57.12,93.38 57.34,93.6 57.34,96.47 57.01,96.79 ; v1(33.02,88.7) 33.2,88.88 33.2,92.47 33.41,92.69 33.41,94.87 33.02,95.26 v1(33.02,95.34) 33.02,95.78 33.48,96.23 33.48,101.09 33.43,101.14 33.43,101.84 33.35,101.91 v1(33.02,101.91)
  L4 w0.152: v1(48.99,102.98) 48.59,103.38 48.59,104.18 49.04,104.62 49.19,104.62 49.36,104.45 49.36,104.29 49.05,103.99 49.05,103.81 49.19,103.68 49.39,103.68 49.68,103.97 49.83,103.97 57.01,96.79
  BOTTOM w0.089: v1(33.02,101.91) 33.02,102.51 32.6,102.93 32.6,103.31 32.87,103.58 33.13,103.58 33.46,103.92 33.46,104.31 33.82,104.67 U4103.J9 ; v1(33.02,88.7) 32.6,89.13 32.6,90.27 32.86,90.53 33.13,90.53 33.44,90.84 33.44,90.99 33.82,91.38 U4102.J9 ; v1(63.53,112.19) 64.13,112.19 64.53,112.59 64.94,112.59 65.19,112.34 65.19,112.09 65.52,111.77 65.67,111.77 66.05,111.39 66.13,111.39 66.13,111.39 U4100.J9 ; U4101.J9 53.07,111.39 52.69,111.78 52.46,111.78 52.15,112.09 52.15,112.36 51.89,112.61 50.74,112.61 v1(50.32,112.19) ; U4500.AY42 58.36,88.71 58.36,88.97 58.27,89.06 v1(57.97,89.06)
M_A_CLK0_DN: length 127.3
  TOP w0.137: v3(46.19,97.68) 46.3,97.79 C4616.2 47.81,97.79 R4115.1
  L3 w0.147: v1(35.9,94.56) 35.99,94.65 35.99,95.19 36.24,95.44 37.16,95.44 37.5,95.1 39.59,95.1 39.88,94.81 39.88,93.77 40.05,93.6 40.31,93.6 40.43,93.73 40.43,94.81 40.73,95.1 41.56,95.1 41.95,94.71 41.95,93.61 42.34,93.22 45.69,93.22 46.81,94.33 46.81,94.54 46.63,94.72 46.42,94.72 45.46,93.77 45,93.77 44.67,94.1 44.67,94.47 45.95,95.75 45.95,95.96 45.77,96.14 45.56,96.14 45.38,95.96 45.01,95.96 44.68,96.29 44.68,96.75 45.52,97.59 46.1,97.59 v3(46.19,97.68) 46.47,97.4 47.07,97.4 47.36,97.11 47.36,95.75 47.51,95.59 47.77,95.59 47.91,95.73 47.91,97.11 48.21,97.4 48.67,97.4 48.97,97.11 48.97,95.78 49.11,95.64 49.37,95.64 49.52,95.8 49.52,97.11 49.81,97.4 50.28,97.4 56.75,103.87 56.75,108.73 57.11,109.09 57.44,109.09 v1(57.59,109.24)
  L4 w0.089: v1(63.53,109.9) 63.33,109.7 62.64,109.7 62.42,109.47 62.42,108.9 62.27,108.76 61.83,108.76 61.69,108.91 61.69,109.27 61.37,109.59 60.76,109.59 60.43,109.27 60.15,109.27 59.66,108.78 59.66,107.92 59.53,107.79 59.05,107.79 58.84,108.01 58.84,108.51 58.53,108.82 58.01,108.82 v1(57.59,109.24) 57.33,108.98 56.92,108.98 56.75,109.14 56.75,109.46 56.5,109.71 56.02,109.71 55.84,109.9 55.22,109.9 54.99,109.66 54.99,108.98 54.87,108.86 54.57,108.86 54.45,108.98 54.45,109.78 54.19,110.04 51.82,110.04 51.49,109.71 50.78,109.71 v1(50.7,109.79) ; v1(55.12,88.16) 55.12,88.03 54.99,87.9 54.31,87.9 54.09,88.12 54.09,88.3 54.25,88.46 54.25,88.74 54.09,88.9 54.09,88.95 54.07,88.97 ; v1(35.19,89.1) 35.45,89.36 35.45,89.91 35.66,90.11 36.69,90.11 36.86,90.28 36.86,90.76 36.71,90.91 35.64,90.91 35.42,91.13 35.42,91.59 35.65,91.81 36.67,91.81 36.86,92.01 36.86,92.36 36.74,92.48 36.42,92.48 35.83,93.06 35.83,93.83 36.12,94.12 36.12,94.33 v1(35.9,94.56) 36.09,94.75 36.09,95.17 36.32,95.4 36.62,95.4 36.73,95.5 36.73,95.77 36.6,95.9 36.21,95.9 35.92,96.18 35.92,96.72 36.14,96.94 36.56,96.94 36.67,97.05 36.67,97.31 36.53,97.45 36.13,97.45 35.93,97.64 35.93,99.81 35.69,100.05 35.69,101.6 v1(35.41,101.88)
  L4 w0.147: v3(46.19,97.68) 46.19,97.48 46.37,97.31 46.71,97.31 46.95,97.07 46.95,96.59 48.81,94.73 49.02,94.73 49.2,94.91 49.2,95.17 47.52,96.86 47.52,97.26 47.85,97.59 48.27,97.59 52.29,93.57 52.29,92.73 52.53,92.49 52.53,90.02 52.65,89.89 52.84,89.89 53.27,90.32 53.71,90.32 54.04,89.99 54.04,89.6 53.84,89.41 53.84,89.2 54.07,88.97
  BOTTOM w0.089: U4100.K7 64.77,111.9 64.7,111.83 64.33,111.83 64.1,111.6 64.1,110.47 63.93,110.31 63.93,109.97 63.87,109.9 v1(63.53,109.9) ; U4102.K7 33.16,90.1 33.56,89.7 33.56,89.66 33.87,89.35 34.94,89.35 v1(35.19,89.1) ; U4101.K7 51.72,112.07 51.15,111.49 51.15,109.9 50.95,109.71 50.79,109.71 v1(50.7,109.79) ; U4500.BF40 55.26,87.6 54.99,87.87 54.99,88.08 55.07,88.16 v1(55.12,88.16) ; U4103.K7 33.24,103.15 33.24,103.15 33.95,102.44 34.78,102.44 35.07,102.15 35.34,101.88 v1(35.41,101.88)
M_A_CLK0_DP: length 127.2
  TOP w0.137: v1(46.19,96.91) 46.22,96.94 C4616.1 47.84,96.94 R4114.1
  L3 w0.147: v1(36.5,94.53) 36.24,94.8 36.24,95.09 36.35,95.2 37.06,95.2 37.4,94.85 39.48,94.85 39.63,94.7 39.63,93.67 39.94,93.35 40.41,93.35 40.68,93.63 40.68,94.7 40.83,94.85 41.46,94.85 41.7,94.61 41.7,93.51 42.24,92.97 45.8,92.97 47.06,94.23 47.06,94.64 46.73,94.97 46.31,94.97 45.36,94.02 45.11,94.02 44.92,94.2 44.92,94.37 46.2,95.65 46.2,96.06 45.87,96.39 45.46,96.39 45.28,96.21 45.11,96.21 44.93,96.4 44.93,96.64 45.62,97.34 45.95,97.34 46.19,97.09 v1(46.19,96.91) 46.43,97.15 46.96,97.15 47.11,97 47.11,95.64 47.41,95.34 47.88,95.34 48.16,95.63 48.16,97 48.31,97.15 48.57,97.15 48.72,97 48.72,95.68 49,95.39 49.47,95.39 49.77,95.69 49.77,97 49.92,97.15 50.38,97.15 57,103.77 57,108.62 57.22,108.84 57.38,108.84 v1(57.59,108.63)
  L4 w0.089: v1(35.8,89.11) 35.63,89.28 35.63,89.28 35.63,89.83 35.73,89.93 36.76,89.93 37.03,90.2 37.03,90.83 36.78,91.08 35.72,91.08 35.6,91.2 35.6,91.52 35.72,91.64 36.74,91.64 37.04,91.94 37.04,92.45 36.84,92.66 36.49,92.66 36.01,93.13 36.01,93.76 36.29,94.04 36.29,94.32 v1(36.5,94.53) 36.26,94.77 36.26,95.09 36.39,95.22 36.7,95.22 36.9,95.43 36.9,95.85 36.68,96.07 36.28,96.07 36.1,96.26 36.1,96.65 36.22,96.76 36.64,96.76 36.85,96.98 36.85,97.38 36.6,97.63 36.2,97.63 36.11,97.72 36.11,99.88 35.87,100.12 35.87,101.74 v1(36.02,101.89) ; v1(63.55,109.29) 63.32,109.52 62.72,109.52 62.59,109.4 62.59,108.83 62.34,108.58 61.76,108.58 61.51,108.83 61.51,109.2 61.29,109.41 60.83,109.41 60.5,109.09 60.23,109.09 59.84,108.7 59.84,107.85 59.61,107.61 58.98,107.61 58.66,107.93 58.66,108.44 58.46,108.64 57.6,108.64 v1(57.59,108.63) 57.42,108.8 57.4,108.8 56.84,108.8 56.57,109.07 56.57,109.39 56.43,109.54 55.95,109.54 55.76,109.72 55.3,109.72 55.17,109.59 55.17,108.91 54.94,108.68 54.5,108.68 54.27,108.91 54.27,109.71 54.12,109.86 51.9,109.86 51.56,109.53 51.07,109.53 v1(50.72,109.18) ; 53.9,88.79 53.91,88.78 53.96,88.78 54.07,88.67 54.07,88.53 53.91,88.37 53.91,88.04 54.24,87.72 55.26,87.72 55.8,88.16 v3(55.8,88.16)
  L4 w0.147: 53.9,88.79 53.59,89.1 53.59,89.51 53.79,89.7 53.79,89.89 53.6,90.07 53.37,90.07 52.94,89.65 52.55,89.65 52.28,89.91 52.28,92.39 52.05,92.63 52.05,93.46 48.16,97.35 47.95,97.35 47.76,97.16 47.76,96.96 49.45,95.28 49.45,94.81 49.12,94.48 48.7,94.48 46.7,96.49 46.7,96.96 46.6,97.06 46.34,97.06 v1(46.19,96.91)
  BOTTOM w0.089: U4102.J7 33.82,90.1 33.74,90.02 33.74,89.73 33.94,89.53 35.39,89.53 35.78,89.14 v1(35.8,89.11) ; U4500.BD40 55.8,88.16 v3(55.8,88.16) ; v1(63.55,109.29) 63.55,109.33 64.11,109.9 64.11,110.23 64.27,110.4 64.27,111.52 64.41,111.66 64.67,111.66 64.77,111.56 U4100.J7 ; U4101.J7 51.72,111.39 51.56,111.56 51.46,111.56 51.32,111.42 51.32,109.83 50.72,109.23 v1(50.72,109.18) ; U4103.J7 33.82,103.15 33.78,103.12 33.78,102.86 34.03,102.62 34.86,102.62 35.16,102.31 35.61,102.31 36.02,101.9 v1(36.02,101.89)
M_A_CS#0: length 121.1
  TOP w0.102: R4117.2 46.32,105.19 v1(46.51,105.38)
  L3 w0.102: v1(56.33,113.77) 56.22,113.77 55.22,112.77 55.22,112.61 53.51,110.9 53.51,110.67 53.32,110.48 53.32,108.41 50.73,105.82 49.92,105.82 49.82,105.72 49.82,105.11 49.72,105.01 49.52,105.01 49.41,105.11 49.41,105.72 49.31,105.82 47.39,105.82 47.29,105.72 47.29,105.52 47.39,105.42 48.45,105.42 48.53,105.34 48.53,105.13 48.4,105.01 47.29,105.01 45.08,102.8 44.91,102.8 44.79,102.92 44.79,103.08 46.73,105.02 46.73,105.16 v1(46.51,105.38) 45.42,104.29 42.83,104.29 42.72,104.18 42.72,103.97 42.81,103.88 44.59,103.88 44.69,103.78 44.69,103.58 44.59,103.48 41.63,103.48 38.17,100.02 36.44,100.02 35.82,99.4 34.61,99.4 33.24,98.03 33.24,97.48 31.98,96.22 31.75,96.22 31.05,95.52 31.05,95.06 31.4,94.71 v1(31.45,94.71)
  L4 w0.089: v1(31.39,101.3) 31.45,101.24 31.45,97.55 30.98,97.08 30.98,95.57 31.04,95.51 31.04,95.17 31.45,94.77 v1(31.45,94.71) 31.44,94.7 31.44,94.29 31,93.85 31,88.48 v1(31.39,88.09) ; v1(58.44,87.12) 58.44,87.16 57.68,87.93 57.68,88.19 57.45,88.42 57.18,88.42 56.76,88.83 56.76,89.91 56.93,90.07 56.93,93.53 57.03,93.64 57.03,96.3 56.73,96.61 ; v1(62.92,113.82) 62.85,113.75 59.72,113.75 59.24,114.23 57.26,114.23 57.19,114.15 56.76,114.15 56.38,113.77 v1(56.33,113.77) 56.27,113.77 55.84,114.2 50.14,114.2 v1(49.7,113.77)
  L4 w0.152: v1(46.51,105.38) 46.41,105.28 46.41,104.91 46.9,104.41 47.1,104.41 47.24,104.54 47.24,104.72 47,104.96 47,105.15 47.13,105.29 47.32,105.29 47.88,104.72 47.88,104.54 47.42,104.09 47.42,103.89 48.76,102.55 49.17,102.55 49.89,103.27 50.07,103.27 50.29,103.05 50.29,102.86 49.47,102.05 49.47,101.86 49.6,101.72 49.79,101.72 50.61,102.54 50.8,102.54 50.99,102.35 50.99,102.16 50.68,101.86 50.68,101.64 50.82,101.51 50.98,101.51 51.31,101.84 51.5,101.84 56.73,96.61
  BOTTOM w0.089: U4100.L2 61.17,113.39 62.49,113.39 v1(62.92,113.82) ; U4500.AY38 58.44,86.79 v1(58.44,87.12) ; v1(31.39,101.3) 31.39,101.24 31.82,100.81 31.82,99.44 32.11,99.15 U4103.L2 ; U4101.L2 47.72,113.33 47.79,113.39 49.33,113.39 v1(49.7,113.77) ; U4102.L2 31.92,86.1 31.82,86.2 31.82,87.78 31.51,88.09 v1(31.39,88.09)
M_A_CS#1: length 111
  TOP w0.102: v3(44.24,100.48) 44.06,100.66 R4119.2
  L3 w0.102: v1(56.33,112.19) 56.22,112.19 55.12,111.09 55.12,110.28 54.5,108.76 54.5,108.23 50.31,104.04 48.53,103.2 45.81,100.48 v3(44.24,100.48) 41.18,100.48 41.07,100.38 41.07,100.18 41.18,100.07 42.5,100.07 42.6,99.97 42.6,99.77 42.5,99.67 40.18,99.67 38.37,97.86 34.98,97.86 32.63,95.51 32.63,95.1 v1(33.02,94.71)
  L4 w0.089: v1(62.92,112.19) 59.42,112.77 58.52,112.77 56.9,112.58 56.79,112.54 56.71,112.48 56.41,112.19 v1(56.33,112.19) 56.3,112.22 51.6,112.22 51.24,112.58 50.1,112.58 v1(49.71,112.19) ; v1(33.02,88.09) 32.64,88.48 32.64,92.4 33.07,92.84 33.07,94.66 v1(33.02,94.71) 33.02,94.8 32.64,95.18 32.64,95.4 33.22,97.56 33.22,97.88 v1(33.02,101.3) ; 52.05,86.86 52.51,86.4 53.51,86.4 53.76,86.16 54.15,86.16 54.8,85.51 58.13,85.51 58.41,85.23 58.87,85.23 59.25,85.6 59.25,86.18 v1(59.25,86.18)
  L4 w0.152: v3(44.24,100.48) 43.98,100.48 43.29,101.18 43.29,101.93 42.31,102.91 42.06,102.91 41.89,102.74 41.89,102.51 42.05,102.36 42.05,102.17 41.77,101.89 41.77,101.7 41.9,101.56 42.09,101.56 42.37,101.85 42.56,101.85 42.67,101.73 42.67,100.03 43.05,99.65 43.05,96.82 49.77,90.1 49.77,89.71 52.05,87.42 52.05,86.86
  BOTTOM w0.089: U4500.AU38 59.47,86.61 59.25,86.39 v1(59.25,86.18) ; U4103.L1 32.63,99.22 32.63,99.79 v1(33.02,101.3) ; U4101.L1 47.76,112.59 48.45,112.59 v1(49.71,112.19) ; U4100.L1 60.8,112.58 61.49,112.58 v1(62.92,112.19) ; U4102.L1 32.42,85.67 32.44,85.69 32.62,86.02 32.62,86.74 v1(33.02,88.09)
M_A_DM<0>: length 15.3
  BOTTOM w0.102: U4500.AP52 61.22,94.85 61.38,95.01 61.38,99.85 62.08,100.55 62.08,101.34 v2(61.89,101.54) 61.89,101.68 61.76,101.81 61.76,102.77 62.29,103.29 62.54,103.29 62.8,103.55 62.8,105.77 62.34,106.22 62.34,106.62 U4100.D3
M_A_DM<1>: length 25.4
  L3 w0.124: v1(63.22,106.53) 62.49,105.8 62.49,105.34 61.14,104 61.14,101.82 60.46,101.14 60.46,100.03 60.04,99.61 60.04,96.99 60.14,96.89 60.32,96.89 60.47,97.04 60.47,99.43 60.59,99.55 60.77,99.55 60.89,99.43 60.89,96.74 59.24,95.09 59.24,93.12 v1(59.76,92.6)
  BOTTOM w0.089: U4500.AT48 60.24,91.74 59.76,92.22 v1(59.76,92.6)
  BOTTOM w0.102: v1(63.22,106.53) 63.53,106.84 63.53,106.98 64.74,108.19 U4100.E7
M_A_DM<2>: length 32.2
  L4 w0.089: 61.14,94.79 61.14,90.48 60.75,90.08 v1(60.75,89.96)
  L4 w0.124: 61.14,94.79 61.14,97.84 59.42,99.57 59.42,100.55 58.64,101.33 58.64,101.66 58.5,101.8 58.33,101.8 58.25,101.72 58.07,101.72 57.94,101.85 57.94,102.02 58.02,102.1 58.02,102.28 56.2,104.1 56.03,104.1 55.94,104.01 55.9,103.97 55.9,103.79 56.41,103.29 56.41,103.13 56.28,103.01 56.08,103.01 55.11,103.98 55.11,104.48 54.92,104.66 54.57,104.66 54.24,104.99 54.07,104.99 53.83,104.75 53.67,104.75 53.54,104.88 53.54,105.08 53.97,105.51 53.97,105.71 53.89,105.79 53.89,106.14 54.17,106.43 54.17,106.76 54.03,106.9 53.47,106.9 53.39,106.97 52.91,106.97 52.75,107.13 52.75,107.47 52.66,107.56 52.35,107.56 52.23,107.44 52.23,106.69 52.1,106.56 51.92,106.56 51.8,106.68 51.8,107.44 51.67,107.56 51.42,107.56 v3(51.15,107.28)
  BOTTOM w0.089: U4500.AP44 60.87,89.96 v1(60.75,89.96)
  BOTTOM w0.102: v3(51.15,107.28) 50.87,107.56 50.87,107.81 50.95,107.89 51.42,107.89 U4101.E7
M_A_DM<3>: length 17
  BOTTOM w0.102: U4101.D3 50.81,104.28 55.93,99.16 v2(56.21,98.88) 56.32,98.78 56.32,96.21 57.82,94.7 U4500.BA53
M_A_DM<4>: length 26.5
  BOTTOM w0.089: U4500.BG41 54.52,87.53 54.81,87.24 54.81,86.99 54.64,86.82 54.4,86.82 54.32,86.91 54.04,86.91 53.95,86.82 53.61,86.82 53.46,86.67 52.72,86.67 52.5,86.9 52.5,87 52.38,87.12 51.85,87.12
  BOTTOM w0.102: 51.85,87.12 51.38,87.12 v2(50.68,87.82) 50.68,87.94 46.65,91.98 45.78,91.98 41.4,96.35 41.4,99.75 40.61,100.54 38.41,100.54 U4103.D3
M_A_DM<5>: length 30.2
  L3 w0.124: v3(37.87,89.33) 38.29,88.91 40.35,88.91 40.5,88.77 40.5,88.59 40.4,88.49 38.17,88.49 38.04,88.36 38.04,88.18 38.17,88.06 42.32,88.06 44.09,89.82 45.76,89.82 49.4,86.18 54.37,86.18 54.99,85.56 57.29,85.56 v1(57.85,86.12)
  BOTTOM w0.089: v1(57.85,86.12) 57.85,86.09 58.26,85.67 U4500.AY36
  BOTTOM w0.102: v3(37.87,89.33) 37.1,90.1 U4102.E7
M_A_DM<6>: length 39.1
  L4 w0.089: v1(55.87,83.22) 55.77,83.22 55.37,83.63 52.03,83.63
  L4 w0.124: v1(37.19,102.25) 37.19,101.8 36.49,101.1 36.49,100.47 37.02,99.95 37.02,99.73 37.14,99.61 37.36,99.61 37.49,99.48 37.49,99.3 37.37,99.18 37.14,99.18 37.02,99.06 37.02,98.57 37.53,98.05 37.94,98.05 38.19,98.3 38.35,98.3 38.48,98.17 38.48,97.98 38.25,97.75 38.25,97.57 42.07,93.75 42.07,93.59 41.95,93.46 41.75,93.46 40.14,95.07 39.98,95.07 39.85,94.94 39.85,94.75 41.63,92.97 41.63,92.4 44.21,89.82 45.76,89.82 46.91,88.67 46.91,88.16 51.44,83.63 52.03,83.63
  BOTTOM w0.089: U4500.BD32 56.13,83.49 55.87,83.24 v1(55.87,83.22)
  BOTTOM w0.102: U4103.E7 37.02,102.42 v1(37.19,102.25)
M_A_DM<7>: length 21.4
  L4 w0.124: v1(47.28,82.45) 47.15,82.58 42.93,82.58 39.04,86.47 v1(39.02,86.47)
  BOTTOM w0.102: v1(39.02,86.47) 39.02,87.06 38.69,87.39 38.08,87.39 37.82,87.13 U4102.D3 ; v1(47.28,82.45) 46.67,82.45 46.47,82.65 46.47,83.04 46.63,83.2 48.32,83.2 48.79,82.72 54.15,82.72 U4500.BH30
M_A_DQ<0>: length 15.1
  BOTTOM w0.102: U4100.C8 65.96,106.2 65.96,104.27 65.42,103.73 65.42,100.48 v2(64.9,99.95) 63.77,98.82 63.77,97.03 63.46,96.73 63.46,95.15 63.24,94.92 63.24,94.6 63.36,94.47 63.36,93.93 63.45,93.84 63.45,93.58 63.16,93.29 U4500.AK51
M_A_DQ<1>: length 13.9
  BOTTOM w0.102: U4100.A7 64.77,104.53 64.62,104.38 64.54,104.38 64.39,104.23 64.39,104.02 64.54,103.87 64.62,103.87 64.77,103.72 64.77,103.51 64.62,103.36 64.54,103.36 64.39,103.21 64.39,103 64.54,102.86 64.62,102.86 64.77,102.71 64.77,102.5 64.62,102.35 64.54,102.35 64.39,102.2 64.39,101.99 64.54,101.84 64.62,101.84 64.77,101.69 64.77,101.13 63.89,100.25 63.89,100.06 v2(63.31,99.48) 62.78,98.95 62.78,94.42 62.95,94.25 62.95,93.92 62.68,93.64 U4500.AL51
M_A_DQ<2>: length 13.8
  BOTTOM w0.102: U4100.A2 59.37,103.59 59.37,98.81 59.47,98.71 59.77,98.71 59.88,98.61 59.88,98.3 59.77,98.2 59.47,98.2 59.4,98.13 v2(59.4,97.94) 59.4,97.77 59.47,97.7 59.77,97.7 59.88,97.59 59.88,97.29 59.77,97.19 59.47,97.19 59.37,97.09 59.37,95.93 59.96,95.33 59.96,95.17 60.23,94.91 60.23,93.72 U4500.AT52
M_A_DQ<3>: length 16.6
  BOTTOM w0.102: U4500.AR51 60.54,93.53 60.54,93.83 60.45,93.93 60.45,95.08 60.36,95.16 60.26,95.26 60.26,96.34 60.16,96.44 59.77,96.44 59.67,96.54 59.67,96.74 59.77,96.84 60.16,96.84 60.26,96.95 60.26,98.77 60.09,98.94 59.79,98.94 59.67,99.06 59.67,99.57 59.77,99.67 v2(59.96,99.67) 60.16,99.67 60.27,99.79 60.27,100.2 60.16,100.31 59.77,100.31 59.67,100.41 59.67,103.3 61.14,104.76 61.14,106.39 60.93,106.59 U4100.C2
M_A_DQ<4>: length 14.9
  BOTTOM w0.102: U4500.AL53 62.58,94.19 62.58,95.66 62.5,95.73 62.5,99.44 64.21,101.14 v2(64.21,101.37) 64.21,101.55 64.08,101.67 64.08,104.52 64.38,104.83 64.38,105.16 64.58,105.35 64.9,105.35 65.15,105.6 65.15,107.01 U4100.D7
M_A_DQ<5>: length 13.2
  BOTTOM w0.102: U4500.AK52 63.16,94.33 63.05,94.45 63.05,95.02 63.09,95.06 63.09,97.19 63.3,97.4 v2(63.3,98.1) 63.3,98.75 64.36,99.8 64.36,100.13 65.12,100.89 65.12,105.1 65.57,105.55 U4100.B8
M_A_DQ<6>: length 16.3
  BOTTOM w0.102: U4500.AR53 60.73,95.08 60.57,95.25 60.57,99.03 60.43,99.16 60.43,99.42 60.57,99.56 60.57,100.92 60.47,101.02 60.03,101.02 59.95,101.1 59.95,101.33 60.05,101.43 60.91,101.43 61.02,101.54 61.02,101.85 60.92,101.95 v2(60.53,101.95) 60.1,101.95 60,102.05 60,102.36 60.1,102.46 60.92,102.46 61.02,102.56 61.02,102.79 60.92,102.89 60.07,102.89 59.97,103 59.97,103.2 60.07,103.3 60.65,103.3 60.73,103.38 60.73,103.96 61.57,104.8 U4100.A3
M_A_DQ<7>: length 18
  BOTTOM w0.102: U4500.AP51 61.22,93.28 60.93,93.57 60.93,93.83 61.01,93.92 61.01,96 61.02,96.01 61.02,100.21 v2(61.18,100.37) 61.35,100.54 61.35,102.75 62.52,103.92 62.52,104.06 62.37,104.2 62.23,104.2 61.3,103.27 61.15,103.27 61.01,103.42 61.01,103.56 62.43,104.98 62.43,105.74 U4100.C3
M_A_DQ<8>: length 24.4
  L3 w0.124: v1(65.2,110.19) 65.2,110.19 64.72,109.7 64.72,108.96 64.84,108.83 65.11,108.83 65.23,108.71 65.23,108.53 65.11,108.4 64.94,108.4 64.45,107.91 64.45,107.69 64.45,107.69 64.58,107.56 65.13,107.56 65.25,107.44 65.25,107.26 65.12,107.13 64.58,107.13 64.45,107.01 64.45,106.83 64.58,106.7 65.13,106.7 65.25,106.58 65.25,106.41 65.12,106.28 64.58,106.28 64.45,106.15 64.45,105.59 63.21,104.35 63.21,96.99 61.16,94.93 61.16,92.5 v1(60.75,92.1)
  BOTTOM w0.089: v1(60.75,92.1) 61.11,91.74 U4500.AP48
  BOTTOM w0.102: v1(65.2,110.19) 65.57,110.56 U4100.H8
M_A_DQ<9>: length 26
  L3 w0.089: v3(59.76,91.54) 59.87,91.54 60.17,91.83 60.17,94.47 60.21,94.52 60.21,95.38
  L3 w0.124: v1(63.23,105.87) 63.23,105.65 61.44,103.87 61.44,97.67 61.55,97.57 61.72,97.57 61.87,97.72 61.87,100.18 62,100.31 62.18,100.31 62.3,100.19 62.3,97.47 60.21,95.38
  BOTTOM w0.089: U4100.E3 62.83,106.94 62.83,106.28 62.94,106.17 63.23,105.88 v1(63.23,105.87) ; v3(59.76,91.54) 59.8,91.5 59.8,91.46 60.23,91.03 U4500.AT47
M_A_DQ<10>: length 20.1
  L3 w0.124: v1(57.7,91.45) 57.64,91.45 56.92,92.16 56.92,100.37 58.68,102.12 58.68,106.41 58.88,106.69 59.8,107.97 60.37,108.54 60.37,108.57 v1(60.37,108.57)
  BOTTOM w0.089: U4500.AY48 58.09,91.74 57.8,91.45 v1(57.7,91.45)
  BOTTOM w0.102: v1(60.37,108.57) 60.77,108.97 U4100.F2
M_A_DQ<11>: length 20.2
  L3 w0.124: v3(58.77,92.85) 58.77,95.06 59.1,96.7 59.98,101.11 60.14,101.27 60.82,104.01 60.84,104.1 61.63,105.69 63.21,107.27 v1(63.21,107.51)
  BOTTOM w0.089: U4500.AV50 59.22,92.41 58.78,92.85 v3(58.77,92.85)
  BOTTOM w0.102: v1(63.21,107.51) 63.33,107.63 63.33,108.33 62.95,109.21 61.57,110.59 U4100.H3
M_A_DQ<12>: length 25.4
  L3 w0.124: v3(65.98,108.61) 65.56,108.19 65.56,106.28 63.51,104.23 63.51,103.93 63.64,103.81 63.97,103.81 64.1,103.68 64.1,103.5 63.97,103.38 63.64,103.38 63.51,103.25 63.51,103.07 63.64,102.95 63.97,102.95 64.1,102.82 64.1,102.64 63.97,102.52 63.64,102.52 63.51,102.39 63.51,102.22 63.64,102.09 63.97,102.09 64.1,101.96 64.1,101.79 63.97,101.66 63.64,101.66 63.51,101.53 63.51,101.36 63.64,101.23 63.97,101.23 64.1,101.11 64.1,100.93 63.97,100.8 63.64,100.8 63.51,100.68 63.51,100.5 63.64,100.37 63.97,100.37 64.1,100.25 64.1,100.07 63.97,99.94 63.64,99.94 63.51,99.82 63.51,95.96 62.01,94.46 62.01,92.16 61.32,91.47 v1(60.75,91.47)
  BOTTOM w0.089: U4500.AP47 61.19,91.03 v1(60.75,91.47)
  BOTTOM w0.102: v3(65.98,108.61) 65.76,108.61 65.57,108.8 U4100.F8
M_A_DQ<13>: length 23.5
  L3 w0.124: v3(64.15,108.29) 64.15,105.72 62.91,104.48 62.91,103.87 62.8,103.76 62.19,103.76 62.05,103.62 62.05,101.62 62.17,101.5 62.35,101.5 62.48,101.62 62.48,103.21 62.6,103.33 62.77,103.33 62.91,103.2 62.91,97.19 60.75,95.04 v1(60.75,92.81)
  BOTTOM w0.089: U4500.AT50 60.36,92.41 v1(60.75,92.81)
  BOTTOM w0.102: v3(64.15,108.29) 64.77,108.92 U4100.F7
M_A_DQ<14>: length 22.2
  L3 w0.124: v3(61.15,108.59) 61.14,108.59 61.14,107.97 60.57,107.39 60.09,107.39 58.98,106.29 58.98,102 57.23,100.24 57.23,99.42 57.35,99.3 57.53,99.3 57.65,99.17 57.65,98.99 57.53,98.87 57.35,98.87 57.23,98.74 57.23,98.56 57.35,98.44 57.53,98.44 57.65,98.32 57.65,98.13 57.53,98.01 57.35,98.01 57.23,97.89 57.23,97.71 57.35,97.58 57.53,97.58 57.65,97.46 57.65,97.28 57.53,97.15 57.35,97.15 57.23,97.03 57.23,92.7 v1(57.7,92.23)
  BOTTOM w0.089: U4500.AY50 57.91,92.41 57.73,92.23 v1(57.7,92.23)
  BOTTOM w0.102: U4100.G2 60.8,109.79 61.14,109.45 61.14,108.6 v3(61.15,108.59)
M_A_DQ<15>: length 24.6
  L3 w0.089: 60.42,95.16 60.42,94.45 60.36,94.39 60.36,91.25 v1(59.76,90.66)
  L3 w0.124: v1(64.23,109.33) 64.23,109.1 63.7,108.57 63.7,105.7 61.75,103.74 61.75,100.8 61.87,100.67 62.05,100.67 62.17,100.8 62.17,101.06 62.31,101.2 62.48,101.2 62.6,101.08 62.6,97.34 60.42,95.16
  BOTTOM w0.089: U4500.AV45 59.35,90.32 59.69,90.66 v1(59.76,90.66) ; U4100.H7 64.77,110.3 64.43,109.96 64.43,109.53 v1(64.23,109.33)
M_A_DQ<16>: length 33.3
  L4 w0.089: 62.48,95.27 62.48,94.17 61.73,93.42 61.73,88.9 60.8,87.97 v1(60.78,87.97)
  L4 w0.124: 62.48,95.27 62.48,95.64 62.39,95.73 62.23,95.73 62.1,95.87 62.1,96.19 62.22,96.31 62.35,96.31 62.48,96.44 62.48,96.62 62.35,96.74 62.22,96.74 62.1,96.86 62.1,97.05 62.22,97.17 62.36,97.17 62.48,97.29 62.48,97.54 62.1,97.92 62.1,98.17 60.32,99.94 60.32,100.93 59.55,101.71 59.55,102.14 59.23,102.46 58.83,102.86 58.83,103.26 58.5,103.58 58.1,103.58 57.85,103.84 57.85,104.02 58.08,104.25 58.08,104.41 57.95,104.54 57.77,104.54 57.54,104.32 57.37,104.32 57.1,104.59 57.1,104.83 v1(57.43,105.16)
  BOTTOM w0.089: U4101.H7 52.07,110.24 53.38,110.24 53.69,109.94 53.69,109.28 54.68,108.28 ; v1(60.78,87.97) 60.39,87.58 U4500.AT40
  BOTTOM w0.102: 54.68,108.28 55.5,107.47 55.64,107.47 55.9,107.72 56.04,107.72 56.18,107.58 56.18,107.43 55.93,107.18 55.93,107.04 56.07,106.89 56.22,106.89 56.47,107.15 56.62,107.15 56.76,107 56.76,106.86 56.5,106.6 56.5,106.46 57.43,105.53 v1(57.43,105.16)
M_A_DQ<17>: length 33.5
  L4 w0.089: v3(60.8,89.25) 61.35,89.8 61.35,93.67 62,94.32 62,94.89 61.5,95.4 61.5,95.53
  L4 w0.124: 61.5,95.53 61.5,97.91 59.72,99.69 59.72,100.68 58.94,101.46 58.94,101.89 58.8,102.03 54.8,106.03 54.8,106.57 54.17,107.2 53.59,107.2 52.93,107.86 51.23,107.86 49.7,109.39 49.7,109.99 48.38,111.31 47.55,111.31 47.3,111.05 47.3,109.44 v1(47.34,109.4)
  BOTTOM w0.089: U4500.AP42 60.87,89.25 v3(60.8,89.25)
  BOTTOM w0.102: U4101.G2 v1(47.34,109.4)
M_A_DQ<18>: length 27.9
  L4 w0.089: v1(60.13,87.05) 61,87.64 61.12,87.76 61.92,88.86 61.92,93.23 62.78,94.09
  L4 w0.124: 62.78,94.09 62.78,97.05 62.78,97.67 57.85,105.34 57.62,105.57 55.73,107.26 v1(52.91,108.58)
  BOTTOM w0.089: U4500.AT38 v1(60.13,87.05)
  BOTTOM w0.102: U4101.F8 52.52,108.98 v1(52.91,108.58)
M_A_DQ<19>: length 31.6
  L4 w0.089: v1(60.89,86.97) 60.95,86.97 62.16,88.19 62.16,93.09 63.08,94.01 63.08,95.94
  L4 w0.124: v3(57.43,106.37) 58,105.8 58.01,105.8 61.11,102.7 61.11,102.52 60.94,102.36 60.94,102.17 61.07,102.04 61.24,102.04 61.41,102.22 61.59,102.22 63.08,100.72 63.08,97.71 63.08,97.71 63.08,96.96 63.08,96.96 63.08,95.94
  BOTTOM w0.089: v1(60.89,86.97) 60.9,86.97 61.23,87.3 U4500.AP40
  BOTTOM w0.102: U4101.H8 52.88,110.96 53.5,110.96 54.65,109.81 55.04,109.81 57.43,107.42 v3(57.43,106.37)
M_A_DQ<20>: length 33.8
  L4 w0.089: v1(59.75,89.96) 59.36,90.35 59.36,93.79
  L4 w0.124: v3(49.95,106.77) 54.24,102.48 54.41,102.48 54.56,102.63 54.73,102.63 54.86,102.5 54.86,102.32 54.72,102.18 54.72,102 55.56,101.16 55.74,101.16 55.84,101.25 56.01,101.25 56.14,101.13 56.14,100.94 56.04,100.85 56.04,100.68 56.74,99.98 57.03,99.69 57.28,99.69 57.57,99.99 57.79,100.2 57.97,100.2 58.1,100.07 58.1,99.9 57.88,99.68 57.88,99.33 57.77,99.22 57.77,99.05 57.9,98.92 58.08,98.92 58.18,99.03 58.36,99.03 58.49,98.9 58.49,98.72 58.38,98.62 58.38,98.44 58.51,98.31 58.68,98.31 58.79,98.42 58.97,98.42 59.36,98.02 59.36,93.79
  BOTTOM w0.089: U4500.AT44 59.9,89.96 v1(59.75,89.96)
  BOTTOM w0.102: v3(49.95,106.77) 49.95,105.94 50.08,105.81 50.28,105.81 50.38,105.91 50.38,106.34 50.48,106.45 51.2,106.45 51.3,106.55 51.3,106.75 51.2,106.85 50.48,106.85 50.38,106.95 50.38,108.68 50.25,108.8 49.86,108.8 49.64,109.03 49.64,109.63 48.96,110.31 48.8,110.31 U4101.H3
M_A_DQ<21>: length 32.3
  L4 w0.089: 59.06,93.79 59.06,93.17 59.18,93.06 59.18,90.09 59.36,89.9 59.36,88.81 59.09,88.55 v3(58.77,88.55)
  L4 w0.124: 59.06,93.79 59.06,97.18 58.9,97.33 58.9,97.51 59.06,97.67 59.06,97.88 58.93,98 58.71,98 58.57,97.86 58.43,97.86 57.46,98.83 57.46,99.15 57.26,99.34 57.13,99.34 56.95,99.34 49.94,106.35 49.78,106.35 49.4,106.73 49.4,109.85 49.13,110.12 48.79,110.12 48.6,110.31 48.6,110.65 48.24,111.01 47.77,111.01 47.6,110.84 47.6,109.75 47.96,109.39 v1(48.11,109.39)
  BOTTOM w0.089: v3(58.77,88.55) 59.13,88.18 U4500.AV41
  BOTTOM w0.102: v1(48.11,109.39) 47.72,109 U4101.F2
M_A_DQ<22>: length 30
  L4 w0.089: v1(60.83,88.58) 61.54,89.28 61.54,93.59 62.18,94.23 62.18,95.12
  L4 w0.124: 62.18,95.12 61.8,95.49 61.8,98.04 60.02,99.82 60.02,100.8 59.24,101.58 59.24,102.01 56.57,104.69 56.57,104.86 57,105.29 57,105.47 56.3,106.18 56.12,106.18 55.99,106.05 55.99,105.87 56.2,105.66 56.2,105.5 56.08,105.37 55.89,105.37 55.1,106.15 55.1,106.89 54.49,107.51 53.75,107.51 53.09,108.16 51.54,108.16 v1(51.22,108.48)
  BOTTOM w0.089: v1(60.83,88.58) 61.23,88.18 U4500.AP41
  BOTTOM w0.102: U4101.F7 51.72,108.97 v1(51.22,108.48)
M_A_DQ<23>: length 33.5
  L4 w0.089: v1(58.81,89.23) 58.27,89.78 58.27,92.89 58.75,93.38
  L4 w0.124: 58.75,93.38 58.75,97.04 49.75,106.05 49.65,106.05 48.93,106.77 48.44,106.77 48.32,106.89 48.32,107.13 48.46,107.27 48.97,107.27 49.1,107.39 49.1,109.65 48.96,109.79 48.78,109.79 48.66,109.67 48.66,109.06 48.53,108.94 47.22,108.94 47.08,108.8 47.08,108.58 47.23,108.44 48.53,108.44 48.66,108.32 48.66,107.91 48.53,107.79 v1(48.14,107.79)
  BOTTOM w0.089: U4500.AV42 58.97,89.19 58.86,89.19 v1(58.81,89.23)
  BOTTOM w0.102: v1(48.14,107.79) 48.2,107.73 48.59,107.73 48.71,107.86 48.71,108.06 48.59,108.19 U4101.E3
M_A_DQ<24>: length 17.1
  BOTTOM w0.102: U4500.BD52 56.25,93.5 56.63,93.88 56.63,94.72 54.47,96.88 v2(54.47,97.22) 54.47,98.39 50.09,102.77 49.95,102.77 49.72,102.54 49.58,102.54 49.44,102.69 49.44,102.84 49.66,103.06 49.66,103.21 49.38,103.48 48.93,103.48 48.77,103.32 48.48,103.32 48.27,103.54 48.27,103.68 48.42,103.84 48.42,104.29 U4101.A2
M_A_DQ<25>: length 19.1
  BOTTOM w0.102: U4101.C8 52.52,106.59 52.92,106.18 53.46,106.18 54.16,105.49 55.27,105.49 56.61,104.15 56.61,103.13 56.71,103.03 56.92,103.03 57.02,103.13 57.02,103.53 57.12,103.63 57.32,103.63 57.42,103.53 57.42,102.72 57.32,102.62 56.71,102.62 56.61,102.52 56.61,102.33 58.4,100.54 v2(58.4,99.61) 58.4,96.06 59.2,95.26 59.2,94.46 59.27,94.39 U4500.AV52
M_A_DQ<26>: length 18.1
  BOTTOM w0.102: U4500.BC53 57.13,94.25 57.13,94.5 54.98,96.66 54.98,98.28 52.49,100.77 v2(52.49,101.09) 52.29,101.29 51.97,101.29 51.83,101.43 51.83,101.75 51.67,101.91 51.35,101.91 51.23,102.04 51.23,102.36 51.08,102.5 50.76,102.5 50.63,102.63 50.63,102.95 50.49,103.09 50.17,103.09 50.07,103.19 50.07,103.52 49.63,103.96 49.24,103.96 49.06,103.77 48.85,103.77 48.7,103.91 48.7,104.32 48.41,104.61 48.18,104.85 48.18,106.45 48.04,106.59 U4101.C2
M_A_DQ<27>: length 19.4
  BOTTOM w0.102: U4101.D7 52.17,106.94 53.96,106.94 55.14,105.77 55.98,105.77 56.21,105.77 57.7,104.28 57.7,101.99 v2(58.34,101.35) 58.89,100.8 58.89,95.93 59.43,95.39 59.43,94.52 59.48,94.47 59.48,93.92 59.57,93.84 59.57,93.58 59.27,93.28 U4500.AV51
M_A_DQ<28>: length 19.2
  BOTTOM w0.102: U4101.B8 52.95,105.37 52.95,104.87 53.18,104.64 55.72,104.64 56.33,104.03 56.33,103.24 56.22,103.13 56.02,103.13 55.92,103.22 55.92,103.58 55.83,103.68 55.62,103.68 55.52,103.57 55.52,102.37 55.62,102.27 56.27,102.27 57.65,100.89 57.74,100.8 57.74,97.75 v2(57.92,97.57) 57.92,96.19 58.97,95.14 58.97,94.4 59.07,94.3 59.07,93.93 58.79,93.65 U4500.AW51
M_A_DQ<29>: length 17.8
  BOTTOM w0.102: U4101.A3 48.55,105.02 49.08,105.02 49.19,104.91 49.19,104.75 48.95,104.51 48.95,104.37 49.1,104.23 49.24,104.23 49.45,104.43 49.57,104.43 52.4,101.6 52.7,101.6 53.02,101.29 53.02,100.64 53.97,99.68 54.11,99.68 54.29,99.86 54.43,99.86 54.58,99.72 54.58,99.57 54.4,99.39 54.4,99.26 54.54,99.12 v2(54.86,99.12) 55.05,99.12 55.25,98.93 55.25,96.68 57.33,94.59 57.33,93.92 57.26,93.84 57.26,93.7 57.08,93.52 U4500.BC52
M_A_DQ<30>: length 17.2
  BOTTOM w0.102: U4500.AW53 58.79,94.13 58.75,94.17 58.75,94.99 57.45,96.29 57.45,100.41 57.31,100.55 v2(57.04,100.82) 55.87,101.99 54.72,101.99 54.58,102.13 54.58,102.27 55,102.7 55,102.84 54.86,102.98 54.72,102.98 54.29,102.56 54.15,102.56 54.01,102.7 54.01,102.85 54.43,103.27 54.43,103.41 54.28,103.56 54.14,103.56 53.72,103.14 53.58,103.14 U4101.A7
M_A_DQ<31>: length 19.1
  BOTTOM w0.102: U4101.C3 48.52,106.42 49.78,105.16 49.78,104.71 52.6,101.88 52.82,101.88 53.45,101.25 53.45,101.11 53.32,100.98 53.32,100.84 53.47,100.7 53.61,100.7 53.73,100.82 53.88,100.82 54.02,100.68 54.02,100.53 53.9,100.41 53.9,100.27 54.04,100.12 54.19,100.12 54.31,100.25 54.45,100.25 55.53,99.17 55.53,98.23 55.63,98.13 55.88,98.13 55.99,98.02 55.99,97.81 55.9,97.72 55.63,97.72 55.53,97.62 55.53,97.42 v2(55.77,97.18) 55.77,96.47 57.54,94.7 57.54,93.83 57.46,93.76 57.46,93.34 57.33,93.21 U4500.BB51
M_A_DQ<32>: length 26.7
  BOTTOM w0.102: U4500.BG42 54.59,88.56 54.3,88.86 54.04,88.86 53.95,88.77 53.45,88.77 53.41,88.72 52.78,88.72 52.17,89.33 51.64,89.33 46.13,94.84 45.73,94.84 45.44,95.14 45.44,95.54 43.05,97.92 43.05,100.44 42.47,101.03 42.47,101.17 42.63,101.34 42.63,101.48 42.49,101.62 42.34,101.62 42.18,101.46 42.03,101.46 41.78,101.72 41.78,101.88 42.2,102.31 42.2,102.46 41.78,102.89 41.78,103.3 40.98,104.1 40.6,104.1 40.33,104.37 39.15,104.37 38.73,103.95 U4103.C8
M_A_DQ<33>: length 26.8
  BOTTOM w0.102: U4500.BG43 54,89.26 53.94,89.33 53.34,89.33 53.15,89.52 51.85,89.52 48.94,92.42 48.94,92.43 48.39,92.98 48.38,92.98 43.51,97.86 43.41,98.34 43.33,98.69 43.33,100.72 42.06,103.43 41.34,104.5 40.74,105.1 39.28,105.1 38.97,104.79 38.97,104.55 38.76,104.35 38.48,104.35 38.22,104.08 38.22,103.71 U4103.D7
M_A_DQ<34>: length 28.5
  BOTTOM w0.102: U4500.BG37 54.23,86.14 53.95,85.86 52.56,85.86 52.13,86.28 50.45,86.28 v2(50.03,86.71) 48.26,88.48 48.26,89.19 46.3,91.14 44.28,91.14 39.75,95.67 39.75,96.35 39.65,96.45 39.04,96.45 38.94,96.55 38.94,96.93 39.04,97.03 39.24,97.03 39.41,96.86 39.65,96.86 39.75,96.96 39.75,97.26 39.85,97.36 40.06,97.36 40.16,97.26 40.16,95.83 40.27,95.72 40.48,95.72 40.56,95.81 40.56,98.81 U4103.A2
M_A_DQ<35>: length 26.8
  BOTTOM w0.102: U4500.BJ37 52.69,86.14 52.25,86.58 50.89,86.58 v2(48.83,88.64) 48.55,88.91 48.55,89.28 46.42,91.42 44.39,91.42 42.78,93.04 42.78,93.18 42.92,93.32 43.06,93.32 44.15,92.24 44.31,92.24 44.45,92.38 44.45,92.51 43.06,93.9 42.92,93.9 42.49,93.47 42.34,93.47 40.84,94.97 40.84,99.33 U4103.A3
M_A_DQ<36>: length 24.7
  BOTTOM w0.102: U4103.B8 39.61,103.95 40.06,103.5 40.42,103.5 40.89,103.03 40.89,102.21 42.77,100.33 42.77,97.81 45.16,95.42 45.16,94.54 45.57,94.13 45.72,94.13 46,94.41 46.14,94.41 46.28,94.26 46.28,94.12 46,93.84 46,93.7 46.13,93.57 47,93.57 47.36,93.22 52.19,88.39 53.99,88.39 U4500.BH42
M_A_DQ<37>: length 24.9
  BOTTOM w0.102: U4500.BJ41 52.1,88.08 47.12,93.07 46.23,93.07 44.5,94.79 44.5,95.68 44.32,95.87 44.17,95.87 43.9,95.59 43.75,95.59 43.61,95.73 43.61,95.88 43.89,96.15 43.89,96.3 43.74,96.44 43.6,96.44 43.35,96.2 43.21,96.2 43.07,96.34 43.07,96.48 43.31,96.73 43.31,96.87 43.17,97.02 43.02,97.02 42.78,96.77 42.64,96.77 42.49,96.92 42.49,97.06 42.74,97.3 42.74,97.45 42.49,97.69 42.49,100.21 40.32,102.38 40.32,103.06 U4103.A7
M_A_DQ<38>: length 27.2
  BOTTOM w0.102: U4500.BH36 52.33,85.65 51.98,86 50.02,86 v2(48.81,87.21) 47.98,88.04 47.98,89.07 46.19,90.86 44.16,90.86 43.7,91.32 43.55,91.32 43.4,91.17 43.26,91.17 43.11,91.31 43.11,91.46 43.27,91.61 43.27,91.76 43.12,91.9 42.98,91.9 42.83,91.74 42.68,91.74 42.54,91.89 42.54,92.03 42.69,92.19 42.69,92.33 42.55,92.47 42.4,92.47 42.25,92.32 42.11,92.32 41.96,92.46 41.96,92.61 42.12,92.76 42.12,92.91 41.97,93.05 41.83,93.05 41.68,92.89 41.53,92.89 41.39,93.04 41.39,93.18 41.54,93.34 41.54,93.48 41.4,93.62 41.25,93.62 41.1,93.47 40.96,93.47 40.81,93.61 40.81,93.76 40.97,93.91 40.97,94.06 40.82,94.2 40.68,94.2 40.53,94.04 40.38,94.04 40.24,94.19 40.24,94.33 40.39,94.49 40.39,94.63 38.66,96.36 38.66,97.91 38.97,98.21 38.97,98.81 38.62,99.15 U4103.C2
M_A_DQ<39>: length 27.9
  BOTTOM w0.102: U4103.C3 39,100.33 40.36,100.33 41.12,99.56 41.12,95.08 42.19,94.01 42.34,94.01 42.48,94.16 42.48,94.3 41.53,95.25 41.53,95.4 41.67,95.55 41.81,95.55 45.08,92.28 45.08,91.96 45.34,91.7 46.53,91.7 50.1,88.14 50.1,87.69 50.97,86.82 52.3,86.82 52.64,86.47 54.01,86.47 U4500.BH38
M_A_DQ<40>: length 30.1
  L3 w0.089: 55.65,86.68 55.92,86.68 v1(56.48,86.12)
  L3 w0.124: 55.65,86.68 55.6,86.68 54.21,88.07 53.84,88.07 53.64,88.27 53.41,88.27 53.21,88.07 52.98,88.07 52.78,88.27 52.55,88.27 52.35,88.07 52.12,88.07 51.92,88.27 51.69,88.27 51.49,88.07 51.26,88.07 51.06,88.27 50.84,88.27 50.63,88.07 50.31,88.07 50.04,88.34 49.66,88.34 49.39,88.07 48.96,88.07 48.81,88.21 48.81,88.45 49.01,88.65 49.01,88.83 48.88,88.96 48.71,88.96 48.4,88.64 48.22,88.64 48.09,88.77 48.09,88.95 48.4,89.26 48.4,89.44 48.28,89.56 48.1,89.56 47.79,89.25 47.61,89.25 47.48,89.38 47.48,89.56 47.8,89.87 47.8,90.04 47.67,90.17 47.49,90.17 47.18,89.86 47,89.86 46.88,89.99 46.88,90.16 47.19,90.48 47.19,90.65 47.06,90.78 46.89,90.78 46.57,90.47 46.4,90.47 46.27,90.59 46.27,90.77 46.58,91.08 46.58,91.26 46.45,91.39 46.28,91.39 45.97,91.07 45.79,91.07 45.42,91.44 39.55,91.44 39.3,91.2 38.94,91.2 38.69,91.44 38.14,91.44 37.43,90.74 v1(37.43,90.5)
  BOTTOM w0.089: v1(56.48,86.12) 56.84,85.76 U4500.BC36
  BOTTOM w0.102: v1(37.43,90.5) 36.62,90.5 U4102.F8
M_A_DQ<41>: length 29.8
  L3 w0.089: v1(57.19,86.12) 56.75,86.56 56.75,87.29 56.37,87.66 56.15,87.66
  L3 w0.124: v1(35,91.3) 36.01,91.3 36.48,91.77 46.52,91.77 49.65,88.64 50.02,88.64 50.15,88.77 50.15,89.24 50.27,89.36 50.45,89.36 50.58,89.24 50.58,88.77 50.7,88.64 50.88,88.64 51.01,88.77 51.01,89.24 51.13,89.36 51.31,89.36 51.44,89.24 51.44,88.77 51.56,88.64 51.74,88.64 51.87,88.77 51.87,89.24 51.99,89.36 52.17,89.36 52.29,89.24 52.29,88.77 52.42,88.64 54.06,88.64 55.04,87.66 56.15,87.66
  BOTTOM w0.089: U4500.BA36 57.55,85.76 v1(57.19,86.12)
  BOTTOM w0.102: v1(35,91.3) 34.62,90.93 U4102.H8
M_A_DQ<42>: length 29.7
  L3 w0.089: v3(59.86,84.21) 59.84,84.18 59.84,84.03 59.44,83.63 54.24,83.63
  L3 w0.124: v1(36.61,85.69) 37.16,85.69 37.87,84.99 38.57,84.99 38.89,85.31 41.63,85.31 41.75,85.44 41.75,86.03 41.89,86.17 42.07,86.17 42.18,86.06 42.18,85.44 42.31,85.31 43.09,85.31 43.21,85.2 43.21,85.02 43.07,84.88 42.34,84.88 42.21,84.76 42.21,84.58 42.34,84.45 43.51,84.45 43.8,84.75 51.54,84.75 52.66,83.63 54.24,83.63
  BOTTOM w0.089: U4500.AU34 59.68,84.38 v3(59.86,84.21)
  BOTTOM w0.102: v1(36.61,85.69) 36.22,86.08 U4102.F2
M_A_DQ<43>: length 28.8
  L3 w0.089: v1(59.33,83.22) 58.76,82.66 54.9,82.66 54.71,82.48 53.97,82.48
  L3 w0.124: v1(35.03,86.49) 35.41,86.11 35.41,85.52 37.32,83.61 43.55,83.61 43.93,83.23 50.08,83.23 50.2,83.36 50.2,83.49 50.33,83.62 50.51,83.62 50.63,83.49 50.63,83.36 50.76,83.23 50.94,83.23 51.06,83.36 51.06,83.49 51.19,83.62 51.37,83.62 51.49,83.49 51.49,83.36 51.62,83.23 52.07,83.23 52.82,82.48 53.97,82.48
  BOTTOM w0.089: U4500.AU32 59.68,83.58 v1(59.33,83.22)
  BOTTOM w0.102: U4102.H3 v1(35.03,86.49)
M_A_DQ<44>: length 29
  L3 w0.124: v1(55.06,86.16) 53.76,87.46 52.59,87.46 52.48,87.35 52.48,86.75 52.34,86.6 49.45,86.6 49.33,86.73 49.33,86.91 49.45,87.03 51.91,87.03 52.05,87.18 52.05,87.35 51.94,87.46 48.55,87.46 45.88,90.13 43.22,90.13 43.09,90 43.09,89.86 42.97,89.74 42.79,89.74 42.66,89.86 42.66,90 42.54,90.13 40.92,90.13 40.57,89.78 36.82,89.78 v3(36.56,89.52)
  BOTTOM w0.089: U4500.BF36 55.45,85.77 v1(55.06,86.16)
  BOTTOM w0.102: U4102.F7 36.22,89.87 v3(36.56,89.52)
M_A_DQ<45>: length 28.4
  L3 w0.124: v1(35.03,90.5) 35.45,90.08 40.35,90.08 40.7,90.43 41.31,90.43 41.43,90.55 41.43,90.89 41.56,91.02 41.74,91.02 41.86,90.89 41.86,90.55 41.99,90.43 42.17,90.43 42.29,90.55 42.29,90.89 42.42,91.02 42.6,91.02 42.72,90.89 42.72,90.55 42.85,90.43 43.03,90.43 43.15,90.55 43.15,90.89 43.28,91.02 43.45,91.02 43.58,90.89 43.58,90.55 43.71,90.43 43.88,90.43 44.01,90.55 44.01,90.89 44.14,91.02 44.31,91.02 44.44,90.89 44.44,90.55 44.56,90.43 44.74,90.43 44.87,90.55 44.87,90.89 44.99,91.02 45.17,91.02 45.3,90.89 45.3,90.55 45.42,90.43 46.01,90.43 48.67,87.77 54.11,87.77 55.76,86.12 v3(55.77,86.12)
  BOTTOM w0.089: v3(55.77,86.12) 56.13,85.76 U4500.BD36
  BOTTOM w0.102: v1(35.03,90.5) 34.63,90.1 U4102.H7
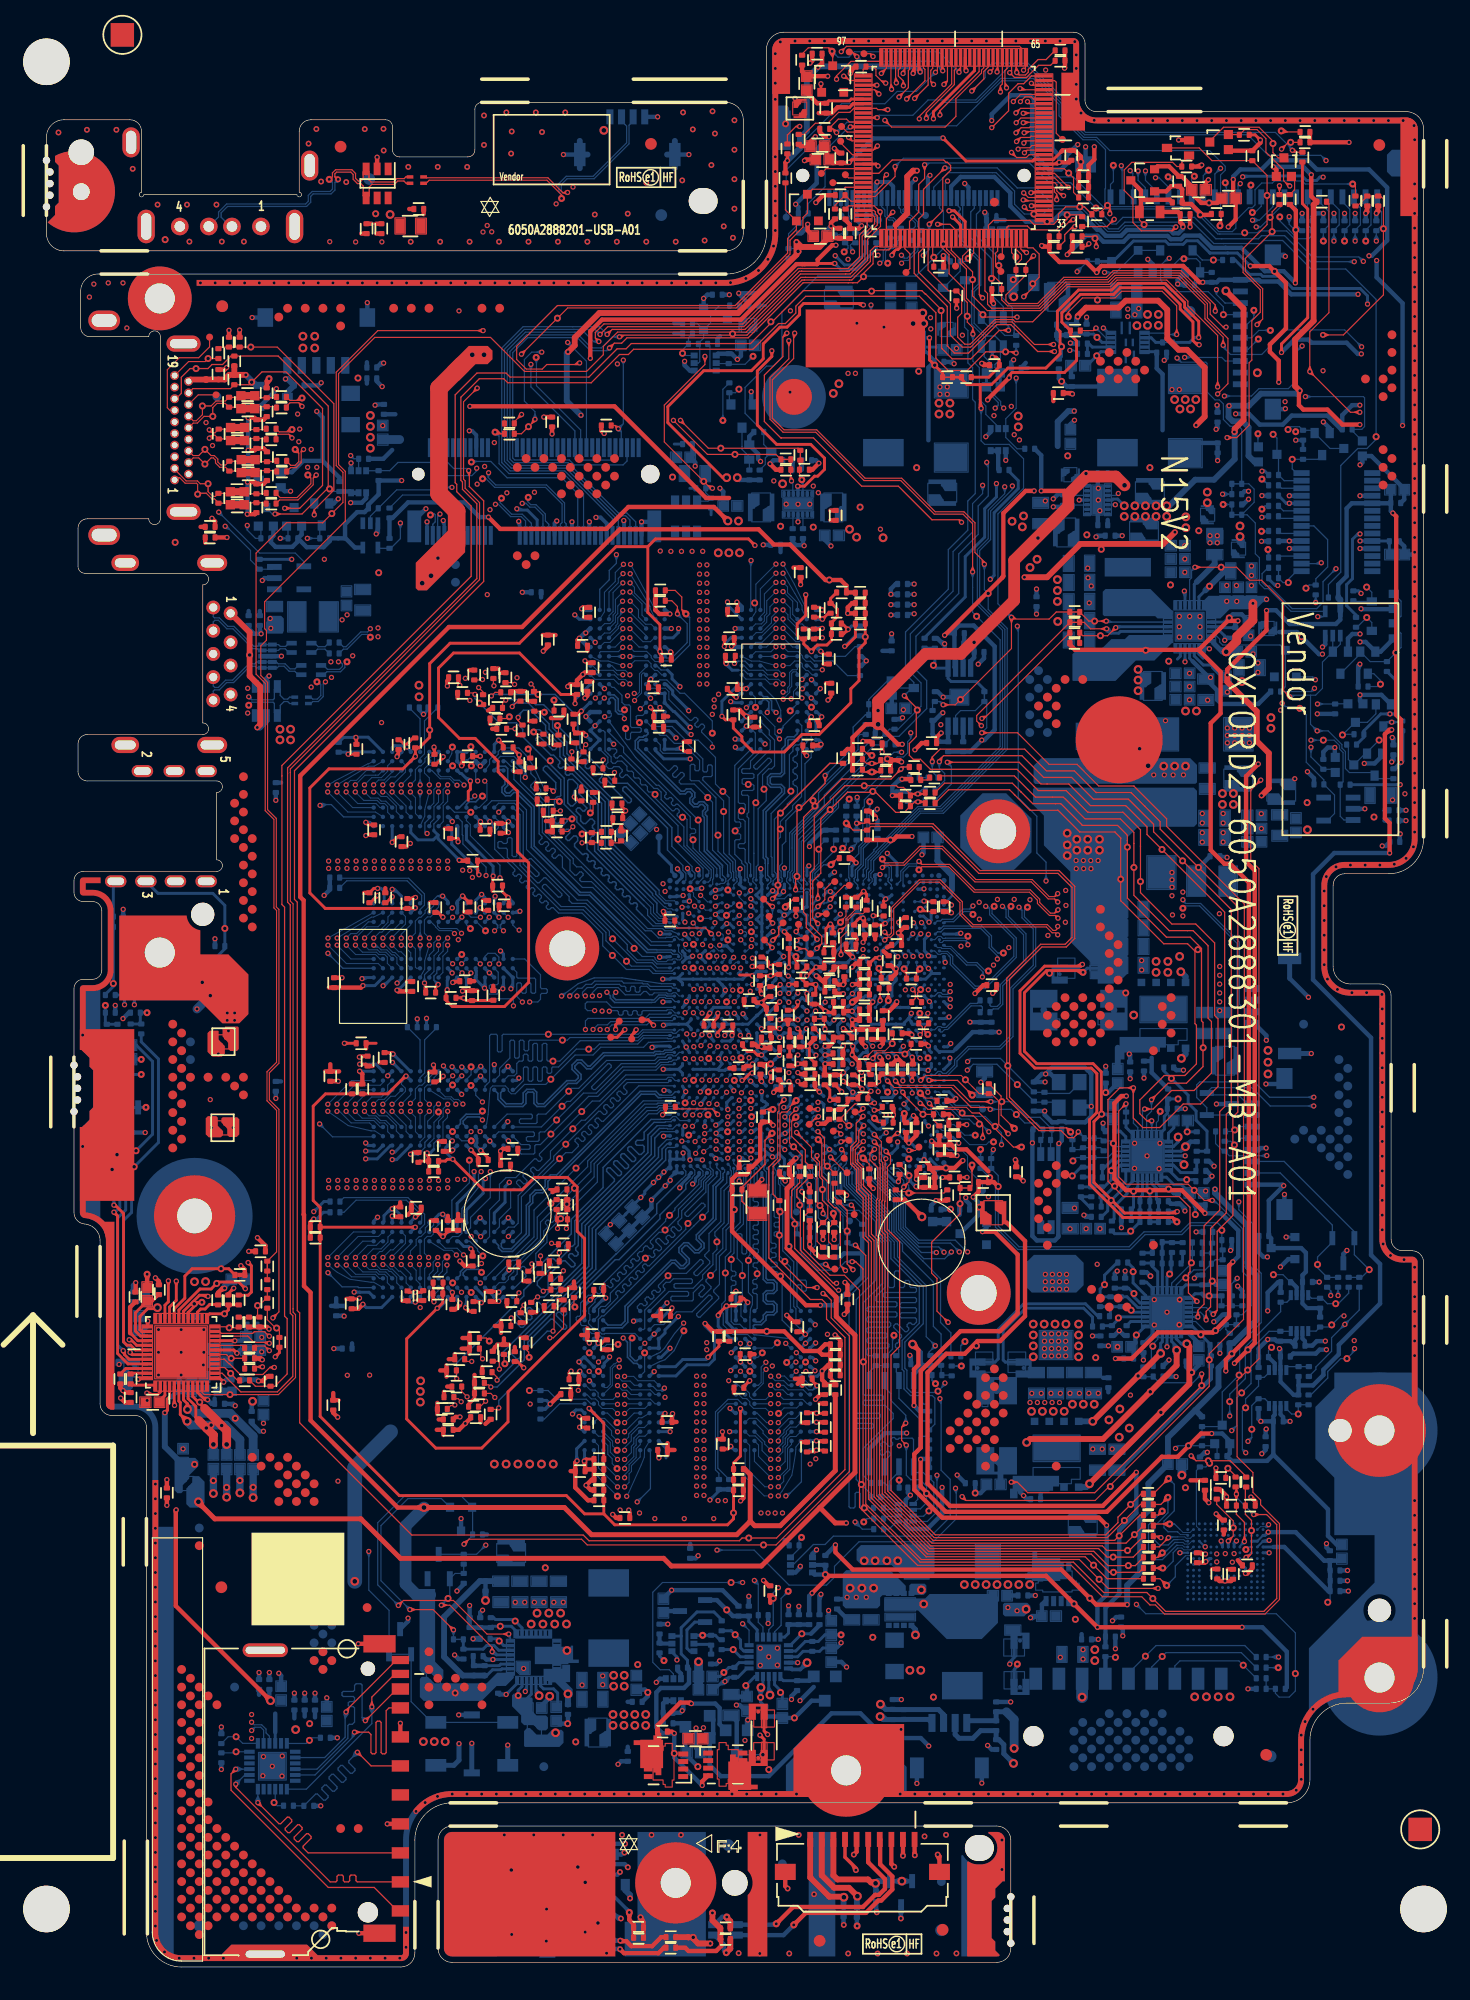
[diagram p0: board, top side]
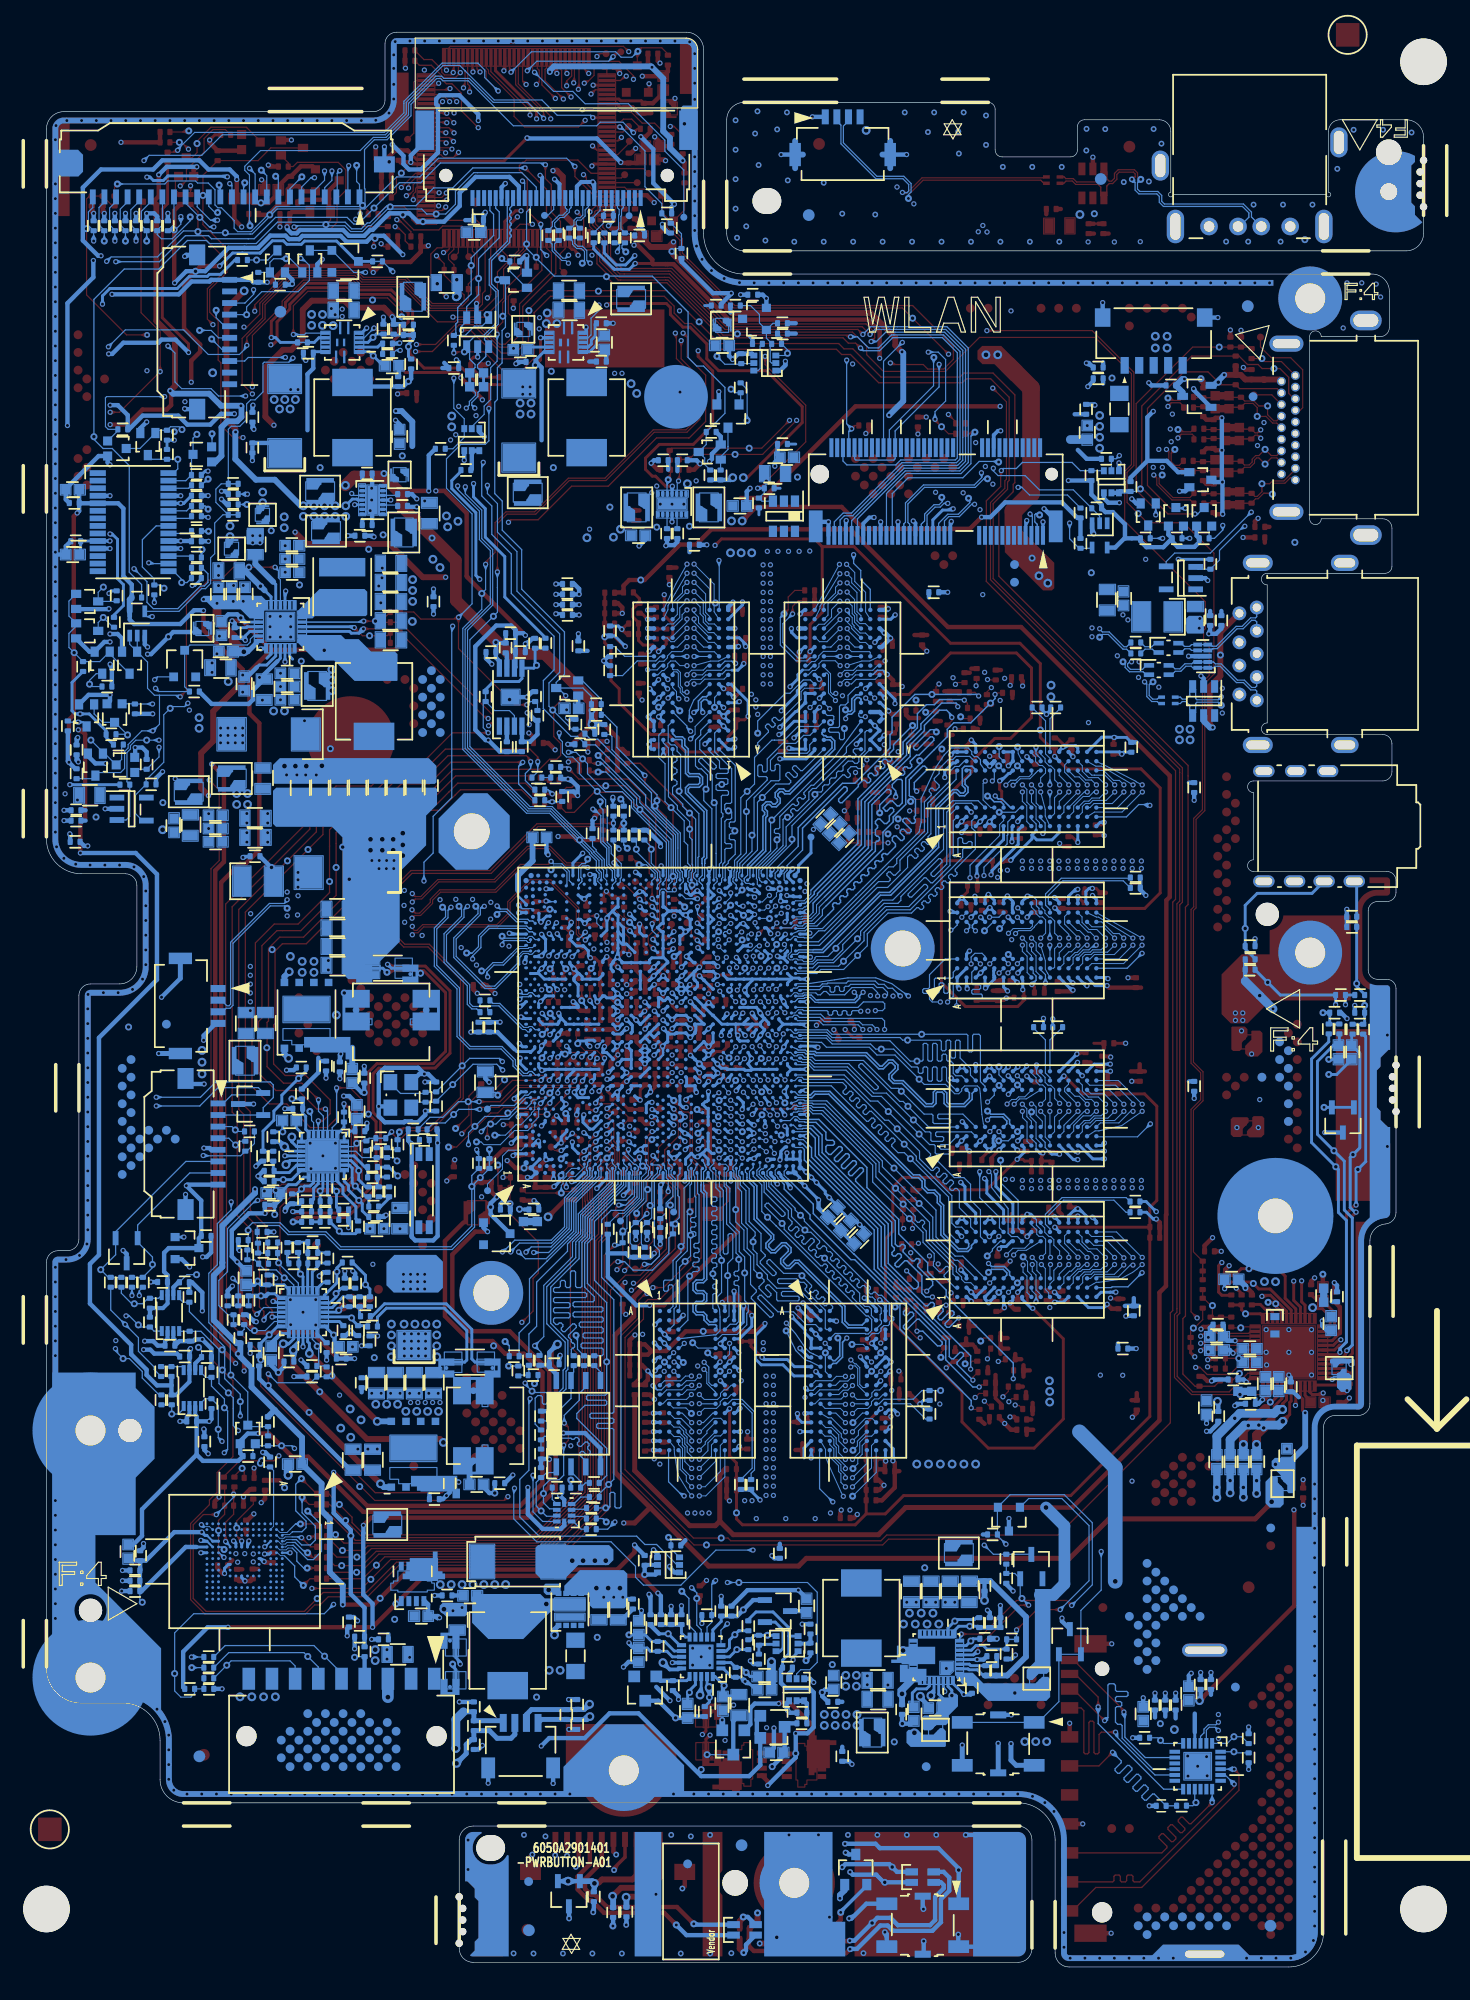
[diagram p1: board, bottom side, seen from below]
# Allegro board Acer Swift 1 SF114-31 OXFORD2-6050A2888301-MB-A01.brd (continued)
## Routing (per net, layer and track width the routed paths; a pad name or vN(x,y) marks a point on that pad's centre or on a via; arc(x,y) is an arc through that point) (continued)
M_A_DQ<46>: length 29.2
  L3 w0.089: v1(59.19,84.22) 59.19,84.11 58.9,83.82 54.82,83.82 54.71,83.93 53.9,83.93
  L3 w0.124: 53.9,83.93 52.79,83.93 51.66,85.05 43.79,85.05 42.36,86.47 39.55,86.47 39.44,86.36 39.44,86.18 39.57,86.04 41.01,86.04 41.15,85.91 41.15,85.73 41.04,85.62 38.77,85.62 38.44,85.29 37.99,85.29 37.42,85.86 v1(37.42,86.48)
  BOTTOM w0.089: v1(59.19,84.22) 59.19,84.23 58.97,84.45 U4500.AV34
  BOTTOM w0.102: v1(37.42,86.48) 37.02,86.87 U4102.E3
M_A_DQ<47>: length 30.1
  L3 w0.089: 53.9,82.78 54.6,82.78 54.65,82.83 58.34,82.83 58.66,83.16 v3(58.66,83.2)
  L3 w0.124: 53.9,82.78 52.99,82.78 51.32,84.45 51.05,84.45 50.92,84.32 50.92,84.19 50.8,84.07 50.62,84.07 50.49,84.19 50.49,84.32 50.37,84.45 50.19,84.45 50.06,84.32 50.06,84.19 49.94,84.07 49.76,84.07 49.63,84.19 49.63,84.32 49.51,84.45 43.93,84.45 43.39,83.91 42.05,83.91 41.91,84.06 41.91,84.66 41.8,84.77 40.58,84.77 40.46,84.65 40.46,84.47 40.58,84.34 41.37,84.34 41.48,84.24 41.48,84.06 41.34,83.91 37.63,83.91 v1(35.85,85.7)
  BOTTOM w0.089: U4500.AV32 58.97,83.57 58.66,83.25 v3(58.66,83.2)
  BOTTOM w0.102: U4102.G2 35.45,86.1 v1(35.85,85.7)
M_A_DQ<48>: length 37.2
  L4 w0.089: 51.47,85.29 51.67,85.08 52.44,85.08 52.99,84.52 55.59,84.52 v1(55.84,84.27)
  L4 w0.124: v1(37.8,102.24) 37.97,102.24 38.26,101.94 38.26,101.75 38.02,101.51 38.02,100.97 38.94,100.05 39.11,100.05 39.24,100.18 39.24,100.36 38.45,101.15 38.45,101.33 38.58,101.46 38.75,101.46 39.85,100.36 39.85,100.18 39.43,99.76 39.43,99.57 39.56,99.45 39.72,99.45 40.15,99.88 40.33,99.88 40.46,99.75 40.46,99.58 40.19,99.31 40.19,99.17 40.46,98.9 40.46,98.64 40.33,98.52 40.19,98.52 40.07,98.39 40.07,98.21 40.19,98.09 40.33,98.09 40.46,97.96 40.46,97.78 40.21,97.53 40.21,97.21 48.04,89.38 48.04,88.71 51.47,85.29
  BOTTOM w0.089: 37.33,99.95 37.99,100.61 37.99,102.04 37.8,102.22 v1(37.8,102.24) ; v1(55.84,84.27) 55.45,84.66 U4500.BF34
  BOTTOM w0.102: U4103.E3 37.33,99.95 37.33,99.95
M_A_DQ<49>: length 37.5
  L4 w0.089: v1(57.13,84.27) 56.53,84.88 54.04,84.88 53.37,85.55 52.06,85.55 51.77,85.84
  L4 w0.124: v3(36.64,103.55) 36.32,103.55 36.21,103.45 36.21,103.12 36.34,102.99 38.07,102.99 41.06,100 41.06,99.63 41.16,99.53 41.53,99.53 41.92,99.14 41.92,97.38 41.8,97.26 41.62,97.26 41.49,97.39 41.49,98.96 41.36,99.1 41.17,99.1 41.06,98.99 41.06,97.21 48.64,89.63 48.64,88.96 51.77,85.84
  BOTTOM w0.089: U4500.BC34 56.84,84.57 v1(57.13,84.27)
  BOTTOM w0.102: v3(36.64,103.55) 36.64,103.55 36.64,103.52 36.27,103.15 U4103.F7
M_A_DQ<50>: length 36.7
  L4 w0.089: v1(57.88,83.22) 58.17,83.51 58.17,84.5 57.44,85.23 54.29,85.23 53.62,85.91 52.56,85.91 52.17,86.29
  L4 w0.124: v3(36.6,105.2) 37.19,105.2 37.86,104.54 37.86,104.11 38.34,103.63 38.51,103.63 38.72,103.83 38.89,103.83 39.01,103.71 39.01,103.52 38.82,103.32 38.82,103.15 42.53,99.44 42.53,96.6 49.25,89.88 49.25,89.49 51.6,87.14 51.6,86.86 52.17,86.29
  BOTTOM w0.089: v1(57.88,83.22) 57.55,83.55 U4500.BA32
  BOTTOM w0.102: v3(36.6,105.2) 36.6,104.34 U4103.F8
M_A_DQ<51>: length 38.2
  L4 w0.089: 51.26,83.37 51.82,82.81 53.63,82.81 53.65,82.83 55.94,82.83 v1(56.55,82.23)
  L4 w0.124: 51.26,83.37 50.94,83.69 48.84,85.79 44.09,85.79 42.9,86.97 42.9,90.7 41.33,92.27 41.33,92.85 37.94,96.24 37.94,96.42 38.07,96.55 38.24,96.55 39.55,95.24 39.71,95.24 39.84,95.36 39.84,95.55 37.71,97.68 37.48,97.68 36.62,98.53 36.62,99.53 v3(36.6,99.55)
  BOTTOM w0.089: v1(56.55,82.23) 56.13,82.65 U4500.BD30
  BOTTOM w0.102: v3(36.6,99.55) 35.19,99.55 34.79,99.95 U4103.H3
M_A_DQ<52>: length 37.4
  L4 w0.089: v1(56.49,84.31) 56.1,84.7 53.07,84.7 52.51,85.26 51.92,85.26 51.65,85.53
  L4 w0.124: 51.65,85.53 48.34,88.84 48.34,89.51 40.76,97.08 40.76,99.87 37.94,102.69 32.93,102.69 32.74,102.88 32.74,103.39 32.9,103.55 v3(35.02,103.55)
  BOTTOM w0.089: U4500.BD34 56.13,84.67 v1(56.49,84.31)
  BOTTOM w0.102: v3(35.02,103.55) 34.63,103.15 U4103.H7
M_A_DQ<53>: length 35
  L4 w0.089: v1(57.78,84.24) 57.33,84.69 56.6,85.06 54.2,85.06 53.53,85.73 52.31,85.73 52.07,85.97
  L4 w0.124: 52.07,85.97 51.3,86.73 48.95,89.37 48.95,89.76 42.22,96.48 42.22,99.31 37.58,103.96 37.31,103.96 v3(35.01,105.17)
  BOTTOM w0.089: U4103.H8 34.96,104.61 v3(35.01,105.17) ; U4500.BA34 v1(57.78,84.24)
M_A_DQ<54>: length 38.9
  L4 w0.089: 51.56,82.4 54.96,82.4 v1(55.08,82.27)
  L4 w0.124: 51.56,82.4 51.33,82.4 50.9,82.83 50.72,82.83 50.29,82.4 50.12,82.4 49.32,83.2 49.32,83.37 49.44,83.5 49.62,83.5 50.12,83 50.29,83 50.42,83.13 50.42,83.31 48.54,85.18 43.84,85.18 42.3,86.72 42.3,89.06 41.06,90.3 41.06,90.58 41.43,90.95 41.43,91.28 40.94,91.78 40.49,91.78 40.36,91.65 40.36,91.36 40.24,91.23 40.06,91.23 39.93,91.36 39.93,91.65 39.81,91.78 39.63,91.78 39.5,91.65 39.5,91.36 39.38,91.23 39.2,91.23 39.08,91.36 39.08,91.65 38.95,91.78 38.64,91.78 38.15,92.26 38.15,92.93 38.03,93.05 37.17,93.05 37.05,93.18 37.05,93.36 37.17,93.48 38.03,93.48 38.15,93.61 38.15,93.85 v1(37.92,94.09)
  BOTTOM w0.089: U4500.BF30 55.45,82.62 55.1,82.27 v1(55.08,82.27)
  BOTTOM w0.102: v1(37.92,94.09) 37.92,94.82 35.92,96.82 35.92,97.55 35.86,97.61 35.86,98.72 U4103.G2
M_A_DQ<55>: length 37.7
  L4 w0.089: v1(55.8,82.27) 55.75,82.27 55.36,82.66 53.75,82.66 53.72,82.63 51.55,82.63 50.9,83.28
  L4 w0.124: v1(39.11,93.9) 39.42,94.21 39.54,94.21 39.71,94.04 39.71,93.86 38.79,92.93 38.79,92.79 38.92,92.66 39.13,92.66 40.02,93.56 40.19,93.56 40.32,93.43 40.32,93.25 39.98,92.91 39.98,92.74 40.11,92.61 40.29,92.61 40.63,92.95 40.8,92.95 41.03,92.72 41.03,92.15 41.96,91.21 41.96,91.04 41.48,90.55 41.48,90.38 41.61,90.25 41.79,90.25 42.27,90.73 42.44,90.73 42.6,90.57 42.6,90.16 42.48,90.03 42.19,90.03 42.06,89.9 42.06,89.72 42.18,89.6 42.48,89.6 42.6,89.48 42.6,86.84 43.96,85.49 48.7,85.49 50.9,83.28
  BOTTOM w0.089: 37.23,96.87 36.56,97.54 36.56,98.49 36.22,98.83 ; U4500.BD28 56.19,81.81 55.8,82.2 v1(55.8,82.27)
  BOTTOM w0.102: U4103.F2 36.22,98.83 36.22,98.83 ; v1(39.11,93.9) 39.11,94.98 37.23,96.87
M_A_DQ<56>: length 21.4
  L4 w0.124: v1(46.48,83.72) 46.51,83.72 46.77,83.98 46.77,84.31 46.63,84.45 46.14,84.45 46.01,84.33 46.01,84.26 45.89,84.14 45.71,84.14 45.58,84.26 45.58,84.33 45.46,84.45 43.53,84.45 41.57,86.42 41.57,88.59 v1(40.77,89.39)
  BOTTOM w0.102: v1(46.48,83.72) 46.31,83.72 46.23,83.8 46.23,84.03 46.64,84.44 47.13,84.44 47.41,84.72 49.41,84.72 49.58,84.55 49.87,84.55 49.97,84.44 49.97,84.21 50.07,84.1 50.28,84.1 50.37,84.2 50.37,84.44 50.48,84.55 50.68,84.55 50.78,84.44 50.78,84.15 50.88,84.04 51.09,84.04 51.19,84.14 51.19,84.44 51.29,84.55 51.79,84.55 52.08,84.26 53.71,84.26 U4500.BJ33 ; v1(40.77,89.39) 40.66,89.39 40.22,89.83 40.22,89.83 U4102.A7
M_A_DQ<57>: length 22.4
  L4 w0.124: v1(41.68,83.19) 41.68,83.11 42.5,82.28 46.86,82.28 47.16,81.98 48.13,81.98 v1(48.54,82.4)
  BOTTOM w0.089: 53.55,82.52 53.93,82.52 54.21,82.25 U4500.BG29
  BOTTOM w0.102: v1(48.54,82.4) 48.59,82.45 49.23,82.45 49.33,82.34 49.33,82.16 49.43,82.06 49.64,82.06 49.74,82.16 49.74,82.34 49.84,82.45 50.04,82.45 50.14,82.34 50.14,82.16 50.25,82.06 50.45,82.06 50.55,82.16 50.55,82.34 50.65,82.45 50.85,82.45 50.96,82.34 50.96,82.16 51.06,82.06 51.26,82.06 51.36,82.16 51.36,82.34 51.46,82.45 53.47,82.45 53.55,82.52 ; U4102.A3 41.26,86.9 42.61,85.55 42.61,84.44 42.71,84.34 43.1,84.34 43.2,84.24 43.2,84.04 43.1,83.93 42.71,83.93 42.61,83.83 42.61,83.43 42.38,83.19 v1(41.68,83.19)
M_A_DQ<58>: length 20.9
  L4 w0.124: v1(38.2,90.5) 39.24,89.75 39.59,89.75 39.98,89.36 39.98,89.2 40.96,87.37 40.96,86.17 43.32,83.81 44.32,83.81 v1(44.43,83.71)
  BOTTOM w0.102: v1(44.43,83.71) 44.47,83.74 45.87,84.78 47.24,85.27 49.64,85.27 50.8,85.1 53.07,84.77 54.07,84.77 U4500.BH34 ; v1(38.2,90.5) 38.2,90.48 U4102.D7
M_A_DQ<59>: length 22.8
  L4 w0.124: v1(39.82,90.5) 40.51,89.81 40.94,89.81 41.87,88.88 41.87,86.54 43.66,84.75 47.66,84.75 47.76,84.65 47.76,84.35 47.55,84.14 47.17,84.14 47.09,84.05 v1(47.09,83.71)
  BOTTOM w0.089: 52.42,83.98 53.49,83.98 53.59,83.89 53.94,83.89 54.04,83.99 54.28,83.99 54.57,83.71 U4500.BG32
  BOTTOM w0.102: U4102.B8 v1(39.82,90.5) ; v1(47.09,83.71) 47.09,84 47.53,84.44 49.3,84.44 49.92,83.81 51.23,83.81 51.52,84.1 51.73,84.1 52.02,83.81 52.25,83.81 52.42,83.98
M_A_DQ<60>: length 23.6
  L4 w0.124: v1(40.28,82.86) 40.79,82.86 41.98,81.68 46.29,81.68 v1(47.14,80.82)
  BOTTOM w0.102: v1(40.28,82.86) 40.28,83.36 40.16,83.47 38.16,83.47 38.05,83.57 38.05,83.77 38.16,83.88 38.87,83.88 38.97,83.98 38.97,84.18 38.87,84.28 38.3,84.28 38.2,84.38 38.2,84.59 38.3,84.69 38.87,84.69 38.97,84.79 38.97,85.76 38.62,86.1 U4102.C2 ; U4500.BG28 54.73,81.91 54.43,81.91 54.28,82.05 54.02,82.05 53.83,81.86 52.06,81.86 51.7,81.5 48.65,81.5 48.38,81.22 47.54,81.22 v1(47.14,80.82)
M_A_DQ<61>: length 23.2
  L4 w0.124: v1(38.22,86.48) 38.84,85.86 38.84,83.71 41.73,80.82 42.19,80.82 42.32,80.94 42.32,81.15 42.44,81.27 42.62,81.27 42.74,81.15 42.74,80.94 42.87,80.82 43.05,80.82 43.17,80.94 43.17,81.15 43.3,81.27 43.48,81.27 43.6,81.15 43.6,80.94 43.73,80.82 43.91,80.82 44.03,80.94 44.03,81.15 44.16,81.27 44.34,81.27 44.46,81.15 44.46,80.94 44.59,80.82 44.77,80.82 44.89,80.94 44.89,81.15 45.02,81.27 45.2,81.27 45.32,81.15 45.32,80.94 45.44,80.82 v1(46.49,80.82)
  BOTTOM w0.102: v1(46.49,80.82) 46.49,81.56 46.71,81.78 51.63,81.78 51.99,82.14 53.6,82.14 53.71,82.25 U4500.BJ29 ; v1(38.22,86.48) 38.62,86.87 U4102.C3
M_A_DQ<62>: length 24.3
  L4 w0.124: v1(48.36,80.82) 48.36,81.36 48.18,81.54 47.17,81.54 46.73,81.98 42.26,81.98 v1(41.05,83.19)
  BOTTOM w0.102: v1(41.05,83.19) 40.56,83.68 40.56,84.74 40.67,84.84 40.87,84.84 40.97,84.74 40.97,84.06 41.08,83.94 41.29,83.94 41.38,84.03 41.38,84.74 41.48,84.84 41.68,84.84 41.78,84.74 41.78,84.06 41.9,83.94 42.1,83.94 42.19,84.03 42.19,85.15 42.09,85.25 40.67,85.25 40.56,85.35 40.56,85.76 U4102.A2 ; U4500.BH28 53.98,81.58 52.15,81.58 51.78,81.22 48.77,81.22 v1(48.36,80.82)
M_A_DQ<63>: length 21.2
  L4 w0.124: v1(39.03,90.5) 39.45,90.08 39.69,90.08 40.29,89.48 40.29,89.28 41.27,88.3 41.27,86.29 43.41,84.15 44.96,84.15 45.13,83.98 v1(45.13,83.71)
  BOTTOM w0.102: v1(39.03,90.5) 38.63,90.9 U4102.C8 ; U4500.BG33 54.33,84.39 54.04,84.39 53.89,84.54 52.07,84.54 51.85,84.76 51.45,84.76 51.38,84.83 49.79,84.83 49.62,85 47.29,85 47.02,84.72 46.53,84.72 46.18,84.38 45.8,84.38 v1(45.13,83.71)
M_A_DQS0_DN: length 16.7
  BOTTOM w0.102: 62.23,95.15 62.23,95.12 62.21,95.1 62.21,94.1 62.48,93.83 62.48,93.57 62.19,93.27 U4500.AM51
  BOTTOM w0.137: 62.23,95.15 62.23,95.55 62.06,95.72 62.06,99.6 63.66,101.19 63.66,101.67 63.38,101.94 62.56,101.94 62.43,102.08 62.43,102.49 62.56,102.63 63.38,102.63 63.66,102.91 63.66,104.91 63.96,105.21 63.96,105.75 64.02,105.82 64.75,105.82 U4100.B7
M_A_DQS0_DP: length 16.6
  BOTTOM w0.102: U4500.AM52 62.01,93.89 62.01,95.1 61.99,95.12 61.99,95.15
  BOTTOM w0.137: U4100.C7 64.77,106.34 64.49,106.06 63.92,106.06 63.72,105.85 63.72,105.31 63.42,105.01 63.42,103.01 63.28,102.87 62.46,102.87 62.19,102.59 62.19,101.98 62.46,101.71 63.28,101.71 63.42,101.57 63.42,101.29 61.83,99.7 61.83,95.62 61.99,95.45 61.99,95.15
M_A_DQS1_DN: length 23.1
  L3 w0.102: 58.35,93.14 58.33,93.12 58.33,91.55 58.42,91.46 v1(58.69,91.46)
  L3 w0.147: v1(62.93,108.15) 62.81,108.15 62.6,107.94 62.6,107.3 62.28,106.98 61.84,106.98 61.66,107.16 61.44,107.16 61.27,106.99 61.27,106.76 61.45,106.58 61.45,106.15 60.61,105.31 60.61,104.64 59.84,103.86 59.84,101.88 58.35,100.39 58.35,93.14
  BOTTOM w0.102: U4500.AV48 59.26,91.65 59.08,91.46 v1(58.69,91.46)
  BOTTOM w0.137: v1(62.93,108.15) 62.81,108.15 62.54,108.41 62.54,109.14 62.18,109.51 61.85,109.51 61.57,109.79 U4100.G3
M_A_DQS1_DP: length 23.1
  L3 w0.102: v3(58.65,90.66) 58.65,90.93 58.12,91.46 58.12,93.08 58.1,93.11
  L3 w0.147: v1(62.17,108.15) 62.35,107.96 62.35,107.4 62.18,107.22 61.95,107.22 61.77,107.4 61.33,107.4 61.02,107.1 61.02,106.66 61.2,106.48 61.2,106.25 60.36,105.41 60.36,104.74 59.59,103.97 59.59,101.98 58.1,100.49 58.1,93.11
  BOTTOM w0.102: U4500.AV47 59.04,91.03 58.67,90.66 v3(58.65,90.66)
  BOTTOM w0.137: v1(62.17,108.15) 62.3,108.29 62.3,109.04 62.08,109.27 61.85,109.27 U4100.F3
M_A_DQS2_DN: length 35.2
  L4 w0.102: v1(59.88,88.55) 59.92,88.55 60.36,88.99 60.36,93.02 60.59,93.25 60.59,93.61 60.61,93.63 60.61,93.74
  L4 w0.147: 60.61,93.74 60.61,94.91 60.06,95.46 60.06,95.79 60.21,95.94 60.41,95.94 60.71,96.23 60.71,96.7 60.41,96.99 60.21,96.99 60.06,97.14 60.06,98.3 58.79,99.57 58.79,99.77 58.98,99.96 58.98,100.37 58.14,101.21 57.78,101.21 57.24,100.68 57.04,100.68 56.83,100.89 56.83,101.05 57.5,101.73 57.5,102.18 57.1,102.58 56.67,102.58 56.04,101.95 55.74,101.95 55.55,102.15 55.55,102.92 55.15,103.32 54.49,103.32 54.36,103.45 54.36,103.92 53.96,104.31 53.49,104.31 52.83,104.97 52.83,105.18 53.44,105.79 53.44,106.2 53.12,106.53 52.69,106.53 52.09,105.92 51.88,105.92 50.72,107.09 50.72,107.71 50.26,108.17 50.07,108.17 v3(49.85,108.38)
  BOTTOM w0.102: v1(59.88,88.55) 59.89,88.55 60.25,88.18 U4500.AT41
  BOTTOM w0.137: v3(49.85,108.38) 49.72,108.24 49.44,108.24 49.32,108.36 49.32,109.32 48.96,109.67 48.63,109.67 48.52,109.78 U4101.G3
M_A_DQS2_DP: length 35.1
  L4 w0.102: 60.36,93.74 60.36,93.63 60.4,93.6 60.4,93.33 60.17,93.1 60.17,89.31 60.08,89.23 59.92,89.23 59.88,89.26 v1(59.88,89.26)
  L4 w0.147: v1(49.84,107.62) 49.84,107.78 49.98,107.92 50.16,107.92 50.47,107.61 50.47,106.98 51.78,105.68 52.19,105.68 52.8,106.28 53.01,106.28 53.2,106.1 53.2,105.9 52.58,105.28 52.58,104.87 53.39,104.07 53.86,104.07 54.11,103.82 54.11,103.34 54.38,103.07 55.04,103.07 55.3,102.82 55.3,102.05 55.47,101.88 55.64,101.7 56.15,101.7 56.77,102.33 57,102.33 57.25,102.07 57.25,101.83 56.58,101.16 56.58,100.78 56.93,100.43 57.35,100.43 57.88,100.96 58.04,100.96 58.73,100.27 58.73,100.06 58.54,99.87 58.54,99.47 59.81,98.2 59.81,97.04 60.1,96.74 60.31,96.74 60.46,96.6 60.46,96.34 60.31,96.19 60.1,96.19 59.81,95.9 59.81,95.36 60.36,94.81 60.36,93.74
  BOTTOM w0.102: v1(59.88,89.26) 60.27,89.26 60.38,89.15 60.38,89.02 U4500.AT42
  BOTTOM w0.137: U4101.F3 48.52,109.29 48.66,109.43 48.86,109.43 49.08,109.22 49.08,108.26 49.34,108 49.64,108 49.84,107.8 v1(49.84,107.62)
M_A_DQS3_DN: length 18.6
  BOTTOM w0.102: U4500.BA51 58.07,93.35 58.13,93.41 58.42,93.41 58.59,93.58 58.59,93.84 58.3,94.13 58.3,94.78 58.3,94.78
  BOTTOM w0.137: U4101.B7 51.21,105.79 51.02,105.61 51.02,105.09 54.74,101.37 55,101.37 55.2,101.56 55.59,101.56 55.92,101.23 55.92,100.84 55.72,100.64 55.72,100.45 55.92,100.26 56.11,100.26 56.3,100.45 56.7,100.45 56.96,100.19 57.03,100.12 57.03,99.73 56.83,99.54 56.83,99.34 56.98,99.2 56.98,96.3 58.3,94.97 58.3,94.78
M_A_DQS3_DP: length 18.6
  BOTTOM w0.102: 58.07,94.78 58.07,94.71 58.1,94.68 58.1,93.91 U4500.AY52
  BOTTOM w0.137: U4101.C7 51.72,106.59 51.87,106.43 51.87,106.3 51.73,106.15 51.57,106.15 51.45,106.03 51.11,106.03 50.78,105.71 50.78,104.99 54.64,101.13 55.1,101.13 55.3,101.32 55.49,101.32 55.68,101.13 55.68,100.94 55.49,100.74 55.49,100.35 55.82,100.02 56.21,100.02 56.4,100.22 56.6,100.22 56.79,100.02 56.79,99.83 56.59,99.64 56.59,99.24 56.74,99.1 56.74,96.2 58.07,94.87 58.07,94.78
M_A_DQS4_DN: length 26
  BOTTOM w0.102: 52.63,87.46 52.65,87.46 52.67,87.48 53.85,87.48 54.03,87.3 54.44,87.3 54.52,87.22 U4500.BG39
  BOTTOM w0.137: 52.63,87.46 51.78,87.46 46.84,92.4 45.95,92.4 41.83,96.53 41.83,99.94 40.51,101.26 40.31,101.26 40.02,100.97 39.59,100.97 39.29,101.27 39.29,101.7 39.54,101.96 39.54,102.34 39.08,102.81 39.08,103.15 39.15,103.22 39.35,103.22 U4103.B7
M_A_DQS4_DP: length 26.1
  BOTTOM w0.102: 52.63,87.7 52.65,87.68 53.94,87.68 54.03,87.59 U4500.BH40
  BOTTOM w0.137: 52.63,87.7 51.88,87.7 46.94,92.64 46.05,92.64 42.07,96.63 42.07,100.04 40.61,101.49 40.21,101.49 39.93,101.21 39.69,101.21 39.53,101.37 39.53,101.6 39.78,101.86 39.78,103.32 39.59,103.51 38.93,103.51 38.62,103.2 U4103.C7
M_A_DQS5_DN: length 27.5
  L3 w0.102: v1(60.9,84.7) 60.75,84.55 60.6,84.55 60.24,84.9 55.43,84.9 55.2,84.67 54.68,84.67 54.66,84.7 54.64,84.7
  L3 w0.147: 54.64,84.7 52.99,84.7 51.95,85.74 44.07,85.74 42.65,87.16 35.94,87.16 v3(35.81,87.29)
  BOTTOM w0.102: v1(60.9,84.7) 60.9,84.7 60.4,84.7 U4500.AT34
  BOTTOM w0.137: v3(35.81,87.29) 35.42,86.9 U4102.G3
M_A_DQS5_DP: length 27.6
  L3 w0.102: 54.64,84.45 54.65,84.45 54.68,84.48 55.28,84.48 55.51,84.71 60.16,84.71 60.52,84.35 60.52,84.34 60.7,84.15 v1(60.7,84.12)
  L3 w0.147: v1(35.81,86.49) 36.24,86.91 42.55,86.91 43.97,85.49 51.84,85.49 52.89,84.45 54.64,84.45
  BOTTOM w0.102: v1(60.7,84.12) 60.7,84.05 60.39,83.74 U4500.AT32
  BOTTOM w0.137: U4102.F3 v1(35.81,86.49)
M_A_DQS6_DN: length 36.4
  L4 w0.102: v1(56.49,83.22) 56.75,83.48 56.75,83.59 56.66,83.67 55.58,83.67 55.28,83.97 54.7,83.97
  L4 w0.147: v1(36.94,100.96) 37.15,100.75 37.15,100.45 38.92,98.68 38.92,97.53 42.67,93.77 42.67,93.56 42.07,92.97 42.07,92.58 42.4,92.25 42.85,92.25 43.42,92.82 43.62,92.82 43.81,92.64 43.81,92.43 43.23,91.85 43.23,91.44 43.56,91.11 43.98,91.11 44.55,91.68 44.76,91.68 44.94,91.5 44.94,91.29 44.68,91.03 44.68,90.61 45.01,90.28 45.42,90.28 45.69,90.55 45.9,90.55 47.35,89.09 47.35,88.42 51.33,84.43 51.75,84.43 52.21,83.97 54.7,83.97
  BOTTOM w0.102: v1(56.49,83.22) 56.84,83.57 U4500.BC32
  BOTTOM w0.137: U4103.G3 35.62,99.95 35.62,99.95 36.36,100.7 36.68,100.7 v1(36.94,100.96)
M_A_DQS6_DP: length 36.4
  L4 w0.102: v1(57.2,83.22) 56.95,83.47 56.95,83.65 56.73,83.88 55.67,83.88 55.34,84.2 54.8,84.2 54.77,84.22
  L4 w0.147: 54.77,84.22 52.31,84.22 51.85,84.68 51.44,84.68 47.6,88.52 47.6,89.2 46,90.8 45.58,90.8 45.32,90.53 45.11,90.53 44.93,90.71 44.93,90.92 45.19,91.19 45.19,91.6 44.86,91.93 44.45,91.93 43.88,91.36 43.66,91.36 43.48,91.55 43.48,91.74 44.06,92.32 44.06,92.74 43.73,93.07 43.31,93.07 42.74,92.5 42.51,92.5 42.32,92.68 42.32,92.86 42.92,93.46 42.92,93.87 39.17,97.63 39.17,98.78 37.39,100.55 37.39,100.74 v3(37.6,100.94)
  BOTTOM w0.102: U4500.BC30 56.84,82.87 57.19,83.22 v1(57.2,83.22)
  BOTTOM w0.137: v3(37.6,100.94) 37.52,100.94 37.04,100.46 36.46,100.46 36.22,100.22 U4103.F3
M_A_DQS7_DN: length 22
  L4 w0.147: v1(48.34,84.03) 48.6,83.76 48.6,83.46 48.42,83.27 43.23,83.27 40.52,85.98 40.52,87.19 39.16,88.55 39.16,89.07 v1(39.42,89.33)
  BOTTOM w0.102: 52.2,83.15 52.22,83.15 52.24,83.17 52.47,83.17 52.9,83.59 53.33,83.59 53.43,83.5 53.94,83.5 54.22,83.22 U4500.BG31
  BOTTOM w0.137: v1(48.34,84.03) 48.64,83.73 48.64,83.52 49.01,83.15 52.2,83.15 ; U4102.B7 39.15,89.83 39.15,89.6 v1(39.42,89.33)
M_A_DQS7_DP: length 21.9
  L4 w0.147: v1(49.1,84.03) 48.85,83.78 48.85,83.35 48.52,83.02 43.13,83.02 40.27,85.88 40.27,87.08 38.91,88.45 38.91,89.07 v1(38.65,89.33)
  BOTTOM w0.102: 52.2,83.39 52.22,83.39 52.24,83.37 52.39,83.37 52.81,83.79 53.42,83.79 53.51,83.7 54.16,83.7 U4500.BH32
  BOTTOM w0.137: v1(38.65,89.33) 38.91,89.6 38.91,89.81 38.62,90.1 U4102.C7 ; v1(49.1,84.03) 48.88,83.81 48.88,83.62 49.11,83.39 52.2,83.39
M_A_OCAVREF: length 13
  TOP w0.254: TP4500.1 49.22,80.15 v1(49.89,80.82)
  L4 w0.203: v1(60.08,82.18) 59.49,81.59 59.16,81.59 59.04,81.48 56.07,81.48 56.03,81.52 54.77,81.52 54.57,81.73 50.8,81.73
  L4 w0.254: 50.8,81.73 v1(49.89,80.82)
  BOTTOM w0.254: U4500.AT28 60.08,82.07 v1(60.08,82.18)
M_A_ODQVREF: length 12.7
  TOP w0.254: v1(49.09,80.82) 49.09,81.23 TP4501.1
  L4 w0.203: 50.06,82.06 54.66,82.06 54.9,81.82 56.15,81.82 56.19,81.78 58.92,81.78 59.33,82.19 v1(59.33,82.23)
  L4 w0.254: 50.06,82.06 49.09,81.1 v1(49.09,80.82)
  BOTTOM w0.254: U4500.AU28 59.68,81.87 v1(59.33,82.23)
M_A_ODT0: length 125
  TOP w0.102: R4142.2 43.72,99.67 v1(44.33,99.67)
  L3 w0.102: v1(33.81,94.71) 33.69,94.59 33.54,94.59 33.42,94.71 33.42,95.62 34.4,96.6 35.99,96.6 36.09,96.7 36.09,97.11 36.19,97.21 36.4,97.21 36.5,97.11 36.5,96.7 36.6,96.6 36.8,96.6 36.91,96.7 36.91,97.17 37,97.27 37.21,97.27 37.31,97.16 37.31,96.7 37.41,96.6 37.62,96.6 37.72,96.7 37.72,97.21 37.82,97.31 38.02,97.31 38.13,97.21 38.13,96.7 38.23,96.6 38.43,96.6 38.53,96.7 38.53,97.32 38.65,97.43 38.85,97.43 38.94,97.34 38.94,96.7 39.04,96.6 39.45,96.6 39.62,96.77 39.62,96.91 39.39,97.14 39.39,97.29 39.53,97.43 39.67,97.43 39.91,97.2 40.05,97.2 41.54,98.69 41.73,98.69 41.87,98.54 41.87,98.45 40.27,96.85 40.27,96.74 40.42,96.6 40.6,96.6 42.49,98.49 42.49,98.63 42.33,98.79 42.33,98.93 42.47,99.08 42.62,99.08 42.78,98.92 42.92,98.92 43.25,99.25 44.18,99.25 44.33,99.4 v1(44.33,99.67) 46.52,99.67 46.75,99.89 47.63,99.89 47.98,100.24 48.12,100.24 48.48,99.88 48.63,99.88 48.77,100.02 48.77,100.17 48.41,100.53 48.41,100.67 48.55,100.82 48.7,100.82 49.06,100.46 49.2,100.46 49.35,100.6 49.35,100.74 48.99,101.1 48.99,101.25 49.13,101.39 49.27,101.39 49.63,101.03 49.78,101.03 49.92,101.17 49.92,101.32 49.56,101.68 49.56,101.82 49.7,101.97 49.85,101.97 50.21,101.61 50.35,101.61 50.5,101.75 50.5,101.89 50.14,102.26 50.14,102.4 50.28,102.54 50.42,102.54 50.79,102.18 50.93,102.18 51.07,102.32 51.07,102.47 50.71,102.83 50.71,102.97 50.84,103.11 51.01,103.11 51.23,102.88 51.35,102.88 54.02,105.55 54.02,105.68 53.8,105.9 53.8,106.06 54.99,107.25 54.99,108.61 55.67,109.29 55.67,110.87 56.19,111.4 v1(56.33,111.4)
  L4 w0.089: v1(33.81,88.09) 33.59,88.09 33.41,88.28 33.41,89.36 33.4,89.37 33.4,92.39 33.62,92.61 33.62,94.51 v1(33.81,94.71) 33.81,94.71 33.81,94.76 33.43,95.15 33.43,95.89 33.85,96.31 33.85,101.27 v1(33.81,101.3) ; v3(58.54,86.11) 58.77,86.11 59.02,85.87 59.02,85.65 58.79,85.42 58.49,85.42 58.18,85.73 54.95,85.73 54.32,86.36 53.87,86.36 53.61,86.61 52.78,86.61 52.46,86.92 ; v1(62.92,111.4) 62.88,111.4 62.63,111.65 57.48,111.65 57.34,111.79 56.77,111.79 56.38,111.4 v1(56.33,111.4) 56.28,111.4 55.87,111.81 50.47,111.81 50.45,111.79 49.9,111.79 49.71,111.59 v1(49.71,111.4)
  L4 w0.152: v1(44.33,99.67) 43.44,100.56 43.2,100.56 43,100.36 43,100.16 43.38,99.79 43.38,97.95 43.5,97.82 43.69,97.82 43.83,97.96 43.83,99.05 43.99,99.21 44.18,99.21 44.29,99.1 44.29,97.52 44.13,97.37 43.49,97.37 43.38,97.26 43.38,96.95 43.56,96.77 43.89,96.77 44.01,96.65 44.01,96.32 44.22,96.11 44.41,96.11 44.54,96.25 44.73,96.25 44.87,96.11 44.87,95.92 44.73,95.79 44.73,95.6 50.1,90.23 50.1,89.89 52.46,87.52 52.46,86.92
  BOTTOM w0.089: U4101.K1 47.1,112.19 47.5,111.79 48.88,111.79 49.27,111.4 v1(49.71,111.4) ; U4500.AV36 58.73,85.64 58.54,85.83 v3(58.54,86.11) ; v1(33.81,88.09) 33.81,87.58 33.42,87.19 33.42,85.82 33.02,85.42 33.02,85.41 U4102.K1 ; v1(33.81,101.3) 33.82,101.3 33.82,100.42 33.42,100.03 33.42,98.96 33.12,98.66 33.12,98.45 U4103.K1 ; v1(62.92,111.4) 62.92,111.4 62.2,111.4 61.8,111.79 60.57,111.79 60.17,112.19 U4100.K1
M_A_ODT1: length 127.3
  TOP w0.102: R4143.2 44.65,98.97 v3(45.32,98.97)
  L3 w0.102: v1(56.33,110.61) 56.49,110.45 56.49,109.43 56.08,109.02 56.08,105.84 51.45,101.21 51.45,101.07 51.59,100.92 51.74,100.92 52.64,101.82 52.81,101.82 52.95,101.68 52.95,101.56 51.74,100.35 51.59,100.35 51.16,100.78 51.02,100.78 50.34,100.1 49.8,100.1 48.3,98.6 45.7,98.6 v3(45.32,98.97) 45,98.63 44.46,98.63 42.08,96.24 42.08,96.11 42.22,95.97 42.37,95.97 44.63,98.23 44.78,98.23 44.92,98.08 44.92,97.94 42.41,95.42 42.19,95.42 41.5,96.11 41.1,96.11 41,96.01 41,95.88 40.89,95.78 40.69,95.78 40.59,95.88 40.59,96.01 40.49,96.11 40.29,96.11 40.19,96.01 40.19,95.88 40.08,95.78 39.88,95.78 39.78,95.88 39.78,96.01 39.68,96.11 34.72,96.11 34.21,95.6 34.21,94.71 34.32,94.6 34.49,94.6 v1(34.6,94.71)
  L4 w0.089: v1(49.71,110.61) 50.1,111 51.26,111 51.67,111.4 52.7,111.4 52.81,111.29 52.81,110.9 52.9,110.81 53.11,110.81 53.2,110.9 53.2,111.25 53.28,111.33 53.5,111.33 53.59,111.24 53.59,111.05 53.68,110.96 53.9,110.96 53.99,111.05 53.99,111.25 54.07,111.33 54.29,111.33 54.38,111.24 54.38,111.05 54.47,110.96 54.69,110.96 54.78,111.05 54.78,111.25 54.86,111.33 55.07,111.33 55.17,111.24 55.17,111.05 55.5,110.73 56.17,110.73 56.28,110.61 v1(56.33,110.61) 56.37,110.61 56.39,110.61 56.79,111.01 57.24,111.01 57.44,110.81 57.83,110.81 57.92,110.9 57.92,111.11 58.01,111.2 58.23,111.2 58.32,111.11 58.32,110.9 58.4,110.81 58.62,110.81 58.71,110.9 58.71,111.11 58.8,111.2 59.01,111.2 59.1,111.11 59.1,110.9 59.19,110.81 59.41,110.81 59.5,110.9 59.5,111.11 59.59,111.2 59.8,111.2 59.89,111.11 59.89,110.9 59.98,110.81 60.2,110.81 60.28,110.9 60.28,111.11 60.37,111.2 60.59,111.2 60.68,111.11 60.68,110.9 60.77,110.81 62.44,110.81 62.64,110.61 v1(62.92,110.61) ; v1(34.6,101.3) 34.42,101.12 34.42,100.31 34.51,100.22 34.71,100.22 34.8,100.13 34.8,99.92 34.71,99.83 34.51,99.83 34.42,99.74 34.42,99.52 34.51,99.44 34.71,99.44 34.8,99.35 34.8,99.13 34.71,99.04 34.51,99.04 34.42,98.95 34.42,98.38 34.51,98.29 34.72,98.29 34.81,98.2 34.81,97.98 34.73,97.9 34.51,97.9 34.42,97.81 34.42,97.59 34.51,97.5 34.7,97.5 34.8,97.4 34.8,97.19 34.72,97.11 34.51,97.11 34.42,97.02 34.42,95.71 34.22,95.51 34.22,95.16 34.6,94.78 34.6,94.75 v1(34.6,94.71) 34.56,94.66 34.56,91.92 34.33,91.69 34.03,91.69 33.92,91.58 33.92,91.35 33.99,91.28 34.14,91.28 34.22,91.19 34.22,90.98 34.13,90.88 34.03,90.88 33.81,90.66 33.81,90.21 33.91,90.11 34.31,90.11 34.4,90.03 34.4,89.78 34.31,89.69 34.02,89.69 33.93,89.6 33.93,89.38 34.02,89.3 34.31,89.3 34.4,89.21 34.4,89.04 34.22,88.86 34.22,88.09 34.34,87.96 34.48,87.96 v1(34.6,88.09) ; 53,87.5 53.8,86.69 55.24,86.69 55.38,86.55 57.22,86.55 57.81,87.14 v1(57.81,87.14)
  L4 w0.152: v3(45.32,98.97) 45.32,99.52 45.18,99.66 44.89,99.66 44.72,99.49 44.72,99.13 44.87,98.98 44.87,98.66 44.72,98.51 44.72,98.26 45,97.98 45,97.25 44.87,97.12 44.44,97.12 44.31,96.98 44.31,96.79 44.44,96.66 44.83,96.66 45.48,96 45.48,95.82 45.33,95.66 45.33,95.47 45.46,95.34 45.65,95.34 45.8,95.49 45.99,95.49 46.13,95.36 46.13,95.17 45.97,95.01 45.97,94.82 46.11,94.69 46.3,94.69 46.45,94.85 46.64,94.85 46.77,94.71 46.77,94.52 46.62,94.37 46.62,94.18 46.75,94.04 46.94,94.04 47.1,94.2 47.29,94.2 47.42,94.06 47.42,93.88 47.27,93.72 47.27,93.53 47.4,93.4 47.52,93.28 47.71,93.28 47.86,93.43 48.05,93.43 48.18,93.29 48.18,93.1 48.03,92.96 48.03,92.77 48.17,92.63 48.35,92.63 48.95,93.23 49.16,93.23 49.29,93.09 49.29,92.92 48.68,92.31 48.68,92.12 48.81,91.99 49,91.99 49.39,92.37 49.55,92.37 49.69,92.24 49.69,92.02 49.33,91.66 49.33,91.47 49.55,91.25 49.99,91.25 50.26,90.98 50.26,90.54 50.46,90.34 50.93,90.34 51.14,90.14 51.14,89.36 53,87.5
  BOTTOM w0.089: v1(34.6,88.09) 34.6,87.56 34.19,87.14 34.19,85.73 33.82,85.36 U4102.J1 ; U4101.J1 47.3,111.01 48.93,111.01 49.33,110.61 v1(49.71,110.61) ; U4500.BA38 57.65,86.61 57.8,86.76 57.8,87.14 v1(57.81,87.14) ; v1(62.92,110.61) 62.41,110.61 61.99,111.03 60.33,111.03 59.97,111.39 U4100.J1 ; U4103.J1 33.82,98.35 34.22,98.75 34.22,100.11 34.6,100.49 v1(34.6,101.3)
M_A_RAS#: length 115.3
  TOP w0.102: v1(45.4,98.3) 44.99,97.89 R4122.2
  L3 w0.102: v1(34.6,95.34) 34.6,95.65 34.82,95.87 37.34,95.87 37.67,95.54 38.04,95.54 38.14,95.64 38.14,95.77 38.24,95.87 38.45,95.87 38.55,95.77 38.55,95.64 38.65,95.54 38.85,95.54 38.96,95.64 38.96,95.77 39.06,95.87 39.26,95.87 39.36,95.77 39.36,95.64 39.46,95.54 41.73,95.54 42.38,94.89 42.38,93.95 42.68,93.65 43.27,93.65 44.29,94.67 44.29,94.78 44.15,94.93 43.97,94.93 43.1,94.05 42.94,94.05 42.79,94.2 42.79,94.32 44.05,95.58 44.17,95.58 44.6,95.15 44.74,95.15 44.88,95.29 44.88,95.44 44.18,96.14 44.04,96.14 42.95,95.06 42.79,95.06 42.65,95.2 42.65,95.32 45.32,98 45.32,98.22 v1(45.4,98.3) 45.46,98.36 46.86,98.36 46.96,98.26 46.96,98 47.07,97.89 47.27,97.89 47.37,97.99 47.37,98.26 47.47,98.36 47.67,98.36 47.77,98.26 47.77,98 47.88,97.89 48.08,97.89 48.18,97.99 48.18,98.26 48.28,98.36 48.48,98.36 48.59,98.26 48.59,98 48.69,97.89 48.9,97.89 48.99,97.99 48.99,98.58 49.1,98.68 49.3,98.68 49.4,98.58 49.4,98 49.51,97.89 49.71,97.89 49.8,97.99 49.8,98.26 49.91,98.36 50.31,98.36 50.62,98.68 50.62,98.82 50.33,99.11 50.33,99.26 50.48,99.4 50.62,99.4 50.91,99.11 51.06,99.11 51.2,99.25 51.2,99.4 50.91,99.69 50.91,99.83 51.05,99.98 51.19,99.98 51.49,99.68 51.63,99.68 56.32,104.38 56.32,108.9 56.73,109.31 56.73,110.37 v1(56.96,110.61)
  L4 w0.089: v3(57.15,87.15) 56.75,86.74 55.59,86.74 55.24,87.09 54.34,87.09 ; v1(63.53,110.61) 63.53,110.46 63.29,110.22 62.74,110.22 62.35,110.61 v1(56.96,110.61) 56.58,110.22 56.21,110.22 54.86,110.76 53.8,110.76 53.64,110.61 v1(50.32,110.61) ; v1(34.6,88.7) 34.6,88.71 34.6,91.53 34.76,91.69 34.76,94.32 34.99,94.55 34.99,95.03 34.68,95.34 v1(34.6,95.34) 35.06,95.8 35.06,96.9 35.39,98.55 35.39,98.91 34.99,100.42 34.99,101.52 v1(34.6,101.91)
  L4 w0.152: v1(45.4,98.3) 45.33,98.23 45.33,96.62 47.45,94.5 48.39,93.56 49.57,93.56 50.04,94.03 50.26,94.03 51.3,92.99 51.3,92.79 51.17,92.66 50.99,92.66 50.26,93.39 50.05,93.39 49.92,93.26 49.92,93.08 51.45,91.55 51.45,91.36 51.32,91.22 51.13,91.22 50.32,92.03 50.13,92.03 50,91.9 50,91.7 51.42,90.29 51.42,89.59 53.92,87.09 54.34,87.09
  BOTTOM w0.089: U4100.J3 61.92,111.39 62.3,111.01 63.13,111.01 v1(63.53,110.61) ; v3(57.15,87.15) 57.15,87.4 57.35,87.6 U4500.BA40 ; U4101.J3 48.99,111.39 49.38,111 49.93,111 v1(50.32,110.61) ; U4103.J3 33.82,100.03 34.21,100.42 34.21,101.52 v1(34.6,101.91) ; U4102.J3 33.82,87.19 34.21,87.58 34.21,88.31 v1(34.6,88.7)
M_A_WE#: length 102.3
  TOP w0.102: v1(43.72,101.36) 43.71,101.36 43.46,101.61 R4121.2
  L3 w0.102: v1(32.23,94.71) 32.13,94.6 31.95,94.6 31.84,94.71 31.84,95.51 32.07,95.74 32.18,95.74 34.78,98.34 36.39,98.34 37.58,99.54 38.37,99.54 39.99,101.16 40.92,101.16 41.02,101.26 41.02,101.71 41.12,101.81 41.32,101.81 41.42,101.71 41.42,101.21 41.52,101.12 41.72,101.12 41.83,101.23 41.83,101.75 41.93,101.85 42.13,101.85 42.24,101.74 42.24,101.21 42.33,101.12 42.53,101.12 42.64,101.23 42.64,101.75 42.74,101.85 42.94,101.85 43.05,101.74 43.05,101.21 43.14,101.12 43.48,101.12 v1(43.72,101.36) 45.88,101.36 49.05,104.53 50.11,104.53 53.99,108.4 53.99,108.69 53.81,108.87 53.81,109.09 53.99,109.28 53.99,109.5 53.81,109.68 53.81,109.91 53.99,110.09 53.99,110.67 55.7,112.38 55.7,112.57 56.11,112.98 v1(56.33,112.98)
  L4 w0.089: v1(32.23,88.09) 31.85,88.48 31.85,88.86 32.22,89.23 32.22,94.69 v1(32.23,94.71) 32.23,94.76 31.85,95.15 31.85,95.51 32.01,95.67 32.01,101.08 v1(32.23,101.3) ; v1(49.71,112.98) 50.12,113.38 52.23,113.38 52.64,112.98 v1(56.33,112.98) 56.38,112.98 56.77,113.37 57.91,113.37 58.07,113.2 62.52,113.2 62.74,112.98 v1(62.92,112.98)
  BOTTOM w0.089: v1(62.92,112.98) 61.58,112.98 U4100.L3 ; v1(32.23,88.09) 32.22,88.08 U4102.L3 ; U4101.L3 48.53,112.98 v1(49.71,112.98) ; v1(32.23,101.3) 32.22,101.29 U4103.L3
  BOTTOM w0.102: U4500.BH44 53.43,89.54 53.22,89.75 52.32,89.75 51.39,90.68
  BOTTOM w0.124: v1(43.72,101.36) 43.93,101.56 43.93,102.11 42.86,103.18 42.86,103.36 43.02,103.52 43.19,103.52 44.18,102.53 44.18,102.53 44.36,102.36 44.36,100.99 44.27,100.9 44.07,100.9 43.82,100.65 43.82,99.26 43.92,99.17 43.92,98.99 43.83,98.9 43.83,98.72 43.96,98.59 44.13,98.59 44.56,99.03 44.79,99.03 44.91,98.9 44.91,98.77 44.2,98.05 44.2,97.9 44.33,97.77 44.53,97.77 44.83,98.08 45.01,98.08 45.14,97.95 45.14,97.77 44.8,97.43 44.8,97.27 44.95,97.12 45.09,97.12 45.47,97.5 45.68,97.5 45.82,97.36 45.82,97.09 45.55,96.83 45.55,96.59 46.23,95.91 46.33,95.91 46.41,95.99 46.59,95.99 46.72,95.86 46.72,95.69 46.64,95.61 46.64,95.43 46.76,95.3 46.94,95.3 47.02,95.38 47.19,95.38 47.32,95.25 47.32,95.08 47.24,95 47.24,94.82 47.37,94.7 47.55,94.7 47.63,94.77 47.8,94.77 47.93,94.65 47.93,94.47 47.85,94.39 47.85,94.22 47.98,94.09 48.16,94.09 48.23,94.17 48.41,94.17 48.54,94.04 48.54,93.86 48.46,93.78 48.46,93.61 48.59,93.48 48.76,93.48 48.84,93.56 49.02,93.56 49.14,93.43 49.14,93.26 49.07,93.18 49.07,93 49.19,92.87 49.37,92.87 49.45,92.95 49.62,92.95 49.75,92.82 49.75,92.65 49.67,92.57 49.67,92.4 49.8,92.27 49.98,92.27 50.06,92.35 50.23,92.35 50.36,92.22 50.36,92.04 50.28,91.96 50.28,91.79 50.41,91.66 50.59,91.66 50.66,91.74 50.84,91.74 50.97,91.61 50.97,91.43 50.89,91.36 50.89,91.18 51.39,90.68
M_B_B<0>: length 120.6
  TOP w0.102: R4156.2 41.33,53.27 41.6,53.01 41.6,52.59 v3(41.63,52.56)
  L3 w0.102: v1(56.71,45.41) 56.71,45.41 56.31,45.8 54.78,45.8 54,46.57 53.29,46.57 51.39,48.47 51.39,49.95 50.03,51.31 49.07,51.31 48.71,50.94 45.11,50.94 44.85,51.21 44.85,52.18 44.75,52.28 44.49,52.28 44.38,52.18 44.38,51.25 44.28,51.15 44.08,51.15 43.98,51.25 43.98,52.18 43.88,52.28 43.39,52.28 43.27,52.41 43.27,53.15 43.16,53.26 42.95,53.26 42.86,53.16 42.86,52.66 42.76,52.56 42.56,52.56 42.45,52.66 42.45,53.62 42.35,53.72 42.15,53.72 42.05,53.62 42.05,52.66 41.95,52.56 v3(41.63,52.56) 41.63,53.44 41.5,53.57 41.08,53.57 40.98,53.46 40.98,52.91 40.87,52.81 40.67,52.81 40.57,52.91 40.57,53.46 40.47,53.57 40.27,53.57 40.16,53.46 40.16,52.91 40.06,52.81 39.86,52.81 39.76,52.91 39.76,53.46 39.66,53.57 38.03,53.57 34.98,56.61 34.98,57.18 34.98,57.18 33.36,58.8 33.36,62.18 32.64,62.9 31.15,62.9 30.74,63.31 30.74,65.03 29.08,66.69 v1(29.08,67.18)
  L4 w0.089: v1(56.72,71.24) 56.63,71.24 56.17,70.77 55.67,70.77 55.49,70.59 54.68,70.59 54.49,70.4 ; v1(29.02,60.56) 28.63,60.95 28.63,61.49 28.95,61.8 28.95,67.05 v1(29.08,67.18) 29.08,67.22 28.69,67.61 28.69,67.99 28.93,68.23 28.93,73.69 v1(29.01,73.77) ; v1(49.86,45.34) 54.93,45.34 55.25,45.02 56.25,45.02 56.64,45.41 v1(56.71,45.41) 56.83,45.29 59.59,45.29 59.68,45.2 59.68,45.06 59.76,44.98 59.98,44.98 60.07,45.06 60.07,45.2 60.16,45.29 60.56,45.29 60.9,44.95 62.72,44.95 v1(63.12,45.35)
  L4 w0.152: v3(41.63,52.56) 42.98,53.91 42.98,54.92 49.73,61.66 49.73,63.06 50.14,63.47 50.14,63.66 49.76,64.04 49.76,64.23 49.89,64.36 50.08,64.36 50.46,63.98 50.65,63.98 50.78,64.12 50.78,64.3 49.78,65.31 49.78,65.5 49.91,65.63 50.1,65.63 51.11,64.63 51.29,64.63 51.43,64.76 51.43,64.95 50.88,65.5 50.88,65.7 51.02,65.83 51.19,65.83 51.75,65.27 51.94,65.27 52.61,65.95 52.61,67.24 54.33,68.96 54.33,70.23 54.49,70.4
  BOTTOM w0.089: U4105.N3 50.22,45.96 50.22,45.69 v1(49.86,45.34) ; v1(29.01,73.77) 29.26,73.77 30.61,72.42 U4107.N3 ; v1(29.02,60.56) 29.26,60.56 29.65,60.17 29.82,60.17 U4106.N3 ; U4104.N3 63.61,46.3 63.61,46.06 63.12,45.58 v1(63.12,45.35) ; U4500.BB7 v1(56.72,71.24)
M_B_B<1>: length 121.3
  TOP w0.102: v1(37.61,52.43) 37.47,52.58 37.47,53.18 R4157.2
  L3 w0.102: v1(28.29,67.81) 27.89,67.41 27.89,64.43 30.99,61.33 30.99,60.14 31.16,59.98 31.16,59.84 30.45,59.12 30.45,59 30.59,58.85 30.75,58.85 31.44,59.55 31.59,59.55 31.73,59.4 31.73,59.26 30.98,58.51 30.98,58.38 31.12,58.24 31.28,58.24 32.02,58.97 32.16,58.97 33.02,58.12 33.02,57.82 32.91,57.71 32.37,57.71 32.27,57.61 32.27,57.41 32.37,57.31 32.91,57.31 33.02,57.21 33.02,56.9 33.8,56.12 33.93,56.12 v1(37.61,52.43) 37.62,52.43 41.02,49.03 45.25,49.03 45.36,48.93 45.36,48.57 45.46,48.46 45.67,48.46 45.76,48.56 45.76,48.93 45.86,49.03 46.07,49.03 46.17,48.93 46.17,48.57 46.28,48.46 46.48,48.46 46.57,48.56 46.57,48.93 46.68,49.03 47.22,49.03 47.3,48.95 47.3,48.46 47.41,48.34 47.61,48.34 47.7,48.44 47.7,48.8 47.81,48.9 48.01,48.9 48.11,48.8 48.11,48.56 48.21,48.46 48.41,48.46 48.52,48.56 48.52,48.8 48.62,48.9 50.03,48.9 50.5,48.43 50.5,48.18 53.76,44.92 54.01,44.92 54.32,44.62 v1(56.07,44.62)
  L4 w0.089: v1(28.22,74.38) 28.6,73.99 28.6,68.3 28.29,67.98 v1(28.29,67.81) 28.29,67.72 28.67,67.34 28.67,66.97 28.17,66.46 28.17,61.24 28.23,61.17 v1(28.23,61.17) ; v1(62.46,44.56) 62.46,44.56 62.4,44.5 60.65,44.5 60.56,44.59 60.56,44.72 60.47,44.81 60.25,44.81 60.16,44.72 60.16,44.59 60.08,44.5 58.85,44.5 58.35,45 56.55,45 56.16,44.62 v1(56.07,44.62) 55.92,44.77 55.21,44.77 55.05,44.94 49.6,44.94 v3(49.22,44.55) ; v1(56.35,73.44) 55.79,72.88 54.75,72.88 54.54,72.66 53.2,72.66 52.89,72.35
  L4 w0.152: 52.89,72.35 47.11,66.57 47.11,62.71 45.02,60.62 45.02,59.76 44.63,59.37 44.44,59.37 44.2,59.61 44.01,59.61 43.88,59.47 43.88,59.28 44.12,59.05 44.12,58.86 43.98,58.72 43.79,58.72 43.56,58.96 43.37,58.96 43.23,58.83 43.23,58.64 43.47,58.4 43.47,58.21 38.94,53.68 38.94,53.46 37.91,52.43 v1(37.61,52.43)
  BOTTOM w0.089: v1(28.23,61.17) 28.23,61.17 28.75,61.68 28.93,61.68 U4106.P7 ; U4107.P7 29.82,75.48 29.82,75.48 29.14,74.8 28.64,74.8 v1(28.22,74.38) ; U4500.BC12 56.84,73.96 v1(56.35,73.44) ; v1(62.46,44.56) 62.46,44.57 61.95,45.08 61.95,45.26 U4104.P7 ; v3(49.22,44.55) 48.83,44.93 48.83,45.33 U4105.P7
M_B_B<2>: length 112.9
  TOP w0.102: R4159.2 38.87,50.84 v1(38.87,50.59)
  L3 w0.102: v1(56.71,43.83) 56.71,43.83 56.31,44.22 54.28,44.22 53.86,44.64 53.11,44.64 50.26,47.5 50.26,47.88 50.03,48.11 49.08,48.11 48.73,47.76 48.29,47.76 48.19,47.86 48.19,48.1 48.09,48.19 47.89,48.19 47.78,48.09 47.78,47.86 47.58,47.66 46.52,47.66 46.06,48.12 41.33,48.12 v1(38.87,50.59) 33.58,55.87 32.63,55.87 30.2,58.3 30.2,61.7 27.5,64.41 v1(27.5,67.18)
  L4 w0.089: v1(63.12,43.77) 63.12,43.5 63.01,43.38 62.28,43.38 62.17,43.5 59.47,43.5 59.29,43.68 59.08,43.68 58.9,43.5 58.68,43.5 58.5,43.68 58.29,43.68 58.11,43.5 57.79,43.5 57.46,43.83 v1(56.71,43.83) 56.62,43.83 56.23,43.44 52.73,43.44 52.4,43.76 v1(49.86,43.76) ; v1(27.43,73.77) 27.43,73.62 27.09,73.29 27.09,67.62 27.5,67.22 v1(27.5,67.18) 27.5,67.14 27.35,66.99 27.35,61.65 27.05,61.35 27.05,60.95 27.44,60.56 v1(27.44,60.56)
  BOTTOM w0.089: U4105.P3 50.66,45.6 50.66,45.11 50.45,44.89 50.45,44.34 v1(49.86,43.76) ; U4107.P3 29.27,72.97 28.83,72.97 28.42,73.38 27.82,73.38 v1(27.43,73.77) ; U4104.P3 64.02,45.9 64.02,45.89 63.72,45.6 63.72,45.58 63.72,45.09 63.51,44.88 63.51,44.4 63.12,44.01 v1(63.12,43.77) ; v1(27.44,60.56) 27.44,60.53 27.85,60.12 28.54,60.12 28.74,59.92 29.27,59.92 U4106.P3
  BOTTOM w0.124: v1(38.87,50.59) 40.23,51.95 40.23,52.13 39.68,52.68 39.68,52.85 39.81,52.98 39.99,52.98 40.54,52.43 40.71,52.43 40.91,52.63 40.91,54.11 47.08,60.28 47.08,63.67 53.09,69.68 53.09,70.52 53.56,70.98 U4500.BJ6
M_B_B<3>: length 115.7
  TOP w0.102: R4158.2 38.94,52.23 39.06,52.1 v1(39.06,51.54)
  L3 w0.102: v1(56.71,44.62) 56.71,44.62 56.32,45.01 55.91,45.01 55.91,45.01 54.42,45.01 54.12,45.31 53.72,45.31 50.86,48.16 50.86,48.9 50.03,49.73 49.11,49.73 48.65,49.27 48.46,49.27 48.36,49.37 48.36,49.66 48.26,49.76 48.05,49.76 47.95,49.66 47.95,49.37 47.85,49.27 47.65,49.27 47.55,49.37 47.55,49.66 47.44,49.76 47.24,49.76 47.14,49.66 47.14,49.37 47.04,49.27 41.33,49.27 v1(39.06,51.54) 34.45,56.15 34.45,57.02 31.78,59.7 31.78,61.59 31.41,61.95 31.27,61.95 31.1,61.78 30.96,61.78 30.81,61.93 30.81,62.07 30.98,62.24 30.98,62.39 30.84,62.53 30.7,62.53 30.53,62.36 30.38,62.36 30.24,62.5 30.24,62.65 30.41,62.82 30.41,62.96 30.26,63.1 30.12,63.1 29.95,62.93 29.81,62.93 29.66,63.08 29.66,63.22 29.83,63.39 29.83,63.54 29.69,63.68 29.55,63.68 29.38,63.51 29.23,63.51 29.09,63.65 29.09,63.8 29.26,63.97 29.26,64.11 28.96,64.4 28.96,66.12 28.29,66.8 v1(28.29,67.18)
  L4 w0.089: v1(63.12,44.56) 62.74,44.17 58.89,44.17 58.45,44.62 58.18,44.62 58.09,44.53 58.09,44.39 58.01,44.3 57.79,44.3 57.7,44.39 57.7,44.53 57.61,44.62 v1(56.71,44.62) 56.62,44.62 56.23,44.23 55.6,44.23 55.28,44.55 v1(49.86,44.55) ; v1(28.23,60.56) 28.23,60.56 27.84,60.95 27.84,66.69 28.29,67.13 v1(28.29,67.18) 28.29,67.22 27.9,67.61 27.9,68.03 28.22,68.35 v1(28.22,73.77)
  BOTTOM w0.089: v1(28.22,73.77) 28.32,73.77 28.71,73.38 29.36,73.38 30.17,72.56 30.17,72.07 U4107.N2 ; U4104.N2 64.65,46.54 64.16,46.54 63.81,46.2 63.81,45.98 63.52,45.68 63.52,45.2 63.12,44.8 v1(63.12,44.56) ; U4106.N2 30.21,58.98 30.21,59.47 29.72,59.97 29.56,59.97 29.41,60.12 28.83,60.12 28.4,60.56 v1(28.23,60.56) ; v1(49.86,44.55) 49.86,44.78 50.44,45.35 50.44,45.88 51.06,46.5 51.56,46.5 U4105.N2
  BOTTOM w0.102: U4500.BH7 54.03,71.42 53.93,71.33 53.49,71.33 53.14,70.98
  BOTTOM w0.124: v1(39.06,51.54) 39.06,52.69 46.78,60.4 46.78,63.81 52.79,69.82 52.79,70.62 53.14,70.98
M_B_B<4>: length 122.3
  TOP w0.102: v1(36.68,52.21) 36.26,52.21 R4160.2
  L3 w0.102: v1(56.07,43.83) 54.17,43.83 53.7,44.3 53.06,44.3 50.03,47.32 48.65,47.32 48.38,47.05 45.3,47.05 44.63,47.72 41.17,47.72 36.69,52.21 36.68,52.21 ; 36.68,52.21 33.25,55.63 32.53,55.63 29.9,58.26 29.9,59.87 29.42,60.35 29.42,61.83 28.92,62.33 28.77,62.33 28.5,62.06 28.36,62.06 28.22,62.2 28.22,62.35 28.49,62.62 28.49,62.76 28.34,62.91 28.2,62.91 27.93,62.64 27.79,62.64 27.64,62.78 27.64,62.92 27.91,63.19 27.91,63.34 27.77,63.48 27.63,63.48 27.35,63.21 27.21,63.21 27.07,63.35 27.07,63.5 27.34,63.77 27.34,63.91 27.1,64.15 27.1,67.42 v1(27.5,67.81) ; 36.68,52.21 v1(36.68,52.21)
  L4 w0.089: v1(62.46,43.77) 62.26,43.97 61.75,43.97 61.59,43.81 61.35,43.81 61.19,43.97 60.96,43.97 60.8,43.81 60.57,43.81 60.41,43.97 60.17,43.97 60.01,43.81 59.78,43.81 59.62,43.97 57.61,43.97 57.36,44.21 56.53,44.21 56.14,43.83 v1(56.07,43.83) 55.42,43.83 54.98,44.27 50.3,44.27 50.19,44.16 49.66,44.16 v1(49.25,43.76) ; v1(27.43,74.38) 27.83,73.98 27.83,73.61 27.94,73.49 27.94,68.48 27.5,68.03 v1(27.5,67.81) 27.5,67.72 27.88,67.34 27.88,67.02 27.55,66.69 27.55,61.28 27.44,61.17 v1(27.44,61.17) ; 52.68,72.61 52.93,72.85 54.46,72.85 54.67,73.07 55.34,73.07 v1(55.74,73.46)
  L4 w0.152: v1(36.68,52.21) 37.6,53.12 38.14,53.12 38.61,53.6 38.61,53.85 38.82,54.06 38.82,54.25 38.61,54.46 38.61,54.65 38.74,54.78 38.93,54.78 39.14,54.57 39.33,54.57 39.47,54.7 39.47,54.89 39.26,55.1 39.26,55.29 39.39,55.43 39.58,55.43 39.79,55.22 39.98,55.22 41.86,57.1 41.86,57.92 46.78,62.85 46.78,66.71 52.68,72.61
  BOTTOM w0.089: U4106.P8 29.82,63.3 29.45,62.93 29.45,62.5 28.86,61.91 28.18,61.91 v1(27.44,61.17) ; U4107.P8 29.43,76.03 29.43,75.53 28.9,75 28.05,75 v1(27.43,74.38) ; v1(49.25,43.76) 48.63,44.38 48.63,45.23 48.1,45.76 47.6,45.76 U4105.P8 ; U4104.P8 60.63,45.78 61.13,45.78 61.72,45.19 61.72,44.51 v1(62.46,43.77) ; U4500.BD12 v1(55.74,73.46)
M_B_B<5>: length 118.8
  TOP w0.102: v1(38.33,50) 38.14,50.19 37.95,50.19 R4161.2
  L3 w0.102: v1(26.71,67.18) 26.71,63.33 28.63,61.41 28.63,60.34 29.66,59.32 29.66,58.16 32.43,55.39 32.85,55.39 38.24,50 v1(38.33,50) 38.46,50 40.98,47.48 44.39,47.48 45.75,46.13 46.32,46.13 46.73,46.54 48.36,46.54 48.46,46.44 48.46,46.3 48.56,46.2 48.76,46.2 48.86,46.3 48.86,46.44 48.96,46.54 50.03,46.54 52.36,44.2 52.36,43.77 52.7,43.43 55.91,43.43 55.91,43.43 56.32,43.43 56.71,43.04 v1(56.71,43.04)
  L4 w0.089: v1(63.12,42.98) 62.74,42.59 62.22,42.59 61.97,42.84 59.4,42.84 59.25,42.98 59.01,42.98 58.86,42.84 58.61,42.84 58.47,42.98 58.22,42.98 58.07,42.84 57.82,42.84 57.68,42.98 57.43,42.98 57.29,42.84 56.91,42.84 v1(56.71,43.04) 56.62,43.04 56.23,42.65 54.81,42.65 54.69,42.77 50.06,42.77 v1(49.86,42.97) ; v1(26.65,60.56) 26.26,60.95 26.26,61.41 26.63,61.78 26.63,67.1 v1(26.71,67.18) 26.71,67.22 26.32,67.61 26.32,73.32 26.64,73.64 v1(26.64,73.77)
  BOTTOM w0.089: U4106.P2 29.4,58.99 29.4,59.49 29.17,59.72 28.66,59.72 28.45,59.92 27.29,59.92 v1(26.65,60.56) ; U4107.P2 29.43,72.01 29.43,72.51 29.17,72.77 28.74,72.77 28.33,73.18 27.23,73.18 v1(26.64,73.77) ; v1(49.86,42.97) 49.86,43.2 50.66,44 50.66,44.8 50.86,45 50.86,45.5 51.13,45.76 51.62,45.76 U4105.P2 ; U4104.P2 64.64,45.73 64.15,45.73 63.93,45.51 63.93,45.49 63.93,45 63.71,44.79 63.71,43.57 v1(63.12,42.98)
  BOTTOM w0.102: U4500.BH6 54.19,70.65 53.58,70.65 53.41,70.48
  BOTTOM w0.124: 53.41,70.48 53.41,69.57 47.38,63.54 47.38,60.15 41.21,53.98 41.21,52.34 38.87,50 v1(38.33,50)
M_B_B<6>: length 130.2
  TOP w0.102: v1(36.28,49.15) 35.81,49.62 R4163.2
  L3 w0.102: v1(25.13,67.81) 24.73,67.42 24.73,61.73 24.66,61.65 24.66,60.99 24.67,60.98 24.67,60.31 25.09,59.89 25.47,59.89 35.92,49.44 35.99,49.44 v1(36.28,49.15) 39.97,45.46 44.54,45.46 45.66,44.34 46.88,44.34 48.64,42.57 49.42,42.57 49.42,42.57 50.47,42.57 50.72,42.33 50.86,42.33 51.14,42.61 51.29,42.61 51.43,42.46 51.43,42.32 51.15,42.04 51.15,41.89 51.59,41.46 v1(56.07,41.46)
  L4 w0.089: v1(62.46,41.4) 62.27,41.4 61.83,41.84 61.32,41.84 61.16,42 60.93,42 60.77,41.84 60.53,41.84 60.37,42 60.14,42 59.98,41.84 59.75,41.84 59.59,42 59.35,42 59.19,41.84 56.55,41.84 56.16,41.46 v1(56.07,41.46) 54.76,41.46 54.44,41.78 49.64,41.78 v1(49.25,41.39) ; v1(25.06,61.16) 25.06,61.73 25.53,62.2 25.53,67.34 25.33,67.55 25.13,67.75 v1(25.13,67.81) 25.13,73.29 25.45,73.61 25.45,73.99 v1(25.06,74.38) ; v1(56.77,71.84) 56.07,71.84 55.49,71.26 55.29,71.26 54.96,71.58 54.72,71.58 54.19,71.41
  L4 w0.152: 54.19,71.41 54.1,71.41 48.1,65.41 48.1,61.44 41.99,55.33 41.99,55.1 36.28,49.39 v1(36.28,49.15)
  BOTTOM w0.089: U4107.R8 29.02,76.42 29.02,76.24 28.8,76.02 26.56,76.02 25.06,74.52 v1(25.06,74.38) ; v1(49.25,41.39) 47.61,43.03 47.61,44.95 U4105.R8 ; U4500.BB8 56.77,71.85 v1(56.77,71.84) ; U4104.R8 60.65,44.96 60.65,42.71 61.96,41.4 v1(62.46,41.4) ; U4106.R8 28.63,62.98 26.88,62.98 v1(25.06,61.16)
M_B_B<7>: length 129.1
  TOP w0.102: R4162.2 35.28,48.99 35.51,48.99 v1(35.77,48.73)
  L3 w0.102: v1(24.34,67.18) 23.87,61.46 23.87,59.69 24.19,59.37 27.08,56.76 28.14,56.39 28.21,56.31 28.28,56.28 28.74,55.79 35.77,48.75 v1(35.77,48.73) 35.81,48.73 39.87,45.22 44.07,45.22 45.56,44.1 46.57,44.1 49.09,41.78 50.14,41.78 51.48,41.06 56.2,41.06 v1(56.71,40.65)
  L4 w0.089: v1(50.04,40.58) 51.2,40.58 53.8,40.35 55.75,40.27 56.01,40.27 56.21,40.27 v1(56.71,40.65) 61.19,40.65 61.62,40.22 62.65,40.22 63.03,40.61 v1(63.12,40.61) ; v1(24.27,73.77) 23.95,67.99 23.95,67.56 v1(24.34,67.18) 23.87,61.52 23.87,60.96 v1(24.28,60.56) ; 53.72,71.49 53.85,71.62 54.06,71.69 54.81,71.79 55.18,71.79 v3(55.39,71.71)
  L4 w0.152: 53.72,71.49 47.77,65.54 47.77,61.58 41.66,55.47 41.66,55.24 35.77,49.35 v1(35.77,48.73)
  BOTTOM w0.089: U4106.R2 28.43,58.91 28.23,59.03 28,59.03 26.2,59.28 25.09,59.88 24.72,60.17 v1(24.28,60.56) ; U4104.R2 64.63,44.81 64.63,44.62 64.61,44.27 64.43,43.15 64.29,42.4 63.45,41.03 v1(63.12,40.61) ; v1(50.04,40.58) 50.23,40.92 51.3,43.29 51.56,43.95 51.58,44.28 51.58,44.62 U4105.R2 ; U4107.R2 28.32,72.08 28.04,72.08 27.94,72.09 26.03,72.54 v1(24.27,73.77) ; U4500.BE8 v3(55.39,71.71)
M_B_B<8>: length 133.1
  TOP w0.102: v1(35.22,48.45) 35.17,48.4 34.86,48.4 R4164.2
  L3 w0.102: v1(24.34,67.81) 24.34,67.81 23.96,67.43 23.63,67.1 23.63,59.59 27.04,56.18 28,56.18 28.01,56.18 28.11,56.07 33.25,50.93 33.25,50.42 v1(35.22,48.45) 38.69,44.98 43.85,44.98 45.97,42.85 46.23,42.85 46.5,43.13 46.64,43.13 46.79,42.99 46.79,42.84 46.51,42.57 46.51,42.42 47.94,40.99 50.19,40.99 50.53,40.65 v1(56.07,40.65)
  L4 w0.089: v1(55.72,72.48) 55.34,72.1 53.11,72.1 53,71.99 ; v3(49.25,40.59) 49.25,40.59 49.64,40.99 54.36,40.99 54.48,40.87 55.86,40.87 v1(56.07,40.65) 56.16,40.65 56.56,41.06 58.98,41.06 59.13,41.21 59.38,41.21 59.53,41.06 59.77,41.06 59.92,41.21 60.16,41.21 60.32,41.06 60.56,41.06 60.71,41.21 60.95,41.21 61.1,41.06 61.57,41.06 62.01,40.61 v1(62.46,40.61) ; v1(24.27,74.38) 24.27,74.37 24.66,73.99 24.66,73.6 24.52,73.46 24.52,67.99 v1(24.34,67.81) 24.34,67.72 24.72,67.34 24.72,67.31 24.73,67.31 24.73,62.06 24.26,61.6 v1(24.26,61.17)
  L4 w0.152: v1(35.22,48.45) 35.22,49.27 39.27,53.32 39.27,53.54 45.35,59.62 45.35,60.48 47.44,62.57 47.44,66.43 53,71.99
  BOTTOM w0.089: v3(49.25,40.59) 47.21,42.62 U4105.T8 ; v1(24.26,61.17) 24.28,61.17 26.48,63.37 U4106.T8 ; v1(62.46,40.61) 61.91,40.61 60.26,42.26 U4104.T8 ; U4107.T8 26.31,76.42 v1(24.27,74.38) ; U4500.BD10 v1(55.72,72.48)
M_B_B<9>: length 120.9
  TOP w0.102: R4165.2 38.89,48.07 v1(39.02,48.2)
  L3 w0.102: v1(56.71,42.25) 56.71,42.25 56.31,42.64 52.66,42.64 50.36,44.94 47.74,44.94 47.63,45.06 45.96,45.06 45.53,45.49 45.53,45.49 44.03,47 42.77,47 42.66,46.9 42.66,46.29 42.56,46.19 40.81,46.19 40.71,46.29 40.71,46.49 40.81,46.59 42.16,46.59 42.26,46.69 42.26,46.9 42.16,47 40.22,47 39.51,47.7 v1(39.02,48.2) 32.31,54.91 32.09,54.91 29.1,57.9 29.1,58.25 27.05,60.3 27.05,61.42 25.92,62.55 v1(25.92,67.18)
  L4 w0.089: v1(49.86,42.18) 54.42,42.18 54.74,41.86 56.23,41.86 56.62,42.25 v1(56.71,42.25) 57,42.25 57.15,42.4 57.39,42.4 57.54,42.25 57.79,42.25 57.94,42.4 58.18,42.4 58.33,42.25 58.57,42.25 58.72,42.4 58.97,42.4 59.12,42.25 61.73,42.25 62.17,41.8 62.74,41.8 v1(63.12,42.19) ; v1(25.85,73.77) 25.85,73.67 25.53,73.35 25.53,67.63 25.92,67.24 v1(25.92,67.18) 25.92,62.07 25.46,61.61 25.46,60.92 v1(25.86,60.52)
  BOTTOM w0.089: v1(49.86,42.18) 49.86,42.42 50.25,42.81 50.25,43.3 50.86,43.91 50.86,44.68 51.21,45.03 U4105.R3 ; U4107.R3 28.79,72.42 28.23,72.97 26.64,72.97 v1(25.85,73.77) ; U4106.R3 28.72,59.37 28.37,59.72 26.66,59.72 v1(25.86,60.52) ; v1(63.12,42.19) 63.92,42.98 63.92,44.7 64.26,45.05 U4104.R3 ; U4500.BE2 55.92,68.68 55.92,68.32 55.7,68.1 55.7,68.02 55.25,67.57
  BOTTOM w0.124: 55.25,67.57 55.14,67.46 55.14,67.07 52.91,64.84 52.91,64.51 49.38,60.98 49.06,60.98 45.16,57.08 45.16,54.98 39.02,48.84 v1(39.02,48.2)
M_B_B<10>: length 107.5
  TOP w0.102: v1(42.36,57.76) 42.28,57.76 R4168.2
  L3 w0.102: v1(56.07,48.57) 55.89,48.57 54.43,50.03 54.43,51.68 53.03,53.09 53.03,54.76 51.52,56.27 50.19,56.27 50.09,56.17 50.09,55.55 49.99,55.45 49.79,55.45 49.68,55.56 49.68,56.17 49.58,56.27 49.38,56.27 49.28,56.17 49.28,55.55 49.18,55.45 48.97,55.45 48.87,55.56 48.87,56.17 48.77,56.27 48.56,56.27 48.46,56.17 48.46,55.55 48.36,55.45 48.16,55.45 48.06,55.56 48.06,56.17 47.96,56.27 47.75,56.27 47.65,56.17 47.65,55.55 47.55,55.45 47.35,55.45 47.24,55.56 47.24,56.17 47.14,56.27 45.31,56.27 43.82,57.76 v1(42.36,57.76) 42.36,58.02 42.27,58.11 41.58,58.11 41.48,58.2 41.48,58.41 41.59,58.51 42.51,58.51 42.61,58.61 42.61,58.81 42.5,58.92 41.58,58.92 41.48,59.02 41.48,59.22 41.59,59.33 42.36,59.33 42.46,59.43 42.46,59.62 42.34,59.73 41.14,59.73 39.43,61.44 39.43,61.66 39.54,61.76 39.92,61.76 40.01,61.85 40.01,62.06 39.89,62.17 39.54,62.17 39.43,62.27 39.43,63.8 39.29,63.94 38.27,63.94 38.16,63.84 38.16,63.56 38.07,63.47 37.86,63.47 37.76,63.57 37.76,63.84 37.66,63.94 36.46,63.94 36.36,64.05 36.36,64.42 36.26,64.52 36.06,64.52 35.95,64.42 35.95,64.05 35.85,63.94 35.65,63.94 35.55,64.05 35.55,64.42 35.45,64.52 35.24,64.52 35.14,64.42 35.14,64.05 35.04,63.94 34.82,63.94 34.44,64.32 34.17,64.32 31.84,66.65 31.84,67.42 32.23,67.81 v1(32.23,67.81)
  L4 w0.089: v1(62.46,48.56) 62.42,48.56 61.91,48.56 61.75,48.73 61.52,48.73 61.35,48.56 61.13,48.56 60.96,48.73 60.73,48.73 60.57,48.56 60.34,48.56 60.17,48.73 59.95,48.73 59.78,48.56 57.78,48.56 57.39,48.95 56.54,48.95 56.19,48.6 56.1,48.6 v1(56.07,48.57) 56.02,48.52 50.59,48.52 50.16,48.95 49.7,48.95 v1(49.25,48.51) ; v1(32.23,74.38) 32.62,73.99 32.62,73.47 32.23,73.08 32.23,67.82 v1(32.23,67.81) 32.23,67.72 32.39,67.56 32.4,67.56 32.62,67.33 32.62,66.96 32.22,66.55 32.22,61.21 v1(32.17,61.17)
  BOTTOM w0.089: v1(32.23,74.38) 32.22,74.39 32.22,75.62 U4107.L7 ; U4106.L7 32.22,61.22 v1(32.17,61.17) ; v1(49.25,48.51) 49.21,48.55 U4105.L7 ; U4104.L7 62.45,48.55 v1(62.46,48.56)
  BOTTOM w0.102: U4500.BJ9 52.68,72.53
  BOTTOM w0.124: 52.68,72.53 51.88,71.73 51.88,70.21 49.4,67.73 45.87,64.2 45.87,62.2 45.65,61.98 45.65,61.8 45.85,61.6 45.85,61.42 45.72,61.29 45.55,61.29 45.34,61.5 45.17,61.5 45.04,61.37 45.04,61.19 45.58,60.65 45.58,60.49 45.45,60.36 45.26,60.36 44.73,60.89 44.56,60.89 43.27,59.6 43.27,58.09 42.95,57.76 v1(42.36,57.76)
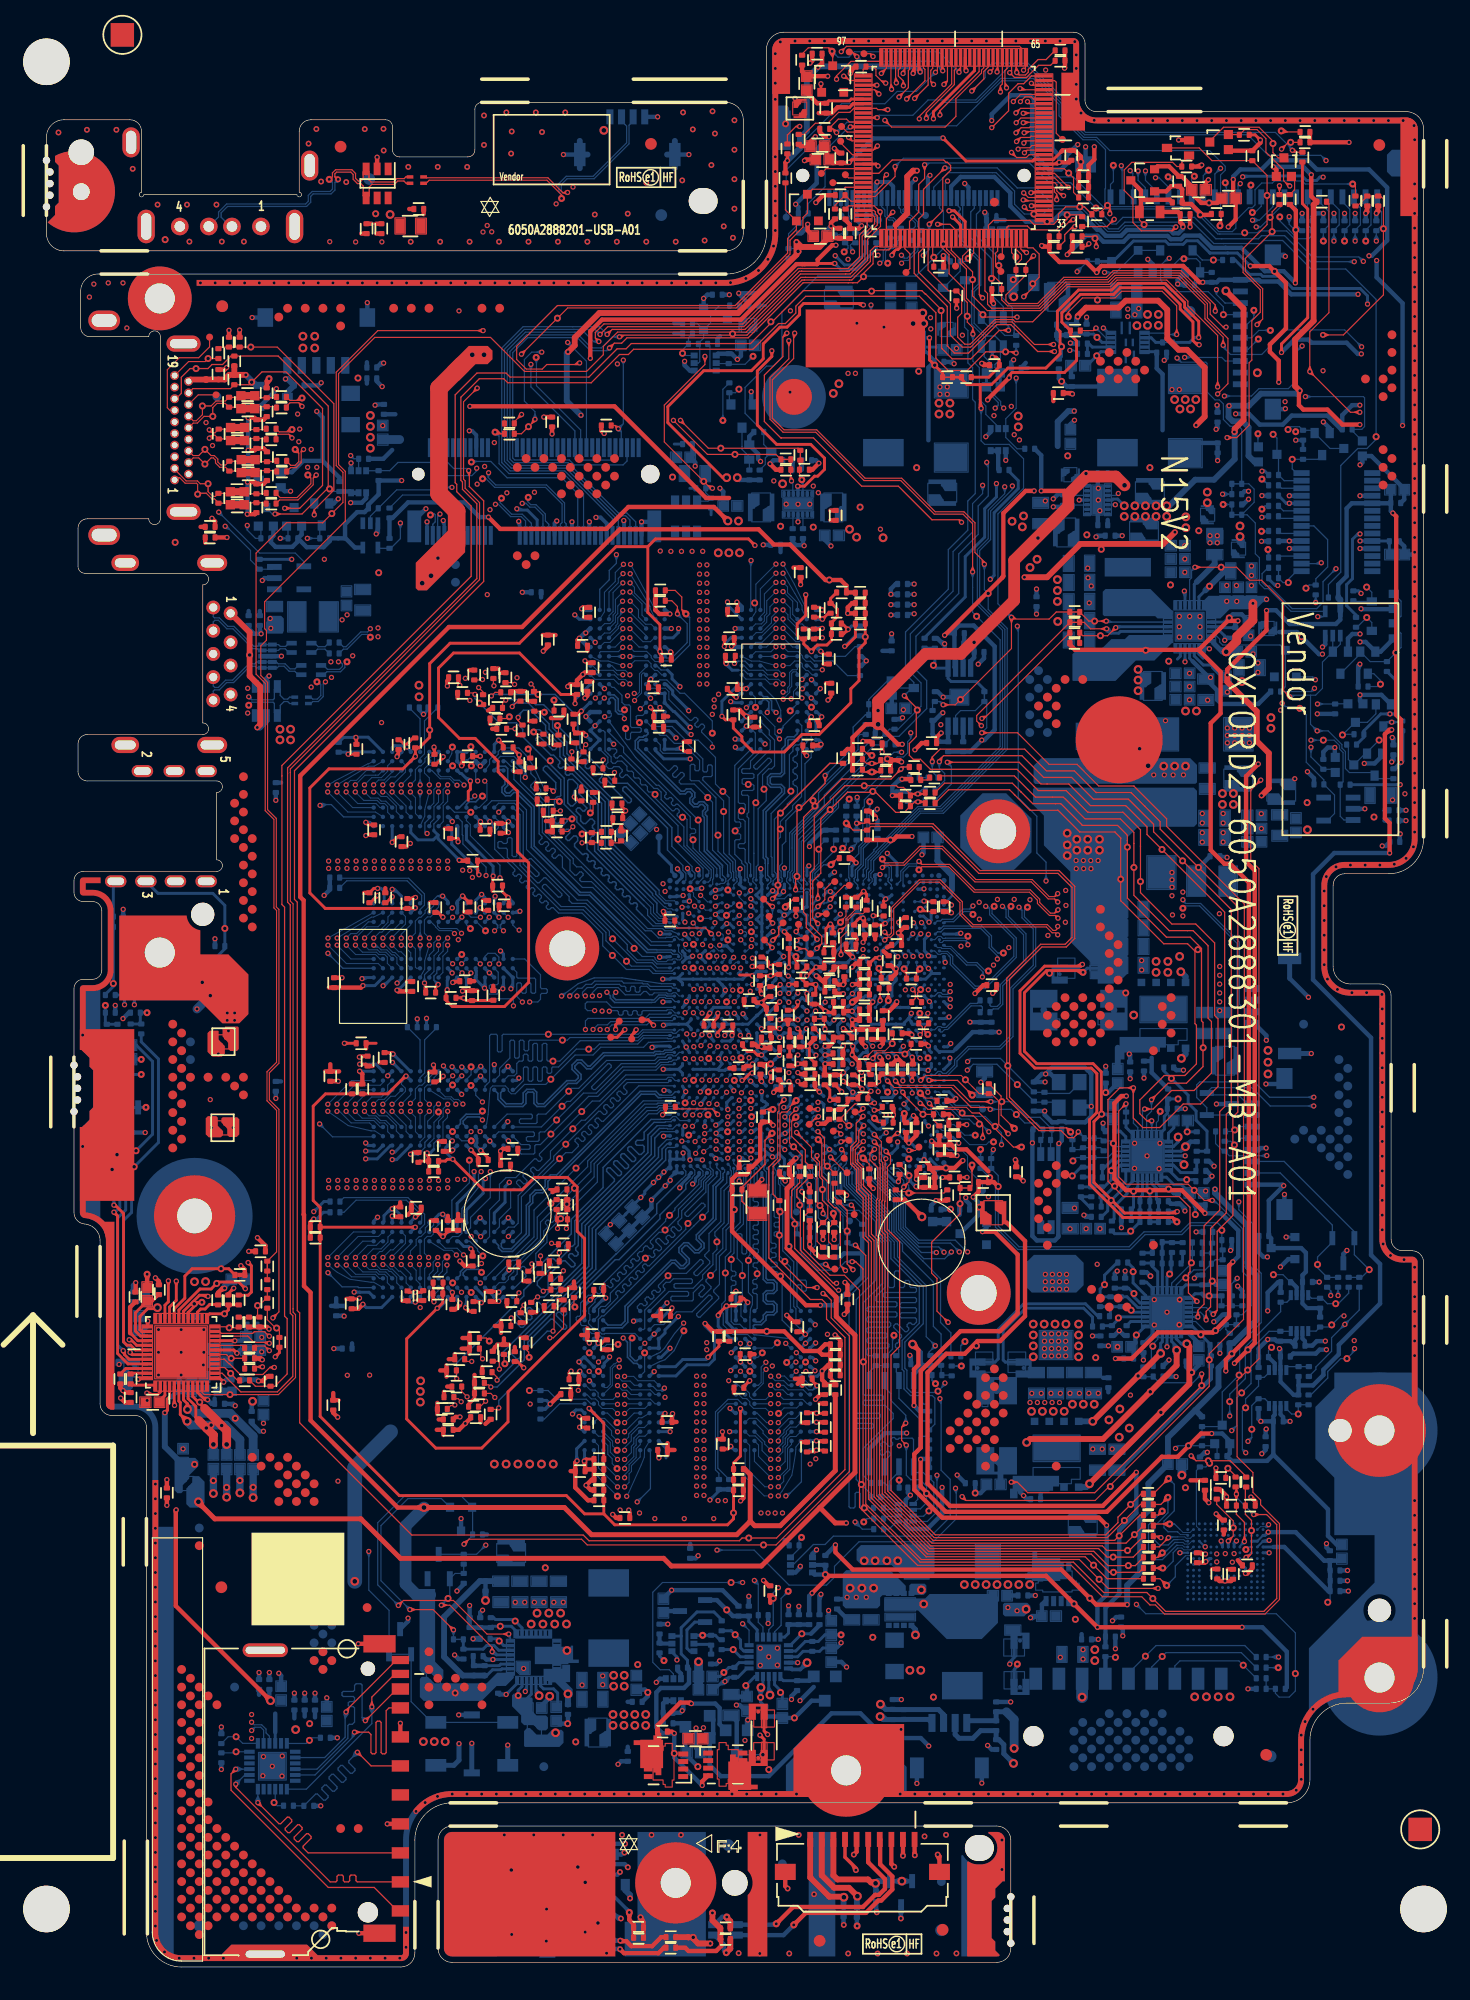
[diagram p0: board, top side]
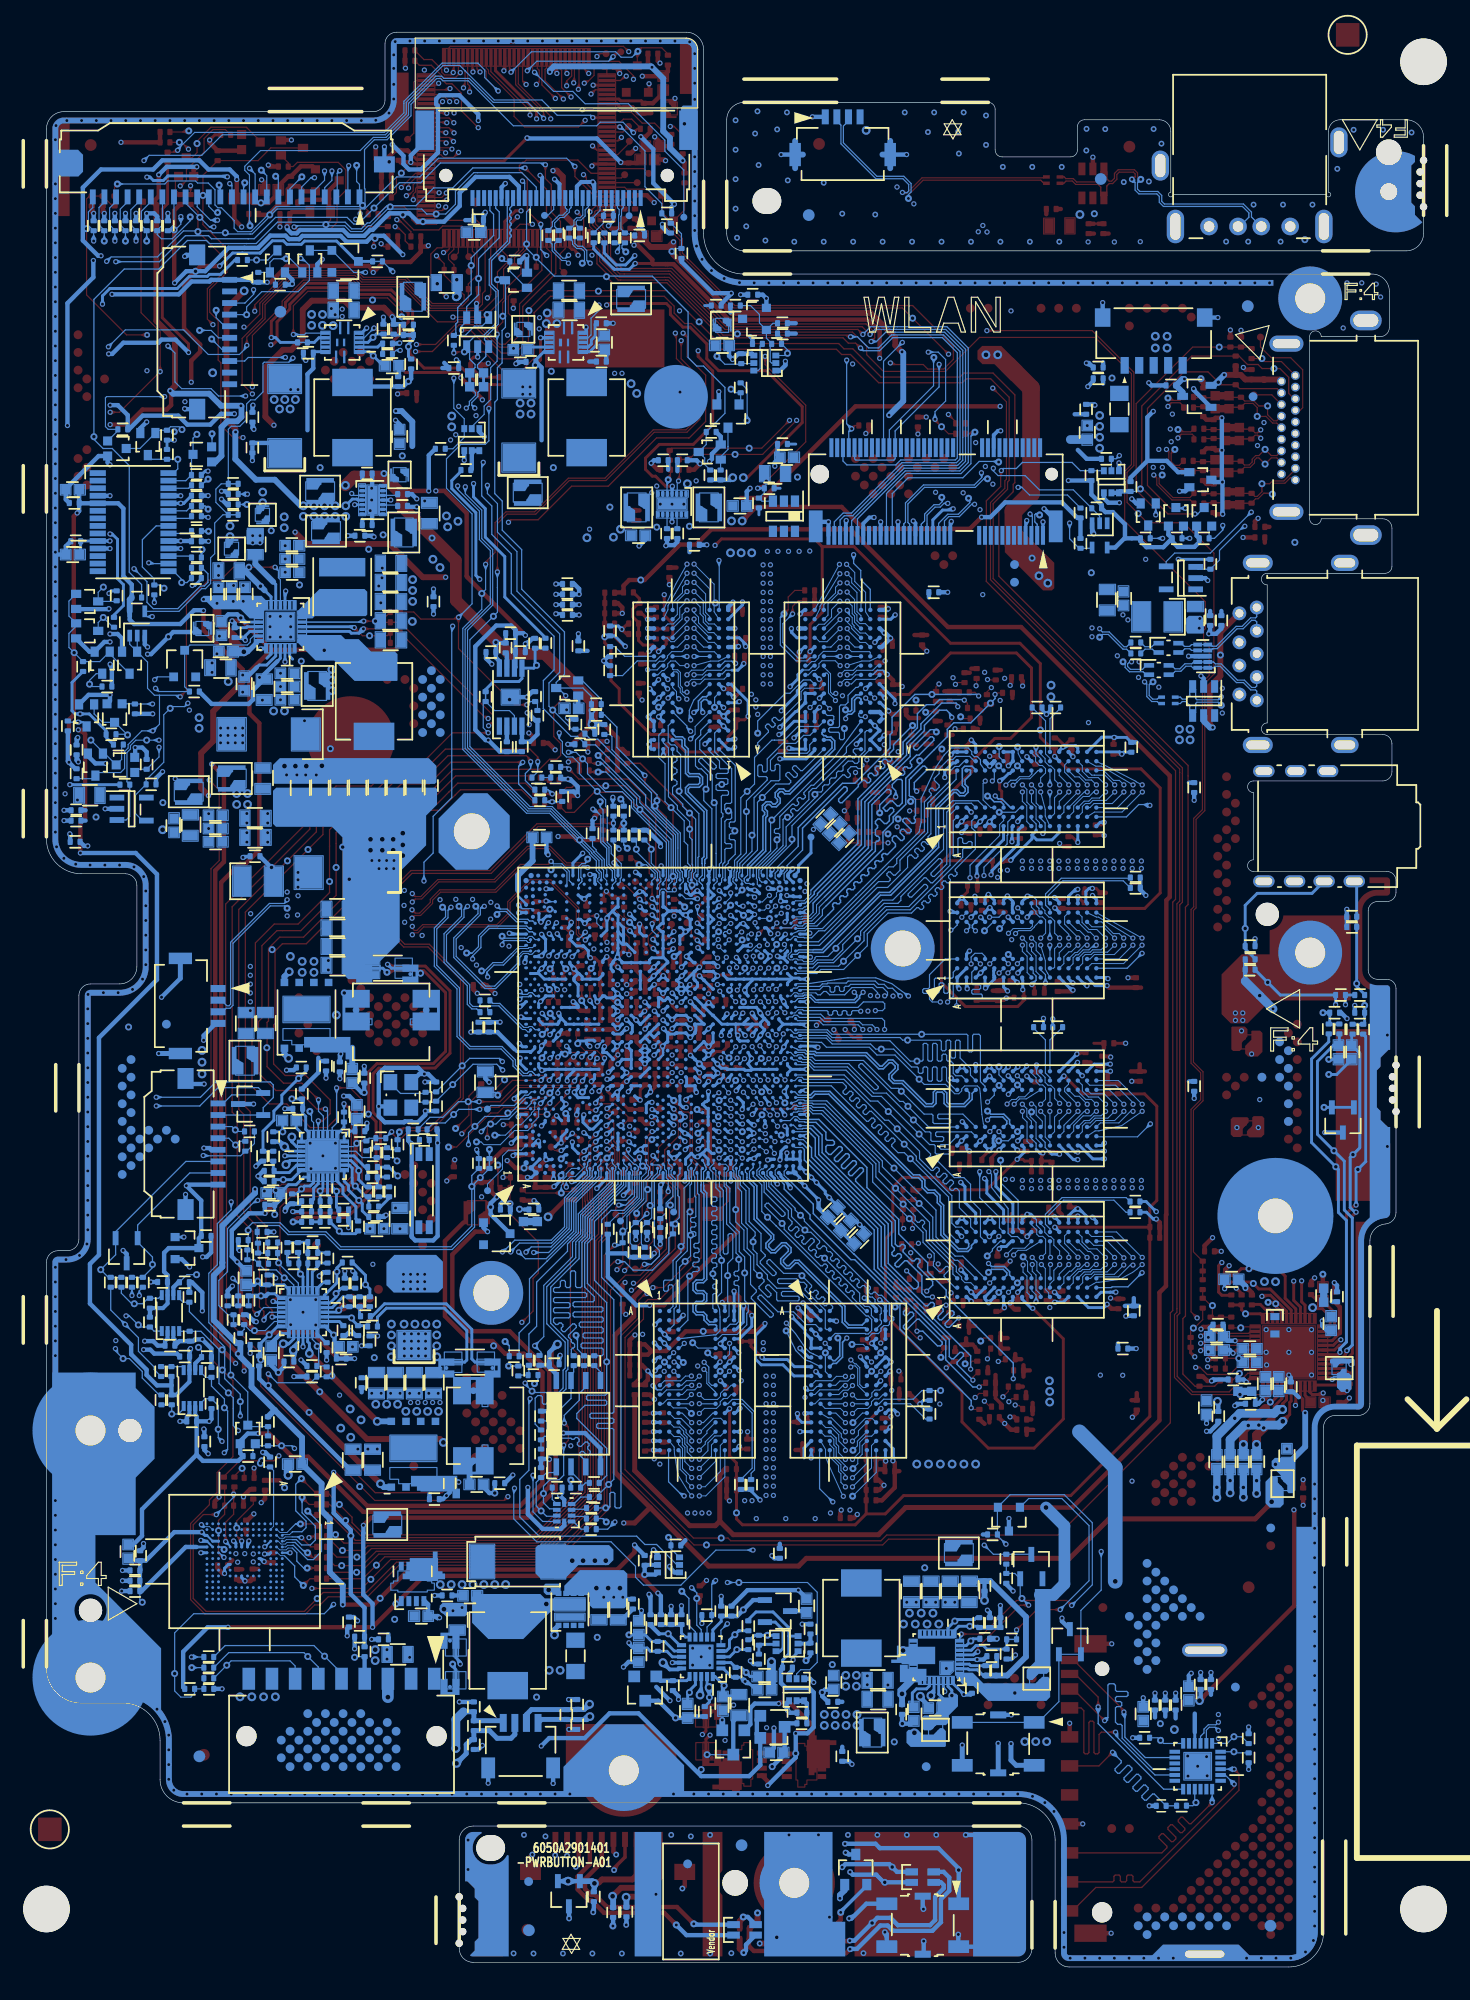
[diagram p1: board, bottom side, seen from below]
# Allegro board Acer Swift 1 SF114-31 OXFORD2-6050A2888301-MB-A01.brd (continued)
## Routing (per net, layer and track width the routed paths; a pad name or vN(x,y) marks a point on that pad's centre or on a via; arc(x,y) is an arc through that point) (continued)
M_B_B<11>: length 119
  TOP w0.102: R4167.2 38.32,49.45 v1(38.67,49.1)
  L3 w0.102: v1(56.07,43.04) 52.72,43.04 50.03,45.73 48.62,45.73 48.52,45.63 48.52,45.29 48.41,45.19 48.21,45.19 48.11,45.29 48.11,46.16 48.01,46.26 47.8,46.26 47.7,46.16 47.7,45.41 47.6,45.3 47.4,45.3 47.3,45.41 47.3,46.16 47.19,46.26 46.99,46.26 46.89,46.16 46.89,45.41 46.79,45.3 46.58,45.3 46.48,45.41 46.48,45.63 46.38,45.73 45.63,45.73 44.13,47.24 40.53,47.24 v1(38.67,49.1) 38.63,49.1 32.58,55.15 32.33,55.15 29.37,58.11 29.37,58.77 27.83,60.3 27.83,61.52 26.31,63.04 26.31,67.42 v1(26.71,67.81)
  L4 w0.089: v1(26.64,74.38) 27.03,73.99 27.03,73.61 26.71,73.29 v1(26.71,67.81) 26.71,67.72 27.09,67.34 27.09,61.83 26.65,61.38 v1(26.65,61.17) ; v1(56.69,70.29) 56.69,70.29 56.16,69.76 56.16,68.73 ; v1(62.46,42.98) 62.25,42.98 61.96,43.27 61.74,43.27 61.59,43.12 61.35,43.12 61.19,43.27 60.95,43.27 60.8,43.12 60.56,43.12 60.41,43.27 60.17,43.27 60.01,43.12 59.77,43.12 59.62,43.27 57.18,43.27 57.03,43.42 56.55,43.42 56.16,43.04 v1(56.07,43.04) 52.84,43.04 52.52,43.36 49.6,43.36 v3(49.22,42.97)
  L4 w0.152: v1(38.67,49.1) 39.57,49.1 47.74,57.26 47.74,58.13 53.83,64.22 56.16,66.55 56.16,68.73
  BOTTOM w0.089: U4107.R7 28.69,75.28 27.54,75.28 v1(26.64,74.38) ; U4104.R7 61.42,45 61.42,44.03 v1(62.46,42.98) ; v1(26.65,61.17) 27.7,62.21 28.45,62.21 28.8,62.57 U4106.R7 ; U4500.BB5 v1(56.69,70.29) ; v3(49.22,42.97) 48.8,43.39 48.8,43.82 48.42,44.2 48.42,44.95 U4105.R7
M_B_B<12>: length 114.2
  TOP w0.102: R4166.2 39.45,52.71 39.47,52.69 39.47,52.07 v3(39.54,52)
  L3 w0.102: v1(56.07,45.41) 54.75,45.41 54.45,45.7 53.67,45.7 51.15,48.22 51.15,49.4 50.03,50.52 49.04,50.52 48.64,50.12 46.13,50.12 46.03,50.22 46.03,50.6 45.93,50.7 45.73,50.7 45.62,50.6 45.62,50.22 45.52,50.12 45.32,50.12 45.22,50.22 45.22,50.6 45.12,50.7 44.91,50.7 44.81,50.6 44.81,50.22 44.71,50.12 44.51,50.12 44.41,50.22 44.41,50.79 44.3,50.9 44.1,50.9 44,50.8 44,50.22 43.9,50.12 43.69,50.12 43.59,50.22 43.59,50.92 43.48,51.03 43.28,51.03 43.19,50.93 43.19,50.22 43.08,50.12 41.43,50.12 v3(39.54,52) 39.25,52 34.74,56.52 34.74,57.08 32.57,59.25 32.57,59.56 32.67,59.66 33.02,59.66 33.11,59.76 33.11,59.96 33.01,60.07 32.67,60.07 32.57,60.17 32.57,61.63 32.67,61.73 33.01,61.73 33.11,61.83 33.11,62.03 33.01,62.13 32.67,62.13 32.57,62.24 32.57,62.55 32.46,62.66 32.23,62.66 32.13,62.56 32.13,62.09 32.02,61.98 31.82,61.98 31.72,62.08 31.72,62.56 31.62,62.66 31.05,62.66 30.22,63.49 30.22,63.64 30.49,63.91 30.49,64.05 30.34,64.2 30.2,64.2 29.93,63.93 29.78,63.93 29.21,64.5 29.21,66.22 28.68,66.75 28.68,67.51 28.98,67.81 v1(29.08,67.81)
  L4 w0.089: v1(29.01,74.38) 29.39,73.99 29.39,73.46 29.15,73.22 29.15,67.89 v1(29.08,67.81) 29.08,67.77 29.46,67.38 29.46,67.01 29.16,66.71 29.16,61.73 29.16,61.31 v1(29.02,61.17) ; v1(62.46,45.35) 62.32,45.49 61.89,45.49 61.81,45.4 61.81,45.31 61.72,45.22 61.5,45.22 61.41,45.31 61.41,45.4 61.32,45.49 57.17,45.49 56.87,45.79 56.55,45.79 56.19,45.44 56.1,45.44 v1(56.07,45.41) 55.54,45.41 55.39,45.56 53.44,45.56 53.28,45.72 50.09,45.72 50.01,45.73 49.64,45.73 v1(49.25,45.34)
  L4 w0.152: v1(54.8,71.2) 54.36,71.2 49.07,65.91 49.07,61.94 42.32,55.19 42.32,54.79 v3(39.54,52)
  BOTTOM w0.089: U4106.N7 30.62,62.55 29.89,61.82 29.67,61.82 29.03,61.17 v1(29.02,61.17) ; U4500.BF6 v1(54.8,71.2) ; U4105.N7 48.74,46.22 48.74,45.85 v1(49.25,45.34) ; U4107.N7 30.07,75.07 29.7,75.07 v1(29.01,74.38) ; v1(62.46,45.35) 61.81,46 61.81,46.21 U4104.N7
M_B_B<13>: length 127
  TOP w0.102: v1(35.39,50.72) 35.36,50.74 R4169.2
  L3 w0.102: v1(25.13,67.18) 25.13,61.8 25.46,61.47 25.46,60.69 25.47,60.68 25.47,60.25 25.89,59.83 26.04,59.83 26.19,59.98 26.33,59.98 26.49,59.82 26.49,59.68 26.34,59.53 26.34,59.38 26.49,59.23 26.64,59.23 26.79,59.38 26.93,59.38 27.09,59.22 27.09,59.08 26.94,58.92 26.94,58.78 27.09,58.63 27.23,58.63 27.39,58.78 27.53,58.78 27.69,58.63 27.69,58.48 27.53,58.33 27.53,58.19 27.68,58.04 27.82,58.04 27.97,58.2 28.12,58.2 28.26,58.05 28.26,57.91 28.11,57.76 28.11,57.61 28.25,57.47 28.39,57.47 28.55,57.62 28.69,57.62 28.83,57.48 28.83,57.33 28.68,57.18 28.68,57.04 28.86,56.86 29,56.86 29.16,57.01 29.3,57.01 29.45,56.87 29.45,56.72 29.3,56.57 29.3,56.42 29.46,56.26 29.6,56.26 29.75,56.42 29.9,56.42 30.07,56.25 30.07,56.1 29.92,55.95 29.92,55.81 35.01,50.72 v1(35.39,50.72) 35.39,50.62 40.31,45.7 44.64,45.7 45.76,44.58 46.98,44.58 48.19,43.36 50.97,43.36 52.48,41.85 56.31,41.85 v1(56.71,41.46)
  L4 w0.089: v1(63.12,41.4) 63.12,41.13 63,41 61.97,41 61.51,41.46 59.5,41.46 59.34,41.62 59.1,41.62 58.94,41.46 58.71,41.46 58.55,41.62 58.32,41.62 58.15,41.46 57.92,41.46 57.76,41.62 57.53,41.62 57.37,41.46 v1(56.71,41.46) 56.62,41.46 56.23,41.07 54.76,41.07 54.44,41.39 v1(49.86,41.39) ; v1(25.06,73.77) 25.06,73.63 24.73,73.31 24.73,67.66 25.13,67.26 v1(25.13,67.18) 25.13,62.12 24.67,61.66 24.67,60.9 v1(25.06,60.51)
  BOTTOM w0.089: v1(63.12,41.4) 63.59,41.86 63.59,42.37 64.12,42.9 64.12,44.41 U4104.T3 ; U4106.T3 28.09,59.5 26.31,59.5 25.3,60.51 v1(25.06,60.51) ; U4107.T3 27.87,72.77 26.28,72.77 25.28,73.77 v1(25.06,73.77) ; U4105.T3 51.21,43.97 50.45,43.22 50.45,42.72 50.25,42.52 50.25,41.78 v1(49.86,41.39)
  BOTTOM w0.102: U4500.BF10 54.63,72.97 54.28,73.32 54.03,73.32 53.79,73.07 52.98,73.07
  BOTTOM w0.124: v1(35.39,50.72) 35.39,52.06 41.17,57.85 41.17,58.36 42.77,59.95 42.77,60.71 45.26,63.2 45.26,64.45 48.01,67.2 48.01,68.93 52.15,73.07 52.98,73.07 52.98,73.07
M_B_B<14>: length 120.2
  TOP w0.102: R4170.2 37.41,48.31 v1(37.88,48.78)
  L3 w0.102: v1(56.07,42.25) 52.55,42.25 50.65,44.15 48.91,44.15 48.81,44.25 48.81,44.4 48.7,44.51 48.49,44.51 48.4,44.41 48.4,44.25 48.3,44.15 47.85,44.15 47.18,44.82 45.86,44.82 44.74,45.94 43.41,45.94 43.31,46.05 43.31,46.25 43.41,46.35 43.93,46.35 44.03,46.45 44.03,46.66 43.93,46.76 43.01,46.76 42.91,46.66 42.91,46.05 42.8,45.94 40.59,45.94 37.88,48.66 v1(37.88,48.78) 37.88,48.86 32.07,54.67 31.99,54.67 28.86,57.8 28.86,57.81 26.5,60.16 26.49,60.16 26.26,60.4 26.26,61.38 25.52,62.11 25.52,67.42 25.92,67.81 v1(25.92,67.81)
  L4 w0.089: v1(55.94,71.16) 55.94,71.16 55.79,71.16 55.44,70.81 54.44,70.81 54.28,70.65 ; v1(25.85,74.38) 26.24,73.99 26.24,73.61 25.92,73.29 v1(25.92,67.81) 25.92,67.72 26.3,67.34 26.3,61.93 25.85,61.48 v1(25.85,61.14) ; v1(49.25,42.18) 49.64,42.57 54.48,42.57 54.8,42.25 v1(56.07,42.25) 56.16,42.25 56.55,42.63 59.25,42.63 59.41,42.47 59.64,42.47 59.81,42.63 60.04,42.63 60.2,42.47 60.43,42.47 60.59,42.63 60.83,42.63 60.99,42.47 61.22,42.47 61.38,42.63 61.89,42.63 62.33,42.19 v1(62.46,42.19)
  L4 w0.152: v1(37.88,48.78) 37.88,48.92 40.73,51.78 40.73,51.84 40.77,51.88 40.77,52.48 42.65,54.36 42.65,55.06 49.4,61.8 49.4,65.77 54.28,70.65
  BOTTOM w0.089: U4107.T7 27.09,75.62 v1(25.85,74.38) ; v1(55.94,71.16) 55.94,71.17 U4500.BD7 ; v1(25.85,61.14) 27.28,62.57 28.22,62.57 U4106.T7 ; v1(62.46,42.19) 61.06,43.59 61.06,44.55 U4104.T7 ; v1(49.25,42.18) 48.01,43.42 U4105.T7
M_B_B<15>: length 119.9
  TOP w0.102: v1(43.41,54.24) 43.72,54.24 44.6,55.12 R4171.2
  L3 w0.102: v1(30.66,67.81) 30.66,67.81 30.26,67.42 30.26,66.84 33.79,63.31 33.79,62.8 34.73,61.86 36.06,61.86 36.77,61.15 36.77,60.55 36.67,60.44 35.74,60.44 35.65,60.35 35.65,60.15 35.76,60.04 36.67,60.04 36.77,59.93 36.77,59.73 36.67,59.63 35.74,59.63 35.65,59.54 35.65,59.33 35.76,59.22 36.67,59.22 36.77,59.12 36.77,58.7 39.09,56.38 41.27,56.38 v1(43.41,54.24) 43.67,54.24 43.91,54.49 44.15,54.49 44.25,54.39 44.25,53.2 44.35,53.11 44.55,53.11 44.66,53.22 44.66,54.39 44.76,54.49 44.97,54.49 45.07,54.39 45.07,53.2 45.16,53.11 45.36,53.11 45.47,53.22 45.47,54.39 45.57,54.49 45.78,54.49 45.88,54.39 45.88,53.33 45.98,53.23 46.19,53.23 46.29,53.33 46.29,54.39 46.39,54.49 47.45,54.49 48,53.93 48,53.46 48.13,53.34 48.39,53.34 48.49,53.43 48.49,53.74 48.59,53.84 48.79,53.84 48.89,53.74 48.89,53.37 49,53.27 49.85,53.27 52.2,50.92 52.2,49.69 53.18,48.71 54.13,48.71 55.85,46.99 v1(56.07,46.99)
  L4 w0.089: v1(30.6,61.17) 30.71,61.28 30.71,66.68 31.04,67.02 31.04,67.34 30.66,67.72 v1(30.66,67.81) 30.72,67.87 30.72,73.01 30.99,73.28 30.99,73.99 v1(30.6,74.38) ; 55.75,69.21 55.9,69.36 55.9,70.05 v1(55.99,70.14) ; v3(49.22,46.93) 49.6,47.32 52.93,47.32 53.2,47.05 55.49,47.05 55.55,46.99 v1(56.07,46.99) 56.16,46.99 56.55,47.37 57.04,47.37 57.13,47.28 57.13,47.15 57.22,47.06 57.43,47.06 57.52,47.15 57.52,47.28 57.61,47.37 57.8,47.37 58.13,47.04 62.35,47.04 v1(62.46,46.93)
  L4 w0.152: v1(43.41,54.24) 44.25,54.24 44.57,54.56 44.57,54.75 44.02,55.29 44.02,55.48 44.16,55.62 44.35,55.62 44.89,55.07 45.08,55.07 45.21,55.21 45.21,55.4 44.67,55.94 44.67,56.13 44.8,56.26 44.99,56.26 45.54,55.72 45.73,55.72 47.34,57.33 47.34,58.2 53.17,64.03 53.17,64.22 52.67,64.72 52.67,64.91 52.8,65.05 52.99,65.05 53.5,64.54 53.69,64.54 53.82,64.68 53.82,64.87 53.27,65.42 53.27,65.62 53.4,65.75 53.58,65.75 54.14,65.19 54.33,65.19 54.47,65.32 54.47,65.51 53.65,66.33 53.65,66.54 53.79,66.67 53.95,66.67 54.79,65.84 54.98,65.84 55.3,66.16 55.3,68.76 55.75,69.21
  BOTTOM w0.089: U4104.M7 61.29,47.75 62.11,46.93 v1(62.46,46.93) ; v1(30.6,61.17) 30.6,61.52 31.42,62.34 U4106.M7 ; U4500.BD5 v1(55.99,70.14) ; U4107.M7 31.42,75.62 31.42,75.2 v1(30.6,74.38) ; U4105.M7 48.39,47.75 v3(49.22,46.93)
M_B_BS0: length 119.8
  TOP w0.102: v1(40.09,55.96) 40.06,55.92 R4153.2
  L3 w0.102: v1(56.71,46.2) 56.32,46.59 55.91,46.59 55.7,46.8 55.55,46.8 55.26,46.5 55.12,46.5 54.97,46.65 54.97,46.79 55.27,47.09 55.27,47.23 55.12,47.37 54.98,47.37 54.69,47.08 54.54,47.08 54.4,47.22 54.4,47.37 54.69,47.66 54.69,47.8 54.03,48.46 53.08,48.46 52.92,48.63 52.77,48.63 52.61,48.46 52.46,48.46 52.32,48.6 52.32,48.75 52.49,48.91 52.49,49.06 51.96,49.59 51.96,50.82 49.75,53.03 48.2,53.03 48.1,52.92 48.1,52.65 48,52.54 47.79,52.54 47.69,52.65 47.69,52.92 47.59,53.03 47.31,53.03 46.99,53.35 46.65,53.35 46.17,52.87 44.23,52.87 41.14,55.96 v1(40.09,55.96) 39.15,55.96 39.05,55.85 39.05,55.57 39.15,55.47 41,55.47 41.1,55.37 41.1,55.17 40.99,55.07 38.74,55.07 38.64,55.17 38.64,55.86 38.54,55.96 38.08,56.42 38.08,56.52 38.26,56.71 38.26,56.85 38.12,57 37.97,57 37.57,56.59 37.42,56.59 36.9,57.11 36.9,57.25 37.33,57.68 37.33,57.8 37.19,57.94 37.01,57.94 36.61,57.54 36.47,57.54 36.23,57.78 36.23,58.36 34.96,59.63 34.96,59.89 35.06,59.99 35.3,59.99 35.41,60.09 35.41,60.3 35.3,60.4 35.06,60.4 34.96,60.5 34.96,61.43 34.78,61.62 34.61,61.62 32.04,64.18 31.74,64.18 31.23,64.7 31.23,65.23 29.87,66.59 v1(29.87,67.18)
  L4 w0.089: v1(49.86,46.14) 53.14,46.14 53.52,45.76 55.34,45.76 55.39,45.81 56.23,45.81 56.62,46.2 v1(56.71,46.2) 56.75,46.2 57.2,45.75 60.22,45.75 60.31,45.84 60.31,45.98 60.4,46.07 60.62,46.07 60.71,45.98 60.71,45.84 60.79,45.75 62.74,45.75 v1(63.12,46.14) ; v1(29.81,60.56) 29.42,60.95 29.42,66.53 29.87,66.97 v1(29.87,67.18) 29.87,67.26 29.48,67.65 29.48,68.08 29.43,68.12 29.43,73.05 29.81,73.43 v1(29.81,73.77)
  BOTTOM w0.089: v1(49.86,46.14) 51.07,47.35 51.35,47.35 U4105.M2 ; v1(29.81,73.77) 31.02,72.56 31.02,72.02 U4107.M2 ; v1(29.81,60.56) 29.81,60.56 30.38,59.99 30.53,59.99 31.02,59.5 31.02,58.97 U4106.M2 ; U4104.M2 64.61,47.29 64.03,47.29 63.12,46.38 v1(63.12,46.14)
  BOTTOM w0.102: 52.83,71.81 53.03,72.01 54.36,72.01 U4500.BH8
  BOTTOM w0.124: v1(40.09,55.96) 40.9,55.15 41.09,55.15 41.26,55.31 41.26,55.49 40.5,56.25 40.5,56.45 40.62,56.57 40.78,56.57 41.56,55.79 41.74,55.79 41.87,55.92 41.87,56.1 41.44,56.52 41.44,56.72 41.57,56.85 41.72,56.85 42.17,56.4 42.35,56.4 42.47,56.53 42.47,56.7 42.19,56.99 42.19,57.16 42.32,57.29 42.5,57.29 42.78,57.01 42.95,57.01 46.47,60.53 46.47,63.93 52.46,69.92 52.46,71.45 52.83,71.81
M_B_BS1: length 126.3
  TOP w0.102: R4154.2 37.93,54.23 v3(38.19,53.96)
  L3 w0.102: v1(56.07,46.2) 55.07,46.2 54.33,46.94 53.57,46.94 51.63,48.88 51.63,50.68 49.59,52.73 49.23,52.73 49.23,52.72 49.2,52.72 48.97,52.5 48.97,52.19 48.55,51.76 47.37,51.76 46.56,52.57 44.18,52.57 42.8,53.96 41.81,53.96 41.71,54.06 41.71,54.83 41.6,54.94 41.4,54.94 41.3,54.84 41.3,54.06 41.2,53.96 v3(38.19,53.96) 37.88,54.27 37.88,54.41 38.42,54.95 38.42,55.08 38.28,55.22 38.11,55.22 37.59,54.7 37.45,54.7 37.31,54.84 37.31,54.99 38.01,55.69 38.01,55.83 37.86,55.98 37.72,55.98 37.02,55.28 36.88,55.28 35.23,56.93 35.23,57.28 34.15,58.35 34.15,58.72 34.25,58.82 34.53,58.82 34.63,58.92 34.63,59.12 34.53,59.22 33.7,59.22 33.6,59.33 33.6,59.53 33.7,59.63 34.54,59.63 34.64,59.73 34.64,59.93 34.54,60.04 34.25,60.04 34.15,60.14 34.15,61.73 32.74,63.14 31.25,63.14 30.98,63.41 30.98,65.13 29.47,66.64 29.47,67.48 29.8,67.81 v1(29.87,67.81)
  L4 w0.089: v1(29.81,74.38) 30.21,73.98 30.21,68.28 29.87,67.93 v1(29.87,67.81) 29.87,67.72 30.25,67.34 30.25,62.57 29.81,62.12 29.81,61.18 v1(29.81,61.18) ; v1(58.66,75.41) 58.28,75.03 56.21,75.03 56.16,75.08 54.5,75.08 54.41,75 52.99,75 52.92,75.06 52.44,75.06 ; v1(62.46,46.14) 62.37,46.14 61.14,46.14 60.7,46.58 57.89,46.58 57.8,46.49 57.8,46.34 57.71,46.25 57.49,46.25 57.41,46.34 57.41,46.49 57.32,46.58 56.55,46.58 56.16,46.2 v1(56.07,46.2) 55.19,46.2 54.85,46.54 49.65,46.54 v1(49.25,46.14)
  L4 w0.152: 52.44,75.06 49.56,75.06 44.68,70.18 44.68,67.5 43.19,66.01 43.19,63.42 44,62.61 44,61.96 43.8,61.75 43.8,61.06 41.2,58.46 41.2,57.71 38.19,54.7 v3(38.19,53.96)
  BOTTOM w0.089: U4106.N8 30.96,63.03 30.96,62.38 29.84,61.26 29.84,61.21 v1(29.81,61.18) ; U4104.N8 60.61,47.3 61.24,47.3 62.4,46.14 v1(62.46,46.14) ; U4500.AY14 v1(58.66,75.41) ; v1(29.81,74.38) 29.86,74.38 30.96,75.48 30.96,75.76 30.62,76.1 30.62,76.42 U4107.N8 ; v1(49.25,46.14) 49.25,46.19 48.14,47.3 47.56,47.3 U4105.N8
M_B_BS2: length 114.8
  TOP w0.102: v1(43.69,54.81) 43.78,54.9 R4155.2
  L3 w0.102: v1(56.71,46.99) 56.31,47.38 55.8,47.38 53.71,49.47 53.71,50.62 53.55,50.77 53.41,50.77 52.73,50.09 52.58,50.09 52.44,50.24 52.44,50.38 53.12,51.06 53.12,51.21 52.58,51.74 51.72,51.74 51.19,52.28 51.19,52.48 51.08,52.58 50.88,52.58 50.78,52.68 50.78,52.89 50.88,52.99 51.08,52.99 51.18,53.09 51.18,53.29 51.08,53.39 50.07,53.39 49.97,53.49 49.97,53.69 50.08,53.8 51.08,53.8 51.19,53.91 51.19,54.47 50.93,54.73 49.43,54.73 49.32,54.63 49.32,54.19 49.22,54.09 49.02,54.09 48.92,54.19 48.92,54.63 48.82,54.73 48.61,54.73 48.51,54.63 48.51,54.19 48.41,54.09 48.21,54.09 48.1,54.19 48.1,54.63 48,54.73 43.78,54.73 v1(43.69,54.81) 43.18,54.81 42.95,55.04 42.95,55.19 43.5,55.73 43.5,55.87 43.35,56.02 43.21,56.02 42.67,55.47 42.52,55.47 42.38,55.62 42.38,55.76 42.92,56.31 42.92,56.45 42.78,56.59 42.63,56.59 42.09,56.05 41.95,56.05 41.37,56.63 39.19,56.63 38.14,57.67 38.14,57.81 38.63,58.3 38.63,58.45 38.49,58.59 38.34,58.59 37.85,58.1 37.71,58.1 37.02,58.8 37.02,62.08 36.77,62.32 35.41,62.32 34.32,63.42 34.02,63.42 30.66,66.79 v1(30.66,67.18)
  L4 w0.089: v1(49.86,46.93) 49.95,46.85 54.94,46.85 55.18,46.6 56.23,46.6 56.62,46.99 v1(56.71,46.99) 56.86,46.84 61.08,46.84 61.17,46.75 61.17,46.64 61.26,46.55 61.47,46.55 61.56,46.64 61.56,46.75 61.65,46.84 62.01,46.84 62.3,46.54 63,46.54 63.12,46.66 v1(63.12,46.93) ; v1(30.6,60.56) 30.2,60.95 30.2,62.23 30.51,62.53 30.51,66.99 30.66,67.14 v1(30.66,67.18) 30.66,67.22 30.27,67.61 30.27,68 30.52,68.25 30.52,73.68 v1(30.6,73.77)
  BOTTOM w0.089: v1(63.12,46.93) 63.94,47.75 U4104.M3 ; U4105.M3 50.69,47.75 v1(49.86,46.93) ; U4107.M3 31.42,72.94 31.42,72.94 v1(30.6,73.77) ; U4106.M3 31.42,59.73 v1(30.6,60.56)
  BOTTOM w0.102: U4500.BF2 54.96,68.79 55.15,68.6 55.15,68.26 54.8,67.91 54.78,67.91
  BOTTOM w0.124: 54.78,67.91 52.64,65.76 52.64,64.96 49.15,61.47 49.12,61.47 44.59,56.93 44.59,56.76 44.86,56.49 44.86,56.28 44.73,56.15 44.58,56.15 44.28,56.45 44.11,56.45 43.98,56.33 43.98,56.15 44.86,55.27 44.86,55.11 44.73,54.98 44.54,54.98 43.68,55.85 43.5,55.85 41.51,53.86 41.51,53.7 41.67,53.55 41.92,53.55 43.19,54.81 v1(43.69,54.81)
M_B_CAS_N: length 109.9
  TOP w0.102: v1(44.59,60.01) 44.35,59.78 R4150.2
  L3 w0.102: v1(56.07,50.14) 55.96,50.14 55.4,50.71 55.4,52.31 54.74,52.97 54.74,53.73 54.07,54.41 54.07,55.24 50.75,58.56 49.54,58.56 48.08,60.01 47.84,60.01 47.74,60.12 47.74,60.77 47.64,60.87 47.44,60.87 47.33,60.77 47.33,59.83 47.24,59.73 47.03,59.73 46.93,59.83 46.93,60.77 46.83,60.87 46.62,60.87 46.52,60.77 46.52,59.83 46.42,59.73 46.22,59.73 46.12,59.83 46.12,60.77 46.01,60.87 45.81,60.87 45.71,60.77 45.71,59.83 45.61,59.73 45.41,59.73 45.3,59.83 45.3,60.77 45.2,60.87 45,60.87 44.9,60.77 44.9,60.12 44.79,60.01 v1(44.59,60.01) 44.4,60.2 44.4,60.75 44.27,60.88 42.48,60.88 42.22,61.14 42.22,61.46 42.66,61.91 42.66,64.53 43.03,64.89 43.03,65.06 42.36,65.73 41.5,65.73 41.39,65.83 41.39,66.69 41.3,66.79 41.1,66.79 40.99,66.68 40.99,65.62 40.88,65.51 40.69,65.51 40.58,65.62 40.58,66.65 40.48,66.75 40.28,66.75 40.17,66.64 40.17,65.6 40.08,65.5 39.81,65.5 39.71,65.6 39.71,65.83 39.6,65.93 39.4,65.93 39.3,65.83 39.3,65.6 39.2,65.5 38.99,65.5 38.89,65.6 38.89,65.83 38.79,65.93 38.58,65.93 38.49,65.83 38.49,65.6 38.38,65.5 38.18,65.5 38.08,65.6 38.08,65.83 37.98,65.93 37.77,65.93 37.67,65.83 37.67,65.6 37.57,65.5 35.44,65.5 34.72,66.22 34.09,66.22 33.42,66.89 33.42,67.41 33.81,67.81 v1(33.81,67.81)
  L4 w0.089: v1(33.75,61.17) 33.75,61.17 33.75,61.9 33.38,62.28 33.38,65.61 34.2,66.44 34.2,67.34 33.81,67.72 v1(33.81,67.81) 33.81,72.99 34.2,73.37 34.2,74.01 v1(33.81,74.4) ; v1(49.25,50.13) 49.65,50.52 55.64,50.52 56.02,50.14 56.07,50.14 v1(56.07,50.14) 56.16,50.14 56.55,50.53 57.08,50.53 57.66,49.96 61.61,49.96 61.79,50.14 62.46,50.14 v1(62.46,50.14)
  BOTTOM w0.089: v1(62.46,50.14) 62.85,49.76 63.52,49.76 63.92,49.35 64.26,49.35 U4104.K3 ; v1(49.25,50.13) 49.65,49.73 50.06,49.73 50.43,49.35 U4105.K3 ; U4107.K3 33.02,72.42 32.88,72.56 32.88,72.92 33.41,73.45 33.41,74.14 33.67,74.4 v1(33.81,74.4) ; U4106.K3 33.02,59.71 33.35,60.04 33.35,60.76 v1(33.75,61.17)
  BOTTOM w0.102: 53.24,72.3 53.52,72.3 53.56,72.25 54.01,72.25 54.34,72.58 U4500.BG9
  BOTTOM w0.124: 53.24,72.3 52.87,72.3 52.16,71.59 52.16,70.05 46.17,64.06 46.17,60.66 43.99,58.47 43.76,58.47 43.57,58.66 43.57,59 v1(44.59,60.01)
M_B_CKE0: length 126.3
  TOP w0.102: v1(41.19,57.06) 40.9,56.77 R4145.2
  L3 w0.102: v1(56.07,47.78) 55.75,47.78 53.95,49.57 53.95,50.73 52.37,52.31 52.37,53.63 51.03,54.97 44.78,54.97 43.4,56.35 43.4,56.49 43.54,56.64 43.69,56.64 44.94,55.38 45.09,55.38 45.24,55.52 45.24,55.66 43.82,57.07 41.2,57.07 v1(41.19,57.06) 41.19,57.13 40.94,57.37 40.8,57.37 40.31,56.88 40.17,56.88 40.02,57.03 40.02,57.17 40.51,57.66 40.51,57.81 40.37,57.95 40.23,57.95 39.75,57.48 39.61,57.48 39.47,57.62 39.47,57.77 39.94,58.24 39.94,58.38 39.79,58.52 39.65,58.52 39.53,58.41 39.39,58.41 39.25,58.55 39.25,58.69 39.36,58.81 39.36,58.96 39.21,59.1 39.21,59.25 39.45,59.48 39.45,59.63 39.31,59.77 39.16,59.77 38.13,58.74 37.97,58.74 37.83,58.88 37.83,59.01 37.93,59.11 37.93,59.25 37.78,59.41 37.78,59.55 37.92,59.69 38.06,59.69 38.21,59.54 38.36,59.54 39.26,60.44 39.26,60.58 39.11,60.72 38.96,60.72 38.35,60.11 38.21,60.11 38.04,60.28 38.04,61.5 36.98,62.56 35.51,62.56 34.36,63.72 34.06,63.72 31.05,66.73 31.05,67.42 31.45,67.81 v1(31.45,67.81)
  L4 w0.089: v1(49.25,47.72) 49.65,48.11 54.14,48.11 54.48,47.78 v1(56.07,47.78) 56.16,47.78 56.55,48.16 57.58,48.16 58.2,47.55 60.09,47.55 60.27,47.72 60.66,47.72 60.82,47.87 61.06,47.87 61.21,47.72 61.45,47.72 61.6,47.87 61.84,47.87 62,47.72 v1(62.46,47.72) ; v1(31.39,61.17) 31.2,61.35 31.2,66.35 31.83,66.97 31.83,67.34 31.45,67.72 v1(31.45,67.81) 31.45,67.95 31.79,68.29 31.79,74.06 v1(31.39,74.45) ; 52.45,72.85 52.65,73.04 54.08,73.04 54.69,73.66 54.7,73.66 54.9,73.86 56.66,73.86 v3(57.06,73.46)
  L4 w0.152: v1(41.19,57.06) 41.53,57.4 41.53,58.06 46.45,62.99 46.45,63.51 46.32,63.65 45.54,63.65 45.4,63.78 45.4,63.97 45.54,64.11 46.32,64.11 46.45,64.24 46.45,64.43 46.32,64.56 45.37,64.56 45.25,64.69 45.25,64.88 45.39,65.02 46.32,65.02 46.45,65.15 46.45,65.34 46.32,65.48 45.54,65.48 45.4,65.61 45.4,65.8 45.54,65.93 46.32,65.93 46.45,66.07 46.45,66.85 52.45,72.85
  BOTTOM w0.089: v1(62.46,47.72) 62.03,48.16 60.98,48.16 60.66,48.48 60.66,48.72 60.43,48.95 60.43,48.95 60.38,49 60.06,49 59.71,49.35 59.47,49.35 U4104.K9 ; v1(49.25,47.72) 48.82,48.15 47.94,48.15 47.62,48.47 47.62,48.72 47.36,48.97 47,48.97 46.62,49.35 U4105.K9 ; v1(31.39,61.17) 31.39,61.73 31.89,62.22 31.89,62.71 32.15,62.97 32.3,62.97 32.67,63.34 32.67,63.71 33.02,64.06 U4106.K9 ; U4107.K9 33.02,77.07 32.64,76.69 32.64,76.27 32.39,76.02 32.14,76.02 31.82,75.69 31.82,74.88 v1(31.39,74.45) ; U4500.BB10 v3(57.06,73.46)
M_B_CKE1: length 123.7
  TOP w0.102: v3(45.58,56.9) 45.5,56.98 R4146.2
  L3 w0.102: v1(33.02,67.81) 32.63,67.42 32.63,66.93 33.87,65.69 34.44,65.69 35.12,65 40.28,65 40.49,64.79 40.49,61.07 40.59,60.97 40.79,60.97 40.89,61.07 40.89,62.98 41,63.09 41.2,63.09 41.3,62.98 41.3,60.62 41.7,60.22 43.48,60.22 45.58,58.12 v3(45.58,56.9) 46,56.9 46.1,57 46.1,58.13 46.21,58.25 46.42,58.25 46.5,58.16 46.5,57 46.61,56.9 47.26,56.9 47.36,57 47.36,58.82 47.46,58.91 48.5,58.91 48.61,58.81 48.61,58.6 48.51,58.5 47.86,58.5 47.77,58.41 47.77,57 47.86,56.91 48.55,56.91 48.66,57.02 48.66,57.99 48.75,58.07 50.55,58.07 53.59,55.04 53.59,54.2 54.26,53.53 54.26,52.69 54.91,52.04 54.91,50.41 55.96,49.36 v1(56.06,49.36)
  L4 w0.089: v1(57.83,74.38) 57.83,74.37 57.83,73.98 57.51,73.65 57.51,73.3 57.25,73.04 57.25,71.22 56.79,70.75 56.5,70.75 56.3,70.55 55.81,70.55 55.61,70.35 55.61,70.26 54.91,69.56 ; v1(62.46,49.35) 62.02,49.35 61.86,49.19 61.62,49.19 61.46,49.35 58.64,49.35 58.48,49.2 58.24,49.2 58.09,49.35 57.66,49.35 57.27,49.74 56.55,49.74 56.23,49.42 56.13,49.42 v1(56.06,49.36) 55.99,49.36 55.99,49.35 55.75,49.35 55.61,49.5 50.56,49.5 50.33,49.73 49.66,49.73 v1(49.25,49.32) ; v1(32.96,61.17) 32.96,61.17 32.91,61.22 32.91,66.12 33.41,66.62 33.41,67.34 33.02,67.72 v1(33.02,67.81) 33.02,67.96 33.23,68.17 33.23,73.14 33.41,73.31 33.41,73.99 v1(33.02,74.38)
  L4 w0.152: 54.91,69.56 54.91,68.27 52.94,66.3 52.94,65.68 52.14,64.88 51.95,64.88 51.82,64.74 51.82,64.55 52.43,63.94 52.43,63.75 52.3,63.62 52.11,63.62 51.5,64.23 51.31,64.23 51.17,64.1 51.17,63.91 51.78,63.3 51.78,63.11 51.65,62.97 51.46,62.97 50.85,63.58 50.66,63.58 50.53,63.45 50.53,63.26 51.14,62.65 51.14,62.46 51,62.33 50.81,62.33 50.38,62.76 50.19,62.76 50.06,62.63 50.06,62.43 50.49,62 50.49,61.81 v3(45.58,56.9)
  BOTTOM w0.089: v1(62.46,49.35) 62.04,48.93 60.9,48.93 60.64,49.19 60.64,49.46 60.33,49.77 60.1,49.77 59.71,50.15 59.46,50.15 U4104.J9 ; v1(49.25,49.32) 48.87,48.93 47.84,48.93 47.58,49.19 47.58,49.49 47.33,49.74 46.91,49.74 46.5,50.15 U4105.J9 ; U4107.J9 33.82,77.07 33.42,76.66 33.42,76.33 33.13,76.04 32.84,76.04 32.6,75.8 32.6,74.8 v1(33.02,74.38) ; v1(32.96,61.17) 32.6,61.53 32.6,62.74 32.84,62.99 33.17,62.99 33.36,63.18 33.36,63.54 33.82,64 U4106.J9 ; v1(57.83,74.38) 57.84,74.37 57.84,74.37 U4500.AY12
M_B_CLK0_DN: length 131.8
  TOP w0.137: v1(44.08,63.67) 44.09,63.68 C4623.2 44,64.55 R4186.1
  L3 w0.147: v1(35.46,67.9) 35.64,67.73 35.64,67.39 35.93,67.09 38,67.09 40.17,69.26 44.51,69.26 47.99,65.79 47.99,65.2 46.51,63.73 46.19,63.73 45.97,63.94 45.97,64.32 46.9,65.24 46.9,65.66 46.37,66.19 45.97,66.19 44.33,64.55 44.33,63.91 v1(44.08,63.67) 44.14,63.61 44.14,63.01 44.54,62.61 51.04,62.61 51.52,62.13 51.52,61.67 51.24,61.38 51.24,60.97 51.7,60.51 52.11,60.51 52.64,61.03 52.84,61.03 53.16,60.72 53.16,60.51 52.63,59.99 52.63,59.57 53.09,59.12 53.51,59.12 54.03,59.64 54.24,59.64 54.55,59.33 54.55,59.12 54.03,58.59 54.03,58.18 54.49,57.72 54.9,57.72 55.37,58.19 55.69,58.19 55.94,57.94 55.94,53.56 56.28,53.22 56.7,53.22 56.7,53.21 v1(56.95,53.21)
  L4 w0.089: v1(35.35,61.38) 35.56,61.59 35.56,61.87 35.39,62.04 35.39,63 35.61,63.22 35.83,63.22 36.02,63.41 36.02,63.66 35.89,63.79 35.58,63.79 35.41,63.96 35.41,64.46 35.61,64.66 35.93,64.66 36.02,64.76 36.02,65.09 35.93,65.18 35.61,65.18 35.39,65.4 35.39,65.87 35.59,66.07 35.95,66.07 36.05,66.17 36.05,66.49 35.96,66.57 35.65,66.57 35.4,66.81 35.4,67.23 35.64,67.47 35.64,67.72 v1(35.46,67.9) 35.52,67.95 35.52,68.86 35.82,69.16 35.82,69.57 35.49,69.89 35.49,70.56 35.87,70.94 35.87,71.55 35.45,71.97 35.45,72.44 35.73,72.72 36.82,72.72 36.93,72.82 36.93,73.1 36.77,73.25 35.95,73.25 35.57,73.63 35.57,74.13 35.32,74.38 v1(35.31,74.38) ; v1(49.41,51.72) 49.68,51.99 55.34,51.99 55.59,52.24 55.59,53.23 55.77,53.42 56.75,53.42 v1(56.95,53.21) 57.11,53.38 57.37,53.38 57.58,53.16 57.58,51.75 57.81,51.52 58.41,51.52 58.61,51.72 58.61,53.27 58.84,53.5 59.12,53.5 59.52,53.1 60.63,53.1 61.16,52.57 61.16,52.01 61.4,51.77 61.82,51.77 v1(62.07,51.52) ; v3(55.09,74.5) 55.09,74.34 55.02,74.27 54.46,74.27 54.42,74.31 54.41,74.31
  L4 w0.147: v1(44.08,63.67) 44.27,63.67 44.47,63.86 44.47,65.96 50.5,72 50.5,72.21 50.19,72.52 49.98,72.52 46.7,69.24 46.3,69.24 45.84,69.7 45.84,70.13 49.88,74.16 50.29,74.16 51.37,73.08 51.58,73.08 52.81,74.31 54.41,74.31
  BOTTOM w0.089: U4104.K7 61.06,49.35 61.06,49.55 61.82,50.31 61.82,51.27 v1(62.07,51.52) ; v1(35.31,74.38) 35.14,74.55 35.14,74.55 34.85,74.84 34.26,74.84 U4107.K7 ; v1(49.41,51.72) 49.31,51.82 49.02,51.82 48.8,51.6 48.8,50.14 U4105.K7 ; v1(35.35,61.38) 35.35,61.41 34.98,61.79 34.26,61.79 U4106.K7 ; U4500.BF14 v3(55.09,74.5)
M_B_CLK0_DP: length 131.9
  TOP w0.137: v1(44.85,63.67) 44.94,63.76 C4623.1 44.92,64.48 R4185.1
  L3 w0.147: v1(56.95,53.82) 56.59,53.47 56.38,53.47 56.19,53.66 56.19,58.04 55.79,58.44 55.27,58.44 54.8,57.97 54.59,57.97 54.28,58.28 54.28,58.49 54.8,59.01 54.8,59.43 54.34,59.89 53.93,59.89 53.4,59.36 53.2,59.36 52.88,59.68 52.88,59.89 53.41,60.41 53.41,60.82 52.95,61.28 52.53,61.28 52.01,60.76 51.8,60.76 51.49,61.07 51.49,61.28 51.77,61.57 51.77,62.23 51.14,62.86 44.64,62.86 44.39,63.12 44.39,63.36 44.69,63.67 v1(44.85,63.67) 44.58,63.94 44.58,64.44 46.07,65.94 46.27,65.94 46.65,65.56 46.65,65.35 45.72,64.42 45.72,63.84 46.08,63.48 46.61,63.48 48.24,65.1 48.24,65.89 44.61,69.51 40.07,69.51 37.9,67.34 36.03,67.34 35.89,67.49 35.89,67.72 v1(36.07,67.9)
  L4 w0.089: v1(62.05,52.13) 61.87,51.95 61.48,51.95 61.34,52.08 61.34,52.64 60.7,53.28 59.6,53.28 59.19,53.68 58.77,53.68 58.43,53.34 58.43,51.8 58.33,51.7 57.89,51.7 57.76,51.83 57.76,53.09 57.76,53.09 57.76,53.24 57.44,53.55 57.22,53.55 v1(56.95,53.82) 56.94,53.82 56.71,53.59 55.7,53.59 55.41,53.3 55.41,52.32 55.26,52.17 49.56,52.17 v1(49.4,52.33) ; v1(35.97,61.39) 35.94,61.39 35.73,61.6 35.73,61.95 35.57,62.11 35.57,62.93 35.68,63.04 35.9,63.04 36.2,63.33 36.2,63.73 35.96,63.97 35.65,63.97 35.59,64.04 35.59,64.39 35.68,64.49 36,64.49 36.2,64.69 36.2,65.16 36.01,65.36 35.69,65.36 35.57,65.48 35.57,65.8 35.66,65.89 36.02,65.89 36.22,66.09 36.22,66.56 36.04,66.75 35.72,66.75 35.58,66.89 35.58,67.16 35.82,67.4 35.82,67.65 v1(36.07,67.9) 35.69,68.28 35.69,68.78 35.99,69.08 35.99,69.64 35.67,69.96 35.67,70.49 36.05,70.86 36.05,71.62 35.63,72.04 35.63,72.37 35.8,72.54 36.9,72.54 37.11,72.75 37.11,73.17 36.85,73.43 36.02,73.43 35.75,73.7 35.75,74.22 v1(35.92,74.39) ; v1(55.81,74.5) 55.23,74.1 54.47,74.1 54.43,74.06 54.41,74.06
  L4 w0.147: 54.41,74.06 52.92,74.06 51.69,72.83 51.27,72.83 50.19,73.91 49.98,73.91 46.09,70.02 46.09,69.8 46.4,69.49 46.6,69.49 49.88,72.77 50.29,72.77 50.75,72.31 50.75,71.9 44.71,65.86 44.71,63.8 v1(44.85,63.67)
  BOTTOM w0.089: U4107.J7 33.82,75.59 34.39,75.02 34.93,75.02 35.15,74.79 35.52,74.79 v1(35.92,74.39) ; U4105.J7 48.01,50.08 48.13,49.96 48.36,49.96 48.63,50.22 48.63,51.67 48.95,52 49.06,52 v1(49.4,52.33) ; U4104.J7 61.06,50.15 61.41,50.15 61.64,50.38 61.64,51.72 v1(62.05,52.13) ; v1(35.97,61.39) 35.97,61.41 35.42,61.96 34.39,61.96 33.82,62.54 U4106.J7 ; U4500.BD14 v1(55.81,74.5)
M_B_CS0_N: length 127.4
  TOP w0.102: v1(40.75,58.12) 40.56,57.93 R4147.2
  L3 w0.102: v1(31.45,67.18) 31.45,66.68 34.08,64.04 34.38,64.04 34.72,63.7 35.15,63.7 35.25,63.6 35.25,63.17 35.36,63.06 35.56,63.06 35.66,63.16 35.66,63.6 35.76,63.7 35.96,63.7 36.06,63.6 36.06,63.42 36.17,63.32 36.37,63.32 36.47,63.42 36.47,63.6 36.57,63.7 37.28,63.7 37.76,63.22 38.17,63.22 38.28,63.12 38.28,62.71 38.18,62.61 37.68,62.61 37.57,62.51 37.57,62.31 37.68,62.2 38.18,62.2 38.28,62.1 38.28,61.47 38.38,61.37 38.58,61.37 38.69,61.47 38.69,63.6 38.79,63.7 39,63.7 39.09,63.61 39.09,61.44 39.5,61.03 39.5,59.93 39.74,59.69 40,59.69 40.1,59.59 40.1,58.68 40.21,58.58 40.41,58.58 40.51,58.67 40.51,59.59 40.61,59.69 40.81,59.69 40.92,59.58 40.92,58.46 40.75,58.3 v1(40.75,58.12) 41.22,58.12 41.97,57.37 43.87,57.37 46.03,55.21 46.4,55.21 46.5,55.32 46.5,55.92 46.61,56.03 46.81,56.03 46.91,55.93 46.91,55.32 47.02,55.21 51.15,55.21 51.39,54.97 51.54,54.97 51.72,55.15 51.85,55.15 52,55.01 52,54.85 51.82,54.68 51.82,54.54 52.61,53.75 52.61,53.12 52.96,52.77 52.96,52.63 52.76,52.42 52.76,52.28 52.9,52.14 53.04,52.14 53.25,52.34 53.39,52.34 53.53,52.2 53.53,52.05 53.33,51.85 53.33,51.71 53.47,51.56 53.62,51.56 53.82,51.77 53.97,51.77 54.19,51.54 54.19,49.86 55.87,48.17 56.52,48.17 56.71,47.98 v1(56.71,47.78)
  L4 w0.089: v1(49.86,47.72) 52.82,47.72 53.22,47.32 54.61,47.32 54.68,47.38 56.27,47.38 56.66,47.78 v1(56.71,47.78) 57.68,47.78 58.13,47.33 60.76,47.33 60.92,47.49 61.15,47.49 61.32,47.33 61.54,47.33 61.71,47.49 61.94,47.49 62.1,47.33 62.75,47.33 v3(63.15,47.72) ; v1(31.39,60.55) 31.39,60.55 31,60.94 31,66.68 31.45,67.13 v1(31.45,67.18) 31.45,67.22 31.06,67.61 31.06,67.99 30.98,68.06 30.98,72.85 31.39,73.25 v1(31.39,73.77) ; v1(57.77,75.42) 57.14,76.05 54.25,76.05
  L4 w0.152: v1(40.75,58.12) 40.75,58.49 41.64,59.37 41.64,59.55 41.5,59.68 41.3,59.68 39.78,58.16 39.57,58.16 39.43,58.29 39.43,58.46 41.3,60.33 41.5,60.33 41.96,59.87 42.14,59.87 43.23,60.96 43.23,61.29 42.53,62 42.53,66.28 44.02,67.77 44.02,71.75 47.99,75.72 52.76,75.72 53.08,76.05 54.25,76.05
  BOTTOM w0.089: v3(63.15,47.72) 63.62,48.2 64.71,48.2 U4104.L2 ; v1(31.39,73.77) 31.39,73.71 31.82,73.27 31.82,72.01 32.22,71.62 U4107.L2 ; U4105.L2 51.61,48.15 50.3,48.15 v1(49.86,47.72) ; v1(31.39,60.55) 31.88,60.06 31.88,59.23 32.22,58.89 32.22,58.57 U4106.L2 ; U4500.AY16 v1(57.77,75.42)
M_B_CS1_N: length 126.8
  TOP w0.102: v1(41.87,60.61) 41.92,60.55 41.92,60.35 R4148.2
  L3 w0.102: v1(33.02,67.15) 33.02,66.94 33.98,65.98 34.62,65.98 35.34,65.26 40.65,65.26 40.76,65.15 40.76,63.43 40.87,63.33 41.07,63.33 41.17,63.43 41.17,65.37 41.28,65.48 41.49,65.48 41.57,65.4 41.57,62.14 41.67,62.04 41.88,62.04 41.98,62.14 41.98,65.15 42.08,65.25 42.33,65.25 42.42,65.16 42.42,62.01 41.87,61.45 v1(41.87,60.61) 43.43,60.61 44.56,59.49 45.69,59.49 45.79,59.39 45.79,58.56 45.89,58.46 46.09,58.46 46.2,58.56 46.2,59.39 46.3,59.49 46.5,59.49 46.6,59.39 46.6,58.56 46.7,58.46 46.91,58.46 47.01,58.56 47.01,59.39 47.11,59.49 48.27,59.49 49.44,58.31 50.65,58.31 53.83,55.14 53.83,54.3 54.5,53.63 54.5,52.79 55.15,52.14 55.15,50.51 55.91,49.75 56.31,49.75 56.71,49.35 v1(56.71,49.35)
  L4 w0.089: v3(59.33,76.44) 59.33,76.93 59.17,77.09 54.3,77.09 53.75,76.54 52.77,76.54 52.6,76.38 52.46,76.38 ; v1(63.15,49.35) 62.76,48.97 60.81,48.97 60.66,49.12 60.42,49.12 60.27,48.97 60.02,48.97 59.87,49.12 59.63,49.12 59.48,48.97 59.24,48.97 59.09,49.12 58.84,49.12 58.69,48.97 57.66,48.97 57.27,49.35 v1(56.71,49.35) 56.62,49.35 56.24,48.97 55.65,48.97 55.4,48.72 50.88,48.72 50.27,49.34 v1(49.86,49.34) ; v1(32.96,60.56) 32.56,60.96 32.56,66.51 33.02,66.98 v1(33.02,67.15) 33.02,67.26 32.64,67.65 32.64,68.01 32.45,68.2 32.45,72.78 33.02,73.36 v1(33.02,73.77)
  L4 w0.152: v1(41.87,60.61) 41.87,60.93 41.76,61.03 40.69,61.03 40.59,61.14 40.59,61.33 40.75,61.49 41.76,61.49 41.87,61.59 41.87,66.56 43.36,68.05 43.36,73.32 46.42,76.38 52.46,76.38
  BOTTOM w0.089: v1(33.02,73.77) 33.02,73.76 32.63,73.37 32.63,71.55 32.22,71.14 U4107.L1 ; v1(63.15,49.35) 63.57,48.93 65.23,48.93 65.62,48.55 65.86,48.55 U4104.L1 ; v1(49.86,49.34) 50.24,48.96 52.08,48.96 52.49,48.55 U4105.L1 ; v1(32.96,60.56) 32.62,60.22 32.62,58.42 32.33,58.13 32.33,57.88 U4106.L1 ; U4500.AU16 v3(59.33,76.44)
M_B_DM<0>: length 18.2
  BOTTOM w0.102: U4500.AP2 61.04,68.67 61.04,67.18 60.67,66.82 60.67,61.39 60.55,61.26 v2(60.55,60.91) 60.55,58.14 60.89,57.8 60.89,57.11 60.72,56.71 60.68,56.03 60.68,54.85 61.04,54.5 61.21,54.5 U4104.D3
M_B_DM<1>: length 28.4
  L4 w0.089: 59.77,68.66 59.89,68.78 59.89,69.33 60.15,69.59 60.15,70.06 59.76,70.45 v1(59.76,70.45)
  L4 w0.124: 59.77,68.66 59.33,68.22 59.33,67.45 59.46,67.33 59.88,67.33 60.01,67.2 60.01,67.02 59.88,66.9 59.46,66.9 59.33,66.77 59.33,66.59 59.46,66.47 59.88,66.47 60.01,66.34 60.01,66.16 59.88,66.04 59.46,66.04 59.33,65.91 59.33,65.73 59.46,65.61 59.88,65.61 60.01,65.48 60.01,65.3 59.88,65.18 59.46,65.18 59.33,65.05 59.33,64.36 51.31,56.34 51.31,55.38 51.19,55.25 50.81,55.25 50.69,55.13 50.69,54.95 50.81,54.82 51.19,54.82 51.31,54.7 51.31,54.29 50.69,53.68 49.3,53.68 v3(49.3,53.67)
  BOTTOM w0.089: U4105.E7 48.33,53.68 49.3,53.68 v3(49.3,53.67) ; v1(59.76,70.45) U4500.AT6
M_B_DM<2>: length 31.5
  L3 w0.089: v1(60.8,72.62) 61.2,72.22 61.2,69.47 60.68,68.95 60.68,68.52
  L3 w0.124: v3(63.04,53.82) 62.94,53.92 62.94,56.43 62.24,57.13 62.06,57.13 61.93,56.99 61.75,56.99 61.62,57.12 61.62,57.29 61.78,57.46 61.78,57.66 60.68,58.77 60.68,66.6 60.81,66.72 60.99,66.72 61.11,66.6 61.11,63.49 61.23,63.37 61.41,63.37 61.54,63.51 61.54,67.03 61.42,67.15 60.81,67.15 60.68,67.28 60.68,68.52
  BOTTOM w0.089: v1(60.8,72.62) 60.79,72.61 U4500.AP10 ; U4104.E7 61.07,53.36 62.58,53.36 v3(63.04,53.82)
M_B_DM<3>: length 21.9
  BOTTOM w0.102: U4500.BA1 57.82,68.16 57.08,67.42 57.08,65.13 v2(56.59,64.64) 55.84,63.9 48.07,56.13 47.9,56.13 47.6,55.83 47.6,54.87 47.9,54.57 48.11,54.57 48.16,54.62 50.75,54.62 U4105.D3
M_B_DM<4>: length 24.5
  BOTTOM w0.102: U4106.D3 39.74,61.28 40.4,61.28 42.05,62.94 42.05,65.25 v2(45.67,68.87) 51.47,74.67 53.36,74.67 53.45,74.76 53.95,74.76 54.06,74.64 U4500.BG13
M_B_DM<5>: length 33.1
  L3 w0.089: 53.04,75.98 53.97,75.98 54.86,76.86 57.38,76.86 v1(57.8,76.44)
  L3 w0.124: 53.04,75.98 52.96,75.98 52.84,75.85 52.84,75.24 52.71,75.12 48.25,75.12 48.12,75.24 48.12,75.42 48.25,75.55 52.28,75.55 52.41,75.67 52.41,75.85 52.28,75.98 42.5,75.98 41.1,74.58 v1(37.6,74.58)
  BOTTOM w0.089: U4500.AY18 v1(57.8,76.44)
  BOTTOM w0.102: U4107.E7 37.02,75.62 37.02,75.15 v1(37.6,74.58)
M_B_DM<6>: length 41.9
  L4 w0.089: 51.45,79.28 51.68,79.28 52.07,79.67 54.85,79.67 54.88,79.7 55.47,79.7 v1(55.83,79.34)
  L4 w0.124: 51.45,79.28 42.83,79.28 40.86,77.3 40.86,77.11 40.98,76.98 41.14,76.98 43.01,78.85 43.2,78.85 43.32,78.72 43.32,78.56 41.31,76.54 41.31,75.32 40.26,74.28 40.26,72.42 40.14,72.29 39.7,72.29 39.58,72.18 39.58,72 39.71,71.86 40.14,71.86 40.26,71.74 40.26,70.81 38.79,69.33 38.79,67.52 37.82,66.55 37.82,65.6 36.94,64.73 36.94,64.22 37.07,64.09 37.69,64.09 37.82,63.97 37.82,63.79 37.69,63.66 37.07,63.66 36.94,63.54 36.94,63.31 36.63,63 v1(36.63,62.98)
  BOTTOM w0.089: v1(55.83,79.34) 56.1,78.84 U4500.BD22
  BOTTOM w0.102: v1(36.63,62.98) 36.63,62.96 U4106.E7
M_B_DM<7>: length 21.6
  BOTTOM w0.089: 40.43,75.28 40.08,75.28 39.84,75.53 39.84,75.7 39.58,75.96 38.48,75.96 38.29,75.76 38.23,75.3 38.09,73.51 37.97,72.69
  BOTTOM w0.102: 40.43,75.28 41.24,76.09 43.06,76.09 v2(43.5,76.53) 45.59,78.62 47.14,78.62 47.81,79.29 51.5,79.29 51.93,79.72 52.11,79.72 U4500.BH24 ; U4107.D3 37.97,72.69
M_B_DQ<0>: length 16.3
  BOTTOM w0.102: U4104.A2 65.06,56.63 64.73,56.96 64.73,58.71 64.83,58.81 65.04,58.81 65.14,58.71 65.14,58.37 65.25,58.26 65.45,58.26 65.55,58.36 65.55,59.11 65.44,59.21 64.83,59.21 64.73,59.32 64.73,60.91 64.05,61.59 v2(64.05,62.12) 63.78,62.39 63.78,67.14 63.33,67.6 63.33,67.99 63.36,68.02 63.36,68.63 63.46,68.72 63.46,68.97 63.16,69.27 U4500.AK3
M_B_DQ<1>: length 14.9
  BOTTOM w0.102: U4500.AL3 62.85,68.73 62.95,68.63 62.95,68.3 62.86,68.1 62.86,66.47 62.77,66.38 62.77,64.71 62.87,64.61 63.12,64.61 63.22,64.5 63.22,64.3 63.12,64.2 62.87,64.2 62.77,64.1 62.77,63.89 62.87,63.79 63.12,63.79 63.22,63.69 63.22,63.49 63.12,63.39 62.87,63.39 62.77,63.29 62.77,63.08 62.87,62.98 63.12,62.98 63.22,62.88 63.22,61.29 v2(63.69,60.83) 64.17,60.34 64.17,56.64 U4104.A3
M_B_DQ<2>: length 16.4
  BOTTOM w0.102: U4500.AT2 60.33,68.77 60.33,67.33 60.11,67.11 60.11,64.06 59.3,63.24 59.3,61.56 59.06,61.32 v2(59.06,61) 59.06,60.08 59.16,59.98 59.36,59.98 59.46,59.88 59.46,59.68 59.36,59.57 59.16,59.57 59.06,59.47 59.06,59.27 59.16,59.17 59.36,59.17 59.46,59.07 59.46,58.86 59.36,58.76 59.16,58.76 59.06,58.66 59.06,55.64 59.29,55.41 59.81,55.41 U4104.C8
M_B_DQ<3>: length 18.6
  BOTTOM w0.089: U4104.D7 60.86,54.15 60.48,54.52 59.2,54.52 58.37,55.36 ; 60.14,67.61 60.14,68.52 59.96,68.69 59.96,68.98 60.19,69.21 U4500.AR3
  BOTTOM w0.102: 60.14,67.61 60.14,67.43 59.83,67.13 59.83,64.17 59.02,63.36 59.02,61.68 58.55,61.21 v2(58.55,59.83) 58.55,57.45 58.24,57.14 58.24,56.48 58.37,56.35 58.37,55.36
M_B_DQ<4>: length 16.7
  BOTTOM w0.102: U4500.AL1 62.61,68.4 62.61,66.69 62.49,66.56 62.49,62.49 62.59,62.39 62.83,62.39 62.93,62.29 62.93,62.08 62.83,61.98 62.59,61.98 62.49,61.88 62.49,61.68 62.59,61.57 62.83,61.57 62.93,61.47 62.93,61.27 62.83,61.17 62.59,61.17 62.49,61.07 62.49,60.86 62.59,60.76 62.93,60.76 63.02,60.67 63.02,60.46 62.91,60.36 62.59,60.36 62.49,60.25 62.49,60.07 62.61,59.95 62.98,59.95 63.3,59.62 v2(63.3,59.56) 63.45,59.41 63.45,55.76 U4104.C3
M_B_DQ<5>: length 14.7
  BOTTOM w0.102: U4500.AK2 63.16,68.11 63.14,68.09 63.14,67.52 63.27,67.38 v2(63.27,65.1) 63.5,64.87 63.5,61.74 64.45,60.79 64.45,56.94 64.64,56.75 64.64,55.37 U4104.C2
M_B_DQ<6>: length 17.3
  BOTTOM w0.089: U4104.B8 59.9,56.11 59.9,57.23
  BOTTOM w0.102: 59.9,57.23 60.02,57.35 v2(60.02,59.61) 60.02,60.65 59.58,61.09 59.58,63.13 59.67,63.22 59.88,63.22 59.99,63.11 59.99,61.57 60.09,61.47 60.29,61.47 60.39,61.57 60.39,66.95 60.73,67.29 U4500.AR1
M_B_DQ<7>: length 19.5
  BOTTOM w0.102: U4500.AP3 61.22,69.27 61.55,68.94 61.55,68.75 61.3,68.5 61.3,67.67 61.4,67.57 61.4,66.49 61.3,66.39 61.05,66.39 60.95,66.3 60.95,66.09 61.06,65.98 61.3,65.98 61.4,65.88 61.4,65.68 61.3,65.58 61.05,65.58 60.95,65.48 60.95,65.28 61.06,65.17 61.3,65.17 61.4,65.07 61.4,64.87 61.3,64.77 61.05,64.77 60.95,64.67 60.95,64.47 61.06,64.36 61.3,64.36 61.4,64.26 61.4,64.05 61.3,63.95 61.05,63.95 60.95,63.86 60.95,63.65 61.06,63.55 61.3,63.55 61.4,63.44 61.4,63.24 61.3,63.14 61.05,63.14 60.95,63.04 60.95,62.84 61.06,62.73 61.3,62.73 61.4,62.63 61.4,62.43 61.3,62.33 61.05,62.33 60.95,62.23 60.95,62.03 61.06,61.92 61.3,61.92 61.4,61.82 61.4,61.62 61.3,61.51 61.07,61.51 60.98,61.43 60.98,61.19 61.07,61.11 61.3,61.11 61.4,61.01 61.4,60.8 61.3,60.7 61.05,60.7 60.95,60.61 60.95,60.4 61.06,60.29 61.19,60.29 61.3,60.19 v2(61.3,59.77) 61.3,59.38 61.2,59.28 61.02,59.28 60.92,59.18 60.92,58.97 61.02,58.87 61.2,58.87 61.3,58.77 61.3,58.57 61.2,58.47 61.02,58.47 60.92,58.37 60.92,58.16 61.02,58.06 61.2,58.06 61.3,57.96 61.3,56.79 U4104.A7
M_B_DQ<8>: length 26.9
  L4 w0.089: v3(60.77,70.43) 60.77,70.28 61.15,69.9 61.15,69.26 60.98,69.09 60.98,68.68
  L4 w0.124: v1(54.96,55.51) 55.35,55.9 55.35,56.08 54.87,56.56 54.87,56.74 55,56.87 55.17,56.87 55.66,56.38 55.83,56.38 55.96,56.51 55.96,56.69 55.45,57.19 55.45,57.39 55.58,57.52 55.74,57.52 56.26,56.99 56.44,56.99 56.81,57.36 56.81,57.59 55.45,58.95 55.45,59.2 60.98,64.73 60.98,68.68
  BOTTOM w0.089: U4500.AP6 v3(60.77,70.43)
  BOTTOM w0.102: U4105.F2 52.61,52.83 52.66,52.86 52.94,52.99 53.29,53.33 54.18,54.62 54.42,54.9 v1(54.96,55.51)
M_B_DQ<9>: length 28.7
  L4 w0.089: v1(59.76,71.17) 60.37,70.55 60.37,69.16
  L4 w0.124: v1(51.61,53.77) 51.62,53.78 51.62,56.22 51.76,56.36 51.94,56.36 52.7,55.6 52.87,55.6 53,55.73 53,55.9 52.24,56.66 52.24,56.84 52.37,56.97 52.54,56.97 53.3,56.21 53.48,56.21 53.61,56.33 53.61,56.51 52.85,57.27 52.85,57.45 53.41,58.01 53.59,58.01 54.03,57.57 54.21,57.57 54.34,57.7 54.34,57.87 53.89,58.32 53.89,58.49 60.37,64.97 60.37,69.16
  BOTTOM w0.089: v1(59.76,71.17) 59.76,71.17 U4500.AT7
  BOTTOM w0.102: U4105.E3 51.21,53.38 51.6,53.77 v1(51.61,53.77)
M_B_DQ<10>: length 24.4
  L4 w0.089: v1(57.76,71.22) 57.16,70.63 57.16,69.61 56.9,69.36 56.9,69.11
  L4 w0.124: 56.9,69.11 56.9,64.9 46.36,54.35 46.36,53.41 v3(46.82,52.94)
  BOTTOM w0.089: U4500.AY6 v1(57.76,71.22)
  BOTTOM w0.102: U4105.F8 v3(46.82,52.94)
M_B_DQ<11>: length 25.2
  L4 w0.124: v3(47.61,51.36) 48.04,51.79 48.04,52.7 48.64,53.29 48.64,54.33 48.76,54.45 49.14,54.45 49.26,54.58 49.26,54.76 49.14,54.88 48.76,54.88 48.64,55.01 48.64,55.35 58.2,64.91 58.2,68.92 58.76,69.48 v1(58.76,69.73)
  BOTTOM w0.089: U4500.AV4 58.88,69.83 v1(58.76,69.73)
  BOTTOM w0.102: v3(47.61,51.36) 48.01,50.95 U4105.H7
M_B_DQ<12>: length 27.8
  L4 w0.089: 61.29,68.69 61.29,68.93 61.38,69.02 61.38,70.54 v1(60.75,71.17)
  L4 w0.124: v3(54.98,54.85) 57.25,57.12 57.25,57.58 55.84,58.99 55.84,59.15 56.14,59.46 56.32,59.46 57.05,58.73 57.22,58.73 57.35,58.85 57.35,59.03 56.62,59.76 56.62,59.94 61.29,64.6 61.29,68.69
  BOTTOM w0.089: U4500.AP7 v1(60.75,71.17)
  BOTTOM w0.102: U4105.G2 52.88,52.18 53.35,52.35 54.14,53.14 54.42,53.72 v3(54.98,54.85)
M_B_DQ<13>: length 27.1
  L4 w0.124: v3(51.59,52.95) 52.05,53.4 52.05,53.44 52.84,54.22 52.84,55.11 54.46,56.73 54.46,56.91 54.31,57.06 54.31,57.24 54.44,57.37 54.61,57.37 54.76,57.21 54.94,57.21 55.15,57.43 55.15,57.6 54.38,58.37 54.38,58.55 54.51,58.68 54.68,58.68 55.46,57.91 55.63,57.91 55.76,58.03 55.76,58.21 54.99,58.98 54.99,59.16 55.12,59.29 60.68,64.85 60.68,69.28 60.76,69.35 v1(60.76,69.74)
  BOTTOM w0.089: U4500.AT4 v1(60.76,69.74)
  BOTTOM w0.102: U4105.H3 51.59,51.33 v3(51.59,52.95)
M_B_DQ<14>: length 24.9
  L4 w0.089: v1(57.75,70.51) 57.34,70.1 57.34,69.54 57.21,69.41 57.21,69.21
  L4 w0.124: 57.21,69.21 57.21,64.77 48.03,55.6 48.03,53.57 47.2,52.73 47.2,51.74 46.81,51.35 v1(46.81,51.35)
  BOTTOM w0.089: U4500.AY4 v1(57.75,70.51)
  BOTTOM w0.102: v1(46.81,51.35) 46.81,51.35 47.21,50.95 U4105.H8
M_B_DQ<15>: length 27
  L4 w0.124: v1(47.62,52.16) 47.62,52.72 48.34,53.44 48.34,55.48 57.9,65.04 57.9,65.64 57.77,65.76 57.63,65.76 57.51,65.88 57.51,66.06 57.64,66.19 57.77,66.19 57.9,66.32 57.9,66.5 57.77,66.62 57.63,66.62 57.51,66.74 57.51,66.92 57.64,67.05 57.77,67.05 57.9,67.17 57.9,67.35 57.77,67.48 57.63,67.48 57.51,67.6 57.51,67.78 57.64,67.91 57.77,67.91 57.9,68.03 57.9,69.17 58.21,69.48 58.21,71.47 v3(58.75,72.01)
  BOTTOM w0.089: U4500.AV9 v3(58.75,72.01)
  BOTTOM w0.102: U4105.F7 48.01,52.55 v1(47.62,52.16)
M_B_DQ<16>: length 32.7
  L3 w0.089: 65.1,52.63 65.06,52.58 65.06,51.75 v1(64.66,51.35) ; v3(60.75,74.71) 61.8,73.66 61.8,69.68 62.49,68.99 62.49,68.63
  L3 w0.124: 62.49,68.63 62.49,66.24 63.35,65.38 63.35,63.15 63.22,63.03 63.04,63.03 62.92,63.15 62.92,65.16 62.81,65.28 62.62,65.28 62.49,65.14 62.49,62.72 62.61,62.6 63.22,62.6 63.35,62.47 63.35,58.4 63,58.06 63,57.77 63.81,56.96 64.11,56.96 64.59,56.49 64.59,53.63 65.1,53.11 65.1,52.63
  BOTTOM w0.089: U4500.AT14 v3(60.75,74.71)
  BOTTOM w0.102: U4104.H3 64.26,50.96 v1(64.66,51.35)
M_B_DQ<17>: length 33
  L3 w0.089: v3(60.82,73.31) 61.39,72.73 61.39,69.36 61.29,69.26 61.29,68.98
  L3 w0.124: v1(63.76,53.76) 63.4,54.13 63.32,54.13 63.24,54.2 63.24,54.44 63.37,54.57 63.86,54.57 63.98,54.69 63.98,54.87 63.86,55 63.37,55 63.24,55.12 63.24,55.3 63.37,55.43 63.57,55.43 63.7,55.56 63.7,55.74 63.58,55.86 63.37,55.86 63.24,55.98 63.24,56.65 61.84,58.05 61.84,62.52 61.72,62.64 61.54,62.64 61.41,62.52 61.41,58.87 61.3,58.76 61.12,58.76 60.98,58.89 60.98,62.95 61.11,63.07 61.72,63.07 61.84,63.2 61.84,67.15 61.53,67.46 61.53,67.46 61.29,67.71 61.29,68.98
  BOTTOM w0.089: U4500.AP12 v3(60.82,73.31)
  BOTTOM w0.102: v1(63.76,53.76) 64.18,53.35 U4104.E3
M_B_DQ<18>: length 27.3
  L3 w0.089: 57.33,72.8 57.51,73.56 57.56,73.71 57.74,73.88 58.04,74.04 58.09,74.07 58.45,74.44 59.61,75.18 v1(59.94,75.37)
  L3 w0.124: 57.33,72.8 57.33,56.44 57.52,55.98 58.64,52.8 58.88,52.48 58.9,52.45 58.93,52.45 v1(59.86,51.36)
  BOTTOM w0.089: U4500.AT16 v1(59.94,75.37)
  BOTTOM w0.102: U4104.H8 v1(59.86,51.36)
M_B_DQ<19>: length 30.7
  L3 w0.089: 62.79,68.51 62.79,68.94 62.06,69.67 62.06,74.09 v1(60.78,75.37)
  L3 w0.124: 62.79,68.51 62.79,66.36 63.65,65.5 63.65,58.73 63.77,58.6 63.95,58.6 64.08,58.73 64.08,60.03 64.2,60.15 64.38,60.15 64.51,60.03 64.51,58.3 64.22,58.01 63.85,58.01 63.63,57.79 63.63,57.57 63.89,57.31 64.19,57.31 64.91,56.59 64.91,53.73 65.46,53.18 65.46,52.16 v3(65.47,52.15)
  BOTTOM w0.089: U4500.AP14 v1(60.78,75.37)
  BOTTOM w0.102: U4104.G2 65.06,51.76 65.45,52.15 v3(65.47,52.15)
M_B_DQ<20>: length 33.4
  L3 w0.124: v1(59.73,72.68) 59.29,72.24 59.29,69.59 58.63,68.93 58.63,61.95 58.75,61.82 59.36,61.82 59.49,61.7 59.49,58.79 59.36,58.67 59.18,58.67 59.06,58.79 59.06,61.27 58.93,61.4 58.75,61.4 58.63,61.27 58.63,58.51 60.26,56.88 60.26,55.31 60.14,55.19 59.35,55.19 59.24,55.08 59.24,54.9 59.37,54.76 60.14,54.76 60.26,54.63 60.26,54.32 60.38,54.21 61.7,54.21 61.81,54.11 61.81,53.89 61.7,53.78 61.21,53.78 61.09,53.66 61.09,53.48 61.21,53.35 61.68,53.35 61.81,53.22 61.81,53.01 v3(61.74,52.95)
  BOTTOM w0.089: U4500.AT10 v1(59.73,72.68)
  BOTTOM w0.102: U4104.F7 61.35,52.55 v3(61.74,52.95)
M_B_DQ<21>: length 31.3
  L3 w0.089: 57.66,69.07 58.17,69.58 58.17,73.15 58.38,73.36 58.38,74.08 58.61,74.3 59.34,74.3 v1(59.76,74.72)
  L3 w0.124: 57.66,69.07 57.63,69.03 57.63,57.07 58.42,56.28 58.42,54.33 60.05,52.7 61.21,52.7 61.57,52.33 61.57,50.27 61.48,50.17 61.25,50.17 61.14,50.28 61.14,51.26 61.04,51.36 v3(60.67,51.36)
  BOTTOM w0.089: U4500.AV13 v1(59.76,74.72)
  BOTTOM w0.102: U4104.H7 61.06,50.96 v3(60.67,51.36)
M_B_DQ<22>: length 32.2
  L3 w0.089: v1(60.75,74.01) 61.6,73.17 61.6,69.5 62.19,68.91 62.19,68.39
  L3 w0.124: 62.19,68.39 62.19,58.96 62.31,58.83 62.49,58.83 62.61,58.96 62.61,62.16 62.75,62.3 62.93,62.3 63.04,62.18 63.04,58.53 62.92,58.4 62.35,58.4 62.23,58.28 62.23,58.09 63.67,56.64 64,56.64 64.28,56.36 64.28,53.36 v1(64.68,52.96)
  BOTTOM w0.089: U4500.AP13 v1(60.75,74.01)
  BOTTOM w0.102: v1(64.68,52.96) 65.06,52.58 U4104.F2
M_B_DQ<23>: length 34.4
  L3 w0.089: v1(58.77,73.3) 58.35,72.88 58.35,69.4 58.33,69.38 58.33,69.07
  L3 w0.124: v1(59.86,53.76) 59.42,53.76 59.23,53.94 59.23,54.15 59.09,54.29 58.88,54.29 58.73,54.45 58.73,54.64 58.93,54.85 58.93,55.09 58.73,55.3 58.73,55.58 58.86,55.72 59.83,55.72 59.96,55.85 59.96,56.03 59.85,56.15 58.84,56.15 58.73,56.26 58.73,56.44 58.86,56.58 59.69,56.58 59.82,56.71 59.82,56.89 59.71,57.01 59.19,57.01 59.07,57.13 59.07,57.65 58.9,57.81 58.73,57.81 58.22,57.29 58.06,57.29 57.93,57.42 57.93,57.61 58.31,57.99 58.31,58.55 58.2,58.66 58.05,58.66 57.93,58.77 57.93,58.95 58.06,59.09 58.2,59.09 58.33,59.21 58.33,59.39 58.2,59.52 58.05,59.52 57.93,59.63 57.93,59.81 58.06,59.95 58.2,59.95 58.33,60.07 58.33,60.25 58.2,60.37 58.05,60.37 57.93,60.49 57.93,60.67 58.06,60.8 58.2,60.8 58.33,60.93 58.33,61.11 58.2,61.23 58.05,61.23 57.93,61.35 57.93,61.53 58.06,61.66 58.2,61.66 58.33,61.79 58.33,61.97 58.2,62.09 58.05,62.09 57.93,62.21 57.93,62.39 58.06,62.52 58.2,62.52 58.33,62.65 58.33,62.83 58.2,62.95 58.05,62.95 57.93,63.07 57.93,63.25 58.06,63.38 58.2,63.38 58.33,63.5 58.33,63.68 58.2,63.81 58.05,63.81 57.93,63.92 57.93,64.1 58.06,64.24 58.2,64.24 58.33,64.36 58.33,64.54 58.2,64.67 58.05,64.67 57.93,64.78 57.93,64.96 58.06,65.1 58.2,65.1 58.33,65.22 58.33,65.4 58.2,65.53 58.05,65.53 57.93,65.64 57.93,65.82 58.06,65.95 58.2,65.95 58.33,66.08 58.33,66.26 58.2,66.38 58.05,66.38 57.93,66.5 57.93,66.68 58.06,66.81 58.2,66.81 58.33,66.94 58.33,67.12 58.2,67.24 58.05,67.24 57.93,67.36 57.93,67.54 58.06,67.67 58.2,67.67 58.33,67.8 58.33,67.98 58.2,68.1 58.05,68.1 57.93,68.22 57.93,68.4 58.06,68.53 58.2,68.53 58.33,68.65 58.33,69.07
  BOTTOM w0.089: 60.13,52.55 59.86,52.83 v1(59.86,53.76)
  BOTTOM w0.102: U4500.AV12 v1(58.77,73.3) ; U4104.F8 60.13,52.55 60.13,52.55
M_B_DQ<24>: length 22.1
  BOTTOM w0.102: U4500.BD2 56.41,68.79 56.43,68.79 56.63,68.6 56.63,68.23 56.27,67.87 56.27,67.47 54.2,65.41 54.2,65.26 v2(53.74,64.8) 53.4,64.47 53.4,64.3 47.71,58.61 47.71,58.46 47.85,58.32 47.85,58.18 47.71,58.03 47.57,58.03 47.42,58.17 47.28,58.17 47.01,57.91 46.74,57.91 46.07,57.24 46.07,56.2 45.97,56.09 45.79,56.09 45.69,55.99 45.69,55.79 45.79,55.69 45.97,55.69 46.07,55.59 46.07,55.41 46.18,55.3 46.55,55.3 46.79,55.06 46.79,54.84 47.03,54.61 47.55,54.61 U4105.D7
M_B_DQ<25>: length 23.9
  BOTTOM w0.102: U4500.AV2 59.27,68.16 59.13,68.02 59.13,67.16 58.82,66.85 58.82,64.13 58.34,63.64 58.34,61.96 57.77,61.39 57.77,60.11 v2(57.28,59.62) 56.88,59.23 56.88,59.08 57.32,58.65 57.32,58.51 56.58,57.77 56.43,57.77 56.29,57.91 56.29,58.06 56.74,58.51 56.74,58.65 56.6,58.8 56.45,58.8 55.79,58.13 55.79,57.53 55.69,57.42 53.96,57.42 53.86,57.53 53.86,57.73 53.96,57.83 55.28,57.83 55.38,57.93 55.38,58.13 55.28,58.24 53.7,58.24 U4105.A2
M_B_DQ<26>: length 22.7
  BOTTOM w0.102: U4500.BC1 56.83,68.32 56.83,68.15 56.47,67.79 56.47,67.28 54.51,65.33 54.51,64.69 v2(53.36,63.53) 53.17,63.34 52.84,63.34 52.09,62.59 52.09,62.44 52.32,62.21 52.32,62.06 52.18,61.92 52.04,61.92 51.8,62.16 51.66,62.16 51.49,61.99 51.49,61.79 51.36,61.67 51.17,61.67 50.98,61.48 50.98,61.33 51.15,61.16 51.15,61.01 51.01,60.87 50.87,60.87 50.69,61.05 50.55,61.05 50.4,60.9 50.4,60.76 50.59,60.57 50.59,60.43 50.44,60.28 50.3,60.28 50.11,60.47 49.97,60.47 49.83,60.33 49.83,60.18 50.01,60 50.01,59.86 49.87,59.71 49.72,59.71 49.54,59.9 49.4,59.9 49.25,59.75 49.25,59.61 49.44,59.42 49.44,59.28 49.29,59.14 49.15,59.14 48.96,59.32 48.82,59.32 48.68,59.18 48.68,59.03 48.86,58.85 48.86,58.71 48.71,58.57 48.57,58.57 48.39,58.75 48.25,58.75 48.07,58.57 48.07,58.08 47.74,57.76 47.53,57.76 47.31,57.53 47.31,57.32 46.78,56.79 46.78,56.34 46.87,56.24 46.87,55.79 46.75,55.67 46.75,55.46 47.21,55.01 U4105.C8
M_B_DQ<27>: length 24.5
  BOTTOM w0.102: U4105.C2 52.44,55.38 53.24,55.38 54.33,56.48 55.68,56.48 57.12,57.91 57.26,57.91 57.4,57.77 57.4,57.63 56.08,56.31 56.08,56.16 56.23,56.02 56.37,56.02 57.98,57.63 57.98,57.77 57.55,58.2 57.55,58.35 58.05,58.84 58.05,61.28 58.62,61.85 58.62,63.53 59.33,64.24 v2(59.33,65.3) 59.33,67.93 59.48,68.08 59.48,68.62 59.57,68.72 59.57,68.97 59.27,69.27 U4500.AV3
M_B_DQ<28>: length 23.8
  BOTTOM w0.102: U4105.C3 51.5,54.95 51.6,55.05 51.6,56.63 53.33,58.36 53.33,58.49 53.2,58.62 53.2,58.79 53.44,59.03 53.76,59.03 54.07,59.33 55.61,59.33 55.71,59.23 55.71,59.03 55.61,58.92 54.23,58.92 54.13,58.82 54.13,58.62 54.23,58.52 55.78,58.52 56.59,59.33 56.59,59.66 57.49,60.55 57.49,61.51 57.83,61.85 v2(57.83,62.52) 57.83,62.86 57.65,63.04 57.65,63.35 58.44,64.15 58.44,66.93 58.93,67.42 58.93,68.11 59.07,68.25 59.07,68.62 58.98,68.71 58.98,69.01 58.88,69.11 U4500.AW3
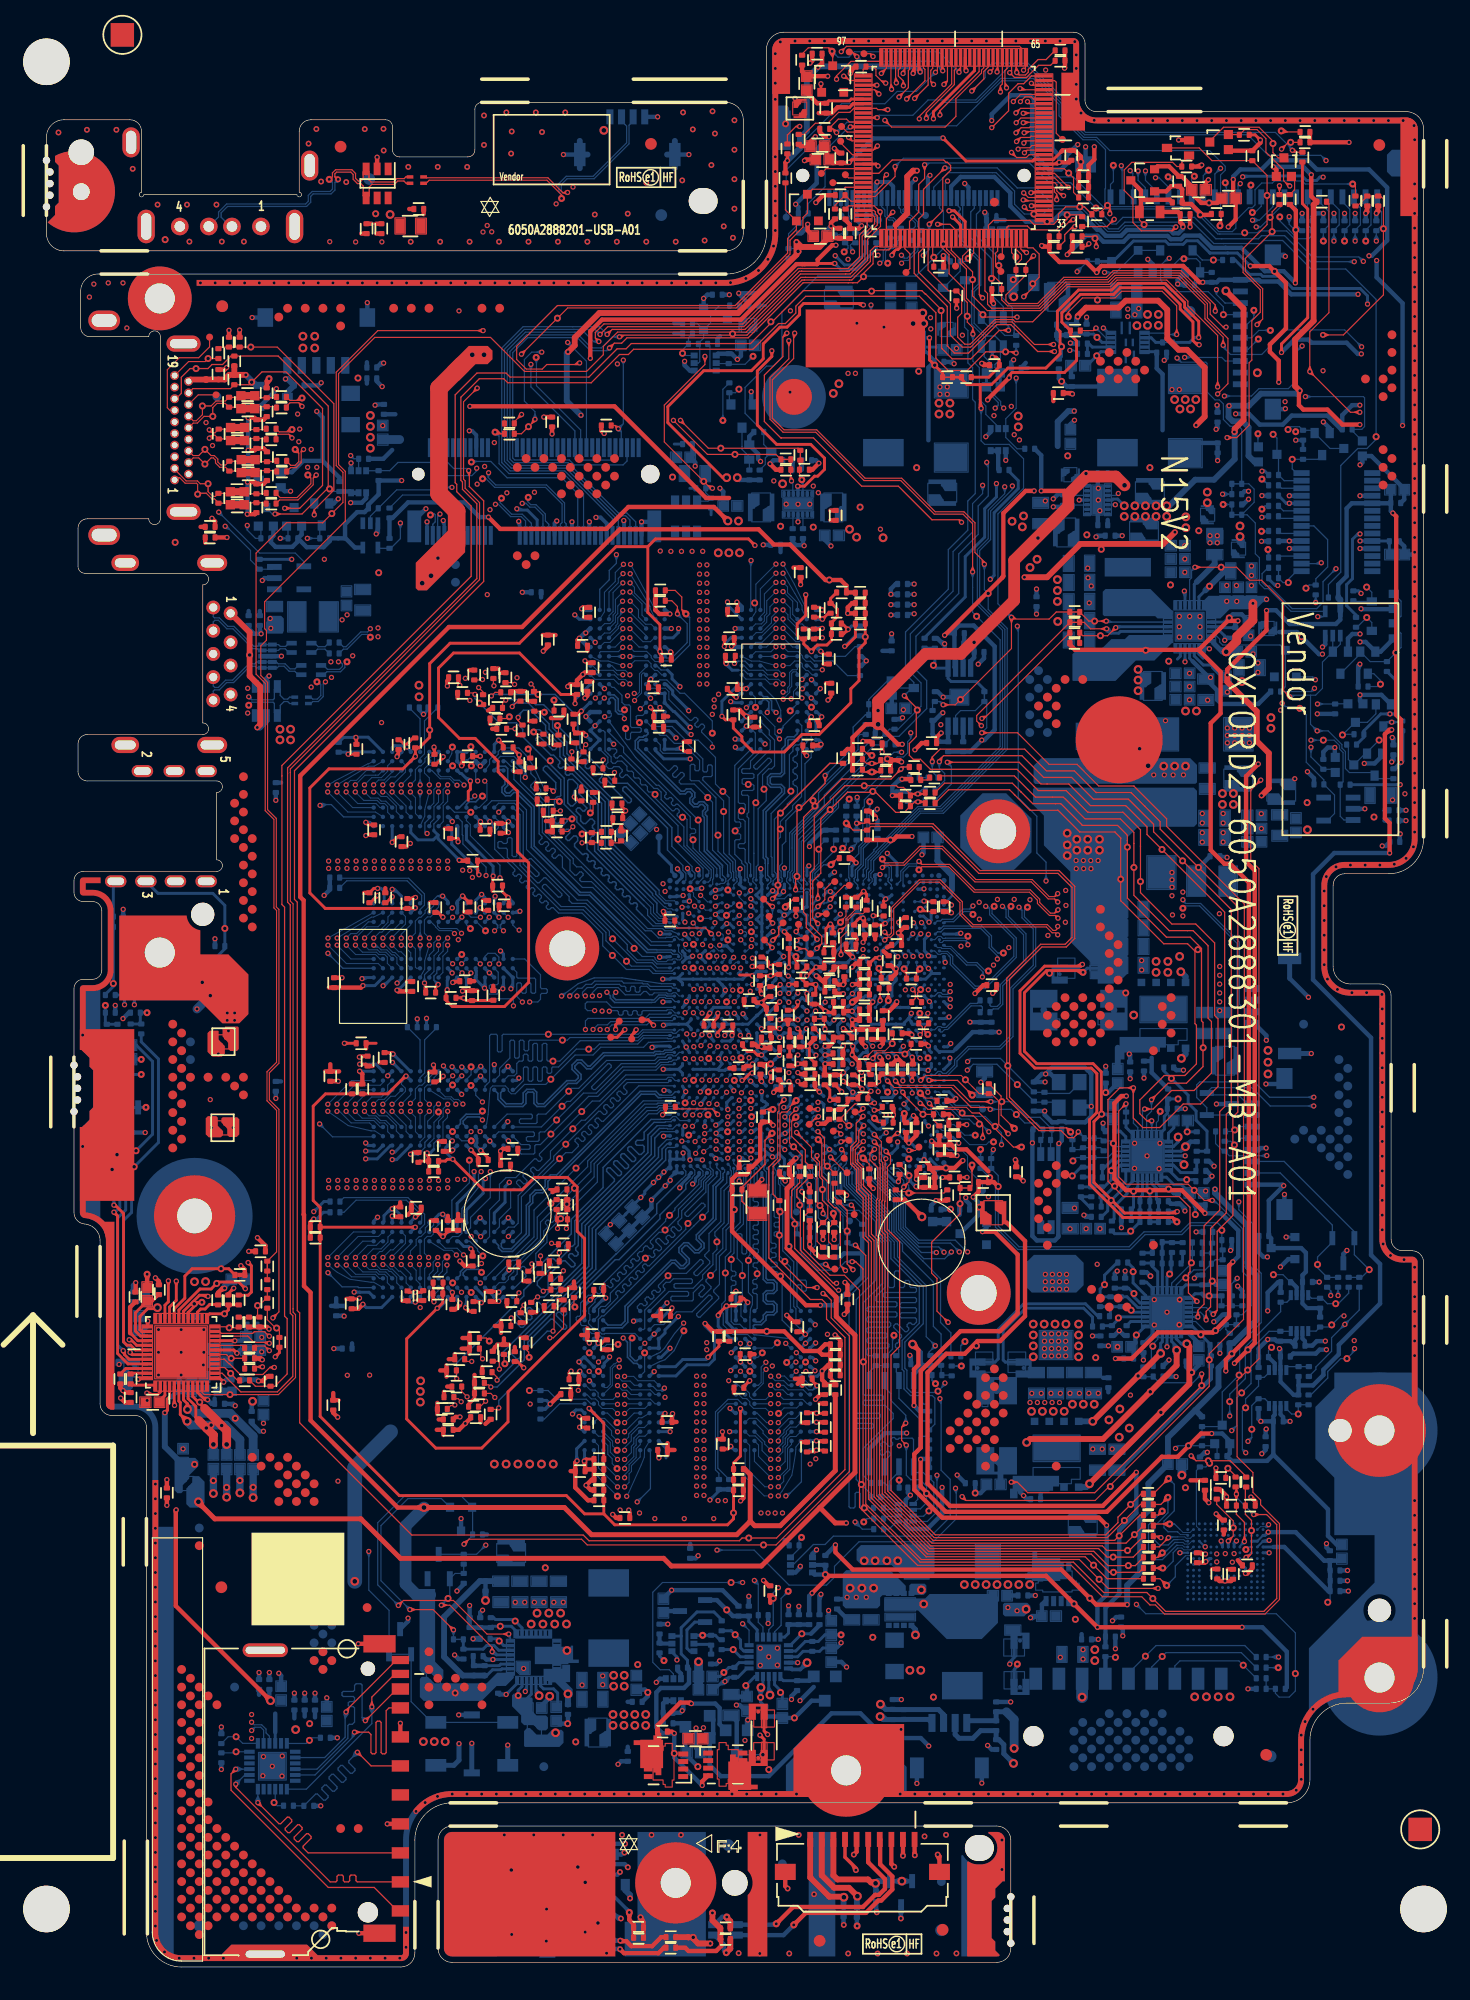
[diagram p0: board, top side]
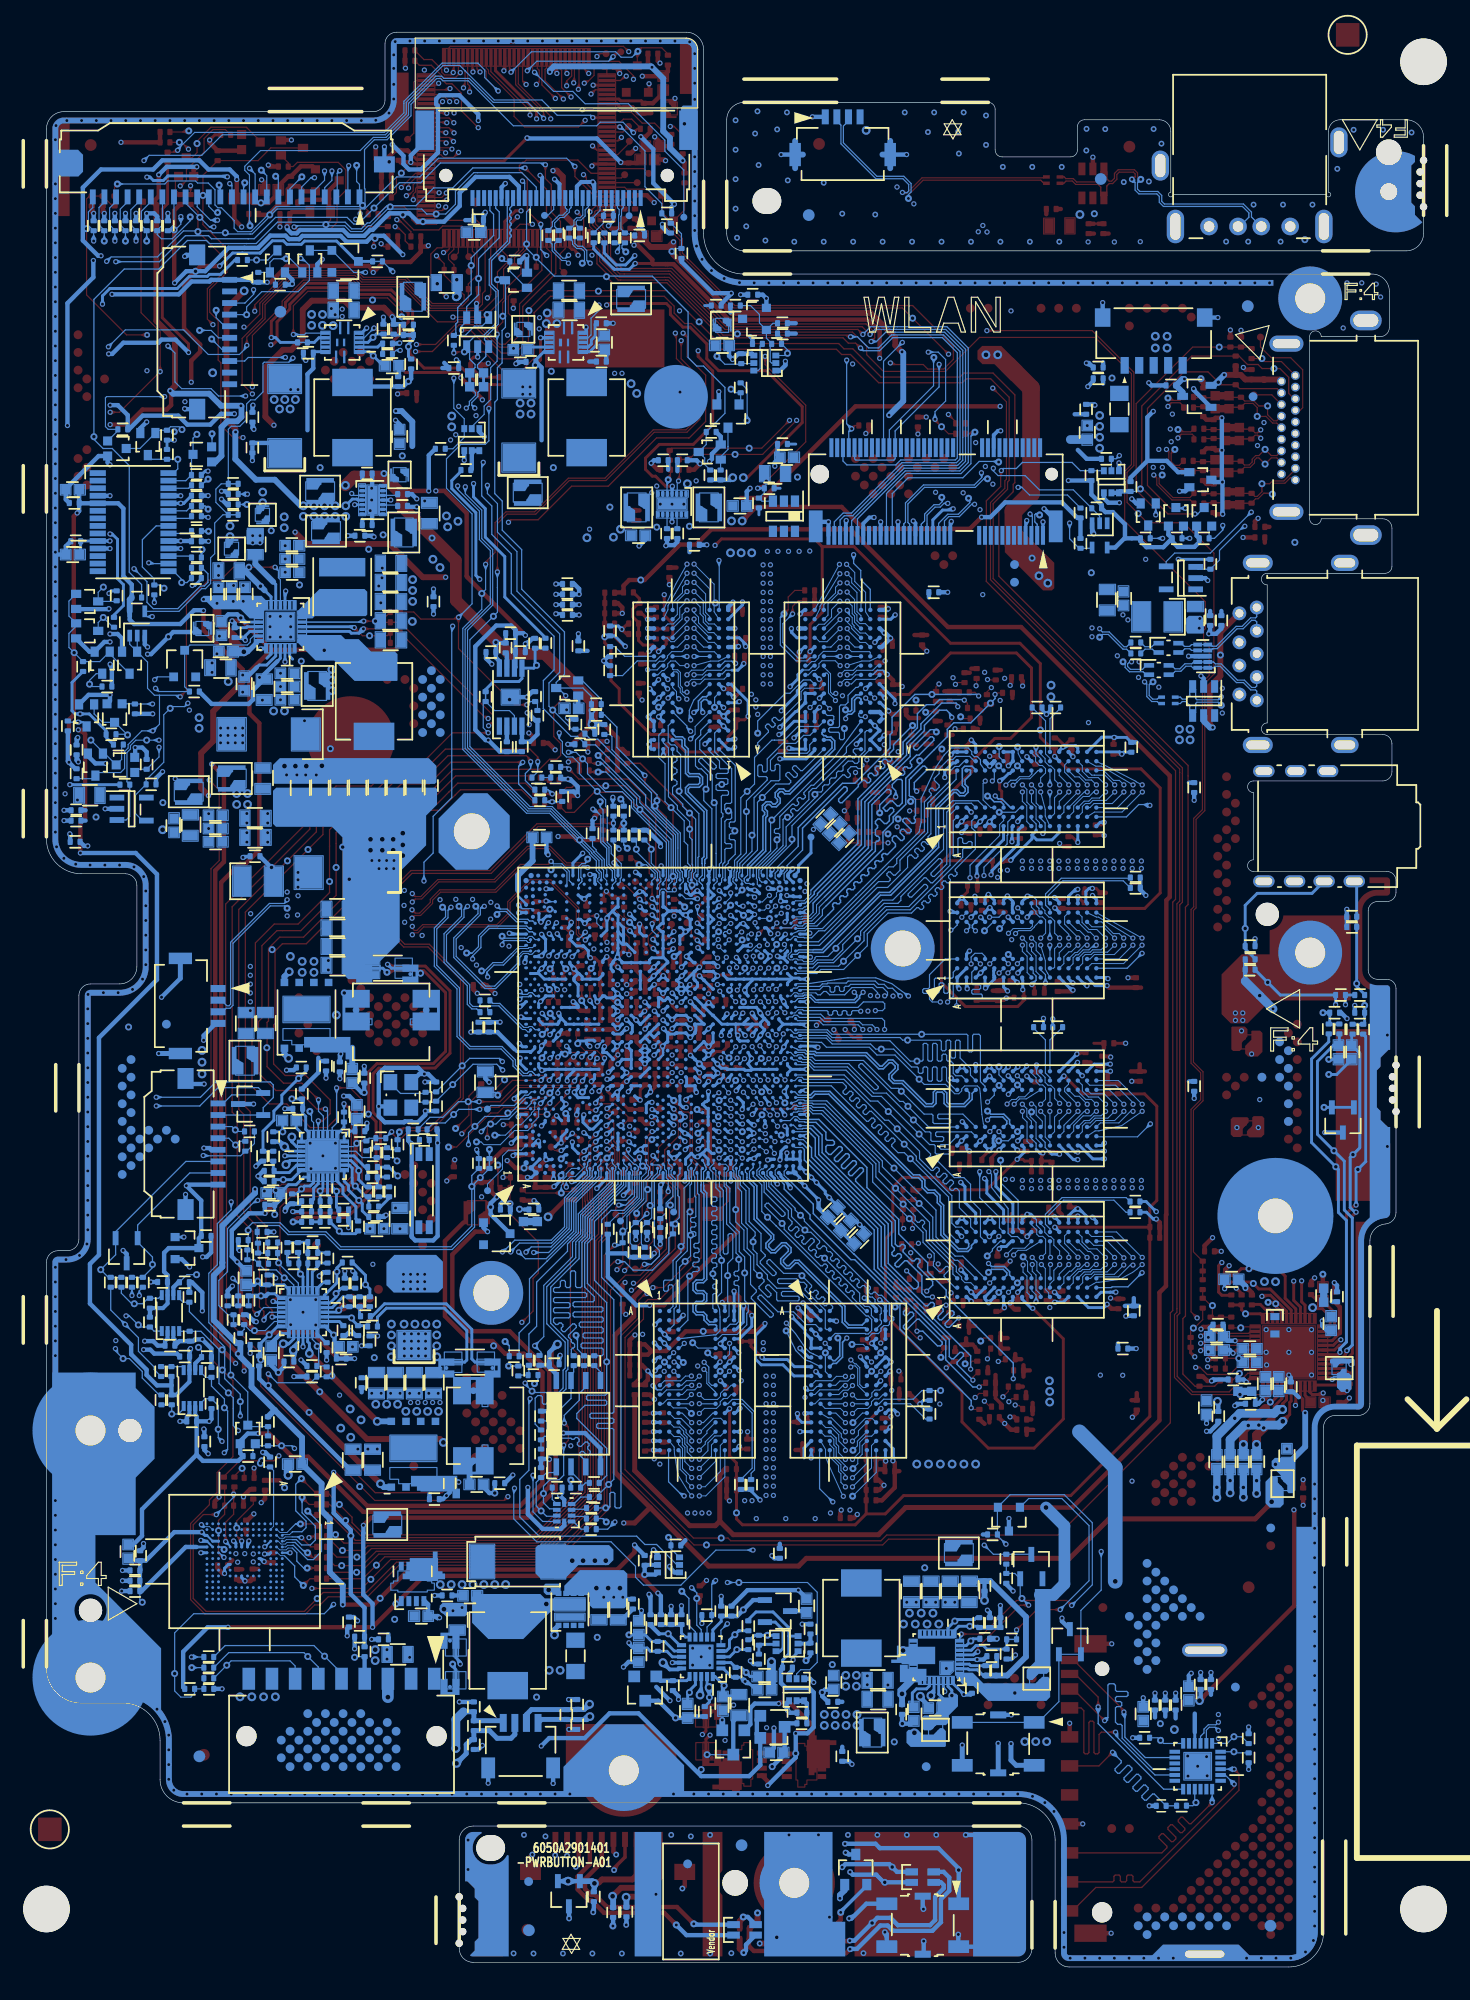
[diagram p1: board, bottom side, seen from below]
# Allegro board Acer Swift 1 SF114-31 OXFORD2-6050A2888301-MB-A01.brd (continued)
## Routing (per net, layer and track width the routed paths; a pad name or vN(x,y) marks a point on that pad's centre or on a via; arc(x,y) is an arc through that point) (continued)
M_B_DQ<29>: length 22.5
  BOTTOM w0.102: U4500.BC2 56.98,68.79 57.11,68.79 57.3,68.6 57.3,68.33 57.11,68.13 57.1,68.13 56.67,67.7 56.67,67.09 54.79,65.21 54.79,64.57 54.47,64.25 54.47,64.06 54.77,63.76 54.77,63.62 54.63,63.47 54.48,63.47 54.15,63.81 54.03,63.81 53.88,63.66 53.88,63.5 54.19,63.19 54.19,63.04 54.05,62.9 53.91,62.9 53.74,63.07 53.59,63.07 53.45,62.93 53.45,62.78 53.62,62.61 53.62,62.47 53.48,62.32 53.33,62.32 52.85,62.81 52.71,62.81 52.56,62.67 52.56,62.52 53.04,62.04 53.04,61.89 52.9,61.75 52.76,61.75 52.65,61.86 52.51,61.86 52.37,61.72 52.37,61.56 52.47,61.46 52.47,61.32 52.33,61.17 52.18,61.17 52.02,61.34 51.89,61.34 v2(51.66,61.11) 48.64,58.08 48.64,57.39 48.19,56.94 47.84,56.94 47.62,56.73 47.62,56.16 U4105.B8
M_B_DQ<30>: length 22
  BOTTOM w0.102: U4500.AW1 58.68,68.35 58.68,67.6 58.17,67.09 58.17,64.26 57.14,63.24 57.14,61.75 56.78,61.38 56.78,61.28 57.21,60.85 57.21,60.67 56.15,59.61 55.99,59.61 55.85,59.75 55.85,59.88 56.63,60.67 56.63,60.85 56.49,60.99 56.38,60.99 55.19,59.8 53.82,59.8 v2(53.61,59.59) 52.78,58.77 52.78,58.62 52.96,58.45 52.96,58.31 52.81,58.16 52.67,58.16 52.5,58.33 52.35,58.33 52.21,58.19 52.21,58.05 52.38,57.87 52.38,57.73 52.24,57.59 52.09,57.59 51.92,57.76 51.78,57.76 51.63,57.62 51.63,57.47 51.81,57.3 51.81,57.16 51.66,57.01 51.52,57.01 51.35,57.18 51.2,57.18 50.97,56.95 50.97,56.8 U4105.A3
M_B_DQ<31>: length 23.8
  BOTTOM w0.102: U4105.A7 48.1,56.55 49.26,57.71 49.26,57.86 49.11,58.01 49.11,58.16 49.25,58.3 49.4,58.3 49.55,58.15 49.7,58.15 49.84,58.29 49.84,58.43 49.68,58.59 49.68,58.73 49.83,58.88 49.97,58.88 50.13,58.72 50.27,58.72 50.41,58.87 50.41,59.01 50.26,59.16 50.26,59.31 50.4,59.45 50.55,59.45 50.7,59.3 50.85,59.3 50.99,59.44 50.99,59.58 50.83,59.74 50.83,59.88 50.98,60.03 51.12,60.03 51.28,59.87 51.42,59.87 51.56,60.02 51.56,60.16 51.41,60.31 51.41,60.46 51.55,60.6 51.7,60.6 51.85,60.45 52,60.45 55.14,63.59 55.14,63.92 v2(55.33,64.1) 56.8,65.58 56.8,65.7 56.66,65.84 56.5,65.84 55.36,64.71 55.22,64.71 55.07,64.85 55.07,65 56.88,66.8 56.88,67.62 57.19,67.93 57.19,67.93 57.5,68.24 57.5,68.68 57.24,68.95 U4500.BB3
M_B_DQ<32>: length 24.7
  BOTTOM w0.089: 40.3,59.94 39.84,59.49 39.84,59.28 39.56,59 39.05,59 U4106.C2
  BOTTOM w0.102: U4500.BG12 54.58,73.99 54.29,74.28 54.04,74.28 53.95,74.19 53.54,74.19 53.47,74.26 52.81,74.26 52.65,74.11 51.7,74.11 46.96,69.36 46.96,68.56 v2(45.54,67.14) 42.61,64.21 42.61,62.71 40.3,60.39 40.3,59.94 40.3,59.94
M_B_DQ<33>: length 24.3
  BOTTOM w0.102: U4106.A2 40.4,58.57 41.35,59.51 41.35,59.66 40.9,60.11 40.9,60.25 41.04,60.39 41.19,60.39 41.63,59.95 41.78,59.95 42.27,60.44 42.27,60.78 42.21,60.85 42.21,61.51 43.17,62.47 43.17,63.33 v2(44.35,64.51) 47.52,67.68 47.52,69.13 51.94,73.55 52.67,73.55 52.98,73.86 53.3,73.86 53.38,73.78 53.94,73.78 54.02,73.7 54.33,73.7 U4500.BG11
M_B_DQ<34>: length 26.4
  BOTTOM w0.102: U4106.C8 39.07,63.81 39.07,64.49 40.04,65.46 40.04,66.9 40.26,67.12 40.4,67.12 40.58,66.94 40.73,66.94 40.87,67.09 40.87,67.23 40.54,67.56 40.54,67.7 40.69,67.84 40.83,67.84 41.16,67.52 41.3,67.52 41.44,67.66 41.44,67.81 41.11,68.14 41.11,68.27 41.25,68.42 41.41,68.42 41.73,68.09 41.88,68.09 42.02,68.24 42.02,68.38 41.77,68.63 41.77,68.8 41.91,68.94 42.03,68.94 42.31,68.67 42.45,68.67 43.47,69.69 43.47,70.33 v2(45.4,72.26) 46.14,73 46.46,73 49.99,76.53 53.45,76.53 53.62,76.7 53.94,76.7 54.23,76.42 U4500.BG17
M_B_DQ<35>: length 25.2
  BOTTOM w0.102: U4106.B8 39.84,63.79 40.35,63.79 40.68,64.12 40.68,66.5 43.75,69.57 43.75,69.89 v2(44.79,70.93) 47.63,73.77 47.78,73.77 48.05,73.5 48.2,73.5 48.34,73.64 48.34,73.78 48.06,74.06 48.06,74.2 48.21,74.35 48.35,74.35 48.63,74.07 48.77,74.07 48.92,74.21 48.92,74.36 48.64,74.64 48.64,74.78 48.78,74.92 48.93,74.92 49.2,74.65 49.35,74.65 49.49,74.79 49.49,74.93 49.21,75.21 49.21,75.35 49.36,75.5 49.5,75.5 49.78,75.22 49.92,75.22 50.07,75.36 50.07,75.51 49.79,75.79 49.79,75.93 50.1,76.25 53.61,76.25 U4500.BJ17
M_B_DQ<36>: length 22.4
  BOTTOM w0.102: U4500.BH12 53.87,73.99 53.87,73.99 53.46,73.99 53.39,74.06 52.89,74.06 52.66,73.83 51.82,73.83 47.24,69.25 47.24,68.12 v2(44.88,65.76) 43.84,64.72 43.84,64.4 43.65,64.2 43.5,64.2 43.32,64.38 43.18,64.38 43.03,64.24 43.03,64.1 43.21,63.91 43.21,63.77 42.89,63.45 42.89,62.59 40.6,60.3 40.6,59.74 40.22,59.37 U4106.A3
M_B_DQ<37>: length 22.8
  BOTTOM w0.102: U4500.BJ13 52.73,74.47 52.65,74.39 51.59,74.39 46.68,69.48 46.68,68.99 v2(43.51,65.82) 42.33,64.65 42.33,62.82 40.43,60.92 40.17,60.92 38.62,59.37 U4106.C3
M_B_DQ<38>: length 25.2
  BOTTOM w0.102: U4106.D7 38.22,62.96 38.22,65.27 39.07,66.13 39.07,67.48 39.65,68.05 40.47,68.05 42.09,69.67 42.23,69.67 42.43,69.46 42.58,69.46 42.72,69.61 42.72,69.75 42.52,69.95 42.52,70.1 v2(46.17,73.75) 47.07,74.65 47.72,74.65 49.97,76.9 U4500.BH18
M_B_DQ<39>: length 25.1
  BOTTOM w0.102: U4106.A7 40.96,63.31 40.96,66.39 v2(44.26,69.68) 44.78,70.2 45.32,70.2 45.87,70.75 45.87,70.89 45.59,71.17 45.59,71.32 45.74,71.46 45.88,71.46 46.16,71.18 46.3,71.18 46.45,71.32 46.45,71.47 46.17,71.75 46.17,71.89 46.31,72.03 46.46,72.03 46.73,71.76 46.88,71.76 47.02,71.9 47.02,72.04 46.74,72.32 46.74,72.47 46.89,72.61 47.03,72.61 47.31,72.33 47.45,72.33 47.6,72.48 47.6,72.62 47.32,72.9 47.32,73.04 47.46,73.18 47.61,73.18 47.88,72.91 48.03,72.91 51.09,75.97 54.13,75.97 U4500.BH16
M_B_DQ<40>: length 32.6
  L3 w0.089: 52.39,73.7 52.45,73.7 54.64,75.89 55.96,75.89 v1(56.54,76.47)
  L3 w0.124: v1(36.62,72.02) 37.03,71.61 37.6,71.61 37.95,71.95 38.94,71.95 39.06,72.08 39.06,72.47 39.18,72.59 39.36,72.59 39.49,72.46 39.49,72.08 39.62,71.95 39.8,71.95 39.92,72.08 39.92,72.43 40.05,72.55 40.23,72.55 40.35,72.43 40.35,72.08 40.47,71.95 41.28,71.95 41.54,72.21 41.54,72.71 41.66,72.84 42.24,72.84 42.37,72.96 42.37,73.14 42.24,73.27 41.66,73.27 41.54,73.39 41.54,73.57 41.67,73.7 42.24,73.7 42.37,73.82 42.37,74.03 42.49,74.16 42.67,74.16 42.8,74.03 42.8,73.28 42.93,73.15 43.11,73.15 43.23,73.27 43.23,74.03 43.35,74.16 43.53,74.16 43.66,74.03 43.66,73.28 43.79,73.15 43.97,73.15 44.09,73.27 44.09,74.03 44.21,74.16 44.39,74.16 44.52,74.03 44.52,73.82 44.64,73.7 44.82,73.7 44.94,73.82 44.94,74.03 45.07,74.16 45.25,74.16 45.37,74.03 45.37,73.82 45.5,73.7 45.68,73.7 45.8,73.82 45.8,74.03 45.93,74.16 46.11,74.16 46.23,74.03 46.23,73.82 46.36,73.7 52.39,73.7
  BOTTOM w0.089: U4500.BC18 v1(56.54,76.47)
  BOTTOM w0.102: U4107.F2 v1(36.62,72.02)
M_B_DQ<41>: length 32.8
  L3 w0.124: v3(36.64,71.22) 37.66,71.22 38.09,71.65 41.71,71.65 41.84,71.78 41.84,72.4 41.96,72.53 42.14,72.53 42.27,72.4 42.27,71.52 42.39,71.39 42.57,71.39 42.64,71.46 42.7,71.52 42.7,72.72 42.82,72.85 43,72.85 43.13,72.72 43.13,71.52 43.25,71.39 43.43,71.39 43.56,71.52 43.56,72.72 43.68,72.85 43.86,72.85 43.98,72.72 43.98,71.52 44.11,71.39 44.28,71.39 44.41,71.52 44.41,73.26 44.54,73.39 52.5,73.39 54.16,75.06 55.45,75.06 56.44,76.06 56.82,76.06 v1(57.19,76.44)
  BOTTOM w0.089: U4500.BA18 v1(57.19,76.44)
  BOTTOM w0.102: v3(36.64,71.22) 35.82,71.22 U4107.G2
M_B_DQ<42>: length 32.5
  L3 w0.089: v1(59.2,78.36) 58.42,77.57 54.87,77.57 54.62,77.83 53.88,77.83
  L3 w0.124: 53.88,77.83 53.04,77.83 52.33,77.11 51.54,77.11 51.42,77.23 51.42,77.84 51.3,77.97 48.05,77.97 47.93,77.85 47.93,77.67 48.06,77.54 50.87,77.54 50.99,77.41 50.99,77.23 50.87,77.11 41.81,77.11 40.7,76 v3(36.61,76)
  BOTTOM w0.102: v3(36.61,76) 36.63,76.02 U4107.F7 ; U4500.AU20 v1(59.2,78.36)
M_B_DQ<43>: length 31.9
  L3 w0.089: 53.88,78.57 54.48,78.57 54.62,78.72 58.71,78.72 v1(59.33,79.33)
  L3 w0.124: 53.88,78.57 52.9,78.57 52.49,78.16 51.95,78.16 51.55,78.57 44.88,78.57 44.74,78.43 44.74,77.85 44.6,77.71 44.43,77.71 44.31,77.84 44.31,78.45 44.19,78.57 41.88,78.57 41.76,78.45 41.76,78.27 41.89,78.14 43.76,78.14 43.88,78.02 43.88,77.84 43.76,77.71 40.67,77.71 40.19,77.23 37,77.23 v3(36.62,77.6)
  BOTTOM w0.102: v3(36.62,77.6) 36.62,76.92 36.22,76.52 U4107.F8 ; U4500.AU22 v1(59.33,79.33)
M_B_DQ<44>: length 32
  L3 w0.089: v1(55.07,76.47) 54.72,76.47 53.06,74.82 53,74.82
  L3 w0.124: 53,74.82 47.81,74.82 47.69,74.94 47.69,75.55 47.56,75.68 43.52,75.68 43.4,75.55 43.4,75.37 43.52,75.25 47.14,75.25 47.26,75.12 47.26,74.94 47.14,74.82 41.95,74.82 41.4,74.27 39.45,74.27 38.02,72.85 38.02,72.85 37.72,72.55 35.55,72.55 v3(35.02,72.02)
  BOTTOM w0.089: U4500.BF18 v1(55.07,76.47)
  BOTTOM w0.102: U4107.H3 34.62,72.42 v3(35.02,72.02)
M_B_DQ<45>: length 31.7
  L3 w0.089: v3(55.82,76.44) 55.45,76.08 54.58,76.08 52.96,74.46 52.78,74.46
  L3 w0.124: 52.78,74.46 52.42,74.46 52.3,74.34 52.3,74.12 52.18,74 52,74 51.87,74.13 51.87,74.34 51.75,74.46 51.57,74.46 51.44,74.34 51.44,74.12 51.32,74 51.14,74 51.01,74.13 51.01,74.34 50.89,74.46 50.71,74.46 50.58,74.34 50.58,74.12 50.46,74 50.28,74 50.15,74.13 50.15,74.34 50.03,74.46 49.85,74.46 49.72,74.34 49.72,74.12 49.6,74 49.42,74 49.29,74.13 49.29,74.34 49.17,74.46 48.99,74.46 48.87,74.34 48.87,74.12 48.75,74 48.56,74 48.44,74.13 48.44,74.34 48.31,74.46 48.13,74.46 48.01,74.34 48.01,74.12 47.89,74 47.71,74 47.58,74.13 47.58,74.34 47.45,74.46 47.27,74.46 47.15,74.34 47.15,74.12 47.03,74 46.85,74 46.72,74.13 46.72,74.34 46.59,74.46 42.03,74.46 41.54,73.97 41.36,73.97 41.23,73.85 41.23,72.38 41.11,72.26 40.93,72.26 40.8,72.38 40.8,73.85 40.68,73.97 40.5,73.97 40.38,73.85 40.38,73.34 40.24,73.21 40.06,73.21 39.95,73.32 39.95,73.85 39.82,73.97 39.57,73.97 39.16,73.56 39.16,73.38 39.35,73.19 39.35,73.02 39.22,72.89 39.05,72.89 38.86,73.08 38.68,73.08 38.55,72.95 38.55,72.77 38.74,72.58 38.74,72.41 38.61,72.28 38.44,72.28 38.25,72.47 38.11,72.47 37.9,72.26 37.83,72.26 37.82,72.25 37.62,72.25 v1(37.4,72.02)
  BOTTOM w0.089: U4500.BD18 v3(55.82,76.44)
  BOTTOM w0.102: v1(37.4,72.02) 37.02,72.4 U4107.E3
M_B_DQ<46>: length 31.5
  L3 w0.089: 53.88,78.27 54.57,78.27 55.06,77.79 58.05,77.79 v1(58.57,78.31)
  L3 w0.124: v3(35.02,76.04) 35.94,76.04 36.33,76.43 36.99,76.43 37.03,76.39 39.78,76.39 40.8,77.41 46.65,77.41 46.77,77.53 46.77,77.71 46.65,77.84 45.17,77.84 45.04,77.96 45.04,78.14 45.17,78.27 47.08,78.27 47.2,78.14 47.2,77.53 47.33,77.41 47.5,77.41 47.63,77.55 47.63,78.17 47.74,78.27 51.42,78.27 51.83,77.86 52.62,77.86 53.02,78.27 53.88,78.27
  BOTTOM w0.102: U4107.H7 34.62,75.64 v3(35.02,76.04) ; U4500.AV20 58.88,77.97 v1(58.57,78.31)
M_B_DQ<47>: length 33.1
  L3 w0.089: v1(58.62,79.33) 58.18,78.89 54.55,78.89 54.53,78.87 53.88,78.87
  L3 w0.124: v1(35.04,76.83) 35.4,77.2 35.4,77.81 35.61,78.02 36.96,78.02 37.07,78.14 37.07,78.72 37.2,78.84 37.38,78.84 37.5,78.72 37.5,78.32 37.62,78.2 37.82,78.2 37.93,78.31 37.93,78.72 38.06,78.84 38.24,78.84 38.36,78.72 38.36,78.34 38.48,78.22 38.66,78.22 38.79,78.34 38.79,78.71 38.92,78.83 39.1,78.83 39.22,78.71 39.22,78.06 39.33,77.94 39.51,77.94 39.65,78.07 39.65,78.71 39.77,78.83 39.95,78.83 40.08,78.71 40.08,78.05 40.2,77.93 40.38,77.93 40.51,78.05 40.51,78.71 40.63,78.83 40.81,78.83 40.93,78.71 40.93,78.17 41.06,78.05 41.24,78.05 41.36,78.17 41.36,78.72 41.52,78.87 51.69,78.87 52.07,78.49 52.38,78.49 52.77,78.87 53.88,78.87
  BOTTOM w0.102: v1(58.62,79.33) 58.88,78.97 U4500.AV22 ; U4107.H8 v1(35.04,76.83)
M_B_DQ<48>: length 39.3
  L4 w0.089: v1(55.1,78.32) 51.96,78.32 51.8,78.15 51.05,78.15
  L4 w0.124: v3(37.63,61.3) 38.11,61.3 38.95,62.13 38.95,66.08 40.34,67.47 40.34,68.62 41.63,69.91 41.63,74.05 44.82,77.24 44.82,77.41 44.69,77.54 44.52,77.54 42.74,75.76 42.56,75.76 42.44,75.89 42.44,76.07 44.52,78.15 44.69,78.15 45.12,77.72 45.3,77.72 45.73,78.15 51.05,78.15
  BOTTOM w0.089: U4500.BF20 55.1,78.31 v1(55.1,78.32)
  BOTTOM w0.102: U4106.F7 36.51,62.57 37.18,61.89 37.18,61.75 v3(37.63,61.3)
M_B_DQ<49>: length 41.5
  L4 w0.089: 51.05,77.55 51.74,77.55 52.08,77.89 54.72,77.89 54.86,77.75 55.91,77.75 v1(56.46,78.3)
  L4 w0.124: 51.05,77.55 46,77.55 42.23,73.78 42.23,68.51 42.02,68.29 41.84,68.29 41.45,68.69 41.26,68.69 41.13,68.56 41.13,68.39 41.54,67.99 41.54,67.81 40.74,67.02 40.74,66.72 40.62,66.6 40.37,66.6 40.25,66.47 40.25,66.29 40.37,66.17 40.62,66.17 40.74,66.05 40.74,65.86 40.62,65.74 39.68,65.74 39.55,65.61 39.55,65.43 39.67,65.31 40.62,65.31 40.74,65.19 40.74,64.88 40.62,64.76 40.39,64.76 40.26,64.64 40.26,64.46 40.39,64.33 40.62,64.33 40.74,64.21 40.74,64.03 40.62,63.9 39.67,63.9 39.55,63.78 39.55,63.6 39.68,63.47 40.62,63.47 40.74,63.35 40.74,63.08 38.88,61.21 38.88,59.64 38.21,58.97 v1(37.42,58.97)
  BOTTOM w0.089: U4500.BC20 v1(56.46,78.3)
  BOTTOM w0.102: U4106.E3 v1(37.42,58.97)
M_B_DQ<50>: length 39
  L4 w0.089: 51.74,76.94 52.82,76.94 52.95,76.81 53.44,76.81 54.03,77.4 56.74,77.4 57.57,78.23 57.57,79 v1(57.91,79.34)
  L4 w0.124: v3(36.63,58.15) 36.49,58.01 36.49,57.8 36.61,57.68 37.92,57.68 39.49,59.25 39.49,60.96 41.35,62.83 41.35,66.77 42.84,68.26 42.84,73.53 46.25,76.94 51.74,76.94
  BOTTOM w0.089: v1(57.91,79.34) U4500.BA22
  BOTTOM w0.102: U4106.F2 36.63,58.16 v3(36.63,58.15)
M_B_DQ<51>: length 42.3
  L4 w0.089: 51.45,79.58 51.74,79.58 52,79.85 54.71,79.85 54.74,79.88 56.06,79.88 56.49,80.31 56.49,80.32 v1(56.54,80.38)
  L4 w0.124: v1(38.28,68.57) 38.49,68.78 38.49,69.13 38.38,69.23 37.89,69.23 37.8,69.33 37.8,69.51 37.95,69.66 38.38,69.66 38.49,69.77 38.49,70.4 39.12,71.03 39.12,73.21 39.24,73.33 39.84,73.33 39.96,73.45 39.96,75.35 39.43,75.89 39.43,76.11 39.62,76.31 39.83,76.31 40.68,75.46 40.87,75.46 41,75.59 41,75.74 40.03,76.72 40.03,76.9 40.59,77.46 40.59,77.64 40.21,78.02 40.21,78.19 40.34,78.32 40.51,78.32 40.89,77.94 41.07,77.94 41.2,78.07 41.2,78.25 40.82,78.63 40.82,78.8 40.94,78.93 41.12,78.93 41.5,78.55 41.68,78.55 41.8,78.68 41.8,78.85 41.42,79.23 41.42,79.41 41.55,79.54 41.73,79.54 42.11,79.16 42.28,79.16 42.71,79.58 51.45,79.58
  BOTTOM w0.089: U4500.BD24 v1(56.54,80.38)
  BOTTOM w0.102: U4106.F8 36.58,63.72 36.58,64.62 38.28,66.32 v1(38.28,68.57)
M_B_DQ<52>: length 40.2
  L4 w0.089: 51.32,77.85 51.78,77.85 52,78.07 54.79,78.07 54.93,77.93 55.44,77.93 v1(55.81,78.29)
  L4 w0.124: v3(35.03,58.98) 33.11,58.98 32.99,59.1 32.99,59.34 33.12,59.47 37.68,59.47 38.58,60.37 38.58,61.34 39.25,62.01 39.25,65.95 40.64,67.35 40.64,68.49 41.93,69.78 41.93,73.92 45.86,77.85 51.32,77.85
  BOTTOM w0.089: U4500.BD20 v1(55.81,78.29)
  BOTTOM w0.102: U4106.H3 34.65,59.37 v3(35.03,58.98)
M_B_DQ<53>: length 38.5
  L4 w0.089: 51.47,77.24 52.8,77.24 53.04,77 53.36,77 53.58,77.23 53.59,77.23 53.93,77.57 56.37,77.57 v3(57.12,78.33)
  L4 w0.124: 51.47,77.24 46.12,77.24 42.54,73.66 42.54,68.39 41.05,66.9 41.05,62.95 39.18,61.09 39.18,59.37 38.37,58.56 36.36,58.56 36.23,58.69 36.23,58.94 36.1,59.07 35.92,59.07 35.8,58.95 v1(35.8,58.17)
  BOTTOM w0.089: v3(57.12,78.33) U4500.BA20
  BOTTOM w0.102: U4106.G2 35.42,58.54 v1(35.8,58.17)
M_B_DQ<54>: length 42.9
  L4 w0.089: v1(55.23,80.44) 54.51,80.44 54.28,80.21 51.04,80.21
  L4 w0.124: 51.04,80.21 40.45,80.21 40.26,80.03 40.26,79.85 40.52,79.59 40.52,79.41 40.39,79.28 40.22,79.28 39.96,79.55 39.78,79.55 39.65,79.42 39.65,79.24 39.92,78.98 39.92,78.8 39.79,78.68 39.61,78.68 39.35,78.94 39.17,78.94 39.05,78.81 39.05,78.64 39.31,78.37 39.31,78.2 39.18,78.07 39,78.07 38.74,78.33 38.57,78.33 38.02,77.79 38.02,77.42 38.14,77.29 38.68,77.29 38.8,77.17 38.8,76.99 38.68,76.86 38.14,76.86 38.02,76.74 38.02,76.56 38.14,76.43 38.68,76.43 38.8,76.31 38.8,76.13 38.68,76.01 38.14,76.01 38.02,75.88 38.02,75.67 37.9,75.55 36.65,75.55 36.52,75.43 36.52,75.25 36.65,75.12 37.9,75.12 38.02,75 38.02,72.05 37.04,71.07 37.04,70.11 v3(36.48,69.55)
  BOTTOM w0.089: U4500.BF24 v1(55.23,80.44)
  BOTTOM w0.102: U4106.H8 34.97,63.71 34.97,66.1 36.48,67.61 v3(36.48,69.55)
M_B_DQ<55>: length 41.4
  L4 w0.089: 51.45,79.88 51.79,79.88 51.93,80.03 54.63,80.03 54.66,80.06 55.51,80.06 v1(55.84,80.38)
  L4 w0.124: 51.45,79.88 41.46,79.88 39.12,77.55 39.12,75.62 38.99,75.48 38.73,75.48 38.6,75.36 38.6,75.18 38.73,75.05 39.53,75.05 39.64,74.94 39.64,74.76 39.51,74.62 38.5,74.62 38.37,74.5 38.37,74.32 38.5,74.2 39.53,74.2 39.64,74.08 39.64,73.9 39.51,73.77 38.5,73.77 38.37,73.64 38.37,73.46 38.5,73.34 38.69,73.34 38.81,73.21 38.81,73.03 38.69,72.91 38.5,72.91 38.37,72.78 38.37,72.6 38.5,72.48 38.69,72.48 38.81,72.35 38.81,72.17 38.69,72.05 38.5,72.05 38.37,71.92 38.37,71.74 38.5,71.62 38.69,71.62 38.81,71.5 38.81,71.15 37.76,70.1 37.49,69.83 v1(37.49,68.57)
  BOTTOM w0.089: 56.1,80.66 v1(55.84,80.38)
  BOTTOM w0.102: U4106.H7 35.02,62.97 35.54,62.97 35.83,63.26 35.83,65.39 35.91,65.49 37.26,67.21 37.26,68.34 v1(37.49,68.57) ; U4500.BD26 56.1,80.66
M_B_DQ<56>: length 21.4
  BOTTOM w0.102: U4500.BJ21 53.66,78.36 53.54,78.24 52.88,78.24 52.52,77.88 49.58,77.88 47.34,75.64 47.17,75.64 47.03,75.79 47.03,75.9 48.71,77.58 48.71,77.73 48.57,77.88 48.43,77.88 45.18,74.62 44.89,74.62 v2(44.47,74.2) 42.68,72.42 U4107.A3
M_B_DQ<57>: length 22.2
  BOTTOM w0.102: U4500.BG25 54.39,80.17 54.08,80.17 53.94,80.02 53.62,80.02 53.56,80.08 51.51,80.08 51,79.57 47.7,79.57 47.25,79.13 v2(46.77,79.13) 45.7,79.13 44.16,77.59 43.67,77.59 43.58,77.49 43.58,77.14 43.48,77.04 43.27,77.04 43.17,77.14 43.17,77.49 43.07,77.59 42.87,77.59 42.77,77.49 42.77,76.47 42.66,76.37 42.45,76.37 42.36,76.46 42.36,77.49 42.26,77.59 42.05,77.59 41.95,77.49 41.95,76.47 41.84,76.37 41.64,76.37 41.55,76.46 41.55,77.49 41.45,77.59 41.24,77.59 41.14,77.49 41.14,76.42 40.34,75.62 U4107.A7
M_B_DQ<58>: length 20.1
  BOTTOM w0.102: U4107.A2 40.94,70.9 41.61,70.9 41.72,70.8 41.72,70.59 41.62,70.49 40.95,70.49 40.85,70.39 40.85,70.19 40.95,70.09 42.02,70.09 42.12,70.19 42.12,70.8 42.22,70.9 42.6,70.9 v2(43.51,71.8) 46.76,75.06 47.55,75.06 49.81,77.32 52.57,77.32 53.03,77.78 54.07,77.78 U4500.BH20
M_B_DQ<59>: length 22.5
  BOTTOM w0.102: U4107.C3 39.73,73.53 41.81,73.53 41.91,73.43 41.91,73.22 41.81,73.12 40.9,73.12 40.79,73.01 40.79,72.81 40.88,72.71 42.21,72.71 42.31,72.82 42.31,73.43 42.42,73.53 43.07,73.53 v2(45.05,75.5) 45.3,75.75 45.91,75.75 48.31,78.15 52.45,78.15 52.73,78.44 53.38,78.44 53.58,78.64 53.95,78.64 54.05,78.54 54.28,78.54 54.58,78.85 U4500.BG22
M_B_DQ<60>: length 23.8
  BOTTOM w0.102: U4500.BG26 54.59,80.8 54.29,80.49 54.04,80.49 53.94,80.59 51.48,80.59 51.02,80.13 45.16,80.13 44.93,79.9 v2(44.5,79.9) 41.7,79.9 41.59,79.8 41.59,79.09 41.49,78.99 41.29,78.99 41.19,79.09 41.19,79.8 41.09,79.9 40.88,79.9 40.78,79.8 40.78,78.47 40.67,78.36 40.46,78.36 40.37,78.44 40.37,79.8 40.27,79.9 40.07,79.9 39.97,79.8 39.97,78.36 39.08,77.47 39.08,76.87 38.62,76.42 U4107.C8
M_B_DQ<61>: length 23
  BOTTOM w0.102: U4107.B8 39.84,76.83 40.35,76.83 40.56,77.05 40.56,77.89 40.77,78.1 41.03,78.1 41.13,78.2 41.13,78.59 41.23,78.69 41.44,78.69 41.54,78.59 41.54,78.2 41.64,78.1 41.84,78.1 41.94,78.2 41.94,79.5 42.07,79.62 42.27,79.62 42.35,79.54 42.35,78.2 42.45,78.1 42.66,78.1 42.76,78.2 42.76,79.5 42.88,79.62 43.08,79.62 43.16,79.54 43.16,78.2 43.27,78.1 v2(43.69,78.1) 44.28,78.1 46.03,79.85 51.01,79.85 51.46,80.3 U4500.BJ25
M_B_DQ<62>: length 23.8
  BOTTOM w0.102: U4500.BH26 51.41,80.79 51.03,80.41 v2(43.29,80.41) 39.4,80.41 39.3,80.31 39.3,79.01 39.19,78.89 38.98,78.89 38.89,78.98 38.89,80.31 38.79,80.41 38.34,80.41 38.22,80.29 38.22,76.33 38,76.11 37.82,75.93 U4107.D7
M_B_DQ<63>: length 21.4
  BOTTOM w0.102: U4107.C2 39,71.99 41.98,71.99 42.08,71.89 42.08,71.69 41.98,71.59 41.49,71.59 41.39,71.49 41.39,71.28 41.49,71.18 42.39,71.18 42.49,71.28 42.49,71.89 42.59,71.99 42.98,71.99 44,73.02 v2(44,73.02) 44.01,73.02 46.32,75.34 47.44,75.34 49.69,77.6 52.56,77.6 52.95,77.99 53.62,77.99 53.7,78.06 53.91,78.06 54.05,78.19 54.35,78.19 U4500.BG21
M_B_DQS0_DN: length 17.7
  BOTTOM w0.102: 62.08,67.36 62.08,67.38 62.1,67.4 62.1,68.52 61.88,68.74 61.88,68.95 61.97,69.08 62,69.17 U4500.AM3
  BOTTOM w0.137: 62.08,67.36 62.08,66.99 61.82,66.73 61.82,59.27 62.11,58.99 62.63,58.99 62.77,58.85 62.77,58.44 62.63,58.31 62.09,58.31 61.82,58.04 61.82,57.43 62.11,57.14 62.63,57.14 62.77,57 62.77,56.59 62.63,56.46 62.09,56.46 61.82,56.19 61.82,55.87 61.56,55.61 61.2,55.61 U4104.B7
M_B_DQS0_DP: length 17.7
  BOTTOM w0.102: U4500.AM2 62.3,68.74 62.3,67.47 62.32,67.46 62.32,67.36
  BOTTOM w0.137: 62.32,67.36 62.32,66.89 62.06,66.63 62.06,59.37 62.21,59.23 62.73,59.23 63.01,58.95 63.01,58.34 62.73,58.07 62.19,58.07 62.06,57.94 62.06,57.52 62.21,57.38 62.73,57.38 63.01,57.1 63.01,56.49 62.73,56.22 62.19,56.22 62.06,56.09 62.06,55.78 61.66,55.37 61.07,55.37 60.97,55.28 60.97,55.04 61.06,54.95 U4104.C7
M_B_DQS1_DN: length 24.5
  L4 w0.102: 59.13,69.36 59.13,69.38 59.16,69.4 59.16,70.43 58.99,70.6 58.91,70.6 v3(58.77,70.46)
  L4 w0.147: 59.13,69.36 59.13,69.06 58.64,68.57 58.64,64.64 49.96,55.96 49.96,54.44 v1(49.74,54.22)
  BOTTOM w0.102: v3(58.77,70.46) 58.88,70.54 U4500.AV6
  BOTTOM w0.137: U4105.G3 51.21,51.75 50.93,52.03 50.65,52.03 50.11,52.57 50.11,53.86 49.75,54.22 v1(49.74,54.22)
M_B_DQS1_DP: length 24.5
  L4 w0.102: 59.38,69.36 59.35,69.4 59.35,70.51 58.76,71.1 v1(58.76,71.14)
  L4 w0.147: v3(50.51,54.22) 50.21,54.53 50.21,55.86 58.89,64.54 58.89,68.47 59.38,68.96 59.38,69.36
  BOTTOM w0.102: U4500.AV7 58.88,71.23 v1(58.76,71.14)
  BOTTOM w0.137: v3(50.51,54.22) 50.51,54.23 50.35,54.07 50.35,52.67 50.75,52.27 50.93,52.27 51.21,52.55 U4105.F3
M_B_DQS2_DN: length 34.5
  L3 w0.102: v1(59.73,74) 59.89,73.84 60.1,73.84 60.36,73.58 60.36,69.12 60.18,68.94 60.18,68.91 60.16,68.89
  L3 w0.147: 60.16,68.89 59.32,68.05 59.32,67.48 59.47,67.33 59.95,67.33 60.24,67.04 60.24,66.57 59.95,66.28 59.47,66.28 59.32,66.13 59.32,65.87 59.47,65.72 59.95,65.72 60.24,65.43 60.24,64.97 59.95,64.67 59.47,64.67 59.32,64.53 59.32,64.27 59.47,64.12 59.95,64.12 60.24,63.83 60.24,63.36 59.95,63.07 59.47,63.07 59.32,62.92 59.32,62.66 59.47,62.51 59.95,62.51 60.24,62.22 60.24,58.5 61.17,57.57 61.17,56.66 61.31,56.52 62.17,56.52 62.5,56.18 62.5,55.75 62.2,55.45 61.07,55.45 60.95,55.33 60.95,55.07 61.13,54.9 62.2,54.9 62.5,54.61 62.5,53.08 62.68,52.89 63.01,52.89 63.29,53.17 63.84,53.17 64.39,52.63 64.39,52.41 64.64,52.15 v1(64.64,52.15)
  BOTTOM w0.102: U4500.AT13 v1(59.73,74)
  BOTTOM w0.137: v1(64.64,52.15) 64.53,52.15 64.26,51.89 U4104.G3
M_B_DQS2_DP: length 34.5
  L3 w0.102: v1(59.74,73.35) 59.74,73.51 59.86,73.63 60.02,73.63 60.15,73.5 60.15,69.2 60.03,69.08 60,69.08 59.98,69.06
  L3 w0.147: 59.98,69.06 59.07,68.15 59.07,67.37 59.36,67.08 59.84,67.08 59.99,66.93 59.99,66.67 59.84,66.53 59.36,66.53 59.07,66.23 59.07,65.77 59.36,65.48 59.84,65.48 59.99,65.33 59.99,65.07 59.84,64.92 59.36,64.92 59.07,64.63 59.07,64.16 59.36,63.87 59.84,63.87 59.99,63.72 59.99,63.46 59.84,63.32 59.36,63.32 59.07,63.02 59.07,62.56 59.36,62.27 59.84,62.27 59.99,62.12 59.99,58.4 60.92,57.47 60.92,56.55 61.21,56.27 62.06,56.27 62.25,56.08 62.25,55.85 62.1,55.7 60.97,55.7 60.7,55.43 60.7,54.97 61.02,54.65 62.1,54.65 62.25,54.5 62.25,52.97 62.58,52.64 63.11,52.64 63.39,52.92 63.74,52.92 64.14,52.52 64.14,52.24 64.02,52.12 v3(63.85,52.12)
  BOTTOM w0.102: U4500.AT12 v1(59.74,73.35)
  BOTTOM w0.137: U4104.F3 64.26,52.53 v3(63.85,52.12)
M_B_DQS3_DN: length 23
  BOTTOM w0.102: U4500.BA3 57.82,68.9 58.14,68.58 58.14,67.98
  BOTTOM w0.137: U4105.B7 48.42,55.34 49.56,55.34 49.9,55.68 49.9,56.96 53.87,60.93 54.26,60.93 54.73,60.46 54.92,60.46 55.21,60.75 55.21,60.95 54.55,61.61 54.55,62.01 54.98,62.44 55.37,62.44 56,61.81 56.19,61.81 56.48,62.1 56.48,62.29 56.05,62.72 56.05,63.11 57.5,64.57 57.5,67.34 58.14,67.98
M_B_DQS3_DP: length 23
  BOTTOM w0.102: 58.31,67.81 58.32,67.82 58.32,67.84 58.36,67.89 58.36,68.07 58.35,68.07 58.35,68.4 58.49,68.54 58.49,68.73 58.39,68.84 58.31,68.84 U4500.AY2
  BOTTOM w0.137: U4105.C7 48.01,54.95 48.16,55.1 49.66,55.1 50.14,55.58 50.14,56.87 53.96,60.69 54.16,60.69 54.63,60.22 55.01,60.22 55.45,60.65 55.45,61.05 54.79,61.71 54.79,61.91 55.08,62.2 55.27,62.2 55.9,61.57 56.29,61.57 56.72,62 56.72,62.39 56.29,62.82 56.29,63.02 57.74,64.47 57.74,67.24 58.31,67.81
M_B_DQS4_DN: length 23.9
  BOTTOM w0.102: 53,75.18 53.01,75.18 53.04,75.15 53.09,75.15 53.92,75.15 54.22,75.45 U4500.BG15
  BOTTOM w0.137: U4106.B7 39.23,62.38 39.23,62.09 39.4,61.92 40.1,61.92 41.39,63.21 41.39,65.67 41.7,65.98 41.7,66.53 42.16,66.98 42.7,66.98 43.01,67.29 43.01,67.83 43.46,68.29 44.01,68.29 51.2,75.48 52.57,75.48 52.88,75.18 53,75.18
M_B_DQS4_DP: length 23.9
  BOTTOM w0.102: 53,74.94 53.02,74.96 U4500.BH14
  BOTTOM w0.137: 53,74.94 52.78,74.94 52.47,75.24 51.3,75.24 44.11,68.05 43.56,68.05 43.25,67.74 43.25,67.19 42.8,66.74 42.26,66.74 41.94,66.43 41.94,65.88 41.63,65.57 41.63,63.11 40.2,61.68 39.3,61.68 38.99,61.99 38.99,62.2 38.62,62.57 U4106.C7
M_B_DQS5_DN: length 30.8
  L3 w0.147: v1(60.6,78.38) 60.41,78.2 60.41,77.85 59.63,77.07 54.56,77.07 53.91,76.42 42.2,76.42 40.92,75.14 37.31,75.14 36.99,74.82 36.99,73.68 37.15,73.52 37.49,73.52 37.6,73.63 v3(37.6,73.79)
  BOTTOM w0.102: U4500.AT20 v1(60.6,78.38)
  BOTTOM w0.137: U4107.G3 35.42,72.42 35.7,72.7 35.7,73.03 36.2,73.52 37.34,73.52 v3(37.6,73.79)
M_B_DQS5_DP: length 30.9
  L3 w0.147: v1(37.6,73.02) 37.35,73.27 37.05,73.27 36.75,73.57 36.75,74.92 37.21,75.39 40.82,75.39 42.1,76.67 53.81,76.67 54.46,77.32 59.52,77.32 60.16,77.96 60.16,78.12 v3(59.9,78.38)
  BOTTOM w0.102: U4500.AT22 v3(59.9,78.38)
  BOTTOM w0.137: U4107.F3 35.94,72.7 35.94,72.93 36.3,73.28 37.34,73.28 v1(37.6,73.02)
M_B_DQS6_DN: length 38.8
  L4 w0.089: 51.41,78.59 51.44,78.59 51.47,78.63 52.93,78.63 53.03,78.72 56.69,78.72 56.95,78.97 56.95,79.26 57.1,79.41 v1(57.24,79.41)
  L4 w0.147: 51.41,78.59 44.34,78.59 42,76.25 42,75.04 41,74.04 41,70.42 39.48,68.9 39.48,67.24 38.51,66.26 38.51,62.83 36.92,61.24 36.92,60.51 37.06,60.37 37.24,60.37 v1(37.52,60.65)
  BOTTOM w0.102: U4500.BC22 v1(57.24,79.41)
  BOTTOM w0.137: U4106.G3 35.42,59.37 35.7,59.65 35.7,59.94 36.15,60.38 37.26,60.38 v1(37.52,60.65)
M_B_DQS6_DP: length 38.9
  L4 w0.089: v1(56.45,79.43) 56.66,79.43 56.77,79.32 56.77,79.05 56.62,78.9 52.96,78.9 52.86,78.8 51.47,78.8 51.44,78.84 51.41,78.84
  L4 w0.147: v3(37.52,59.89) 37.29,60.12 36.96,60.12 36.67,60.4 36.67,61.35 38.26,62.93 38.26,66.37 39.23,67.34 39.23,69 40.75,70.52 40.75,74.14 41.75,75.14 41.75,76.35 44.23,78.84 51.41,78.84
  BOTTOM w0.102: U4500.BC24 v1(56.45,79.43)
  BOTTOM w0.137: U4106.F3 35.94,59.65 35.94,59.84 36.25,60.15 37.26,60.15 37.52,59.88 v3(37.52,59.89)
M_B_DQS7_DN: length 22.2
  BOTTOM w0.102: 52.92,78.93 52.94,78.93 52.96,78.91 53.18,78.91 53.32,79.05 53.95,79.05 54.05,79.15 U4500.BG23
  BOTTOM w0.137: 52.92,78.93 52.48,78.93 52.37,78.82 48.04,78.82 46.89,77.67 46.69,77.67 46.17,78.2 45.77,78.2 45.33,77.76 45.33,77.38 45.87,76.85 45.87,76.65 45.63,76.41 44.88,76.41 42.88,74.42 42.41,74.42 42.28,74.55 42.28,75.42 42.04,75.66 41.43,75.66 41.12,75.35 41.12,74.55 40.99,74.42 39.65,74.42 39.17,74.9 39.17,75.37 U4107.B7
M_B_DQS7_DP: length 22.2
  BOTTOM w0.102: U4500.BH22 54.03,78.85 54.03,78.85 53.4,78.85 53.27,78.71 52.96,78.71 52.94,78.69 52.92,78.69
  BOTTOM w0.137: U4107.C7 38.62,75.62 38.93,75.31 38.93,74.8 39.55,74.18 41.09,74.18 41.36,74.45 41.36,75.25 41.53,75.42 41.94,75.42 42.04,75.32 42.04,74.45 42.31,74.18 42.98,74.18 44.98,76.17 45.73,76.17 46.11,76.55 46.11,76.94 45.57,77.48 45.57,77.66 45.87,77.96 46.07,77.96 46.6,77.43 46.99,77.43 48.14,78.58 52.47,78.58 52.58,78.69 52.92,78.69
M_B_OCAVREF: length 10.8
  TOP w0.254: v1(52.37,81.18) 51.89,81.66 TP4502.1
  L4 w0.203: v1(60.57,80.3) 60.56,80.3 59.59,81.28 59.28,81.28 59.17,81.17 55.94,81.17 55.9,81.21 54,81.21 53.53,80.74 52.81,80.74 52.41,81.14
  L4 w0.254: 52.41,81.14 v1(52.37,81.18)
  BOTTOM w0.254: U4500.AT26 60.56,80.63 60.56,80.31 v1(60.57,80.3)
M_B_ODQVREF: length 11.1
  TOP w0.254: TP4503.1 50.48,80.33 50.86,80.71 v1(50.86,80.8)
  L4 w0.203: 52.24,80.54 52.34,80.45 53.66,80.45 54.14,80.92 55.76,80.92 55.81,80.87 59.26,80.87 59.81,80.31 v1(59.85,80.31)
  L4 w0.254: v1(50.86,80.8) 51.13,80.54 52.24,80.54
  BOTTOM w0.254: v1(59.85,80.31) 59.85,80.64 U4500.AU26
M_B_ODT0: length 131.5
  TOP w0.102: v1(42.61,61.3) 42.61,60.73 R4184.2
  L3 w0.102: v1(33.81,67.1) 33.81,67.01 34.36,66.47 34.82,66.47 35.11,66.17 35.3,66.17 35.41,66.07 35.41,65.91 35.52,65.79 35.72,65.79 35.81,65.88 35.81,66.07 35.91,66.17 36.12,66.17 36.22,66.07 36.22,65.91 36.33,65.79 36.54,65.79 36.62,65.88 36.62,66.07 36.73,66.17 36.93,66.17 37.03,66.07 37.03,65.91 37.15,65.79 37.35,65.79 37.44,65.88 37.44,66.07 37.54,66.17 39.36,66.17 40.71,67.51 40.91,67.51 43.09,65.34 43.23,65.34 43.38,65.48 43.38,65.63 41.17,67.83 41.17,67.98 41.32,68.12 41.46,68.12 43.96,65.61 43.96,65.49 42.9,64.43 42.9,61.59 v1(42.61,61.3) 42.79,61.12 48.53,61.12 48.81,60.84 48.81,60.7 48.35,60.24 48.35,60.09 48.49,59.95 48.64,59.95 49.1,60.41 49.24,60.41 49.38,60.27 49.38,60.12 48.92,59.66 48.92,59.52 49.07,59.37 49.21,59.37 49.67,59.83 49.82,59.83 49.96,59.69 49.96,59.55 49.5,59.08 49.5,58.94 49.64,58.8 49.79,58.8 50.25,59.26 50.39,59.26 54.31,55.34 54.31,54.51 54.98,53.83 54.98,53.07 55.64,52.41 55.64,50.81 55.91,50.54 56.31,50.54 v1(56.71,50.14)
  L4 w0.089: v1(33.75,60.56) 33.55,60.56 33.35,60.76 33.35,61.89 33.17,62.06 33.17,65.81 33.81,66.45 v1(33.81,67.1) 33.81,67.22 33.42,67.62 33.42,68.02 33.54,68.14 33.54,73.07 33.81,73.34 v3(33.81,73.72) ; v1(63.12,50.14) 62.72,49.74 61.02,49.74 60.89,49.61 60.6,49.61 60.47,49.74 60.23,49.74 60.1,49.61 59.81,49.61 59.68,49.74 59.44,49.74 59.29,49.59 59.05,49.59 58.9,49.74 58.66,49.74 58.5,49.59 58.26,49.59 58.11,49.74 57.57,49.74 57.17,50.14 v1(56.71,50.14) 56.66,50.14 56.28,49.76 55.34,49.76 54.78,50.32 50.06,50.32 v1(49.87,50.13) ; 52.44,76.05 52.54,76.05 52.82,76.33 54.13,76.33 54.67,76.87 58.81,76.87 58.95,76.74 58.95,76.57 58.81,76.43 v1(58.65,76.43)
  L4 w0.152: 52.44,76.05 46.56,76.05 43.69,73.18 43.69,72.99 43.82,72.86 44.01,72.86 46.75,75.59 46.95,75.59 47.09,75.46 47.09,75.29 43.69,71.89 43.69,67.91 42.2,66.42 42.2,61.72 v1(42.61,61.3)
  BOTTOM w0.089: v3(33.81,73.72) 33.82,73.72 33.92,73.61 33.92,73.32 33.42,72.82 33.42,71.42 33.02,71.02 U4107.K1 ; U4106.K1 33.02,57.97 33.42,58.37 33.42,59.65 33.75,59.98 v1(33.75,60.56) ; U4500.AV18 58.88,76.77 v1(58.65,76.43) ; v1(63.12,50.14) 63.59,50.14 63.98,49.76 65.28,49.76 65.69,49.35 65.86,49.35 U4104.K1 ; v1(49.87,50.13) 50.08,50.13 50.45,49.75 52.09,49.75 52.49,49.35 U4105.K1
M_B_ODT1: length 129.2
  TOP w0.102: R4183.2 44.15,62.29 43.66,62.29 v1(43.57,62.39)
  L3 w0.102: v1(34.6,67.18) 34.6,67.18 34.93,67.18 35.45,66.65 38.22,66.65 40.37,68.81 41.88,68.81 41.99,68.7 41.99,68.45 42.09,68.35 42.3,68.35 42.39,68.44 42.39,68.7 42.49,68.81 43.36,68.81 43.46,68.7 43.46,68.08 43.57,67.98 43.77,67.98 43.87,68.08 43.87,68.7 43.97,68.81 44.24,68.81 44.69,68.35 44.69,68.21 44.47,67.99 44.06,67.58 44.06,67.43 44.2,67.29 44.34,67.29 44.47,67.42 44.98,67.92 45.12,67.92 45.27,67.78 45.27,67.64 44.59,66.96 44.59,66.82 44.74,66.68 44.88,66.68 45.55,67.35 45.7,67.35 46,67.04 46,66.85 43.6,64.44 43.6,62.42 v1(43.57,62.39) 43.87,62.08 49.5,62.08 51.99,59.59 51.99,59.45 51.52,58.98 51.52,58.82 51.67,58.68 51.8,58.68 52.28,59.16 52.42,59.16 52.57,59.02 52.57,58.87 52.09,58.4 52.09,58.25 52.24,58.11 52.38,58.11 52.86,58.59 53,58.59 53.14,58.44 53.14,58.3 52.66,57.82 52.66,57.68 52.8,57.54 52.96,57.54 53.43,58.01 53.57,58.01 55.47,56.12 55.47,53.27 56.71,52.02 v1(56.71,50.93)
  L4 w0.089: v1(63.15,50.95) 62.75,50.55 61.85,50.55 61.47,50.16 57.74,50.16 56.97,50.93 v1(56.71,50.93) 56.62,50.93 56.23,50.55 55.91,50.55 55.73,50.73 50.56,50.73 50.38,50.92 v1(49.86,50.92) ; v1(34.6,73.77) 34.59,73.75 34.59,73.26 34.22,72.88 34.22,67.61 34.6,67.22 v1(34.6,67.18) 34.6,62.32 34.14,61.85 34.14,60.92 v1(34.54,60.52) ; 52.62,75.39 52.86,75.39 53.07,75.19 54.25,75.19 54.91,75.85 56.67,75.85 57.08,75.45 v3(57.08,75.45)
  L4 w0.152: v1(43.57,62.39) 43.57,62 43.4,61.84 43.15,61.84 42.86,62.13 42.86,66.15 44.35,67.64 44.35,70.32 48.67,74.65 48.67,74.8 48.54,74.93 48.32,74.93 44.66,71.28 44.48,71.28 44.35,71.42 44.35,71.61 48.13,75.39 52.62,75.39
  BOTTOM w0.089: U4500.BA16 v3(57.08,75.45) ; U4104.J1 65.86,50.15 65.48,50.53 64.07,50.53 63.66,50.95 v1(63.15,50.95) ; v1(34.54,60.52) 34.54,59.9 34.2,59.56 34.2,58.15 U4106.J1 ; U4107.J1 33.82,70.82 34.2,71.2 34.2,72.84 34.58,73.23 34.58,73.75 v1(34.6,73.77) ; v1(49.86,50.92) 50.64,50.92 51.02,50.54 52.42,50.54 U4105.J1
M_B_RAS_N: length 120.7
  TOP w0.102: v1(44.23,61.58) 44.22,61.57 R4152.2
  L3 w0.102: v1(56.07,50.93) 56.07,52.32 55.23,53.17 55.23,53.93 54.55,54.61 54.55,55.45 50.89,59.11 50.89,59.25 51.31,59.67 51.31,59.82 51.17,59.96 51.02,59.96 50.6,59.54 50.46,59.54 50.32,59.69 50.32,59.83 50.74,60.25 50.74,60.39 50.59,60.54 50.45,60.54 50.03,60.12 49.89,60.12 49.74,60.26 49.74,60.41 50.16,60.82 50.16,60.97 50.02,61.11 49.87,61.11 49.45,60.69 49.31,60.69 49.17,60.84 49.17,60.98 49.59,61.4 49.59,61.54 49.44,61.69 49.3,61.69 48.88,61.27 48.74,61.27 48.16,61.84 47.91,61.84 47.81,61.74 47.81,61.47 47.71,61.36 47.51,61.36 47.41,61.47 47.41,61.74 47.3,61.84 47.1,61.84 47,61.74 47,61.47 46.9,61.36 46.69,61.36 46.59,61.47 46.59,61.74 46.49,61.84 44.49,61.84 v1(44.23,61.58) 43.82,61.58 43.14,62.25 43.14,64.33 44.87,66.05 44.87,66.2 44.51,66.56 42.77,68.3 42.62,68.3 42.48,68.15 42.48,68.02 44.3,66.2 44.3,66.06 44.15,65.91 44.01,65.91 41.56,68.36 41.21,68.36 39.26,66.41 35.21,66.41 34.9,66.72 34.5,66.72 34.21,67.01 34.21,67.42 v1(34.6,67.81)
  L4 w0.089: v1(57.14,74.43) 56.79,74.78 56.17,74.78 56.06,74.89 54.67,74.89 54.51,74.73 52.99,74.73 ; v1(62.46,50.93) 62.46,50.93 60.1,50.93 60.01,50.84 60.01,50.68 59.92,50.59 59.72,50.59 59.62,50.69 59.62,50.85 59.54,50.93 57.26,50.93 56.87,51.32 56.46,51.32 56.08,50.93 v1(56.07,50.93) 50.65,50.93 50.26,51.32 49.66,51.32 v1(49.25,50.91) ; v1(34.6,74.38) 34.99,73.99 34.99,73.23 34.6,72.85 v1(34.6,67.81) 34.99,67.42 34.99,62.26 34.54,61.81 v3(34.54,61.21)
  L4 w0.152: 52.99,74.73 52.33,74.73 52.19,74.6 52.19,74.27 52.05,74.13 51.86,74.13 51.73,74.26 51.73,74.6 51.6,74.73 51.41,74.73 51.28,74.6 51.28,74.25 51.13,74.11 50.94,74.11 50.82,74.23 50.82,74.6 50.69,74.73 49.69,74.73 45.01,70.05 45.01,69.2 45.14,69.07 45.72,69.07 45.86,68.94 45.86,68.75 45.72,68.62 45.15,68.62 45.01,68.47 45.01,68.29 45.14,68.16 45.46,68.16 45.59,68.03 45.59,67.84 45.45,67.7 45.15,67.7 45.01,67.56 45.01,67.36 43.52,65.87 43.52,65.62 43.65,65.49 43.8,65.49 43.93,65.36 43.93,65.17 43.8,65.03 43.65,65.03 43.52,64.9 43.52,64.71 43.65,64.58 43.8,64.58 43.93,64.44 43.93,64.25 43.8,64.12 43.65,64.12 43.52,63.98 43.52,63.56 43.95,63.13 45.65,63.13 45.79,62.98 45.79,62.79 45.67,62.67 44.44,62.67 44.33,62.56 44.33,61.68 v1(44.23,61.58)
  BOTTOM w0.089: v1(62.46,50.93) 62.85,50.55 63.58,50.55 63.98,50.15 64.26,50.15 U4104.J3 ; v1(57.14,74.43) 57.2,74.43 U4500.BA14 ; U4107.J3 33.82,72.91 34.21,73.31 34.21,73.99 v1(34.6,74.38) ; v3(34.54,61.21) 34.15,60.82 34.15,59.99 33.82,59.66 U4106.J3 ; U4105.J3 51.21,50.15 50.71,50.15 50.34,50.51 49.65,50.51 v1(49.25,50.91)
M_B_WE_N: length 116.4
  TOP w0.102: R4149.2 42.98,58.39 v1(42.85,58.26)
  L3 w0.102: v1(32.24,67.17) 32.24,66.6 33.39,65.44 34.34,65.44 35.02,64.76 36.65,64.76 37.23,64.19 38.1,64.19 38.2,64.28 38.2,64.65 38.3,64.76 38.5,64.76 38.6,64.65 38.6,64.29 38.7,64.19 38.91,64.19 39.01,64.3 39.01,64.65 39.11,64.76 39.31,64.76 39.41,64.65 39.41,64.28 39.51,64.19 40.14,64.19 40.25,64.08 40.25,60.97 41.24,59.98 43.32,59.98 45.23,58.07 45.23,57.9 45.09,57.77 44.94,57.77 43.21,59.5 42.96,59.5 42.85,59.39 v1(42.85,58.26) 43.66,58.26 45.41,56.51 48.91,56.51 49.01,56.61 49.01,57.48 49.11,57.58 49.32,57.58 49.42,57.48 49.42,56.61 49.52,56.51 49.72,56.51 49.82,56.61 49.82,57.48 49.93,57.58 50.13,57.58 50.23,57.48 50.23,56.61 50.33,56.51 50.54,56.51 50.64,56.61 50.64,57.23 50.74,57.33 50.94,57.33 51.04,57.23 51.04,56.61 51.14,56.51 51.71,56.51 53.33,54.88 53.33,53.12 54.67,51.78 54.67,50.19 55.9,48.96 56.31,48.96 v1(56.71,48.56)
  L4 w0.089: v1(32.17,60.56) 32.17,60.56 31.77,60.96 31.77,61.63 31.42,61.99 31.42,66.22 32.24,67.04 v1(32.24,67.17) 32.24,67.22 31.83,67.62 31.83,68.01 32.01,68.18 32.01,73.37 32.23,73.59 v1(32.23,73.77) ; v1(49.86,48.51) 50.05,48.32 54.47,48.32 54.62,48.18 56.25,48.18 56.64,48.56 v1(56.71,48.56) 57.49,48.56 58.3,47.75 60.01,47.75 60.42,48.16 62.72,48.16 v1(63.12,48.56)
  BOTTOM w0.089: v1(49.86,48.51) 49.91,48.55 U4105.L3 ; U4107.L3 32.22,73.76 v1(32.23,73.77) ; v1(63.12,48.56) 63.14,48.55 U4104.L3 ; v1(32.17,60.56) 32.22,60.51 U4106.L3
  BOTTOM w0.102: U4500.BH10 54.02,73.02 53.87,72.87 53.39,72.87 53.34,72.82
  BOTTOM w0.124: 53.34,72.82 52.4,72.82 51.55,71.96 51.55,71.38 51.44,71.27 50.95,71.27 50.81,71.14 50.81,70.96 50.93,70.84 51.44,70.84 51.55,70.73 51.55,70.31 51.29,70.05 51.11,70.05 50.44,70.72 50.26,70.72 50.13,70.6 50.13,70.42 50.81,69.74 50.81,69.57 50.68,69.44 50.51,69.44 49.83,70.12 49.65,70.12 49.53,69.99 49.53,69.81 50.2,69.14 50.2,68.96 50.07,68.83 49.9,68.83 49.22,69.51 49.05,69.51 48.92,69.38 48.92,69.21 49.59,68.53 49.59,68.35 49.47,68.23 49.29,68.23 48.62,68.9 48.44,68.9 48.31,68.77 48.31,68.6 48.99,67.92 48.99,67.75 45.57,64.33 45.57,62.32 45.36,62.12 45.19,62.12 45.02,62.29 44.84,62.29 44.72,62.16 44.72,61.99 44.89,61.82 44.89,61.64 44.11,60.87 43.94,60.87 43.74,61.07 43.56,61.07 43.43,60.94 43.43,60.77 43.63,60.57 43.63,60.39 42.34,59.1 42.34,58.77 v1(42.85,58.26)
MEM_RST0#: length 118.3
  TOP w0.109: C4617.1 54.19,89.74 54.37,89.57 56.84,89.57 v1(57.34,89.07)
  L3 w0.135: v1(60.77,121.26) 60.77,121.88 60.08,122.57 49.97,122.57 v1(49.16,121.76)
  L4 w0.089: 58.09,93.54 58.09,92.97 58.09,92.97 58.09,91.06 58.09,91.06 58.09,89.82 v1(57.34,89.07)
  L4 w0.135: 44.53,112.06 37.71,112.06 37.08,111.44 37.08,111.1 32.84,106.86 29.21,106.86 24.81,102.46 24.18,102.46 23.6,101.88 v1(23.6,100.14) 23.27,99.81 23.27,88.4 v1(24.28,87.39) ; 44.53,112.06 45.67,110.92 45.67,109.57 46.57,108.67 46.57,108.37 47.79,107.15 47.79,106.69 48.41,106.07 48.91,106.07 49.44,105.54 49.53,105.54 58.09,96.97 58.09,93.54 ; 44.53,112.06 44.53,117.93 48.35,121.76 v1(49.16,121.76)
  BOTTOM w0.102: U4100.T2 60.75,117.02 60.75,121.23 v1(60.77,121.26)
  BOTTOM w0.109: v1(57.34,89.07) 57.55,88.86 U4500.BA42 ; v1(24.28,87.39) 25.57,86.1 U4102.T2 ; U4101.T2 47.72,118.77 48.54,119.59 48.54,120.4 49.16,121.01 v1(49.16,121.76) ; v1(23.6,100.14) 23.67,100.21 24.56,100.21 25.63,99.15 U4103.T2
MEM_RST1_N: length 128.7
  TOP w0.109: C4610.1 54.42,73.97 57.42,73.97 v1(57.9,73.49)
  L4 w0.089: v1(57.9,73.49) 58.19,73.79 58.19,74.01 58.54,74.36 58.98,74.36 59.28,74.06 59.28,71.92 59.6,71.6 61.24,71.6 61.69,71.14 61.69,68.97 61.89,68.78
  L4 w0.135: v1(23.56,72.68) 23.56,72.67 23.36,72.48 23.36,67.15 23.47,67.04 23.47,64.29 23.36,64.19 23.36,60.77 v1(24.28,59.86) 24.28,59.16 26.9,56.54 28.37,56.54 34.67,50.24 34.67,47.55 37.7,44.53 43.84,44.53 46.22,42.14 46.61,42.14 48.72,40.02 50.88,40.02 v1(50.95,40.09) 51.31,39.73 62.94,39.73 63.62,40.41 63.62,40.45 v1(63.77,40.61) 66.86,43.69 66.86,49.11 66.06,49.91 65.13,49.91 62.61,52.43 62.61,56.41 62.33,56.69 62.33,68.05 62,68.37 62,68.66 61.89,68.78
  BOTTOM w0.102: U4107.T2 28.17,71.57 24.67,71.57 v1(23.56,72.68)
  BOTTOM w0.109: U4500.BA12 57.55,73.84 v1(57.9,73.49) ; U4106.T2 26.93,58.57 26.86,58.63 25.5,58.63 v1(24.28,59.86) ; v1(50.95,40.09) 52.09,41.24 52.09,44.47 U4105.T2 ; U4104.T2 65.12,44.5 65.12,41.83 63.89,40.61 v1(63.77,40.61)
MIC: length 12.7
  BOTTOM w0.254: R602.1 14.53,86.93 15.38,87.78 C605.1 v2(15.38,89.53) 15.38,91.52 14.35,92.56 9.62,92.56 JACK600.3
MIC2_REF: length 39.5
  TOP w0.254: U500.29 7.78,53.59 7.3,54.08 v1(7.13,54.08)
  L3 w0.254: v1(7.58,82.96) 7.58,80.15 7.13,79.7 v1(7.13,54.08)
  BOTTOM w0.254: v1(7.58,82.96) R601.2 12.35,83.79 v2(13.44,84.88) R600.2
MIC_IN_CLK: length 165.8
  TOP w0.109: v1(82.98,141.1) 82.18,141.1 79.73,138.64 78.12,138.64 77.24,139.51 77.21,139.55 77.21,142.86 75.83,144.23 75.79,144.23 75.5,144.52 65.28,144.52 60.72,139.96 50.44,139.96 49.99,139.5 49.22,139.5 46.79,137.07 39.99,137.07 39.64,137.41 37.13,137.41 35.25,135.53 35.25,127.96 35.39,127.82 35.39,127.19 36.63,125.94 36.63,119.9 20.31,103.58 20.31,102.68 20.31,102.68 20.31,91.59 20.54,91.36 20.54,56.12 20.76,55.89 20.76,51.12 19.71,50.07 C18.1 18.02,50.07 R512.1
  BOTTOM w0.109: v1(82.98,141.1) 82.98,141.44 82.53,141.89 D3000.3 82.53,143.14 81.51,144.17 v2(81.51,145.57) 81.51,147.29 79.72,149.07 79.72,151.31 80.03,151.61 CN3000.26
MIC_IN_CLK_R: length 2.6
  TOP w0.109: U500.3 14.68,51.59 14.77,51.68 15.37,51.68 15.54,51.51 15.54,51.51 v2(15.88,51.17) 16.48,50.57 R512.2
MIC_IN_DATA: length 158.3
  TOP w0.109: U500.2 15.15,51.19 16.76,49.58 19.91,49.58 21.25,50.92 21.25,56.14 21.03,56.36 21.03,91.57 20.8,91.8 20.8,102.89 20.8,102.89 20.8,103.38 37.12,119.7 37.12,126.15 35.88,127.39 35.88,128.02 35.74,128.16 35.74,135.33 37.33,136.92 39.44,136.92 39.79,136.58 46.99,136.58 49.42,139.01 50.19,139.01 50.64,139.47 60.92,139.47 63.14,141.68 63.73,141.68 64.63,142.59 64.63,143.18 65.49,144.03 75.3,144.03 76.72,142.61 76.72,138.7 77.77,137.64 79.42,137.64 81.02,139.24 v2(82.72,139.24) 83.54,139.24 v1(83.64,139.14)
  BOTTOM w0.109: v1(83.64,139.14) R3011.1
MIC_IN_DATA_R: length 17.2
  BOTTOM w0.109: D3000.1 80.63,142.04 81.2,141.47 81.85,141.47 82.66,140.66 R3011.2 83.44,140.86 83.47,140.89 83.47,141.65 83.31,141.81 83.31,143.05 83.02,143.34 83.02,143.35 82.14,144.23 v2(82.14,146.68) 82.14,147.34 80.21,149.28 80.21,151.1 80.53,151.42 CN3000.27
MMC1_CLK: length 68
  TOP w0.109: R3955.2 103.48,42.28 102.11,43.64 v2(100.21,43.64) 99.15,43.64 v1(98.73,44.07)
  L3 w0.135: v1(72.43,71.93) 72.78,72.28 73.73,72.28 74.96,71.06 74.96,69.64 77.78,66.82 77.78,64.29 75.65,62.16 75.65,54.98 76.16,54.47 76.16,52.9 74.4,51.14 74.4,47.84 74.76,47.49 74.76,42.52 77.54,39.73 92.03,39.73 96.36,44.07 v1(98.73,44.07)
  BOTTOM w0.109: U4500.M7 72.32,71.93 v1(72.43,71.93)
MMC1_CLK_R: length 7.2
  TOP w0.109: v1(103.46,35.31) 103.61,35.31 103.93,35.64 103.93,35.79 103.94,35.79 103.94,36.19 103.93,36.2 v2(103.93,37.62) 103.93,38.5 103.41,39.03 C3960.1 103.41,41.31 R3955.1
  BOTTOM w0.109: U3950.M6 103.86,35.71 v1(103.46,35.31)
MMC1_CMD: length 56.3
  TOP w0.109: v1(71.43,70.5) 71.02,70.1 71.02,69.58 71.7,68.9 71.7,66.24 71.59,66.12 71.59,63.08 71.85,62.82 71.85,40.73 76.27,36.31 91.06,36.31 91.46,35.91 v2(93.25,35.91) 93.39,35.91 R3962.1
  BOTTOM w0.109: v1(71.43,70.5) 71.12,70.81 U4500.P6
MMC1_CMD_R: length 13.9
  TOP w0.109: R3962.2 96.01,37.13 v1(96.13,37.02)
  L4 w0.135: v1(96.13,37.02) 95.39,36.28 95.39,34.29 95.72,33.96 102.35,33.96 103.02,34.63 103.02,35.56 v3(103.45,35.99)
  BOTTOM w0.109: v3(103.45,35.99) 103.66,36.2 103.81,36.2 103.82,36.21 U3950.M5
MMC1_D0: length 56.1
  TOP w0.109: R4665.1 94.43,40.79 v2(93.51,39.88) 92.41,38.78 92.41,38.31 91.36,37.25 76.66,37.25 72.84,41.07 72.84,52.76 73.58,53.5 73.58,62.54 72.53,63.59 72.53,68.98 72.8,69.24 72.8,69.93 v1(72.42,70.31)
  BOTTOM w0.109: U4500.M6 v1(72.42,70.31)
MMC1_D0_R: length 9
  TOP w0.109: v3(96.78,42.11) R4665.2
  BOTTOM w0.076: U3950.A3 98.37,37.27 97.8,37.27 97.58,37.49
  BOTTOM w0.109: 97.58,37.49 97.56,37.52 96.74,37.52 96.38,37.87 96.38,38.44 97.28,39.33 97.28,41.61 v3(96.78,42.11)
MMC1_D1: length 54.4
  TOP w0.109: R4666.1 94.36,39.88 v2(92.97,38.49) 91.5,37.02 76.57,37.02 72.56,41.02 72.56,63.22 72.3,63.49 72.3,65.99 72.33,66.02 72.33,69.62 v1(72.4,69.69)
  BOTTOM w0.109: U4500.M4 71.95,70.14 v1(72.4,69.69)
MMC1_D1_R: length 9
  TOP w0.109: v3(96.73,40.49) 96.12,39.88 R4666.2
  BOTTOM w0.076: U3950.A4 98.23,36.71 98.09,36.84 97.58,36.84
  BOTTOM w0.109: v3(96.73,40.49) 96.73,39.16 95.58,38.01 95.58,36.8 96,36.38 96.76,36.38 97.22,36.84 97.58,36.84
MMC1_D2: length 56.9
  TOP w0.089: 71.42,71.76 72.01,71.17 72.01,69.48 72.13,69.35
  TOP w0.109: 72.13,69.35 72.13,66.1 72.06,66.03 72.06,63.39 72.32,63.13 72.32,40.92 76.47,36.78 92.13,36.78 v2(92.52,37.17) 94.31,38.96 R4667.1 ; 71.42,71.76 v1(71.4,71.77)
  BOTTOM w0.089: v1(71.4,71.77) 70.94,72.24 U4500.P9
MMC1_D2_R: length 9.1
  TOP w0.109: R4667.2 95.9,38.96 v3(96.24,39.3)
  BOTTOM w0.076: U3950.A5 98.13,36.21 97.98,36.36 97.58,36.36
  BOTTOM w0.109: 97.58,36.36 97.48,36.36 96.25,35.12 95.76,35.12 95.06,35.83 95.06,38.12 v3(96.24,39.3)
MMC1_D3: length 56.2
  TOP w0.089: 71.9,69.24 71.83,69.31 71.83,70.71 v1(71.41,71.13)
  TOP w0.109: 71.9,69.24 71.9,66.16 71.82,66.08 71.82,63.29 72.09,63.03 72.09,40.83 76.37,36.55 93.11,36.55 v2(93.84,37.27) R4668.1
  BOTTOM w0.089: v1(71.41,71.13) 71.02,71.52 U4500.P7
MMC1_D3_R: length 3.9
  TOP w0.109: v3(96.87,38.19) 95.61,38.19 R4668.2
  BOTTOM w0.076: U3950.B2 98.88,37.71 98.64,37.46 98.02,37.46 97.77,37.72
  BOTTOM w0.109: 97.77,37.72 97.29,38.19 v3(96.87,38.19)
MMC1_D4: length 57
  TOP w0.109: v1(70.43,70.52) 69.96,70.04 69.96,69.46 70.47,68.95 70.47,67.35 71.15,66.67 71.15,63.19 71.62,62.72 71.62,40.63 76.17,36.07 90.74,36.07 91.48,35.34 v2(92,35.34) 93.74,35.34 R4669.1
  BOTTOM w0.109: U4500.T6 69.95,70.76 70.2,70.52 v1(70.43,70.52)
MMC1_D4_R: length 4
  TOP w0.109: v1(96.77,37.01) 95.98,36.22 R4669.2
  BOTTOM w0.076: 97.58,37.08 98.18,37.08 98.3,36.96 98.66,36.96 98.91,37.21 U3950.B3
  BOTTOM w0.109: 97.58,37.08 96.84,37.08 v1(96.77,37.01)
MMC1_D5: length 58.3
  TOP w0.109: v1(70.47,71.18) 69.76,70.47 69.76,69.38 70.27,68.87 70.27,67.19 70.91,66.55 70.91,63.09 71.38,62.62 71.38,40.53 76.08,35.84 90.33,35.84 91.57,34.6 v2(93.31,34.6) 93.91,34.6 R4672.1
  BOTTOM w0.109: U4500.T7 69.95,71.42 70.2,71.18 v1(70.47,71.18)
MMC1_D5_R: length 4.2
  TOP w0.109: v3(96.25,35.71) 95.84,35.31 R4672.2
  BOTTOM w0.076: U3950.B4 98.79,36.71 98.54,36.46 98.17,36.46 98.03,36.6 97.58,36.6
  BOTTOM w0.109: v3(96.25,35.71) 96.44,35.71 97.33,36.6 97.58,36.6
MMC1_D6: length 60.1
  TOP w0.109: v1(70.5,72.53) 70.06,72.1 70.06,71.08 69.56,70.58 69.56,69.3 70.07,68.79 70.07,67.04 70.68,66.43 70.68,62.99 71.14,62.53 71.14,40.43 75.98,35.6 90.1,35.6 91.68,34.03 v2(92.03,34.03) 94.25,34.03 R4673.1
  BOTTOM w0.109: v1(70.5,72.53) 70.46,72.53 70.05,72.95 U4500.T10
MMC1_D6_R: length 4.8
  TOP w0.109: R4673.2 v3(96.29,34.39)
  BOTTOM w0.076: U3950.B5 98.9,36.21 98.65,35.96 98.09,35.96 97.93,36.12 97.58,36.12
  BOTTOM w0.109: 97.58,36.12 97.18,35.72 97.18,34.99 96.58,34.39 v3(96.29,34.39)
MMC1_D7: length 61.3
  TOP w0.109: v1(70.44,73.35) 69.84,72.75 69.84,71.19 69.36,70.72 69.36,69.22 69.87,68.71 69.87,66.88 70.44,66.31 70.44,62.9 70.91,62.43 70.91,40.34 75.88,35.36 89.59,35.36 v2(90.32,34.64) 91.48,33.48 R4674.1
  BOTTOM w0.109: U4500.T12 69.95,73.6 70.2,73.35 v1(70.44,73.35)
MMC1_D7_R: length 5.4
  TOP w0.109: R4674.2 96.03,33.48 v3(96.62,32.89)
  BOTTOM w0.076: U3950.B6 98.85,35.71 98.6,35.46 98.25,35.46 98.2,35.41
  BOTTOM w0.109: v3(96.62,32.89) 97.37,33.64 97.37,34.57 98.2,35.41
MMC1_RCLK: length 1.4
  TOP w0.109: TP4531.1 70.14,73.71 v1(70.43,74.01)
  BOTTOM w0.109: v1(70.43,74.01) 70.31,74.01 U4500.T13
MMC1_RST#: length 85.4
  TOP w0.109: v1(104.12,39) 105.24,39 106.11,38.13 106.11,31.77 105,30.66 96.53,30.66 v2(95.42,31.76) 94.9,32.28 91.19,32.28 88.57,34.9 75.36,34.9 70.43,39.83 70.43,60.17 69.8,60.81 v1(69.49,60.81) ; v1(103.32,36.68) 103.32,38.33 102.63,39.02 C3958.1 v1(102.63,40.77) 102.63,41.31 R3963.2
  BOTTOM w0.109: v1(69.49,60.81) 68.91,60.81 68.17,60.07 66.52,60.07 65.1,61.49 65.1,62.85 R4540.2 ; v1(102.63,40.77) 102.63,40.49 v1(104.12,39) ; U3950.K5 102.93,36.29 v1(103.32,36.68)
MOIC_RSMRST: length 92
  TOP w0.102: R4814.2 82.34,75.08 82.34,73.43 v3(83.49,72.29)
  L4 w0.102: v1(109.37,110.24) 108.79,109.65 108.79,106.64 108.25,106.1 108.25,105.21 106.45,103.4 106.45,101.51 106.45,101.51 106.45,100.84 105.6,99.99 105.6,98.15 105.6,98.15 105.6,97.81 103.92,96.13 103.92,70.55 103.25,69.88 103.25,65.79 100.01,62.56 97.76,62.56 90.04,70.28 90.04,72.01 89.43,72.62 83.82,72.62 v3(83.49,72.29)
  BOTTOM w0.102: v1(109.37,110.24) 109.09,109.96 R60001.1 106.85,110.37 D60000.3 106.4,113.97 101.44,113.97 101.19,114.22 101.19,114.48 100.92,114.74 U60600.13
MUX_GPIO_SUS1: length 4.3
  BOTTOM w0.102: R4551.1 67.9,96.96 v2(67.9,96.36) 67.9,96.16 66.08,94.34 U4500.AD52
MUX_GPIO_SUS2: length 16.5
  TOP w0.127: v1(62.62,92.1) 63.09,92.56 v2(63.09,93.27) 63.09,99.3 67.56,103.77 R4547.2
  BOTTOM w0.102: U4500.AH50 63.97,92.41 63.65,92.1 v1(62.62,92.1)
MUX_GPIO_SUS3: length 1.8
  TOP w0.127: v3(63.72,91.38) 64.38,92.04 R4693.1
  BOTTOM w0.102: v3(63.72,91.38) 64.08,91.74 U4500.AH48
MUX_GPIO_SUS8: length 15.6
  TOP w0.102: R4554.1 70.73,103.76 v1(71.19,103.76) 71.68,103.76 R4851.1
  BOTTOM w0.102: U4500.AF51 65.11,93.29 64.81,93.58 64.81,93.83 64.9,93.91 64.9,97.22 67.87,100.19 67.87,100.78 70.85,103.76 v1(71.19,103.76)
MUX_GPIO_SUS9: length 14
  TOP w0.102: R4849.2 71.84,103.02 v3(71.19,103.02) 70.58,103.02 R4553.1
  BOTTOM w0.102: U4500.AF52 65.11,97.03 68.11,100.04 68.11,100.62 70.52,103.02 v3(71.19,103.02)
MUX_GPIO_SUS11: length 3.7
  TOP w0.102: v3(67.66,95.02) 68.24,95.6 R4533.2
  BOTTOM w0.102: v3(67.66,95.02) 67.03,95.02 66.28,94.28 66.28,93.91 66.56,93.63 U4500.AC51
NB671LGQ_LP#: length 20.3
  TOP w0.102: v1(97.48,140.74) 97.48,143.21 96.23,144.46 92.74,144.46 92.17,143.89 89.35,143.89 88.13,142.67 v3(88.13,142.26)
  L4 w0.102: v1(88.26,139.37) 87.85,139.78 87.85,141.98 v3(88.13,142.26)
  BOTTOM w0.102: R6198.2 88.63,139.37 v1(88.26,139.37) ; U6150.3 96.4,140.86 96.51,140.74 v1(97.48,140.74)
PCH_SPI_CLK: length 38.5
  BOTTOM w0.109: R4631.1 71.1,40.79 v2(70.29,41.6) 69.84,42.04 69.84,46.32 69.95,46.43 71.21,46.43 71.32,46.54 71.32,46.76 71.21,46.87 69.95,46.87 69.84,46.98 69.84,47.19 69.95,47.3 71.79,47.3 71.9,47.41 71.9,47.63 71.79,47.74 69.95,47.74 69.84,47.85 69.84,57.53 71.51,59.2 71.51,64.28 69.67,66.12 68.78,66.12 68.26,66.64 68.26,68.27 68.22,68.3 68.22,68.62 68.35,68.75 68.35,69.05 U4500.W3
PCH_SPI_CS0#: length 38.3
  BOTTOM w0.102: 68.08,69.2 68.98,70.09 U4500.V4
  BOTTOM w0.109: R4807.1 v2(70.53,39.57) 70.29,39.57 70.18,39.68 70.18,40.81 70.07,40.92 69.86,40.92 69.75,40.81 69.75,39.68 69.64,39.57 69.33,39.57 69.22,39.68 69.22,57.79 69.58,58.15 70.89,59.45 70.89,64.41 70.08,65.23 68.97,65.23 67.84,66.36 67.84,68.6 67.72,68.72 67.72,68.97 67.95,69.2 68.08,69.2
PCH_SPI_IO2: length 28.9
  BOTTOM w0.109: U4500.U1 69.48,67.5 72.32,64.66 72.32,63.02 72.83,62.51 72.83,61.07 75.28,58.62 75.28,55.5 73.8,54.02 73.8,51.52 73.96,51.36 73.96,49.83 74.53,49.26 75.46,49.26 75.57,49.15 75.57,48.63 75.67,48.52 75.89,48.52 76,48.63 76,49.15 76.11,49.26 76.4,49.26 76.62,49.04 76.62,46.8 R4805.2
PCH_SPI_IO3: length 38.2
  BOTTOM w0.109: U4500.U3 69.44,69.16 69.44,68.87 69.19,68.62 69.19,67.5 72.12,64.57 72.12,62.94 72.6,62.47 72.6,58.68 72.7,58.57 73.03,58.57 73.14,58.68 73.14,59.9 73.25,60.01 73.47,60.01 73.58,59.9 73.58,58.68 73.69,58.57 73.9,58.57 74.01,58.68 74.01,59.08 74.12,59.19 74.34,59.19 74.45,59.08 74.45,58.68 74.56,58.57 74.93,58.57 75.04,58.47 75.04,58.26 74.93,58.15 72.29,58.15 72.18,58.04 72.18,57.82 72.29,57.71 74.93,57.71 75.04,57.6 75.04,57.38 74.93,57.27 73.73,57.27 73.62,57.16 73.62,56.95 73.73,56.84 74.93,56.84 75.04,56.73 75.04,56.51 74.93,56.4 73.73,56.4 73.62,56.29 73.62,56.07 73.73,55.96 74.93,55.96 75.04,55.85 75.04,55.6 74.83,55.39 74.67,55.39 74.54,55.52 74.39,55.52 74.23,55.37 74.23,55.21 74.37,55.08 74.37,54.93 74.21,54.77 74.06,54.77 73.39,55.44 73.23,55.44 73.08,55.29 73.08,55.13 73.75,54.46 73.75,54.31 73.5,54.07 73.5,53.89 73.4,53.79 73.33,53.79 73.23,53.68 73.23,53.46 73.33,53.35 73.4,53.35 73.5,53.24 73.5,52.9 R4806.2
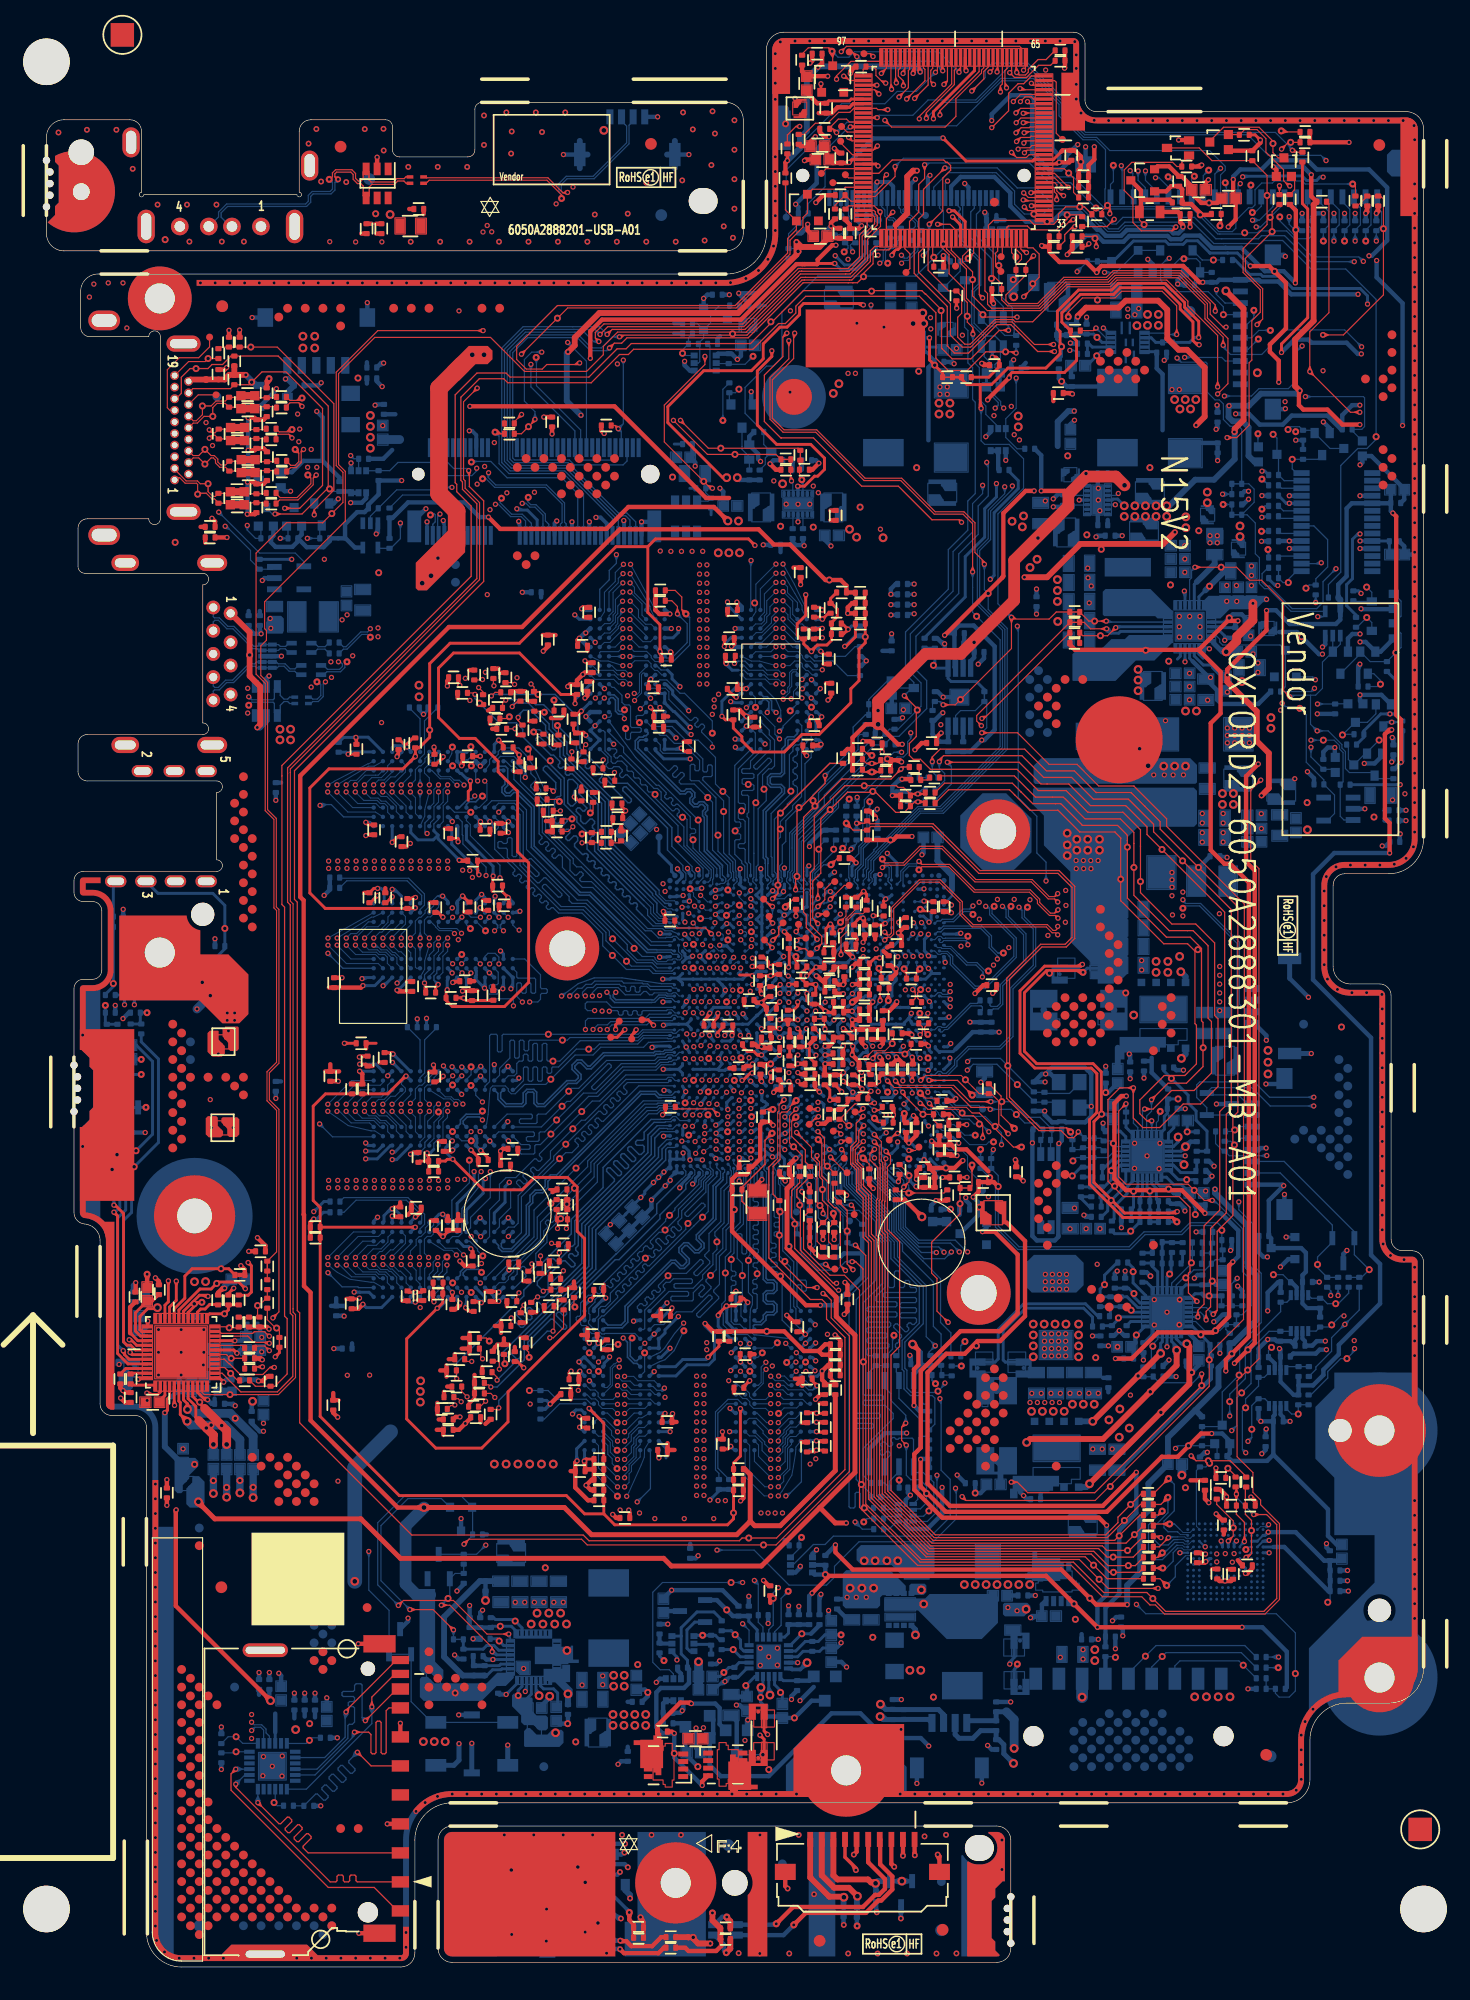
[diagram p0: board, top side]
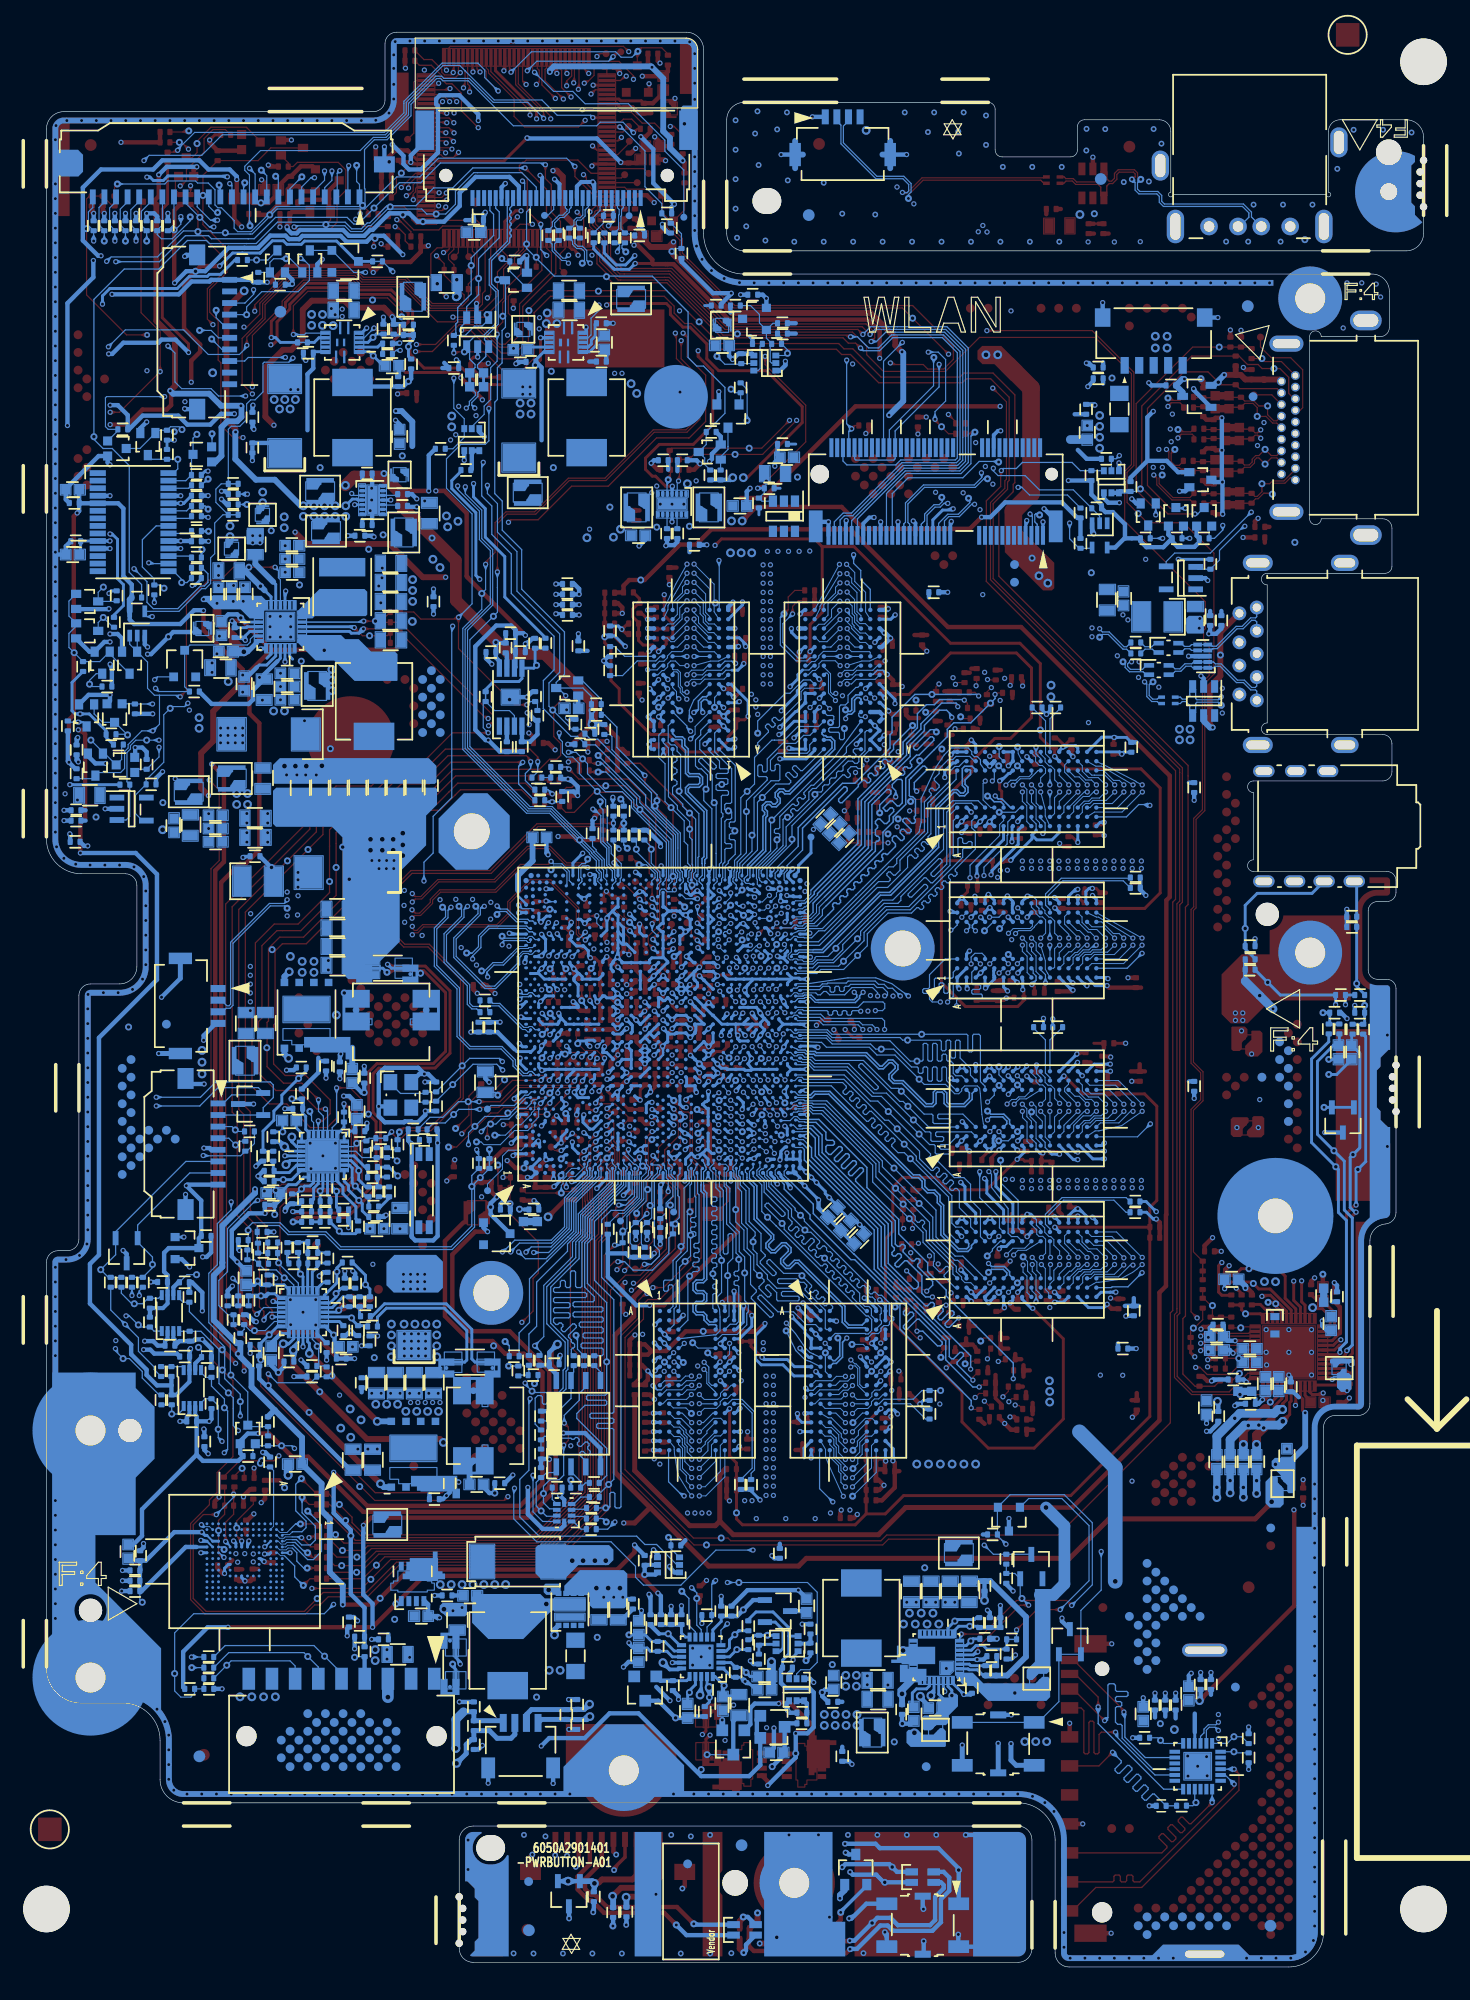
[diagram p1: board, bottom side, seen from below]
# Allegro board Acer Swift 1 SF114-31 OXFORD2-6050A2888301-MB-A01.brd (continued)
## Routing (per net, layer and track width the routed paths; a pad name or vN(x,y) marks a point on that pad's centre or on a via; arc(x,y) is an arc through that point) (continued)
PCH_SPI_SI: length 38.3
  BOTTOM w0.109: U4500.V2 69,68.84 69,67.42 71.92,64.49 71.92,62.86 72.36,62.42 72.36,58.62 71.53,57.79 71.53,57.46 71.64,57.35 73.25,57.35 73.35,57.24 73.35,57.02 73.25,56.91 70.89,56.91 70.78,56.8 70.78,56.58 70.89,56.47 73.25,56.47 73.35,56.36 73.35,56.15 73.25,56.04 70.87,56.04 70.76,55.93 70.76,55.71 70.87,55.6 72.71,55.6 72.82,55.49 72.82,55.29 72.69,55.16 70.9,55.16 70.76,55.02 70.76,54.78 70.87,54.67 72.39,54.67 72.5,54.56 72.5,54.34 72.39,54.23 70.87,54.23 70.76,54.12 70.76,53.9 70.87,53.79 72.55,53.79 72.66,53.68 72.66,53.47 72.55,53.36 70.87,53.36 70.76,53.25 70.76,52.81 70.87,52.7 R4633.2
PCH_SPI_SO: length 36.7
  BOTTOM w0.109: R4648.2 70.46,42.37 70.46,44.71 73.03,47.29 73.03,47.72 72.32,48.42 70.57,48.42 70.46,48.53 70.46,48.75 70.57,48.86 72.08,48.86 72.19,48.97 72.19,49.19 72.08,49.3 70.57,49.3 70.46,49.41 v2(70.46,52.17) 70.46,57.27 72.12,58.94 72.12,62.38 71.73,62.78 71.73,64.4 68.8,67.32 68.8,68.61 68.7,68.72 68.7,68.97 68.99,69.27 U4500.V3
PCI_3S_CLKRUN#: length 210.1
  TOP w0.109: U301.8 74.84,146.01 77.7,143.15 77.7,139.76 78.32,139.13 79.53,139.13 81.98,141.59 83.18,141.59 85.5,139.27 v1(86.94,139.27)
  L3 w0.135: v1(86.94,139.27) 87.29,139.61 87.29,142.73 88.2,143.64 96.02,143.64 96.76,142.89 98.07,142.89 100.52,140.45 101.98,140.45 103,139.43 105.44,139.43 105.93,139.92 106.79,139.92 107.2,139.5 107.2,138.08 109,136.28 109,131.45 111.01,129.44 111.01,122.88 111.01,121.34 111.22,121.13 v1(111.22,120.55) 111.22,119.69 110.99,119.45 110.99,108.3 110.07,107.38 109.44,107.38 108.53,106.48 108.53,104.39 105.53,101.39 105.53,97.95 103.87,96.29 103.87,82.4 106.44,79.84 106.44,73.27 107.79,71.93 107.79,63.08 105.28,60.58 105.28,60.31 105.28,58.17 103.91,56.8 103.91,52.89 100.21,49.19 94.33,49.19 93.49,50.04 83.75,50.04 82.63,51.16 78.31,51.16 v1(77.49,50.34)
  BOTTOM w0.102: 73.12,62.28 73.12,62.5 72.52,63.1 72.52,64.77 69.76,67.52 69.76,68.63 69.67,68.73 69.67,68.99 69.96,69.28 U4500.T3
  BOTTOM w0.109: 73.12,62.28 73.12,61.15 75.62,58.65 75.62,55.46 74.04,53.87 74.04,51.62 74.22,51.44 74.22,49.91 74.6,49.53 76.78,49.53 v2(76.89,49.64) 77.49,50.24 v1(77.49,50.34) ; v1(111.22,120.55) 110.11,119.43 110.11,117.65 109.56,117.1 107.44,117.1 105.49,119.06 105.15,119.06 104.85,119.36 104.85,120.12 105.36,120.62 R3510.1
PCI_3S_SERIRQ: length 318.1
  TOP w0.102: v1(19.53,55.96) 20.05,56.48 20.05,73.93 19.22,74.76 19.22,77.09 20.05,77.92 20.05,91.16 19.82,91.39 19.82,99.02 19.07,99.77 19.07,110.75 18.49,111.34 18.49,113.89 18.97,114.38 18.97,115.22 18.82,115.38 18.82,117.7 25.78,124.66 25.78,128.94 25.19,129.52 25.19,137.36 28.32,140.49 38.3,140.49 41.23,137.55 46.58,137.55 48.03,139 48.03,139.72 49.26,140.94 60.35,140.94 65.07,145.67 65.46,145.67 69.36,145.66 70.83,147.13 70.83,148.95 71.94,150.06 71.94,151.28 v1(71.91,151.31) 71.38,151.83 U301.125
  TOP w0.109: D7503.2 69.2,151.83 U301.125
  L3 w0.102: v1(76.67,53.56) 76.67,53.44 76.67,52.69 75.13,51.16 75.13,49.36 75.96,48.53 75.96,42.33 76.53,41.76 77.92,41.76 v1(78.41,41.27) ; v3(104.49,132.18) 104.49,136.02 106.96,138.49 106.96,139.4 106.69,139.67 106.03,139.67 105.54,139.19 101.27,139.19 99.35,141.1 99.07,141.1 97.68,142.49 96.82,142.49 95.92,143.39 88.37,143.39 87.59,142.61 87.59,138.92 87.36,138.68 86.72,138.68 85.85,139.56 85.85,141.81 84.25,143.41 82.99,143.41 82.75,143.65 82.75,144.62 77.79,149.57 75.9,149.57 73.63,151.84 72.44,151.84 v1(71.91,151.31) ; v1(57.83,35.94) 32.7,35.94 22.89,45.74 22.89,53.86 20.8,55.96 v1(19.53,55.96)
  BOTTOM w0.102: Q3500.2 104.49,131.09 v3(104.49,132.18) ; v1(57.83,35.94) 61.03,35.94 64.06,32.92 67.28,32.92 67.97,33.6 67.97,34.54 70.08,36.65 76.49,36.65 78.47,38.64 78.47,41.21 v1(78.41,41.27) ; U4500.T2 69.96,67.59 72.71,64.84 72.71,63.18 73.4,62.49 73.4,61.24 75.88,58.76 75.88,54.34 v1(76.67,53.56) 76.11,53 76.11,52.86 R4660.2
PCI_SERR#: length 5.9
  BOTTOM w0.089: R4534.1 69.41,64.97 68.96,64.97 67.64,66.28 67.64,68.35 U4500.AA1
PCIE_OBSN: length 1.7
  TOP w0.107: v1(75.36,80.37) 75.55,80.57 75.55,81.04 R4522.1
  BOTTOM w0.107: v1(75.36,80.37) 75.36,80.39 U4500.F26
PCIE_OBSP: length 1.8
  TOP w0.107: v3(76.02,80.4) 75.76,80.66 75.76,81.02 R4522.2
  BOTTOM w0.107: v3(76.02,80.4) 76.01,80.41 75.99,80.41 U4500.D26
PCIE_WAKE#: length 191.4
  TOP w0.102: v1(100.81,142.75) 100.81,143.29 97.85,146.24 92,146.24 91.43,145.67 87.75,145.67 85.49,143.41 82.99,143.41 82.75,143.65 82.75,144.14 84.47,145.87 R325.1 84.47,146.86 v1(85.14,147.52) ; v1(40.98,133.84) 40.35,133.21 R1306.2
  L4 w0.102: v1(100.81,142.75) 101.06,142.5 101.06,141.8 101.29,141.57 101.29,140.98 101.7,140.56 102.56,140.56 103.86,139.27 105.16,139.27 106.96,137.47 106.96,135.78 107.34,135.4 107.34,134.15 107.14,133.95 107.14,131.38 107.81,130.71 107.81,120.13 108.1,119.83 108.1,119.66 108.1,112.32 108.51,111.91 108.51,106.64 108.05,106.19 108.05,105.29 106.25,103.49 106.25,101.43 106.25,100.92 105.4,100.07 105.4,98.06 105.4,97.89 103.72,96.21 103.72,70.63 103.04,69.96 103.04,66.17 v1(102.84,65.96) ; v1(40.98,133.84) 40.98,134.4 45.85,139.27 45.85,140.36 47.3,141.82 48.96,141.82 49.59,141.82 53.7,137.7 65.24,137.7 66.95,139.41 66.95,139.58 66.95,143.18 69.82,146.05 74.52,146.05 75.05,146.58 77.37,146.58 78.49,147.7 83.97,147.7 84.27,147.4 84.96,147.4 85.09,147.52 v1(85.14,147.52)
  BOTTOM w0.102: R4637.2 R4652.1 101.29,46.59 Q4513.3 101.41,49.57 v2(102.87,51.03) 102.92,51.08 102.92,53.69 104.77,55.55 104.77,59.8 104.04,60.54 104.04,64.09 102.84,65.28 v1(102.84,65.96)
PCIE_WLAN_RX_DN: length 96.9
  L3 w0.109: v1(75.35,78.33) 75.8,78.79 76.23,78.79 78.45,81 78.45,86.39 80.05,87.99 80.05,89.27 79.21,90.12 79.21,93.41 79.57,93.76 79.57,100.09 81.09,101.61 81.09,112.74 77.57,116.26 77.57,120.07 74.08,123.55 74.08,124.91 67.55,131.44 64.42,131.44 63.6,132.26 60.28,132.26 60.03,132 50.71,132 48.67,129.97 43.8,129.97 41.05,127.22 41.05,126.83 41.21,126.68 41.53,126.68 v3(41.55,126.7)
  BOTTOM w0.107: CN1300.43 43.32,124.38 43.03,124.67 43.03,125.25 42.22,126.06 41.78,126.06 41.51,126.33 41.51,126.65 v3(41.55,126.7) ; U4500.F22 75.05,78.63 v1(75.35,78.33)
PCIE_WLAN_RX_DP: length 96.9
  L3 w0.109: v1(41.04,126.18) 41.04,126.55 40.84,126.75 40.84,127.31 43.71,130.18 48.58,130.18 50.62,132.21 59.94,132.21 60.19,132.47 63.69,132.47 64.51,131.65 67.64,131.65 74.29,125 74.29,123.64 77.78,120.16 77.78,116.35 81.3,112.83 81.3,101.52 79.78,100 79.78,93.67 79.42,93.32 79.42,90.2 80.26,89.36 80.26,87.9 78.66,86.3 78.66,80.91 76.11,78.37 v3(76.04,78.37)
  BOTTOM w0.107: v1(41.04,126.18) 41.37,126.18 41.69,125.86 42.14,125.86 42.82,125.17 CN1300.41 ; U4500.D22 v3(76.04,78.37)
PCIE_WLAN_TX_C_DN: length 99.6
  L3 w0.109: v3(39.24,126.62) 39.13,126.51 38.84,126.51 38.6,126.75 38.6,127.05 42.93,131.37 46.36,131.37 48.73,133.75 64.8,133.75 65.7,132.85 68.15,132.85 75.84,125.15 75.84,124.49 79.12,121.21 79.12,116.79 82.52,113.39 82.52,101.83 84.89,99.47 84.89,95.65 82.81,93.58 82.81,91.61 82.64,91.44 v1(82.46,91.44)
  BOTTOM w0.107: C4505.2 81.38,82.91 81.48,82.81 82,82.81 82.27,83.08 82.27,84.69 84.27,86.69 84.27,88.99 82.76,90.5 82.76,91.18 82.5,91.44 v1(82.46,91.44) ; CN1300.37 41.83,124.46 41.04,125.25 40.12,125.25 39.13,126.23 39.13,126.51 v3(39.24,126.62)
PCIE_WLAN_TX_C_DP: length 99.6
  L3 w0.109: v1(38.72,126.1) 38.72,126.33 38.39,126.67 38.39,127.13 42.84,131.58 46.27,131.58 48.64,133.96 64.89,133.96 65.79,133.06 68.24,133.06 76.05,125.24 76.05,124.58 79.33,121.3 79.33,116.88 82.73,113.48 82.73,101.92 85.1,99.56 85.1,95.57 83.02,93.49 83.02,91.61 v3(83.19,91.44)
  BOTTOM w0.107: v1(38.72,126.1) 38.97,126.1 40.04,125.04 40.95,125.04 41.32,124.66 CN1300.35 ; v3(83.19,91.44) 82.97,91.22 82.97,90.58 84.48,89.07 84.48,86.6 82.48,84.6 82.48,82.99 82.08,82.6 81.66,82.6 C4504.2
PCIE_WLAN_TX_DN: length 5.3
  BOTTOM w0.089: U4500.C26 76.62,80.8 76.73,80.91 76.9,81.08 77.14,81.08 77.21,81 77.61,81 77.69,81.08
  BOTTOM w0.107: C4505.1 80.27,83.07 79.67,83.07 77.69,81.08
PCIE_WLAN_TX_DP: length 5.3
  BOTTOM w0.089: 77.83,80.94 77.72,80.82 77.46,80.82 77.25,80.61 77.11,80.61 77.02,80.7 U4500.B26
  BOTTOM w0.107: C4504.1 80.73,82.51 80.73,82.75 80.61,82.86 79.76,82.86 77.83,80.94
PCSPKR: length 96.1
  TOP w0.254: v1(19.73,52.6) 20.09,52.96 R521.2
  L3 w0.254: v1(19.73,52.6) 21.76,50.57 21.76,45.26 v1(25.14,41.88) ; v3(74.38,69.67) 74.38,69.4 77.2,66.58 77.2,64.53 75.07,62.4 75.07,54.58 75.59,54.06 75.59,53.14 73.56,51.11 v1(73.56,44.93)
  L4 w0.254: v1(73.56,44.93) 73.56,43.43 70.23,40.11 65.54,40.11 65.07,39.64 65.07,39.64 63.5,38.07 28.95,38.07 v1(25.14,41.88)
  BOTTOM w0.254: U4500.H4 74.03,70.02 v3(74.38,69.67)
PCU_SMB_CLK: length 80.8
  L3 w0.089: 63.25,67.07 63.12,67.19 63.12,69.95 v1(62.58,70.5)
  L3 w0.135: 63.25,67.07 66.64,63.68 67.9,63.68 68.77,62.81 69.8,62.81 70.93,61.67 70.93,41.47 73.7,38.71 74.75,38.71 76.31,37.15 89.48,37.15 90.01,36.62 93.89,36.62 94.71,37.44 96.99,37.44 103.44,43.89 v1(103.44,44.34)
  BOTTOM w0.089: v1(62.58,70.5) 62.49,70.5 U4500.AM6
  BOTTOM w0.109: v1(103.44,44.34) 103.15,44.63 103.15,47.93 v2(103.43,48.21) 103.43,48.97 104.54,50.09 R4560.2 105.03,50.83 105.33,51.13 105.33,51.35 U4502.5
PCU_SMB_DATA: length 78.1
  L3 w0.089: 63.59,67.35 63.3,67.63 63.3,70.13 63.04,70.38 63.04,70.68 v1(62.55,71.18)
  L3 w0.135: 63.59,67.35 64.44,66.5 64.64,66.5 66.94,64.19 68.11,64.19 68.98,63.32 70.01,63.32 71.45,61.89 71.45,41.68 73.91,39.22 74.97,39.22 76.52,37.66 89.7,37.66 90.22,37.14 93.67,37.14 95.24,38.71 97.3,38.71 102.08,43.48 102.08,43.76 v1(103.63,45.31)
  BOTTOM w0.089: U4500.AM7 62.2,71.52 62.55,71.18 v1(62.55,71.18)
  BOTTOM w0.109: U4502.4 105.44,48.63 105.08,48.99 R4583.2 103.96,48.4 v2(103.96,46.35) 103.96,45.64 v1(103.63,45.31)
PLT_RST#: length 167
  TOP w0.109: v1(75.74,155.37) 75.74,154.18 75.23,153.67 75.23,151.28 74.44,150.49 U301.7
  L4 w0.135: v1(75.74,155.37) 74.99,155.37 71.45,151.83 71.45,148.93 66.22,143.71 66.22,140.03 66.22,140.03 66.22,139.68 64.87,138.33 60.68,138.33 60,139.01 58.45,139.01 57.77,138.33 56.38,138.33 53.68,141.03 51.65,141.03 50.24,142.44 49.56,142.44 48.7,142.44 48.7,142.44 46.63,142.44 42.35,138.16 v1(41.78,138.16) 41.78,138.91 41.11,139.58 40.52,139.58 38,137.06 38,135.89 37.51,135.41 36.34,135.41 34.55,133.61 34.55,128.89 30.53,124.87 v1(30.53,124.48) ; v1(112.8,147.01) 112.8,146.94 110.54,144.68 110.54,137.2 111.39,136.35 111.39,131.87 110.53,131 110.53,121.63 v1(109.95,121.06)
  BOTTOM w0.109: v1(41.78,138.16) 41.78,136.22 45.58,132.43 CN1300.52 45.57,130.03 45.69,129.91 48.96,129.91 49.08,130.03 CN1300.66 ; v1(30.53,124.48) 30.53,123.14 29.69,122.31 R4584.1 28.65,122.31 U4504.4 ; U3500.16 109.88,120.99 v1(109.95,121.06) ; v1(75.74,155.37) 75.89,155.52 84.79,155.52 86.49,153.82 88.34,153.82 v2(90.52,151.64) 91.9,150.26 92.27,150.26 92.84,150.84 99.02,150.84 100.86,148.99 101.37,148.99 104.54,148.99 104.8,149.26 106.79,149.26 109.03,147.01 v1(112.8,147.01)
PLT_RST_1V8#: length 213
  TOP w0.089: v1(75.36,74.46) 75.49,74.46 76.02,73.94 78.66,73.94 v2(78.98,73.62) 79.22,73.38 79.84,73.38
  TOP w0.102: 79.84,73.38 79.96,73.38 80.75,72.58 v1(80.75,71.48)
  L4 w0.102: v1(37.11,129.21) 37.11,131.42 38.81,133.12 40.88,133.12 45.45,137.7 45.45,138.33 46.31,139.18 46.31,140.53 47.39,141.61 49.04,141.61 49.21,141.61 53.33,137.5 65.32,137.5 67.17,139.34 67.17,142.82 70.16,145.81 77.46,145.81 78.33,146.68 78.5,146.68 85.27,146.68 88.01,149.43 89.16,149.43 89.58,149.85 91.4,149.85 95.19,146.06 95.57,146.06 95.57,146.06 95.77,146.06 95.94,146.06 100.68,141.32 100.68,139.61 101.34,138.94 101.63,138.94 106.94,133.63 106.94,131.29 107.6,130.63 107.6,120.04 107.9,119.75 107.9,112.23 108.3,111.83 108.3,106.73 107.85,106.27 107.85,105.37 106.04,103.57 106.04,101.34 106.04,101.01 105.19,100.16 105.19,97.98 103.51,96.3 103.51,70.72 102.84,70.05 102.84,67.32 101.7,66.18 101.7,65.05 99.41,62.76 97.84,62.76 90.24,70.36 90.24,72.1 89.52,72.82 82.75,72.82 81.49,71.56 80.83,71.56 v1(80.75,71.48)
  BOTTOM w0.102: v1(75.36,74.46) 75.36,74.64 U4500.F14 ; v1(37.11,129.21) 37.11,128.98 36.7,128.57 34.36,128.57 33.13,127.34 30.21,127.34 R4628.1 27.94,125.07 U4504.2
PMU_AC_PRESENT: length 148.3
  L4 w0.089: v3(80.11,71.71) 80.32,71.92
  L4 w0.102: 80.32,71.92 80.94,72.54 81.9,72.54 82.58,73.23 83.54,73.23 84.5,74.19 84.5,76.3 85.77,77.57 89.71,77.57 90.65,76.63 90.65,70.53 96.78,64.4 97.1,64.4 97.34,64.64 97.67,64.64 98.49,63.83 99.35,63.83 101.29,65.77 101.29,66.34 102.44,67.49 102.44,70.21 103.11,70.89 103.11,96.55 104.17,97.61 104.17,99.71 105.64,101.18 105.64,103.74 107.44,105.54 107.44,106.44 107.9,106.9 107.9,110.67 107.49,111.07 107.49,119.38 104.39,122.48 104.39,125.81 104.66,126.09 104.98,126.09 105.45,126.56 105.45,127.22 104.8,127.86 104.66,127.86 104.43,128.1 104.43,129.38 105.2,130.15 105.2,132.91 101.48,136.63 100.78,136.63 100.45,136.3 100.45,134.92 98.24,132.71 89.71,132.71 89.1,133.32 89.1,134.34 86.46,136.98 v1(83.64,136.98)
  BOTTOM w0.089: U4500.C13 76.66,73.91 76.95,73.62 76.95,73.52 77.85,72.62 78.28,72.62 79.19,71.71 v3(80.11,71.71)
  BOTTOM w0.102: v1(83.64,136.98) 83.64,134.38 82.74,133.48 Q4506.3 82.74,131.86 83.72,130.89 R4587.1
PMU_BATLOW#: length 224.7
  TOP w0.102: R4659.1 63.74,151.48 D4701.1 64.68,149.77 64.67,149.76 ; 41.68,140.84 40.56,139.72 40.56,138.58 41.38,137.76 42.76,137.76 43.15,138.15 45.85,138.15 v1(45.99,138.29)
  TOP w0.109: 64.67,149.76 63.92,149.02 63.92,147.76 59.4,143.23 44.07,143.23 41.68,140.84
  L4 w0.102: v1(81.28,72.01) 81.65,72.01 82.67,73.02 89.6,73.02 90.45,72.18 90.45,70.45 97.93,62.97 99.33,62.97 101.5,65.13 101.5,66.26 102.64,67.4 102.64,70.13 103.31,70.8 103.31,96.47 104.37,97.53 104.37,99.62 105.84,101.09 105.84,103.65 107.64,105.46 107.64,106.36 108.1,106.81 108.1,111.74 107.69,112.15 107.69,119.66 106.73,120.62 106.73,133.55 101.54,138.73 101.18,138.73 100.47,139.44 100.47,141.23 95.85,145.86 95.65,145.86 95.11,145.86 91.46,149.51 89.53,149.51 89.24,149.22 88.23,149.22 85.48,146.48 78.42,146.48 77.55,145.61 70.24,145.61 67.37,142.74 67.37,139.26 65.41,137.29 53.25,137.29 49.13,141.41 47.47,141.41 46.51,140.45 46.51,138.81 v1(45.99,138.29)
  BOTTOM w0.102: U4500.C14 76.51,74.77 76.79,74.77 76.95,74.61 76.95,74.47 77.41,74.02 77.97,74.02 78.89,73.1 79.58,73.1 80.01,72.67 v2(80.46,72.67) 80.62,72.67 v1(81.28,72.01)
PMU_PCIE_WAKE#: length 68.3
  L3 w0.089: 74.06,74.85 72.35,74.85 v1(71.74,75.47)
  L3 w0.102: v1(97.38,44.7) 95.32,44.7 90.85,40.23 80.11,40.23 78.38,41.96 76.66,41.96 76.17,42.45 76.17,48.61 75.33,49.44 75.33,51 77.07,52.73 77.07,54.69 76.15,55.62 76.15,61.96 78.28,64.09 78.28,67.85 75.67,70.45 75.67,73.08 74.47,74.29 74.47,74.45 74.06,74.85
  BOTTOM w0.102: R4655.1 100.97,44.9 Q4513.2 100.59,44.94 R4637.1 v2(98.5,44.94) 97.61,44.94 v1(97.38,44.7) ; v1(71.74,75.47) 71.74,75.7 U4500.N16
PMU_RSTBTN#: length 5.7
  BOTTOM w0.089: R4625.2 C4515.1
  BOTTOM w0.102: C4515.1 65.33,65.03 65.33,65.86 64.75,66.44 64.75,67.86 65.11,68.22 U4500.AF2
PMU_STAT_1V8#: length 119.6
  TOP w0.089: v1(76.16,74.44) 76.48,74.12 79.35,74.12 79.84,73.62
  TOP w0.102: 79.84,73.62 80.46,73.62 83.4,70.69 v3(84.1,70.69)
  L4 w0.102: v1(108.58,135.38) 108.58,122.36 108.58,122.19 108.21,121.82 108.21,120.3 108.51,120 108.51,119.5 108.51,112.49 110.05,110.94 110.05,106.42 109.47,105.83 109.47,104.99 107.26,102.78 107.26,101.85 107.26,100.5 106.41,99.65 106.41,98.48 106.41,98.48 106.41,97.47 104.73,95.79 104.73,70.21 104.06,69.54 104.06,65.46 100.35,61.75 97.15,61.75 87.29,71.6 85.01,71.6 v3(84.1,70.69)
  BOTTOM w0.089: U4500.D14 75.73,74.87 v1(76.16,74.44)
  BOTTOM w0.102: v1(108.58,135.38) 113.59,135.38 113.69,135.28 113.69,132.8 113.45,132.56 R3514.1 112.62,132.44 Q3501.1
PVADPTR: length 30.3
  TOP w0.381: v1(55.62,22.71) 55.53,22.8 54.67,22.8 52.71,20.83 C6030.1 52.71,19.16 Q6010.5
  L4 w0.381: v1(55.62,22.71) 55.4,22.71 52.65,25.45 52.65,31.22 v1(53.92,32.49)
  BOTTOM w0.381: D6000.1 58.06,20.92 58.06,22.33 57.68,22.71 v1(55.62,22.71) ; R6002.2 58.31,32.49 v1(53.92,32.49) 53.21,31.77 R60021.1
  vias: v2(28.66,120.2) v5(20.14,106.7) v5(20.14,105.79) v5(21.05,106.7) v5(21.05,105.79) v5(27.94,133.76) v5(27.94,132.82) v5(27.94,131.88) v5(27.94,130.94) v5(32.51,19.43) v5(33.45,19.43) v5(34.39,19.43)
PVCORE: length 26
  TOP w0.254: v1(64.81,80.9) 65.01,80.69 65.01,80.18 C4522.1 ; C4517.1 63.11,84.52 v1(63.28,84.69) ; v1(64.81,81.66) 64.79,81.64 C4523.1 63.26,81.64 v1(63.24,81.66) ; C4518.1 64.07,87.77 64.07,86.3 64.09,86.27 v1(64.01,86.19) ; v1(64.02,84.69) 64.07,84.73 C4519.1
  TOP w0.381: v1(80.09,83.92) 80.81,84.64 C7515.1 ; v1(63.24,80.9) 63.2,80.94 C4524.1 62.45,80.19 C4520.1 ; R4698.1 v2(72.79,97.16) 73.03,97.16 73.33,97.46 v1(74.65,97.46) ; C7551.2 75.49,105.52 v1(74.9,104.93) ; C4521.1 64.1,80.86 ; 63.95,81.24 C4523.1 ; C7552.1 v1(72.08,104.74)
  BOTTOM w0.254: v1(64.02,84.69) U4500.AG35 64.35,85.07 v1(63.98,85.44) 63.63,85.79 U4500.AJ36 ; v1(64.02,84.69) 64.01,84.69 U4500.AJ33 ; v1(64.02,84.69) U4500.AG33 v1(64.02,83.93) 64.01,83.93 U4500.AJ33 ; U4500.AJ38 63.63,86.56 v1(64.01,86.19) ; U4500.AJ33 63.28,84.66 v1(63.28,84.69) ; U4500.AJ33 v1(63.26,83.94) ; v1(64.81,80.9) 64.43,81.28 U4500.AG27 U4500.AJ27 63.62,81.28 v1(63.24,80.9) ; U4500.AF30 65.21,82.79 v1(65.59,82.41) ; U4500.AF29 65.19,82.03 v1(64.81,81.66) 64.43,82.03 U4500.AG29 U4500.AJ29 63.62,82.03 v1(63.24,81.66)
  vias: v1(88.8,95.39) v1(88.82,94.69) v1(89.44,95.39) v1(89.46,94.69) v1(90.07,95.39) v1(90.09,94.69) v1(90.71,95.39) v5(88.04,97.75) v5(88.04,96.73) v5(88.04,95.82) v5(88.87,97.22) v5(88.87,96.28) v5(89.81,97.22) v5(89.81,96.28) v5(90.82,97.22) v5(90.82,96.28)
PVCORE_PG: length 116.3
  TOP w0.102: v1(101.01,136.22) 101.01,140.66 98.45,143.22 98.45,143.61 96.63,145.43 92.34,145.43 91.77,144.86 88.08,144.86 85.06,141.83 83.55,141.83 83.36,142.02 81.8,142.02 79.68,139.9 79.2,139.9 78.59,140.51 78.59,142.22 78.94,142.57 78.94,144.04 R350.1 77.83,144.5 76.04,146.28 U301.11
  L4 w0.102: v3(96.06,73.76) 102.24,79.95 102.24,96.94 103.29,97.99 103.29,100.24 105.43,102.37 105.43,103.82 107.24,105.63 107.24,106.52 107.69,106.98 107.69,110.58 107.29,110.99 107.29,119.29 104.19,122.39 104.19,125.9 104.58,126.29 104.88,126.29 105.24,126.65 105.24,127.12 104.7,127.66 104.58,127.66 104.22,128.02 104.22,129.47 104.99,130.24 104.99,132.82 101.6,136.22 v1(101.01,136.22)
  BOTTOM w0.102: U6600.6 95.73,72.8 95.91,72.97 95.91,73.61 v3(96.06,73.76)
PVGG: length 18
  TOP w0.381: 65.04,76.98 C4528.1 ; v1(84.25,67.77) 83.89,68.13 C7519.1 ; v1(68.87,59.02) 69.08,58.8 C7522.1 ; C4530.1 64.53,77.69 ; C4531.1 64.19,76.1 ; 65.04,77.87 C4529.1 ; 65.04,76.1 C4527.1
  L3 w0.381: v1(90.62,60.58) 91.31,61.26 101.13,61.26 101.13,61.26 101.62,61.26 v1(102.13,61.77)
  BOTTOM w0.381: C7591.1 v1(90.22,54.4) ; R4699.1 102.23,61.87 v1(102.13,61.77) ; 91.14,50.79 C7520.1
  vias: v1(63.69,72.58) v1(64.04,77.11) v1(64.05,76.34) v1(64.81,78.62) v1(64.81,77.86) v1(64.81,77.11) v1(64.81,76.35) v1(86.08,54.58) v1(86.08,53.95) v1(86.08,53.31) v1(86.08,52.68) v1(86.69,54.58) v1(86.69,53.95) v1(86.69,53.31) v1(86.69,52.68) v1(87.3,54.58) v1(87.3,53.95) v1(87.3,53.31) v1(87.3,52.68) v1(87.91,54.58) v1(87.91,53.95) v1(87.91,53.31) v1(87.91,52.68) v1(88.29,63.64) v1(89.67,63.65) v2(90.5,52.53) v5(85.11,55.42) v5(85.11,54.48) v5(85.11,53.54) v5(85.11,52.6) v5(86.05,55.42) v5(86.99,55.42) v5(87.93,55.42) v5(89.02,55.42) v5(89.02,54.48) v5(89.02,53.54) v5(89.02,52.6)
PVGG_PG: length 5.6
  BOTTOM w0.102: U6700.6 99.12,55.65 99.9,54.86 v2(100.83,54.86) 101.21,54.86 C7225.2 ; R7250.1 102.64,55.38 C7225.2 ; C7225.2 101.72,54.96 101.73,54.96 R7245.1
PVPACK: length 42.4
  L3 w0.381: v1(76.1,19.05) 80.26,19.05 87.45,26.24 v1(87.45,26.69)
  BOTTOM w0.381: D60002.1 57.5,21.36 57.5,20.05 D60002.2 57.21,17.41 58.16,16.45 62.3,16.45 67.71,21.87 70.2,21.87 72.34,19.74 75.41,19.74 v1(76.1,19.05) ; C6050.1 89.28,28.69
  vias: v2(88.74,29.97)
PWR_OLED#: length 37
  TOP w0.102: v1(83.72,142.24) 80.97,142.24 v2(80.77,142.44) 79.35,143.86 79.35,146.38 78.81,146.91 78.81,147.22 78.04,148 U301.16
  L4 w0.102: v1(98.17,138.76) 98.17,141.37 96.11,143.42 94.81,143.42 91.32,146.92 91.15,146.92 90.24,146.92 85.56,142.24 v1(83.72,142.24)
  BOTTOM w0.102: v1(98.17,138.76) 98.17,138.76 101.37,138.76 101.68,138.45 101.68,138.45 CN245.8
PWR_OLED#_PB: length 32.6
  TOP w0.381: v4(73.12,8.63) 72.87,8.88 CN9100.8
  L3 w0.381: v4(73.12,8.63) 72.92,8.83 71.29,8.83 71,9.12 69.88,9.12 69.87,9.12 69.4,9.12 68.94,9.58 51.13,9.58 v4(50.15,8.59)
  BOTTOM w0.381: D9128.4 45.41,8.2 v2(45.83,8.62) 46.08,8.87 49.87,8.87 v4(50.15,8.59)
PWR_SWIN#_3: length 59.6
  TOP w0.102: v1(106.52,156.72) 107.11,157.3 v2(107.31,157.3) R301.1 ; U301.93 73.24,162.49 v1(73.3,162.43)
  L3 w0.102: v1(73.3,162.43) 73.69,162.81 77.29,162.81 78.41,163.93 84.44,163.93 85.26,163.11 85.26,162.8 86.19,161.87 86.19,160.79 89.38,157.61 93.41,157.61 94.12,156.9 98.28,156.9 98.91,157.53 102.65,157.53 103.46,156.72 v1(106.52,156.72)
  L4 w0.102: v1(106.52,156.72) 106.52,156.72 106.26,156.72 105.41,155.86 105.41,153.42 103.4,151.41 103.4,148.04 100.91,145.55 v1(100.91,144.61)
  BOTTOM w0.102: CN245.3 101.66,143.45 101.66,143.45 100.91,144.2 v1(100.91,144.61)
PWR_SWIN#_3_PB: length 64.6
  TOP w0.508: v5(71.51,7.21) 71.38,7.21 71.31,7.29 71.12,7.29 70.86,7.55 68.24,7.55 67.88,7.91 CN9100.3
  L3 w0.508: v4(49.91,10.62) 49.79,10.5 48.76,10.5 47.73,9.48 47.73,5.45 49.09,4.09 49.46,4.09 v4(49.55,4.18) 50.11,3.62 52.22,3.62 52.53,3.93 55.3,3.93 56.85,5.49 57.95,5.49 58.4,5.03 60.66,5.03 60.95,5.32 68.4,5.32 68.46,5.25 70.78,5.25 71.33,5.81 73.11,5.81 73.51,6.2 73.51,7.12 v5(73.78,7.4)
  BOTTOM w0.381: v5(71.51,7.21) 71.51,6.78 71.56,6.73 C9102.1 ; D9100.1 v5(73.78,7.4) D9100.2 ; SW9100.1 v2(40.09,8.36) 40.09,8.5 41.84,10.25 46.89,10.25 47.27,10.62 v4(49.91,10.62) ; SW9100.3 48.06,5.45 49.33,4.18 v4(49.55,4.18)
  BOTTOM w0.508: v5(71.51,7.21) 71.7,7.4 D9100.1
PWR_WLED#: length 43.1
  TOP w0.102: U301.65 84.44,163.69 v1(84.27,163.52)
  L4 w0.102: v1(84.27,163.52) 84.69,163.94 86.35,163.94 86.89,163.4 86.89,158.02 88.9,156.01 90.98,156.01 91.51,156.54 94.43,156.54 94.96,156.01 96.74,156.01 99.03,153.72 99.99,153.72 102.95,150.76 102.95,147.88 100.48,145.41 100.48,144.04 101.69,142.82 v3(104.14,142.82)
  BOTTOM w0.102: CN245.5 103.4,141.45 104.14,142.19 v3(104.14,142.82)
PWR_WLED#_PB: length 28.5
  TOP w0.381: v4(69.63,9.69) 69.87,9.93 CN9100.5
  L3 w0.381: v4(49.46,8.19) 49.46,8.72 49.91,9.16 50.02,9.16 50.96,10.1 69.22,10.1 v4(69.63,9.69)
  BOTTOM w0.381: v4(49.46,8.19) 49.24,7.96 47.21,7.96 46.55,7.3 v2(46.47,7.3) D9128.3
RAM_ID1: length 7.5
  BOTTOM w0.102: R4892.1 67.46,62.33 67.46,63.7 R4900.1 66.57,64.59 66.57,67.97 66.08,68.46 U4500.AD2
RAM_ID2: length 7.4
  TOP w0.102: v3(67.87,64.97) 67.94,64.9 R4901.1 67.46,63.7 67.46,62.53 R4893.1
  BOTTOM w0.089: v3(67.87,64.97) 67.86,64.98 67.86,65.23 67.05,66.04 67.05,67.77 66.56,68.26 U4500.AC1
RAM_ID3: length 9.4
  TOP w0.102: R4894.1 66.47,62.55 66.47,63.67 R4902.1 67.39,64.59 67.39,65.63 66.93,66.09 v2(66.93,67.03) 66.93,67.87 66.83,67.97 66.68,68.12 66.68,69.41 66.46,69.63 v1(66.46,69.95)
  BOTTOM w0.089: U4500.AD3 v1(66.46,69.95)
RAM_ID4: length 12.3
  TOP w0.102: v1(66.98,64.95) 66.98,65.37 v2(66.71,65.65) 66.46,65.9 66.46,69.33 65.99,69.8 65.99,70.65 v1(64.69,71.95)
  BOTTOM w0.102: U4500.AF7 v1(64.69,71.95) ; R4895.1 68.42,62.4 68.42,63.7 R4903.1 67.76,64.18 v1(66.98,64.95)
RING2: length 34.3
  TOP w0.254: U500.17 12.22,56.42 13.1,57.3 v3(13.41,57.3)
  L4 w0.508: v3(13.41,57.3) 12.32,57.3 11.81,57.81 11.81,59.41 7.62,63.6 7.62,74.62 9.39,76.4 9.39,80.09 6.73,82.75 v1(6.73,82.96)
  BOTTOM w0.254: R603.2 R601.1 v1(6.73,82.96)
RING2_CONN: length 10.2
  BOTTOM w0.254: JACK600.4 5.77,93.39 R610.1 C604.1 v2(5.77,84.78) 5.77,84.54 5.08,83.85 R603.1
RTC_RST_N: length 10.4
  TOP w0.109: v3(79.85,75.16) 78.58,76.44 v1(76.12,76.44) ; R4580.1 C4625.1 v1(79.37,72.62)
  L3 w0.135: v3(79.85,75.16) 79.37,74.68 v1(79.37,72.62)
  BOTTOM w0.102: U4500.D18 76.12,76.5 v1(76.12,76.44)
  BOTTOM w0.109: C4627.1 80.1,75.4 v3(79.85,75.16)
RTC_TEST_N: length 5.4
  TOP w0.109: R4581.1 76.51,73.01 C4514.1 75.61,73.51 v2(75.6,73.51) 73.86,75.25 v1(73.86,75.42)
  BOTTOM w0.109: v1(73.86,75.42) 73.63,75.65 U4500.J16
RTCX1: length 18
  TOP w0.089: 78.15,75.71 78.04,75.82 73.11,75.82 v1(72.54,76.39)
  TOP w0.109: v1(81.4,73.94) 81.23,74.11 79.75,74.11 78.15,75.71
  BOTTOM w0.089: v1(72.54,76.39) 72.54,76.51 72.21,76.84 U4500.M18
  BOTTOM w0.109: X4501.4 R4579.2 85.95,71.49 C4512.1 85.39,72.76 84.38,72.76 v2(83.65,73.49) 83.21,73.94 v1(81.4,73.94)
RTCX2: length 18.1
  TOP w0.089: v1(73.23,76.39) 73.6,76.01 78.24,76.01 78.33,75.92
  TOP w0.109: v1(81.45,74.6) 79.65,74.6 78.33,75.92
  BOTTOM w0.089: v1(73.23,76.39) 73.23,76.54 72.92,76.85 U4500.K18
  BOTTOM w0.109: X4501.1 86.61,70.13 R4579.1 86.72,71.41 C4511.1 86.72,72.23 85.7,73.25 84.59,73.25 83.24,74.6 v2(82.4,74.6) v1(81.45,74.6)
SATA_OBSN: length 1.8
  TOP w0.107: R4532.1 72.61,84.31 v3(72.61,83.31)
  BOTTOM w0.107: U4500.M30 v3(72.61,83.31)
SATA_OBSP: length 1.8
  TOP w0.107: v1(71.9,83.31) 71.9,84.29 R4532.2
  BOTTOM w0.107: U4500.N30 v1(71.9,83.31)
SB_PWRBTN#: length 120.7
  TOP w0.109: v1(66.8,162.35) 66.8,161.68 D4700.1 ; R4653.1 63.9,157.94 64.64,158.67 v1(64.97,158.67) ; v1(63.86,140.86) 63.51,140.51 63.51,138.83 61.92,137.23 61.92,133.24 63.33,131.83 63.4,131.83 66.15,131.83 70.32,127.66 73.48,127.66 76.37,124.76 78.71,124.76 v1(78.93,124.55)
  L3 w0.135: v1(86.21,93.62) 86.01,93.41 86.01,90.84 85.03,89.86 83.03,89.86 79.27,86.1 79.27,82.75 80.2,81.82 80.2,77.37 79.64,76.8 77.15,76.8 76.31,75.95 73.1,75.95 72.57,75.42 v3(72.55,75.42) ; v1(83.74,115.59) 83.95,115.81 83.95,119.52 v1(78.93,124.55)
  L4 w0.135: v1(66.8,162.35) 66.8,160.5 v1(64.97,158.67) 64.97,158.4 66.99,156.37 66.99,151.97 66.09,151.06 66.09,149.54 65.78,149.24 65.78,147.88 63.32,145.42 63.32,141.4 v1(63.86,140.86)
  BOTTOM w0.109: v1(86.21,93.62) 86.21,95.24 85.42,96.04 85.42,99.2 83.82,100.8 83.82,115.52 v1(83.74,115.59) ; U4500.M16 72.21,75.76 v3(72.55,75.42)
SB_PWRGD: length 130.9
  TOP w0.109: U301.118 71.79,154.63 72.94,155.78 77.39,155.78 77.58,155.59 77.7,155.59 77.98,155.3 77.98,154.9 77.31,154.22 77.31,151.41 v1(76.14,150.24) ; v3(79.83,69.14) 79.83,67.34 R7243.1
  L3 w0.135: v3(79.83,69.14) 79.63,68.94 78.69,68.94 77.77,69.85 77.77,73.01 77.67,73.12 77.67,74.69 78.62,75.64 80.55,75.64 81.2,76.29 81.2,82.88 85.75,87.43 88.08,87.43 88.23,87.57 88.23,87.57 88.7,88.03 96.49,88.03 98.65,90.19 98.65,93.66 96.59,95.73 96.59,100.82 94.44,102.97 94.44,105.62 95.6,106.78 95.6,111.51 97.25,113.16 97.25,121.64 96.01,122.88 91.54,122.88 88.65,125.78 88.65,127.43 86.68,129.39 86.68,135.8 84.83,137.64 83.54,137.64 82.88,138.3 82.88,140.6 80.31,143.17 80.31,143.98 76.74,147.55 v1(75.63,147.55)
  BOTTOM w0.109: v1(76.14,150.24) 76.14,148.06 v1(75.63,147.55)
SB_USB_1: length 96.1
  TOP w0.102: U301.17 78.44,149.73 77.93,150.24 v1(76.86,150.24)
  L3 w0.102: v1(14.86,125.42) 14.85,125.43 14.85,138.18 18.96,142.29 61.46,142.29 64.49,145.31 64.49,147.73 64.49,147.9 66.25,149.67 66.25,150.02 69.62,153.39 73.71,153.39 v1(76.86,150.24)
  BOTTOM w0.102: v1(14.86,125.42) 18.39,121.89 21.46,121.89 22.2,121.16 U2406.4
SB_USB_3: length 79.1
  TOP w0.102: v1(101.01,135.61) 101.9,136.5 101.9,140.4 100.13,142.17 100.13,143.39 97.68,145.84 92.17,145.84 91.6,145.26 87.91,145.26 85.65,143 81.51,143 81.17,143.35 81.17,144.27 80.94,144.5 80.94,148.94 U301.23
  L4 w0.102: v1(106.58,108.95) 106.58,108.95 106.58,110.41 106.7,110.54 106.7,119.3 103.78,122.22 103.78,126.07 104.11,126.4 104.11,127.55 103.82,127.85 103.82,133.42 102.21,135.03 101.34,135.03 101.01,135.36 v1(101.01,135.61)
  BOTTOM w0.102: v1(106.58,108.95) 106.58,108.94 106.85,108.66 107.95,108.66 v2(108.1,108.51) 108.66,107.95 108.66,103.86 110.18,102.34 C2004.1 111.1,101.04 111.1,99.44 110.49,98.83 U2000.4
SCAN_IN<0>: length 44.3
  TOP w0.102: v1(84.25,159) 84.29,159.03 U301.54
  L3 w0.102: v1(114.7,148.79) 113.48,147.57 109.29,147.57 107.64,149.23 106,149.23 104.51,150.73 104.51,153.59 103.01,155.09 102.79,155.09 102.75,155.13 101.79,155.13 101.02,155.9 99.59,155.9 98.96,155.27 93.44,155.27 92.86,155.85 91.92,155.85 91.36,155.29 88.22,155.29 84.52,159 84.52,159 v1(84.25,159)
  BOTTOM w0.102: CN251.24 114.78,151.68 115.16,151.3 115.16,150.14 D250.1 v1(114.7,148.79)
SCAN_IN<1>: length 45
  TOP w0.102: v1(83.64,159) 84.05,159.4 86.01,159.4 U301.55
  L3 w0.102: v3(113.79,148.79) 112.77,147.78 109.38,147.78 107.72,149.43 106.09,149.43 104.71,150.81 104.71,153.68 103.09,155.3 102.87,155.3 102.83,155.33 101.87,155.33 101.1,156.11 99.5,156.11 98.87,155.47 93.53,155.47 92.94,156.06 91.84,156.06 91.27,155.49 88.32,155.49 84.42,159.4 84.05,159.4 v1(83.64,159)
  BOTTOM w0.102: v3(113.79,148.79) D251.1 113.79,149.74 114.24,150.19 114.24,151.69 113.78,152.16 CN251.23
SCAN_IN<2>: length 42.6
  TOP w0.102: v1(84.25,159.81) 84.27,159.83 U301.56
  L3 w0.102: v1(112.87,148.79) 112.06,147.98 109.46,147.98 107.8,149.64 106.17,149.64 104.91,150.9 104.91,153.76 103.18,155.5 102.96,155.5 102.15,156.31 99.42,156.31 98.79,155.68 93.61,155.68 93.03,156.26 91.75,156.26 91.19,155.7 88.41,155.7 84.3,159.81 v1(84.25,159.81)
  BOTTOM w0.102: CN251.22 112.77,152.19 113.33,151.64 113.33,150.19 112.87,149.74 D252.1 v1(112.87,148.79)
SCAN_IN<3>: length 43.3
  TOP w0.102: U301.57 84.01,160.23 v1(83.62,159.84)
  L3 w0.102: v1(83.62,159.84) 83.99,160.21 84.42,160.21 84.75,159.88 84.75,159.87 88.72,155.9 91.1,155.9 91.67,156.46 93.11,156.46 93.7,155.88 98.7,155.88 99.34,156.51 102.23,156.51 103.04,155.7 103.26,155.7 105.12,153.85 105.12,150.98 106.26,149.84 107.89,149.84 109.55,148.18 111.35,148.18 v3(111.96,148.79)
  BOTTOM w0.102: CN251.21 111.78,152.18 112.41,151.54 112.41,150.19 111.96,149.74 D253.1 v3(111.96,148.79)
SCAN_IN<4>: length 40.5
  TOP w0.102: U301.58 84.8,160.63 v1(84.61,160.82)
  L3 w0.102: v1(111.05,148.79) 110.64,148.39 109.63,148.39 107.97,150.04 106.34,150.04 105.32,151.07 105.32,153.93 103.35,155.9 103.12,155.9 102.31,156.71 99.25,156.71 98.62,156.08 93.78,156.08 93.2,156.67 91.58,156.67 91.02,156.1 88.81,156.1 84.95,159.96 84.95,160.48 v1(84.61,160.82)
  BOTTOM w0.102: CN251.20 110.78,152.21 111.5,151.49 111.5,150.19 111.05,149.74 D254.1 v1(111.05,148.79)
SCAN_IN<5>: length 41.2
  TOP w0.102: v1(84,160.82) 84.41,161.22 84.96,161.22 85.15,161.03 U301.59
  L3 w0.102: v3(110.13,148.79) 108.68,150.25 106.43,150.25 105.52,151.15 105.52,154.02 103.43,156.11 103.21,156.11 102.4,156.92 99.17,156.92 98.53,156.29 93.87,156.29 93.28,156.87 91.5,156.87 90.94,156.31 88.89,156.31 85.25,159.95 85.25,160.75 84.78,161.22 84.41,161.22 v1(84,160.82)
  BOTTOM w0.102: v3(110.13,148.79) D255.1 110.58,150.14 110.58,151.36 109.77,152.17 CN251.19
SCAN_IN<6>: length 40.9
  TOP w0.102: U301.60 84.01,161.43 v1(83.39,160.82)
  L3 w0.102: v3(106.37,150.88) 105.73,151.52 105.73,154.1 103.52,156.31 103.29,156.31 102.48,157.12 99.08,157.12 98.45,156.49 93.95,156.49 93.37,157.07 91.41,157.07 90.85,156.51 88.98,156.51 85.48,160 85.48,160.81 84.87,161.43 84,161.43 v1(83.39,160.82)
  BOTTOM w0.102: CN251.18 108.76,152.59 108.76,150.24 108.78,150.23 108.78,150.18 109.22,149.74 D256.1 109.22,149.35 108.86,149 107.92,149 106.37,150.54 v3(106.37,150.88)
SCAN_IN<7>: length 36.8
  TOP w0.102: U301.61 84.08,161.84 v1(83.97,161.94)
  L3 w0.102: v1(83.97,161.94) 84.69,161.94 89.23,157.4 93.32,157.4 94.04,156.69 98.37,156.69 99,157.32 102.57,157.32 103.38,156.51 103.6,156.51 105.93,154.19 105.93,152.16 v1(107.18,150.9)
  BOTTOM w0.102: v1(107.18,150.9) 107.18,150.24 107.74,149.69 D257.1 107.78,150.21 107.78,152.6 CN251.17
SCAN_OUT<0>: length 16
  TOP w0.102: U301.53 84.84,158.63 84.77,158.56 84.07,158.56 v1(83.62,158.12)
  L3 w0.102: v3(92.02,155.32) 91.79,155.09 87.26,155.09 85.57,156.78 85.57,157.46 84.49,158.54 84.04,158.54 v1(83.62,158.12)
  BOTTOM w0.102: v3(92.02,155.32) 92.02,153.92 91.77,153.68 CN251.1
SCAN_OUT<1>: length 14.6
  TOP w0.102: U301.52 84.43,158.23 v1(84.32,158.13)
  L3 w0.102: v1(84.32,158.13) 85.37,157.09 85.37,156.7 87.18,154.89 92.3,154.89 v1(92.71,155.3)
  BOTTOM w0.102: v1(92.71,155.3) 92.78,155.23 92.78,152.6 CN251.2
SCAN_OUT<2>: length 16.4
  TOP w0.102: v1(83.67,157.37) 84.02,157.73 84.82,157.73 84.93,157.83 U301.51
  L3 w0.102: v1(83.67,157.37) 83.94,157.65 84.47,157.65 85.16,156.95 85.16,156.61 87.1,154.68 93.29,154.68 v1(93.47,154.86)
  BOTTOM w0.102: v1(93.47,154.86) 93.7,154.63 93.7,152.68 CN251.3
SCAN_OUT<3>: length 15.6
  TOP w0.102: v1(84.3,157.24) 84.49,157.43 U301.50
  L3 w0.102: v1(94.15,154.84) 93.77,154.46 87.03,154.46 84.96,156.53 84.96,156.66 84.37,157.24 v1(84.3,157.24)
  BOTTOM w0.102: v1(94.15,154.84) 94.15,154.03 94.77,153.41 CN251.4
SCAN_OUT<4>: length 17.7
  TOP w0.102: U301.49 85,157.03 84.8,156.84 83.92,156.84 v1(83.81,156.72)
  L3 w0.102: v1(83.81,156.72) 83.89,156.81 84.52,156.81 84.76,156.57 84.76,156.45 86.95,154.25 94.69,154.25 94.79,154.36 v1(94.79,154.84)
  BOTTOM w0.102: v1(94.79,154.84) 94.79,154.03 95.77,153.04 CN251.5
SCAN_OUT<5>: length 16.4
  TOP w0.102: v1(84.35,156.4) 84.58,156.63 U301.48
  L3 w0.102: v1(95.65,154.25) 95.45,154.05 86.86,154.05 84.81,156.1 84.65,156.1 v1(84.35,156.4)
  BOTTOM w0.102: v1(95.65,154.25) 95.96,154.25 96.78,153.44 CN251.6
SCAN_OUT<6>: length 20
  TOP w0.102: v1(83.23,156.44) 83.67,156 84.52,156 84.75,156.23 U301.47
  L3 w0.102: v3(96.75,154.33) 96.26,153.85 86.78,153.85 84.73,155.9 83.77,155.9 v1(83.23,156.44)
  BOTTOM w0.102: CN251.7 97.77,153.3 v3(96.75,154.33)
SCAN_OUT<7>: length 15.8
  TOP w0.102: U301.43 86.95,154.63 v1(88.17,153.41)
  L3 w0.102: v3(99.01,154.38) 97.99,153.37 92.98,153.37 88.21,153.37 v1(88.17,153.41)
  BOTTOM w0.102: CN251.8 98.77,154.15 v3(99.01,154.38)
SCAN_OUT<8>: length 18.7
  TOP w0.102: v1(87.55,153.36) 87.55,153.64 86.96,154.23 U301.42
  L3 w0.102: v1(87.55,153.36) 87.64,153.36 88,153.01 88.34,153.01 88.44,153.11 99.38,153.11 99.64,153.37 99.64,154.3 v3(100.24,154.9)
  BOTTOM w0.102: CN251.9 99.78,154.44 v3(100.24,154.9)
SCAN_OUT<9>: length 20
  TOP w0.102: U301.41 86.96,153.83 87.14,153.65 87.14,153.12 87.56,152.7 v1(87.73,152.7)
  L3 w0.102: v1(87.73,152.7) 88.32,152.7 88.53,152.91 99.75,152.91 101.27,154.42 v1(101.27,155.07)
  BOTTOM w0.102: v1(101.27,155.07) 100.78,154.58 CN251.10
SCAN_OUT<10>: length 18.5
  TOP w0.102: v1(87.13,152.36) 87.13,152.84 86.94,153.04 86.94,153.33 86.84,153.43 U301.40
  L3 w0.102: v1(87.13,152.36) 87.19,152.3 88.2,152.3 88.61,152.7 100.55,152.7 v3(101.67,153.82)
  BOTTOM w0.102: v3(101.67,153.82) 101.77,153.72 CN251.11
SCAN_OUT<11>: length 21.6
  TOP w0.102: U301.39 84.98,153.03 v1(84.91,152.96)
  L3 w0.102: v1(84.91,152.96) 85.95,152.96 86.97,151.95 88.24,151.95 88.8,152.5 101.72,152.5 v1(102.97,153.75)
  BOTTOM w0.102: CN251.12 102.77,153.55 v1(102.97,153.75)
SCAN_OUT<12>: length 23.9
  TOP w0.102: v1(84.28,152.95) 84.68,152.55 85.96,152.55 U301.38
  L3 w0.102: v1(84.28,152.95) 84.69,152.54 86.08,152.54 86.88,151.75 88.33,151.75 88.88,152.3 102.56,152.3 v3(103.88,153.62)
  BOTTOM w0.102: v3(103.88,153.62) 103.78,153.51 CN251.13
SCAN_OUT<13>: length 24.3
  TOP w0.102: v1(84.24,152.34) 84.32,152.26 86.01,152.26 U301.37
  L3 w0.102: v1(84.24,152.34) 86,152.34 86.8,151.54 88.41,151.54 88.96,152.09 103.17,152.09 v3(104.01,151.26)
  BOTTOM w0.102: v3(104.01,151.26) 104.24,151.26 104.78,151.8 104.78,151.8 CN251.14
SCAN_OUT<14>: length 24.2
  TOP w0.102: U301.36 v1(84.95,151.83)
  L3 w0.102: v1(84.95,151.83) 85.44,151.34 88.5,151.34 89.05,151.89 102.72,151.89 v1(104.02,150.59)
  BOTTOM w0.102: v1(104.02,150.59) 104.62,150.59 105.78,151.75 105.77,151.75 CN251.15
SCAN_OUT<15>: length 26.8
  TOP w0.102: v1(84.34,151.73) 84.65,151.43 86.03,151.43 U301.35
  L3 w0.102: v1(84.34,151.73) 84.94,151.14 88.58,151.14 89.13,151.69 102.2,151.69 103.87,150.01 v1(104.34,150.01)
  BOTTOM w0.102: CN251.16 106.78,152.07 v2(105.55,150.84) 104.72,150.01 v1(104.34,150.01)
SD_CD#: length 15.2
  TOP w0.109: v1(28.06,22.43) 28.06,23.27 30.06,25.27 CN901.10
  BOTTOM w0.109: U900.13 22.41,15.33 28.06,20.98 v1(28.06,22.43)
SD_CLK: length 19.2
  TOP w0.109: v1(26.82,18.51) 28,17.33 CN901.5
  BOTTOM w0.109: v1(26.82,18.51) 26.08,17.77 26.08,17.61 26.61,17.08 26.61,16.93 26.37,16.7 26.22,16.7 25.54,17.38 25.39,17.38 25.15,17.14 25.15,16.99 25.83,16.31 25.83,16.16 25.6,15.92 25.45,15.92 24.76,16.61 24.61,16.61 24.38,16.38 24.38,16.22 25.06,15.54 25.06,15.38 24.83,15.15 24.67,15.15 24.14,15.68 23.99,15.68 23.76,15.45 23.76,15.3 24.29,14.77 24.29,14.61 24.06,14.38 23.9,14.38 23.37,14.91 23.22,14.91 C907.1 21.31,13.89 R901.2
SD_CMD: length 21.2
  TOP w0.109: CN901.2 22.57,9.84 22.14,10.27 22.14,10.42 22.82,11.1 22.82,11.26 22.59,11.49 22.43,11.49 21.75,10.81 21.6,10.81 21.37,11.04 21.37,11.19 22.05,11.87 22.05,12.03 21.81,12.26 21.66,12.26 20.98,11.58 20.83,11.58 20.59,11.81 20.59,11.97 21.15,12.53 21.15,12.68 20.92,12.91 20.77,12.91 20.21,12.35 20.05,12.35 v1(18.23,14.17)
  BOTTOM w0.109: U900.18 v1(18.23,14.17)
SD_D0: length 21.6
  TOP w0.109: v1(26.57,20.24) 27.79,20.24 27.99,20.04 27.99,18.48 28.1,18.38 28.32,18.38 28.43,18.48 28.43,21.08 28.53,21.19 28.75,21.19 28.86,21.08 28.86,18.48 28.97,18.38 29.19,18.38 29.3,18.48 29.3,22.09 29.54,22.33 CN901.7
  BOTTOM w0.109: v1(26.57,20.24) 26.57,19.95 23.16,16.55 U900.11
SD_D1: length 21.4
  TOP w0.109: v1(27.51,21.23) 30.24,23.97 CN901.8
  BOTTOM w0.109: v1(27.51,21.23) 27.22,21.52 27.22,24.3 27.11,24.41 26.71,24.41 26.57,24.28 26.57,23.87 26.46,23.76 25.6,23.76 25.49,23.65 25.49,23.43 25.6,23.32 26.46,23.32 26.57,23.21 26.57,22.99 26.46,22.88 26.14,22.88 26.03,22.77 26.03,22.55 26.14,22.45 26.46,22.45 26.57,22.34 26.57,21.11 26.38,20.92 26.11,20.92 26,20.81 26,19.72 23.33,17.06 U900.10
SD_D2: length 22.1
  TOP w0.109: CN901.9 30.29,4.84 28.27,6.86 24.3,6.86 15.92,15.24 15.92,16.65 v1(16.33,17.06)
  BOTTOM w0.109: U900.21 v1(16.33,17.06)
SD_D3: length 21.2
  TOP w0.109: v1(16.33,15.76) 16.33,15.48 24.47,7.34 24.95,7.34 25.06,7.44 25.06,7.82 25.17,7.92 25.5,7.92 25.61,7.82 25.61,7.44 25.72,7.34 26.05,7.34 26.15,7.44 26.15,7.82 26.26,7.92 26.59,7.92 26.7,7.82 26.7,7.44 26.81,7.34 CN901.1
  BOTTOM w0.109: U900.20 17.11,16.55 16.33,15.77 v1(16.33,15.76)
SD_R_CLK: length 2.1
  BOTTOM w0.109: U900.15 19.73,14.27 v2(19.63,14.17) 19.9,13.9 R901.1
SD_WP: length 13.8
  TOP w0.109: v1(25.84,21.98) 25.84,22.11 30.2,26.47 CN901.11
  BOTTOM w0.109: U900.8 24,18.06 25.76,19.82 25.76,21.9 v1(25.84,21.98)
SDIO_V3P3A_V1P8A: length 1.4
  BOTTOM w0.381: 78.77,64.86 C4579.1 78.77,65.83 ; C4580.1 77.55,65.3
  vias: v2(77.97,65.33)
SDMMC1_RCOMP: length 1.5
  TOP w0.109: v1(71.4,73.86) 71.81,73.86 R4521.2
  BOTTOM w0.109: U4500.P13 70.93,74.3 71.16,74.07 71.19,74.07 v1(71.4,73.86)
SDMMC3_RCOMP: length 1.6
  TOP w0.109: v3(71.41,73.17) 71.8,72.79 R4712.1
  BOTTOM w0.102: v3(71.41,73.17) 71.39,73.2 71.35,73.2 70.93,73.62 U4500.P12
SIO_I2C_CLK: length 84
  L3 w0.135: v1(102.05,47.5) 102.74,46.82 102.74,45.61 98.21,41.07 96.59,41.07 93.17,37.65 90.44,37.65 89.91,38.18 76.74,38.18 75.18,39.74 74.13,39.74 71.97,41.9 71.97,62.1 69.37,64.69 69.08,64.69 67.63,66.14 67.63,66.19 65.59,68.22 65.24,68.22 63.68,69.78 v1(63.68,70.47)
  BOTTOM w0.109: U4503.5 107.21,57.81 107.21,57.53 106.99,57.31 R4681.2 106.45,56.5 103.4,53.45 103.4,50.73 102.05,49.38 v2(102.05,48.74) v1(102.05,47.5) ; v1(63.68,70.47) 63.33,70.81 U4500.AK6
SIO_I2C_DATA: length 80.2
  L3 w0.135: v1(63.7,71.17) 64.21,70.66 64.21,69.57 64.74,69.04 65.51,69.04 68.15,66.4 68.15,66.36 69.29,65.21 69.59,65.21 72.48,62.31 72.48,42.11 74.34,40.25 75.39,40.25 76.95,38.7 93.48,38.7 96.37,41.59 97.99,41.59 102.22,45.82 v1(102.22,46.24)
  BOTTOM w0.109: v1(63.7,71.17) 64.05,71.52 U4500.AH7 ; v1(102.22,46.24) 102.66,46.67 102.66,48.13 102.66,48.13 102.66,49.07 v2(103.08,49.49) 103.89,50.3 103.89,53.25 105.45,54.81 R4682.2 107.31,54.81 U4503.4
SLEEVE: length 38.9
  TOP w0.254: U500.18 11.82,55.9 11.82,56.53 13.2,57.91 13.84,57.91 v1(13.94,57.81)
  L3 w0.762: v1(12.98,82.59) 12.98,73.69 8.89,69.6 8.89,63.6 11.99,60.5 13.94,60.5 14.61,59.83 14.61,58.48 v1(13.94,57.81)
  BOTTOM w0.381: 15.38,84.99 R600.1 15.38,85.98 R602.2
  BOTTOM w0.762: 15.38,84.99 v2(14.13,83.74) v1(12.98,82.59)
SLP_S3#: length 80.4
  L4 w0.102: v1(82.37,70.89) 83.69,70.89 84.71,71.91 87.55,71.91 97.51,61.95 100.27,61.95 103.86,65.54 103.86,69.62 104.53,70.3 104.53,95.88 106.21,97.56 106.21,98.4 106.21,99.74 107.06,100.59 107.06,101.77 107.06,103.15 v1(109.06,105.16)
  BOTTOM w0.102: v1(82.37,70.89) 82.37,71.92 v2(81.82,72.47) 80.96,73.33 79.03,73.33 77.41,74.94 77.04,74.94 U4500.B14 ; v1(109.06,105.16) 109.06,104.32 R4680.1 110.89,103.26 Q4517.1
SLP_S3#_3R: length 183.4
  TOP w0.102: v1(107.24,109.5) 106.7,110.03 106.7,117.65 104.8,119.56 103.77,119.56 102.65,120.67 v2(101.32,120.67) v1(99.06,120.67) ; U301.106 v1(71.65,159.43) ; R60003.1 80.86,107.63 v1(80.68,107.63)
  L3 w0.102: v1(110.11,137.62) 110.11,135.94 109.65,135.48 109.65,132.69 111.46,130.88 111.46,130.26 111.46,122.7 111.46,121.53 111.84,121.15 111.84,119.67 111.43,119.26 111.43,108.11 110.25,106.93 109.97,106.93 v1(109.6,106.57)
  L4 w0.102: v1(110.37,155.73) 109.52,154.89 109.52,138.91 110.11,138.33 v1(110.11,137.62) ; v1(107.24,109.5) 107.24,107.16 107.03,106.96 107.03,105.97 105.45,104.39 83.92,104.39 v1(80.68,107.63)
  BOTTOM w0.102: v1(99.06,120.67) 98.77,120.39 98.77,119.76 98.6,119.59 U60600.4 ; v1(107.24,109.5) 107.38,109.64 109.03,109.64 ; R4641.2 114.81,102.45 Q4525.3 114.29,102.97 112.38,102.97 112.04,103.32 112.04,104.61 112.04,104.61 112.04,104.78 111.73,105.09 111.73,105.38 110.55,106.57 v1(109.6,106.57) 109.03,107.14 109.03,109.64 ; Q4714.1 110.94,113.41 U4703.2 ; Q4714.1 110.06,112.5 110.06,110.23 109.47,109.64 109.03,109.64 ; Q4714.1 111.59,114.04 U4703.1 ; v1(110.37,155.73) 109.92,156.18 105.38,156.18 103.61,157.96 89.54,157.96 87.74,159.76 87.74,160.76 84.57,163.93 83.12,163.93 82.67,163.48 82.67,163.47 80.16,160.96 76.04,160.96 74.72,159.64 71.85,159.64 v1(71.65,159.43)
SLP_S3#_3R_IC: length 253.9
  TOP w0.102: R7111.1 64.84,130.94 v2(58.16,130.94) 57.08,130.94 v1(54.68,133.34)
  L4 w0.102: v1(37.89,36.37) 65.3,36.37 67.81,38.89 74.04,38.89 74.48,38.44 74.56,38.44 74.65,38.35 90.31,38.35 94.79,42.83 94.79,43.48 103.32,52.02 103.32,53.89 103.17,54.04 103.17,58.84 102.7,59.31 v1(102.7,59.37) 103.32,59.99 103.32,62.31 107.6,66.59 107.6,80.6 107.39,80.82 107.39,80.82 106.13,82.08 106.13,95.21 107.37,96.45 107.66,96.75 107.66,98.52 109.99,100.85 110.21,101.06 110.21,105.53 110.79,106.11 110.79,111.25 109.65,112.39 v1(109.65,116.42) ; v1(54.68,133.34) 56.36,135.01 58.95,135.01 59.65,134.31 64.98,134.31 68.91,138.24 68.91,141.58 69.92,142.6 71.24,142.6 72,143.36 76.33,143.36 77.42,142.26 78.77,142.26 79.49,142.98 79.49,143.56 80.51,144.59 81.12,144.59 81.43,144.28 82.12,144.28 83.31,143.08 83.31,142.07 83.55,141.83 85.44,141.83 90.32,146.71 91.23,146.71 94.73,143.22 96.03,143.22 97.92,141.32 97.92,139.24 97.84,139.04 v1(97.51,138.71)
  BOTTOM w0.102: v1(97.51,138.71) 97.87,138.35 100,138.35 100.1,138.25 100.1,135.79 100.79,135.1 101.16,135.1 101.51,134.75 101.51,133.41 102.1,132.83 102.83,132.83 103.09,132.57 R7115.1 103.7,127.86 104.16,127.41 104.16,126.27 R7112.1 103.55,125.2 104.26,124.48 104.26,121.84 104.62,121.49 104.62,119.27 105.06,118.83 105.39,118.83 107.35,116.87 U4703.4 110.29,116.61 110.1,116.42 v1(109.65,116.42) ; R7204.1 102.23,58.9 v1(102.7,59.37) ; D7200.3 33.84,35.58 R7207.1 37.1,35.58 v1(37.89,36.37)
SLP_S3_3R: length 12.4
  BOTTOM w0.102: Q4714.3 113.32,113.21 Q7114.1 114.17,112.54 R4834.2 v2(116.39,113.31) 116.83,113.76 116.83,114.97 116.21,115.59 Q7108.1 116.83,116.46 116.83,117.76 Q7106.1
SLP_S4#: length 83.6
  L4 w0.102: v1(109.62,108.88) 109.19,108.45 109.19,106.47 108.66,105.93 108.66,105.04 106.85,103.23 106.85,101.68 106.86,100.67 106.01,99.82 106.01,98.31 106.01,97.64 104.33,95.96 104.33,70.38 103.65,69.71 103.65,65.63 100.18,62.15 97.59,62.15 87.64,72.11 84.48,72.11 83.77,71.4 81.95,71.4 v3(81.68,71.13)
  BOTTOM w0.089: U4500.C12 76.32,73.28 76.9,72.7 76.9,72.46 77.26,72.11 78.41,72.11 79.62,70.89 81.05,70.89 81.29,71.13 81.38,71.13
  BOTTOM w0.102: v3(81.68,71.13) 81.38,71.13 ; Q4516.1 111.17,108.9 R4670.1 v1(109.62,108.88)
SLP_S4#_3R: length 270.8
  TOP w0.102: U301.20 79.64,148.12 79.02,147.49 79.02,146.99 79.88,146.13 v2(79.88,145.47) 79.88,144.07 81.15,142.8 85.74,142.8 88,145.06 91.68,145.06 92.26,145.63 97.6,145.63 99.92,143.31 99.92,142.09 101.49,140.52 v1(101.49,139.8) ; v1(31.34,30.81) 33.35,30.81 v1(35.1,29.06)
  L3 w0.102: v1(112.8,54) 113.35,54.55 113.35,62.66 112.68,63.32 112.68,81.39 112.68,82.21 109.7,85.19 109.7,94.08 113.29,97.67 114.33,97.67 117.17,100.51 v1(117.17,101.14)
  L4 w0.102: v1(35.1,29.06) 37.11,31.06 37.11,32.99 38.55,34.44 55.5,34.44 57.45,32.49 62.15,32.49 62.91,33.25 66.35,33.25 69.82,36.72 86.6,36.72 94.97,28.35 104.67,28.35 109.17,32.84 109.17,33.6 109.78,34.21 109.78,51.68 112.1,54 v1(112.8,54) ; v1(117.17,101.14) 117.17,102.1 115.54,103.72 115.54,106.82 v1(116.03,107.32) 116.46,107.74 116.46,124.44 115.72,125.18 115.72,137.39 v1(113.43,139.67)
  BOTTOM w0.102: R4644.2 116.83,107.32 v1(116.03,107.32) 115.6,107.32 115.31,107.03 Q4524.3 ; v1(113.43,139.67) 111.97,141.13 106.93,141.13 104.82,139.02 102.13,139.02 101.49,139.65 v1(101.49,139.8) ; v1(31.34,30.81) 28.85,33.3 28.85,38.05 31.19,40.39 34.06,40.39 Q7202.1 ; v1(35.1,29.06) R7208.1
SOC_COLD_RESET_N: length 2
  TOP w0.089: v1(68.58,70.48) 68.81,70.26 TP4535.1
  BOTTOM w0.089: v1(68.58,70.48) 68.58,70.1 U4500.Y3
SOC_SDMMC3_P1V8_EN: length 7.8
  TOP w0.089: R4811.2 73.4,66.85 74.25,66.85 v3(74.37,66.73) 77.42,66.73 R4810.2
  BOTTOM w0.089: U4500.K2 73.48,68.85 73.95,68.38 73.95,68.16 74.22,67.89 74.22,67.54 74.37,67.39 v3(74.37,66.73)
SOC_SDMMC3_PWR_EN_N: length 5.3
  TOP w0.089: v1(73.94,67.23) 74.39,67.69 v2(74.39,68.22) 74.39,68.37 R4809.2
  BOTTOM w0.089: v1(73.94,67.23) 73.94,67.79 73.59,68.14 73.18,68.14 72.39,68.93 U4500.L3
SOC_SMBCLK: length 133
  TOP w0.109: v1(91.72,151.15) 91.72,151.66 v2(91.51,151.87) 91.02,151.38 R314.2
  L3 w0.135: v1(91.72,151.15) 91.75,151.19 101.99,151.19 103.71,149.47 104.75,149.47 105.49,148.73 107.43,148.73 109.1,147.06 111.96,147.06 117.39,141.63 117.39,123.94 117.01,123.57 117.01,109.07 117.34,108.74 117.34,103.3 115.51,101.46 115.51,99.58 114.1,98.17 113.5,98.17 113.08,98.17 109.2,94.28 109.2,84.99 112.18,82.01 112.18,63.12 112.59,62.71 112.59,56 v1(111.99,55.4)
  BOTTOM w0.109: R282.1 113.23,56.64 v1(111.99,55.4) 110.84,54.25 110.84,53.08 109.49,51.73 109.49,51.51 R4591.2
SOC_SMBDAT: length 133.5
  TOP w0.109: v1(92.1,150.67) 91.47,150.04 R313.2
  L3 w0.135: v1(112.83,53.31) 112.49,53.31 110.77,55.03 v1(110.77,57.89) 111.66,58.78 111.66,81.79 108.68,84.77 108.68,94.5 112.87,98.68 113.71,98.68 113.88,98.68 114.99,99.79 114.99,101.68 115.39,102.08 115.39,104.19 116.81,105.61 116.81,108.54 116.5,108.85 116.5,123.78 116.81,124.1 116.81,130.3 116.54,130.57 116.54,141.75 111.75,146.54 108.89,146.54 107.22,148.22 105.27,148.22 104.54,148.95 101.73,148.95 100,150.67 v1(92.1,150.67)
  BOTTOM w0.109: v1(110.77,57.89) 110.77,58.3 R281.1 ; v1(112.83,53.31) 112.83,53.11 v2(112.16,52.45) 111.62,52.45 110.51,51.34 110.51,50.77 109.05,49.32 R4593.2
SOC_SMI#: length 14.1
  TOP w0.102: R4657.1 70.93,104.44 v3(71.19,104.44)
  BOTTOM w0.102: v3(71.19,104.44) 67.6,100.85 67.6,100.38 64.71,97.5 64.71,94.18 U4500.AG53
SPI_CLK: length 14.2
  TOP w0.109: v1(74.11,46.89) 73.76,46.53 73.76,45.39 v1(74.16,44.98)
  BOTTOM w0.109: v1(74.11,46.89) 74.11,47.56 72.81,48.86 72.81,49.45 72.26,50 U4701.6 ; v1(74.16,44.98) 74.16,42.39 74.55,42.01 75.35,42.01 75.91,41.45 v2(75.91,40.82) 75.91,40.03 75.38,39.5 74.84,39.5 U4702.7
SPI_CS0#: length 6.7
  BOTTOM w0.109: U4702.8 74.81,38.86 75.65,38.86 v2(76.11,39.32) 76.53,39.74 76.53,41.78 R35.1 76.06,42.19 75.63,42.63 74.93,42.63 74.8,42.75 U4701.1
SPI_HOLD: length 6.3
  BOTTOM w0.109: R4545.1 75.48,47.07 73.53,49.02 U4701.7 73.53,51.07 73.3,51.29 R4806.1
SPI_SI_IO0: length 2.4
  BOTTOM w0.109: U4701.5 70.99,51.31 R4633.1 R341.1
SPI_SO_IO1: length 3
  BOTTOM w0.109: U4701.2 73.53,42.7 72.7,41.86 R340.1 72.29,41.73 R4648.1
SPI_SOC_R_CLK: length 1.8
  BOTTOM w0.109: R4631.2 72.69,40.51 73.29,39.91 U4702.4
SPI_SOC_R_CS0#: length 1.4
  BOTTOM w0.109: U4702.3 73.43,39.46 72.31,39.46 R4807.2
SPI_WP#: length 12.2
  BOTTOM w0.109: U4701.3 72.26,43.61 72.78,44.13 72.78,44.3 72.63,44.45 72.48,44.45 72.18,44.14 72.02,44.14 71.87,44.3 71.87,44.45 72.09,44.68 72.09,44.83 71.98,44.95 71.98,45.1 72.13,45.26 72.29,45.26 72.67,44.88 72.83,44.88 72.98,45.03 72.98,45.18 72.83,45.34 72.83,45.49 72.98,45.65 73.14,45.65 73.29,45.49 73.44,45.49 73.54,45.59 74.67,45.59 74.78,45.47 74.78,44.4 74.89,44.29 75.11,44.29 75.22,44.4 75.22,45.64 75.33,45.75 75.81,45.75 R4805.1 R4546.1
SPK_OUT_L_N: length 10.4
  TOP w0.254: U500.43 11.82,48.89 12.17,48.55 v5(12.17,48.06)
  BOTTOM w0.762: v5(12.17,48.06) 12.23,48.06 12.24,48.06 12.56,48.06 12.89,47.73 15.86,47.73 v2(16.28,47.3) 17.83,45.76 R508.2
SPK_OUT_L_P: length 9.9
  TOP w0.254: v5(12.14,47.04) 11.54,47.64 11.54,48.67 11.42,48.79 U500.42
  BOTTOM w0.762: R509.2 16.68,45.46 15.43,46.71 v2(14.21,46.71) 12.46,46.71 v5(12.14,47.04)
SPK_OUT_R_L_N: length 98.2
  L3 w0.635: v5(71.93,22.66) 66.79,22.66 62.85,18.72 58.37,18.72 58.01,19.07 47.76,19.07 47.14,18.45 30.79,18.45 30.27,17.93 25.56,13.22 17.92,13.22 13.33,17.81 13.33,33.65 17.83,38.15 v5(17.83,40.47)
  BOTTOM w0.432: CN600.3 77.38,21.76 76.94,22.19 C607.2 73.01,22.19 C609.1 72.38,22.2 v5(71.93,22.66)
  BOTTOM w0.635: v5(17.83,40.47) v2(17.83,41.36) R508.1
SPK_OUT_R_L_P: length 97.7
  L3 w0.635: v5(16.68,40.87) 16.68,38.26 12.44,34.02 12.44,17.44 17.55,12.33 25.92,12.33 31.16,17.56 47.51,17.56 48.13,18.19 57.64,18.19 58,17.83 63.24,17.83 67,21.59 v5(71.9,21.59)
  BOTTOM w0.432: CN600.4 76.07,21.34 C607.1 73.93,21.33 C608.1 72.16,21.33 v5(71.9,21.59)
  BOTTOM w0.635: v5(16.68,40.87) v2(16.68,41.94) R509.1
SPK_OUT_R_N: length 6.9
  TOP w0.254: U500.44 12.22,49 12.88,48.34 12.88,47.38 13.15,47.11
  TOP w0.762: v5(14.4,45.05) 14.4,45.86 14.4,45.86 v2(13.79,46.47) 13.15,47.11
  BOTTOM w0.762: R510.2 v5(14.4,45.05)
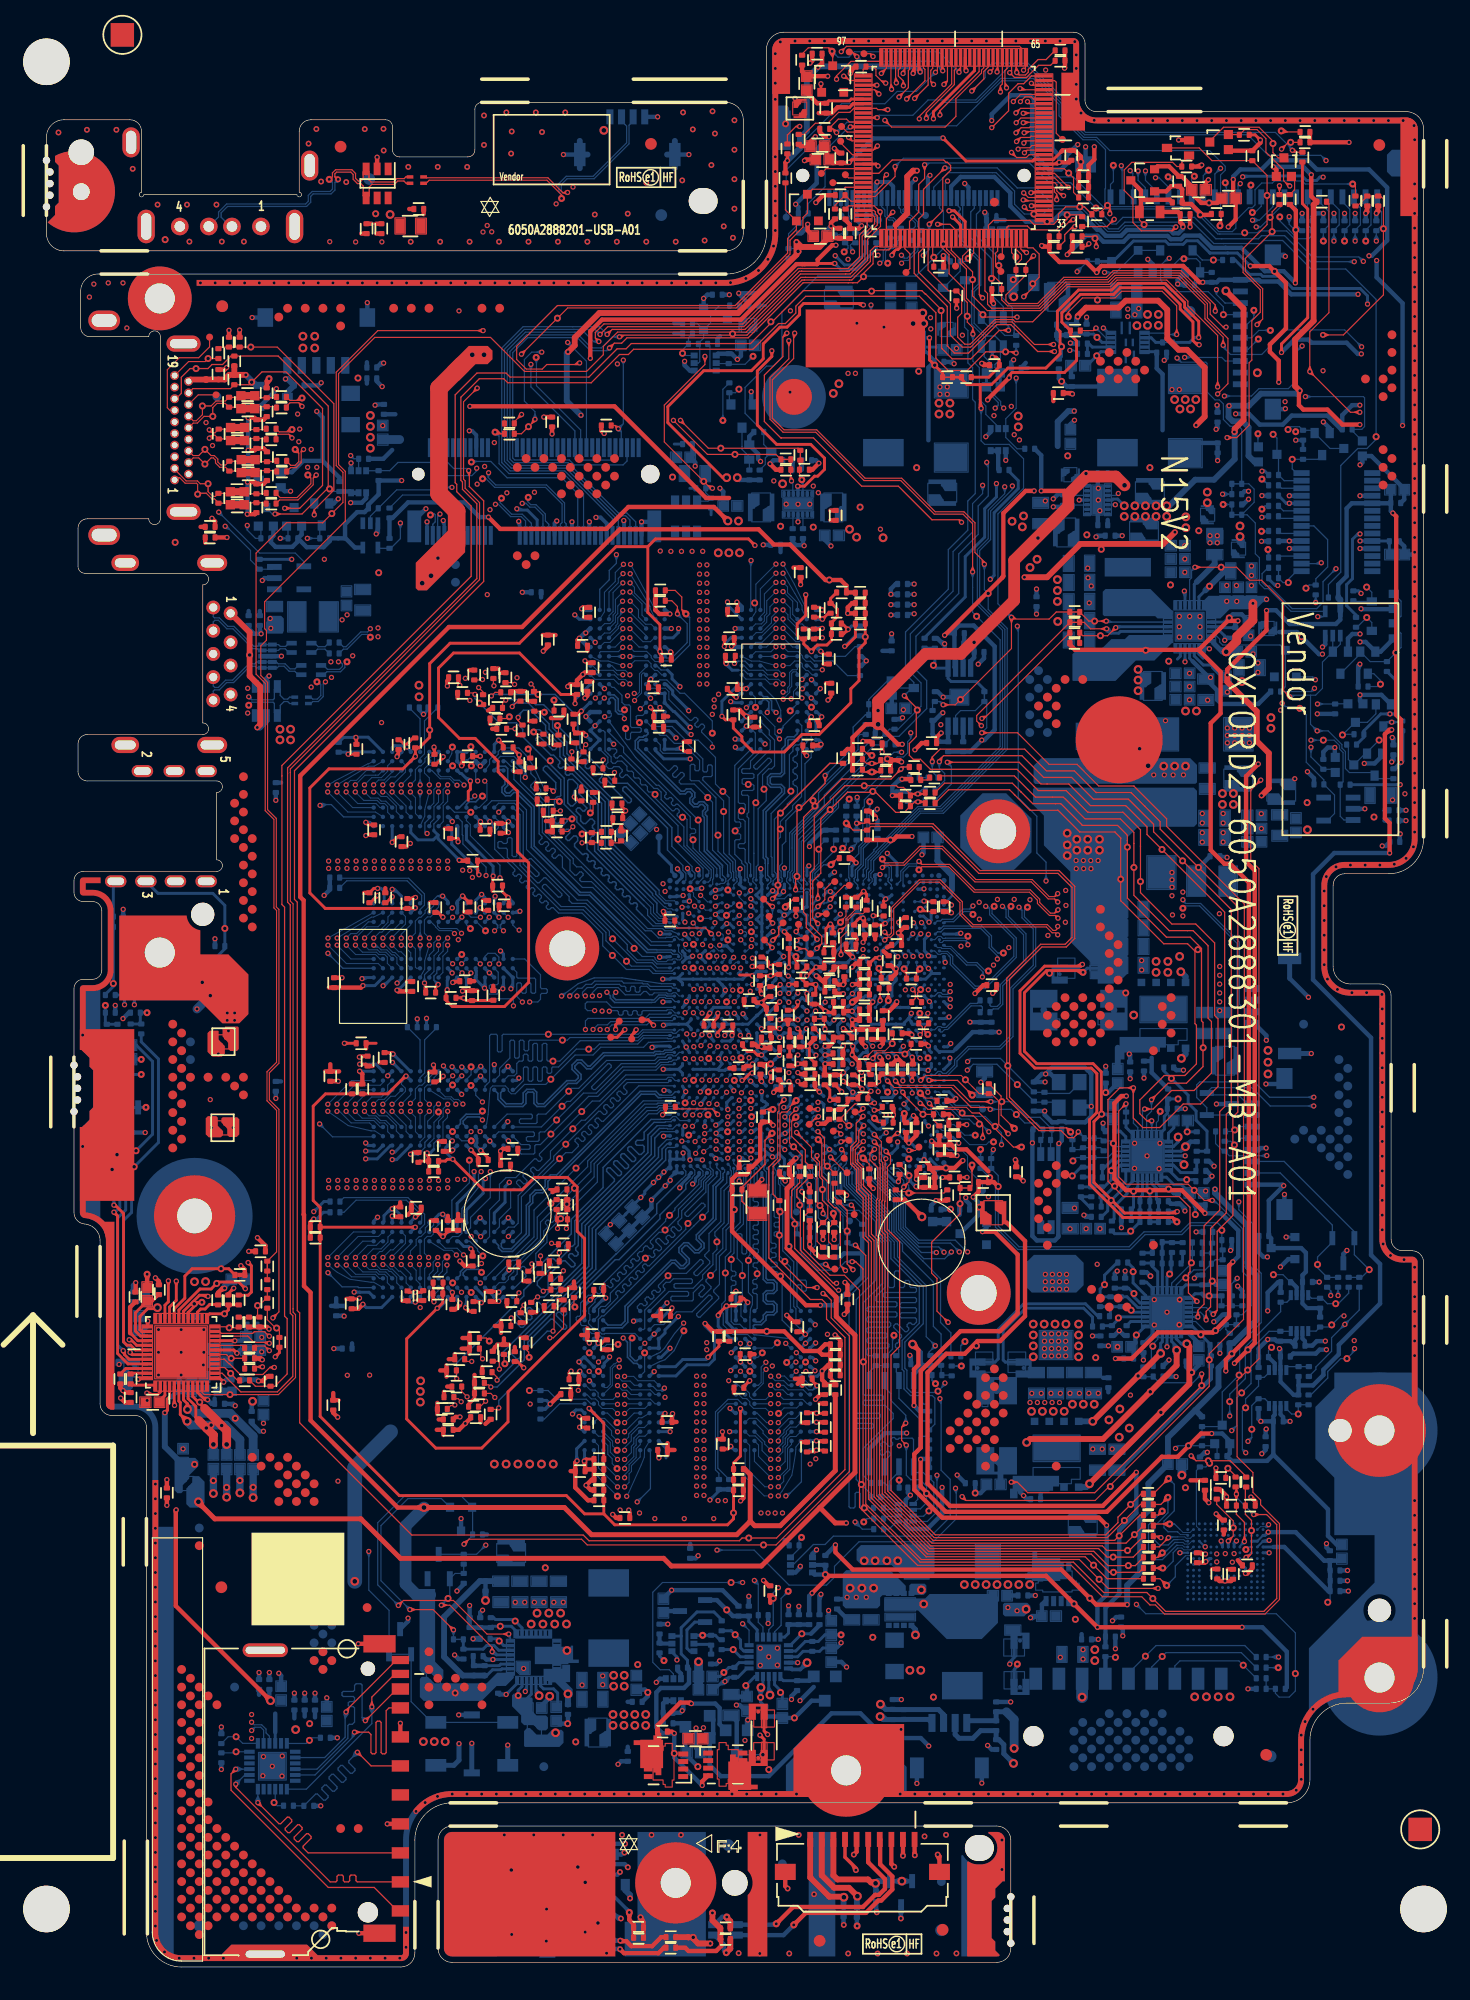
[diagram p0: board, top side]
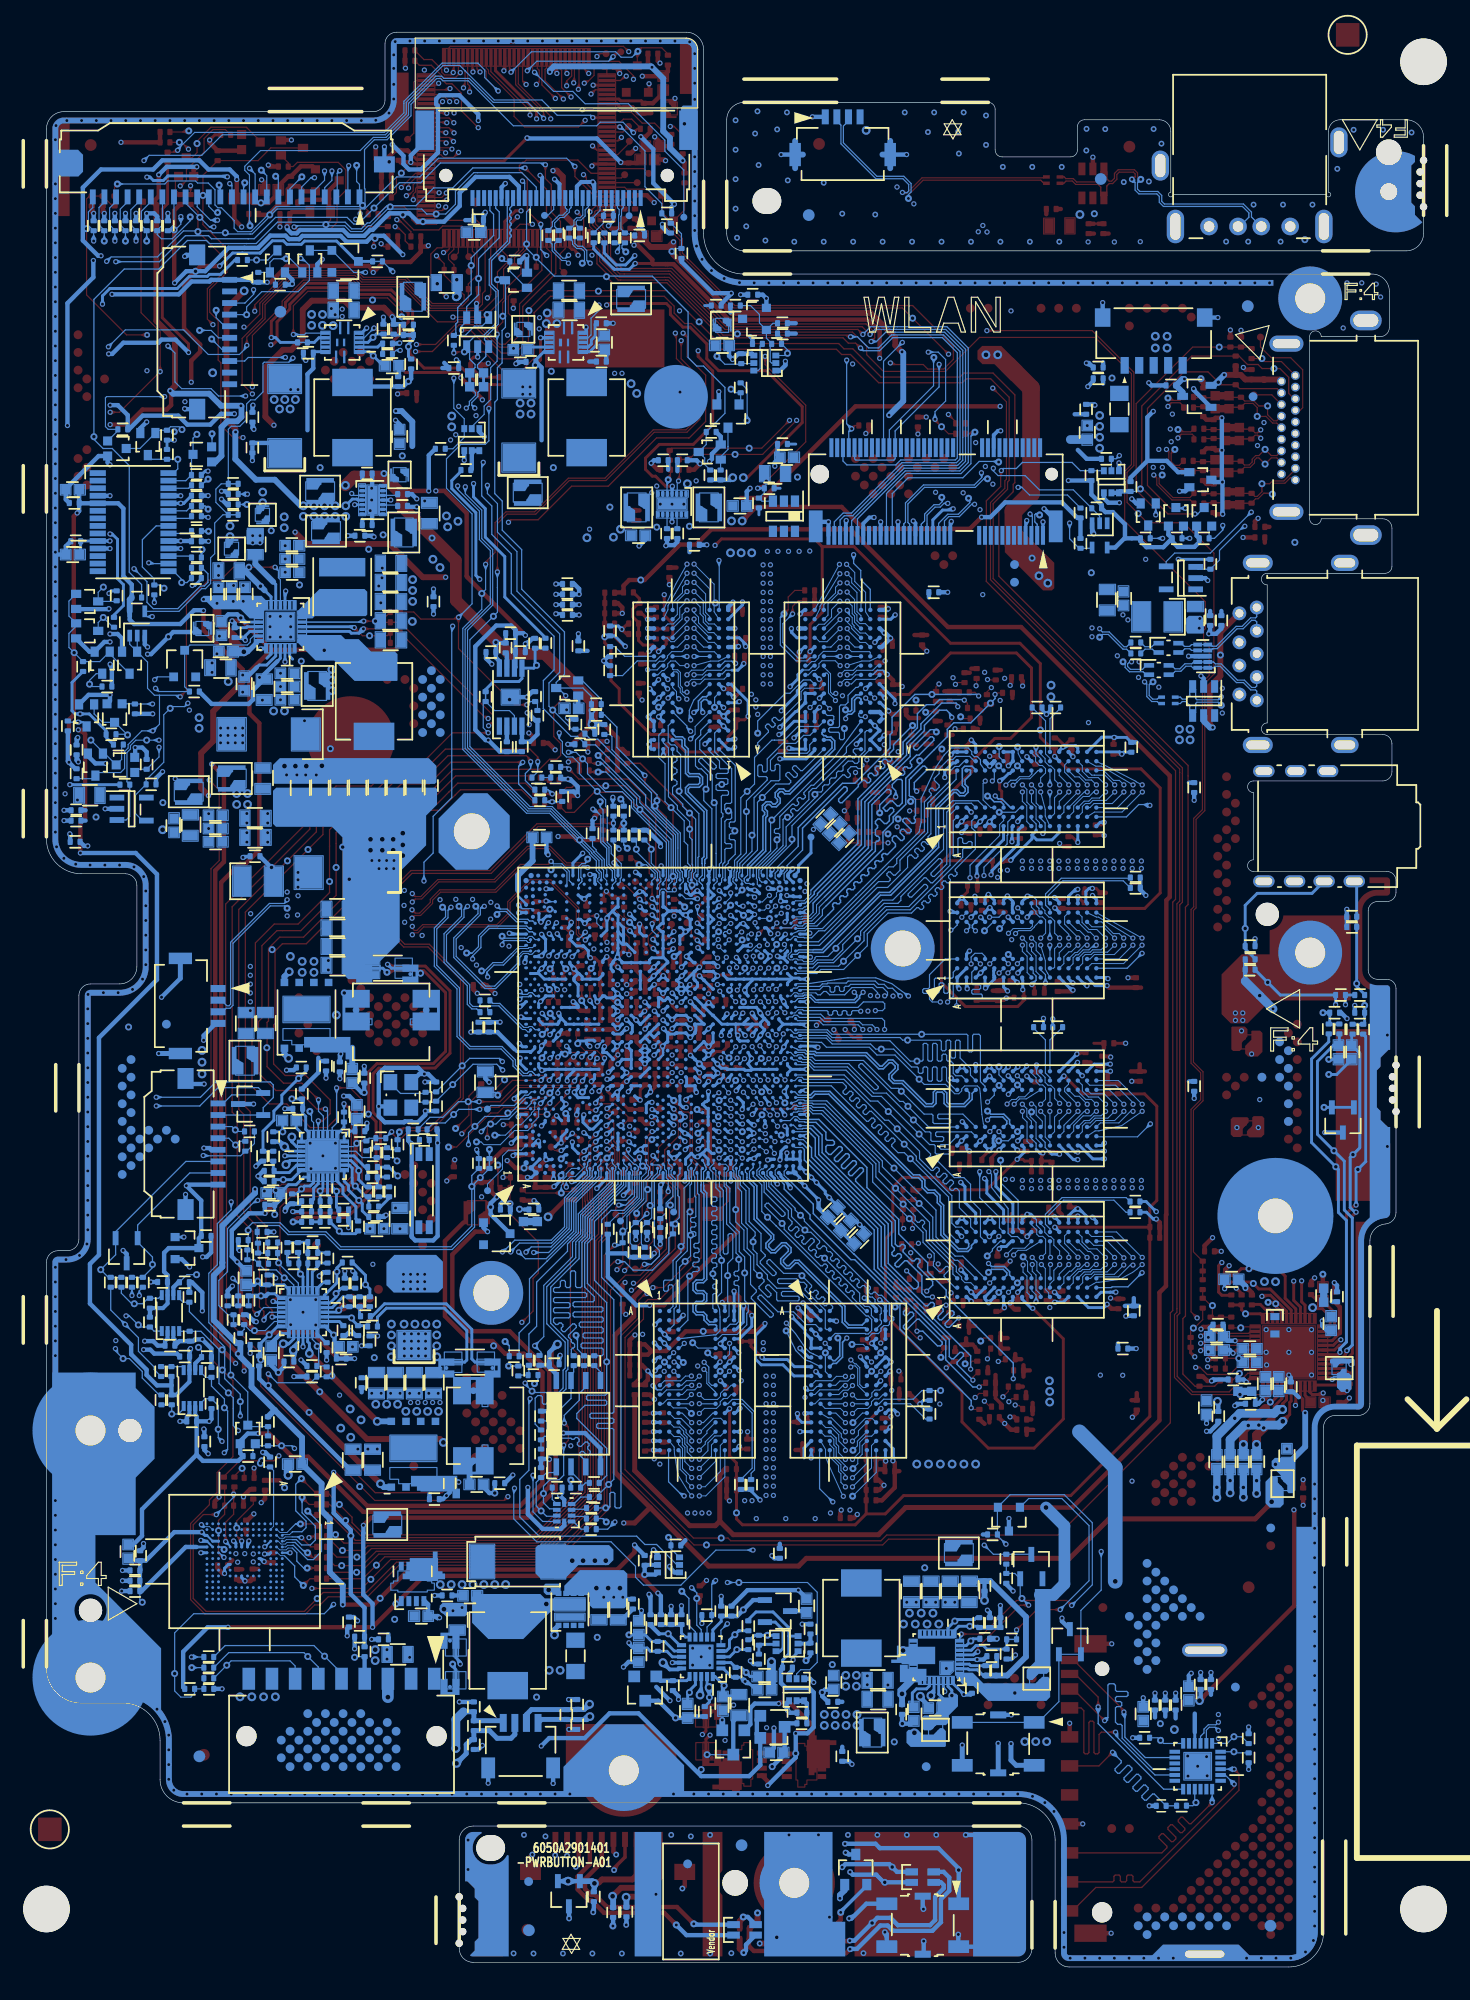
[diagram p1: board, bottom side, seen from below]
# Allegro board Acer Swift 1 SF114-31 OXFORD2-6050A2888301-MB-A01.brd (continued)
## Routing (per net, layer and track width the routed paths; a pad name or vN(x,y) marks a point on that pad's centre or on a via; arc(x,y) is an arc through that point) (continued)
SPK_OUT_R_P: length 7.2
  TOP w0.254: 13.64,48.16 12.62,49.18 U500.45
  TOP w0.762: 13.64,48.16 v2(15.11,46.68) 15.54,46.25 v5(15.54,45.05)
  BOTTOM w0.762: R511.2 v5(15.54,45.05)
SPK_OUT_R_R_N: length 116.7
  L3 w0.635: v5(14.4,40.82) 14.4,38.49 10.66,34.75 10.66,16.7 16.81,10.55 26.66,10.55 31.89,15.79 51.09,15.79 51.71,16.41 56.91,16.41 57.26,16.05 64.37,16.05 64.89,16.57 67.52,19.2 70.9,19.2 73.23,16.87 81.28,16.87 81.95,17.55 v5(83.41,17.55)
  BOTTOM w0.432: CN600.2 78.38,20.04 78.7,19.71 79.91,19.71 80.57,20.38 C606.1 C610.1 82.14,19.6 82.57,19.17 82.57,18.39 v5(83.41,17.55)
  BOTTOM w0.635: v5(14.4,40.82) v2(14.4,41.93) R510.1
SPK_OUT_R_R_P: length 114.8
  L3 w0.635: v5(83.46,18.85) 81.99,18.85 80.91,17.76 73.6,17.76 71.27,20.09 67.89,20.09 67.15,20.09 64,16.94 57.63,16.94 57.27,17.3 51.34,17.3 50.72,16.67 31.52,16.67 26.29,11.44 17.18,11.44 11.55,17.07 11.55,34.39 15.54,38.38 v5(15.54,40.5)
  BOTTOM w0.432: 81.91,21.23 79.57,21.23 CN600.1 ; 81.91,21.23 C606.2 ; 81.91,21.23 C611.1 82.8,22
  BOTTOM w0.635: v5(15.54,40.5) v2(15.54,41.34) R511.1
  BOTTOM w0.762: v5(83.46,18.85) 83.46,21.34 82.8,22
SUS_PWR_DN_ACK: length 275.3
  TOP w0.102: v1(65.15,66.85) 65.15,66.66 R4815.2 R4709.2 65.3,64.66 65.3,61.91 67.57,59.64 68.83,59.64 70.13,58.34 70.13,39.63 75.12,34.63 88.38,34.63 91.09,31.92 94.47,31.92 95.17,31.21 95.64,31.21 96.43,30.42 105.1,30.42 106.35,31.67 106.35,38.23 104.72,39.85 104.72,40.26 104.06,40.92 104.06,42.62 102.69,43.99 102.69,50.55 v2(103.61,51.46) 104.58,52.44 104.58,94.68 103.87,95.39 103.87,101.46 v1(104.73,102.32) ; v1(80.64,107.01) 80.24,107.42 80.24,107.89 R60002.1
  TOP w0.109: U301.64 84.96,163.03 84.28,162.35 83.8,162.35 82.98,161.54 82.98,160.02 v1(81.53,158.57)
  L3 w0.102: v1(104.73,102.32) 108.08,105.67 108.08,107.19 109.33,108.44 109.79,108.44 110.54,109.19 110.54,119.63 110.54,128.27 107.34,131.46 107.34,134.54 106.93,134.95 v1(106.83,134.95)
  L4 w0.102: v1(104.73,102.32) 104.92,102.51 104.92,103.88 104.61,104.19 104.05,104.19 83.66,104.19 80.85,107.01 v1(80.64,107.01) ; v1(81.53,158.57) 81.53,152.13 85.67,147.99 86,147.99 86.24,148.23 86.24,148.94 88.86,151.56 91.89,151.56 96.83,146.62 97.27,146.62 100.36,143.53 100.36,143.36 100.36,143.36 100.36,142.62 100.85,142.13 100.85,141.72 101.08,141.49 101.08,140.89 102.91,139.06 104.51,139.06 106.75,136.82 106.75,135.7 106.83,135.62 v1(106.83,134.95)
  BOTTOM w0.102: v1(65.15,66.85) 65.15,67.87 65.31,68.03 65.31,68.62 65.47,68.78 65.47,69.08 U4500.AE3
SVID_ALERT: length 24.6
  TOP w0.109: v1(66.45,87.81) 66.87,88.24 66.87,88.85 65.89,89.83 65.89,94.34 66.22,94.67 66.22,99.21 68.85,101.84 v2(70.53,101.84) 73.31,101.84 73.46,101.69 73.92,101.69 74.52,101.09 R4645.1 74.65,101.13 v1(75.15,101.13) 75.68,101.13 R4614.1
  BOTTOM w0.109: v1(75.15,101.13) 75.52,101.5 R4647.1 ; v1(66.45,87.81) 66.11,87.47 U4500.AD40
SVID_CLK: length 23.4
  TOP w0.109: v1(66.53,89.95) 66.53,89.98 66.09,90.43 66.09,93.6 66.79,94.3 66.79,98.97 67.41,99.59 67.41,99.6 v2(67.59,99.78) 69.09,101.27 71.52,101.27 73.25,99.54 73.98,99.54 R4850.1 74.89,100.45 v1(75.16,100.45) 75.68,100.45 R4592.1
  BOTTOM w0.109: v1(66.53,89.95) 66.53,89.36 U4500.AD42 ; R4596.1 75.66,100.45 v1(75.16,100.45) 74.33,100.45 R4590.1
SVID_DATA: length 23.3
  TOP w0.109: v1(66.47,88.59) 66.47,88.67 65.54,89.61 65.54,90.69 65.3,90.93 65.3,99.11 66.28,100.09 v2(66.28,100.09) 66.28,100.09 68.59,102.4 68.62,102.4 68.63,102.41 72.85,102.41 v1(73.71,103.27) 73.89,103.45 R4601.1
  BOTTOM w0.109: R4601.1 73.89,103.45 v1(73.71,103.27) ; U4500.AD41 v1(66.47,88.59)
THRM_SHUTDWN#: length 183.9
  TOP w0.102: v1(78.98,40.55) 79.31,40.22 90.45,40.22 100.29,50.06 v2(100.29,52.35) 100.29,52.87 103.25,55.82 103.25,73.4 103.32,73.47 103.32,91.63 96.62,98.33 96.62,98.98 93.81,101.79 93.79,101.81 90.75,101.81 88.89,103.68 86.48,103.68 83.76,106.4 v1(80.67,106.4)
  L4 w0.102: v1(27.8,35.82) 34.36,35.82 34.46,35.92 34.46,35.94 36.17,37.64 52.13,37.64 52.21,37.56 63.6,37.56 65.5,39.46 65.72,39.68 72.57,39.68 74.83,41.93 78.56,41.93 78.98,41.52 v1(78.98,40.55)
  BOTTOM w0.102: v1(27.8,35.82) 27.8,32.49 29.55,30.74 D500.2 D500.1 31.45,22.87 33.24,21.09 SW500.1 SW500.3 ; v1(80.67,106.4) 81.1,106.83 81.1,108.89 R4448.1 80.11,108.31 78.84,108.31 78.41,107.89 U4441.3
TP_EN#: length 140.9
  TOP w0.102: U301.123 71.47,152.63 73.19,154.35 v1(73.19,155.22)
  L4 w0.102: v1(113.59,147.04) 111.5,144.96 111.5,144.36 111.41,144.27 111.41,137.04 112.11,136.35 112.11,117.57 112.85,116.83 112.85,112.18 113.91,111.12 113.91,107.6 112.93,106.62 112.93,102.08 112.49,101.65 112.49,99.4 107.55,94.45 107.55,83.14 108.09,82.59 110.32,80.36 110.32,66.74 106.92,63.33 v1(106.92,62.93)
  BOTTOM w0.102: v1(113.59,147.04) 113.2,147.42 109.2,147.42 106.96,149.67 104.61,149.67 104.45,149.51 v2(103.35,149.51) 103.18,149.51 103.07,149.4 101.2,149.4 101.03,149.4 98.87,151.56 91.33,151.56 88.57,154.32 86.57,154.32 84.96,155.93 73.91,155.93 v1(73.19,155.22) ; Q281.1 v1(106.92,62.93)
TP_INT#: length 102.1
  TOP w0.102: v1(106.35,153.57) R312.1 R311.1 107.65,153.22 107.65,154.09 Q311.2
  L3 w0.102: v1(105.26,69.96) 106.2,70.9 106.2,79.73 103.63,82.3 103.63,96.39 104.27,97.04 104.27,98.25 105.28,99.26 105.28,102.29 108.29,105.3 108.29,106.58 109.33,107.63 109.97,107.63 110.74,108.4 110.74,119.55 110.74,119.55 110.74,129.25 107.75,132.24 v3(107.75,132.36)
  L4 w0.102: v3(107.75,132.36) 107.75,135.56 107.36,135.95 107.36,140.74 103.32,144.78 103.32,147.67 105.48,149.83 105.48,152.7 v1(106.35,153.57)
  BOTTOM w0.102: v1(105.26,69.96) 105.23,69.94 102.02,69.94 R285.1 101.49,70.34 100.84,70.99 R286.1
TP_INT#_SOC: length 118.4
  TOP w0.102: Q310.2 102.86,157.98 102.86,157.98 R310.1 103.34,158.4 104.41,158.4 105.18,157.63 105.18,156.46 106.7,154.94 106.7,154 107.16,153.54 v1(107.24,153.54)
  L4 w0.102: v1(73.76,104.72) 73.83,104.72 75.06,105.95 77.98,105.95 80.13,108.1 81.25,108.1 84.76,104.6 105.37,104.6 106.83,106.06 106.83,107.09 107.01,107.26 107.01,109.14 106.83,109.32 106.83,110.21 107.08,110.46 107.08,119.21 103.98,122.31 103.98,125.98 104.31,126.31 104.31,127.64 104.02,127.93 104.02,133.5 102.09,135.43 v1(101.6,135.43) ; v1(107.24,153.54) 106.99,153.3 106.99,151.92 108.3,150.61 v1(108.3,139.75)
  BOTTOM w0.102: U4500.AE51 65.59,93.49 65.4,93.68 65.4,93.83 65.3,93.92 65.3,94.42 65.31,96.95 68.32,99.96 68.32,100.53 69.11,101.32 70.56,101.32 72.11,102.87 72.11,103.73 v2(72.53,104.16) 73.1,104.72 v1(73.76,104.72) ; v1(101.6,135.43) 103.93,135.43 104.57,136.07 107.11,136.07 107.69,136.65 107.69,139.14 v1(108.3,139.75)
TPM_CLKRUN: length 3.6
  BOTTOM w0.109: R3510.2 R3513.1 106.65,119.35 v2(107.11,119.35) 107.11,119.62 107.83,120.34 U3500.15
TPM_LPC_AD<0>: length 2.1
  BOTTOM w0.109: R3506.2 106.51,127.49 U3500.26
TPM_LPC_AD<1>: length 2.2
  BOTTOM w0.109: R3505.2 106.68,125.54 U3500.23
TPM_LPC_AD<2>: length 2.1
  BOTTOM w0.109: R3504.2 106.48,123.59 U3500.20
TPM_LPC_AD<3>: length 2
  BOTTOM w0.109: U3500.17 106.39,121.64 R3503.2
TPM_LPC_CLK: length 8
  BOTTOM w0.109: U3500.21 109.31,124.24 110.5,123.05 110.5,120.7 109.49,119.69 109.49,119.16 R3509.2 108.91,119.14 v2(108.64,118.87)
TPM_LPC_FRAME#: length 2.1
  BOTTOM w0.109: U3500.22 106.45,124.89 R3507.2
TPM_LPCPD#: length 4.5
  BOTTOM w0.109: Q3502.3 109.67,129.98 R3516.2 v2(107.45,129.98) 107.45,129.15 107.81,128.79 U3500.28
TPM_SERIRQ: length 5.9
  BOTTOM w0.109: v2(105.8,132.13) 106.13,131.8 Q3500.3 106.27,130.27 R3511.1 106.75,128.14 U3500.27
TSENSE: length 3.6
  BOTTOM w0.254: R6612.1 99.21,68.7 C6646.1 98.99,68.49 97.84,68.49 97.19,69.13 U6600.13
UNNAMED_5_BEADSINGLE_I57_INA: length 1.6
  BOTTOM w0.381: C6000.1 69.13,29.93 C7604.1
  vias: v2(71.27,28.42)
UNNAMED_5_BEADSINGLE_I76_INA: length 0.9
  BOTTOM w0.381: 27.64,136.51 C7601.1 ; C7602.1 27.64,138.34
  vias: v2(26.87,136.98)
UNNAMED_5_CN09_I103_4: length 2.8
  BOTTOM w0.102: R6055.2 92.14,26.75 v2(92.2,26.69)
  BOTTOM w0.381: CN6050.4 91.34,24.86 R6055.2
UNNAMED_5_CN09_I103_5: length 12.9
  BOTTOM w0.109: CN6050.5 93.32,25.33 v2(94.79,26.79) 95.7,27.71 103.36,27.71 R6052.2
UNNAMED_5_CN09_I103_6: length 11.1
  BOTTOM w0.109: R6050.2 103.05,27.1 96.57,27.1 v2(96.23,26.77) 95.32,25.86 CN6050.6
UNNAMED_5_CN09_I103_7: length 8.9
  BOTTOM w0.102: CN6050.7 97.32,25.95 97.76,26.39 102.85,26.39 v2(103.22,26.02) R6051.2
UNNAMED_5_POWERINDUCTOR_I49_2:
  vias: v2(76.5,23.27)
UNNAMED_5_RSC0805_I51_B: length 5.8
  BOTTOM w0.102: D6000.3 v2(61.8,18.31)
  BOTTOM w0.381: R6012.2 59.53,21.2 D6000.3
UNNAMED_6_CSC0402_I64_A: length 3.2
  BOTTOM w0.254: C6166.1 87.12,140.69 R6167.2 87.13,140.33 87.55,139.9 v2(87.55,139.69) 87.55,138.85 R6166.2
UNNAMED_6_CSC0805_I6_A:
  vias: v2(90.65,143.71)
UNNAMED_6_CSC0805_I27_A:
  vias: v2(71.17,144.47)
UNNAMED_8_CSC0402_I24_A: length 4.2
  BOTTOM w0.254: U6600.7 96.13,71.93 96.42,72.21 96.42,73.33 96.67,73.59 C6647.1 ; R6660.2 v2(97.6,74.84)
  BOTTOM w0.381: C6647.1 96.67,74.76 R6660.2
UNNAMED_8_CSC0402_I35_A: length 3
  BOTTOM w0.109: R6666.2 90.95,71.45 C6618.1 91.8,71.22 v2(92.02,71) 92.29,70.73 U6600.27
UNNAMED_8_CSC0402_I35_B: length 2.9
  BOTTOM w0.109: R6663.2 89.11,70.47 89.27,70.63 C6649.1 R6659.1 90.92,70.63 C6618.2
UNNAMED_8_CSC0402_I36_B: length 4.9
  BOTTOM w0.109: U6600.26 92.09,70.33 91.55,69.78 R6659.2 C6649.2 88.82,69.78 v2(88.54,69.49)
UNNAMED_8_CSC0402_I40_A: length 2.1
  BOTTOM w0.254: R6619.1 90.22,68.96 C6613.1 89.23,68.96 v2(88.48,68.2)
UNNAMED_8_CSC0402_I40_B: length 7.1
  BOTTOM w0.254: C6617.1 89.23,67.25 R6654.1 ; C6617.1 90.23,67.36 R6616.2 90.19,68.1 C6613.2 ; C6617.1 90.12,67.25 C6614.1 91.23,67.25 91.84,67.87 v2(91.84,68.65) 91.84,68.86 92.51,69.53 U6600.24
UNNAMED_8_CSC0402_I41_B: length 2.2
  BOTTOM w0.254: R6618.2 89.94,65.56 89.23,66.27 R6654.2 C6617.2
UNNAMED_8_CSC0402_I44_B: length 4.8
  BOTTOM w0.254: U6600.23 92.66,69.13 92.4,68.87 92.4,67.59 v2(92.14,67.33) 91.22,66.4 C6614.2 90.97,66.37 R6618.1
UNNAMED_8_CSC0402_I52_A: length 3.2
  BOTTOM w0.254: U6600.17 95.33,67.53 95.73,67.13 95.73,66.2 C6616.1 R6647.1
UNNAMED_8_CSC0402_I57_A: length 6.9
  BOTTOM w0.254: R6633.1 92.13,63.22 93.3,63.22 v2(93.52,63.44) R6651.2 94.31,64.24 C6639.1 C6640.1 94.31,66.32 94.31,66.33 94.53,66.55 U6600.19
UNNAMED_8_CSC0402_I57_B: length 4.7
  BOTTOM w0.254: U6600.18 94.93,67.14 v2(95.17,66.9) 95.17,66.02 C6640.2 C6639.2 95.16,64.24 R6651.1 R6649.1
UNNAMED_8_CSC0402_I58_A: length 3.9
  BOTTOM w0.254: U6600.20 94.13,67.24 v2(93.76,66.87) 93.76,65.5 C6645.1 R6655.1
UNNAMED_8_CSC0603_I70_A: length 5.1
  BOTTOM w0.254: C6643.1 97.89,67.44 97.24,67.44 96.59,68.09 U6600.15 ; R6665.1 v2(99.09,64.87)
  BOTTOM w0.381: C6643.1 98.61,66.19 R6665.1
UNNAMED_8_NCP81101BMNTXG_I71_14: length 2.8
  BOTTOM w0.254: R6650.1 99,67.87 99,67.88 v2(98.35,67.88) 97.62,67.88 U6600.14
UNNAMED_8_NCP81101BMNTXG_I71_16: length 2.7
  BOTTOM w0.254: U6600.16 95.73,67.63 96.04,67.33 96.53,67.33 v2(96.78,67.07) 97.21,66.64 R6646.1
UNNAMED_8_NCP81101BMNTXG_I71_21: length 4.5
  BOTTOM w0.254: R6633.2 92.09,64.5 92.09,65.55 93.2,66.66 93.2,67.25 93.73,67.77 U6600.21
UNNAMED_8_NCP81101BMNTXG_I71_22: length 5
  BOTTOM w0.254: U6600.22 93.09,67.74 92.72,67.37 92.72,66.98 v2(91.83,66.09) 91.53,65.79 91.53,65.19 91.02,64.67 R6652.2
UNNAMED_8_NCP81101BMNTXG_I71_25: length 3.3
  BOTTOM w0.254: U6600.25 92.26,69.93 91.29,68.96 R6619.2 91.07,68.08 R6616.1
UNNAMED_8_RSC0402_I48_A: length 9.7
  BOTTOM w0.254: R6661.1 96.37,77.26 v2(97.03,76.6) 98.47,75.16 98.47,74.47 99.16,73.79 99.16,73 100.1,72.06 R6658.1 100.1,70.32 R6612.2
UNNAMED_9_CSC0402_I14_A: length 2.2
  BOTTOM w0.381: C7661.1 v2(91.36,75.39) 91.58,75.39 R7661.2
UNNAMED_9_IDUT4PIN_I34_2:
  vias: v2(86.51,85.67)
UNNAMED_10_CSC0402_I24_A: length 3.6
  BOTTOM w0.254: U6700.7 98.82,55.25 v2(99.56,54.5) 100.36,53.71 C6747.1
  BOTTOM w0.381: R6760.2 100.36,52.74 C6747.1
UNNAMED_10_CSC0402_I35_A: length 5.4
  BOTTOM w0.109: U6700.27 97.45,58.79 98.07,59.41 v2(98.27,59.41) 98.96,60.1 99.94,60.1 C6718.1 100.81,60.97 R6766.2
UNNAMED_10_CSC0402_I35_B: length 2.7
  BOTTOM w0.109: C6749.1 99.69,60.69 C6718.2 ; C6749.1 99.69,61.55 R6763.2 ; C6749.1 R6759.1
UNNAMED_10_CSC0402_I36_B: length 4.9
  BOTTOM w0.109: U6700.26 97.05,58.65 97.05,58.95 98.75,60.65 v2(98.75,60.71) 98.84,60.79 C6749.2 R6759.2
UNNAMED_10_CSC0402_I40_A: length 1
  BOTTOM w0.254: C6713.1 97.99,60.79 R6719.1
UNNAMED_10_CSC0402_I40_B: length 6
  BOTTOM w0.254: U6700.24 96.25,60.64 C6714.1 C6717.1 R6754.1 97.04,62.48 R6716.2 C6713.2
UNNAMED_10_CSC0402_I41_B: length 1.8
  BOTTOM w0.254: R6718.2 94.57,61.57 C6717.2 R6754.2
UNNAMED_10_CSC0402_I44_B: length 3.4
  BOTTOM w0.254: R6718.1 95.35,60.69 C6714.2 95.38,60.39 95.85,59.93 U6700.23
UNNAMED_10_CSC0402_I51_A: length 4.1
  BOTTOM w0.254: R6747.1 91.15,55.29 91.15,55.29 C6716.1 92.46,55.85 v2(92.46,55.96) 92.55,56.05 U6700.17
UNNAMED_10_CSC0402_I56_A: length 7.9
  BOTTOM w0.254: R6733.1 92.35,60.73 91.26,59.64 v2(91.26,58.83) 90.88,58.44 R6751.2 91.76,57.78 C6739.1 C6740.1 93.19,57.78 94.13,56.85 U6700.19
UNNAMED_10_CSC0402_I56_B: length 5
  BOTTOM w0.254: R6749.1 91.77,56.19 C6739.2 ; C6739.2 C6740.2 93.25,56.93 v2(93.56,56.62) 93.73,56.45 U6700.18 ; C6739.2 91.76,56.93 R6751.1
UNNAMED_10_CSC0402_I57_A: length 3.4
  BOTTOM w0.254: U6700.20 94.32,57.25 93.8,57.77 v2(93.8,58.05) 93.32,58.53 C6745.1 R6755.1
UNNAMED_10_CSC0603_I49_A: length 3.4
  BOTTOM w0.254: v2(94,54.48) 94.77,55.25 U6700.15
  BOTTOM w0.381: R6765.1 93.77,53.26 C6743.1 93.93,53.83 93.93,54.41 v2(94,54.48)
UNNAMED_10_NCP81101BMNTXG_I71_1: length 1.2
  BOTTOM w0.254: U6700.14 94.65,53.82 R6750.1
UNNAMED_10_NCP81101BMNTXG_I71_2: length 1.8
  BOTTOM w0.254: R6746.1 93.52,55.65 U6700.16
UNNAMED_10_NCP81101BMNTXG_I71_3: length 3.7
  BOTTOM w0.254: R6733.2 93.72,60.27 v2(93.72,59.94) 93.72,58.98 94.81,57.9 U6700.21
UNNAMED_10_NCP81101BMNTXG_I71_4: length 1.3
  BOTTOM w0.254: R6752.2 94.88,59.04 95.45,58.47 U6700.22
UNNAMED_10_NCP81101BMNTXG_I71_5: length 3.5
  BOTTOM w0.254: U6700.25 96.65,59.51 v2(96.87,59.74) 97.01,59.87 R6719.2 97.01,61.53 R6716.1
UNNAMED_10_RSC0402_I48_A: length 28.1
  TOP w0.109: v1(83.21,41.8) 83.73,41.8 84.64,40.89 90.41,40.89 99.64,50.11 v2(99.64,50.12) v1(99.64,51.13)
  BOTTOM w0.109: R6712.2 95.44,50.88 R6758.1 95.99,50.37 98.88,50.37 v1(99.64,51.13) ; R6761.1 83.52,42.11 v1(83.21,41.8)
UNNAMED_11_CSC0402_I7_A: length 2.3
  BOTTOM w0.381: R7761.2 81.08,41.38 80.57,40.86 v2(80.11,40.86) 80.11,41.7 C7761.1
UNNAMED_11_IDUT4PIN_I27_2:
  vias: v2(80.21,53.55)
UNNAMED_12_CSC0402_I17_A: length 75
  TOP w0.102: R7252.1 87.09,116.81 86.48,116.2 83.39,116.2 v1(83.23,116.36) 83.23,113.66 v2(78.83,109.26) 78.38,108.81 v1(77.34,108.81)
  TOP w0.254: R7206.2 R7230.1 78.92,136.9 79.4,136.42 80.54,136.42 ; v1(99.38,140.47) 99.38,141.86 98.17,143.08 98.17,143.49 96.51,145.15 92.46,145.15 91.88,144.58 89.02,144.58 87.2,142.75 87.2,141.22 87.43,140.99 87.43,139.07 86.2,137.85 82.93,137.85 81.5,136.42 80.54,136.42 ; 80.54,136.42 80.54,134.44 v1(80.62,134.37)
  BOTTOM w0.102: v1(83.23,116.36) 82.06,117.53 82.06,125.27 84.27,127.48 84.27,130.02 83.03,131.27 80.92,131.27 80.62,131.57 80.62,131.58 v1(80.62,134.37) ; R7256.2 76.43,108.89 76.43,108.89 C7205.1 77.06,109.1 v1(77.34,108.81)
  BOTTOM w0.254: v1(99.38,140.47) 99.01,140.47 98.59,140.06 R7241.2
UNNAMED_12_CSC0603_I125_A: length 5.1
  BOTTOM w0.381: v2(56.18,17.27) 55.23,18.23 C60013.1 55.11,18.61 D60002.3 54.8,21.01 R60017.1
UNNAMED_12_DDUALSERIESA_I130_A1: length 4.1
  BOTTOM w0.254: D60003.1 55.92,29.73 55.24,29.06 55.24,27.48 55.5,27.23 Q60003.3
UNNAMED_12_DDUALSERIESA_I130_C: length 1.5
  BOTTOM w0.381: D60003.3 53.35,30.68 R60021.2
UNNAMED_12_NMOSDUALC_I66_D1: length 3.1
  BOTTOM w0.356: Q7214.5 67.14,34.66 R7246.1
  BOTTOM w0.381: Q7214.6 66.25,33.83 v2(67.18,33.83) R7246.1
UNNAMED_12_NMOSDUALC_I91_D1: length 2.7
  BOTTOM w0.381: Q60002.5 Q60002.6 53.19,22.72 53.19,22.72 R60018.1 53.19,21.92 53.19,21.01 R60017.2
UNNAMED_12_NMOSDUALC_I91_D2: length 1.1
  BOTTOM w0.381: Q60002.3 54.72,25.28 54.44,25.57 54.44,25.57 R60022.2
UNNAMED_12_NMOSDUALC_I113_G1: length 2.3
  BOTTOM w0.254: Q60003.2 55.91,27.81 57.26,27.81 R60020.2 R60019.1
UNNAMED_12_NMOSDUALC_I113_G2: length 1.9
  BOTTOM w0.356: R60024.1 R60023.2 52.93,27.88 Q60003.5
UNNAMED_13_CSC0603_I58_A:
  vias: v2(96.95,119.15)
UNNAMED_13_CSC0603_I80_A: length 1
  BOTTOM w0.254: U60600.20 97.8,113 97.55,112.75
  vias: v2(96.8,112.57)
UNNAMED_13_RSC0402_I94_B: length 9
  TOP w0.102: v1(92.22,115.47) 91.53,114.77 v2(90.91,114.77) 89.38,114.77 R60003.2 R60000.2
  BOTTOM w0.254: v1(92.22,115.47) 92.3,115.54 U60600.25
UNNAMED_13_RSCSHORT_I99_B: length 8.1
  TOP w0.102: R60002.2 89.5,115.93 90.06,115.37 v1(91.44,115.37)
  BOTTOM w0.254: v1(91.44,115.37) 91.82,114.99 92.48,114.99 92.64,115.14 U60600.24
UNNAMED_15_APL3523A_I201_3: length 13.3
  L3 w0.102: v1(101.44,126.97) 100.95,126.49 100.95,125.87 100.48,125.4 99.25,125.4 97.62,127.03 v1(92.45,127.03)
  BOTTOM w0.102: v1(101.44,126.97) C7116.1 102.24,126.98 R7115.2 ; v1(92.45,127.03) 92.28,126.87 U7100.3
UNNAMED_15_APL3523A_I201_5: length 13
  L3 w0.102: v1(92.19,126.07) 92.19,126.2 92.82,126.83 97.54,126.83 99.17,125.2 99.34,125.2 100.56,125.2 101.45,126.09 v3(101.49,126.09)
  BOTTOM w0.102: U7100.5 v1(92.19,126.07) ; v3(101.49,126.09) C7125.1 102.24,126.08 R7112.2
UNNAMED_15_APL3523A_I201_8:
  vias: v2(89.74,123.47)
UNNAMED_15_APL3523A_I201_10: length 1.3
  BOTTOM w0.102: U7100.10 89.73,126.03 88.56,126.03 C7101.1
UNNAMED_15_APL3523A_I201_12: length 1.3
  BOTTOM w0.102: C7122.1 88.59,126.87 89.75,126.87 U7100.12
UNNAMED_15_APL3523A_I201_13:
  vias: v2(89.66,128.75)
UNNAMED_15_APL3523A_I202_3: length 3.1
  TOP w0.102: v1(64.26,128.11) 64.18,128.19 64.18,129.06 C13.1 64.2,129.97 R7110.2
  BOTTOM w0.102: U7102.3 64.37,127.05 64.37,128 v1(64.26,128.11)
UNNAMED_15_APL3523A_I202_5: length 3.1
  TOP w0.102: R7111.2 64.95,129.83 C7111.1 64.95,128.42 v3(65.15,128.22)
  BOTTOM w0.102: U7102.5 65.25,127.03 65.25,128.12 v3(65.15,128.22)
UNNAMED_15_APL3523A_I202_8:
  vias: v2(66.14,124.13)
UNNAMED_15_APL3523A_I202_10: length 1.2
  BOTTOM w0.102: C7100.1 65.25,125.19 U7102.10
UNNAMED_15_APL3523A_I202_12: length 1.2
  BOTTOM w0.102: C7109.1 64.39,124.02 64.39,125.19 U7102.12
UNNAMED_15_APL3523A_I202_13:
  vias: v2(63.32,124.21)
UNNAMED_15_NMOS_I179_D: length 2.6
  BOTTOM w0.102: Q7108.3 114.31,115.9 v2(113.88,116.34) 113.03,115.5 R29.2
UNNAMED_15_NMOS_I184_D: length 2.8
  BOTTOM w0.102: R28.2 114.86,110.39 v2(115.06,110.59) 115.06,110.92 114.48,111.5 Q7114.3
UNNAMED_15_NMOS_I189_D: length 2.9
  BOTTOM w0.102: Q7120.3 99.68,147.16 99.69,147.16 v2(100.65,147.16) R7125.2
UNNAMED_15_NMOS_I194_D: length 3
  BOTTOM w0.102: R7109.2 112.78,117.73 Q7106.3 114.31,118.52 v2(113.87,118.96)
UNNAMED_16_505030084N001_I222_3: length 2.5
  BOTTOM w0.102: R286.2 102.36,72.03 v2(102.49,72.16) 102.77,72.45 CN281.3
UNNAMED_16_505030084N001_I222_4: length 2.7
  BOTTOM w0.102: R285.2 102.14,71.19 v2(102.46,70.87) 103.05,71.45 CN281.4
UNNAMED_20_CSC0402_I15_A: length 3.1
  BOTTOM w0.102: C904.1 22.91,19.76 v2(22.68,19.54) 22.42,19.27 20.74,19.27 U900.6
UNNAMED_20_CSC0402_I20_A: length 2.5
  BOTTOM w0.102: U900.24 v2(16.35,18.55) 16.26,18.46 16.26,18.46 C901.1
UNNAMED_21_APCI0062P001A_I66_PE: length 16.6
  TOP w0.102: R1306.1 39.5,132.18 R1302.2 38.84,132.18 v3(38.69,132.32)
  BOTTOM w0.102: v3(38.69,132.32) 39.04,131.98 39.04,129.6 39.9,128.75 44.6,128.75 46.32,127.02 CN1300.55
UNNAMED_24_CSC0402_I46_A: length 4.1
  TOP w0.381: 101.55,37.28 C3955.1 ; 102.75,35.07 C3954.1 ; C3956.1 98.67,41.96 ; 101.89,34.28 C3957.1 ; 100.54,34.31 D3950.1
  BOTTOM w0.762: R3966.1 v5(97.93,42.4)
  vias: v1(100.94,35.61) v1(100.94,34.92) v1(101.67,35.64) v1(102.28,34.9) v1(102.44,35.64) v2(98.24,41.32)
UNNAMED_24_CSC0402_I53_A: length 28.2
  TOP w0.381: C3952.1 99.57,35.71 99.67,35.6 v1(99.96,35.6)
  L4 w0.381: v1(105.38,37.49) 101.31,37.49 100.73,36.92 100.73,36.19 100.14,35.6 v1(99.96,35.6)
  BOTTOM w0.102: D3951.1 110.72,31.65 v2(110.51,31.44)
  BOTTOM w0.178: U3950.N4 U3950.P3
  BOTTOM w0.254: U3950.M4 U3950.N4 ; U3950.C6 99.54,35.6 v1(99.96,35.6) ; 105.84,36.21 U3950.P5 ; v1(105.38,37.49) 105.1,37.21 U3950.P3
  BOTTOM w0.381: C3953.1 111.55,35.03 R3964.1 ; C3953.1 110.2,35.03 107.74,37.49 v1(105.38,37.49) ; C3953.1 110.69,34.21 C3951.1 C3950.1 D3951.1 110.57,32.41 106.76,36.21 105.84,36.21
UNNAMED_24_CSC0402_I63_A: length 6.6
  BOTTOM w0.076: 99.18,38.56 99.18,38 99.43,37.74 U3950.C2
  BOTTOM w0.102: v2(100.32,43.43) 100,43.11 C3959.1 99.18,42.8 99.18,38.56
UNNAMED_24_RSC0402_I92_A: length 4.9
  TOP w0.102: v1(101.93,36.73) 102.36,37.15 v2(102.36,37.86) 102.36,38.45 100.94,39.88 R3965.1
  BOTTOM w0.254: U3950.H5 v1(101.93,36.73)
UNNAMED_24_RSC0402_I113_A: length 1.9
  TOP w0.109: R3950.1 101.72,42.81 v2(101.9,42.99) 102.56,42.33 R3963.1
UNNAMED_25_NMOS_I248_D: length 5.7
  BOTTOM w0.102: v2(107.09,132.54) 107.33,132.79 108.07,132.79 108.38,132.48 R3515.1 109.14,132.48 Q3502.1 110.71,130.91 Q3501.3
UNNAMED_27_099A4AC19HBLBNF_I1_1: length 2.7
  TOP w0.102: CN3150.14 13.09,135.53 TP3151.1
UNNAMED_27_099A4AC19HBLBNF_I1_2: length 4.4
  TOP w0.102: CN3150.19 12.26,138.4 13.68,138.4 v2(13.94,138.67) R3154.2
UNNAMED_27_099A4AC19HBLBNF_I126: length 9.3
  TOP w0.102: CN3150.13 10.65,134.2 10.43,134.42 10.43,137.7 11.46,138.73 13.13,138.73 14.07,139.67 TP3152.1
UNNAMED_27_NMOS_I117_D: length 20.7
  TOP w0.381: v1(17.35,128.02) 17.95,128.02 R3158.2 18.73,127.86 R3159.2 ; v1(17.32,125.25) 17.97,125.25 R3157.2 ; R3160.2 18.73,130.92 R3161.2 17.95,130.76 v1(17.4,130.76) ; v1(17.4,133.55) 17.95,133.55 R3162.2 18.73,133.39 R3164.2 ; v3(19.2,136.93) 19,136.73 R3163.2
  L3 w0.381: v3(19.2,136.93) 17.4,135.13 v1(17.4,133.55)
  BOTTOM w0.381: v1(17.35,128.02) 17.35,125.27 v1(17.32,125.25) ; v1(17.35,128.02) 17.4,128.07 v1(17.4,130.76) v1(17.4,133.55) ; v1(17.35,128.02) 18.1,128.02 Q3152.3
UNNAMED_29_H5TC4G63AFR_I114_NC4: length 4.2
  BOTTOM w0.089: 32.22,105.2 U4103.L9
  BOTTOM w0.102: R4103.2 31.31,108.53 32.22,107.62 32.22,105.2
UNNAMED_29_H5TC4G63AFR_I114_ZQ0: length 5.3
  BOTTOM w0.089: 32.6,105.2 32.6,104.58 32.22,104.2 U4103.L8
  BOTTOM w0.102: R4109.2 32.6,107.43 32.6,105.2
UNNAMED_29_H5TC4G63AFR_I157_NC4: length 8.6
  BOTTOM w0.102: R4102.2 25.9,93.64 31.1,93.64 32.36,92.38 32.36,91.84 U4102.L9
UNNAMED_29_H5TC4G63AFR_I157_ZQ0: length 9.7
  BOTTOM w0.102: U4102.L8 32.22,91.16 32.6,91.54 32.6,92.5 31.25,93.86 25.35,93.86 R4108.2
UNNAMED_30_H5TC4G63AFR_I119_NC4: length 7.3
  TOP w0.102: v1(54.42,116.65) 54.42,117.3 53.93,117.79 R4101.2
  BOTTOM w0.102: v1(54.42,116.65) 55.26,115.81 55.26,114.18 53.93,112.85 53.46,112.85 U4101.L9
UNNAMED_30_H5TC4G63AFR_I119_ZQ0: length 9.8
  TOP w0.102: R4107.2 54.23,118.68 54.8,118.11 54.8,117.01 v3(55.16,116.65)
  BOTTOM w0.102: v3(55.16,116.65) 55.17,116.65 55.48,116.34 55.48,113.96 54.11,112.6 53.18,112.6 52.9,112.88 52.64,112.88 U4101.L8
UNNAMED_30_H5TC4G63AFR_I178_NC4: length 4.1
  BOTTOM w0.102: U4100.L9 68.9,112.99 69.74,113.83 R4100.2
UNNAMED_30_H5TC4G63AFR_I178_ZQ0: length 5.3
  BOTTOM w0.102: R4106.2 69.08,111.33 68.59,111.82 67.82,112.6 66.22,112.6 65.83,112.99 U4100.L8
UNNAMED_32_H5TC4G63AFR_I41_NC4: length 8
  BOTTOM w0.102: U4104.L9 59.46,48.55 58.71,48.55 57.91,47.75 57.91,43 R4179.2
UNNAMED_32_H5TC4G63AFR_I41_ZQ0: length 9.1
  BOTTOM w0.102: R4178.2 58,42.56 57.7,42.85 57.7,47.85 58.78,48.93 59.62,48.93 60,48.55 U4104.L8
UNNAMED_32_H5TC4G63AFR_I181_NC4: length 4.3
  BOTTOM w0.102: U4105.L9 44.26,48.55 42.95,47.24 R4144.2
UNNAMED_32_H5TC4G63AFR_I181_ZQ0: length 6
  BOTTOM w0.102: U4105.L8 46.96,48.55 46.56,48.95 44.01,48.95 43.26,49.7 R4151.2 41.66,49.7 v2(41.65,49.7)
UNNAMED_35_540276_I159_DDI0PL_1: length 1.6
  TOP w0.127: R4514.2 75.03,85.74 v3(75.34,86.05)
  BOTTOM w0.089: U4500.F38 75.05,86.34 v3(75.34,86.05)
UNNAMED_35_540276_I159_DDI0PLLO: length 1.6
  TOP w0.127: v3(73.97,86.05) 74.18,85.84 R4514.1
  BOTTOM w0.089: U4500.G38 74.34,86.42 v3(73.97,86.05)
UNNAMED_35_540276_I159_DDI1PL_1: length 1.8
  TOP w0.127: v3(75.36,91.19) 75.56,90.99 R4518.2
  BOTTOM w0.102: U4500.F47 75.09,91.19 75.36,91.19 v3(75.36,91.19)
UNNAMED_35_540276_I159_DDI1PLLO: length 1.7
  TOP w0.127: R4518.1 75.74,91.84 v1(75.69,91.9)
  BOTTOM w0.102: v1(75.69,91.9) 75.63,91.84 U4500.F49
UNNAMED_35_540276_I159_GPCAME_1: length 5.8
  TOP w0.089: R4705.1 70.43,90.81 69.68,90.81 69.14,90.27 69.14,89.36 68.53,88.75 v1(68.53,87.27)
  BOTTOM w0.089: v1(68.53,87.27) 68.72,87.47 U4500.V40
UNNAMED_35_540276_I159_GPCAME_2: length 2.1
  TOP w0.089: R4707.1 68.96,90.6 68.48,90.12 v3(68.48,90.06)
  BOTTOM w0.102: U4500.Y44 v3(68.48,90.06)
UNNAMED_35_540276_I159_GPCAMERA: length 3.3
  TOP w0.089: v1(68.47,89.34) 68.54,89.34 68.96,89.76 68.96,90.34 69.85,91.23 R4706.1
  BOTTOM w0.089: v1(68.47,89.34) 68.03,88.9 U4500.Y42
UNNAMED_35_540276_I159_MCSICOMP: length 2.1
  TOP w0.089: R4711.1 71.34,90.61 v1(71.31,90.63)
  BOTTOM w0.089: v1(71.31,90.63) 71.31,89.99 U4500.P44
UNNAMED_36_540276_I157_MFHDACLK: length 4.8
  TOP w0.109: R4538.1 v2(67.35,69.04) 67.1,69.29 67.1,71.46 67.03,71.53 66.76,71.81 66.76,71.81 v1(66.54,72.02)
  BOTTOM w0.109: v1(66.54,72.02) 66.28,72.02 U4500.AD9
UNNAMED_36_540276_I157_MFHDARST: length 6.3
  TOP w0.089: v1(64.65,73.95) 64.1,73.4 64.1,71.05
  TOP w0.109: 64.1,71.05 v2(64.44,70.71) 65.17,69.98 65.17,69.21 R4536.1
  BOTTOM w0.089: v1(64.65,73.95) 65.07,74.37 U4500.AF13
UNNAMED_36_540276_I157_MFHDASDO: length 10.5
  TOP w0.109: v3(64.67,74.7) 64.15,74.18 64.15,73.98 63.87,73.71 63.43,73.71 63.27,73.54 63.27,69.61 62.67,69.01 62.67,66.61 R4539.1
  BOTTOM w0.109: v3(64.67,74.7) 65.04,75.08 U4500.AF14
UNNAMED_36_540276_I157_MFHDASYN: length 5.7
  TOP w0.089: v3(64.65,73.27) 64.28,72.91 64.28,71.61 64.44,71.45
  TOP w0.109: 64.44,71.45 65.45,70.43 65.45,69.41 R4537.1
  BOTTOM w0.089: U4500.AF12 65.04,73.66 v3(64.65,73.27)
UNNAMED_36_540276_I157_PCIECLKR: length 1.6
  TOP w0.102: v3(62.66,73.93) 62.02,73.93 R4523.2
  BOTTOM w0.102: U4500.AM12 62.39,73.66 v3(62.66,73.93)
UNNAMED_36_540276_I157_SATAGP0: length 5.2
  BOTTOM w0.109: R4540.1 64.19,64.6 64.19,66.38 64.32,66.51 64.32,68.22 64.13,68.4 U4500.AH2
UNNAMED_36_540276_I157_SATAGP3: length 4.8
  BOTTOM w0.089: 65.11,69.26 U4500.AF3
  BOTTOM w0.102: TP4540.1 64.54,65.23 64.54,67.95 64.9,68.3 64.9,68.64 64.81,68.73 64.81,68.97 64.88,69.03 65.1,69.26 65.11,69.26
UNNAMED_36_RSC0402_I236_A: length 1.6
  BOTTOM w0.102: R4702.1 75.15,40.31 U4702.6
UNNAMED_37_540276_I161_GPIODFX0: length 1.5
  TOP w0.102: TP4551.1 61.94,88.54 v1(62.6,87.88)
  BOTTOM w0.102: U4500.AM40 62.19,87.47 v1(62.6,87.88)
UNNAMED_37_540276_I161_GPIODFX1: length 2.5
  TOP w0.127: TP4552.1 63.16,89.65 63.16,89.01 62.67,88.52 v1(62.64,88.52)
  BOTTOM w0.102: v1(62.64,88.52) 62.31,88.18 U4500.AM41
UNNAMED_37_540276_I161_GPIODFX2: length 1.3
  TOP w0.127: v1(62.64,89.99) 62.33,90.3 TP4553.1
  BOTTOM w0.102: U4500.AM44 62.56,89.99 v1(62.64,89.99)
UNNAMED_37_540276_I161_GPIODFX3: length 2.3
  TOP w0.127: v1(62.62,91.42) 62.5,91.42 TP4554.1
  BOTTOM w0.102: v1(62.62,91.42) 62.62,90.76 U4500.AM45
UNNAMED_37_540276_I161_I2C5SCL: length 5.5
  BOTTOM w0.089: TP4506.1 69.26,64.41 67.46,66.22 67.46,68.07 67.05,68.48 U4500.AB2
UNNAMED_37_540276_I161_I2C5SDA: length 11.5
  TOP w0.102: TP4505.1 67.61,60.17 v1(67.21,60.58)
  BOTTOM w0.109: U4500.AC3 66.5,69.14 65.95,69.14 65.78,68.97 65.78,68.72 65.88,68.62 65.88,68.35 66.34,67.89 66.34,62.2 65.91,61.77 65.91,61.29 66.62,60.58 v1(67.21,60.58)
UNNAMED_37_540276_I161_I2C6SDA: length 7.3
  BOTTOM w0.089: R4635.1 68.7,63.67 68.7,64.72 67.28,66.14 67.28,66.19 67.26,66.22 67.26,67.87 66.85,68.27 66.85,68.64 66.76,68.73 66.76,68.97 67.03,69.23 67.03,69.52 U4500.AB3
UNNAMED_37_540276_I161_I2CNFCSC: length 2.6
  TOP w0.089: TP4504.1 68.97,68.48 v1(67.63,69.83)
  BOTTOM w0.089: v1(67.63,69.83) 67.53,69.73 U4500.AA3
UNNAMED_37_540276_I161_I2CNFCSD: length 5
  TOP w0.089: 69.56,65.54 v1(69.42,65.68)
  TOP w0.102: 69.56,65.54 69.67,65.43 TP4537.1
  BOTTOM w0.089: U4500.Y2 68.03,68.84 68.03,68.08
  BOTTOM w0.102: v1(69.42,65.68) 68.81,65.68 68.06,66.43 68.06,66.74 68.05,66.75 68.05,68.06 68.03,68.08
UNNAMED_37_540276_I161_MFSMBALE: length 9.3
  TOP w0.127: v3(62.59,71.88) 61.97,71.27 61.97,69.21 59.99,67.23 R4632.1 59.99,66.02 61.07,64.93 B500.1
  BOTTOM w0.102: v3(62.59,71.88) 62.23,72.24 U4500.AM9
UNNAMED_37_RSC0402_I174_B: length 3.1
  BOTTOM w0.102: v2(105.83,59.68) 106.65,59.68 R4686.2
  BOTTOM w0.356: 107.83,58.59 U4503.6
  BOTTOM w0.381: R4686.2 107.39,59.03 107.83,58.59
UNNAMED_37_RSC0402_I273_B: length 2.3
  BOTTOM w0.102: R4582.2 105.4,53.15 v2(105.66,53.42)
  BOTTOM w0.356: R4582.2 105.94,52.04 U4502.6
UNNAMED_37_RSC0402_I274_A: length 2.2
  BOTTOM w0.109: R4591.1 R4561.1 107.05,51.76 106.94,51.65 U4502.8
UNNAMED_37_RSC0402_I275_A: length 3.1
  BOTTOM w0.109: R4593.1 R4562.1 v2(107.97,47.67) 107.39,47.67 106.94,48.12 U4502.1
UNNAMED_38_540276_I11_VSS2: length 5.9
  BOTTOM w0.089: TP4534.1 80.74,67.49 79.44,68.79 79.44,69.91 78.93,70.42 77.81,70.42 U4500.A6
UNNAMED_38_540276_I11_VSS16: length 3.9
  BOTTOM w0.254: TP4533.1 52.83,96.04 53.91,94.97 53.91,94.45 54.21,94.15 U4500.BH53
UNNAMED_39_NMOS_I11_G: length 5.1
  BOTTOM w0.102: v2(114.94,105.77) 113.9,104.73 Q4525.1 113.74,104.61 Q4517.3 112.29,104.1 112.29,105.24 R4639.1
UNNAMED_39_NMOS_I12_D: length 5.4
  BOTTOM w0.102: 111.84,106.27 v2(111.78,106.22) ; 111.84,106.27 R4642.1 ; 111.84,106.27 112.86,107.3 Q4516.3 113.93,107.3 114.66,108.04 Q4524.1
UNNAMED_39_NMOSDUALC_I78_D2: length 2.6
  BOTTOM w0.102: v2(24.42,127.42) 24.63,127.21 R4643.1
  BOTTOM w0.381: Q1302.2 Q1302.3 26.15,127.21 R4643.1
UNNAMED_41_540276_I90_SDIOV3P3A: length 3.1
  TOP w0.381: v1(75,67.28) 75.07,67.21 C4581.1 76.6,67.21 R4835.2
  BOTTOM w0.254: U4500.G1 74.52,68.21 74.52,67.72 74.95,67.28 v1(75,67.28)
UNNAMED_42_RSC0402_I10_A: length 2
  TOP w0.109: R4601.2 75.27,102.47 R4602.1 75.97,102.34 R4846.1
UNNAMED_42_RSC0402_I11_A: length 1.7
  BOTTOM w0.109: R4604.2 75.27,102.54 R4605.1 R4847.1
UNNAMED_45_AT9667_I14_2: length 1.3
  BOTTOM w0.381: R4446.2 79.06,105.64 U4441.2
UNNAMED_45_AT9667_I14_5: length 8.4
  BOTTOM w0.254: R4448.2 80.9,110.13 80.21,110.82 78.03,110.82 77.76,111.08 U4441.5 76.74,111.97 v2(76.5,112.22) 76.63,112.34 R4441.1 75.74,113.69 R4449.2
UNNAMED_45_AT9667_I14_7: length 1.4
  BOTTOM w0.381: R4443.2 79.06,113.18 U4441.7
UNNAMED_45_AT9667_I14_8: length 4.1
  BOTTOM w0.381: R4442.1 79.16,114.15 R4443.1 79.96,114.14 v2(80.01,114.2) R4444.1 80.01,112.88 79.71,112.58 U4441.8
UNNAMED_45_CSC0402_I38_B: length 1.9
  TOP w0.102: C4102.2 49.39,96.91 48.72,96.91 R4114.2 48.71,97.85 R4115.2
UNNAMED_46_CSC0402_I70_A: length 4.7
  TOP w0.102: C310.1 88.59,152.99 88.59,154.23 v2(88.17,154.65) 87.79,155.03 U301.44
UNNAMED_46_CSC0402_I232_A: length 2.5
  TOP w0.102: U301.12 76.44,147.61 76.53,147.52 v2(76.53,147.4) C316.1
UNNAMED_46_NMOS_I547_D: length 8.6
  TOP w0.102: Q310.3 100.34,157.42 101.47,158.55 101.53,158.61 104.58,158.61 105.79,157.4 v2(105.79,157.2) 105.79,156.41 106.23,155.97 Q311.3
UNNAMED_46_NPCE985LB1DX_I255_10: length 2.6
  TOP w0.102: TP302.1 70.43,153.83 U301.120
UNNAMED_46_NPCE985LB1DX_I255_11: length 3.3
  TOP w0.102: TP307.1 74.47,146.42 74.47,147.7 74.04,148.13 U301.6
UNNAMED_46_NPCE985LB1DX_I255_12: length 2.1
  TOP w0.102: TP308.1 69.06,158.19 70.4,158.19 U301.109
UNNAMED_46_NPCE985LB1DX_I255_13: length 2.7
  TOP w0.102: U301.15 77.64,148.11 78.41,147.34 TP309.1
UNNAMED_46_NPCE985LB1DX_I255_14: length 3.1
  TOP w0.102: TP310.1 81.86,146.63 81.86,147.75 82.04,147.93 U301.26
UNNAMED_46_NPCE985LB1DX_I255_15: length 9.9
  TOP w0.102: v1(77.3,163.47) 77.24,163.54 U301.83 ; TP306.1 69.49,165.1 v1(69.9,164.69)
  BOTTOM w0.102: v1(69.9,164.69) 70.29,164.3 76.48,164.3 v1(77.3,163.47)
UNNAMED_46_NPCE985LB1DX_I255__1: length 5.5
  TOP w0.102: v1(73.88,163.24) 74.04,163.39 U301.91 ; v1(71.29,164.71) 71.05,164.95 TP329.1
  L3 w0.102: v1(73.88,163.24) 72.42,164.71 v1(71.29,164.71)
UNNAMED_46_NPCE985LB1DX_I255__2: length 3.3
  TOP w0.102: R391.2 68.01,151.87 R390.1 69.4,152.23 70.44,152.23 U301.124
UNNAMED_46_NPCE985LB1DX_I255__3: length 2.5
  TOP w0.102: U301.114 69.52,156.23 68.5,157.25 TP301.1
UNNAMED_46_NPCE985LB1DX_I255__4: length 11.5
  TOP w0.109: R314.1 89.54,151.74 v2(89.13,151.74) 87.91,151.74 87.28,151.11 87.28,150.64 86.89,150.25 85.14,150.25 84.81,150.58 81.67,150.58 81.24,150.15 U301.24
UNNAMED_46_NPCE985LB1DX_I255__5: length 8.4
  TOP w0.109: R313.1 89.17,151.05 v2(88.03,151.05) 88.03,150.7 87.09,149.76 84.93,149.76 84.6,150.09 82.95,150.09 82.84,149.98 U301.28
UNNAMED_46_NPCE985LB1DX_I255__6: length 1.6
  TOP w0.102: TP303.1 82.44,147.55 U301.27
UNNAMED_46_NPCE985LB1DX_I255__7: length 3.8
  TOP w0.102: TP311.1 67.24,155.03 U301.117
UNNAMED_46_NPCE985LB1DX_I255__8: length 22.3
  TOP w0.102: v1(76.68,163.35) 76.84,163.51 U301.84
  BOTTOM w0.102: TP304.1 63.8,154.91 65.44,156.55 65.44,157.49 68.58,160.63 72.32,160.63 73.38,161.7 75.03,161.7 v1(76.68,163.35)
UNNAMED_46_NPCE985LB1DX_I255__9: length 1.7
  TOP w0.102: TP300.1 69.18,154.23 U301.119
UNNAMED_46_NPCE985LB1DX_I255_EC: length 1.8
  TOP w0.102: U301.29 83.24,147.79 TP327.1
UNNAMED_46_NPCE985LB1DX_I255_GP: length 59.2
  TOP w0.102: R312.2 105.71,151.31 v2(105.71,149.61) 103.42,147.31 103.42,146.17 104.9,144.69 104.9,142.07 v1(104.42,141.59)
  TOP w0.109: v1(77.06,159.66) 77.06,160.02 80.44,163.4 U301.75
  L3 w0.102: v1(77.06,159.66) 77.94,158.78 77.94,154.76 77.31,154.14 77.31,152.66 78.6,151.38 78.6,150.33 83.5,145.43 83.52,145.43 87.6,145.43 88.51,144.52 96.32,144.52 96.39,144.52 97.08,143.83 98.45,143.83 100.24,142.04 102.41,142.04 103.44,141 103.83,141 v1(104.42,141.59)
UNNAMED_46_NPCE985LB1DX_I256__1: length 6.3
  TOP w0.102: U301.63 86.05,162.62 86.96,162.62 87.09,162.49 87.09,158.09 TP305.1
UNNAMED_46_NPCE985LB1DX_I256_GP: length 4.1
  TOP w0.102: U301.30 83.64,148.08 84.1,147.62 84.1,147.22 83.62,146.75 R325.2 83.62,145.7 v2(83.39,145.47)
UNNAMED_51_ALC233VB2CGT_I110__1: length 2.2
  TOP w0.254: C511.1 7.37,50.16 9.34,50.16 U500.37
UNNAMED_51_ALC233VB2CGT_I110__2: length 1.6
  TOP w0.254: C512.2 9.74,48.81 10.22,49.29 U500.39
UNNAMED_51_ALC233VB2CGT_I110__3: length 2.9
  TOP w0.254: v1(16.43,52.91) 16.15,53.19 U500.7
  BOTTOM w0.381: v1(16.43,52.91) 16.71,53.19 C530.1
UNNAMED_51_ALC233VB2CGT_I110_AV: length 7.6
  TOP w0.254: U500.40 10.62,49.15 10.44,48.97 10.44,48.01 v1(10.21,47.78)
  BOTTOM w0.508: C513.1 11.6,43.47 10.21,44.86 v1(10.21,47.78)
  vias: v2(12.77,43.33)
UNNAMED_51_ALC233VB2CGT_I110_CB: length 1.5
  TOP w0.254: U500.35 7.33,51.19 C511.2
UNNAMED_51_ALC233VB2CGT_I110_CP: length 2.5
  TOP w0.254: U500.34 6.84,51.59 C503.2
UNNAMED_51_ALC233VB2CGT_I110_HP: length 3.6
  TOP w0.254: R502.1 R504.1 15.69,56.65 15.35,56.31 v2(15.35,56.31) 14.07,56.31 13.82,56.06 U500.13
UNNAMED_51_ALC233VB2CGT_I110_LD: length 5.5
  TOP w0.254: R531.1 9.15,57.41 C501.1 7.68,56.41 7.68,54.83 8.11,54.39 U500.27
UNNAMED_51_ALC233VB2CGT_I110_MI: length 8.5
  TOP w0.254: v1(17.16,58.47) 16.57,59.05 14.81,59.05 v2(14.68,58.93) 14.21,58.45 13.24,58.45 11.42,56.63 U500.19
  BOTTOM w0.254: v1(17.16,58.47) C531.1
UNNAMED_51_ALC233VB2CGT_I110_NC: length 8.9
  TOP w0.254: U500.20 11.02,56.74 11.93,57.65 11.93,59.56 12.57,60.2 v2(15.06,60.2) 15.72,60.2 R514.1
UNNAMED_51_ALC233VB2CGT_I110_PC: length 2.1
  TOP w0.102: U500.12 15.68,55.19 v2(15.77,55.1) 16.51,55.1 C507.1
UNNAMED_51_ALC233VB2CGT_I110_SP: length 2.6
  TOP w0.254: R501.1 14.76,57.12 14.08,57.12 13.68,56.72 13.3,56.72 13.02,56.45 13.02,55.92 13.02,55.92 U500.15
UNNAMED_51_ALC233VB2CGT_I110_VR: length 4.6
  TOP w0.254: 7.24,54.64 7.88,53.99 U500.28
  TOP w0.381: C502.2 7.22,56.88 7.22,54.66 7.24,54.64
UNNAMED_51_CSC0402_I68_B: length 4.7
  TOP w0.102: R515.1 R505.1 18.97,57.65 18.34,57.02 v2(18.21,57.02) 18.21,56.18 R503.1 18.36,56.02 C506.2 C507.2
UNNAMED_51_RSC0402_I120_B: length 3
  TOP w0.102: R505.2 19.05,55.8 19.77,55.08 v2(19.85,55.08) 19.85,55.07 20.09,54.84 R521.1
UNNAMED_51_RSC0402_I136_B: length 0.7
  TOP w0.102: R520.1 R515.2
UNNAMED_52_2SJ3095078111F_I61_1: length 18.8
  L3 w0.254: v3(8.67,82.27) 11.17,82.27 15.44,86.54 15.44,91.93 JACK600.1
  BOTTOM w0.254: v3(8.67,82.27) C600.1 8.09,81.38 R606.2 R605.2
UNNAMED_52_2SJ3095078111F_I61_2: length 39.4
  L4 w0.254: JACK600.2 9.52,103.1 10.3,103.87 15.27,103.87 16.3,102.84 16.3,88.29 11.63,83.62 5.8,83.62 v3(5.08,82.9)
  BOTTOM w0.254: v3(5.08,82.9) C601.1 5.08,81.39 R607.2 R604.2
UNNAMED_54_5020303001001_I97_3: length 1.5
  BOTTOM w0.102: CN3000.3 68.53,150.98 TP3001.1
UNNAMED_54_5020303001001_I97_7: length 3.4
  BOTTOM w0.102: CN3000.7 70.53,151.42 70.73,151.21 R3061.2 70.73,150.34 R3060.1
UNNAMED_54_5020303001001_I97_8: length 2.2
  BOTTOM w0.102: TP3002.1 71.75,150.7 71.03,151.43 CN3000.8
UNNAMED_54_5020303001001_I97_16: length 2
  BOTTOM w0.102: CN3000.16 75.03,151.51 75.54,151 TP3003.1
UNNAMED_54_CSC0402_I39_A: length 7.7
  TOP w0.381: R3069.2 100.98,152.08 v2(100.28,152.08) 99.6,152.08 98.79,152.9 R3068.2 98.79,153.51 97.92,154.38 C3016.1 96.82,155.24 95.83,155.24 Q3004.3
UNNAMED_54_CSC0402_I39_B: length 6.9
  TOP w0.381: R3030.2 100.4,151.05 v2(99.51,151.05) 99.51,151.21 98.73,151.99 98.08,151.99 98.08,151.99 C3015.2 97.96,153.25 C3016.2 97.02,153.52 97.02,153.52 96.57,153.08 Q3004.1
UNNAMED_54_CSC0402_I43_A: length 7.2
  TOP w0.102: v2(94.67,150.22) 94.27,150.62 FUSE3004.1
  TOP w0.381: 94.39,152.43 94.39,151.43 FUSE3004.1 ; 94.39,152.43 94.47,152.36 96.87,152.36 C3015.1 ; 94.39,152.43 94.39,153.16 Q3004.2
UNNAMED_54_CSC0402_I105_A: length 8.3
  BOTTOM w0.102: Q3001.2 56.23,138.28 56.35,138.39 56.35,139.8 R3001.2 56.22,139.97 56.68,140.43 Q3000.1 ; Q3000.1 56.11,141.71 C3000.1 ; Q3000.1 57.28,141.74 57.28,142.47 58.05,143.23 C3003.1
UNNAMED_54_NMOS_I135_G: length 3.9
  BOTTOM w0.102: Q3006.3 59.99,131.09 59.99,131.09 59.99,130.83 60.62,130.2 Q3007.1 60.63,129.94 R3006.2
UNNAMED_54_NMOSDUALC_I102_D1: length 2.8
  BOTTOM w0.102: Q3001.6 57.39,137.63 57.22,137.79 57.22,139.73 R3004.2
UNNAMED_54_NMOSDUALC_I102_D2: length 3.1
  BOTTOM w0.102: Q3001.3 55.05,138.93 v2(54.86,139.12) 54.86,139.42 R3001.1 55.37,140.47 R3000.2
UNNAMED_54_NPND_I136_B: length 2
  BOTTOM w0.102: v2(59.73,136.02) 59.42,135.72 R3025.2 58.9,134.84 58.9,134.84 Q3006.1
UNNAMED_59_540276_I142_BVCCRTCE: length 2.5
  TOP w0.089: v3(75.36,75.34) 75.8,74.9 76.58,74.9 C4513.1
  BOTTOM w0.102: U4500.F16 75.05,75.65 v3(75.36,75.34)
UNNAMED_59_540276_I142_CXPRDYB: length 1.4
  TOP w0.102: TP4516.1 66.63,90.8 v1(66.54,90.7)
  BOTTOM w0.102: v1(66.54,90.7) 66.15,90.32 U4500.AD45
UNNAMED_59_540276_I142_CXPREQB: length 1.4
  TOP w0.127: TP4517.1 64.91,88.7 v1(64.71,88.5)
  BOTTOM w0.102: v1(64.71,88.5) 65.02,88.18 U4500.AF41
UNNAMED_59_540276_I142_MFLPCCLK: length 19.5
  BOTTOM w0.109: R4828.2 77.16,54.57 76.5,55.23 76.5,59.04 73.83,61.7 73.83,62.33 73.41,62.75 72.9,63.26 72.9,64.93 70.17,67.66 70.17,68.62 70.45,68.91 U4500.R3
UNNAMED_59_540276_I142_PWM0: length 1.6
  TOP w0.089: TP4509.1 74.95,70.39 74.95,70.39 v1(74.38,70.39)
  BOTTOM w0.102: U4500.H5 74.24,70.39 v1(74.38,70.39)
UNNAMED_59_540276_I142_PWM1: length 1.6
  TOP w0.127: TP4510.1 73.27,71.87 v1(73.41,71.87)
  BOTTOM w0.089: U4500.H7 73.85,71.44 v1(73.41,71.87)
UNNAMED_59_540276_I142_RSVDVSS: length 1.2
  TOP w0.089: R4820.1 74.72,76.47 v1(74.66,76.41)
  BOTTOM w0.089: U4500.G18 74.34,76.85 74.66,76.53 v1(74.66,76.41)
UNNAMED_59_540276_I142_TCK: length 1.3
  TOP w0.127: TP4511.1 64.86,89.47 v1(64.65,89.26)
  BOTTOM w0.102: U4500.AF42 65.02,88.89 v1(64.65,89.26)
UNNAMED_59_540276_I142_TDI: length 3.5
  TOP w0.102: TP4512.1 67.81,93.57 67.13,92.89 67.13,92.02 v1(66.54,91.42)
  BOTTOM w0.102: v1(66.54,91.42) 66.15,91.03 U4500.AD47
UNNAMED_59_540276_I142_TDO: length 1.9
  TOP w0.127: v1(64.71,87.79) 65.45,87.79 TP4513.1
  BOTTOM w0.102: v1(64.71,87.79) 65.02,87.47 U4500.AF40
UNNAMED_59_540276_I142_TMS: length 1.9
  TOP w0.102: TP4514.1 66.54,93.11 v1(66.54,92.12)
  BOTTOM w0.102: U4500.AD48 66.54,92.1 v1(66.54,92.12)
UNNAMED_59_540276_I142_TRSTB: length 2.8
  TOP w0.102: v1(67.61,92.05) 68.81,93.24 TP4515.1
  BOTTOM w0.102: v1(67.61,92.05) 67.3,91.74 U4500.AB48
UNNAMED_59_NMOS_I8_G: length 1.1
  BOTTOM w0.381: Q4505.1 72.91,108.54 R4578.2
UNNAMED_59_NMOSDUALC_I161_D1: length 2.4
  BOTTOM w0.381: R4586.1 82.09,129.14 Q4506.5 Q4506.6
UNNAMED_59_RSC0402_I187_B: length 1.7
  BOTTOM w0.109: R4573.2 78.01,51.03 R4572.2 77.16,51.1 77.16,51.1 R4828.1
UNNAMED_59_RSCSHORT_I186_A: length 5.6
  TOP w0.381: R704.1 80.39,66.83 v1(79.93,66.37)
  BOTTOM w0.381: v1(79.93,66.37) 80.46,65.84 v2(80.46,65.51) 80.46,64.9 D4501.3
UNNAMED_60_540276_I79_UART1RXD: length 1.3
  TOP w0.127: TP4542.1 65.92,73.93 v1(66.54,73.93)
  BOTTOM w0.127: U4500.AD12 66.34,73.93 v1(66.54,73.93)
UNNAMED_60_540276_I79_UART1TXD: length 2
  TOP w0.127: v1(66.59,73.32) 66.47,73.32 TP4541.1
  BOTTOM w0.127: U4500.AD10 66.07,73.24 66.18,73.35 66.55,73.35 v1(66.59,73.32)
UNNAMED_60_540276_I79_UART2RXD: length 1.4
  TOP w0.089: TP4544.1 68.27,72.06 v1(68.53,71.81)
  BOTTOM w0.089: v1(68.53,71.81) 68.24,71.52 U4500.Y7
UNNAMED_60_540276_I79_UART2TXD: length 1.4
  TOP w0.089: v1(68.53,71.14) 68.65,71.27 TP4543.1
  BOTTOM w0.089: v1(68.53,71.14) 68.19,70.81 U4500.Y6
UNNAMED_61_19223S2T1DC302T_I5_1: length 2.4
  TOP w0.508: v3(58.68,4.31) 58.68,4.25 58.98,3.95 R9123.1
  BOTTOM w0.381: D9129.1 58.28,4.32 58.65,4.32 58.66,4.31 v3(58.68,4.31)
UNNAMED_61_19223S2T1DC302T_I5_2: length 3.3
  TOP w0.508: v3(58.64,1.23) 58.98,1.58 R9124.1
  BOTTOM w0.381: v3(58.64,1.23) 58.44,1.43 58.44,1.92 D9129.2
UNNAMED_61_19223S2T1DC302T_I6_1: length 19.2
  TOP w0.381: v4(49.47,1.53) 49.82,1.19 52.78,1.19 53.25,1.66 R9121.1
  BOTTOM w0.381: v4(49.47,1.53) 49.45,1.56 48.87,1.56 46.85,3.58 46.23,3.58 45.77,3.12 42.36,3.12 41.62,3.86 41.62,5.86 40.9,6.57 40.9,7.71 41.39,8.2 D9128.1
UNNAMED_61_19223S2T1DC302T_I6_2: length 17.4
  TOP w0.381: R9122.1 53.02,2.57 52.24,1.8 50.45,1.8 50.02,2.23 49.53,2.23 v4(49.49,2.27)
  BOTTOM w0.381: v4(49.49,2.27) 49.08,2.27 v2(47.56,3.79) 47.12,4.24 45.98,4.24 45.35,3.6 42.56,3.6 42.13,4.04 42.13,6.03 41.39,6.77 41.39,7.06 41.63,7.3 D9128.2
UNNAMED_62_CSC0402_I6_B: length 1.8
  TOP w0.102: R4186.2 44.92,66.16 R4185.2 44.92,67 C4200.2
UNNAMED_63_H5TC4G63AFR_I34_NC4: length 8.7
  BOTTOM w0.102: U4106.L9 32.36,64.31 32.36,64.79 31.04,66.11 26.71,66.11 25.66,65.07 R4182.2
UNNAMED_63_H5TC4G63AFR_I34_ZQ0: length 9.7
  BOTTOM w0.102: R4187.2 25.65,66.33 31.18,66.33 32.61,64.89 32.61,64.03 32.22,63.64 32.22,63.37 U4106.L8
UNNAMED_63_H5TC4G63AFR_I164_NC4: length 4.3
  BOTTOM w0.102: U4107.L9 32.22,79.93 R4180.2
UNNAMED_63_H5TC4G63AFR_I164_ZQ0: length 5.2
  BOTTOM w0.102: R4181.2 33.63,80.94 32.62,79.93 32.62,77.07 32.22,76.67 32.22,76.42 U4107.L8
USB3_OBSN: length 1.8
  TOP w0.107: R4563.1 74.93,83.49 74.93,84.04 v1(74.71,84.26)
  BOTTOM w0.107: U4500.F34 v1(74.71,84.26)
USB3_OBSP: length 1.8
  TOP w0.107: R4563.2 75.14,83.52 75.14,84.01 v3(75.4,84.26)
  BOTTOM w0.107: U4500.D34 v3(75.4,84.26)
USB3_PCH_RX1_DN: length 100.7
  L3 w0.109: v1(76.02,82.21) 75.84,82.39 75.84,82.81 75.28,83.37 74.23,83.37 73.63,83.97 73.07,83.97 71.12,85.93 71.12,89.38 71.96,90.22 71.96,93.29 73.17,94.51 73.17,100.08 73.92,100.82 73.92,101.51 74.47,102.06 74.47,105.3 75.26,106.09 75.26,110.39 71.41,114.24 71.41,118.18 65.41,124.18 63.86,124.18 63.24,124.8 62.36,124.8 61.63,125.53 57.1,125.53 56.92,125.35 48.48,125.35 46.92,123.79 39.17,116.04 31.79,116.04 29.09,113.34 27.77,113.34 26.38,111.94 25.85,111.94 25.74,112.05 25.74,112.35 v3(25.92,112.52)
  BOTTOM w0.107: v3(25.92,112.52) 25.74,112.34 25.74,112.03 25.37,111.66 24.19,111.66 23.93,111.41 L2432.2 ; U4500.D28 v1(76.02,82.21)
USB3_PCH_RX1_DP: length 100.7
  L3 w0.109: v3(75.32,82.21) 75.45,82.21 75.63,82.4 75.63,82.72 75.19,83.16 74.14,83.16 73.54,83.76 72.98,83.76 70.91,85.84 70.91,89.47 71.74,90.31 71.74,93.38 72.96,94.6 72.96,100.16 73.71,100.91 73.71,101.6 74.26,102.15 74.26,105.39 75.05,106.17 75.05,110.3 71.2,114.15 71.2,118.09 65.32,123.96 63.77,123.96 63.15,124.59 62.28,124.59 61.54,125.32 57.19,125.32 57.01,125.14 48.57,125.14 47.13,123.71 39.25,115.83 31.88,115.83 29.18,113.13 27.86,113.13 26.46,111.73 25.77,111.73 25.53,111.97 25.53,112.31 25.32,112.52 v1(25.19,112.52)
  BOTTOM w0.107: U4500.F28 v3(75.32,82.21) ; L2432.1 23.9,112.21 24.24,111.87 25.28,111.87 25.53,112.12 25.53,112.33 25.34,112.52 v1(25.19,112.52)
USB3_PCH_TX1_DN: length 102.6
  L3 w0.109: v3(27.94,114.64) 27.71,114.87 27.39,114.87 27.28,114.76 27.28,114.26 27.47,114.07 28.63,114.07 31.3,116.74 38.38,116.74 40.96,119.31 41.45,119.31 46.2,124.07 46.2,124.85 47.41,126.06 56.57,126.06 56.75,126.25 62.11,126.25 62.85,125.51 65.57,125.51 72.11,118.97 72.11,114.53 75.98,110.66 75.98,105.13 75.26,104.41 75.26,101.85 74.62,101.21 74.62,100.43 73.92,99.73 73.92,94.28 73.08,93.43 73.08,88.43 72.51,87.86 72.51,85.72 73.21,85.03 76.22,85.03 77.31,83.93 77.78,83.93 v1(77.94,84.09)
  BOTTOM w0.107: v3(27.94,114.64) 27.69,114.88 27.2,114.88 25.92,113.61 25.61,113.61 C2440.1 ; v1(77.94,84.09) 77.7,83.85 77.29,83.85 77.14,84 76.9,84 76.6,83.71 U4500.C32
USB3_PCH_TX1_DP: length 102.6
  L3 w0.109: v1(77.96,83.43) 77.66,83.72 77.22,83.72 76.13,84.82 73.13,84.82 72.3,85.64 72.3,87.95 72.87,88.52 72.87,93.52 73.71,94.36 73.71,99.82 74.41,100.52 74.41,101.3 75.05,101.93 75.05,104.5 75.77,105.22 75.77,110.57 71.9,114.44 71.9,118.89 65.48,125.3 62.76,125.3 62.02,126.03 56.84,126.03 56.65,125.84 47.5,125.84 46.41,124.76 46.41,123.98 41.54,119.1 41.04,119.1 38.47,116.53 31.38,116.53 28.72,113.86 27.39,113.86 27.07,114.17 27.07,114.85 27.31,115.08 27.67,115.08 27.94,115.34 v1(27.94,115.37)
  BOTTOM w0.107: v1(77.96,83.43) 77.94,83.43 77.73,83.64 77.21,83.64 77.14,83.71 U4500.B32 ; C2441.1 25.61,113.82 25.84,113.82 27.11,115.09 27.7,115.09 27.94,115.33 v1(27.94,115.37)
USB3_SSRX1_DN: length 9.7
  BOTTOM w0.107: CN2401.5 14.39,109.99 14.49,110.1 14.91,110.1 15.54,110.73 16.14,110.73 17.54,112.14 17.99,112.14 18.12,112 D2406.1 D2406.10 19.9,112 20.04,112.14 20.49,112.14 20.93,111.71 21.41,111.71 21.71,111.41 L2432.3
USB3_SSRX1_DP: length 9.7
  BOTTOM w0.107: CN2401.6 14.39,110.44 14.51,110.31 14.82,110.31 15.45,110.94 16.05,110.94 17.46,112.34 17.95,112.34 18.12,112.5 D2406.2 D2406.9 19.83,112.5 19.99,112.35 20.58,112.35 21.02,111.91 21.44,111.91 21.73,112.21 L2432.4
USB3_SSTX1_C_DN: length 1.8
  BOTTOM w0.107: L2440.2 23.1,113.32 23.39,113.61 24.02,113.61 C2440.2
USB3_SSTX1_C_DP: length 1.8
  BOTTOM w0.107: L2440.1 23.13,114.12 23.44,113.82 24.03,113.82 C2441.2
USB3_SSTX1_L_DN: length 8.8
  BOTTOM w0.107: L2440.3 20.91,113.32 20.59,113.64 20.15,113.64 20.01,113.5 D2406.7 D2406.4 18.33,113.5 18.19,113.65 18.15,113.65 18.14,113.65 17.8,113.65 16.09,115.37 15.56,115.37 14.83,116.1 14.52,116.1 14.39,115.96 CN2401.8
USB3_SSTX1_L_DP: length 8.8
  BOTTOM w0.107: CN2401.9 14.39,116.41 14.49,116.31 14.92,116.31 15.65,115.57 16.17,115.57 17.88,113.86 18.22,113.86 18.36,114.01 D2406.5 D2406.6 20.01,114.01 20.17,113.85 20.63,113.85 20.9,114.12 L2440.4
USB_CAM_DN: length 67.7
  L3 w0.109: v3(81.24,85.87) 81.24,85.6 81.45,85.39 81.45,84.89 80.94,84.38 80.26,84.38 79.82,84.82 79.82,85.91 83.27,89.36 85.3,89.36 86.51,90.57 86.51,92.82 87.01,93.32 87.01,102.08 84.68,104.41 84.68,115.6 84.52,115.76 84.52,119.14 86.49,121.1 86.49,123.99 83.87,126.6 83.87,129.82 82.52,131.17 82.52,132.71 82.18,133.05 82.18,134.04 v1(81.83,134.39)
  BOTTOM w0.089: 78.68,87.35 78.67,87.36 78.65,87.36 78.02,87.98 77.5,87.98 U4500.A41
  BOTTOM w0.107: v3(81.24,85.87) 80.98,85.87 80.26,86.59 79.44,86.59 78.68,87.35 ; R3005.1 81.57,135.74 81.57,135.4 82.09,134.87 82.09,134.66 v1(81.83,134.39)
USB_CAM_DP: length 67.7
  L3 w0.109: v1(82.56,134.39) 82.39,134.23 82.39,133.14 82.73,132.8 82.73,131.26 84.08,129.91 84.08,126.69 86.7,124.07 86.7,121.02 84.73,119.05 84.73,115.85 84.89,115.69 84.89,104.5 87.22,102.17 87.22,93.23 86.72,92.73 86.72,90.48 85.38,89.15 83.35,89.15 80.03,85.82 80.03,84.91 80.35,84.59 80.85,84.59 81.24,84.98 81.24,85.3 81.07,85.47 80.85,85.47 v1(80.72,85.35)
  BOTTOM w0.089: 78.54,87.2 78.52,87.21 78.52,87.24 77.95,87.81 77.24,87.81 77.16,87.88 76.86,87.88 U4500.C41
  BOTTOM w0.107: v1(82.56,134.39) 82.3,134.66 82.3,134.96 81.77,135.48 81.77,135.74 R3029.1 ; v1(80.72,85.35) 80.79,85.41 80.79,85.77 80.17,86.38 79.36,86.38 78.54,87.2
USB_CAM_R_DN: length 17.9
  BOTTOM w0.107: CN3000.23 78.53,151.92 78.82,151.62 78.82,151.5 78.69,151.37 78.69,151.24 78.82,151.12 78.82,150.95 78.69,150.82 78.69,150.69 78.82,150.57 78.82,150.44 78.69,150.31 78.69,150.19 78.82,150.06 78.82,149.93 78.69,149.81 78.69,149.68 78.82,149.55 78.82,149.42 78.69,149.3 78.69,149.17 78.82,149.04 78.82,148.68 80.38,147.12 80.38,145.09 79.8,144.52 79.8,141.62 80.99,140.44 80.99,140.28 80.63,139.93 D3000.6 80.88,139.45 80.88,138.84 81.6,138.12 81.6,137.88 81.15,137.43 R3005.2
USB_CAM_R_DP: length 17.9
  BOTTOM w0.107: R3029.2 81.81,137.89 81.81,138.16 82.28,138.63 82.28,139.44 D3000.4 82.53,139.89 81.82,140.6 81.12,140.6 80.01,141.71 80.01,144.43 80.59,145 80.59,147.21 79.03,148.77 CN3000.24
USB_CR_DN: length 240.9
  L3 w0.109: v3(79.91,90.74) 80.17,91.01 80.49,91.01 81.07,90.42 84.81,90.42 85.5,91.12 85.5,93.87 86.52,94.89 86.52,100.27 84.18,102.61 84.18,114.17 82.82,115.52 82.82,119.94 77.47,125.29 77.47,125.81 68.76,134.51 66.37,134.51 65.52,135.36 39.24,135.36 37.16,137.44 36.58,137.44 34.69,139.33 24.7,139.33 24.01,138.64 19.46,138.64 16.23,135.41 16.23,122.71 19.17,119.77 19.17,118.57 19.83,117.91 19.83,115 18.48,113.65 18.48,108.52 17.26,107.3 17.26,74.02 18.97,72.31 18.97,57.7 16.93,55.66 16.93,45.04 18.86,43.11 18.86,32.17 16.19,29.51 16.19,21.43 17.03,20.59 17.49,20.59 v1(17.69,20.39)
  BOTTOM w0.107: U900.2 18.73,20.42 18.48,20.67 17.98,20.67 v1(17.69,20.39) ; v3(79.91,90.74) 79.66,91 79.13,91 78.25,90.12 77.5,90.12 U4500.A45
USB_CR_DP: length 240.9
  L3 w0.109: v1(17.69,21.1) 17.69,21.09 17.41,20.8 17.12,20.8 16.41,21.52 16.41,29.42 19.07,32.09 19.07,43.2 17.14,45.13 17.14,55.57 19.18,57.61 19.18,72.39 17.47,74.1 17.47,107.21 18.69,108.43 18.69,113.56 20.04,114.91 20.04,118 19.38,118.65 19.38,119.85 16.44,122.8 16.44,135.32 19.55,138.43 24.1,138.43 24.79,139.12 34.61,139.12 36.49,137.23 37.07,137.23 39.15,135.15 65.43,135.15 66.28,134.3 68.68,134.3 77.26,125.72 77.26,125.2 82.61,119.85 82.61,115.44 83.97,114.08 83.97,102.52 86.31,100.18 86.31,94.97 85.29,93.96 85.29,91.21 84.72,90.63 81.16,90.63 80.58,91.22 80.17,91.22 v1(79.91,91.48)
  BOTTOM w0.107: v1(79.91,91.48) 79.64,91.2 79.04,91.2 78.16,90.32 77.26,90.32 77.12,90.18 76.82,90.18 U4500.C45 ; U900.3 19.23,19.89 18.94,20.18 18.94,20.5 18.56,20.88 17.92,20.88 v1(17.69,21.1)
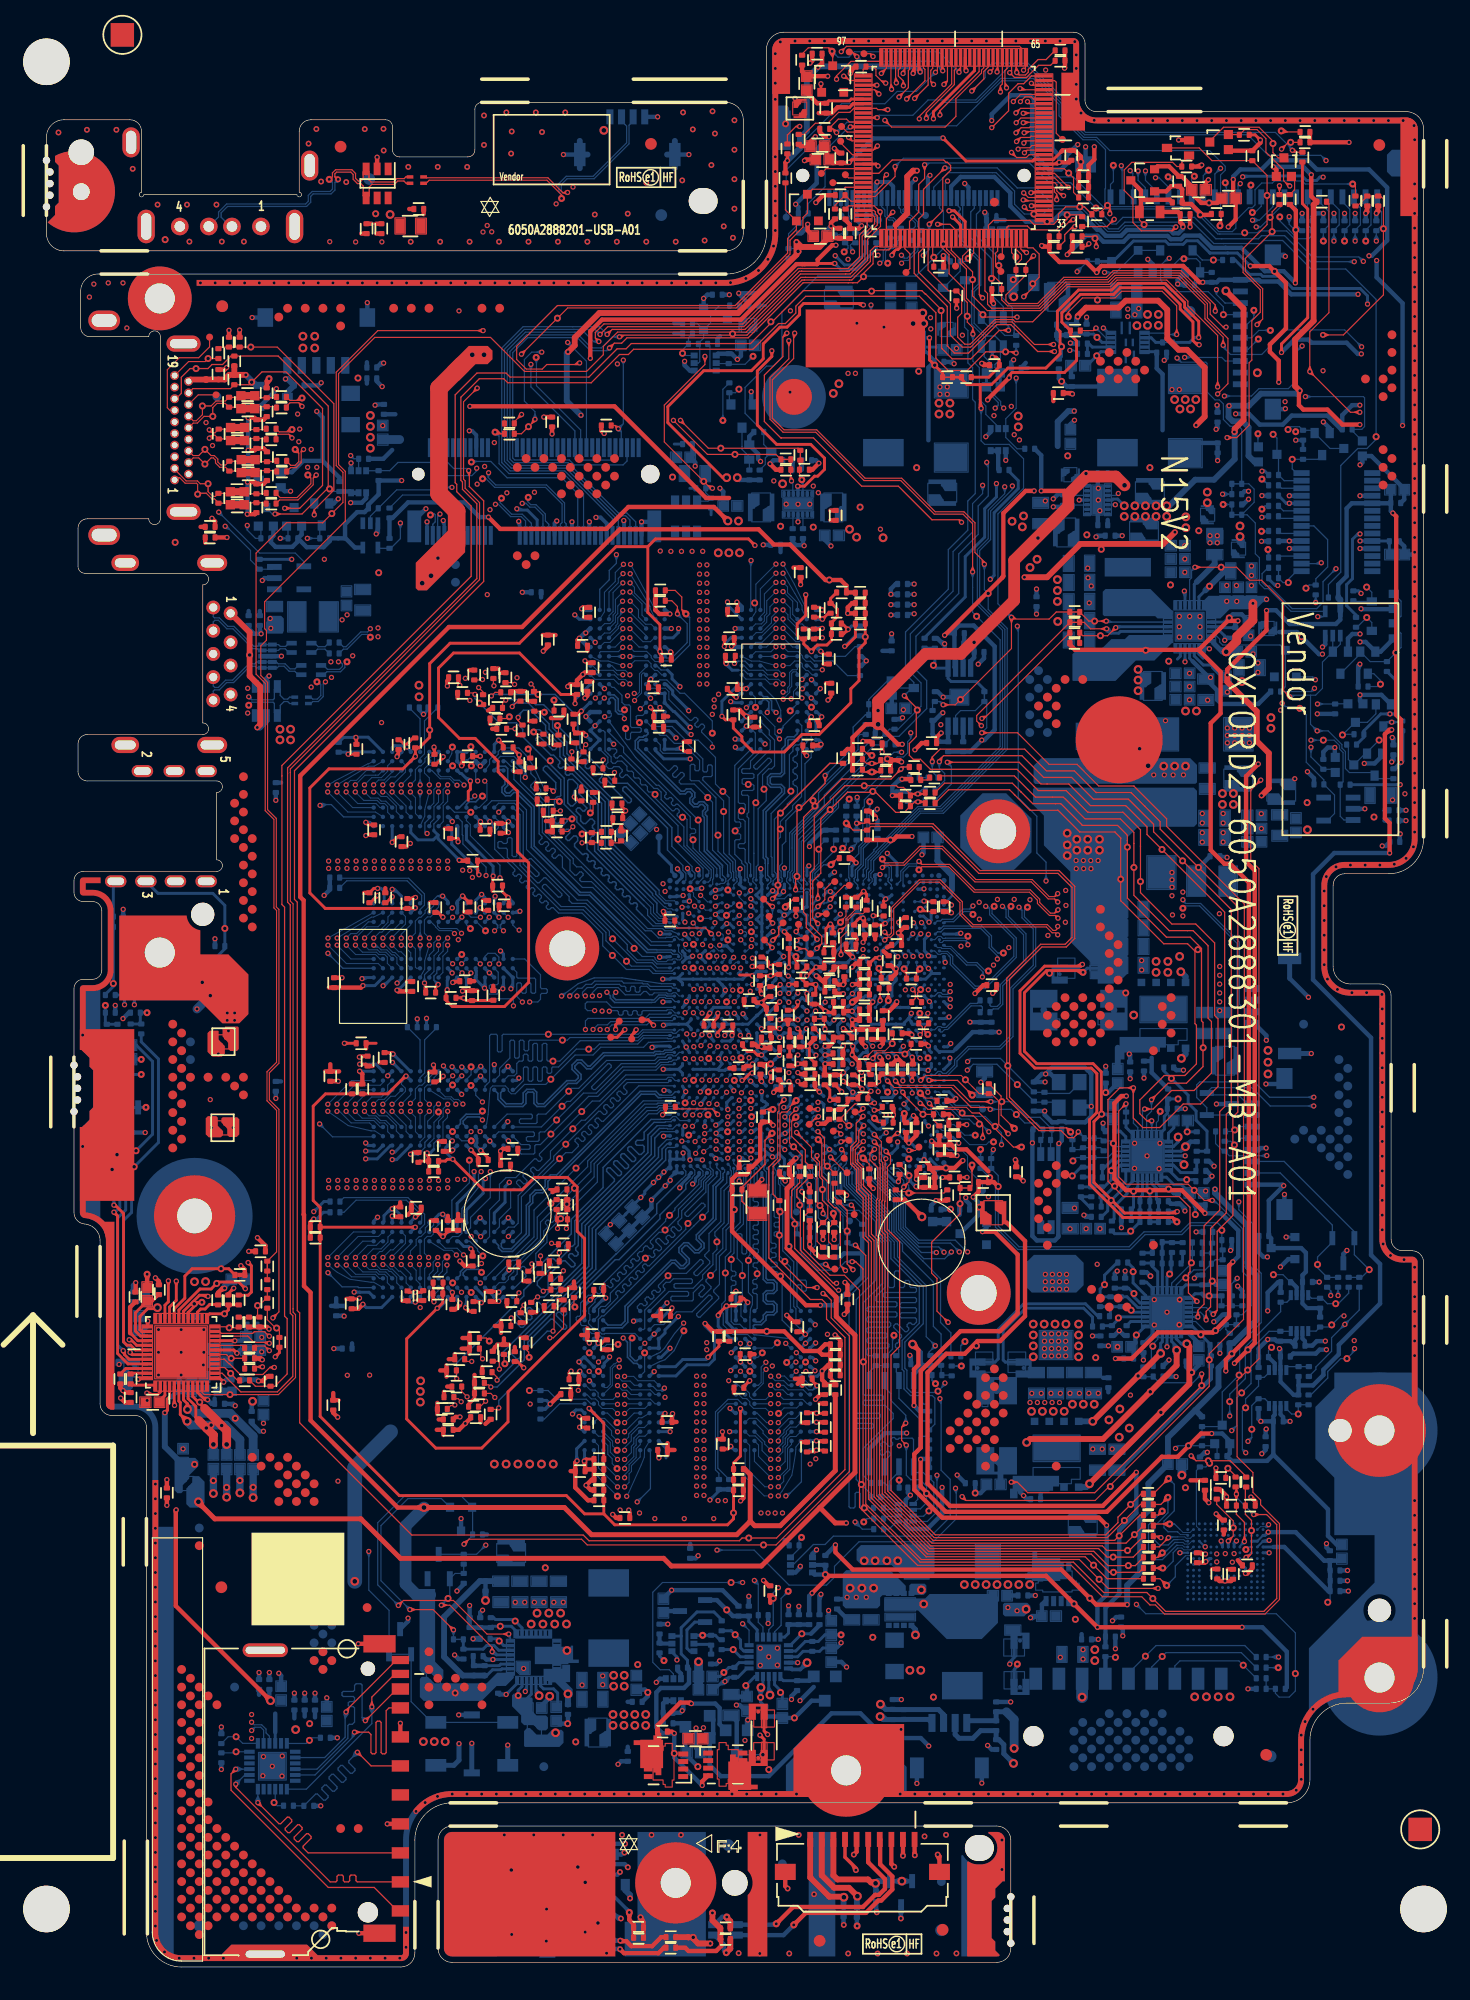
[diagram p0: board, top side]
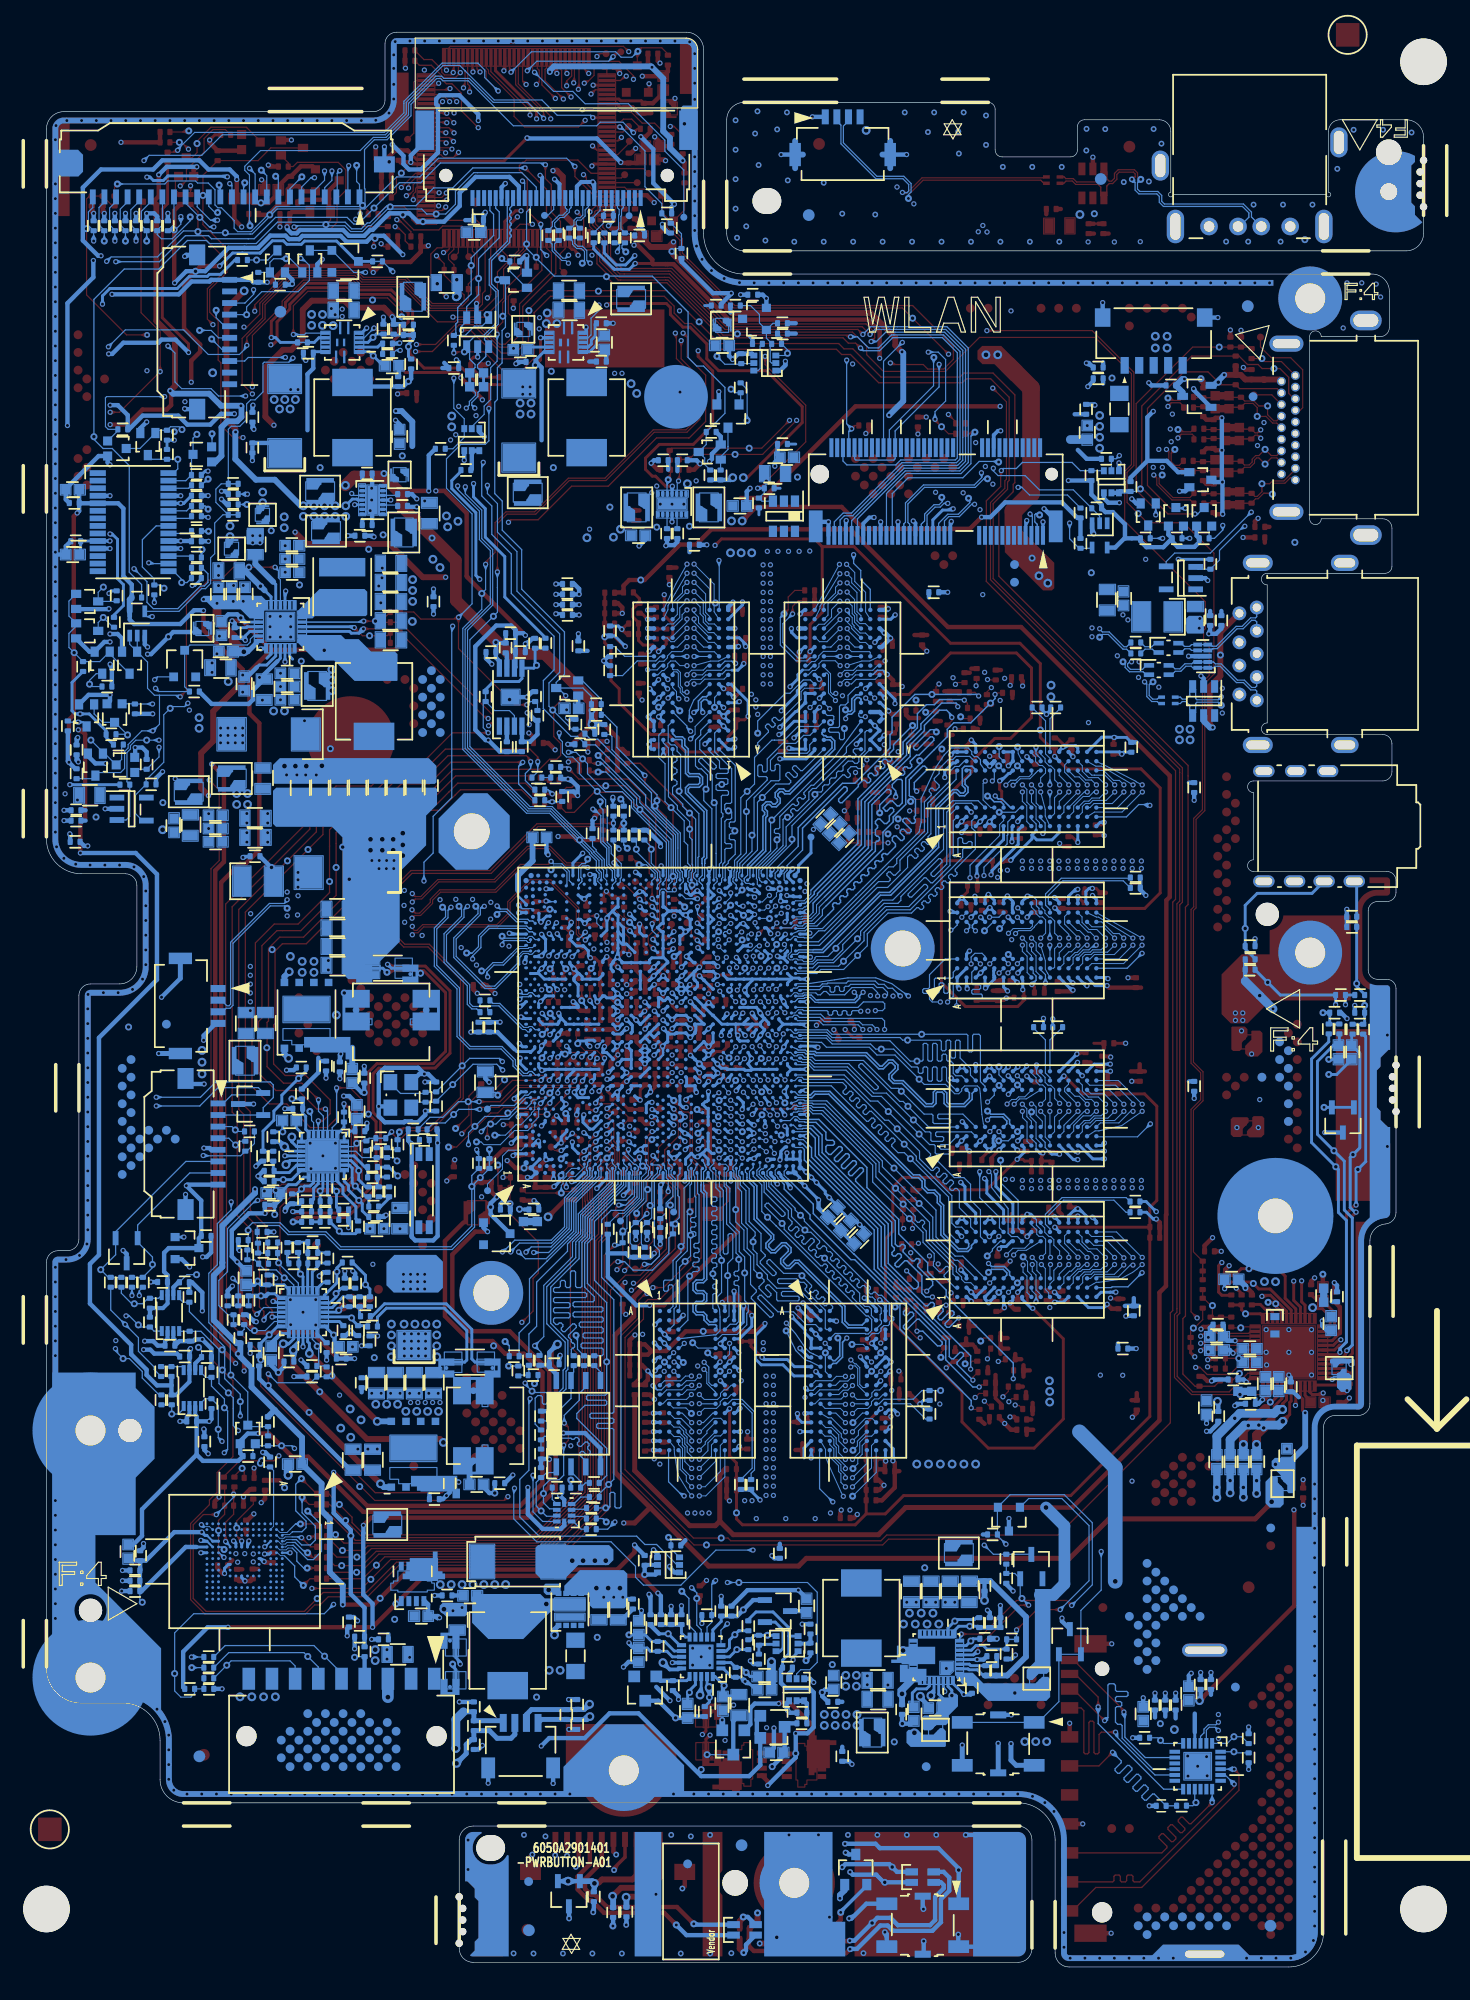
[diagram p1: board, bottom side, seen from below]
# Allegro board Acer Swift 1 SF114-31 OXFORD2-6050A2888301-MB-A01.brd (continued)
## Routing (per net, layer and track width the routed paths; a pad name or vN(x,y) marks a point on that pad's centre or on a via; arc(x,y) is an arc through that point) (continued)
USB_HSIC_RCOMP: length 1.5
  TOP w0.109: v3(71.8,86.09) 72,85.89 R4676.1
  BOTTOM w0.109: v3(71.8,86.09) 71.5,86.39 U4500.N38
USB_OC0#: length 5.4
  TOP w0.109: v1(71.42,74.48) 71.35,74.42 69.74,74.42 R4677.1 68.54,73.08 69.08,72.54 v2(69.21,72.54)
  BOTTOM w0.102: v1(71.42,74.48) 71.42,74.61 71.05,74.97 U4500.P14
USB_OC1#: length 1.3
  TOP w0.109: R4671.1 70.85,75.23 v1(71.12,75.51)
  BOTTOM w0.102: v1(71.12,75.51) 71.12,75.54 70.79,75.87 U4500.P16
USB_OC#_1: length 108
  TOP w0.102: U301.32 84.44,148.42 84.65,148.21 85.09,148.21 85.62,147.67 85.62,145.67 v2(85.07,145.12) 85.07,144.77 v1(84.29,143.99)
  L3 w0.102: v1(15.41,124.21) 15.41,126.14 15.05,126.5 15.05,138.09 19.05,142.09 61.55,142.09 64.69,145.23 64.69,147.82 66.45,149.58 66.45,149.81 69.63,152.98 73.61,152.98 75.73,150.86 75.73,150.07 76.02,149.78 77.88,149.78 82.98,144.68 83.61,144.68 v1(84.29,143.99)
  BOTTOM w0.102: U2406.3 19.46,120.5 R2410.2 17.6,121.29 17.6,122.12 15.52,124.21 v1(15.41,124.21)
USB_OC#_3: length 94
  TOP w0.102: U301.10 75.64,148.19 75.22,147.76 75.22,146.13 77.97,143.38 77.97,140.67 78.99,139.65 79.71,139.65 81.88,141.82 83.28,141.82 85.22,139.88 v1(86.86,139.88)
  L3 w0.102: v1(109.06,105.77) 109.06,106.66 109.54,107.14 110.17,107.14 111.23,108.2 111.23,119.35 111.63,119.75 111.63,121.07 111.26,121.44 111.26,122.78 111.26,122.78 111.26,129.54 109.25,131.55 109.25,136.38 107.45,138.18 107.45,139.61 106.89,140.16 105.83,140.16 105.34,139.68 103.11,139.68 102.08,140.7 100.62,140.7 98.17,143.14 96.86,143.14 96.12,143.88 88.1,143.88 86.86,142.65 v1(86.86,139.88)
  BOTTOM w0.102: v1(109.06,105.77) v2(110.13,105.77) 111.06,105.77 111.53,105.3 111.53,105 111.83,104.7 111.83,102.18 R2001.2 111.59,99.2 111.91,98.88 U2000.3
USB_P0_DN: length 113.8
  L3 w0.109: v3(23.33,110.79) 23.49,110.79 23.67,110.61 23.67,110.27 23.9,110.04 24.59,110.04 25.35,110.79 25.35,111.37 24.75,111.97 24.19,111.97 24.08,112.08 24.08,113.48 27.98,117.37 38.3,117.37 40.74,119.81 41.25,119.81 44.75,123.31 44.75,124.6 46.7,126.55 56,126.55 56.22,126.76 65.95,126.76 66.69,126.02 66.69,125.11 73.37,118.43 73.37,114.21 76.48,111.11 76.48,104.92 75.76,104.2 75.76,99.26 75.1,98.6 75.1,96.67 74.41,95.98 74.41,93.79 73.99,93.37 73.99,88.78 72.82,87.61 72.82,86.82 73.16,86.48 76.57,86.48 78.56,88.47 79.29,88.47 79.47,88.29 v1(79.47,88.13)
  BOTTOM w0.089: U4500.B42 77.02,88.39 77.09,88.32 77.23,88.32 77.4,88.49 77.53,88.49
  BOTTOM w0.107: v3(23.33,110.79) 23.41,110.79 23.66,110.54 23.66,109.61 23.35,109.3 22.97,109.3 22.8,109.47 L2404.1 ; 77.53,88.49 79.32,88.49 79.47,88.34 v1(79.47,88.13)
USB_P0_DP: length 113.8
  L3 w0.109: v3(79.47,88.86) 79.29,88.68 78.47,88.68 76.49,86.69 73.25,86.69 73.03,86.91 73.03,87.52 74.2,88.69 74.2,93.28 74.62,93.71 74.62,95.89 75.32,96.58 75.32,98.51 75.97,99.17 75.97,104.12 76.69,104.83 76.69,111.19 73.58,114.3 73.58,118.52 66.9,125.2 66.9,126.11 66.04,126.97 56.13,126.97 55.91,126.76 46.61,126.76 44.54,124.69 44.54,123.4 41.17,120.02 40.65,120.02 38.21,117.58 27.89,117.58 23.87,113.56 23.87,111.99 24.11,111.76 24.66,111.76 25.14,111.28 25.14,110.88 24.5,110.25 23.99,110.25 23.88,110.36 23.88,110.61 v1(24.06,110.79)
  BOTTOM w0.089: U4500.C42 76.62,88.56 76.9,88.85 77.14,88.85 77.31,88.67 77.5,88.67 77.52,88.7 77.53,88.7
  BOTTOM w0.107: L2404.2 22.8,108.92 22.97,109.1 23.44,109.1 23.87,109.53 23.87,110.6 v1(24.06,110.79) ; 77.53,88.7 79.31,88.7 v3(79.47,88.86)
USB_P0_L_DN: length 12.1
  L3 w0.109: v1(17.45,109.51) 17.45,109.46 17.23,109.25 17.06,109.25 16.95,109.36 16.95,112.85 16.53,113.26 16.02,113.26 15.88,113.39 CN2401.2
  BOTTOM w0.107: v1(17.45,109.51) 17.71,109.25 19.55,109.25 19.66,109.35 19.66,110.13 D2409.3 20.16,110.14 20.16,109.63 20.49,109.3 20.8,109.3 20.98,109.47 L2404.4
USB_P0_L_DP: length 12.1
  L3 w0.109: CN2401.3 15.89,112.94 16,113.05 16.44,113.05 16.73,112.76 16.73,109.27 16.97,109.04 17.19,109.04 v3(17.45,108.77)
  BOTTOM w0.107: L2404.3 20.98,108.92 20.8,109.1 20.5,109.1 20.16,108.76 20.16,108.14 D2409.4 19.66,108.15 19.66,108.93 19.55,109.04 17.71,109.04 v3(17.45,108.77)
USB_P2_DN: length 79.1
  L3 w0.109: v3(82.54,87.42) 82.48,87.36 82.48,87.02 82.6,86.91 82.9,86.91 84.27,88.28 87.94,88.28 88.4,88.75 89.2,88.75 89.69,89.24 90.02,89.24 90.45,88.81 90.61,88.81 90.84,89.04 90.84,89.2 90.41,89.63 90.41,89.96 90.76,90.31 91.09,90.31 91.57,89.83 91.73,89.83 91.96,90.07 91.96,90.22 91.58,90.6 91.58,91.13 92.12,91.67 92.68,91.67 92.91,91.44 92.91,88.89 93.02,88.78 93.35,88.78 93.46,88.89 93.46,92.54 93.69,92.77 94.2,92.77 94.43,92.54 94.43,88.92 94.54,88.81 94.87,88.81 94.97,88.92 94.97,93.23 94.87,93.34 94.56,93.34 94.32,93.57 94.32,94.08 94.56,94.31 94.87,94.31 94.97,94.42 94.97,94.75 94.87,94.85 94.56,94.85 94.32,95.09 94.32,95.59 94.56,95.82 94.87,95.82 94.97,95.93 94.97,96.26 94.87,96.37 94.58,96.37 94.35,96.6 94.35,97.1 94.58,97.34 94.87,97.34 94.97,97.45 94.97,97.77 94.87,97.88 94.56,97.88 94.32,98.11 94.32,98.62 94.56,98.85 94.87,98.85 94.97,98.96 94.97,99.54 95.21,99.77 95.71,99.77 95.94,99.54 95.94,89.07 96.05,88.96 96.38,88.96 96.49,89.07 96.49,91.44 96.72,91.67 97.81,91.67 98.02,91.87 v1(98.02,92.01)
  BOTTOM w0.107: U4500.B44 77.15,89.54 77.35,89.74 80.66,89.74 81.51,88.89 81.51,87.96 82.07,87.41 82.53,87.41 v3(82.54,87.42) ; v1(98.02,92.01) 98.02,91.92 98.25,91.69 99.55,91.69 102.89,88.34 102.89,83 103.02,82.86 103.21,82.86 103.69,83.35 CN2002.2
USB_P2_DN_A: length 23.9
  TOP w0.107: L2406.1 32.75,153.77 33.01,154.04 43.16,154.04 44.43,152.77 v3(44.43,152.47)
  BOTTOM w0.107: v3(44.43,152.47) 44.43,152.8 44.2,153.03 44.2,153.75 44.82,154.38 47.15,154.38 50.04,157.27 50.04,158.71 49.6,159.15 CN2003.3
USB_P2_DP: length 79.1
  L3 w0.109: v3(98.02,91.27) 97.83,91.46 96.81,91.46 96.7,91.35 96.7,88.98 96.47,88.75 95.96,88.75 95.73,88.98 95.73,99.45 95.62,99.56 95.29,99.56 95.19,99.45 95.19,98.87 94.95,98.64 94.64,98.64 94.54,98.53 94.54,98.2 94.64,98.09 94.95,98.09 95.19,97.86 95.19,97.36 94.95,97.13 94.67,97.13 94.56,97.02 94.56,96.69 94.67,96.58 94.95,96.58 95.19,96.35 95.19,95.84 94.95,95.61 94.64,95.61 94.54,95.5 94.54,95.17 94.64,95.07 94.95,95.07 95.19,94.83 95.19,94.33 94.95,94.1 94.64,94.1 94.54,93.99 94.54,93.66 94.64,93.55 94.95,93.55 95.19,93.32 95.19,88.83 94.95,88.6 94.45,88.6 94.22,88.83 94.22,92.45 94.11,92.56 93.78,92.56 93.67,92.45 93.67,88.8 93.44,88.57 92.94,88.57 92.7,88.8 92.7,91.35 92.59,91.46 92.21,91.46 91.79,91.04 91.79,90.69 92.17,90.31 92.17,89.98 91.81,89.62 91.49,89.62 91.01,90.1 90.85,90.1 90.62,89.87 90.62,89.72 91.05,89.28 91.05,88.95 90.7,88.6 90.37,88.6 89.94,89.03 89.78,89.03 89.29,88.54 88.49,88.54 88.02,88.07 84.36,88.07 82.99,86.7 82.51,86.7 82.31,86.9 v1(82.02,86.9)
  BOTTOM w0.107: v3(98.02,91.27) 98.22,91.48 99.46,91.48 102.68,88.25 102.68,82.91 102.94,82.66 103.27,82.66 103.57,82.35 CN2002.3 ; v1(82.02,86.9) 82.02,87.16 81.3,87.88 81.3,88.81 80.58,89.53 77.44,89.53 77.16,89.26 77.16,89.26 77.14,89.24 76.85,89.24 U4500.C43
USB_P2_DP_A: length 23.9
  TOP w0.107: v1(44.95,152.99) 44.92,152.96 44.54,152.96 43.25,154.25 32.81,154.25 32.73,154.32 L2406.2
  BOTTOM w0.107: v1(44.95,152.99) 44.92,152.96 44.56,152.96 44.41,153.11 44.41,153.67 44.91,154.17 47.24,154.17 50.25,157.18 50.25,158.78 50.6,159.13 CN2003.2
USB_P2_L_DN: length 23.5
  TOP w0.107: L2406.4 31.03,153.77 30.83,153.97 30.3,153.97 30.01,153.68 28.07,153.68 27.84,153.45 27.84,152.7 27.65,152.51 D2410.4 27.52,152.51 27.32,152.71 27.32,153.54 27.11,153.75 26.82,153.75 26.45,154.12 26.45,154.53 26.25,154.74 25.03,154.74 24.87,154.58 24.87,154.34 25.1,154.11 v4(25.16,154.11)
  BOTTOM w0.107: v4(25.16,154.11) 24.88,153.83 24.88,153.19 24.55,152.86 23.01,152.86 22.79,152.64 22.79,152.14 22.43,151.78 15.62,151.78 15.07,151.22 15.07,150.85 15.87,150.05 CN2403.2
USB_P2_L_DP: length 23.5
  TOP w0.107: L2406.3 31,154.32 30.86,154.18 30.21,154.18 29.92,153.89 27.99,153.89 27.82,154.06 27.82,154.76 27.57,155.01 D2410.3 27.32,154.76 27.32,154.16 27.12,153.96 26.9,153.96 26.66,154.2 26.66,154.62 26.34,154.94 24.94,154.94 24.67,154.67 24.67,154.34 24.44,154.11 v3(24.39,154.11)
  BOTTOM w0.107: v3(24.39,154.11) 24.67,153.83 24.67,153.27 24.47,153.07 22.92,153.07 22.58,152.73 22.58,152.22 22.35,151.99 15.54,151.99 14.84,151.29 14.84,150.87 14.02,150.05 CN2403.3
USB_RCOMP: length 6.6
  BOTTOM w0.203: U4500.A48 77.4,91.65 78.1,92.34 78.1,92.84
  BOTTOM w0.508: R4564.1 76.85,95.37 76.85,95.36 78.1,94.11 78.1,92.84
USB_VBUS_SENSE: length 2.2
  TOP w0.254: v1(78.06,91.55) 77.76,91.85 77.4,91.85 R4837.2
  BOTTOM w0.102: v1(78.06,91.55) 77.75,91.24 76.93,91.24 U4500.B47
USB_WLAN_DN: length 106.5
  L3 w0.109: v3(81.74,91.44) 81.56,91.62 81.56,93.12 84.4,95.96 84.4,99.16 82.01,101.55 82.01,113.21 78.63,116.59 78.63,121.01 75.35,124.28 75.35,124.95 67.95,132.35 64.8,132.35 63.98,133.17 59.72,133.17 59.46,132.92 50.32,132.92 48.28,130.88 43.33,130.88 40.13,127.68 40.13,126.38 37.92,124.18 34.15,124.18 33.74,124.59 33.74,125.06 v1(33.94,125.26)
  BOTTOM w0.089: U4500.C40 76.62,87.59 76.91,87.3 77.13,87.3 77.21,87.38 77.64,87.38 77.86,87.16 77.86,87.14 77.88,87.12
  BOTTOM w0.107: v1(33.94,125.26) 33.74,125.06 33.74,123.5 CN1300.5 ; v3(81.74,91.44) 81.56,91.25 81.56,90.8 83.64,88.72 83.64,87.04 80.96,84.35 80.03,84.35 77.96,86.42 77.96,87.04 77.88,87.12
USB_WLAN_DP: length 106.4
  L3 w0.109: v3(33.12,125.18) 33.12,125.23 33.23,125.34 33.38,125.34 33.53,125.19 33.53,124.5 34.07,123.97 38.01,123.97 40.34,126.3 40.34,127.59 43.42,130.67 48.37,130.67 50.41,132.7 59.55,132.7 59.8,132.96 63.89,132.96 64.71,132.14 67.86,132.14 75.14,124.86 75.14,124.2 78.42,120.92 78.42,116.5 81.8,113.12 81.8,101.46 84.19,99.08 84.19,96.05 81.35,93.21 81.35,91.58 81.21,91.44 v1(81.01,91.44)
  BOTTOM w0.089: 78.02,87.27 78.01,87.28 77.99,87.28 77.71,87.56 77.05,87.56 U4500.B40
  BOTTOM w0.107: CN1300.3 33.32,124.38 33.53,124.59 33.53,125.2 33.42,125.31 33.24,125.31 v3(33.12,125.18) ; 78.02,87.27 78.17,87.13 78.17,86.51 80.11,84.56 80.87,84.56 83.44,87.12 83.44,88.63 81.35,90.72 81.35,91.28 81.19,91.44 v1(81.01,91.44)
VGG_SENSEN: length 27.4
  BOTTOM w0.109: R6763.1 100.6,62.47 R4701.2 100.6,63.76 100.44,63.92 98.72,63.92 97.94,63.14 94.77,63.14 93.48,61.85 83.78,61.85 81.85,63.78 81.85,67.55 v2(81.36,68.05) R4622.2
VGG_SENSEN_R: length 20.5
  L4 w0.135: v3(80.57,70.48) 79.01,72.04 75.02,72.04 74.18,72.87 72.41,72.87 71.94,73.34 71.94,74.54 71.59,74.89 68.57,74.89 66.37,77.1 v1(66.37,78.61)
  BOTTOM w0.109: v1(66.37,78.61) 65.98,78.99 U4500.AD22 ; R4622.1 v3(80.57,70.48)
VGG_SENSEP: length 28.3
  BOTTOM w0.109: R6766.1 101.38,61.89 R4699.2 v2(101.38,63.51) 101.38,63.79 101,64.16 98.62,64.16 97.84,63.38 94.67,63.38 93.38,62.09 83.88,62.09 82.09,63.88 82.09,68.23 R4621.2
VGG_SENSEP_R: length 23.3
  L4 w0.135: v1(66.39,79.36) 65.96,78.93 65.96,77.19 68.5,74.65 70.37,74.65 70.92,74.1 70.92,73.08 71.36,72.65 74.06,72.65 74.93,71.78 78.53,71.78 80.39,69.93 81.12,69.93 v1(81.67,70.47)
  BOTTOM w0.109: U4500.AD24 v1(66.39,79.36) ; v1(81.67,70.47) 81.48,70.28 R4621.1
VGG_TSENSE: length 4
  BOTTOM w0.109: U6700.13 95.85,54.12 95.42,53.69 v2(95.42,53.52) 95.3,53.39 95.3,51.97 C6746.1 94.69,51.82 R6712.1
VNN_SENSE_R: length 1.5
  TOP w0.109: R4623.1 67.09,80.92 v1(67.15,80.86)
  BOTTOM w0.109: U4500.AC27 66.77,81.24 v1(67.15,80.86)
VNN_SENSEP: length 2
  TOP w0.109: R4726.2 66.95,80.13 R4836.2 66.2,81.71 R4623.2
VR_SVID_VCC_ALERT#: length 51.4
  TOP w0.109: R4614.2 77.46,102.06 83.3,102.06 84.07,101.28 85.07,100.29 87.01,100.29 87.48,100.29 89.35,98.42 92.38,98.42 93.23,97.57 93.23,97.1 v2(93.23,96.55) 93.23,92.15 96.6,88.78 98.66,88.78 99.29,88.15 99.62,87.81 99.62,81.56 99.75,81.44 99.75,77.62 99.42,77.29 98.32,76.19 96.74,76.19 v1(95.31,74.76)
  BOTTOM w0.109: U6600.4 94.89,71.81 94.89,73.35 95.31,73.77 v1(95.31,74.76)
VR_SVID_VCC_CLK: length 51.4
  TOP w0.109: R4592.2 77.81,101.49 83.07,101.49 83.51,101.05 84.83,99.72 87.24,99.72 89.11,97.85 92.15,97.85 92.66,97.34 v2(92.66,93.78) 92.66,91.92 96.36,88.21 98.42,88.21 99.06,87.58 99.06,81.33 99.18,81.2 99.18,77.85 98.19,76.86 96.41,76.86 94.3,74.75 94.3,73.56 94.92,72.95 v1(95.33,72.95)
  BOTTOM w0.109: U6600.5 v1(95.33,72.95)
VR_SVID_VCC_DATA: length 52.9
  TOP w0.109: R4846.2 77.03,102.57 77.14,102.68 83.47,102.68 84.64,101.52 85.3,100.86 86.78,100.86 87.71,100.86 89.58,98.99 92.61,98.99 93.79,97.81 93.79,96.87 v2(93.79,94.79) 93.79,92.39 96.83,89.35 98.42,89.35 98.89,89.35 99.53,88.71 99.53,88.71 100.19,88.05 100.19,81.8 100.48,81.51 100.48,77.06 98.98,75.56 97.05,75.56 95.45,73.96 v1(94.71,73.96)
  BOTTOM w0.109: U6600.3 94.53,73.78 v1(94.71,73.96)
VR_SVID_VGG_ALERT#: length 72.5
  TOP w0.109: v1(77.01,103.91) 77.01,104.06 77.37,104.43 84.14,104.43 86.01,102.55 88.42,102.55 90.29,100.69 93.32,100.69 95.49,98.51 95.49,97.86 v2(97.99,95.36) 102.19,91.17 102.19,73.94 101.76,73.51 101.76,65.02 100.41,63.66 100.41,56.91 100.02,56.53 v1(100.02,55.78)
  BOTTOM w0.109: U6700.4 99.53,56.45 100.02,55.96 v1(100.02,55.78) ; R4647.2 76.68,101.5 77.47,102.29 77.47,102.89 77.01,103.35 v1(77.01,103.91)
VR_SVID_VGG_CLK: length 70.4
  TOP w0.109: v1(99.31,56.03) 99.31,56.62 99.84,57.15 99.84,63.9 101.19,65.25 101.19,73.74 101.62,74.17 101.62,90.93 v2(96.22,96.34) 94.92,97.63 94.92,98.28 93.08,100.12 90.05,100.12 88.18,101.99 86.31,101.99 85.77,101.99 83.9,103.86 v1(77.7,103.86)
  BOTTOM w0.109: R4596.2 78.05,101.99 78.05,103.5 v1(77.7,103.86) ; v1(99.31,56.03) 99.29,56.05 U6700.5
VR_SVID_VGG_DATA: length 73
  TOP w0.109: v1(76.4,103.91) 76.4,104.32 77.08,104.99 84.37,104.99 86.24,103.12 88.65,103.12 90.52,101.25 93.55,101.25 93.58,101.23 94.73,100.07 94.73,100.07 96.06,98.75 96.06,98.1 v2(99.36,94.79) 102.76,91.4 102.76,73.7 102.33,73.27 102.33,64.78 100.97,63.43 100.97,56.6 v1(100.63,56.26)
  BOTTOM w0.109: R4847.2 76.4,103.04 v1(76.4,103.91) ; U6700.3 100.04,56.85 v1(100.63,56.26)
VRA3V3A_LDO: length 2
  BOTTOM w0.254: U6100.6 77.06,139.66 C6121.1
  vias: v2(77.16,142.8)
VRA3V3A_VCC: length 2.8
  BOTTOM w0.254: U6100.11 72.05,139.66 71.78,139.92 71.78,140.26 71.45,140.59 71.45,141.6 C6122.1
VRA5V0A_VCC: length 3
  BOTTOM w0.254: R6198.1 C6172.1 89.91,139.95 90.2,139.66 U6150.11
VRACHG_ACDET: length 6.5
  BOTTOM w0.254: U6000.6 61.3,29.06 60.58,29.78 R6003.1
  BOTTOM w0.381: D60003.2 57.83,31.63 v2(58.67,30.79) 59.2,30.26 R6002.1 R6003.1
VRACHG_ACDRV: length 3.5
  BOTTOM w0.254: R6004.1 59.06,28.99 v2(59.4,28.65) 59.86,28.18 59.86,27.52 60.14,27.24 U6000.4
VRACHG_ACDRV1: length 25.2
  TOP w0.381: v1(56.56,15.65) 56.56,16 57.05,16.49 Q6011.4 ; C6030.2 53.95,20.29
  BOTTOM w0.254: 54.75,28.53 54.75,26.99 55.29,26.45 R60022.1 ; 54.75,28.53 Q60003.6 ; 54.75,28.53 54.75,29.25 56.11,30.61 57.57,30.61 58.24,29.94 R6004.2
  BOTTOM w0.381: v1(56.56,15.65) 54.15,18.06 v2(54.15,18.41) v1(54.15,20.14) 53.13,20.14 52.6,20.68 52.6,23.67 52.98,24.05 55,24.05 55.42,24.48 55.42,25.67 R60022.1
VRACHG_ACN: length 12.4
  TOP w0.254: R6000.4 61.9,20.34 v1(62.2,20.04)
  L4 w0.254: v1(58.52,24.61) 58.19,24.28 58.19,22.78 60.17,20.8 61.44,20.8 v1(62.2,20.04)
  BOTTOM w0.254: U6000.1 60.41,25.74 59.64,24.98 C6020.2 58.88,24.98 v1(58.52,24.61) 58.32,24.61 57.6,23.9 C6022.1
VRACHG_ACP: length 12.9
  TOP w0.254: R6000.3 61.9,19.63 v1(61.54,19.99)
  L4 w0.254: v3(58.43,25.39) 57.81,24.77 57.81,22.63 60.01,20.42 61.11,20.42 v1(61.54,19.99)
  BOTTOM w0.254: C6021.1 58.08,25.04 v3(58.43,25.39) 58.86,25.83 C6020.1 59.74,26.24 U6000.2
VRACHG_BATDRV: length 3.4
  BOTTOM w0.254: U6000.11 64.16,27.74 v2(65.15,28.73) 65.94,28.73
  BOTTOM w0.381: R6009.1 66.67,29.46 65.94,28.73
VRACHG_BATDRV1: length 33.5
  L4 w0.381: v1(66.8,32.13) 66.8,33.17 69.97,36.35 85.85,36.35 87.14,35.05 87.14,32.38 v1(84.87,30.11)
  BOTTOM w0.381: v1(66.8,32.13) 66.67,32 R6009.2 ; v1(84.87,30.11) 85.01,30.25 C6033.2 85.86,31.26 Q6012.4
VRACHG_BST: length 2.6
  BOTTOM w0.254: R6020.1 63.47,23.51 v2(63.31,23.67) 63.31,23.83 62.8,24.34 U6000.17
VRACHG_BST1: length 5.8
  BOTTOM w0.381: C6027.1 63.35,21.59 R6020.2 v2(64.51,21.47) 65.99,22.95 D6001.3
VRACHG_CMSRC: length 2.6
  BOTTOM w0.254: R6005.1 v2(59.23,27.36) 59.23,27.36 59.85,26.74 U6000.3
VRACHG_CMSRC1: length 13.7
  L4 w0.254: v1(56.66,20.62) 56.66,21.11 56.25,21.52 56.25,23.06 53.87,25.44 53.87,27.28 55.19,28.59 v3(56.59,28.59)
  BOTTOM w0.254: Q60003.1 55.91,28.59 v3(56.59,28.59) R60020.1 57.69,28.59 58.07,28.21 R6005.2
VRACHG_HG: length 19.4
  L4 w0.508: v5(62.4,23.44) 63.08,24.12 70.44,24.12 72,25.68 72,28.52 72.65,29.16 74.42,29.16 v5(74.95,28.63)
  BOTTOM w0.254: U6000.18 62.3,23.55 v5(62.4,23.44)
  BOTTOM w0.432: v5(74.95,28.63) 74.95,29.1 Q6000.1
VRACHG_ILIM: length 3.4
  BOTTOM w0.254: U6000.10 63.67,28.44 64,28.78 C6032.1
  BOTTOM w0.381: R6007.1 65.78,29.52 R6008.2 64.89,29.52 C6032.1
VRACHG_MP1: length 11.1
  L4 w0.254: v1(60.25,19.53) 58.82,19.53 56.73,21.62 56.73,23.12 54.38,25.48 v1(54.38,26.47)
  BOTTOM w0.254: Q60003.4 53.95,27.15 54.38,26.72 v1(54.38,26.47)
  vias: v2(62.3,17.02)
VRACHG_PH: length 21.2
  L4 w0.508: v5(61.62,24.1) 62.54,25.02 69.62,25.02 71.13,26.53 71.13,28.81 72.63,30.31 74.68,30.31 v5(75.66,31.29)
  BOTTOM w0.254: C6027.2 61.59,22.85 61.59,22.86 v2(61.59,23.24) 61.59,24.07 v5(61.62,24.1) 61.8,24.27 61.8,25.04 U6000.19
VRACHG_REGN: length 25.3
  L4 w0.254: v1(65,22.96) 64.06,22.03 62.14,22.03 60.21,23.96 60.21,28.38 59.28,29.31 55.1,29.31 53.26,27.47 v3(53.26,26.42)
  BOTTOM w0.254: v3(53.26,26.42) 52.88,26.8 R60023.1 ; U6000.16 63.3,24.94 63.56,24.68 C6028.1
  BOTTOM w0.381: C6028.1 65.81,24.68 D6001.1 ; 66.18,24.14 v1(65,22.96)
VRACHG_SNB: length 1
  BOTTOM w0.381: C7600.1 82.87,32.03 R7600.2
VRACHG_SRN: length 37.3
  L3 w0.254: v1(83.08,26.11) 83.08,26.19 85.78,28.89 85.78,33.47 85.44,33.82 69.22,33.82 68.34,32.94 68.34,28.83 v3(68.54,28.63)
  BOTTOM w0.254: U6000.12 64.63,27.24 65.45,28.07 C6023.2 66.57,28.07 67.14,28.63 C6025.1 v3(68.54,28.63) ; v1(83.08,26.11) 83.08,26.29 83.46,26.67 R6001.4
VRACHG_SRP: length 39.4
  L3 w0.254: v1(68.54,27.95) 67.96,28.53 67.96,33.19 69.03,34.26 79.89,34.26 79.91,34.24 85.64,34.24 86.23,33.65 86.23,28.65 83.74,26.16 v3(83.74,26.11)
  BOTTOM w0.254: v3(83.74,26.11) 83.74,25.91 83.46,25.63 R6001.3 ; U6000.13 64.79,26.74 65.26,27.21 C6023.1 66.68,27.21 66.97,27.5 C6024.1 68.19,27.5 68.54,27.85 v1(68.54,27.95)
VRACHG_VCC: length 3.7
  BOTTOM w0.254: U6000.20 61.11,25.04 v2(60.32,24.26)
  BOTTOM w0.381: R6012.1 59.22,23.31 C6026.2 60.42,24.15 v2(60.32,24.26)
VRACPU_BST: length 1.8
  BOTTOM w0.254: C6615.2 v2(98.39,72) 98.39,72.93 R6615.1
VRACPU_BST1: length 2
  BOTTOM w0.254: U6600.8 96.77,71.88 97.24,72.35 R6615.2
VRACPU_CSN1: length 38.6
  TOP w0.254: v3(89.4,85.75) 89.25,85.9 86.26,85.9 84.35,84 84.35,78.94 85.41,77.88 90.27,77.88 90.98,77.17 90.98,73.52 90.34,72.88 90.34,67.64 92.99,65 97.41,65 v1(97.53,65.13)
  BOTTOM w0.254: R6610.4 89.76,86.11 v3(89.4,85.75) ; R6647.2 v1(97.53,65.13)
VRACPU_CSP1: length 39.8
  TOP w0.254: v1(89.35,86.44) 89.2,86.28 86.1,86.28 83.97,84.16 83.97,78.78 85.25,77.49 90.12,77.49 90.6,77.01 90.6,73.67 89.96,73.04 89.96,67.48 92.83,64.62 97.12,64.62 v3(97.5,64.24)
  BOTTOM w0.254: R6610.3 89.02,86.11 v1(89.35,86.44) ; R6649.2 v3(97.5,64.24)
VRACPU_VDD: length 3.9
  BOTTOM w0.254: C6642.1 92.61,72.06 93.09,71.57 U6600.28 ; R6645.1 91.82,73.11 91.4,73.52 v2(91.01,73.52)
  BOTTOM w0.381: C6642.1 92.17,72.94 R6645.1
VRAVDDQ_BST: length 3.5
  BOTTOM w0.254: R60315.1 44.09,22.55 44.09,23.62 43.74,23.98 42.87,23.98 42.62,24.23 U60300.27
VRAVDDQ_BST1: length 1.9
  BOTTOM w0.381: R60315.2 44.2,20.98 v2(44.95,20.98) 44.98,21.01 C60315.2
VRAVDDQ_CS: length 3.6
  BOTTOM w0.254: U60300.10 41.02,29.23 v2(40.43,29.82) 40.29,29.95 38.73,29.95 38.57,30.12 R60305.2
VRAVDDQ_SET: length 4
  BOTTOM w0.254: R60300.1 39.06,25.98 39.19,26.11 U60300.3
  BOTTOM w0.381: R60301.2 36.81,26.04 C60304.2 36.88,25.98 R60300.1
VRAVDDQ_SNB: length 2.1
  BOTTOM w0.381: C60316.1 51.86,23.35 v2(51.86,23.67) 51.62,23.91 R60316.1
VRAVDDQ_TON: length 2
  BOTTOM w0.254: R60306.1 38.85,28.3 v2(39.05,28.1) 39.44,27.71 U60300.7
VRAVGG_BST: length 2.4
  BOTTOM w0.381: R6715.1 99.39,51.87 v2(98.78,51.26) 98.29,51.75 C6715.2
VRAVGG_BST1: length 2.2
  BOTTOM w0.254: 98.55,54.61 U6700.8
  BOTTOM w0.381: R6715.2 99.39,53.77 98.55,54.61
VRAVGG_CSN1: length 13.2
  BOTTOM w0.254: R6747.2 90.23,56.02 89.46,56.79 84.45,56.79 82.52,54.86 82.52,52.33 82.7,52.15 R6710.4
VRAVGG_CSP1: length 13.8
  BOTTOM w0.254: R6749.2 90.68,56.11 89.61,57.17 84.29,57.17 82.09,54.97 82.09,52.43 81.81,52.15 R6710.3
VRAVGG_ON: length 3.1
  BOTTOM w0.254: U6700.1 98.67,57.65 99.06,58.04 99.67,58.04
  BOTTOM w0.381: 99.67,58.04 99.85,57.86 v2(100.28,57.86) R6743.1
VRAVGG_VDD: length 4.2
  BOTTOM w0.254: C6742.1 98.27,58.81 97.85,58.38 U6700.28
  BOTTOM w0.381: C6742.1 100.23,58.81 v2(100.56,59.13) 100.88,58.81 101.54,58.81 R6745.1
VRAVR_ON: length 1.3
  BOTTOM w0.254: R6643.1 93.11,72.39 U6600.1
VRB3V3A_BST: length 2.6
  BOTTOM w0.254: U6100.10 71.91,139.25 71.35,139.82 71.35,140.11 70.8,140.66 R6115.1
VRB3V3A_BST1: length 1.1
  BOTTOM w0.381: C6115.1 70.49,139.28 R6115.2
VRB5V0A_BST: length 2.7
  BOTTOM w0.254: U6150.10 90.94,139.25 v2(90.59,138.9) 89.74,138.05 R6165.1
VRB5V0A_BST1: length 1
  BOTTOM w0.381: R6165.2 88.37,137.17 C6165.1
VRB_VCC: length 4.5
  BOTTOM w0.254: R60305.1 38.43,29.37 v2(39.14,29.37) 40.09,29.37 40.62,28.85 U60300.9
  BOTTOM w0.381: R60309.2 37.41,29.27 C60306.1 R60305.1
VRB_VDD5: length 180
  TOP w0.381: 99.37,113.56 101.27,111.66 101.27,108.08 100.42,107.23 100.42,96.29 101.6,95.11 102.09,95.11 103.71,93.5 103.71,54.33 v2(102.24,52.86) 101.72,52.35 v1(101.72,51.38) ; 99.37,113.56 88.71,113.56 88.27,114 R60000.1 ; 99.37,113.56 99.39,113.56 101.89,116.05 v1(102.77,116.05)
  L3 w0.381: v1(101.01,129.87) 102.1,129.87 104.24,127.74 104.24,122.01 103.37,121.14 103.37,116.66 v1(102.77,116.05)
  L4 w0.381: v1(36.5,31.17) 36.5,35.79 37.98,37.27 51.98,37.27 52.06,37.19 63.75,37.19 65.87,39.31 74.14,39.31 74.63,38.81 79.06,38.81 79.09,38.79 90.22,38.79 92.96,41.52 92.96,41.94 92.96,41.94 92.96,42.62 v1(101.72,51.38)
  BOTTOM w0.254: C60209.1 101.55,115.46 101.46,115.54 U60600.11
  BOTTOM w0.381: C60209.1 102.54,115.82 v1(102.77,116.05) ; R6161.2 v1(101.01,129.87) ; v1(36.5,31.17) R60309.1
VRP1V05A: length 6.9
  L3 w0.508: v1(98.2,112.52) 96.52,110.83 v1(96.52,107.44)
  BOTTOM w0.254: U60600.19 v1(98.2,112.52)
  vias: v2(94.28,105.03)
VRP1V05A_PH:
  vias: v2(94.82,113.51)
VRP1V5S: length 3.8
  BOTTOM w0.254: 101.66,115.94 U60600.10
  BOTTOM w0.381: 101.66,115.94 v2(102.02,116.3) 102.32,116.61 103.09,116.61 C61700.1
VRP1V8A: length 9
  TOP w0.762: v1(104.06,117.56) 104.06,116.1 102.66,114.71 102.66,114.3 v5(101.75,113.39)
  BOTTOM w0.254: U60600.3 98.2,118.56 v1(98.14,118.62) ; U60600.14 100.65,114.14
  BOTTOM w0.432: v5(101.75,113.39) 101.41,113.39 100.65,114.14
  BOTTOM w0.762: C7002.1 v5(101.75,113.39)
  vias: v1(89.81,120.6) v1(89.84,119.76) v1(89.94,117.6) v1(90.12,119.05) v1(101.8,117.74) v1(102.66,117.73) v1(105.23,117.91) v2(90.98,122.22)
VRP1V15: length 4.4
  BOTTOM w0.254: U60600.6 99.4,118.12 99.96,118.68
  BOTTOM w0.508: C61100.1 101.65,120.37 v2(100.32,119.04) 99.96,118.68
VRP1V24A: length 5.1
  BOTTOM w0.254: 99.21,119.41 99,119.2 U60600.5
  BOTTOM w0.508: 99.21,119.41 100.76,120.95 C61000.1
  vias: v2(99.39,123.82)
VRP3V3A: length 8.6
  BOTTOM w0.254: U6100.7 75.87,139.25 76.56,138.56 C6109.1
  BOTTOM w0.381: C6109.1 76.07,137.89 76.07,131.62
  vias: v2(75.05,129.26)
VRP3V3A_PH: length 0.6
  BOTTOM w0.381: C6115.2 71.96,138.4
  vias: v2(75.23,137.57)
VRP5V0A: length 33.4
  TOP w0.508: v1(99.16,132.92) 99.9,133.65 99.9,137.9 98.37,139.42 97.65,139.42 96.67,140.4 96.67,142.87 95.89,143.65 93.08,143.65 92.48,143.05 89.67,143.05 88.95,142.33 v1(88.95,142.26)
  BOTTOM w0.254: U6150.7 95.67,139.25 C6169.1
  BOTTOM w0.381: v1(88.95,142.26) 88.82,142.14 R6150.2 88.02,141.62 C6166.2 ; R6161.1 99.1,131.39 C6150.1 98.24,130.48 ; 96.26,132.49 96.26,137.32 95.76,137.82 C6169.1
  vias: v2(95.17,129.26)
VRP5V0A_PH: length 6.3
  BOTTOM w0.381: L6150.1 92.03,136.25 C6165.2 88,136.25 v2(87.56,136.7) 87.32,136.93 R6166.1
VRPCHG_LG: length 15.5
  L4 w0.508: v5(65.61,26.24) 68.25,26.24 69.61,27.6 69.61,29.53 72.59,32.51 v5(75.46,32.51)
  BOTTOM w0.33: v5(65.61,26.24) 65.02,25.65 64.31,25.65 64.22,25.74 U6000.15
VRPVCORE_HG1: length 9.6
  L3 w0.508: v5(97.89,78.33) 97.36,77.8 97.36,71.81 v5(97.61,71.55)
  BOTTOM w0.254: v5(97.61,71.55) 97.61,71.13 97.2,70.73 U6600.9
  BOTTOM w0.508: Q6610.1 98.25,78.69 v5(97.89,78.33)
VRPVCORE_LG1: length 21.4
  L3 w0.508: v5(98.12,69.17) 98.81,69.17 100.1,70.46 100.1,79.35 98.7,80.75 98.7,84.94 v5(97.84,85.8)
  BOTTOM w0.254: v5(98.12,69.17) 97.76,69.53 U6600.12
  BOTTOM w0.508: Q6610.8 98.25,85.39 v5(97.84,85.8)
VRPVCORE_PH1: length 19.4
  L3 w0.508: v5(93.77,82.07) 95.65,82.07 98.83,78.89 98.83,71.33 98.24,70.74 v5(98.24,70.71)
  BOTTOM w0.254: U6600.10 97.85,70.33 v5(98.24,70.71)
  BOTTOM w0.381: v5(98.24,70.71) 98.67,71.15 C6615.1
  BOTTOM w0.508: R7661.1 92.4,79.25
  vias: v2(93.09,83.97)
VRPVDDQ: length 16.3
  BOTTOM w0.254: U60300.2 39.29,25.71 39.2,25.62 38.47,25.62 37.98,25.13 R60300.2
  BOTTOM w0.508: R60300.2 37.79,25.13 C60304.1 35.91,25.13 34.29,26.74 34.29,30.18 37.38,33.27 R60359.1 39.18,33.27 C60303.1
  vias: v2(43.02,34.42)
VRPVDDQ_PH: length 4.7
  L4 w0.508: v5(44.89,27.28) 44.89,23.63 v5(44.98,23.55)
  BOTTOM w0.508: C60315.1 v5(44.98,23.55)
  vias: v2(51,26.07)
VRPVDDQ_VIN: length 16.3
  L3 w0.508: v1(46.2,24.31) 46.2,22.88 45.18,21.87 40.13,21.87 36.8,25.2 v1(36.8,28.3)
  BOTTOM w0.508: R60306.2 v1(36.8,28.3)
  vias: v2(45.65,19.41)
VRPVDDQ_VLDOIN: length 13.7
  L3 w0.508: v5(42.49,23.39) 42.24,23.14 40.92,23.14 39.16,24.89 39.16,30.29 37.87,31.59 v5(37.87,31.6)
  BOTTOM w0.254: v5(42.49,23.39) 42.47,23.39 42.22,23.65 U60300.28
  BOTTOM w0.508: R60359.2 v5(37.87,31.6)
VRPVGG_HG1: length 18.3
  TOP w0.508: v5(89.96,41.66) v2(96.12,47.81) 98.57,50.27 98.57,53.51 v5(98.36,53.73)
  BOTTOM w0.254: U6700.9 97.45,54.15 97.87,53.73 v5(98.36,53.73)
  BOTTOM w0.508: Q6710.1 89.68,41.37 v5(89.96,41.66)
VRPVGG_LG1: length 11.3
  TOP w0.508: v5(96.1,52.89) v2(94.16,50.95) v5(90.24,47.04)
  BOTTOM w0.254: U6700.12 96.25,53.91 96.1,53.76 v5(96.1,52.89)
  BOTTOM w0.508: Q6710.8 v5(90.24,47.04)
VRPVGG_PH1: length 21.8
  TOP w0.508: v5(97.48,53.17) 97.48,51.86 v2(95.2,49.59) 91.13,45.52 84.83,45.52 v5(84.54,45.22)
  BOTTOM w0.254: U6700.10 97.05,53.93 97.48,53.49 v5(97.48,53.17)
  BOTTOM w0.381: v5(97.48,53.17) 97.44,53.13 C6715.1
  BOTTOM w0.508: R7761.1 82.28,43.31 L6710.1
VRPVTT: length 3.2
  BOTTOM w0.254: U60300.31 41.02,24.19 40.69,23.86 v2(40.69,23.4) ; 41.41,23.11 41.82,23.52 U60300.29
VRPVTT_REF:
  vias: v2(35.25,23.62)
WLON: length 60.2
  TOP w0.102: v1(84.53,147.8) 84.35,147.8 84.04,148.11 U301.31
  L4 w0.102: v1(44.95,140.06) 46.92,142.02 48.88,142.02 49.67,142.02 53.79,137.9 65.16,137.9 66.75,139.5 66.75,143.56 71.35,148.16 84.17,148.16 v1(84.53,147.8)
  BOTTOM w0.102: v1(44.95,140.06) 46.58,138.43 CN1300.56
XTAL_SOC_IN: length 21.1
  L3 w0.135: v1(79.45,78.05) 79.23,77.83 74.54,77.83 73.46,78.91 71.73,78.91 71.26,79.38 v1(71.26,79.38)
  BOTTOM w0.109: v1(71.26,79.38) 71.23,79.38 U4500.P24 ; v1(79.45,78.05) 79.73,78.33 82.28,78.33 v2(82.92,77.69) C4509.2 85.2,75.41 R4543.1 86.17,75.31 88.24,75.31 89.11,76.19 X4500.1
XTAL_SOC_OUT: length 17.9
  L3 w0.135: v1(79.42,77.32) 76.99,77.32 76.54,76.86 74.2,76.86 v1(72.61,78.45)
  BOTTOM w0.109: v1(72.61,78.45) 72.22,78.84 U4500.M22 ; v1(79.42,77.32) 79.93,77.83 81.98,77.83 v2(83.73,76.07) C4510.2 85.25,74.56 R4543.2 86.84,74.56 X4500.3

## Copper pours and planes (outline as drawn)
AGND_AUDIO on TOP (solid shape): 14.78,73.23 14.78,72.52 15.24,72.06 15.24,71.73 15.03,71.53 13.99,71.53 13.74,71.78 13.74,73.18 13.92,73.35 14.65,73.35
AGND_AUDIO on TOP (solid shape): 14.86,80.67 14.86,79.93 15.39,79.4 15.39,78.74 15.14,78.49 14.3,78.49 13.89,78.89 13.89,80.52 14.09,80.72 14.81,80.72
AGND_AUDIO on BOTTOM (solid shape): 8.07,52.35 8.07,52.09 8,52.02 6.55,52.02 6.32,51.79 6.02,51.79 5.94,51.87 5.94,52.35 6.04,52.45 7.97,52.45
AGND_AUDIO on L2: outline of 90 points within 2.86,41.02 18.26,104.11
AGND_AUDIO on L5: outline of 90 points within 2.86,41.02 18.26,104.11
AGND_KBC on TOP: 66.82,160.17 66.7,160.3 65.5,160.3 65.02,159.82 64.28,159.82 64.11,159.99 63.7,159.99 63.37,159.66 63.37,158.8 63.6,158.57 64.28,158.57 64.84,159.13 66.72,159.13 66.82,159.23
DGND on TOP (solid shape): 75.77,137.9 65.47,137.9 65.47,142.9 75.77,142.9
DGND on TOP (solid shape): 73.97,14.66 64.44,14.66 64.44,18.82 66.57,20.95 73.97,20.95
DGND on TOP (solid shape): 23.59,0.81 23.59,0.66 23.47,0.53 14.7,0.53 14.63,0.61 15.95,1.93 22.48,1.93
DGND on TOP (solid shape): 13.23,87.3 15.69,87.3 17.42,85.57 17.42,82.14 16.63,81.36 15.16,81.36 13.08,83.44 13.08,87.45
DGND on TOP (solid shape): 16.58,81 16.58,79.12 16.43,78.97 15.85,78.97 15.67,79.15 15.67,79.73 15.19,80.21 15.19,80.85 15.41,81.08 16.51,81.08
DGND on TOP (solid shape): 16.63,73.08 16.63,71.78 16.41,71.55 15.77,71.55 15.59,71.73 15.59,72.29 15.08,72.8 15.08,73.15 15.19,73.25 16.46,73.25
DGND on TOP (solid shape): 7.58,66.05 2.88,66.05 2.88,72.42 3.08,72.42 3.71,73.04 3.71,73.79 4.03,74.11 4.03,77.3 3.71,77.62 3.71,78.38 3.02,79.07 2.88,79.07 2.88,80.85 7.58,80.85
DGND on TOP (solid shape): 89.07,160.95 89.2,160.33 89.57,159.82 89.57,158.31 87.54,158.31 87.54,163.31 89.07,163.31
DGND on TOP (solid shape): 64.14,161.48 62.61,161.48 62.61,165.3 62.9,166 63.6,166.29 64.14,166.29
DGND on TOP (solid shape): 117.27,159.44 117.98,159.15 118.27,158.45 118.27,150.95 116.77,150.95 116.77,159.44
DGND on TOP (solid shape): 12.1,90.61 12.46,89.81 13.24,89.39 13.27,89.38 13.27,83.32 6.27,83.32 6.27,90.65 12.1,90.65
DGND on TOP (solid shape): 5.87,48.06 5.62,48.06 5.28,48.2 5.13,48.55 5.13,62.61 5.1,62.97 5,63.32 5,64.25 5.87,64.25
DGND on TOP (solid shape): 118.27,25.75 117.54,23.99 115.77,23.26 112.17,23.26 111.8,23.24 111.43,23.18 111.43,26.42 113.48,28.47 118.27,28.47
DGND on TOP (solid shape): 9.64,3 10.22,1.6 11.62,1.02 30.57,1.02 30.71,1.07 30.76,1.2 30.76,3.48 31.27,3.48 31.27,1.2 31.06,0.71 30.57,0.51 11.62,0.51 9.86,1.24 9.13,3 9.13,41.99 9.64,41.99
DGND on TOP (solid shape): 3.22,72.55 3.33,72.57 3.39,72.48 3.39,65.06 4.99,64.27 5.64,62.61 5.64,48.57 5.84,48.57 5.84,48.06 5.62,48.06 5.28,48.2 5.13,48.55 5.13,62.61 4.61,63.94 3.01,64.72 2.88,65.05 2.88,72.42 3.08,72.42
DGND on TOP (solid shape): 4.67,93.43 3.39,93.43 3.39,92.87 3.98,92.87 5.26,92.33 5.79,91.05 5.79,85.95 5.26,84.67 3.98,84.13 3.39,84.13 3.39,78.94 3.33,78.85 3.22,78.87 3.02,79.07 2.88,79.07 2.88,84.35 2.97,84.56 3.17,84.64 3.98,84.64 4.9,85.03 5.28,85.95 5.28,91.05 4.9,91.98 3.98,92.36 3.17,92.36 2.97,92.44 2.88,92.65 2.88,93.65 2.97,93.86 3.17,93.94 4.67,93.94
DGND on TOP (solid shape): outline of 113 points within 12.95,13.39 118.27,166.29
DGND on BOTTOM (solid shape): 64.06,160.3 64.06,156.77 62.79,156.77 62.79,160.48 63.88,160.48
DGND on BOTTOM (solid shape): 41.57,28.56 43.57,28.56 43.57,28.36 41.27,28.36 41.27,29.05 41.57,29.05
DGND on BOTTOM (solid shape): 23.59,0.81 23.59,0.66 23.47,0.53 14.7,0.53 14.63,0.61 15.95,1.93 22.48,1.93
DGND on BOTTOM (solid shape): 7.46,49.94 7.11,49.58 6.45,49.58 6.22,49.81 6.22,50.98 6.45,51.21 7.46,51.21
DGND on BOTTOM (solid shape): 20.47,116.26 20.47,115.16 20.29,114.99 19.1,114.99 19,115.09 19,116.28 19.2,116.48 20.24,116.48
DGND on BOTTOM (solid shape): 74.19,17.25 74.19,14.91 74.01,14.73 63.93,14.73 63.78,14.88 63.78,17.4 67.31,20.93 70.51,20.93
DGND on BOTTOM (solid shape): 84.86,31.14 84.86,30.76 84.32,30.23 82.67,30.23 82.5,30.4 82.5,31.27 82.62,31.39 84.6,31.39
DGND on BOTTOM (solid shape): 84.96,99.01 84.96,96.09 83.46,94.59 80.72,94.59 78.81,96.49 78.81,99.27 80.74,101.19 82.78,101.19
DGND on BOTTOM (solid shape): 89.46,60.71 89.46,58.78 88.82,58.14 84.99,58.14 84.58,58.55 84.58,60.81 85.16,61.39 88.77,61.39
DGND on BOTTOM (solid shape): 99.23,103.63 99.23,102.13 99.11,102.01 85.26,102.01 85.14,102.13 85.14,103.56 85.8,104.22 98.65,104.22
DGND on BOTTOM (solid shape): 101.52,123.88 101.52,122.71 101.44,122.63 100.2,122.63 100.05,122.78 100.05,123.95 100.1,124 101.39,124
DGND on BOTTOM (solid shape): 118.06,156.62 118.06,154.43 117.98,154.36 116.02,154.36 115.62,154.76 115.62,156.23 116.05,156.67 118.01,156.67
DGND on BOTTOM (solid shape): 74.11,32.87 74.11,32.18 73.99,32.05 72.11,32.05 71.9,31.85 71.9,31.17 71.65,30.91 68.93,30.91 68.68,31.17 68.68,33.91 68.98,34.21 72.77,34.21
DGND on BOTTOM (solid shape): 76.6,36.14 76.6,33.93 76.17,33.5 75.05,33.5 75.03,33.48 74.06,33.48 72.89,34.65 70.3,34.65 69.87,35.08 69.87,35.99 70.25,36.37 76.37,36.37
DGND on BOTTOM (solid shape): 4.6,84.75 4.65,84.68 4.65,64.12 4.59,64.04 4.49,64.06 3.96,64.4 3.33,64.56 3.01,64.72 2.88,65.05 2.88,72.42 3.08,72.42 3.71,73.04 3.71,73.79 4.03,74.11 4.03,77.3 3.71,77.62 3.71,78.38 3.02,79.07 2.88,79.07 2.88,84.35 2.89,84.41 2.91,84.47 3.01,84.59 3.17,84.64 3.97,84.64 4.25,84.67 4.52,84.76
DGND on BOTTOM (solid shape): outline of 243 points within 108.89,21.51 118.27,51.25
DGND on BOTTOM (solid shape): outline of 149 points within 2.88,0.51 118.27,166.29
DGND on L4 (solid shape): 13.81,55.09 13.81,50.93 13.71,50.82 13.71,50.8 9.52,50.8 9.42,50.9 9.42,55.09 9.52,55.19 13.71,55.19
DGND on TOP: 64.36,160.12 64.16,160.32 64.16,161.06 64.36,161.26 65.4,161.26 65.71,160.96 65.71,160.76 65.61,160.65 65.15,160.65 64.61,160.12
DGND on TOP: 119.48,50.39 113.43,50.39 110.97,47.93 110.97,44.55 113.43,42.09 118.21,42.09 119.48,43.36
DGND on TOP: 18.36,18.44 18.36,16.18 20.57,16.18 20.57,18.44
DGND on TOP: 81.28,66.65 81.02,66.65 80.41,66.04 80.41,64.24 80.69,63.96 81.51,63.96 81.68,64.13 81.68,64.62 81.23,65.07 81.23,66.14 81.45,66.37 81.45,66.47
DGND on TOP: 40.1,32.05 44.75,32.05 45.29,31.52 45.29,29.41 45.01,29.13 40.56,29.13 39.87,29.82 39.87,31.83
DGND on TOP, BOTTOM: 10.06,138.99 10.06,140.65 1.9,140.65 1.9,146.91 13.38,146.91 13.38,139.42 12.95,138.99
DGND on BOTTOM: 38.68,32.05 44.75,32.05 45.29,31.52 45.29,29.41 44.31,28.44 41.39,28.44 41.39,29.36 40.63,30.12 39.09,30.12 38.45,30.76 38.45,31.83
DGND on BOTTOM: 98.19,111.99 99.01,111.99 99.18,111.81 99.18,108.74 99.63,108.29 99.63,108.11 99.46,107.95 97.91,107.95 97.81,108.05 97.81,108.43 98.12,108.74 98.12,111.91
DGND on BOTTOM: 87.8,121.79 88.59,121.79 88.8,121.59 88.8,113.87 88.57,113.64 86.48,113.64 85.85,114.27 85.85,119.84
DGND on BOTTOM: 47.37,25.3 47.37,22.61 47.55,22.43 49.81,22.43 50.19,22.81 50.19,25.42 50.06,25.55 47.62,25.55
DGND on BOTTOM: 101.52,107.67 101.52,104.88 101.65,104.75 103.89,104.75 104.22,105.09 104.22,107.46 103.88,107.8 101.65,107.8
DGND on BOTTOM: 76.5,137.64 76.5,133.58 76.63,133.45 79.35,133.45 79.42,133.53 79.42,137.69 79.35,137.77 76.63,137.77
DGND on BOTTOM: 99.49,101.96 99.49,96.54 99.64,96.39 100.55,96.39 100.76,96.6 100.76,101.96 100.63,102.08 99.62,102.08
DGND on BOTTOM: 99.49,81.51 99.36,81.64 99.36,85.37 98.07,86.66 97.53,86.66 97.23,86.36 97.23,85.45 97.48,85.19 97.48,84.48 97.28,84.28 94.41,84.28 94.18,84.51 94.18,97.59 94.43,97.84 97.84,97.84 98.02,97.66 98.02,93.18 97.72,92.89 97.72,89.56 100.4,89.56 102.56,87.4 102.56,81.81 102.26,81.51
DGND on BOTTOM: 109.14,98.32 105.51,98.32 105.25,98.58 105.25,99.8 105.24,99.82 104.38,99.82 104.37,99.8 104.37,96.52 108.23,96.52 109.27,97.56 109.27,98.2
DGND on BOTTOM: 97.84,119.71 98.47,119.71 98.73,119.96 98.73,125.32 98.55,125.5 97.99,125.5 97.76,125.27 97.76,119.79
DGND on BOTTOM: 66.67,76.22 69.42,76.22 70.15,75.49 70.15,72.72 70.71,72.16 70.71,71.32 68.86,69.47 66.44,69.47 65.45,70.46 65.45,72.36 65.05,72.77 65.05,73.1 65.45,73.51 65.45,75.01
DGND on BOTTOM: 96.69,137.9 96.69,133.71 96.82,133.58 99.62,133.58 99.74,133.71 99.74,137.9 99.62,138.02 96.82,138.02
DGND on BOTTOM: 21.49,137.16 21.49,141.22 21.66,141.4 23.34,141.4 23.7,141.05 23.7,137.36 23.19,136.85 21.79,136.85
DGND on BOTTOM: 51.63,99.29 51.63,99.27 51.62,99.27 50.5,98.14 50.5,98.09 49.54,97.13 48.99,97.67 48.99,99.81 49.21,100.03 50.89,100.03
DGND on BOTTOM: 102.1,137.9 104.67,137.9 104.98,137.59 104.98,136.8 104.19,136.02 102.17,136.02 101.83,136.36 101.83,137.62
DGND on BOTTOM: 93.14,145.14 93.14,140.82 93.27,140.69 93.75,140.69 94.21,141.15 95.35,141.15 95.35,141.15 96.61,141.15 96.89,141.43 96.89,142.71 95.67,143.93 95.67,144.78 95.2,145.26 93.27,145.26
DGND on BOTTOM: 84.76,49.94 93.32,49.94 93.88,49.38 93.88,44.53 93.32,43.97 90.17,43.97 89.89,44.25 89.89,46.08 90.12,46.3 90.6,46.3 90.98,46.68 90.98,47.47 90.55,47.9 88.34,47.9 88.21,47.78 88.21,46.79 88.08,46.66 84.66,46.66 84.43,46.89 84.43,49.61
DGND on BOTTOM: 99.92,95 98.52,95 98.4,94.87 98.4,92.33 98.52,92.2 99.41,92.2 101.06,90.55 101.44,90.55 101.57,90.68 101.57,90.93 100.05,92.46 100.05,94.87
DGND on BOTTOM: 98.8,25.86 102.31,25.86 102.71,25.45 102.71,22.96 102.28,22.53 98.78,22.53 98.45,22.86 98.45,25.5
DGND on BOTTOM: 87.17,125.58 87.17,126.72 87.04,126.85 85.01,126.85 84.88,126.72 84.88,125.58 85.01,125.45 87.04,125.45
DGND on BOTTOM: 9.42,55.09 9.42,50.9 9.52,50.8 10.64,50.8 10.97,50.47 14.3,50.47 14.78,50.95 14.78,54.58 14.17,55.19 9.52,55.19
DGND on BOTTOM: 73.83,140.82 73.96,140.69 74.47,140.69 74.98,141.2 75.89,141.2 76.04,141.05 76.4,141.05 76.48,141.12 76.48,144.86 76.07,145.26 73.96,145.26 73.83,145.14
DGND on BOTTOM: 23.47,117.6 23.47,115.19 23.59,115.06 26.39,115.06 27.66,116.33 28.04,116.33 28.17,116.46 28.17,117.6 28.04,117.73 23.59,117.73
DGND on BOTTOM: 89.1,27.74 90.65,27.74 90.88,27.51 90.88,26.31 90.65,26.09 88.9,26.09 88.72,26.26 88.72,27.36
DGND on BOTTOM, L3, L4: 61.31,27.73 61.31,25.77 63.3,25.77 63.3,27.73
DGND on L2: 127.31,13.18 127.31,168.68 61.49,168.68 61.49,147.24 -7.13,147.24 -7.13,-1.99 32.41,-1.99 32.41,13.18 ; 1 cut-out
DGND on L3: 9.42,55.09 9.42,50.9 9.52,50.8 13.71,50.8 13.71,50.82 13.81,50.93 13.81,55.09 13.71,55.19 9.52,55.19
DGND on L5: 61.57,167.51 114.02,167.51 122.15,159.38 122.15,21.84 113.76,13.46 34.39,13.46 32.23,11.3 32.23,0.51 31.21,-0.51 9.88,-0.51 -0.54,9.91 -0.54,143.26 3.02,146.81 59.03,146.81 61.06,148.84 61.06,167
DGND_HDMI on TOP, BOTTOM: 1.29,126.75 12.57,126.75 13.56,125.75 13.56,123.04 14.07,122.53 15.64,122.53 16.08,122.1 16.08,120.65 15.26,119.84 1.29,119.84
DGND_PB on TOP (solid shape): 62.18,0.91 60.47,0.91 60.47,6.19 60.9,7.25 60.47,8.31 60.47,11.64 62.18,11.64
DGND_PB on TOP (solid shape): 81.97,11.64 82.46,11.44 82.67,10.95 82.67,7.38 82.47,7.38 81.84,6.76 81.84,6.01 81.52,5.69 81.52,2.5 81.84,2.18 81.84,1.74 81.84,1.42 82.18,1.08 82.2,0.99 82.14,0.93 82.06,0.91 81.97,0.91 79.4,0.91 79.4,1.74 79.4,1.74 79.4,9.01 79.45,9.09 79.55,9.08 79.92,8.91 80.32,8.85 80.6,8.85 81.97,9.91 81.28,11.5 81.24,11.54 81.24,11.64
DGND_PB on BOTTOM (solid shape): 68.04,0.91 65.74,0.91 65.74,11.64 68.04,11.64
DGND_PB on BOTTOM (solid shape): 56.87,0.91 49.87,0.91 49.87,3.9 50.97,3.9 50.97,11.64 56.87,11.64
DGND_PB on BOTTOM (solid shape): 81.97,11.64 82.46,11.44 82.67,10.95 82.67,7.38 82.47,7.38 81.84,6.76 81.84,6.01 81.52,5.69 81.52,2.5 81.84,2.18 81.84,1.42 82.2,1.06 82.23,1.01 82.22,0.95 82.1,0.92 81.97,0.91 78.9,0.91 78.9,9.56 78.97,9.65 79.08,9.6 79.13,9.51 79.64,9.03 80.32,8.85 80.6,8.85 81.97,9.91 81.28,11.5 81.24,11.56 81.26,11.64
DGND_PB on L2, L4, L5: 81.97,11.64 82.46,11.44 82.67,10.95 82.67,1.6 82.46,1.11 81.97,0.91 34.97,0.91 34.49,1.11 34.28,1.6 34.28,10.95 34.49,11.44 34.97,11.64
P0V675M_VREF on BOTTOM (solid shape): 33.52,26.31 34.24,25.6 34.24,24.92 34.06,24.74 33.73,24.74 33.19,25.27 32.48,25.27 32.18,25.58 32.18,32.59 33.52,32.59
P0V675S on BOTTOM (solid shape): 42.26,20.04 43.2,20.04 43.61,20.45 44.42,20.45 44.6,20.27 44.6,19.33 44.24,18.97 41.27,18.97 41.2,19.05 41.2,20.34 41.45,20.6 41.7,20.6
P0V675S on TOP: 43.62,67.56 44,67.18 44,66.8 43.37,66.16 43.37,63.88 44.08,63.17 45.26,63.17 45.89,62.55 45.89,58.82 45.06,57.99 45.06,57.38 44.88,57.38 43.51,56.01 43.51,55.52 43.23,55.24 42.71,55.24 42.48,55.01 42.48,54.01 41.02,52.55 38.69,52.55 38.69,51.41 38.14,50.85 35.71,50.85 33.87,49.01 33.87,47.03 34.48,46.41 35.73,46.41 36.68,47.37 38.06,47.37 38.06,46.58 36.9,45.43 33.3,45.43 31.55,47.17 31.55,53.84 34.1,56.38 38.83,56.38 40.32,57.87 40.32,62.23 41.59,63.5 41.59,66.8 42.35,67.56
P0V675S on TOP: 50.22,97.79 49.46,97.79 48.95,98.29 46.16,98.29 45.27,97.41 43.31,97.41 41.27,99.44 41.27,101.63 39.6,103.31 39.6,104.42 37.31,106.7 35.84,106.7 34.86,107.69 34.86,111.88 35.96,112.99 40.29,112.99 42.92,110.35 42.92,108.77 45.91,105.79 47.81,105.79 49.97,103.63 49.97,101.34 48.95,100.33 48.95,99.31 49.97,98.29 50.22,98.29 50.35,98.17 50.35,97.91
P0V675S on BOTTOM: 32.48,51.13 32.74,50.88 32.74,48.28 28.09,43.64 27.71,43.64 27.71,45.17 31.3,48.77 31.3,50.96 31.47,51.13
P0V675S on L3: 33.86,108.36 29.61,108.36 23.17,101.92 23.17,59.42 27.19,55.4 27.99,55.4 32.66,50.72 32.66,48.49 32.48,48.31 29.38,48.31 19.53,58.17 19.53,72.67 17.9,74.29 17.9,101.55 24.43,108.08 25.68,108.08 29.46,111.86 32.09,111.86 36.4,111.87 36.4,110.9
P0V675S on L4: 21.92,55.78 29.38,48.31 32.48,48.31 32.66,48.49 32.66,50.72 27.99,55.4 27.18,55.4 22.81,59.77 22.81,101.73 24,102.92 24.53,102.92 29.97,108.36 33.86,108.36 36.4,110.9 36.4,113.9 36.32,113.98 32.65,113.98 21.92,103.25
P1V05A on TOP: 66.8,77.29 67.41,77.29 67.47,77.35 67.47,79.63 66.73,79.63 66.73,77.36
P1V05A on TOP: 69.65,84.96 69.65,83.56 68.38,83.56 68.38,84.96
P1V05A on TOP: 69.15,79.63 69.15,78.36 69.25,78.26 70.04,78.26 70.04,79.5 69.78,79.75 69.27,79.75
P1V05A on BOTTOM: 66.62,76.48 67.64,76.48 67.76,76.6 67.76,80.54 67.64,80.67 66.87,80.67 66.11,81.43 65.99,81.43 65.86,81.3 65.86,80.41 66.49,79.78 66.49,76.6
P1V05A on BOTTOM: 61.11,83.38 61.35,83.38 61.48,83.51 61.86,83.51 61.98,83.38 62.23,83.38 62.3,83.46 62.3,84.35 62.18,84.48 61.92,84.48 61.54,84.1 61.16,84.1 61.03,84.22 60.78,84.22 60.65,84.1 60.65,83.84
P1V05A on BOTTOM: 69.43,78.38 69.67,78.38 70.18,78.89 70.18,79.91 70.05,80.03 69.03,80.03 68.97,79.97 68.97,79.68 69.1,79.55 69.1,79.22 68.97,79.09 68.97,78.84
P1V05A on BOTTOM: 68.27,82.57 68.53,82.57 68.94,82.99 68.94,83.26 68.82,83.38 68.82,83.84 69.12,84.15 69.17,84.15 69.48,84.45 69.63,84.45 69.78,84.6 69.78,84.76 69.63,84.91 69.43,84.91 69.27,84.76 69.01,84.76 67.76,86 67.51,86 67.38,85.87 67.38,84.48 66.49,83.59 66.49,83.46 66.62,83.33 67.51,83.33
P1V05A on BOTTOM: 104.06,101.83 104.06,96.49 103.83,96.27 101.24,96.27 101.01,96.49 101.01,102.46 101.14,102.59 102.41,102.59 103.04,101.96 103.93,101.96
P1V05A on L3: 72.09,81.02 72.09,75.89 71.97,75.78 71.66,75.78 71.26,76.18 69.86,76.18 69.16,76.89 67.8,76.89 65.44,79.26 62.67,79.26 61.84,78.42 61.38,78.42 61.1,78.7 61.1,83.74 61.63,84.27 61.99,84.27 62.47,83.79 62.47,83.23 63.07,82.63 65.42,82.63 66.94,81.11 68.76,81.11 69.59,81.94 71.16,81.94 ; 1 cut-out
P1V05A on L4: 73.97,72.89 71.9,74.97 68.67,74.97 66.96,76.68 66.96,79.47 67.5,80.01 68.77,80.01 69.15,80.39 69.15,81.66 69.28,81.79 78.89,81.79 84.66,87.55 89.15,87.55 91.49,89.89 91.49,100.53 92.59,101.64 102.48,101.64 102.77,101.35 102.77,96.95 100.94,95.12 100.94,85.39 93.52,77.98 85.82,77.98 84.24,76.39 84.24,75.17 81.96,72.89 ; 2 cut-outs
P1V05A on L5: 96.49,90.67 90.78,90.67 88.26,93.19 87.7,93.19 87.55,93.04 76.35,93.04 71.18,87.87 71.18,85.75 70.96,85.53 70.96,80.52 69.01,80.52 69.01,82.55 67.38,84.18 67.38,88.65 67.79,89.05 67.79,90.22 69.49,91.92 71.84,94.27 71.84,95.06 72.41,95.63 73.17,95.63 91.18,95.63 91.51,95.96 91.51,101.7 102.41,101.7 102.77,101.35 102.77,96.19 99.69,93.12 97.96,93.12 97.66,92.81 97.66,91.85
P1V5S on BOTTOM (solid shape): 13.64,41.83 13.64,39.98 13.26,39.6 12.37,39.6 12.06,39.9 12.06,41.25 12.57,41.76 12.57,42.19 12.7,42.32 13.15,42.32
P1V5S on BOTTOM: 105.71,115.18 105.71,116.08 105.73,116.1 106.51,116.1 106.52,116.08 106.52,114.52 106.51,114.5 105.2,114.5 105.18,114.52 105.18,115.15 105.2,115.16 105.69,115.16
P1V8A on L3 (solid shape): 103.65,113 103.65,110.72 103.37,110.44 102.71,110.44 102.46,110.69 102.46,113.28 102.54,113.36 103.3,113.36
P1V8A on BOTTOM: 91.26,127.3 91.26,128.5 91.77,129.01 93.29,129.01 93.65,128.65 93.65,127.3 93.49,127.15 91.41,127.15
P1V8A on BOTTOM: 76.7,63.02 75.3,63.02 74.61,63.71 74.61,64.99 74.9,65.28 75.46,65.28 75.97,64.77 76.73,64.77 76.93,64.57 76.93,63.25
P1V8A on BOTTOM: 101.14,112.83 100.81,113.16 99.64,113.16 99.44,112.95 99.87,112.52 100.61,112.52 101.22,111.91 102.16,111.91 102.31,111.76 102.31,110.69 102.59,110.41 103.5,110.41 103.78,110.69 103.78,112.55 103.5,112.83
P1V8A on L3: 65.28,83.69 63.36,85.62 63.36,93.66 64.03,94.34 64.03,99.08 68.98,104.04 68.98,106.96 69.62,107.59 72.13,107.59 72.13,103.66 66.28,97.8 66.28,84.19 65.78,83.69
P1V8A on L3: 65.96,78.23 67.55,76.64 69.05,76.64 69.73,75.95 70.39,75.95 71.14,75.21 71.67,75.21 72.24,74.64 72.24,71.73 72.37,71.6 72.91,71.6 73.06,71.45 73.06,71.12 73.64,70.53 73.64,68.68 76.4,65.92 76.4,63.75 75.51,62.86 72.95,62.86 68.75,67.06 68.75,68.28 64.77,72.27 62.45,72.27 62.45,73.81 61.92,74.35 61.92,77.16 62.99,78.23
P1V8A on L4: 67.5,82.42 67.24,82.17 66.23,82.17 65.92,82.47 65.92,82.85 65.21,83.56 65.21,84.58 65.34,84.71 65.72,84.71 67.5,82.93
P1V8A on L5: 70.96,80.26 70.96,75.34 70.15,75.34 69.72,75.77 68.27,75.77 68.27,77.83 65.99,80.11 65.99,82.68 65.35,83.31 65.35,84.18 67.03,84.18 68.75,82.45 68.75,80.26
P1V8S on BOTTOM: 86.92,131.67 86.92,127.61 87.04,127.48 87.8,127.48 87.91,127.58 87.91,128.55 88.34,128.98 88.34,129.36 88.82,129.84 88.82,131.67 88.69,131.8 87.04,131.8
P1V15A on TOP: 63.54,79.41 63.54,77.76 63.36,77.58 61.43,77.58 61.38,77.63 61.38,77.96 61.58,78.16 62.29,78.16 62.93,78.8 62.93,79.36 63.11,79.53 63.46,79.53 63.61,79.38 63.56,79.38
P1V15A on BOTTOM: 101.9,122.78 101.9,124.56 102.03,124.69 103.43,124.69 103.55,124.56 103.55,122.78 103.45,122.68 102,122.68
P1V15A on L3: 61.86,86.58 63,86.58 63.23,86.36 63.23,85.19 63.89,84.53 63.89,83.18 63.69,82.98 63.05,82.98 62.75,83.28 62.75,84.02 61.76,85.01 61.76,86.48
P1V15A on L4: 62.35,77.52 62.23,77.65 62.23,79.58 60.78,81.03 60.78,84.25 61.13,84.61 61.13,86.72 62.45,88.04 62.45,92.61 62.33,92.74 62.33,92.86 63.81,94.35 63.81,99.27 64.32,99.78 64.32,104.52 66.35,106.55 66.35,114.22 71.9,119.77 84.59,119.77 86.03,121.21 86.03,131.88 103.22,131.88 103.22,122.78 100.77,122.78 100.77,129.69 89.07,129.69 89.07,121.26 81.96,114.15 75.47,114.15 69.16,107.83 69.16,90.22 65.25,90.22 64.44,89.41 64.44,87.48 62.91,85.95 62.91,83.79 63.4,83.31 63.4,82.73 62.81,82.14 62.81,80.57 63.61,79.77 63.61,78.44 62.69,77.52
P1V24A on TOP: 66.71,85.8 66.4,85.8 66.01,86.19 66.01,86.78 66.19,86.96 69.6,86.96 69.65,86.9 69.65,85.2 69.07,85.2 68.18,86.08 67,86.08
P1V24A on TOP: 73.07,88.25 73.07,86.97 70.21,86.97 69.67,87.51 69.67,89.03 69.8,89.15 71.65,89.15 71.93,88.87 71.93,88.62 72.3,88.25
P1V24A on BOTTOM: 69.54,86.69 68.83,86.69 68.25,86.11 68.25,85.72 69.03,84.94 69.19,84.94 69.39,85.14 69.62,85.14 69.87,84.89 70,84.89 70.1,84.99 70.1,86.13
P1V24A on BOTTOM: 99.36,125.7 99.36,127.48 99.49,127.61 100.76,127.61 100.89,127.48 100.89,125.2 100.76,125.07 100.5,125.07 100,125.58 99.49,125.58
P1V24A on BOTTOM: 70.08,88.65 71.78,88.65 72.13,88.29 72.13,87.32 71.24,86.44 70.63,86.44 69.75,87.32 69.75,88.32
P1V24A on L3: 67.91,84.19 66.97,83.25 66.97,81.72 67.29,81.4 68.82,81.4 70.68,83.25 70.68,88.81 69.82,88.81 68.89,87.88 68.89,86.86 67.91,85.89
P1V24A on L4: 70.33,86.87 69.42,87.78 69.42,107.71 75.52,113.81 82.13,113.81 89.33,121.01 89.33,129.44 100.53,129.44 100.53,125.83 98.09,125.83 98.09,126.72 97.33,127.48 92.25,127.48 92.25,117.86 84.32,109.93 76.21,109.93 73.21,106.93 73.21,101.98 74.04,101.15 74.04,94.13 73.63,93.73 73.63,88.87 71.62,86.87
P1V35 on TOP: outline of 202 points within 23.05,38.54 69.24,122.48 ; 3 cut-outs
P1V35 on TOP: 32.23,56.24 30.35,54.36 30.35,47.07 33.78,43.64 33.78,41.27 30.5,41.27 24.25,47.52 24.25,56.24
P1V35 on BOTTOM: 33.09,54.89 34.64,54.89 34.64,47.45 36.22,45.87 38.17,45.87 38.17,41.73 35.89,41.73 33.09,44.53
P1V35 on BOTTOM: 50.79,95.57 52.84,93.53 52.84,92.75 53.57,92.02 54.84,92.02 55.21,92.39 55.21,93.1 52.26,96.05 52.26,97.22 52.42,97.38 52.42,97.58 52.89,98.05 52.89,98.22 52.14,98.97 51.87,98.97 49.77,96.86 49.77,96.59 50.79,95.57
P1V35 on BOTTOM: 38.73,36.19 37.94,36.98 37.94,47.89 45.65,55.6 46.29,55.6 47.18,54.71 47.18,49.86 47.37,49.67 47.43,49.67 47.43,49.32 46.81,48.7 46.81,42.09 49.15,39.75 51.23,39.75 52.57,41.1 52.57,45.06 52.32,45.31 52.32,48.31 52.19,48.44 52.19,48.44 51.81,48.82 51.81,51.24 54.86,54.29 57.09,54.29 57.13,54.25 60.5,54.25 60.5,48.67 59.97,48.13 59.97,41.88 61.69,40.16 64.11,40.16 65.63,41.68 65.63,45.06 65.38,45.31 65.38,48.62 64.82,49.17 64.82,51.43 65.4,52.02 65.4,53.36 64.87,53.9 64.87,55.75 64.94,55.68 64.94,55.9 66.11,57.07 68.27,57.07 68.86,56.49 68.86,39.23 67.07,37.44 64.67,37.44 63.42,36.19 ; 1 cut-out
P1V35 on BOTTOM: outline of 108 points within 20.06,68.55 72.41,122.4 ; 1 cut-out
P1V35 on BOTTOM: 39.73,58.88 24.58,58.88 23.8,59.66 23.8,68.22 24.91,69.34 24.91,70 22.04,72.87 21.99,72.87 21.84,72.72 21.84,56.41 24.74,53.52 36.84,53.52 40.65,57.32 40.65,57.96
P1V35 on L3: 68.37,117.33 68.37,104.85 67.64,104.11 65.25,104.11 65.07,104.29 65.07,104.81 66.55,106.28 66.55,117.33 66.8,117.59 68.12,117.59
P3V3_CARD on BOTTOM: 53.26,123.16 53.26,126.21 50.97,126.21 50.42,126.77 50.42,141.71 33.7,141.71 33.7,130.23 30.07,130.23 29.56,130.73 29.56,143.53 29.77,143.74 52.24,143.74 52.37,143.61 52.37,135.1 54.4,133.07 54.4,130.91 54.78,130.53 54.78,129.64 54.91,129.51 55.42,129.51 55.55,129.39 55.55,123.24 55.27,122.96 53.46,122.96
P3V3_LDO on BOTTOM: 78.1,141.38 78.69,141.38 79.24,140.82 79.24,140.61 79.04,140.41 77.64,140.41 77.57,140.49 77.57,140.84
P3V3_RTC on TOP: 82.27,63.86 82.93,63.86 83.08,64.01 83.08,68.66 82.52,69.21 81.28,69.21 81.12,69.06 81.12,67.18 81.68,66.62 81.68,65.43 82.12,65 82.12,64.01
P3V3A on BOTTOM: 55.8,125.2 55.8,122.94 55.95,122.78 60.78,122.78 61.24,123.24 61.24,125.75 61.77,126.29 61.77,127.48 61.64,127.61 59.23,127.61 59.1,127.48 59.1,125.45 58.98,125.32 55.93,125.32
P3V3AL on TOP: 72.82,127.22 72.82,122.79 70.71,122.79 70.71,125.33 63.89,125.33 62.48,126.74 62.48,128.37 66.48,128.37 67.62,127.22
